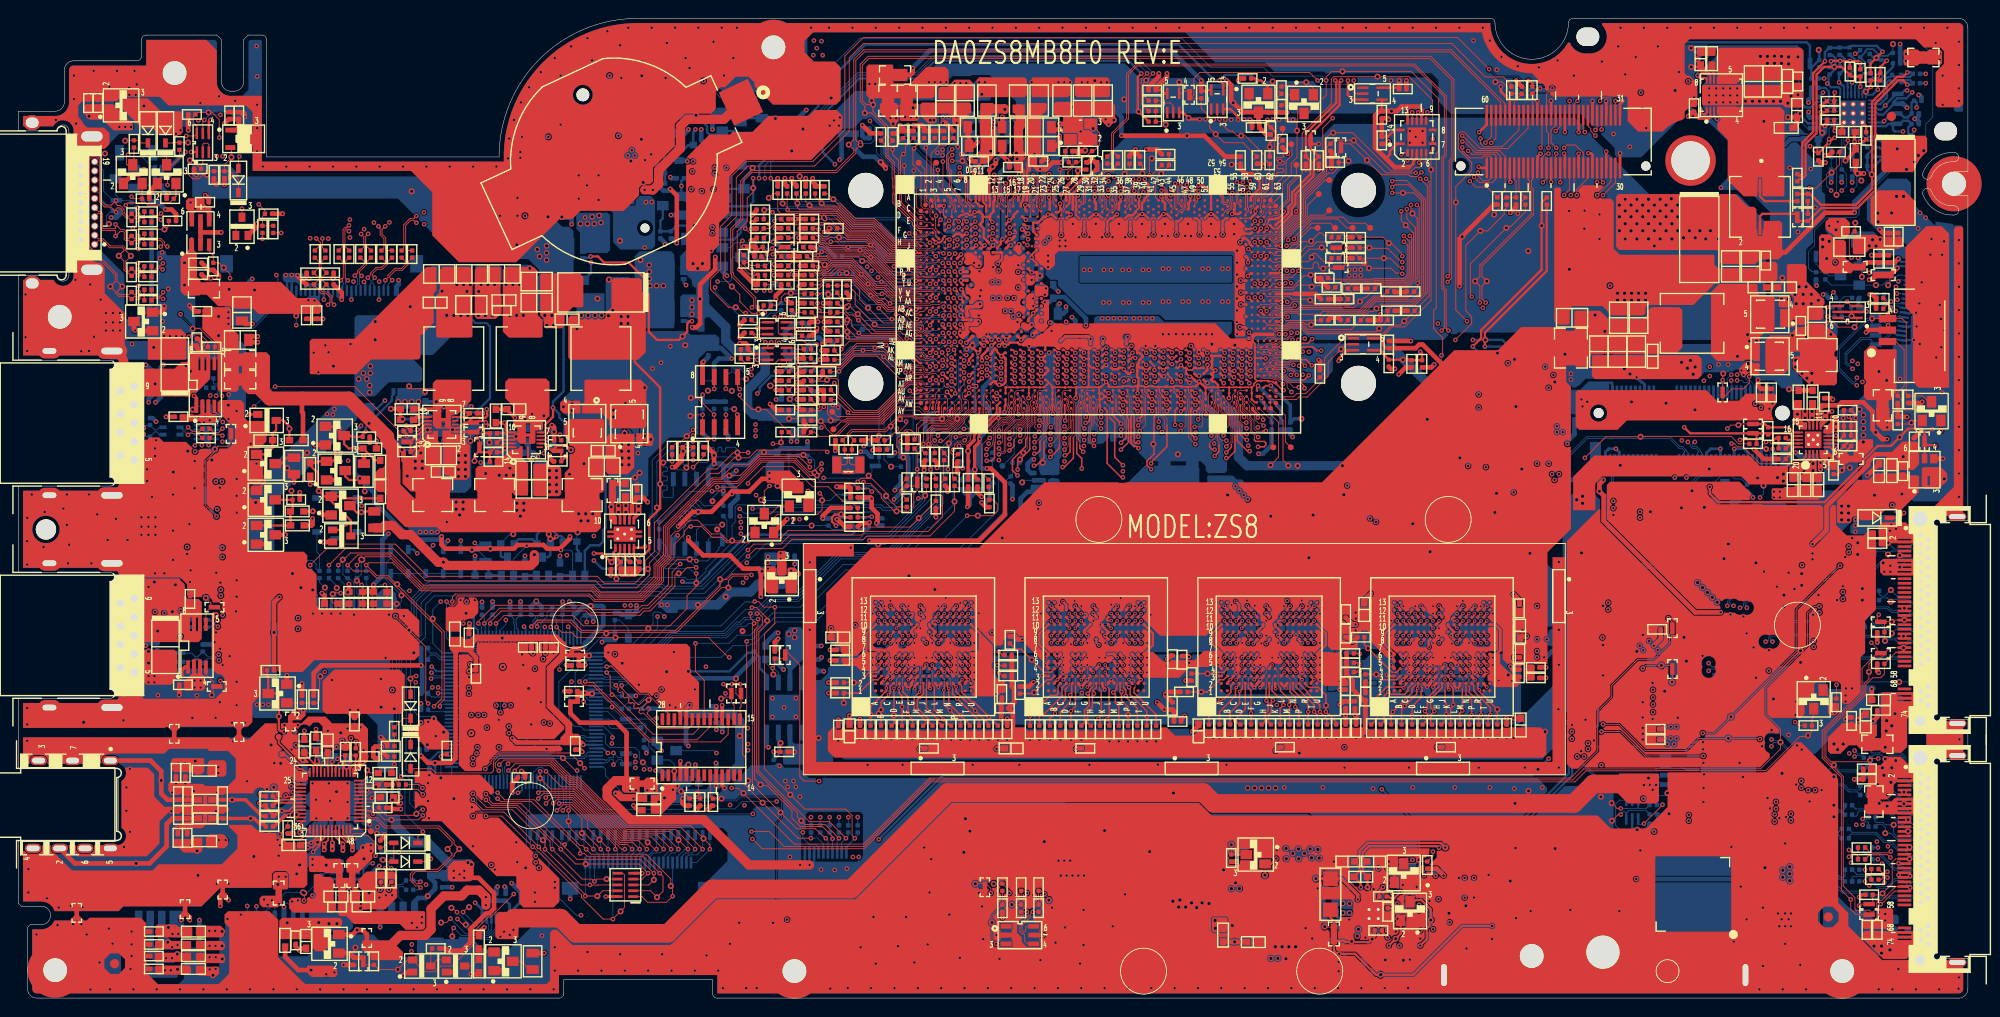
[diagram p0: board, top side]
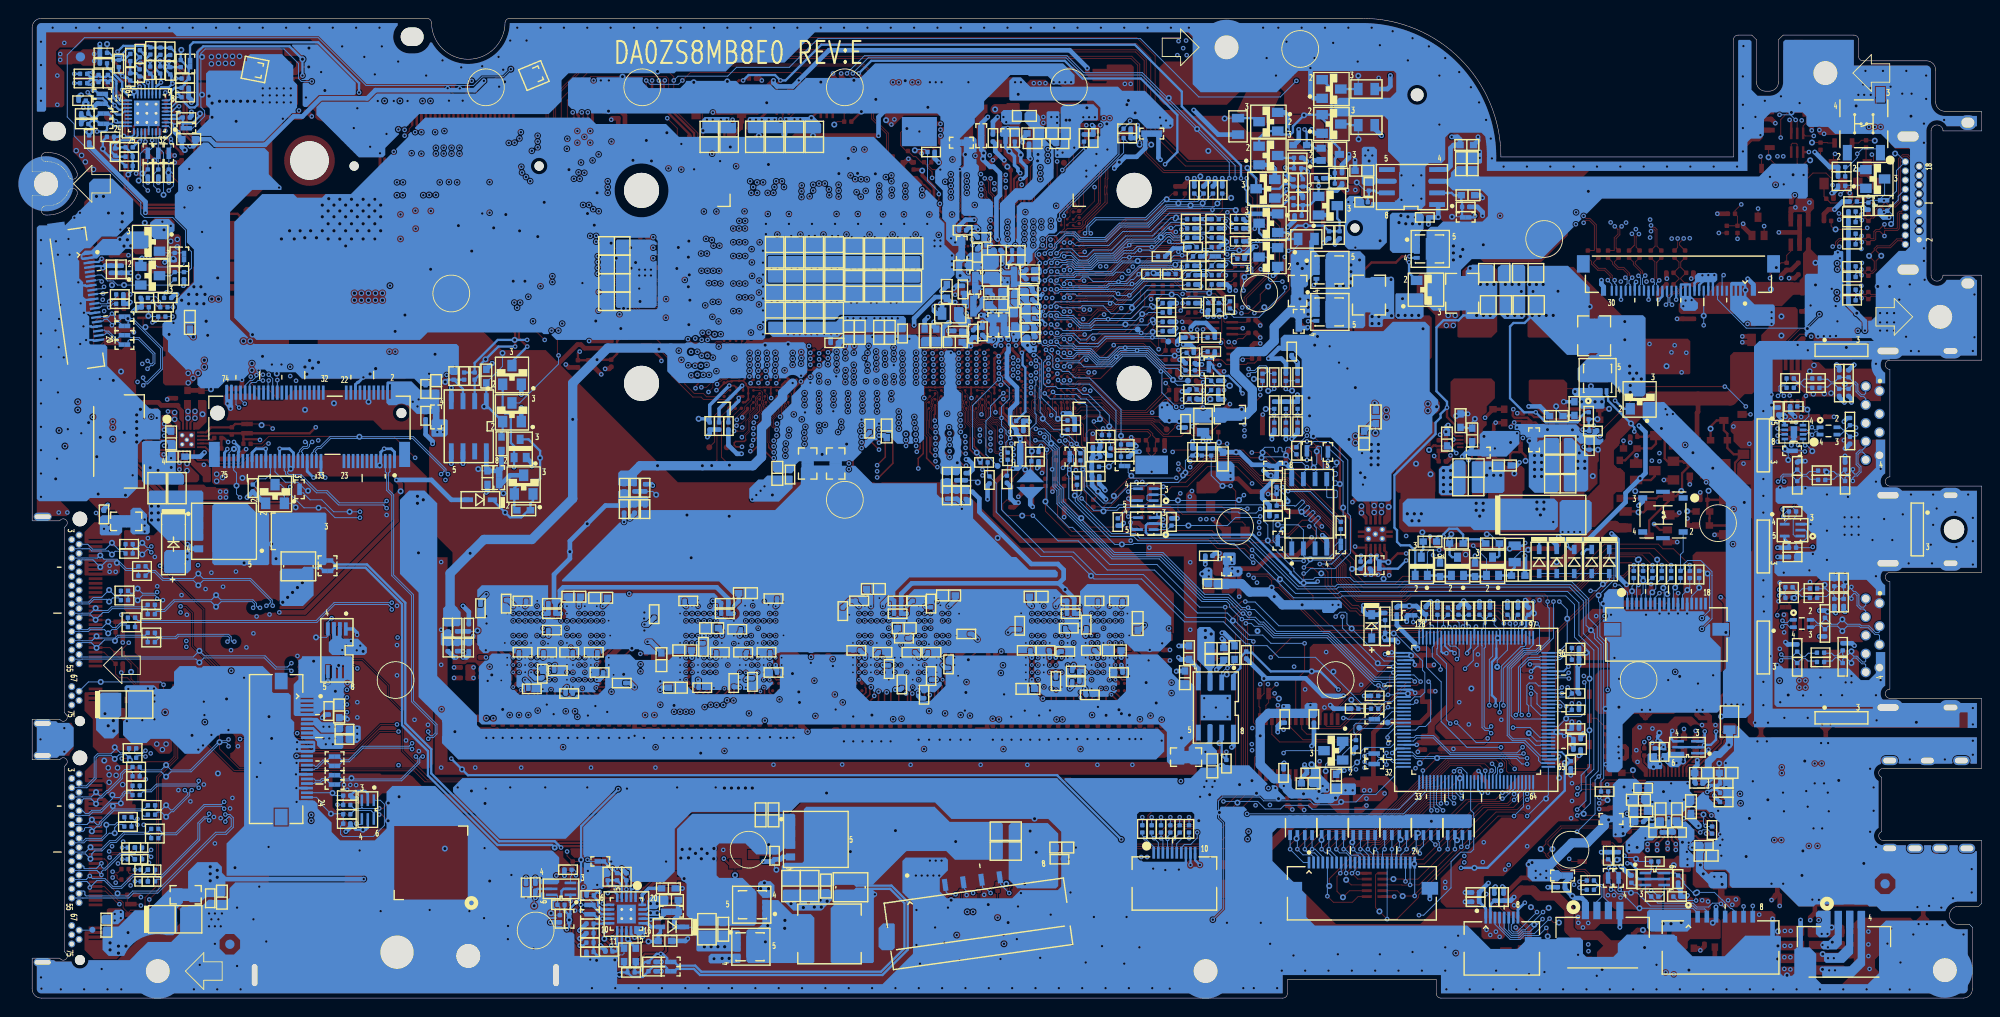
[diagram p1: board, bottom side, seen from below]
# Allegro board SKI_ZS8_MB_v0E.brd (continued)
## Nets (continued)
MA_ODT: R207.2 U6.AP32 U13.J8 U14.J8
MAIND: PC80.2 PQ21.3 PQ25.4 PQ28.4 PQ31.2 PR113.2
MAINON: PQ20.2 PR36.1 PR106.1 PR126.1 R531.1 U23.80
MAINON_ON_G: PQ17.2 PQ18.2 PQ19.2 PQ20.3 PQ21.2 PR114.1 PR119.2
MB_AMA0: R286.2 U6.AP45 U12.R2
MB_AMA1: R285.2 U6.AU46 U12.P2
MB_AMA2: R283.2 U6.AW46 U12.N2
MB_AMA3: R284.2 U6.AY47 U12.N3
MB_AMA4: R282.2 U6.AY46 U12.M3
MB_AMA5: R277.2 U6.AU49 U12.F3
MB_AMA6: R275.2 U6.AU47 U12.E3
MB_AMA7: R276.2 U6.AV47 U12.E2
MB_AMA8: R274.2 U6.AP46 U12.D2
MB_AMA9: R273.2 U6.AR46 U12.C2
MB_AZQ0: R221.2 U12.B3
MB_AZQ1: R206.2 U12.B4
MB_BMA0: R272.2 U6.AK33 U11.R2
MB_BMA1: R271.2 U6.AM33 U11.P2
MB_BMA2: R269.2 U6.AK35 U11.N2
MB_BMA3: R270.2 U6.AM35 U11.N3
MB_BMA4: R268.2 U6.AL35 U11.M3
MB_BMA5: R263.2 U6.AP42 U11.F3
MB_BMA6: R261.2 U6.AM36 U11.E3
MB_BMA7: R262.2 U6.AK36 U11.E2
MB_BMA8: R260.2 U6.AR40 U11.D2
MB_BMA9: R259.2 U6.AP40 U11.C2
MB_BZQ0: R223.2 U11.B3
MB_BZQ1: R219.2 U11.B4
MB_CKE0: R281.2 U6.AY49 U12.K3
MB_CKE1: R280.2 U6.AU50 U12.K4
MB_CKE2: R266.2 U6.AW49 U11.K3
MB_CKE3: R267.2 U6.AV50 U11.K4
MB_CLKN0: R279.2 U6.AM38 U12.J2
MB_CLKN1: R265.2 U6.AK38 U11.J2
MB_CLKP0: R278.2 U6.AN38 U12.J3
MB_CLKP1: R264.2 U6.AL38 U11.J3
MB_CS#0: R216.2 U6.AM32 U11.L3 U12.L3
MB_CS#1: R212.2 U6.AK32 U11.L4 U12.L4
MB_DQ0: U6.AY31 U12.R9
MB_DQ1: U6.AW31 U12.T8
MB_DQ2: U6.AY29 U12.T10
MB_DQ3: U6.AW29 U12.T11
MB_DQ4: U6.AV31 U12.R8
MB_DQ5: U6.AU31 U12.T9
MB_DQ6: U6.AV29 U12.R10
MB_DQ7: U6.AU29 U12.R11
MB_DQ8: U6.AY27 U12.C11
MB_DQ9: U6.AW27 U12.B11
MB_DQ10: U6.AY25 U12.C9
MB_DQ11: U6.AW25 U12.B8
MB_DQ12: U6.AV27 U12.B10
MB_DQ13: U6.AU27 U12.C10
MB_DQ14: U6.AV25 U12.B9
MB_DQ15: U6.AU25 U12.C8
MB_DQ16: U6.AM29 U12.D9
MB_DQ17: U6.AK29 U12.F8
MB_DQ18: U6.AL28 U12.E10
MB_DQ19: U6.AK28 U12.F10
MB_DQ20: U6.AR29 U12.E9
MB_DQ21: U6.AN29 U12.F9
MB_DQ22: U6.AR28 U12.F11
MB_DQ23: U6.AP28 U12.E11
MB_DQ24: U6.AN26 U12.N9
MB_DQ25: U6.AR26 U12.P9
MB_DQ26: U6.AR25 U12.N10
MB_DQ27: U6.AP25 U12.M10
MB_DQ28: U6.AK26 U12.M8
MB_DQ29: U6.AM26 U12.M9
MB_DQ30: U6.AK25 U12.M11
MB_DQ31: U6.AL25 U12.N11
MB_DQ32: U6.AY23 U11.R8
MB_DQ33: U6.AW23 U11.T8
MB_DQ34: U6.AY21 U11.T10
MB_DQ35: U6.AW21 U11.T11
MB_DQ36: U6.AV23 U11.R9
MB_DQ37: U6.AU23 U11.T9
MB_DQ38: U6.AV21 U11.R10
MB_DQ39: U6.AU21 U11.R11
MB_DQ40: U6.AY19 U11.M8
MB_DQ41: U6.AW19 U11.M9
MB_DQ42: U6.AY17 U11.M10
MB_DQ43: U6.AW17 U11.N10
MB_DQ44: U6.AV19 U11.N9
MB_DQ45: U6.AU19 U11.P9
MB_DQ46: U6.AV17 U11.M11
MB_DQ47: U6.AU17 U11.N11
MB_DQ48: U6.AR21 U11.F11
MB_DQ49: U6.AR22 U11.E9
MB_DQ50: U6.AL21 U11.F10
MB_DQ51: U6.AM22 U11.D9
MB_DQ52: U6.AN22 U11.F9
MB_DQ53: U6.AP21 U11.E11
MB_DQ54: U6.AK21 U11.E10
MB_DQ55: U6.AK22 U11.F8
MB_DQ56: U6.AN20 U11.B10
MB_DQ57: U6.AR20 U11.C10
MB_DQ58: U6.AK18 U11.C8
MB_DQ59: U6.AL18 U11.B8
MB_DQ60: U6.AK20 U11.C11
MB_DQ61: U6.AM20 U11.B11
MB_DQ62: U6.AR18 U11.B9
MB_DQ63: U6.AP18 U11.C9
MB_DQSN0: U6.AW30 U12.P11
MB_DQSN1: U6.AV26 U12.D11
MB_DQSN2: U6.AN28 U12.G11
MB_DQSN3: U6.AN25 U12.L11
MB_DQSN4: U6.AW22 U11.P11
MB_DQSN5: U6.AV18 U11.L11
MB_DQSN6: U6.AN21 U11.G11
MB_DQSN7: U6.AN18 U11.D11
MB_DQSP0: U6.AV30 U12.P10
MB_DQSP1: U6.AW26 U12.D10
MB_DQSP2: U6.AM28 U12.G10
MB_DQSP3: U6.AM25 U12.L10
MB_DQSP4: U6.AV22 U11.P10
MB_DQSP5: U6.AW18 U11.L10
MB_DQSP6: U6.AM21 U11.G10
MB_DQSP7: U6.AM18 U11.D10
MB_ODT: R209.2 U6.AL32 U11.J8 U12.J8
MBCLK: PR70.2 PR164.1 PU6.4 R509.1 U23.110
MBDATA: PR71.2 PR162.1 PU6.6 R510.1 U23.111
ME_WR#: R456.2 U23.106
MIC2-VREFO: R537.1 R538.1 R553.2 U16.29
MODPHY_D: PC85.2 PQ22.3 PQ26.4 PR118.2
MODPHY_EN: PR122.1 U6.Y2
MX0: CN16.5 CP2.8 RP1.1 U23.58
MX1: CN16.8 CP2.6 RP1.2 U23.59
MX2: CN16.9 CP2.4 RP1.3 U23.60
MX3: CN16.11 CP2.2 RP1.4 U23.61
MX4: CN16.18 CP1.2 RP1.6 U23.62
MX5: CN16.22 CP1.8 RP1.7 U23.63
MX6: CN16.23 CP1.6 RP1.8 U23.64
MX7: CN16.24 CP1.4 RP1.9 U23.65
MY0: CN16.21 CP3.2 U23.36
MY1: CN16.20 CP3.4 U23.37
MY2: CN16.19 CP3.6 U23.38
MY3: CN16.17 CP3.8 U23.39
MY4: CN16.16 CP4.2 U23.40
MY5: CN16.15 CP4.4 U23.41
MY6: CN16.14 CP4.6 U23.42
MY7: CN16.13 CP4.8 U23.43
MY8: CN16.12 CP5.2 U23.44
MY9: CN16.10 CP5.4 U23.45
MY10: CN16.7 CP5.6 U23.46
MY11: CN16.6 CP5.8 U23.51
MY12: CN16.4 CP6.2 U23.52
MY13: CN16.3 CP6.4 U23.53
MY14: CN16.2 CP6.6 U23.54
MY15: CN16.1 CP6.8 U23.55
NBSWON#: CN1.51 CN12.14 R495.1 SW2.2 U23.125
NGFF0_DET_C: R86.2 R87.2 U6.V1
NGFF0_PEDET: CN13.69 TP24.1
NGFF1_DET_C: R80.2 R85.2 U6.U1
NGFF1_RST#: CN10.50 CN13.50 R205.1 R315.1
NGFF2_DET_C: R376.2 R377.2 U6.V6
NGFF3_DET: Q16.3 R85.1 R86.1 R229.1 R376.1
NGFF3_DET_C: R97.2 R229.2 U6.AC1
NGFF3_PEDET: CN10.69 Q16.2 R227.2
NOA_STBN_0: CN1.28 U6.AA62
NOA_STBN_1: CN1.19 U6.U63
NOA_STBP_0: CN1.29 U6.AA61
NOA_STBP_1: CN1.20 U6.U62
OPI_COMP1: R187.2 U6.AY15
OPI_COMP2: R186.2 U6.AW15
PC_BEEP: D8.1 D9.1 R287.1
PCBEEP: C136.1 U16.12
PCBEEP_EC: D9.2 U23.34
PCBEEP_R: C134.1 C136.2 R287.2 R291.2
PCH_ACPRESENT: R416.2 R417.2 R418.2 U6.AJ8
PCH_AZ_CODEC_BITCLK: C70.1 C143.1 R180.2 U16.6
PCH_AZ_CODEC_RST#: C140.1 D14.1 R295.2 R457.2 U16.11
PCH_AZ_CODEC_SDIN0: R549.1 U6.AY10
PCH_AZ_CODEC_SDIN0_C: R549.2 U16.8
PCH_AZ_CODEC_SDOUT: R470.2 U16.5
PCH_AZ_CODEC_SYNC: R185.2 U16.10
PCH_BATLOW#: R428.2 R429.2 U6.AN4
PCH_I2C1_CLK: Q8.1 Q25.1 R24.2 R400.2 R571.2 U6.F1
PCH_I2C1_DAT: Q8.4 Q25.4 R25.2 R397.2 R581.2 U6.G4
PCH_INTVRMEN: R179.1 U6.AV7
PCH_PWRBTN#: R445.2 R455.2 R464.2 U6.AL7
PCH_PWROK: R13.1 R184.2 R191.2 U23.78
PCH_RSMRST#: R172.2 R182.2 U6.AW6
PCH_SLP_A#: R497.1 U6.AL5
PCH_SLP_S0#: R493.1 U6.AF3
PCH_SLP_S5#: R499.1 U6.AP5
PCH_SLP_SUS#: Q14.2 U6.AP4 U23.71
PCH_SLP_WLAN#: TP22.1 U6.AM5
PCH_SPI_CLK: C68.1 R176.2 U6.AA3
PCH_SPI_CLK_EC: R448.1 U23.105
PCH_SPI_CLK_R: R176.1 R448.2 U19.6
PCH_SPI_CS0#: R487.2 U6.Y7 U19.1
PCH_SPI_IO2: R475.2 U6.Y6
PCH_SPI_IO3: R449.2 U6.AF1
PCH_SPI_SI: R175.2 U6.AA2
PCH_SPI_SI_EC: R447.1 R507.2 U23.102
PCH_SPI_SI_R: R175.1 R447.2 U19.5
PCH_SPI_SO: R486.2 U6.AA4
PCH_SPI_SO_EC: R489.1 R508.2 U23.103
PCH_SPI_SO_R: R486.1 R489.2 U19.2
PCH_STAT: TP21.1 U6.AG4
PCH_SUSACK#: R119.2 U23.2
PCH_SUSCLK: TP20.1 U6.AE6
PCH_SUSPWARN#: R166.2 R515.1 U23.128
PCH_SUSPWRACK: R120.2 R166.1 R167.2 U6.AV4
PCI_PIRQA#: R375.1 U6.U6
PCI_PIRQB#: R74.1 U6.P4
PCI_PIRQC#: R369.1 U6.N4
PCI_PIRQD#: R64.1 U6.N2
PCI_PLTRST#: U6.AG7 U18.1 U18.2
PCIE_CLKREQ_NGFF0#: CN13.52 R367.1 R370.1
PCIE_CLKREQ_NGFF0#_C: R367.2 U6.U5
PCIE_CLKREQ_NGFF1#: CN10.52 R75.1 R210.1
PCIE_CLKREQ_NGFF1#_C: R75.2 U6.T2
PCIE_CLKREQ_WLAN#: R65.1 R473.1 U6.N1
PCIE_IREF: R44.2 U6.B27
PCIE_RCOMP: R43.1 U6.A27
PCIE_WAKE_WLAN#: Q22.3 R409.2 R410.2 U6.AJ5
PD#: D14.2 D15.2 R310.2 U16.47
PECI: R513.2 U23.117
PEG_RXN4: CN9.43 U6.F13
PEG_RXN5_L0: R567.2 U6.F10
PEG_RXN5_L1: R556.2 U6.F8
PEG_RXN5_L1_N: CN13.29 R556.1
PEG_RXN5_L2: R548.2 U6.H10
PEG_RXN5_L2_N: CN13.17 R548.1
PEG_RXN5_L3: R536.2 U6.E6
PEG_RXN5_L3_N: CN13.5 R536.1
PEG_RXN6_L1: R503.2 U6.J6
PEG_RXN6_L1_N: CN10.29 R503.1
PEG_RXN6_L2_N: CN10.17 R312.1
PEG_RXN6_L3: R488.2 U6.J5
PEG_RXN6_L3_N: CN10.5 R488.1
PEG_RXP4: CN9.41 U6.G13
PEG_RXP5_L0: R570.2 U6.E10
PEG_RXP5_L1: R560.2 U6.E8
PEG_RXP5_L1_N: CN13.31 R560.1
PEG_RXP5_L2: R551.2 U6.G10
PEG_RXP5_L2_N: CN13.19 R551.1
PEG_RXP5_L3: R541.2 U6.F6
PEG_RXP5_L3_N: CN13.7 R541.1
PEG_RXP6_L1: R505.2 U6.H6
PEG_RXP6_L1_N: CN10.31 R505.1
PEG_RXP6_L2_N: CN10.19 R311.1
PEG_RXP6_L3: R491.2 U6.H5
PEG_RXP6_L3_N: CN10.7 R491.1
PEG_TXN4: C19.1 CN9.37
PEG_TXN5_L0: C400.1 U6.C23
PEG_TXN5_L1: C391.1 U6.B23
PEG_TXN5_L1_N: C391.2 CN13.35
PEG_TXN5_L2: C384.1 U6.B21
PEG_TXN5_L2_N: C384.2 CN13.23
PEG_TXN5_L3: C372.1 U6.B22
PEG_TXN5_L3_N: C372.2 CN13.11
PEG_TXN6_L1: C291.1 U6.B14
PEG_TXN6_L1_N: C291.2 CN10.35
PEG_TXN6_L2_N: C148.2 CN10.23
PEG_TXN6_L3: C266.1 U6.B15
PEG_TXN6_L3_N: C266.2 CN10.11
PEG_TXP4: C18.1 CN9.35
PEG_TXP5_L0: C402.1 U6.C22
PEG_TXP5_L1: C395.1 U6.A23
PEG_TXP5_L1_N: C395.2 CN13.37
PEG_TXP5_L2: C387.1 U6.C21
PEG_TXP5_L2_N: C387.2 CN13.25
PEG_TXP5_L3: C377.1 U6.A21
PEG_TXP5_L3_N: C377.2 CN13.13
PEG_TXP6_L1: C299.1 U6.C15
PEG_TXP6_L1_N: C299.2 CN10.37
PEG_TXP6_L2_N: C149.2 CN10.25
PEG_TXP6_L3: C267.1 U6.A15
PEG_TXP6_L3_N: C267.2 CN10.13
PLTRST#: CN14.7 R57.1 R154.2 R189.2 R205.2 R224.1 R315.2 U18.4 U23.22
PROC_DETECT#: TP5.1 U6.D61
PROCHOT_EC: Q24.2 R535.2 U23.17
PTP_PWR_EN#: Q54.2 R775.1 R781.1 U23.99
PWR_DEBUG: CN1.53 R31.1
PWR_DEBUG_R: R31.2 R42.1 U6.H59
PWRLED#: CN18.4 U23.24
R_PEG_TXN4: C19.2 U6.B29
R_PEG_TXP4: C18.2 U6.A29
R_SPK+: R328.2 U16.45
R_SPK-: R327.2 U16.44
RAM_ID0: R148.2 R149.2 U6.AT3
RAM_ID1: R160.2 R161.2 U6.AM3
RAM_ID2: R151.2 R152.2 U6.AM2
RAM_ID3: R412.2 R413.2 U6.AH4
RF_EN: CN9.56 U23.66
RING2: L6.1 Q23.3 R538.2 U16.17
RING2_R: C135.1 CN6.3 D10.1 L6.2
RSMRST#: R181.2 R182.1 U23.112
RTC_RST#: C249.1 J2.1 R459.1 R496.1 U6.AU7
RTC_X1: C65.2 R173.2 U6.AW5 Y2.1
RTC_X2: C66.2 R173.1 U6.AY5 Y2.2
S5D: PC47.2 PQ6.3 PQ27.2 PQ30.4 PR38.2 PR47.2
S5ON: PQ13.2 PQ29.2 PQ33.2 PR147.1 R506.2 U23.100
SATA_IREF: R337.1 U6.A12
SATA_LED#: R82.2 U6.U3
SATA_RCOMP: R336.2 U6.C12
SATA_RXN1/PEG_RXN6_L2: C399.1 R312.2 U6.J8
SATA_RXN1/PEG_RXP5_L0_N: C399.2 CN13.43 R570.1
SATA_RXN3/PEG_RXN6_L0: R519.2 U6.F5
SATA_RXN3/PEG_RXN6_L0_N: CN10.43 R519.1
SATA_RXP1/PEG_RXN5_L0_N: C397.2 CN13.41 R567.1
SATA_RXP1/PEG_RXP6_L2: C397.1 R311.2 U6.H8
SATA_RXP3/PEG_RXP6_L0: R516.2 U6.E5
SATA_RXP3/PEG_RXP6_L0_N: CN10.41 R516.1
SATA_TXN1/PEG_TXN5_L0_N: C400.2 C401.2 CN13.47
SATA_TXN1/PEG_TXN6_L2: C148.1 C401.1 U6.A17
SATA_TXN3/PEG_TXN6_L0: C310.1 U6.C17
SATA_TXN3/PEG_TXN6_L0_N: C310.2 CN10.47
SATA_TXP1/PEG_TXP5_L0_N: C402.2 C403.2 CN13.49
SATA_TXP1/PEG_TXP6_L2: C149.1 C403.1 U6.B17
SATA_TXP3/PEG_TXP6_L0: C314.1 U6.D17
SATA_TXP3/PEG_TXP6_L0_N: C314.2 CN10.49
SB_ACDC: PR165.1 U23.21
SENSOR_EN: R79.1 R780.1 U23.126
SENSOR_INT: R390.2 U6.AG5 U23.81
SENSOR_PCH_CLK: R346.2 R539.2 U6.F3
SENSOR_PCH_CLK_E: R539.1 U23.30
SENSOR_PCH_DAT: R347.2 R542.2 U6.F2
SENSOR_PCH_DAT_E: R542.1 U23.31
SENSOR_SCL: C219.1 CN7.12 R527.1 R787.1 U23.94
SENSOR_SDA: C229.1 CN7.13 R525.1 R788.1 U23.95
SIO_EXT_SCI#: R352.2 U6.G2 U23.23
SIO_EXT_SMI#: R353.2 U6.K4 U23.15
SIO_RCIN#: R384.2 U6.V4 U23.4
SKU_ID0: R94.2 U6.Y1
SKU_ID1: R360.2 U6.N5
SLEEVE: L9.1 Q23.6 R537.2 U16.18
SLEEVE_R: C146.1 CN6.4 D13.1 L9.2
SM_INTRUDER#: R465.1 U6.AU6
SM_RCOMP_0: R439.1 U6.AU60
SM_RCOMP_1: R438.1 U6.AV60
SM_RCOMP_2: R440.1 U6.AU61
SMB0ALERT#: R127.2 U6.AL2
SMB1ALERT#: R164.2 U6.AU4
SMB_ME1_CLK: Q11.4 R134.1 R139.1 U6.AU3
SMB_ME1_DAT: Q11.1 R135.1 R140.1 U6.AH3
SMB_PCH_CLK: Q10.3 R130.2 U6.AP2
SMB_PCH_DAT: Q10.6 R126.2 U6.AH1
SMBALERT#: R141.2 U6.AN2
SMBCLK0: R145.2 U6.AN1
SMBDATA0: R116.2 U6.AK1
SPD_A0: R430.2 R441.2 U9.1
SPD_A1: R431.2 R442.2 U9.2
SPD_A2: R432.2 R443.2 U9.3
SPD_CLK: R422.1 U9.6
SPD_DAT: R423.1 U9.5
SPD_WP: R420.1 R421.1 U9.7
SPI_CS0#_UR_ME: R482.2 R487.1 U23.101
SPI_HOLD_IO3_ME: R177.1 R449.1 U19.7
SPI_WP_IO2_ME: R475.1 R478.1 U19.3
SPK_L+: C158.1 CN19.1 R322.1
SPK_L-: C161.1 CN19.2 R326.1
SPK_R+: C164.1 CN19.4 R328.1
SPK_R-: C163.1 CN19.3 R327.1
SPKR: D8.2 R88.1 U6.V2
SRTC_RST#: C67.1 R174.1 U6.AV6
SUSACK#_R: R119.1 R120.1 U6.AK2
SUSB#: R500.1 U6.AT4 U23.82
SUSC#: R498.1 U6.AJ6 U23.83
SUSLED#: CN18.5 U23.28
SUSON: PQ3.2 PR23.1 PR61.1 R514.1 U23.123
SYS_HWPG: D26.1 PR22.2 PR40.2 PR44.2
SYS_PWROK: R4.1 R108.2 R115.2 R192.2 R193.2 U20.4
SYS_PWROK_R: C47.1 R107.1 R108.1 U6.AG2
SYS_RESET#: R55.1 R485.2 R494.1 U6.AC3
SYS_SHDN#: C176.1 D16.1 PQ32.3 PR31.1 PR32.2 PR37.2 Q2.3 SW1.1
TD_IREF: R338.1 U6.B12
TEMP_MBAT: PR66.2 PR69.1 PU6.3 U23.73
TESTLOW_AK8: R436.2 U6.AK8
TESTLOW_AL8: R444.2 U6.AL8
TESTLOW_C34: R32.2 U6.C34
TESTLOW_C35: R33.2 U6.C35
THRMTRIP#: Q2.1 R12.1 U6.D60
TP_DC_TEST_A4: TP4.1 U6.A4
TP_DC_TEST_A60: TP1.1 U6.A60
TP_DC_TEST_A62: TP2.1 U6.A62
TP_DC_TEST_AV1: TP14.1 U6.AV1
TP_DC_TEST_AW1: TP13.1 U6.AW1
TP_DC_TEST_AW63: TP16.1 U6.AW63
TP_DC_TEST_AY60: TP15.1 U6.AY60
TP_DC_TEST_B2: TP3.1 U6.B2
TPCLK: R569.2 R573.1 U23.89
TPCLK_R: C408.1 CN15.2 R573.2
TPD_EN: CN15.8 R580.1 U23.87
TPD_INT#: CN15.7 Q20.3 R532.1
TPD_INT#_C: Q20.1 R368.1 U6.U7
TPD_INT#_EC: R532.2 U23.16
TPDATA: R568.2 R572.1 U23.90
TPDATA_R: C407.1 CN15.3 R572.2
TPM_BADD: R301.2 U15.9
TPM_CLKRUN#: R225.2 U15.15
TPM_LRESET#: R224.2 U15.16
TPM_PP: R299.2 R300.2 U15.7
TS_INT: CN7.6 Q21.1 R379.1
TS_INT_PCH: Q21.3 R378.2 R379.2 U6.R6
TS_RST#: CN7.7 R387.1 U23.35
USB2N0: R171.2 U6.AN8 U17.7
USB2N0_R: L11.4 R171.1 U17.2
USB2N0_USB3: CN4.2 D21.1 L11.3
USB2N1: L15.1 U6.AR7
USB2N1_USB3: CN5.2 D33.1 L15.2
USB2N3: R540.1 U6.AR10
USB2N3_C: CN12.16 R540.2
USB2N4: CN9.5 U6.AM15
USB2N5: R414.1 U6.AM13
USB2N5_C: CN7.16 R414.2
USB2N6: R419.1 U6.AP11
USB2N6_C: CN7.19 R419.2
USB2N7: R545.1 U6.AR13
USB2N7_C: CN12.19 R545.2
USB2P0: R163.2 U6.AM8 U17.6
USB2P0_R: L11.1 R163.1 U17.3
USB2P0_USB3: CN4.3 D20.1 L11.2
USB2P1: L15.4 U6.AT7
USB2P1_USB3: CN5.3 D31.1 L15.3
USB2P3: R544.1 U6.AT10
USB2P3_C: CN12.17 R544.2
USB2P4: CN9.3 U6.AL15
USB2P5: R411.1 U6.AN13
USB2P5_C: CN7.15 R411.2
USB2P6: R415.1 U6.AN11
USB2P6_C: CN7.18 R415.2
USB2P7: R547.1 U6.AP13
USB2P7_C: CN12.20 R547.2
USB3_RXN1: C259.1 R469.2 U6.G20
USB3_RXN1_USB3: CN4.5 D23.1 R469.1
USB3_RXN2: C337.1 R528.2 U6.E18
USB3_RXN2_USB3: CN5.5 D35.1 R528.1
USB3_RXP1: C251.1 R466.2 U6.H20
USB3_RXP1_USB3: CN4.6 D22.1 R466.1
USB3_RXP2: C317.1 R526.2 U6.F18
USB3_RXP2_USB3: CN5.6 D34.1 R526.1
USB3_TXN1: C237.1 U6.C33
USB3_TXN1_R: C237.2 R426.2
USB3_TXN1_USB3: C239.1 CN4.8 D19.1 R426.1
USB3_TXN2: C275.1 U6.B33
USB3_TXN2_R: C275.2 R504.2
USB3_TXN2_USB3: C286.1 CN5.8 D30.1 R504.1
USB3_TXP1: C235.1 U6.B34
USB3_TXP1_R: C235.2 R424.2
USB3_TXP1_USB3: C234.1 CN4.9 D18.1 R424.1
USB3_TXP2: C269.1 U6.A33
USB3_TXP2_R: C269.2 R502.2
USB3_TXP2_USB3: C268.1 CN5.9 D29.1 R502.1
USB_BC_EN: R168.1 R481.2 U21.4
USB_BC_ON: R481.1 U21.1 U23.96
USB_CHARGE_ON: R446.1 U23.76
USB_CR_ON: R446.2 U17.8
USB_OC0#: R132.2 R133.1 R200.2 U6.AL3
USB_OC1#: R153.2 R213.2 U6.AT1
USB_OC2#: R114.2 U6.AH2
USB_OC3#: R155.2 U6.AV3
USBCOMP: R437.2 U6.AJ10 U6.AJ11
USBON#: R202.1 R220.1 U23.79
VA: PC96.2 PC100.2 PJ1.3 PJ1.4 PL6.1 PL7.1
VA1: PC55.2 PC56.1 PD1.2 PD4.1 PL6.2 PL7.2 PQ8.1 PQ35.1 PQ35.2 PQ35.3 PR49.1
VA2: PD3.1 PD3.2 PQ35.5
VL: PC44.2 PR132.1 PR133.1 PU2.11
VR_SVID_ALERT#: PR109.1 PR116.2 R83.2 R84.2
VR_SVID_CLK: PR110.1 PR117.2 R91.1
VR_SVID_DATA: PR108.1 PR115.2 R77.1 R78.2
VRON: PR90.1 R543.1 U23.69
VRON_CPU: PR83.1 R17.1 R37.2 U6.F60
VRTC1: D7.2 R492.2
VRTC2: D7.1 R501.1
WLAN_CLKREQ#: CN9.53 R473.2
WLAN_RST#: CN9.52 R154.1
WLAN_WAKE#: CN9.55 Q22.1 R474.1
WRST#: C312.1 D32.2 R517.1 U23.14
XDP_BPM#0: CN1.41 U6.J60
XDP_BPM#1: CN1.42 U6.H60
XDP_BPM#2: TP7.1 U6.H61
XDP_BPM#3: TP8.1 U6.H62
XDP_BPM#4: TP11.1 U6.K59
XDP_BPM#5: TP6.1 U6.H63
XDP_BPM#6: TP12.1 U6.K60
XDP_BPM#7: TP9.1 U6.J61
XDP_DBRESET_N: CN1.7 R55.2 R56.2
XDP_PRDY#: CN1.33 U6.J62
XDP_PREQ#: CN1.32 U6.K62
XDP_RST_R_N: CN1.8 R57.2
XDP_TCK_CPU: CN1.59 R117.2 R125.2 U6.AE63 U6.E60
XDP_TCK_PCH: CN1.58 R118.2 U6.AE62
XDP_TDI_CPU: U4.6 U6.F63
XDP_TDI_PCH: CN1.3 R123.2 U4.5 U6.AD61
XDP_TDO_CPU: R30.2 U4.3 U6.F62
XDP_TDO_PCH: CN1.5 R54.2 R124.2 U4.2 U6.AE61
XDP_TMS_CPU: U4.8 U6.E61
XDP_TMS_PCH: CN1.2 R122.2 U4.9 U6.AD62
XDP_TRST#: R147.2 U4.11 U6.AU62 U6.E59
XDP_TRST_N: CN1.4 U4.12
XTAL24_IN: C17.1 R41.2 U6.A25 Y1.3
XTAL24_OUT: C16.1 R41.1 U6.B25 Y1.1
N03288: PC56.2 PQ8.6 PQ35.4 PR33.1 PR49.2
N05582: PQ36.4 PR63.1 PR154.2
N05646: PQ8.2 PQ8.3
N05670: PQ8.5 PQ14.2 PR34.1
N05802: PL10.1 PR159.1 PR173.2
N06510: PC70.1 PR75.2
N90670: PC69.1 PJ2.3 PR71.1
N90734: PC121.1 PC122.2 PJ2.7 PJ2.8 PL8.1 PL9.1
N91425: R109.1 R115.1 R183.2 R393.2
N125333: Q2.2 R3.1
N125337: Q1.1 R3.2
N243495: PD3.3 PR146.2 PR150.1
N420837: C361.1 U23.12
N423040: C362.1 R530.1
N16778199: PC22.1 PR16.2
N16779997: Q9.3 R350.1 R354.1 R359.1 R363.1 R373.1 R380.1 R385.1 R389.1
N16780395: PC39.1 PR18.2
N16793601: C142.1 U16.7
N16797704: C147.1 U16.39
N16798387: C392.1 U16.35
N16798543: C392.2 U16.37
N16798641: C145.1 U16.34
N16800298: R292.2 U16.15
N16824795: PC68.1 PJ2.4 PR70.1
N16828407: Q15.3 Q23.2 Q23.5 R214.1
N16828426: C103.2 Q15.2 R226.1 R295.1
N16828811: C123.1 U16.19
N16832743: TP19.1 U16.48
N16857822: PQ14.3 PR63.2
N16860490: D3.1 R29.2
N16860618: D2.1 R27.2
N16870904: PQ16.3 PR169.1
N16876480: PC62.1 PR51.1
N16876574: PC95.1 PR136.2
N16911747: C248.2 Q13.2 Q14.3 R450.2
N16928869: PQ37.2 PQ37.5 PR160.1 PU11.5
N16928948: PQ37.6 PR161.2 PR166.1
N16991480: PC129.2 PD8.1 PR163.1
N17028529: PD1.1 PR73.1 PR74.2
N17036761: PR67.1 PR74.1
N17045614: PR162.2 PU11.8
N17046311: PR164.2 PU11.9
N17109474: C304.2 R520.2
N17109500: C260.2 R471.2
N17132574: C256.2 R467.2
N17177387: PR171.2 PU11.13
N17177693: PR172.2 PU11.12
N17295384: TP25.1 U23.19
N17295398: TP26.1 U23.20
N17388651: R15.1 U1.4 U4.1 U4.4 U4.10 U4.13
N19105029: R213.1 U22.5
N19105147: R202.2 U22.4
N19105233: R133.2 U8.5
N19105388: R168.2 U8.4
N19105409: R220.2 U10.4
N19105455: R200.1 U10.5
N19177528: CN3.4 Q12.3 R158.2
N19177538: Q12.2 R165.2
N19179160: R433.1 U17.4
N19426582: JP8.1 PC20.2 PC21.2 PC24.2 PC26.2 PC28.2 PC88.2 PC90.2 PD7.2 PL4.2 PU3.7
N19432785: PQ19.3 PR101.2
N19432788: PQ17.3 PR93.2
N19432899: PQ18.3 PR102.2
N19432905: PC115.2 PR60.1 PR61.2 PU10.2
N19432917: PR62.2 PR153.1 PU10.7
N19433355: C714.1 Q19.2 R780.2
N19439774: JP7.1 PC18.2 PC19.2 PC25.2 PC27.2 PC43.2 PC87.2 PC89.2 PL3.2 PR137.1 PU2.7
N19442536: PC86.2 PR124.1 PR126.2 PU8.2
N19442558: PR120.2 PR123.1 PU8.7
N19866545: C177.1 CN2.13
N19866548: C27.1 CN2.14
N19944352: PC84.2 PQ23.2 PR121.1 PR122.2 PR125.2
N20615974: PQ3.3 PQ7.2 PQ10.2 PR29.1 PR30.2
N20616004: PC64.2 PQ10.3 PQ12.2 PR53.2 PR55.2
N20616028: PQ7.3 PR46.2
N21454878: C713.1 Q53.2 R781.2
N21605343: Q53.1 R325.2
N21733433: Q54.3 Q55.2 R783.2
N21733447: Q55.3 Q56.2 R785.2 R786.1
N21733477: Q56.3 R784.2
N47973729: PC104.2 PR141.1 PR143.2 PU9.8
N47973733: PD2.1 PQ34.1 PR144.1
N47973739: PQ34.3 PR143.1
N47973743: PQ33.3 PQ34.2 PR144.2
N47973784: PC92.2 PQ32.2 PR141.2 PU9.1
N47973813: PQ29.3 PR17.1
N105883866: PJ2.6 PR65.2
N106376146: PJ2.5 PR66.1
N106389743: PQ22.2 PQ23.3 PQ24.2 PR128.1 PR129.2
N106389874: PQ24.3 PR130.2
N106400087: PR99.1 PR103.2 PU7.3
N106400399: PC4.2 PR5.1
N106400425: PL1.4 PR14.1
N106400429: PL1.3 PR12.1
N106400442: PR13.2 PR15.2
N106400512: PC10.1 PR10.2
N106400579: PC77.2 PR112.2
N106400606: PR79.2 PR80.1 PR88.1
N108094032: PC45.2 PU3.11
N108094152: PC110.1 PD7.3
N108094154: PC112.2 PD6.2 PD7.1
N108094162: PC109.1 PD6.3
N108094178: PC94.1 PR138.2
N108094262: PC108.1 PD5.3
N108094270: PC111.2 PD5.2 PD6.1
N108094286: PC113.2 PD5.1 PR145.2
N108094465: PC93.1 PR135.2
N108099073: PQ6.2 PQ9.2 PQ11.2 PQ13.3 PR48.1 PR52.2
N108099274: PQ11.3 PR54.2
N108099282: PQ9.3 PR50.2
N108100988: PR26.1 PU2.3

Pads without a net: CN1 9 52; CN7 5; CN8 5 33 34; CN9 6 8 9 10 11 12 13 14 15 16 17 19 20 21 22 23 32 34 36 38 40 42 44 46 48 50 58 59 60 61 62 65 67 76 77; CN10 6 8 10 20 22 24 26 28 30 32 34 36 40 42 44 46 48 54 56 58 67 68; CN11 16 17 18 19 20; CN12 25 26; CN13 6 8 10 20 22 24 26 28 30 32 34 36 40 42 44 46 48 54 56 58 67 68; HOLE5 1; NOREF#3 1; NOREF#4 1; NOREF#6 1; NOREF#8 1; NOREF#9 1; NOREF#10 1; PU2 5 6; PU3 3; PU6 1; PU7 21 22; PU8 5; PU9 7; PU10 5; SW1 2 3; SW2 1 4 5 6; U1 1; U2 1; U3 1; U6 A5 A6 A8 A31 A41 A51 A53 AA23 AA59 AB21 AB23 AC2 AC4 AC20 AC58 AC59 AD2 AD4 AD23 AD59 AD60 AE59 AE60 AF2 AF4 AF20 AG58 AJ7 AL1 AL11 AM10 AM11 AN10 AP7 AP8 AP36 AR8 AR42 AR45 AT2 AU10 AU12 AU15 AU39 AU44 AU63 AV2 AV10 AV44 AV62 AV63 AW10 AW14 AY8 AY14 B5 B6 B30 B31 B41 B42 B43 B50 B51 B53 B54 C5 C29 C30 C31 C41 C42 C43 C49 C50 C51 C53 C62 C63 D1 D9 D11 D15 D58 E1 E13 E15 F11 F15 F17 F22 G11 G15 G17 H18 H22 J20 J21 J58 K10 K18 K21 L11 L59 L60 M20 M21 N23 N58 N59 N60 N61 P20 P60 P61 R20 R23 T23 T59 U10 U59 V21 V59 W23 Y4 Y20 Y22; U7 1; U11 A1 A2 A12 A13 B1 B13 C4 K9 R3 T1 T13 U1 U2 U12 U13; U12 A1 A2 A12 A13 B1 B13 C4 K9 R3 T1 T13 U1 U2 U12 U13; U13 A1 A2 A12 A13 B1 B13 C4 K9 R3 T1 T13 U1 U2 U12 U13; U14 A1 A2 A12 A13 B1 B13 C4 K9 R3 T1 T13 U1 U2 U12 U13; U15 1 2 3 6 8 12 13 14 28; U16 14 16 20; U23 18 48 56 57 70 77 88 98 109

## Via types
v1: diameter 0.508, hole 0.254, TOP to BOTTOM, 3409 vias
v2: diameter 0.66, hole 0.33, TOP to BOTTOM, 680 vias
v3: diameter 0.66, hole 0.254, TOP to BOTTOM, 10 vias
v4: diameter 0.61, hole 0.356, TOP to BOTTOM, 346 vias
v5: diameter 0.305, hole 0.152, TOP to BOTTOM, 4 vias
v6: diameter 0.406, hole 0.203, TOP to BOTTOM, 516 vias

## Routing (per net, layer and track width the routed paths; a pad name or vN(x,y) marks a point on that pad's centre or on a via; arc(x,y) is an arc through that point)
2.469V: length 4.9
  BOTTOM w0.254: PR134.1 165.23,66.29 PU9.3 ; PR134.1 166.89,67.3 167.15,67.05 v2(167.16,67.05) ; PR134.1 PR133.2
3VPCU_AGND: length 9.5
  TOP w0.203: v1(52.96,59.82) 53.1,59.96 PU3.14
  TOP w0.254: v1(50.55,61.47) PC45.1 PR35.1 ; PC50.1 52.55,59.41 v1(52.96,59.82)
  IN2 w0.254: v1(52.96,59.82) 56.64,59.82 v1(57.15,59.31)
  BOTTOM w0.254: PC97.1 57.94,60.1 v1(57.15,59.31)
  vias: v2(51.25,60.47) v2(54.14,61.13)
3VPCU_VIN:
  vias: v2(50.84,57.09) v2(53.48,57.67) v4(52.32,56.9) v4(53.09,56.9) v4(53.85,56.9)
5VPCU_AGND: length 2.6
  TOP w0.203: v1(43.94,61.09) 43.94,61.21 44.36,61.63 PU2.14
  TOP w0.254: PC44.1 42.29,61.33 v1(42.29,61.16) ; v1(50.55,62.1) 50.29,62.1 49.89,61.71 PR26.2
  vias: v2(44.52,61.84) v2(47.23,61.86)
5VPCU_VIN: length 1.4
  TOP w0.508: 42.29,58.17 41.9,58.56 PR41.1
  vias: v2(42.31,56.81) v2(43.78,59.32) v4(43.18,58.42) v4(43.18,57.66) v4(43.94,58.42) v4(43.94,57.66)
51211V_DRVH: length 11.9
  IN1 w1.016: 64.97,53.72 60.82,57.87 60.82,63.41 60.5,63.73
  vias: v2(59.3,64.35) v4(60.25,64.67) v4(60.25,63.93) v4(65.29,53.59) v4(65.29,52.86)
51211V_DRVL: length 6
  IN1 w1.016: 68.3,59.97 68.3,55.09 67.49,54.28
  vias: v2(68.82,60.8) v4(67.47,53.53) v4(67.47,52.8) v4(68.12,61.16) v4(68.12,60.43)
51211V_EN: length 3.8
  TOP w0.254: PR58.2 66.44,47.46 65.79,48.11 v1(65.79,48.13) 65.96,48.31 PU5.3
  BOTTOM w0.254: v1(65.79,48.13) 65.79,47.76 PR147.2 64.63,47.51 v2(64.56,47.44)
51211V_FB: length 3.8
  TOP w0.254: v1(66.46,48.13) PU5.4
  BOTTOM w0.254: v1(66.46,48.13) 66.46,47.59 PR148.1 66.78,47.51 PR149.2 67.59,46.7 v2(68.49,46.7)
51211V_SW: length 10.5
  IN1 w1.016: 66.29,53.97 66.29,55.58 64.52,57.35 64.52,62.76 64.64,62.89
  BOTTOM w0.508: v1(66.04,64.77) 65.91,64.64 PR136.1
  vias: v2(68.14,66.44) v4(64.77,63.98) v4(64.77,63.25) v4(66.09,53.59) v4(66.09,52.86)
51211V_TRIP: length 3.8
  TOP w0.254: PU5.2 65.46,48.52 65.28,48.34 65.28,47.71 PR57.2 65,46.92 65,45.7 v2(65.06,45.63)
51211V_TST: length 3.1
  TOP w0.254: v1(68.16,49.14) 68.04,49.02 PU5.5 66.96,47.97 67.48,47.46 PR59.2
51211V_VBST:
  vias: v2(64.51,53.46)
+1.2VSUS_SRC: length 58.1
  TOP w0.203: PU4.9 197.69,61.16 v1(197.74,61.21)
  IN1 w0.254: v1(173.23,70.36) 173.42,70.17 175.83,70.17 178.69,67.31 182.63,67.31 183.01,67.69 v1(184.02,67.69)
  IN1 w0.508: v1(183.39,67.18) 183.01,66.8 178.19,66.8 175.45,69.54 173.16,69.54 172.59,70.1 v1(172.59,70.36)
  IN3 w0.254: v1(184.02,67.69) 184.07,67.69 189.03,62.73 190.78,62.73 193.81,59.69 196.22,59.69 v1(197.74,61.21)
  IN3 w0.508: v1(183.39,67.18) 183.78,66.79 184.28,66.79 188.88,62.19 190.63,62.19 192.68,60.14 192.68,58.78 v1(193.42,58.04)
  vias: v2(171.54,74.34) v2(172.61,72.56)
+1V2_SUS: length 34.5
  TOP w0.076: 154.56,36.28 154.56,35.37 U14.H3 ; 135.75,36.29 135.75,35.37 U13.H3 ; 98.14,36.26 98.14,35.38 U11.H3 ; U12.H3 116.3,35.37 v6(116.3,36.25)
  TOP w0.254: U11.J9 v6(98.14,40.25) U11.H9 ; U13.L2 137.88,33.75 v6(137.92,33.75) 137.92,34.11 U13.M2 ; v6(97.49,34.65) 97.16,34.32 U11.G2 97.16,34.07 v6(96.84,33.67) 96.51,34.07 U11.F2 ; U7.5 148.16,71.81 148.46,71.5 148.46,71.12 148.85,70.73 C58.1 ; U14.M2 156.84,33.99 v6(156.54,33.62) 156.19,34.05 U14.L2 ; U11.L2 v6(100.08,33.85) U11.M2 ; U12.H3 116.62,34.97 v6(116.3,34.65) 116.3,34.57 U12.G2 115.97,34.17 v6(115.65,33.85) 115.32,34.17 U12.F2 ; U13.G2 134.78,34.12 v6(134.46,33.8) 134.13,34.12 U13.F2 ; U12.M2 119.22,34.32 v6(118.9,34.65) 118.57,34.33 U12.L2 ; v6(104.5,41.88) 104.14,41.45 U11.U11
  TOP w0.305: v6(153.92,41.85) 154.24,41.53 U14.H11 ; v6(97.49,34.65) 97.81,34.97 U11.H3 ; U13.G2 135.11,34.57 v6(135.11,34.65) 135.43,34.97 U13.H3 ; U14.F2 152.94,34.17 v6(153.26,33.85) 153.27,33.85 153.59,34.17 U14.G2 153.59,34.33 v6(153.91,34.65) 154.24,34.98 U14.H3
  TOP w0.508: v1(90.5,37.89) C88.1 ; v1(162.74,37.85) C89.1 ; C58.1 152.01,70.73 152.4,71.12 152.78,71.12 154.85,69.05 154.85,68.87
  BOTTOM w0.508: C358.1 153.28,33.83 v6(153.26,33.85) ; R524.2 166.2,37.08 v1(165.99,37.08)
  vias: v1(89.15,38.61) v1(110.95,53.25) v1(145.49,41.96) v1(145.52,41.3) v1(145.49,40) v1(162.7,41.57) v1(162.66,40.77) v2(107.05,50.08) v2(136.26,52.44) v2(140.4,47.92) v2(140.86,52.57) v2(162.93,64.38) v6(92.74,39.47) v6(92.94,41.85) v6(94.24,42.65) v6(94.88,43.23) v6(94.89,37.05) v6(94.89,36.25) v6(94.89,35.45) v6(95.53,38.65) v6(96.84,42.65) v6(96.84,36.25) v6(97.48,38.65) v6(97.49,37.05) v6(97.49,36.25) v6(98.14,41.05) v6(98.78,37.05) v6(99.44,38.65) v6(99.43,37.05) v6(100.08,42.65) v6(100.9,43.56) v6(101.39,38.65) v6(102.03,37.05) v6(102.03,36.25) v6(102.03,35.45) v6(102.46,43) v6(103.99,38.65) v6(111.25,41.83) v6(111.54,39.45) v6(113.28,42.75) v6(113.7,37.05) v6(113.7,36.25) v6(113.7,35.45) v6(114.53,38.51) v6(114.91,43.23) v6(115.65,42.65) v6(115.65,36.25) v6(116.3,38.65) v6(116.3,37.05) v6(116.95,41.05) v6(117.6,37.05) v6(118.25,38.65) v6(118.25,37.05) v6(118.9,42.82) v6(119.92,43.53) v6(120.2,38.65) v6(120.85,37.05) v6(120.85,36.25) v6(120.85,35.45) v6(121.49,42.65) v6(122.8,38.65) v6(123.19,41.71) v6(130.35,43.13) v6(130.35,39.48) v6(131.98,42.8) v6(132.51,37.05) v6(132.51,36.25) v6(132.51,35.45) v6(133.16,38.65) v6(133.66,43.28) v6(134.53,42.7) v6(134.46,36.25) v6(135.11,37.05) v6(135.11,36.25) v6(135.23,38.6) v6(135.76,41.05) v6(135.75,39.45) v6(136.41,37.05) v6(137.06,38.65) v6(137.06,37.05) v6(137.7,42.65) v6(139.01,39.45) v6(139.62,43.28) v6(139.66,37.05) v6(139.66,36.25) v6(139.66,35.45) v6(140.3,42.65) v6(141.61,41.85) v6(141.61,38.65) v6(149.21,39.45) v6(149.38,41.07) v6(150.67,42.65) v6(151.31,37.05) v6(151.31,36.25) v6(151.31,35.45) v6(151.97,42.65) v6(153.26,36.25) v6(153.92,42.65) v6(153.92,38.65) v6(153.91,37.05) v6(153.91,36.25) v6(154.56,40.25) v6(154.56,39.45) v6(155.21,37.05) v6(155.86,37.05) v6(155.97,38.57) v6(156.51,42.65) v6(156.51,36.25) v6(157.15,43.23) v6(157.82,38.65) v6(158.46,37.05) v6(158.46,36.25) v6(158.45,35.47) v6(159.11,42.65) v6(160.42,41.85) v6(160.67,38.65)
+1V2_SUS_VDDQ: length 11.8
  TOP w0.203: v1(119.96,62.52) 119.04,63.45 U6.AY35 ; v1(121.87,62.96) 122.22,63.31 122.22,64.15 U6.AY40 ; v1(127.43,66.97) 127.37,66.97 U6.AR48 ; v1(128.01,63.74) 128.46,64.19 U6.AY50
  TOP w0.254: U6.AJ37 120.56,71.82 v1(120.69,71.95) ; U6.AJ33 118.01,71.25 v1(118.01,71.75) ; v1(124.62,67.67) 124.36,67.67 U6.AP43 ; U6.AN33 118.2,68.88 v1(118.35,68.88) ; U6.AY44 125.01,63.87 v1(124.94,63.87) ; v1(116.66,71.75) U6.AJ31
  TOP w0.305: v1(116.66,71.75) 116.39,72.01 113.89,72.01 U6.AH26
  vias: v2(123.48,60.29) v2(126.15,59.17)
+1V5: length 180
  IN2 w0.508: v1(67.06,91.69) 68.09,92.73 75.45,92.73 76.55,93.82 80.18,93.82 86.88,100.52 94.04,100.52 96.01,98.55 107.19,98.55 108.13,97.61 v1(108.13,95.89)
  IN2 w1.524: 27.37,9.08 27.88,8.58 31.01,8.58 35.45,13.02 41.08,13.02 42.61,14.54 42.61,16.3 41.46,17.45 41.46,18.95 40.47,19.93 40.47,21.63 39.44,22.67 39.44,23.84 40.78,25.19 40.78,29.96 33.99,36.76 30.15,36.76 25.59,41.32 25.59,55.69 28.77,58.87 34.99,58.87
  IN3 w1.524: 65.66,91.69 61.34,91.69 58.93,89.28 58.93,86.74 54.74,82.55 49.48,82.55 35.53,68.61 35.53,63.09 35.37,62.93 35.37,61.53 34.74,60.9 34.74,59.76 34.61,59.63
  BOTTOM w0.508: R333.1 108.84,95.17 v1(108.13,95.89)
  vias: v1(26.74,10.73) v1(27.13,10.16) v1(27.58,10.64) v1(35.05,59.31) v1(35.05,58.42) v1(35.88,58.49) v1(66.29,91.69) v1(66.74,92.27) v2(66.64,91.1)
+1V05: length 142.9
  TOP w0.279: C1.2 150.09,99.07 U1.5
  TOP w0.508: v1(150.23,99.86) C1.2 ; PR8.1 196.97,91.69 v1(196.6,91.69) ; v1(120.02,93.85) v2(127.14,93.85) 129.03,93.85 131.31,91.58 R36.2 ; PC11.1 196.08,90.93 v1(196.6,90.93)
  IN2 w0.254: 198.88,90.68 203.45,90.68 207.42,94.64 207.42,95.13 208.69,96.39 208.69,101.7 205.93,104.46 173.73,104.46 171.68,102.42 169.98,102.42 166.69,99.13 163.26,99.13 162.31,98.17 159.51,98.17 156.46,101.22 149.73,101.22 149.35,100.84 v1(149.35,99.86)
  IN2 w1.016: 109.41,75.5 109.41,76.49 110.07,77.16 110.48,77.16 111.14,77.82 111.14,81.17 111.57,81.6
  BOTTOM w0.508: v1(120.02,93.85) 120.02,95.89 117.48,98.42 115.03,98.42 ; v1(197.23,88.77) PR115.1 ; v1(199.52,88.77) PR117.1 ; PR102.1 83.05,93.97 v1(85.72,96.65) ; v1(198.37,88.77) PR116.1
  BOTTOM w1.016: R434.2 80.01,63.5 79.35,64.16 79.35,66.19 81.25,68.1 81.25,69.88 80.77,70.36 78.11,70.36 76.96,71.5 76.96,73.02 74.68,75.31
  vias: v1(92.58,99.49) v1(93.22,99.49) v1(99.06,99.67) v1(99.69,99.67) v1(100.33,99.67) v1(100.97,99.67) v1(108.24,74.16) v1(108.85,74.36) v1(110.24,99.67) v1(111.67,82.23) v1(112.12,82.68) v1(113.16,99.67) v1(113.79,99.67) v1(114.43,99.67) v2(114.65,96.94) v2(120.31,97.81) v4(73.28,75.95) v4(73.28,75.18) v4(73.28,74.42)
+1V5_ADO_AVDD2: length 8.5
  TOP w0.203: v1(31.5,16.38) 31.99,16.38 32.32,16.72 32.32,16.9 32.91,17.49 U16.40
  BOTTOM w0.762: v1(31.5,16.38) 31.24,16.64 C396.1 30.62,16 30.71,15.91 C398.1 30.71,13.94 v2(30.28,13.52) 29.34,12.57
  vias: v1(28.32,13.21) v1(29.08,13.21) v2(28.23,12.37)
+1V05_AIDLE: length 27.4
  TOP w0.254: v1(102.53,79.06) 102.77,79.3 U6.N8
  TOP w0.305: v1(102.53,79.06) 102.53,79.05 U6.P9
  IN2 w1.016: 94.72,80.52 93.79,81.45 88.03,81.45 86.73,82.74 86.68,82.74 86.05,83.38 86.05,84.9 88.65,87.5 88.65,89.23 91.31,91.9 92.71,91.9 94.74,93.93 94.74,95.25
  vias: v1(94.87,95.76) v1(95.25,79.63) v1(95.5,95.76) v1(95.89,79.63) v2(95.18,95.14)
+1V05_APLLOPI: length 9.6
  TOP w0.305: U6.AA21 110.41,75.32 v1(110.42,75.32) ; v1(110.43,76.14) U6.W21
  IN2 w1.016: 118.49,94.36 118.49,91.69 116.97,90.17 115.67,90.17 114.17,88.67 114.17,88.39
  vias: v1(118.29,95.63) v1(118.62,95.07) v2(119.19,95.54)
+1V05_ASATA3PLL: length 7.9
  TOP w0.254: U6.B11 104.61,86.17 104.15,86.63 104.15,87.88 103.91,88.13 103.91,90.07 104.27,90.42 104.28,90.42 C22.1
  TOP w1.016: v2(107.33,96.71) 107.26,96.78 L1.2
  vias: v1(105.96,94.69)
+1V05_AUSB3PLL: length 18
  TOP w0.254: 109.16,90.29 109.37,90.07 109.37,87.17 109.32,87.12 109.32,86.8 109.06,86.53 U6.B18
  TOP w0.508: R43.2 116.38,90.95 v1(116.76,91.34) 117.15,90.95 R44.1
  TOP w1.016: C14.1 C9.1 108.99,94.96 108.99,96.35 108.83,96.52 L2.2
  IN2 w0.508: v1(109.47,91.67) 109.96,92.15 113.61,92.15 114.63,91.14 116.56,91.14 v1(116.76,91.34)
  vias: v2(108.65,91.33)
+1V05_AXCK_DCB: length 4
  IN2 w1.016: 108.71,85.98 108.71,84.33 108.87,84.17 108.87,82.04 v1(108.88,82.03)
  vias: v1(102.08,95.89) v1(102.08,95.26) v2(99.23,95.54)
+1V05_AXCK_LCPLL: length 10
  TOP w0.254: U6.A20 109.73,86.84 109.73,89.98 109.92,90.17
  TOP w0.508: 109.92,90.17 109.92,90.74 110.25,91.07 C21.1 110.57,90.6 110.96,90.21 v1(111.17,90.21) 111.8,90.21 112.52,90.93 v1(113.46,90.93)
  BOTTOM w0.508: v1(113.46,90.93) 113.91,91.38 R342.1
+1V05_CORE_PCH: length 20.2
  TOP w0.254: v1(105.96,82.58) 106.17,82.58 U6.H15 ; U6.H11 104.91,81.93 v1(105.13,81.93) 104.79,81.59 U6.J11 ; U6.AE8 102.77,73.06 v1(102.52,73.31)
  TOP w0.381: U6.AF22 110.66,72.48 v1(110.34,72.16)
  IN1 w0.508: v1(110.34,72.16) 110.34,72.31 109.75,72.9 108.58,72.9 107.99,72.3 103.53,72.3 v1(102.52,73.31)
  IN3 w0.508: v1(108.77,79.03) 109.6,78.21 109.6,77.85 111.06,76.39 111.06,72.89 v1(110.34,72.16)
  vias: v1(96.47,95.86) v1(97.1,95.86) v1(97.74,95.86) v1(99.99,92.01) v1(100.55,92.34) v1(100.55,91.72) v2(97.35,96.89) v2(99.61,95.54)
+1V05_DCPSUS1: length 1.5
  TOP w0.305: v1(102.54,74.3) 102.77,74.06 U6.AD8 U6.AD10
  vias: v1(107.37,74.77) v1(107.99,74.77) v5(102.07,74.76)
+1V05_DCPSUS2: length 0.5
  TOP w0.305: U6.AH13 105.15,71.65 v1(105.05,71.65)
  vias: v1(105.32,72.23)
+1V05_DCPSUS3: length 0.6
  TOP w0.254: v1(106.05,81.92) 105.72,81.59 U6.J13
  vias: v2(102.66,91.81)
+1V05_DCPSUS4: length 8.4
  TOP w0.254: v1(102.52,75.24) 102.52,75.02 U6.AB8
  IN1 w0.508: v1(102.52,75.24) 103.84,75.24 104.17,74.91 104.88,74.91 105.53,75.55 106.97,75.55 v1(107.61,76.19)
  BOTTOM w0.508: v1(107.61,76.19) 107.61,76.49 R386.2 ; v1(102.52,75.24) 102.52,75.36 102.78,75.63 102.9,75.63 C211.1
+1V05_S5: length 114.6
  TOP w0.508: R123.1 143.62,74.05 v1(143.15,74.05) 142.76,74.05 R122.1 ; R124.1 R125.1 v1(148.2,74.41) ; R54.1 160.52,86.35 157.09,82.92 ; v1(156.79,77.47) 156.79,82.63 157.09,82.92 ; v2(157.09,82.87) 157.09,82.92
  IN1 w0.508: v1(143.15,74.05) 143.52,74.41 v1(148.2,74.41) 149.78,76 151.64,76 152.18,76.54 155.87,76.54 v1(156.79,77.47)
  IN2 w1.016: 92.52,80.08 92.29,80.3 87.56,80.3 87.29,80.57 86.18,80.57 84.9,81.85 84.27,81.85 83.55,82.57 83.55,85.07 87.32,88.84 87.32,90.64 89.99,93.32 91.69,93.32 92.96,94.59 92.96,96.27 93.73,97.03 105.03,97.03 105.66,96.39
  IN3 w0.508: v1(106.7,76.19) 106.7,77.1 107.36,77.76 107.36,79.31 108.41,80.37 109.52,80.37 109.93,79.96 110.32,79.96 111.47,78.81 112.23,78.81 116.42,74.62 130.56,74.62 130.96,74.22 133.96,74.22 135.31,72.87 137.89,72.87 138.07,73.04 142.15,73.04 v1(143.15,74.05)
  vias: v1(92.35,79.6) v1(92.81,79.15) v1(106.12,95.33) v1(106.06,76.19) v1(106.43,95.89) v2(67.68,80.33) v4(68.63,79.78) v4(68.63,79.04) v4(68.63,78.28) v4(68.71,77.52) v4(69.44,77.52) v4(70.18,77.52)
+1V05_SRC: length 25.4
  TOP w0.254: v1(67.51,48.13) 67.94,48.13 68.65,48.83 68.65,52.13 69.82,53.3 v2(69.82,55.95) 69.82,66.45 67.06,69.22 67.06,70.48
  BOTTOM w0.254: PR149.1 67.56,48.08 v1(67.51,48.13)
  vias: v2(64.25,78.2) v4(64.2,74.26) v4(64.67,74.83) v4(65.58,74.17) v4(65.58,73.41) v4(66.32,74.17) v4(66.32,73.41)
+1V05_VCCASW: length 2.3
  TOP w0.254: 103.53,73.33 104.17,73.33 v1(104.46,73.62) ; 103.53,73.33 103.53,73.33 ; 103.53,73.33 U6.AE9 U6.AF9 103.21,72.39
  vias: v1(88.6,64.54) v1(89.18,64.29) v1(102.49,72.39) v2(88.38,62.85)
+1V05_VCCASW_1: length 0.6
  TOP w0.254: v1(106.68,71.64) 106.66,71.64 U6.AG14
  vias: v1(107.32,70.99)
+1V05_VCCASW_2: length 0.6
  TOP w0.305: U6.AG13 105.5,72.02 v1(105.87,71.66)
+1V5_VCCATS: length 13
  TOP w0.254: U6.J15 106.5,81.69 106.9,82.08 106.9,82.4 v1(107.06,82.57)
  BOTTOM w0.508: R333.2 108.84,92.33 108.58,92.08 v2(108.58,91.96) 108.58,91.19 107.89,90.49 107.51,90.49 106.81,89.79 106.81,87.38 107.19,87 107.19,82.69 v1(107.06,82.57)
+1V05_VCCCLK1: length 0.6
  TOP w0.305: U6.J17 107.78,81.92 v1(107.95,81.92)
  vias: v2(110.56,91.81)
+1V05_VCCCLK2:
  vias: v1(110.25,78.17) v2(111.14,78.63)
+1V05_VCCST: length 114.9
  TOP w0.254: R8.1 129.29,98.7 129.42,98.83 U2.5
  TOP w0.508: v1(97.31,101.19) 97.31,100.74 97.03,100.46 R1.2 ; R69.2 v1(144.53,82.8) ; R30.1 142.87,92.08 R42.2 v1(142.87,90.3) ; Q1.3 134.92,95.34 135.01,95.25 C11.1 135.78,93.97 R17.2 ; Q1.3 133.21,96.4 v2(132.18,97.44) 131.95,97.66 131.95,99.36 v1(131.44,99.86) ; Q1.3 136,96.4 136.02,96.38 R12.2 v1(138.04,96.38) ; R78.1 v1(144.53,81.66) ; R84.1 v1(144.53,80.52) ; v1(128.69,99.86) R8.1
  IN1 w0.508: v1(142.87,90.3) 142.37,90.8 142.37,92.84 138.82,96.38 v1(138.04,96.38)
  IN2 w0.508: v1(142.87,90.3) 141.86,89.29 141.86,86.39 144.53,83.72 v1(144.53,82.8) v1(144.53,81.66) v1(144.53,80.52) 143.76,79.76 141.48,79.76 138.43,76.71 137.03,76.71 135.76,75.44 134.49,75.44 133.25,74.19 128.08,74.19 126.98,73.09 116.27,73.09 v1(116.14,73.22)
  BOTTOM w0.508: v1(97.31,101.19) 97.31,101.24 99.21,103.15 125.41,103.15 v1(128.69,99.86) 129.35,99.21 131.06,99.21 131.44,99.59 v1(131.44,99.86) ; v1(111.67,75.73) 112.16,75.73 C207.1 112.72,76.29 113.83,76.29 116.14,73.98 v1(116.14,73.22)
+1V05_VCCUSBCORE: length 66.5
  TOP w0.254: U6.AG17 107.53,71.66 v1(107.49,71.66) 107.13,72.02 U6.AG16
  TOP w0.508: v1(73.3,73) 73.76,73 74.17,73.41 v2(74.17,76.09) 74.17,77.66 75.82,79.31 v1(75.82,80.64)
  IN1 w0.508: 105.51,81.38 105.7,81.19 109.99,81.19 110.41,81.61 112.53,81.61 115.03,79.11 115.03,77.56 115.79,76.8 115.79,73.88 114.42,72.51 113.27,72.51 112.11,71.34 110.27,71.34 109.73,71.88 109.73,72.01 109.46,72.28 108.85,72.28 108.23,71.66 v1(107.49,71.66) ; 99.86,84.18 98.14,82.45 96.37,82.45 94.98,81.06 88.54,81.06 87.45,82.15 86.46,82.15 86.12,81.8 84.32,81.8 83.04,83.08 78.26,83.08 v1(75.82,80.64)
  BOTTOM w0.508: C222.1 108.05,71.52 107.64,71.52 v1(107.49,71.66) ; v1(73.3,73) 73.38,72.92 R402.2
+1V05_VIN:
  vias: v2(59.96,57.01) v2(61.53,58.16)
+1V05DX_MODPHY: length 1.6
  BOTTOM w0.508: 72.89,81.16 72.89,82.3 PR130.1
  vias: v1(88.27,94.95) v1(88.73,95.5) v1(89.28,94.95) v1(89.38,95.83) v1(97.41,90.04) v1(97.41,89.41) v1(103.96,80.01) v1(104.52,99.67) v1(104.52,79.73) v1(105.16,99.67) v2(84.14,92.19) v2(85.36,94.58) v2(92.83,97.68) v2(104.82,98.36) v4(73.41,79.93) v4(73.91,79.4) v4(74.42,79.93)
+1V8_SUS: length 47
  TOP w0.254: v6(130.56,37.05) 130.88,36.72 U13.A5 130.88,36.57 v6(130.56,36.25) 130.88,35.92 U13.A4 ; U11.U6 103.66,37.38 v6(103.98,37.05) 104.65,37.72 104.65,39.65 U11.U10 ; U14.A3 148.97,35.05 v6(148.84,35.18) ; U13.A3 v6(130.38,35.05) ; U11.A4 93.26,35.92 v6(92.94,36.25) 93.26,36.57 U11.A5 ; U11.A10 92.25,39.64 92.25,37.73 v6(92.94,37.05) 93.26,37.37 U11.A6 ; v6(141.61,34.65) 141.28,34.97 U13.U3 ; U11.U4 103.66,35.77 v6(103.98,35.45) ; U11.U3 103.66,34.97 v6(103.98,34.65) ; U11.U5 103.66,36.57 v6(103.98,36.25) ; U12.A6 111.08,38.44 111.08,39.66 U12.A10 ; v6(141.61,35.45) 141.28,35.77 U13.U4 ; U13.U6 142.24,38.41 142.24,39.69 U13.U10 ; U14.A10 148.71,39.67 148.71,38.43 U14.A6 ; U13.A6 130.88,37.57 129.92,38.53 129.92,39.69 U13.A10 ; U13.U5 141.28,36.57 v6(141.61,36.25) ; U12.U10 123.43,39.69 123.43,38.41 U12.U6 ; v6(111.35,35.08) 111.38,35.05 U12.A3 ; U11.A3 v6(92.72,35.05)
  TOP w0.305: U12.A5 112.07,36.57 v6(111.75,36.25) 112.07,35.92 U12.A4 ; U14.A6 149.69,37.38 v6(149.36,37.05) 149.69,36.72 U14.A5 ; U12.A6 112.07,37.37 v6(111.75,37.05) ; v6(149.36,36.25) 149.69,35.92 U14.A4 ; U14.U10 160.65,40.65 161.24,40.06 161.24,37.87 v6(160.42,37.05)
  TOP w0.508: v1(90.63,36.75) C92.1
  vias: v1(106.35,33.05) v1(124.98,36.14) v1(127.38,36.49) v1(143.76,34.46) v1(162.53,34.52) v2(87.06,28.31) v2(93.59,30.95) v2(128.62,32.17) v2(162.09,35.17) v6(122.8,37.05) v6(122.8,36.25) v6(122.8,35.45) v6(141.61,37.05) v6(160.42,36.25) v6(161.06,34.57)
+1V8_SUS_C: length 0.8
  TOP w0.508: PR62.1 v1(84.45,26.8)
+3V3: length 540.2
  TOP w0.254: Q8.5 Q8.2 201.02,74.68 201.08,74.74 v1(201.08,74.73) ; Q10.2 v1(80.39,72.9) ; Q10.5 84.58,72.9 v1(84.71,72.77)
  TOP w0.279: U4.14 149.72,94.48 148.98,93.73 C12.1
  TOP w0.457: v1(86.79,81.45) 86.51,81.73 R76.2 ; v1(84.38,78.67) 84.38,78.68 R95.1 ; R62.2 v1(84.52,84.78) R61.1 ; v1(79.77,84.39) 79.94,84.39 R60.1 ; R88.2 85.04,79.7 v1(85.04,79.69) ; R87.1 82.36,79.7 v1(82.21,79.85) ; R82.1 84.62,80.71 v1(84.38,80.95) 84.14,80.71 R81.1 ; R65.2 v1(85.03,83.76) ; R64.2 v1(82.36,83.76) ; v1(84.93,77.46) 85.13,77.66 R99.2 ; R72.1 v1(84.9,82.74)
  TOP w0.508: v1(179.14,28.26) 179.01,28.13 C120.1 ; v1(149.1,95.6) 149.1,95.63 148.98,95.75 R15.2 C12.1 ; R228.1 60.06,31 61.09,29.97 65.08,29.97 66.17,28.89 66.17,23.75 ; v1(86.43,89.22) 86.43,88.84 86.68,88.59 R50.1 R51.1 ; v1(91.82,95) 92.7,94.12 R24.1 ; R226.2 32.13,35.37 32.96,36.2 v1(43.81,36.2) ; v1(18.48,94.44) R14.2 ; v1(48.51,13.08) 50.07,13.08 51.76,11.39 51.76,9.76 51.23,9.24 50.9,9.24 49.19,7.53 49.19,6.08 48.28,5.17 46.73,5.17 46.5,5.4 R783.1 ; R18.1 96.27,94.61 v1(95.89,95) ; R18.1 97.4,94.37 R19.1 ; R18.1 95.89,94.37 95.62,94.1 R25.1 ; R22.1 R21.1 R20.2 98.55,94.74 98.3,95 v1(97.41,95) ; R56.1 162.94,86.08 v1(162.33,85.47) ; C71.1 92.71,54.48 v1(92.84,54.36) 92.84,53.34 93.47,52.7 93.47,51.82 v1(93.34,51.69) ; R46.1 v1(82.62,89.22) ; v1(202.4,35.42) 202.24,35.58 R210.2 ; v1(16.31,87.6) 16.12,87.42 R53.2 ; R129.1 34.3,78.36 v1(34.24,78.3) ; v1(188.82,59.74) 189.89,58.67 PR42.2 ; R63.1 80.27,83.71 v1(79.72,83.71) ; v1(78.93,81.79) 80.13,81.79 R74.2 80.19,81.22 80.07,81.09 R80.1 ; v1(84.14,89.22) 84.14,88.97 84.65,88.46 R48.1 ; v1(64.46,46.01) 64.47,46.02 PR56.2 ; U5.6 18.86,85.54 v1(19.24,85.92) 19.93,86.61 C25.1 ; v1(20.26,86.05) 20.76,85.54 U5.4 ; v1(83.4,89.22) 83.4,88.58 R47.1 ; v1(78.44,79.32) 80.1,77.66 R97.1 R93.2 ; v1(132.71,99.86) 132.93,100.08 R2.1 ; v1(13.67,90.2) 13.11,89.64 12.42,89.64 Q6.2 ; v1(155.07,13.34) 154.31,14.09 PR64.2 ; Q7.2 14.48,88.01 14.48,87.73 v1(14.35,87.6) 14.23,87.49 R52.2 ; R157.2 R165.1 205.48,63.25 v1(205.49,63.25) ; U9.8 74.44,69.16 v1(74.53,69.25) ; R70.1 80.03,82.45 v1(79.71,82.45) ; v1(86.87,72.91) 86.87,72.67 86.27,72.08 R131.2 ; v1(78.49,73.2) 78.49,73.29 R121.2 ; R49.1 v1(85.66,89.22) ; Q9.2 v1(13.48,72.62) ; R128.1 31.36,78.54 v1(31.6,78.3)
  TOP w1.016: 65.85,23.66 64.94,23.66 64.06,22.78 64.06,21.93 66.56,19.42 74.56,19.42 79.49,14.49 v1(85.05,14.49) v1(86.07,14.49)
  IN1 w0.508: v1(84.71,72.77) 84.71,73.15 85.06,73.5 86.18,73.5 86.77,72.91 v1(86.87,72.91) ; v4(196.31,82.57) 195.71,83.16 195.71,93.09 194.77,94.03 v1(194.77,96.44)
  IN1 w2.54: 190.82,14.16 188.15,16.83 188.15,22.16 191.3,25.31 195.09,25.31 196.1,26.33
  IN2 w0.508: v1(202.4,35.42) 198.74,35.42 ; v1(188.82,59.74) 187.23,61.33 179.52,61.33 178.15,59.96 ; v1(108.78,77.33) 109.62,78.18 109.62,80.9 110.48,81.75 110.48,83.96 111.38,84.86 111.38,90.68 111.01,91.05 108.85,91.05 108.18,91.72 v1(107.91,91.72) ; 45.47,39.12 43.81,37.46 v1(43.81,36.2) ; v1(92.84,54.36) 88.65,54.36 85.09,57.91 79.63,57.91 77.85,59.69 72.26,59.69 ; 180.28,23.82 178.31,21.85 176.94,21.85 v1(176.8,21.71) 176.8,20.59 177.97,19.42 v1(177.97,18.13) ; v1(205.49,63.25) 205.55,63.31 205.55,70.27 201.1,74.73 v1(201.08,74.73) ; v1(84.71,72.77) 80.52,72.77 v1(80.39,72.9) 78.79,72.9 v1(78.49,73.2) ; 64.1,44.38 64.46,44.73 v1(64.46,46.01)
  IN2 w1.016: 64.1,44.38 64.02,44.3 64.02,42.41 68.58,37.85 68.58,33.73 v1(69.42,32.89) 69.42,31.83 66.13,28.54 66.13,24.29 66.93,23.49
  IN2 w2.54: 47.81,14.66 47.81,17.38 47.62,17.56 47.62,32.26 47.37,32.51 47.37,37.21 44.2,40.39 44.2,43.74 45.74,45.28 60.26,45.28 61.16,44.38 67.87,44.38 69.34,45.85 69.34,46.61 70.08,47.35 70.08,52.17 71.68,53.77 71.68,56.08
  IN2 w3.048: 164.86,79.8 195.03,79.8 195.83,78.99
  IN3 w0.508: v1(38.55,14.67) 38.55,14.16 39.31,13.4 42.61,13.4 43.05,13.84 v1(47.37,13.84) ; v1(194.77,97.46) v1(194.77,96.44) ; v1(176.02,12.95) 160.65,12.95 159.51,11.81 156.59,11.81 v1(155.07,13.34)
  BOTTOM w0.254: R552.1 176.97,22.55 175.86,22.55 175.58,22.27 Q17.2 ; Q25.5 Q25.2 37.34,12.95 37.53,13.15 37.53,14.04 38.17,14.67 v1(38.55,14.67) ; CN14.9 v1(86.07,14.49) ; CN14.10 85.57,15.01 v1(85.05,14.49) ; Q17.5 175.58,18.53 175.78,18.33 v2(176.11,18.33) 176.93,18.33 177.48,18.88
  BOTTOM w0.305: v1(92.84,54.36) 92.62,54.14 U18.5
  BOTTOM w0.457: R388.2 200.19,76.1 R398.2 ; v1(84.38,80.95) 84.62,80.71 R82.1 ; R87.1 82.36,79.7 v1(82.21,79.85) ; R61.1 v1(84.52,84.78) R62.2 ; R72.1 v1(84.9,82.74) ; R64.2 v1(82.36,83.76) ; v1(16.31,87.6) 16.16,87.6 15.62,88.14 R343.2 ; v1(79.72,83.71) 79.77,83.76 R63.1 ; R65.2 v1(85.03,83.76) ; v1(79.77,84.39) 79.94,84.39 R60.1 ; R369.2 87.94,81.6 86.94,81.6 v1(86.79,81.45) 86.51,81.73 R76.2 ; v1(84.38,78.67) 84.38,78.68 R95.1 ; R375.2 89.38,78.81 v1(89.35,78.84) 89.31,78.81 R374.1 ; R88.2 85.04,79.7 v1(85.04,79.69)
  BOTTOM w0.508: R330.1 R334.1 92.08,93.6 91.82,93.85 v1(91.82,95) ; Q21.2 200.28,80.42 v1(200.15,80.54) ; v1(61.66,84.96) PR127.2 ; R525.2 R527.2 v1(43.81,36.2) 43.94,36.07 43.94,33.28 R529.2 ; v1(108.78,77.33) 109.21,77.33 R382.2 109.49,76.24 R396.1 ; PR125.1 74.75,84.64 v1(75.5,83.89) ; R332.1 89.56,91.44 v1(89.35,91.23) ; PR92.2 PR95.2 194.77,97.75 v1(194.77,97.46) ; Q20.2 76.58,79.12 v1(77.09,78.61) ; R420.2 74.42,69.14 v1(74.53,69.25) 75.06,69.78 C233.1 ; R99.2 85.13,77.66 v1(84.93,77.46) ; R485.1 93.61,51.43 v1(93.34,51.69) ; R362.1 79.79,82.36 v1(79.71,82.45) ; v1(83.4,89.22) 83.4,88.58 R47.1 ; R378.1 195.58,77.6 v1(195.65,77.54) ; R552.1 177.15,21.71 v1(176.8,21.71) ; v1(13.67,90.2) 13.63,90.16 Q18.2 ; R387.2 196.59,76.58 v1(196.34,76.58) ; v1(65.28,93.85) 66.03,94.61 PR101.1 ; v1(78.93,81.79) 79.19,81.79 80.19,80.78 R370.2 ; v1(176.02,12.95) 191.77,12.95 v4(191.96,13.15) ; v1(194.77,96.44) 194.77,96 PR99.2 ; v1(177.97,18.13) 177.48,18.62 R559.1 ; R398.2 200.62,75.18 v1(201.08,74.73) ; PR152.2 77.86,34.8 73.53,34.8 71.63,32.89 v1(69.42,32.89) ; v1(74.45,65.66) 74.42,65.63 R430.1 R431.1 R432.1 ; v1(84.14,89.22) 84.14,88.85 R48.1 ; R49.1 v1(85.66,89.22) ; R46.1 v1(82.62,89.22)
  BOTTOM w1.016: 47.12,14.35 44.58,16.89 42.93,16.89 41.06,18.76 R557.2
  vias: v1(18.74,86.58) v1(47.37,13.08) v1(48.01,13.46) v1(48.51,13.84) v1(66.55,22.61) v1(67.18,22.61) v1(86.49,102.62) v1(86.55,104.21) v1(86.87,103.38) v1(87.38,104.14) v1(87.5,102.62) v1(167.39,62.23) v1(167.39,61.59) v1(168.02,61.59) v1(179.39,27.63) v1(179.77,28.26) v1(180.15,27.63) v1(180.41,28.26) v2(48.91,14.75) v2(49.29,14.54) v2(196.74,80.48) v4(61.15,84.27) v4(61.92,84.27) v4(62.42,85.03) v4(62.65,84.27) v4(63.19,85.16) v4(63.39,84.39) v4(191.96,13.91) v4(192.73,14.29) v4(192.73,13.53) v4(192.73,12.77) v4(196.31,81.75) v4(197.02,82.36) v4(197.53,27.65) v4(197.93,27.04) v4(198.54,27.65)
+3V3_ADO: length 12.5
  TOP w0.203: U16.1 37.89,19.26 v1(38.23,18.92) ; v1(30.81,18.75) U16.36 ; v1(37.94,22.61) 37.8,22.46 U16.9
  TOP w0.508: R310.1 39.83,17.61 v1(39.83,17.81)
  IN1 w1.016: v1(38.23,18.92) 37.72,18.92 37.15,18.35 31.98,18.35 31.84,18.21 31.56,18.48
  BOTTOM w0.762: C385.1 31.62,19.56 v1(30.81,18.75)
  vias: v1(39.06,18.61) v2(38.9,22.98) v2(39,17.9)
+3V3_CCD: length 7
  TOP w0.102: R90.1 200.57,79.56 v2(200.57,78.5)
  TOP w0.508: R90.1 201.07,80.07 C43.1 C44.1 204.15,80.07 v1(204.54,80.46)
  BOTTOM w0.241: v1(204.54,80.46) 204.88,80.11 205.38,80.11 CN7.3
+3V3_DMIC: length 5.4
  BOTTOM w0.508: CN17.1 43.11,10.49 43.5,10.89 44.31,10.89 v2(44.53,11.1) 45.33,11.9 C404.1 45.33,12.56 44.86,13.04 R574.1
+3V3_EC: length 4.2
  TOP w0.508: v2(62.42,33.14) 61.71,33.14 v1(61.62,33.22) 61.02,33.22 C100.1 R228.2
  BOTTOM w0.203: v1(61.62,33.22) 61.97,33.57 U23.11
+3V3_PCU: length 269.4
  TOP w0.305: RP1.5 v1(67.87,13.59) ; v1(63.91,11.05) RP1.10
  TOP w0.508: v1(19.37,89.58) 19.11,89.84 R40.2 ; PU6.5 v1(111.51,6.86) ; R194.1 v1(35.97,45.06) ; R196.1 33.3,43.79 v1(33.02,44.07) ; v1(57.78,59.05) 57.78,58.8 58.17,58.42 PR44.1 ; v1(21.53,88.56) 21.28,88.81 R45.2 ; v1(28.39,43.63) 27.82,43.06 v2(27.82,39.79) R214.2 ; PR69.2 v1(107.06,8.76) ; R136.1 v1(87.4,70.48) ; v1(22.44,95.21) 22.89,95.66 D6.1 C24.1 23.99,94.76 23.7,94.46 HE1.1 ; v1(29.06,50.42) PQ12.3
  IN1 w0.508: v1(93.52,78.44) 94.06,78.97 94.06,79.73 94.71,80.38 95.19,80.38 96.64,81.83 98.53,81.83 98.98,81.38 99.63,81.38 ; v1(114.62,74.11) 114.9,74.39 114.9,76.52 112.52,78.89 111.48,78.89 110.4,79.98 109.99,79.98 109.4,80.57 104.81,80.57 104.74,80.63 103.24,80.63
  IN2 w0.508: v1(23.03,89.37) 23.03,94.63 v1(22.44,95.21) ; v1(67.87,13.59) 65.33,11.05 v1(63.91,11.05) 63.02,10.16 58.76,10.16 56.4,12.51 v1(53.66,12.51)
  IN2 w1.016: 80.18,27.07 81.07,26.18 81.07,14.77 83.23,12.61 100.42,12.61 104.27,8.76 v1(107.06,8.76) 108.97,6.86 v1(111.51,6.86) 117.2,12.55 130.84,12.55 131.37,13.08 147.83,13.08
  IN2 w1.524: 67.76,41.47 68.9,40.33 71.31,40.33 76.27,45.28 76.27,49.34 77.79,50.87
  IN3 w0.508: v1(57.78,59.05) 57.78,58.75 56.64,57.61 56.64,50.93 54.36,48.64 54.36,43.43 v1(54.64,43.15) ; v1(53.66,12.51) 53.66,13.27 45.31,21.62 45.31,24.51 44.57,25.26 44.57,29.18 47.42,32.04 47.42,41.99 48.11,42.67 v1(48.11,43.31) ; v1(91.64,59.46) 92.21,59.46 92.74,58.93 94.95,58.93 v1(95.38,59.36) ; v1(93.52,78.44) 93.52,77.84 90.66,74.98 88.16,74.98 87.39,74.21 86.4,74.21 86.03,73.84 v1(86.03,72.75)
  BOTTOM w0.305: CN18.1 53.95,9.76 C153.1 ; U21.5 21.42,49.95 20.96,49.49 R490.1
  BOTTOM w0.508: R409.1 83.43,72.51 84.39,73.47 85.54,73.47 86.03,72.98 v1(86.03,72.75) ; R455.1 92.74,58.93 92.21,59.46 v1(91.64,59.46) ; R509.2 v1(53.49,43.15) ; R417.1 85.46,68.96 v1(84.84,68.96) ; v1(67.25,42.74) 67.25,42.1 66.87,41.72 D32.1 65.6,41.72 65.4,41.92 R517.2 ; C153.1 C150.1 54.67,11.5 v1(53.66,12.51) ; v1(82.42,65.15) R428.1 R427.1 ; R510.2 v1(54.64,43.15) ; PR167.2 152.53,7.37 v1(152.53,7.37) ; v1(114.62,74.11) 115,73.73 R408.2 ; R506.1 49.53,42.73 49.53,43.18 v1(49.66,43.31) ; R452.1 95.06,59.05 v1(95.38,59.36) ; v1(158.37,13.08) PC126.1 ; v1(157.35,13.08) PR160.2 ; PR156.2 147.46,13.6 v1(147.95,14.1) ; PR170.2 149.73,5.09 149.73,5.18 v1(150.26,5.71) ; v1(154.19,13.32) PR155.2 ; v1(155.72,8.25) PR166.2 ; v1(22.2,49.02) R490.1 ; C265.1 v1(22.2,48.01)
  vias: v1(65.98,42.74) v1(66.61,42.74) v1(78.6,51.81) v1(78.6,51.17) v1(78.6,50.54) v1(79.4,27.64) v1(79.38,26.97) v1(80.2,62.42) v1(80.2,61.79) v1(80.2,61.15) v1(81.54,48.01) v1(81.54,47.37) v2(20.51,89.6) v2(42.79,87.8) v2(48.71,41.87) v2(54.22,81.98) v4(56.45,81.47) v4(56.71,80.71) v4(57.47,81.85) v4(57.47,81.09) v4(57.47,80.33) v4(83.82,39.62) v4(84.45,40) v4(84.45,39.24)
+3V3_PCU_EC: length 74.5
  TOP w0.508: 59.25,37.28 59.31,37.34 R208.1 60.19,37.84 60.39,38.04 61.27,38.04 v1(61.34,37.97) ; 59.44,27.82 54.19,27.82 v1(53.75,28.27) ; 48.96,37.91 49.78,37.09 C96.1 49.16,35.7 v1(49.02,35.56) ; v1(43.81,26.37) 44.58,25.59 v2(45.33,25.59) 47.06,25.59 47.56,26.1 47.56,38.17 ; v1(55.98,37.53) 55.83,37.68 C86.1 55.83,39.17 55.82,39.18 ; 57.34,39.18 57.33,39.17 C87.1 57.33,37.54 v1(57.34,37.53) ; v1(61.46,27.57) 61.21,27.82 C124.1 ; C138.1 55.13,24.32 v1(54.74,24.71)
  TOP w0.762: 59.88,28.51 59.88,29.78 57.85,31.82 57.85,35.88 59.25,37.28 59.25,38.42 58.49,39.18 v2(52.64,39.18) 49.72,39.18 48.83,38.29
  IN1 w0.508: v1(53.75,28.27) 53.75,26.75 54.74,25.76 v1(54.74,24.71)
  BOTTOM w0.178: U23.92 48.03,35.97 48.16,36.09 48.49,36.09 v1(49.02,35.56) ; v1(55.98,37.53) 55.98,37.72 55.59,38.11 U23.114 ; U23.121 58.39,38.33 57.85,37.79 57.6,37.79 v1(57.34,37.53)
  BOTTOM w0.203: U23.26 v1(61.46,27.57) ; v1(54.74,24.71) 54.39,24.37 U23.50
  BOTTOM w0.508: L19.1 43.63,26.54 v1(43.81,26.37) ; L14.2 63.63,40.59 61.65,38.61 61.65,38.32 61.44,38.11 61.34,38.11 v1(61.34,37.97)
+3V3_PCU_ECAVCC: length 4.1
  BOTTOM w0.203: C370.1 44.73,28.51 v1(45.41,28.51) 45.67,28.77 U23.74
  BOTTOM w0.508: C370.1 L19.2
+3V3_PCU_ECPLL: length 6.3
  BOTTOM w0.203: U23.127 60.79,40.68 60.45,41.02 C293.2
  BOTTOM w0.508: C293.2 60.61,41.77 61.5,42.67 v2(62.27,42.67) 63.49,42.67 L14.1
+3V3_PCU_ECVBAT: length 4.6
  TOP w0.508: v1(61.67,36.27) 61.59,36.2 C93.1 R208.2 61.03,37.28 v2(62.07,37.28)
  BOTTOM w0.203: U23.3 61.86,36.77 61.77,36.68 61.77,36.37 v1(61.67,36.27)
+3V3_RTC: length 50.8
  TOP w0.305: U6.AG10 103.83,72.02 v1(103.13,71.32)
  TOP w0.508: v1(92.95,59.62) 93.01,59.69 R174.2 ; v1(99.95,57.71) 99.95,58.28 R179.2 ; v1(98.54,57.46) 98.54,58.4 R178.2
  IN2 w0.508: v1(102.74,57.68) 102.51,57.91 100.15,57.91 v1(99.95,57.71) 99.7,57.46 v1(98.54,57.46) 97.48,57.46 97.41,57.53 95.04,57.53 v1(92.95,59.62)
  IN2 w1.016: 83.82,48.64 85.22,50.04 89.15,50.04 92.46,53.34 94.34,53.34 v1(95.28,54.28) 95.81,54.28 98.54,57.01 v1(98.54,57.46) 98.54,64.76 99.95,66.17
  BOTTOM w0.508: v1(102.74,57.68) 102.61,57.82 R459.2 ; v1(95.28,54.28) v2(96.14,55.14) 96.78,55.79 C255.1 96.81,56.79 R465.2 96.81,58.8 C250.1 C247.1 ; v1(82.93,48.41) 83.4,48.41 C264.1
  vias: v1(82.93,47.78)
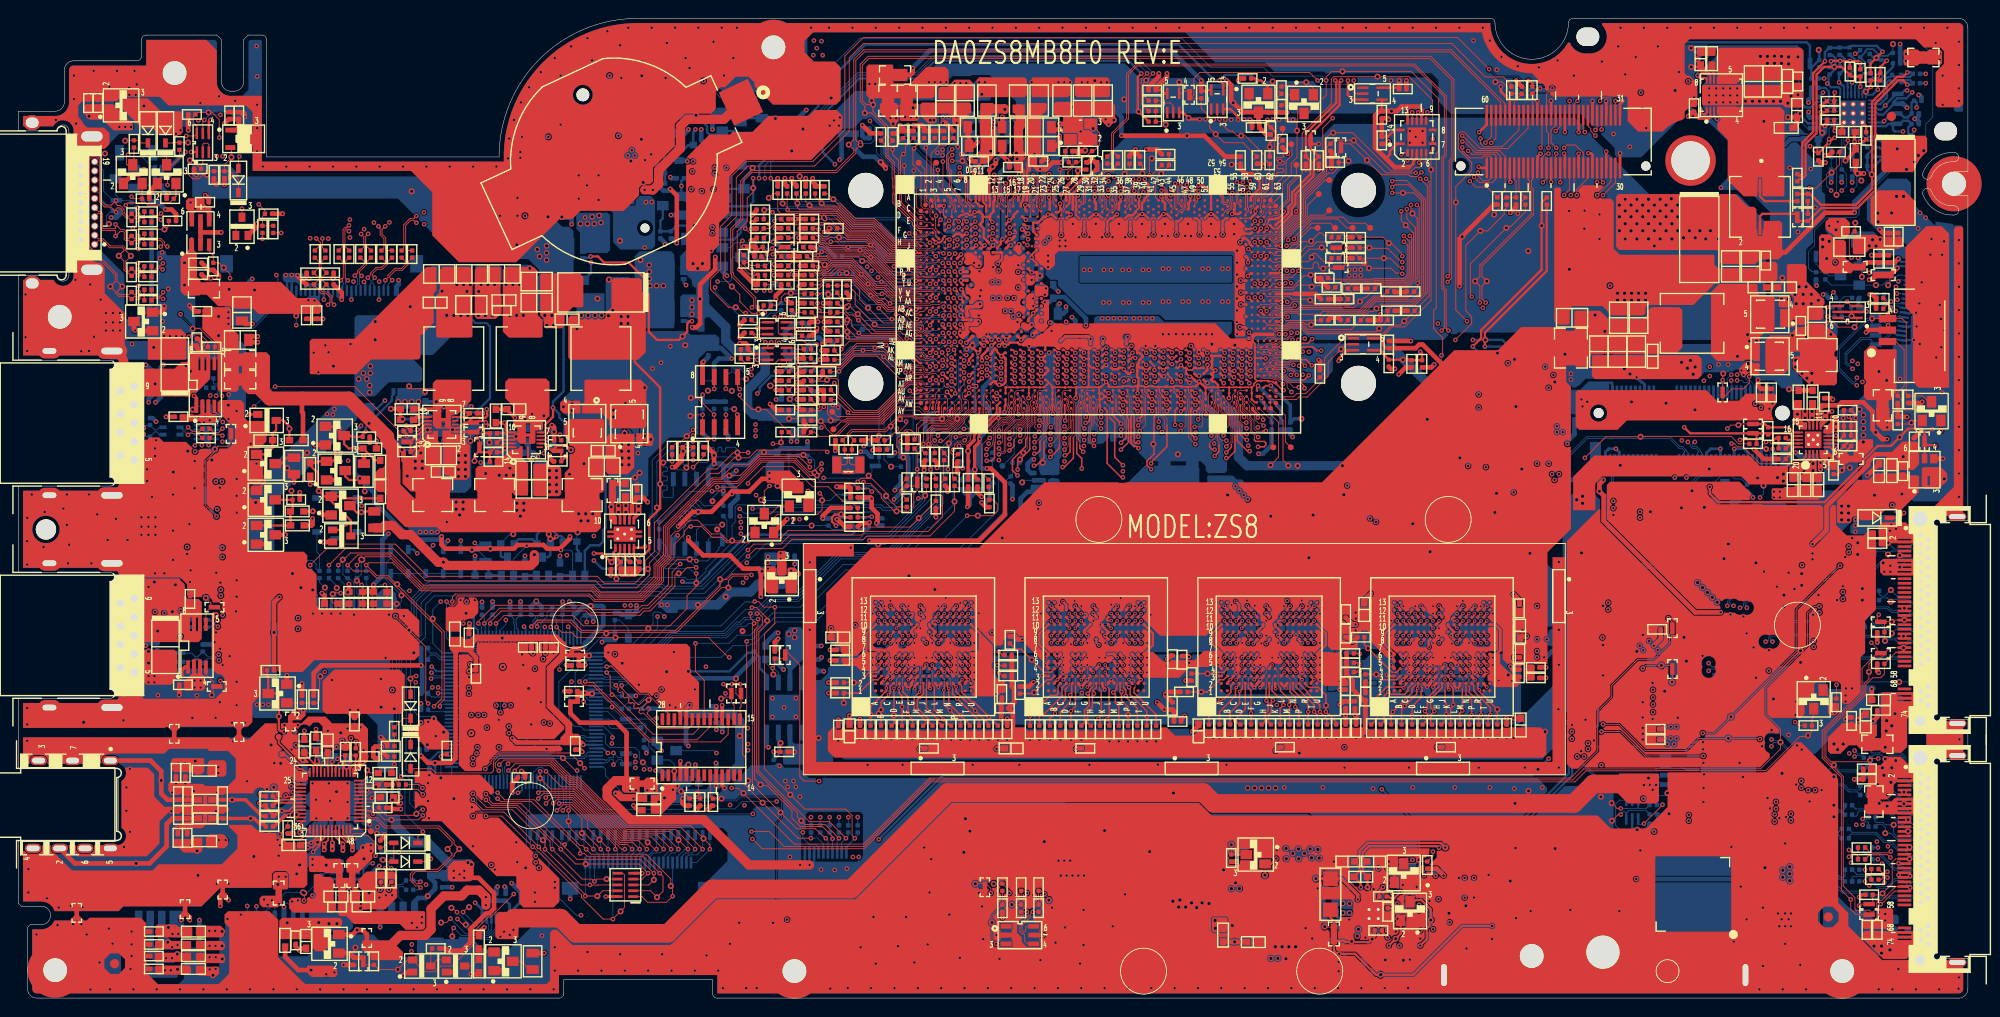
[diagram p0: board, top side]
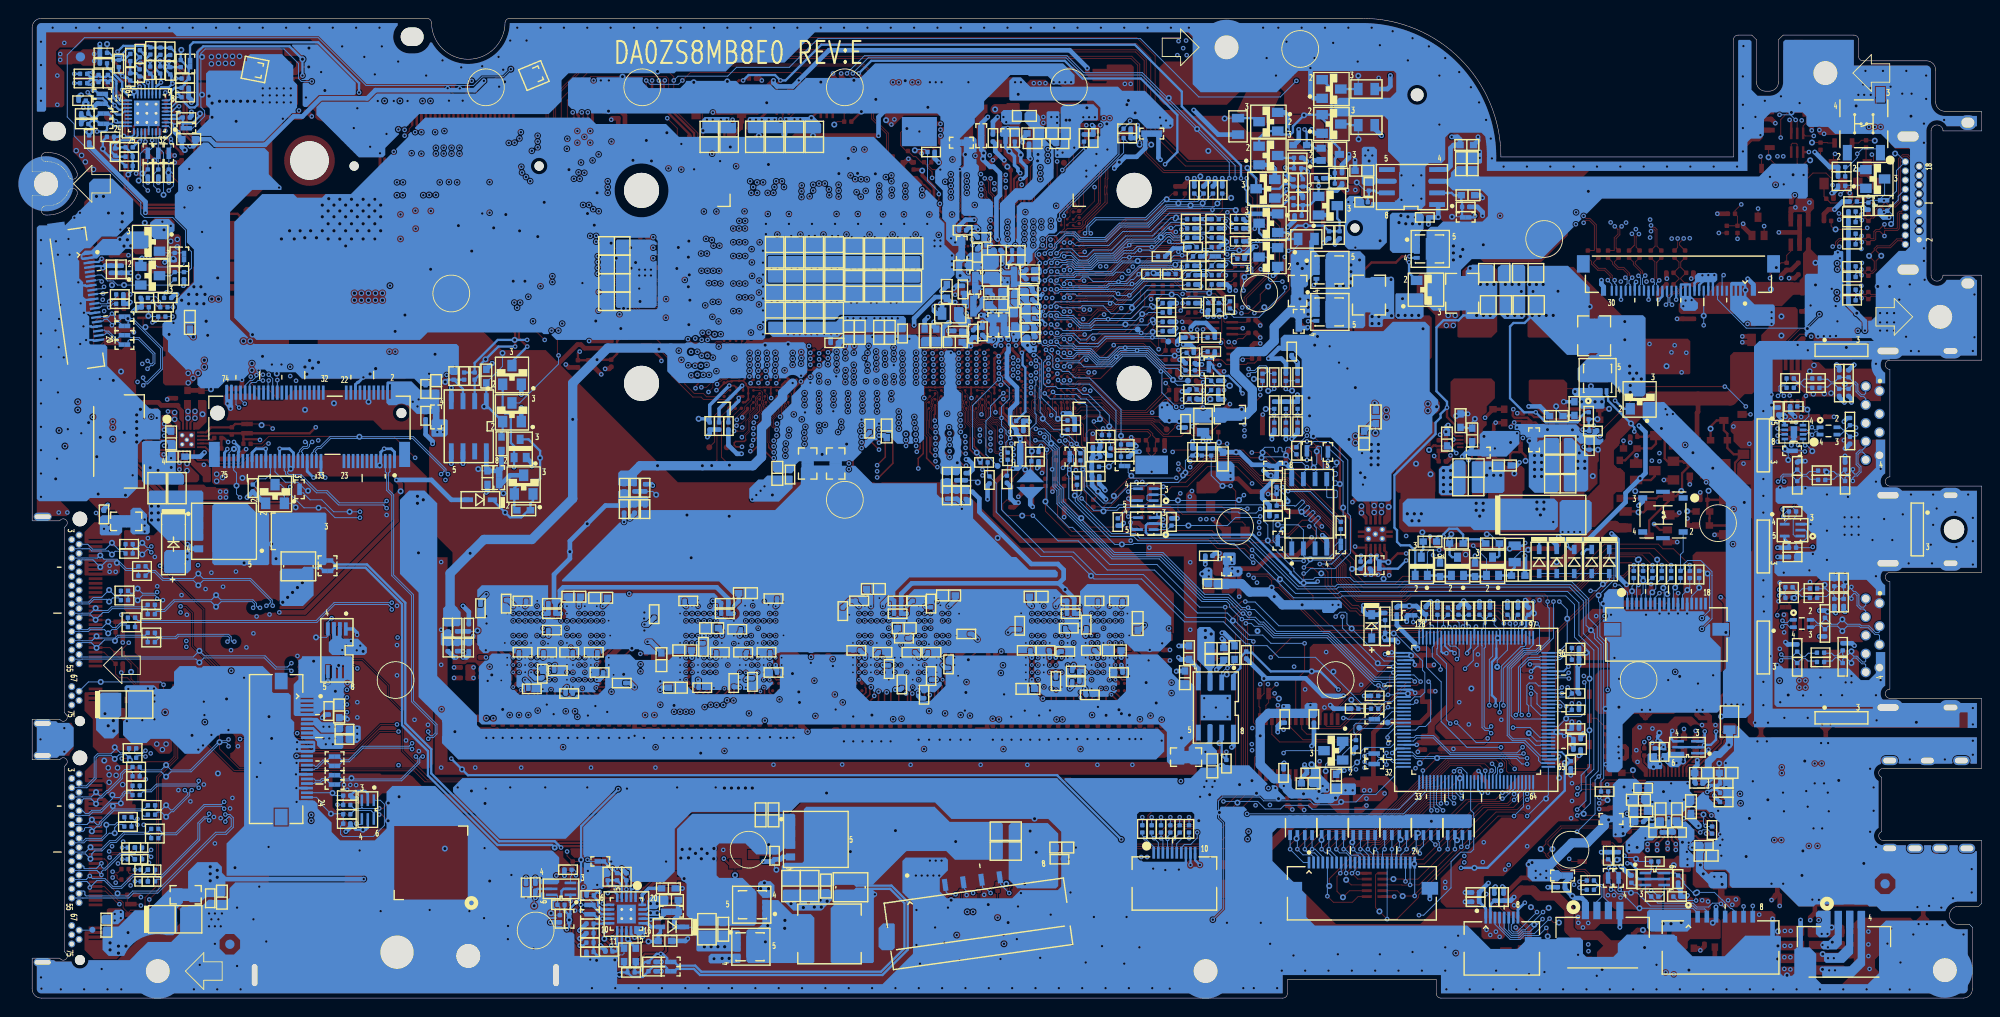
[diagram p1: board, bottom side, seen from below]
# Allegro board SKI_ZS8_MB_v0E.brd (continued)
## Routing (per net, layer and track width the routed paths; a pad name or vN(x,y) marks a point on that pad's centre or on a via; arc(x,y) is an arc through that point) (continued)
+3V3_S5: length 396.7
  TOP w0.254: R134.2 79.89,70.1 Q11.2 ; R140.2 85.46,69.86 85.22,70.1 Q11.5
  TOP w0.279: U3.5 124.68,98.46 124.32,98.82 C2.1
  TOP w0.508: R167.1 85.46,61.84 v1(85.85,62.23) 85.46,62.62 R164.1 ; R778.1 87.95,71.57 v1(87.5,71.12) ; v1(105.38,57.63) 105.82,57.63 107.34,56.11 107.34,52.6 104.52,49.78 v1(92.58,49.78) ; R132.1 87.95,72.58 87.95,72.61 v1(87.65,72.91) ; R113.1 84.85,75.63 v1(84.84,75.62) ; R148.1 v1(82.42,67.18) ; v1(84.84,69.6) R140.2 ; R151.1 v1(82.42,66.17) ; R134.2 79.38,70.98 79.12,71.25 v1(78.49,71.25) ; R114.1 v1(87.57,75.63) ; R126.1 86.18,73.6 v1(86.98,73.6) ; v1(162.95,99.82) R5.1 ; v1(78.49,71.88) 78.99,72.38 R130.1 ; v1(87,66.01) 87.15,66.17 R153.1 R156.1 ; R144.1 v1(82.42,68.2) ; R160.1 82.42,64.01 v1(81.79,64.64) ; R145.1 85.41,68.15 85.03,68.15 84.8,67.92 v1(84.8,67.91) ; R127.1 v1(87.65,73.6) ; R116.1 83.93,75.64 v1(83.56,76.01) ; C2.1 123.75,99.06 124.97,100.28 v1(124.97,100.63) ; R141.1 v1(87.25,69.47) ; R146.1 87.52,67.91 v1(87.15,67.54) ; v1(82.41,76.01) 82.41,76.45 82.99,77.03 R98.1 ; C73.1 91.69,51.68 92.52,51.68 v1(92.6,51.76) ; R155.1 v1(84.71,65.15)
  TOP w1.016: v1(50.87,10.1) v1(50.87,10.99) 50.1,11.75 48.83,11.75 48.2,11.12 46.29,11.12 44.9,9.72 44.9,7.46 44.26,6.82 41.57,6.82 40.55,5.81 ; v4(56.13,48.26) 56.13,47.47 55.74,47.08 46.6,47.08 v2(46.24,47.44) 45.66,47.44 42.66,50.43 41.72,50.43 40.72,51.44 39.88,51.44 39.62,51.17 PR54.1
  IN1 w0.508: v1(106.64,79.19) 106.67,79.16 107.77,79.16 108.52,78.41 109.11,78.41 109.98,77.54 110.51,77.54 111.24,78.27 111.98,78.27 112.51,77.74 112.51,75.33 114,73.84 v1(114,73.59) ; v1(124.97,100.63) 126.96,102.62 157.61,102.62 159.83,100.39 161.61,100.39 162.18,99.82 v1(162.95,99.82)
  IN1 w1.016: 67.81,21.72 69.37,21.72 70.3,20.79 72.76,20.79 73.65,21.68 75.35,21.68 77.03,20.01 78.02,20.01 v1(78.99,20.98)
  IN2 w0.508: v1(197.93,84.5) 197.93,86.17 194.07,90.03 194.07,90.95 194.94,91.82 v1(194.94,92.71) ; v1(114,73.59) 114.14,73.45 114.84,73.45 115.31,73.91 115.31,79.62 117.22,81.53 117.22,83.19 116.4,84.01 116.4,88.63 117.06,89.29 117.33,89.29 119.37,91.33 119.37,98.79 119.82,99.24 123.93,99.24 124.97,100.28 v1(124.97,100.63)
  IN2 w1.016: 84.71,51.44 84.2,50.93 80.3,50.93 77.85,48.48 77.85,38.86 80.01,36.7 80.01,32.13 78.23,30.35 78.23,24 78.99,23.24 v1(78.99,20.98) 78.99,19.25 78.23,18.49 78.23,14.1 70.87,6.73 60.05,6.73 57.57,9.21 53.15,9.21 52.64,9.72 51.25,9.72 v1(50.87,10.1) ; v4(56.35,43.21) 56.35,43.15 57.47,42.04 59.52,42.04 60.9,40.66 60.9,39.94 62.88,37.96 62.88,23.79 64.4,22.27 v1(64.96,22.27)
  IN3 w0.508: v1(194.94,92.71) 196.72,92.71 197.36,92.08 201.98,92.08 202.82,92.91 202.82,94.23 v1(205.49,96.9) ; v1(95.58,61.99) 95.58,61.44 95.01,60.87 93.28,60.87 92.48,60.07 v1(91.97,60.07)
  IN3 w1.016: v4(56.35,43.21) 56.35,48.04 v4(56.13,48.26)
  BOTTOM w0.102: v1(95.58,61.99) 95.71,61.86 R777.1
  BOTTOM w0.305: v1(92.6,51.76) 92.6,51.2 92.39,50.99 U20.5 ; C162.1 53.45,10.17 CN18.2
  BOTTOM w0.508: R418.1 86.99,69.47 v1(87.25,69.47) ; v1(84.84,75.62) 84.85,75.63 R113.1 ; R463.2 77.61,58.04 79.38,58.04 80.75,59.41 v2(81.12,59.41) R458.2 82.97,59.83 R450.1 C248.1 R451.1 v1(85.85,60.58) ; v1(162.95,99.82) 163.97,98.81 174.75,98.81 175.64,97.92 180.73,97.92 182.69,95.95 183.66,95.95 186.75,92.86 192.18,92.86 192.79,93.47 PR105.2 194.34,92.94 194.56,92.71 v1(194.94,92.71) ; v1(87.5,71.12) 87.5,71.5 87.12,71.88 R410.1 ; R511.2 55.78,42.58 56.35,43.15 ; v4(56.35,43.21) 56.35,43.15 ; 56.35,43.15 56.92,42.58 R512.2 ; v1(84.71,65.15) 85.34,65.15 R429.1 ; R453.2 104.6,57.89 104.86,57.63 v1(105.38,57.63) ; R381.1 105.55,78.93 106.39,78.93 v1(106.64,79.19) ; v1(84.84,69.6) 84.71,69.72 83.68,69.72 83.43,69.98 R412.1 ; R407.2 114,73.08 v1(114,73.59) ; R776.1 86.4,66.01 v1(87,66.01) ; v1(50.87,10.99) 51.26,10.6 C159.1 C162.1 ; v1(91.97,60.07) 92.15,60.25 R445.1 ; R98.1 82.11,77.66 81.8,77.36 v1(81.8,77) ; v1(205.49,96.9) 205.05,97.33 PR97.2 ; R132.1 87.94,72.58 87.94,72.61 v1(87.65,72.91) ; R399.1 R114.1 v1(87.57,75.63) ; R127.1 v1(87.65,73.6) ; R148.1 v1(82.42,67.18)
  vias: v1(66.93,21.72) v1(84.35,52.12) v1(84.99,52.12) v1(85.92,55.18) v1(86.15,54.57) v1(197.02,84.04) v2(63.01,76.11) v2(197.75,83.61) v4(61.25,74.3) v4(61.99,74.3) v4(62.73,74.3) v4(63.46,74.3)
+3V3_S5_DEEP: length 85.4
  TOP w0.305: v1(105.05,71.02) 104.93,71.02 104.65,71.29 U6.AH11
  TOP w0.508: v1(71.78,51.33) 73.37,52.92 v2(73.98,52.92) 75.4,52.92 77.6,55.12 79.5,55.12 80.9,56.52 v1(81.72,56.52) ; R195.1 v1(38.63,44.98)
  IN1 w0.508: v1(40.26,50.55) 43.41,47.4 61.85,47.4 62.37,46.88 68.72,46.88 69.47,47.62 69.47,49.02 v1(71.78,51.33)
  IN3 w1.016: 81.03,57.02 80.62,57.43 80.62,60.17 81.22,60.77 81.22,63.31 80.92,63.61 80.92,65 81.53,65.61 81.53,68.88 84.03,71.37 85.85,71.37 86.5,72.02 87.97,72.02 90.07,74.12 91.02,74.12 94.12,77.22 95.5,77.22
  BOTTOM w0.508: v1(40.26,50.55) 39.6,49.89 39.6,45.95 v1(38.63,44.98)
  vias: v1(81.72,57.15) v1(104.61,75.53) v1(110.25,73.29)
+3V3_S5_HDA: length 12.9
  TOP w0.254: v1(105.87,71.02) 105.96,71.02 U6.AH14
  BOTTOM w0.508: R453.1 v1(104.6,60.85) 104.6,61.03 105.04,61.47 C245.1 105.04,61.86 105.69,62.51 105.69,64.03 104.95,64.77 104.95,66.45 106.05,67.54 106.05,70.15 105.87,70.33 v1(105.87,71.02)
+3V3_S5_PSPI: length 4.2
  TOP w0.254: v1(102.47,76.19) 102.77,75.89 U6.Y8
  BOTTOM w0.508: R381.2 104.54,77.74 104.45,77.65 103.69,77.65 103.28,77.25 C206.1 103.28,76.95 102.85,76.52 102.8,76.52 v1(102.47,76.19)
  vias: v5(102.15,76.67)
+3V3_S5_SPI: length 12
  TOP w0.508: v1(75.69,58.17) v2(75.69,59.07) 75.69,59.24 74.98,59.95 R177.2
  BOTTOM w0.508: U19.8 75.06,57.53 v1(75.69,58.17) 76.45,58.17 R463.1 C254.1 76.7,56.68 78.27,55.11 78.27,54.39 78.06,54.18 78.03,54.18 77.48,53.63 77.48,53.6 R478.2 R482.1
+3V3_SATA_N0:
  vias: v2(201.67,7.13) v2(204.26,25.85) v4(201.89,5.65) v4(202.25,23.23) v4(202.71,5.65) v4(202.71,4.89) v4(202.81,25.06) v4(202.96,24.25) v4(203.62,6.01) v4(203.62,5.25) v4(203.72,24.3) v4(203.72,23.48) v4(203.82,25.06)
+3V3_SATA_N0_N:
  vias: v2(203.32,20.89)
+3V3_SATA_N1:
  vias: v1(203.62,50.87) v1(203.77,51.53) v1(204.28,51.07) v2(204.18,30.95) v4(197.63,31.1) v4(203.22,29.07) v4(203.27,30.19) v4(203.82,29.63)
+3V3_SATA_N1_N:
  vias: v1(199.86,52.09) v1(199.86,51.42) v1(199.86,50.76) v1(203.01,46.4) v1(203.67,47.06) v1(203.67,46.4) v2(202.89,47.36)
+3V3_SER: length 7.7
  TOP w0.508: v1(201.42,76.58) 201.7,76.58 R787.2 R788.2
  IN1 w0.508: v4(202.11,81.84) 202.28,81.67 202.28,77.43 v1(201.42,76.58)
  vias: v2(202.55,82.57) v4(201.37,81.86) v4(201.74,82.52)
+3V3_SUS: length 324.2
  TOP w0.508: v2(31.84,3.05) 30.46,3.05 29.02,4.49 R323.1 ; v1(66.93,20.95) 67.44,20.45 R303.2 ; v1(154.04,68.95) 153.73,68.64 R779.1 ; v1(27.05,49.4) PQ12.1 ; v1(29.97,56.13) PR46.1
  IN2 w1.016: 154.93,69.03 155.87,68.09 158.13,68.09 168.57,57.65 172.99,57.65 179.39,51.25 179.39,46.09 184.88,40.6 190.49,40.6 191.79,39.31 191.79,35.37 190.26,33.85 184.06,33.85 182.64,35.27 177.48,35.27 175.58,33.37 175.58,26.94 167.35,18.71 93.26,18.71 92.65,18.1 92.65,16.27 91.79,15.41 ; v1(29.97,56.13) 27.96,54.12 27.96,52.19 27.05,51.28 v1(27.05,49.4) 27.05,42.19 30.69,38.55 34.35,38.55 42.28,30.62 42.28,27.6 42.84,27.04 42.84,18.03 44,16.87 44,14.28 45.24,13.03 45.24,11.2 44.9,10.86 42.94,10.86 41.29,9.21 33.6,9.21 32.87,8.48 32.87,4.12 33.67,3.32
  IN3 w1.016: 91.23,14.62 91.23,13.86 90.39,13.02 84.32,13.02 83.25,14.09 79.34,14.09 76.27,17.16 69.18,17.16 67.6,18.74 67.6,20.28 ; v1(34.38,2.79) 34.56,2.62 37.89,2.62 39.12,3.85 51.76,3.85 60.26,12.36 60.26,16.1 60.5,16.34 60.5,18.17 63,20.67 64.84,20.67
  vias: v1(33.49,2.59) v1(90.79,15.36) v1(91.43,15.36)
+3V3_TPM: length 25.8
  TOP w0.406: U15.19 v1(75.92,31.75) ; U15.10 v1(75.92,23.09) ; U15.24 72.67,31.52 v1(73.02,31.88)
  TOP w0.508: v1(72.26,21.72) 72.26,21.21 72.53,20.95 R299.1
  BOTTOM w1.016: 70.23,22.33 70.85,21.72 v1(72.26,21.72) 72.77,22.23 v2(73.78,22.23) 75.06,22.23 75.56,22.73 75.56,23.62 ; 73.02,30.99 77.6,30.99 78.49,30.1 v2(78.49,28.54) 78.49,25.4 76.96,23.88 76.33,23.88
  vias: v1(68.43,22.61) v1(69.22,22.61)
+3V3_TPM_VSB: length 1.2
  TOP w0.406: v4(72.9,25.4) 72.67,25.17 U15.5
  vias: v1(71.21,22.67) v1(71.69,23.08) v2(70.3,21.78)
+3V3_VCCPCORE: length 1.2
  TOP w0.254: U6.W9 103.2,76.19 102.77,76.62 U6.V8 102.77,76.97 v1(102.6,77.14)
  vias: v1(105.98,77.9) v1(106.62,77.9) v5(106.29,78.35)
+3V3_VCCPTS: length 23.4
  TOP w0.254: U6.K14 106.05,81.14 106.95,81.14 U6.K16 106.98,80.37 v1(106.55,79.95)
  TOP w0.508: v1(94.36,90.3) 94.36,90.43 v2(93.82,90.97)
  IN2 w0.508: v1(106.55,79.95) 106.31,80.19 105.36,80.19 104.42,81.13 103.96,81.13 103.66,81.43 ; 100.4,86.81 98.24,88.97 98.24,90.62 97.6,91.25 95.32,91.25 v1(94.36,90.3)
  BOTTOM w0.508: R332.2 91.03,93.42 91,93.38 91,92.5 91.94,91.56 93.16,91.56 94.36,90.36 v1(94.36,90.3) ; C179.1 106.55,81.23 v1(106.55,79.95)
+3V3_VCCSDIO: length 11.9
  TOP w0.254: U6.U8 102.56,77.83 102.56,78.09 v1(102.55,78.1) U6.T9
  IN1 w0.508: v1(108.32,76.19) 108.32,76.49 107.89,76.93 107.89,77.74 107.1,78.53 105.32,78.53 105.27,78.48 103.01,78.48 102.63,78.1 v1(102.55,78.1)
  BOTTOM w0.508: v1(108.32,76.19) 108.57,76.19 108.78,75.99 108.78,75.33 109.54,74.56 R396.2 ; C196.1 102.71,78.26 v1(102.55,78.1)
+3V3_WLAN: length 13.2
  IN2 w0.508: v1(188.72,54.48) 188.72,58.42 189.48,59.18 189.48,61.59 190.47,62.59 190.47,64.11 v1(190.52,64.15)
  BOTTOM w0.508: Q22.2 186.83,53.85 R474.2 188.1,55.11 v1(188.72,54.48)
  vias: v1(170.05,65.15) v1(170.18,64.39) v1(170.69,64.9) v1(190.85,64.71) v2(175.5,64.89) v2(179.26,64.73) v2(182.41,64.02)
+3V_LDO: length 4.6
  TOP w0.203: v1(58.04,62.36) 57.68,62 57.68,61.65 57.19,61.16 PU3.6
  TOP w0.508: v1(58.04,62.36) 58.28,62.11 v2(58.28,61.64) PR31.2
  BOTTOM w0.508: v1(58.04,62.36) 58.17,62.23 PC97.2
+5V: length 314.6
  TOP w0.508: v1(207.14,64.9) 207,64.76 R158.1 ; v1(179.14,29.53) 178.88,29.28 C114.1 ; R101.2 201.64,78.17 v1(201.36,78.17)
  TOP w2.032: 175.45,23.31 171.36,23.31 169.24,21.18 v2(162.83,21.18) 130.09,21.18 128.91,22.37 101.11,22.37 90.62,11.88 75.5,11.88 70.68,7.05 60.65,7.05 58.99,8.7 53.91,8.7 53.71,8.5
  IN1 w1.016: 194.69,37.46 184.28,27.05 184.28,20.19 183.64,19.56 182.63,19.56
  IN1 w2.032: 43.12,9.97 42.13,10.96 42.13,13.88 43.12,14.87 43.12,17.01 39.97,20.16 39.97,21 39.33,21.63 39.33,23.82 41.6,26.08 41.6,29.28 38.04,32.83 28.13,32.83
  IN2 w1.524: v2(177.36,23.94) 177.87,24.45 177.87,28.77 178.76,29.66 179.01,29.66
  IN2 w2.032: 43.75,6.92 45.41,5.27 52.64,5.27
  IN3 w0.508: v1(17.65,94.46) 17.65,94.74 17.97,95.06 18.81,95.06 21.3,92.57 22.43,92.57 23.37,91.63 23.37,90.19 25.42,88.14 54.23,88.14 64.33,98.24 v1(64.33,100.4)
  IN3 w1.016: 207.74,76.7 207.74,65.5 v1(207.14,64.9) 204.24,64.9 203.2,63.85 203.2,63.12 ; 202.56,62.23 202.18,61.85 202.18,56.67 201.04,55.52 201.04,48.77 199.96,47.69 199.96,41.72 196.98,38.73 196.21,38.73
  BOTTOM w0.508: PR93.1 64.64,98.93 64.33,99.25 v1(64.33,100.4)
  vias: v1(17.14,94.06) v1(25.95,31.94) v1(26.58,31.94) v1(27.22,31.94) v1(27.85,31.94) v1(33.59,63.57) v1(34.21,63.5) v1(34.38,64.1) v1(42.8,8.17) v1(43.37,7.69) v1(43.91,8.83) v1(43.88,8.19) v1(52.44,6.67) v1(52.85,7.23) v1(53.46,6.87) v1(53.86,7.43) v1(176.85,23.18) v1(177.49,23.21) v1(177.82,22.67) v1(178.17,23.21) v1(179.77,29.53) v1(180.41,29.53) v1(181.74,19.94) v1(181.74,19.3) v1(195.33,38.86) v1(195.33,38.23) v1(203.33,62.74) v1(203.33,62.1) v2(13.66,97.09) v2(25.82,53.94) v2(29.25,57.67) v2(34.84,61.99)
+5V_ADO_AVDD: length 7.2
  TOP w0.203: v1(29.72,23.7) 29.8,23.7 30.24,23.26 U16.26
  BOTTOM w0.762: L17.2 27.43,27.71 27.5,27.65 v2(27.5,27.55) 28.53,26.52 28.93,26.52 29.74,25.71 C374.1
+5V_ADO_PVDD1: length 3
  TOP w0.203: v1(32.07,15.92) 32.78,16.63 32.78,16.93 33.2,17.35 33.2,17.38 33.31,17.48 U16.41
  vias: v1(32,15.11) v1(32,14.48) v2(32.55,16.96) v2(33.49,14.47)
+5V_ADO_PVDD2: length 2
  TOP w0.203: v1(36.58,17.4) 35.72,17.4 35.31,17.81 U16.46
  vias: v1(38.35,16.64) v1(38.35,16) v2(37.48,16.4) v2(37.61,15.15)
+5V_FAN:
  vias: v2(202.43,68.19)
+5V_HDMI:
  vias: v1(10.99,94.81) v1(11.62,94.81) v1(12.26,94.81) v2(7.69,95.98)
+5V_PCU: length 297.3
  TOP w0.508: v1(68.45,53.97) 67.95,54.47 PC63.2 ; v1(46.04,50.23) 46.04,49.34 46.47,48.91 v2(51.35,48.91) 53.91,48.91 54.32,49.32 57.11,49.32 57.52,48.91 58.92,48.91 60.01,50 v1(60.01,50.23) ; PC40.2 198.06,64.51 198.39,64.84 200.73,64.84 201.74,63.82 201.74,61.89 v2(202.07,61.56) 202.8,60.83 v1(203.32,60.83) ; v1(80.77,43.69) 80.77,46.48 80.52,46.74 78.87,46.74 77.42,48.18 74.5,48.18 72.9,49.79 v1(72.9,50.14)
  IN1 w0.508: v1(60.01,50.23) 61.03,50.23 61.98,49.28 62.74,49.28 63.37,48.64 63.37,48.39 64.26,47.5 67.76,47.5 68.45,48.19 v1(68.45,53.97) 70.02,53.97 72.4,51.59 72.4,50.41 72.67,50.14 v1(72.9,50.14) ; v1(203.32,60.83) 203.32,56.76 200.89,54.33 200.89,48.13 197.02,44.26 197.02,41.6 191.05,35.63 v1(190.44,35.63)
  IN2 w0.508: v1(190.44,35.63) 187.77,38.29 180.18,38.29 178.6,36.72 176.06,36.72 174.49,35.14 174.49,28.49 170.02,24.02 162.58,24.02 159.2,20.64 116.58,20.64 115.38,21.83 93.89,21.83 87,28.73 87,36.7 v1(87.38,37.08) 85.22,39.24 85.22,41.02 82.55,43.69 v1(80.77,43.69) ; 36.2,69.09 36.2,69.87 56.01,89.68 56.01,92.08 v1(57.66,93.73)
  BOTTOM w0.279: U17.5 21.41,62.56 22.1,63.25 C240.1
  BOTTOM w0.508: v1(57.66,93.73) 57.02,93.73 56.74,93.45 PC78.2 57.45,92.84 57.78,92.51 57.78,90.55 58.17,90.17 PU8.4 ; v1(87.38,37.08) 87.15,36.86 PC116.2 85.22,35.84 PU10.4 ; v1(21.34,63.27) 21.56,63.49 C240.1 ; R433.2 20.84,63.8 v1(20.31,63.27) ; v1(37.28,62.3) 36.58,61.59 36.58,57.13 v2(37.15,56.56) 38.73,54.97 38.73,53.97 42.81,49.9 45.71,49.9 v1(46.04,50.23)
  vias: v1(19.63,63.25) v1(20.19,62.65) v1(20.82,62.89) v2(38.83,73.62) v2(38.83,71.64) v4(37.02,67.38) v4(37.53,68.01) v4(37.91,67.38) v4(38.23,66.67) v4(38.23,65.91) v4(38.29,68.77) v4(38.29,68.01)
+5V_PCU_USB3_P0:
  vias: v2(14.87,66.84) v4(16.38,65.84) v4(17.12,65.79) v4(18.24,68.86) v4(18.31,65.76) v4(18.69,68.22)
+5V_S5: length 96.1
  TOP w0.191: 184.08,95.94 PU1.2
  TOP w0.406: 184.08,95.94 183.91,95.77 182.85,95.77 182.31,96.31 PC12.1
  TOP w0.508: v1(200.79,89.74) v2(200.09,89.74) 199.9,89.93 PR9.2 ; v1(177.93,38.35) 178.7,39.12 C80.1 ; PR50.1 37.59,59.01 v1(37.53,59.07) ; v1(181.68,95.95) 182.18,96.45 PC12.1 ; v1(149.76,68.48) 149.32,68.48 R142.1
  IN1 w0.508: v1(167,67.82) 165.04,67.82 157.93,74.93 152.78,74.93 149.76,71.91 v1(149.76,68.48) ; v1(173.17,77.54) 172.79,77.16 172.79,74.36 177,70.14 182.84,70.14 184.02,68.97 v1(184.02,68.71)
  IN3 w0.508: v1(200.79,89.74) 200.42,90.11 196.15,90.11 195.2,91.07 188.59,91.07 183.71,95.95 v1(181.68,95.95) 180.03,95.95 173.17,89.09 v1(173.17,77.54)
  BOTTOM w0.508: 41.25,64.9 v4(41.33,64.9)
  vias: v1(19.17,34.56) v1(19.17,33.8) v1(19.83,34.56) v1(19.83,33.8) v1(176.4,38.35) v1(176.78,37.85) v1(177.42,38.86) v1(178.36,37.87) v2(44.24,66) v2(176.09,37.73) v4(42.06,64.9) v4(42.8,64.9) v4(43.54,64.9)
+5V_S5_USB2:
  vias: v2(179.11,33.39) v2(181.47,36.67)
+5V_S5_USB3_P1:
  vias: v2(14.8,45.28) v2(16.75,42.05) v2(17.08,44.97)
+5V_TS: length 6
  TOP w0.102: v2(203.41,77.58) 203.62,77.79 R101.1
  TOP w0.508: R101.1 203.65,78.68 v1(204.41,79.44)
  BOTTOM w0.241: v1(204.41,79.44) 204.64,79.67 204.99,79.67 CN7.4
  BOTTOM w0.508: v1(204.41,79.44) 204.15,79.7 C50.1 C49.1
+15V: length 94.6
  TOP w0.254: PR53.1 32,52.96 v3(32.03,52.98) ; PR38.1 v1(38.96,60.66)
  IN1 w0.254: v1(38.96,60.66) 38.96,59.77 32.18,52.98 v3(32.03,52.98) 31.5,52.45 31.5,52 31.94,51.56 34.51,51.56 35.41,52.46 40.31,52.46 41.52,51.25 41.84,51.25 44.43,48.66 48.02,48.66 48.89,49.53 v1(49.66,49.53)
  IN3 w0.254: v1(38.96,60.66) 40.36,62.05 40.36,65.22 39.82,65.77 39.82,70.09 45.16,75.44 61.34,75.44 65.18,79.27 65.18,87.27 68.12,90.21 73.07,90.21 v1(73.32,89.96)
  BOTTOM w0.254: PR145.1 49.96,49.23 v1(49.66,49.53) ; PR118.1 73.85,89.29 74.03,89.47 PR113.1 73.66,90.3 v1(73.32,89.96)
+VCC_RTC: length 76.2
  TOP w1.016: v1(68.14,87.95) v1(69.03,87.95) 69.66,88.59 69.66,90.11 72.03,92.48 72.03,94.9 72.77,95.63 76.75,95.63 BT1.1
  IN3 w1.016: v1(69.03,87.95) v1(68.14,87.95) 66.67,86.49 66.67,76.83 67.82,75.69 67.82,68.46 69.39,66.88 69.39,59.89 69,59.5 69,55.4 69.67,54.73 69.67,53.47 69,52.8 69,44.54 69.67,43.87
  BOTTOM w1.016: 82.42,45.08 80.52,45.08 79.63,44.2 77.47,44.2 v2(76.96,43.69) 76.07,42.8 v2(73.93,42.8) 71.63,42.8
  vias: v1(69.98,42.8) v1(70.61,42.8)
+VCCIN: length 27.9
  TOP w0.254: U6.F56 v1(132.27,84.25) ; U6.P57 v1(132.59,78.74) ; v1(132.59,74.83) U6.AB57 ; 133.35,83.19 134.06,83.19 U6.F59 ; U6.M57 v1(132.59,80.04) ; U6.U57 v1(132.59,77.44) ; U6.K57 v1(132.59,81.34) ; U6.AG57 v1(132.59,72.23) ; U6.W57 v1(132.59,76.13) ; U6.E55 U6.G55
  TOP w0.508: 191.36,81.15 192.25,81.15 196.57,85.47 v1(199.77,85.47) ; R38.2 v1(140.08,90.2)
  BOTTOM w0.508: v1(199.77,85.47) 199.77,86.65 205.89,92.77 PR104.2
  vias: v1(112.03,80.81) v1(112.03,80.18) v1(112.03,79.54) v1(113.28,82.45) v1(113.28,81.83) v1(113.92,82.45) v1(113.92,81.83) v1(114.72,84.25) v1(115.41,82.8) v1(116.53,82.8) v1(117.22,84.25) v1(117.91,82.8) v1(118.05,75.69) v1(118.68,75.69) v1(119.04,82.8) v1(119.73,84.25) v1(120.21,75.69) v1(120.42,82.8) v1(120.84,75.69) v1(121.55,82.8) v1(122.24,84.25) v1(122.36,75.69) v1(122.93,82.8) v1(123,75.69) v1(124.41,82.93) v1(124.52,75.79) v1(124.75,84.25) v1(125.07,82.93) v1(125.16,75.79) v1(126.68,75.79) v1(126.95,82.95) v1(127.25,84.25) v1(127.32,75.79) v1(127.58,82.93) v1(128.84,75.79) v1(129.51,82.93) v1(129.48,75.79) v1(129.76,84.25) v1(130.25,82.83) v1(131,75.79) v1(131.64,75.79) v1(132.27,83.14) v1(132.56,73.56) v2(164.28,81.3) v2(174.82,86.93) v2(174.82,82.62) v2(177.99,81.85) v4(174.18,86.3) v4(174.18,85.03) v4(174.18,83.51) v4(174.82,85.66) v4(174.82,84.27) v4(175.45,86.3) v4(175.45,85.03) v4(175.45,83.51) v4(176.09,86.93) v4(176.09,85.66) v4(176.09,84.27) v4(176.09,82.62) v4(176.72,86.3) v4(176.72,85.03) v4(176.72,83.51) v4(177.36,86.93) v4(177.36,85.66) v4(177.36,84.27) v4(177.36,82.62) v4(177.99,86.3) v4(177.99,85.03) v4(177.99,83.51) v4(178.63,86.93) v4(178.63,85.66) v4(178.63,84.27) v4(178.63,82.62) v4(179.26,86.3) v4(179.26,85.03) v4(179.26,83.51) v4(179.83,87) v4(179.9,85.66) v4(179.9,84.27) v4(179.9,82.62) v4(180.53,86.3) v4(180.53,85.03) v4(180.53,83.51) v4(181.17,82.74) v4(181.8,83.51) v4(182.44,82.74) v4(182.95,83.51) v4(183.58,82.62) v4(184.09,83.51) v4(184.98,82.62)
+VCCIO_OUT: length 6.6
  TOP w0.076: v2(131.99,90.72) 132.07,90.8 R36.1
  TOP w0.254: U6.A59 134.09,87.16 135.04,88.11 135.04,88.86 134.24,89.66
  TOP w0.508: 134.24,89.66 133.6,89.66 132.97,90.3 R36.1
+VCCIOA_OUT: length 2.1
  TOP w0.254: v1(109.77,83.88) 109.45,84.2 U6.E20
  BOTTOM w0.508: R358.1 110.17,83.88 v1(109.77,83.88) 109.38,83.88 109.19,83.69 v1(109.19,83.66)
+VCCPDSW: length 14.2
  TOP w0.254: U6.AH10 103.84,71.28 v1(103.17,70.61)
  IN2 w0.508: v1(112.26,73.52) 111.01,73.52 110.63,73.91 109.93,73.91 108.96,72.94 105.37,72.94 103.89,71.45 103.89,71.04 103.45,70.61 v1(103.17,70.61)
  BOTTOM w0.508: 113.02,71.62 113.02,72.91 112.41,73.52 v1(112.26,73.52)
  vias: v2(103.8,71.03)
+VCCRTCEXT: length 2.1
  TOP w0.254: v1(101.88,73.32) 101.88,73.1 U6.AE7
  BOTTOM w0.254: v1(101.88,73.32) 101.88,73.46 102.23,73.81 102.94,73.81 C218.1
AGND_ADO: length 24.3
  TOP w0.203: U16.38 32.11,17.78 31.97,17.64 31.1,17.64 30.73,17.27 28.22,17.27 v1(28.19,17.25)
  TOP w0.508: v1(30.42,29.71) R230.2 v1(28.96,29.71) ; v1(21.61,22.36) R296.2 ; D10.2 v1(17.14,23.37) ; v1(16.74,22.36) D11.2 ; v1(17.35,18.47) D13.2 ; v1(18.29,18.47) 18.36,18.39 C146.2 ; v1(24.39,27.94) 24.39,28.18 R288.2 23.38,27.94 v1(23.37,27.94) ; v1(21.5,20.33) R304.2 ; C135.2 v1(18.16,23.37) ; C123.2 v1(33.66,29.08) ; v1(16.63,20.33) D12.2 ; v1(28.45,16.64) C147.2
  BOTTOM w0.254: v1(33.66,29.08) 33.78,28.96 33.78,28.22 33.52,27.95 Q23.4 ; v1(29.72,27.05) 30.11,26.66 Q23.1
  BOTTOM w0.508: v1(30.94,25.88) 30.94,25.34 31.22,25.06 C374.2 31.22,23.46 C379.2 ; R553.1 C382.2 ; C398.2 v1(28.32,15.49) ; C396.2 v1(28.45,16.64)
  vias: v1(0.96,28.01) v1(0.96,26.48) v1(1.08,14.04) v1(1.08,11.5) v1(3.11,10.86) v1(4,25.97) v1(4.38,9.85) v1(5.71,10.03) v1(6.98,9.91) v1(7.81,25.97) v1(11.5,16.45) v1(11.75,22.93) v1(11.75,20.39) v1(12.13,24.96) v1(12.13,18.1) v1(16.7,27.75) v1(17.47,27.75) v1(17.7,10.69) v1(18.41,10.72) v1(18.92,20.83) v1(19.08,22.53) v1(21.59,12.45) v1(22.86,12.45) v1(24.89,23.6) v1(27.05,22.73) v1(27.84,25.58) v1(35.81,29.34) v1(35.83,27.78) v1(37.21,29.46) v1(37.44,25.7) v1(37.57,26.97) v2(19.55,13.35) v2(25.62,15.41) v2(30.6,14.49)
AGND_CPU: length 23.4
  TOP w0.254: PU7.40 201.04,94.87 PC9.2 ; v1(197.61,98.55) 197.56,98.5 PR6.2 PR7.1 ; PC7.2 197.56,94.44 v1(197.61,94.39) ; PC2.2 v1(199.26,101.98) ; v1(199.26,101.98) 198.23,101.98 v1(198.21,102) 197.25,102 v1(197.21,101.95) ; v1(199.26,101.98) 200.13,101.98 v1(200.33,101.78) 200.41,101.7 PR2.1 ; PU7.34 198.4,95.07 PC8.2 ; PC11.2 v1(196.97,93.1) 197.5,93.62 v1(197.61,93.62) ; PR4.2 202.56,101.31 203.27,102.02 v1(203.27,102.02)
  BOTTOM w0.178: PU7.41 199.42,95.09 PU7.29
  BOTTOM w0.254: v1(197.21,101.95) 197.21,101.43 PR85.2 195.94,101.3 PR84.1 ; v1(199.26,101.98) PR87.2 ; PR94.2 205.24,98.78 v1(205.49,98.78) ; PR86.2 198.17,101.96 v1(198.21,102) ; PC72.2 v1(207.52,100.58) ; PR81.2 202.08,102.09 PC71.2 203.2,102.09 v1(203.27,102.02) ; PC74.2 v1(207.52,99.57) ; v1(199.85,102.77) 199.99,102.77 PR80.2
  vias: v1(205.36,102.74) v1(205.36,101.98)
AGND_DDR: length 13.3
  TOP w0.203: v1(197.74,60.12) 197.5,60.36 PU4.7
  TOP w0.254: PC48.2 198.64,59.31 ; v1(190.78,60.52) 191.22,60.96 PR28.1 PR39.1 ; PC46.2 PR24.2 199.4,63.01 v1(199.14,63.27) ; PC54.2 197.98,57.01 v2(198.4,57.43) 198.65,57.68 PR43.2
  IN2 w0.254: v1(190.78,60.52) 190.99,60.52 192.71,58.8 194.55,58.8
  vias: v1(197.79,59.16)
GND: length 1162
  TOP w0.076: v1(96.51,88.25) 96.51,86.74 97.97,85.28 98.36,85.28 98.54,85.1 98.54,85.04 U6.D2 ; U6.AP26 113.65,67.95
  TOP w0.102: 110.25,78.98 v1(110.25,78.98)
  TOP w0.127: U6.D5 100.63,85.2 100.63,85.85 100.68,85.9 v1(100.68,86.22) ; v1(135.82,83.75) 135.84,83.77 135.84,84.25 135.99,84.41 135.99,84.61 ; 122.52,66.53 122.57,66.48 122.57,66 122.75,65.82 122.77,65.82 122.93,65.65 U6.AV41 ; U6.AV49 127.66,65.63 127.29,65.99 127.29,66.37 127.13,66.53 ; U6.AY51 129.17,63.87 129.23,63.81 v1(129.23,63.53) ; v1(130.73,63.27) 130.55,63.45 130.55,64.48 U6.AY53 ; v1(137.66,68.23) 137.46,68.42 136.5,68.42 U6.AN63 ; 136.16,84.78 U6.D62 ; U6.AV43 124.42,65.57 124.42,65.69 124.14,65.97 124.14,66.28 123.9,66.53 ; 125.73,66.59 125.73,66.28 125.72,66.27 125.72,65.97 126.08,65.6 U6.AV46 ; U6.D59 U6.D57
  TOP w0.152: v1(116.11,62.61) 116.33,62.61 116.55,62.83 116.55,63.61 116.29,63.88 U6.AY30 ; v1(111.09,63.52) 111.15,63.58 U6.AY22 ; v1(137.4,70.91) 137.35,70.86 U6.AJ63 ; U6.AY18 108.72,63.62 v1(108.81,63.53) ; U6.AY57 132.95,63.9 133.35,63.5 v1(133.35,63.25) ; U6.AU53 130.93,66.46 130.94,66.48 131.23,66.48 131.25,66.46 U6.AU55
  TOP w0.178: U6.AU30 116.8,66.46 116.82,66.48 U6.AU33 ; U6.AU30 115.88,66.46 115.86,66.48 115.57,66.48 115.56,66.46 U6.AU28 ; U6.AU30 116.45,66.62 U6.AR31 U6.AP31 U6.AN31 ; U6.AW33 U6.AY33 117.69,64.46 117.69,63.97 v1(117.81,63.85) ; U6.AW33 117.88,65.16 U6.AV34 ; U6.AW33 117.64,65.76 U6.AV33 ; U6.AL60 134.54,70.13 134.52,70.15 134.52,70.43 134.54,70.45 U6.AJ60 134.54,71.23 134.32,71.44 134.32,71.99 ; U6.AL60 U6.AL61 135.66,69.65 v1(135.7,69.61) ; U6.AL60 134.54,69.16 134.52,69.14 134.52,68.86 134.54,68.84 U6.AN60 134.54,67.91 134.52,67.9 134.52,67.61 134.54,67.59 134.54,67.39 134.75,67.18 ; v1(133.9,72.43) 133.9,72.42 134.32,71.99 ; v1(131.7,65.3) 131.73,65.34 U6.AV55 U6.AU55 132.22,66.46 132.24,66.48 132.52,66.48 132.54,66.46 U6.AU57 133.46,66.46 133.48,66.48 133.77,66.48 133.78,66.46 U6.AU59 ; U6.AU59 U6.AV59 U6.AW59 ; U6.AU59 134.4,66.68 134.4,66.83 134.75,67.18 ; v1(126.48,68.87) 126.81,68.59 127.03,68.59 U6.AN48 127.3,68.34 127.68,68.34 U6.AN49 ; U6.AU33 117.8,66.48 v1(118.35,67.04) ; U6.AU33 117.59,66.46 U6.AV33 ; U6.AU28 114.58,66.46 114.57,66.48 114.28,66.48 114.26,66.46 U6.AU26 113.34,66.46 113.32,66.48 113.04,66.48 113.02,66.46 U6.AU24 ; U6.AU28 U6.AV28 115.07,65.34 v1(115.04,65.3) ; 134.75,67.18 U6.AT61 135.94,67.18 U6.AT62 136.01,67.11 136.44,67.11 136.58,66.97 U6.AT63 136.81,66.89 137.55,66.16 v1(137.65,66.16) ; v1(118.35,67.04) 118.62,66.77 U6.AT35 118.71,66.51 120.11,66.51 U6.AT37 120.96,66.59 121.03,66.53 121.4,66.53 121.46,66.59 U6.AT40 122.46,66.59 122.52,66.53 122.89,66.53 122.96,66.59 U6.AT42 123.42,66.59 123.49,66.53 124.85,66.53 U6.AT43 124.99,66.52 125.66,66.52 125.73,66.59 U6.AT46 126.56,66.53 127.62,66.53 127.66,66.57 U6.AT49 ; v1(118.35,67.04) 118.09,67.3 U6.AR33 ; 134.32,71.99 U6.AG60 U6.AG61 U6.AG62 U6.AG63 ; U6.AR23 111.8,67.3 112.13,66.97 ; 112.13,66.97 112.5,66.58 U6.AU24 ; 112.13,66.97 111.89,66.74 111.62,66.48 111.6,66.46 U6.AU22 110.74,66.46 110.73,66.48 110.44,66.48 110.42,66.46 U6.AU20 ; U6.AV33 117.88,65.81 U6.AV34 ; U6.AV34 118.32,65.49 v1(118.64,65.17) 118.97,64.84 U6.AW35 ; U6.AU16 107.89,66.46 107.9,66.48 108.19,66.48 108.21,66.46 U6.AU18 109.13,66.46 109.15,66.48 109.43,66.48 109.45,66.46 U6.AU20 ; U6.AU24 U6.AV24 U6.AW24 U6.AY24 112.5,63.65 v1(112.55,63.6) ; U6.AU20 U6.AV20 109.94,65.34 v1(109.9,65.3) ; U6.AU51 129.68,66.46 129.7,66.48 129.98,66.48 130,66.46 U6.AU53 ; v1(104.04,85.54) 103.72,85.22 103.44,85.22 103.26,85.39 102.99,85.39 102.82,85.22 102.53,85.22 U6.D8 ; U6.AY26 113.85,63.59 113.94,63.5 113.94,62.9 v1(113.89,62.85) ; U6.AN31 116.77,68.6 U6.AN32 117.08,68.6 v1(117.4,68.27) ; U6.AN31 U6.AM31 ; v1(115.94,69.57) U6.AM31 ; U6.AM31 U6.AL31 116.45,70.75 116.01,71.19 U6.AH30 ; U6.AP48 127.11,67.95 v1(127.43,67.62) ; U6.AV49 127.98,65.17 v1(128.07,65.17) 128.15,65.17 U6.AW50
  TOP w0.191: v1(184.83,95.7) 184.48,96.04 PU1.3
  TOP w0.203: PU3.2 55.45,58.85 55.75,58.55 v1(55.83,58.55) ; U6.F61 135.82,83.65 v1(135.82,83.75) ; U6.AY11 104.56,63.69 v1(103.61,62.74) ; v1(99.95,63.63) 100.11,63.79 U6.AY4 100.11,64.8 U6.AW4 ; U6.AN51 128.68,68.6 128.61,68.53 128.16,68.53 128.09,68.6 U6.AN49 ; U6.AP57 133.02,67.63 v1(133.11,67.63) ; U6.AP3 99.19,67.34 v1(99.19,67.23) ; U6.AV14 106.13,65.49 v1(106.43,65.19) ; U6.AG1 97.7,72.1 v1(97.59,72.21) ; U6.AU51 U6.AV51 U6.AW51 ; U6.AV8 103.09,65.49 v1(103.43,65.83) ; v1(38.58,20.07) 38.25,20.4 37.72,20.4 37.65,20.46 U16.4 ; v1(131.19,69.57) 130.86,69.9 U6.AL54 ; v1(133.14,69.6) 132.99,69.6 U6.AL57 ; U6.U61 135.51,77.46 v1(135.81,77.76) ; U6.AV39 121.45,65.49 v1(121.76,65.17) 121.85,65.17 U6.AW40 ; U6.K1 97.7,81.09 v1(97.59,81.21) ; U6.AV43 124.83,65.17 v1(124.91,65.17) 125,65.17 U6.AW44 ; U6.AK3 99.49,70.53 v1(99.19,70.23) ; U6.AL46 125.72,69.63 v1(125.53,69.63) 125.33,69.63 U6.AL45 ; U6.AW16 107.41,64.55 U6.AY16 107.37,64.42 107.3,64.35 107.3,63.77 v1(107.29,63.75) ; v1(126.48,68.87) 126.21,68.6 U6.AN46 ; v1(99.82,82.23) 100.26,82.23 100.58,82.55 100.58,82.69 U6.G5 ; U6.AM1 98.06,69.1 97.7,69.46 v1(97.41,69.46) ; U6.F58 133.99,83.69 134.05,83.75 v1(134.54,83.75) ; U6.AW59 134.51,64.84 U6.AW60 ; v1(97.6,66.25) 97.69,66.16 U6.AU1 ; U6.AW47 126.83,64.84 v1(126.49,65.17) 126.18,65.49 U6.AV46 ; U6.C39 121.55,85.64 121.92,86.01 121.92,86.29 121.87,86.34 121.87,86.62 121.94,86.7 v1(121.94,87.2) ; U6.AN45 124.86,68.6 v1(124.58,68.31) 124.29,68.6 U6.AN43 ; U6.AN7 101.85,68.74 v1(101.52,69.07) ; v1(115.26,87.36) 115.04,87.13 115.04,86.69 115.11,86.61 115.11,86.37 115.04,86.29 115.04,86.03 115.11,85.95 115.11,85.73 115.04,85.65 115.04,85.23 U6.D29 ; U6.AV41 123.25,65.17 v1(123.34,65.17) 123.42,65.17 U6.AW42 ; U6.AV16 U6.AU16 ; U6.J63 v1(137.32,81.88) ; U6.AP48 U6.AN48
  TOP w0.229: U6.J22 110.78,81.42 110.25,80.89 v1(110.25,80.6) 110.25,80.51 110.79,79.96 U6.M22
  TOP w0.254: Q5.1 18.8,92.07 v1(18.8,92.08) ; U13.N5 138.68,36.57 v6(139.01,36.25) ; v1(101.22,63.42) 101.36,63.56 101.36,63.98 U6.AY6 ; U13.T4 140.63,35.77 v6(140.96,35.45) ; v1(20.89,95.57) 20.72,95.39 Q5.4 ; U6.W22 110.89,76.54 U6.V23 ; U14.H10 154.24,40.65 154.56,40.97 v6(154.56,41.05) ; v6(134.46,37.05) 134.78,37.37 U13.G6 ; v6(153.92,39.45) 153.59,39.78 U14.G9 ; U6.AV36 120.11,65.16 v1(120.18,65.16) 120.28,65.16 U6.AW37 ; U6.D41 122.46,85.33 v1(122.27,85.33) 122.02,85.33 U6.D39 ; U6.AL54 U6.AL52 129.9,69.77 129.9,69.37 U6.AM52 129.87,69.15 129.87,68.7 U6.AN52 130.05,68.31 v1(130.23,68.31) 129.87,67.95 U6.AP52 129.96,67.76 129.96,67.49 U6.AR52 129.97,67.09 130.15,67.09 130.52,66.73 U6.AU53 ; v1(128.46,67.11) 128.13,67.11 U6.AR49 127.62,67.62 v1(127.43,67.62) ; v1(128.46,67.11) 128.46,66.93 U6.AT49 ; v1(128.46,67.11) 129.11,66.46 U6.AU51 ; U6.D47 126.24,84.54 U6.D46 U6.F46 126,83.11 v1(126.01,83.11) ; U14.R5 158.79,36.57 v6(159.11,36.25) ; U13.D12 132.83,42.79 v6(132.44,43.18) ; U14.T12 159.44,42.33 v6(159.76,42.65) ; U13.E4 133.48,35.77 v6(133.16,35.45) ; U13.T12 140.63,42.33 v6(140.96,42.65) ; U13.F4 134.13,35.77 v6(134.46,35.45) 134.78,35.77 U13.G4 ; U6.AL29 115.56,69.9 115.89,69.57 v1(115.94,69.57) ; v6(140.31,37.05) 139.98,37.37 U13.R6 ; v6(157.16,42.65) 156.84,42.33 U14.M12 ; U6.N3 99.19,79.33 v1(99.19,79.22) ; U13.T3 140.63,34.97 v6(140.96,34.65) 140.63,34.32 U13.T2 ; v1(104.83,67.45) 104.49,67.11 U6.AR11 ; v1(115.98,83.11) 115.97,83.11 U6.F30 U6.D30 ; U12.K2 117.92,34 118.2,33.72 v6(118.2,33.55) ; U6.AL10 103.84,69.93 103.43,69.52 v1(103.43,69.06) ; U6.AY59 134.27,64.02 134.85,63.45 v1(134.85,63.2) ; U13.J12 136.08,42.33 v6(135.76,42.65) ; v1(121.22,68.26) 120.9,67.95 U6.AP38 120.74,67.95 v1(120.26,68.42) 120.09,68.6 U6.AN36 119.61,68.44 119.07,68.44 U6.AN35 ; U11.H2 97.51,33.95 v6(97.51,33.67) ; v1(162.33,88.8) 162.25,88.87 CN1.6 ; U6.B36 119.73,85.98 119.75,86.06 119.75,86.33 119.73,86.38 U6.A36 119.93,86.68 v1(119.93,87.16) ; U6.D62 136.76,84.78 U6.D63 137.06,84.84 137.66,85.43 v1(137.66,85.6) ; U14.K10 155.54,40.5 U14.L9 155.91,39.57 v6(155.91,39.45) 155.91,39.33 U14.L8 ; U13.F12 133.7,42.68 v6(133.7,42.7) ; U13.C5 132.18,36.57 v6(131.86,36.25) ; U6.AE5 100.57,73.11 v1(100.57,73.31) ; U6.AE58 133.44,73.01 v1(132.89,73.01) ; U12.H10 115.97,40 U12.G9 ; U6.D59 134.59,85.37 v1(134.59,85.62) 134.59,85.88 134.81,86.1 134.81,86.12 U6.B60 ; U12.D3 114.02,34.97 v6(113.7,34.65) ; U6.R22 U6.P22 110.25,78.98 ; v1(113.46,83.06) 113.46,83.06 U6.F26 U6.D26 ; v1(109.38,69.57) 109.33,69.57 109.01,69.9 U6.AL20 ; U6.J10 103.88,81.59 v1(104.2,81.91) ; v1(137.41,75.77) 137.3,75.89 U6.Y63 ; U6.V58 v1(133.02,76.78) ; v6(115.65,34.65) 115.97,34.97 U12.G3 ; v1(113.33,86.44) 113.33,85.97 U6.B26 113.14,85.51 U6.C25 ; v1(123.5,83.11) 123.49,83.11 U6.F42 U6.D42 ; U13.T5 140.63,36.57 v6(140.96,36.25) ; v6(158.47,38.65) 158.14,38.98 U14.P8 ; U6.AB7 101.89,74.99 v1(101.89,75.24) ; v6(134.37,38.58) 134.78,39 U13.G8 ; v6(159.11,35.45) 158.79,35.77 U14.R4 ; U12.H2 116.62,34.17 v6(116.3,33.85) ; U6.N21 109.87,79.35 v1(110.25,78.98) ; U6.B40 U6.A40 122.53,86.78 122.53,86.97 122.94,87.38 122.94,88.52 122.55,88.9 v1(122.55,89.12) ; v1(137.36,79.14) 137.1,78.88 U6.P63 U6.P62 ; v1(99.18,76.22) 99.18,76.33 U6.V3 ; U14.D8 151.64,38.97 v6(151.32,38.65) ; U6.C39 121.22,85.19 U6.C38 120.75,85.19 U6.D37 ; U13.H10 135.43,40.5 U13.G9 134.78,39.78 v6(135.11,39.45) ; v1(111.3,69.57) 111.41,69.47 111.49,69.47 U6.AM23 ; v1(111.3,69.57) 111.22,69.57 U6.AL22 ; v1(111.3,69.57) 111.45,69.72 111.54,69.72 U6.AL23 ; v6(131.21,36.25) 131.53,36.57 U13.B5 ; U6.B48 127.33,85.91 127.33,86.41 U6.A48 127.51,86.74 v1(127.51,87.25) ; v1(115.94,67.62) 115.91,67.62 115.7,67.83 115.66,67.83 U6.AP29 ; v1(121.76,65.82) 121.77,65.83 U6.AT40 121.87,66.69 121.87,67.48 U6.AR39 U6.AP39 U6.AN39 ; U6.T58 v1(132.99,78.09) ; U13.R5 139.98,36.57 v6(140.31,36.25) ; v1(143.64,69.34) 143.64,69.6 144.1,70.06 144.13,70.06 144.46,70.39 144.46,70.42 144.55,70.51 U7.3 ; v1(104.43,88.52) 104.55,88.4 U6.A11 ; U6.AL36 120.09,69.9 v1(120.26,69.73) ; U11.H10 97.16,40 U11.G9 ; U6.AR5 101.07,67.44 v1(100.56,67.95) ; v6(139.66,38.65) 139.33,38.98 U13.P8 ; U6.Y59 v1(133.84,76.23) ; 135.99,84.61 136.16,84.78 ; U6.AD3 99.19,73.34 v1(99.19,73.22) ; v1(120.99,83.11) 120.99,83.11 U6.F38 U6.D38 ; U13.N6 138.68,37.37 v6(139.01,37.05) ; v1(97.65,78.07) 97.68,78.09 U6.T1 ; U6.AH24 111.71,71.13 U6.AK23 ; U12.F4 v6(115.65,35.45) U12.G4 ; v1(133.79,80.06) 133.79,80.46 U6.L58 ; U13.R4 139.98,35.77 v6(140.31,35.45) ; U13.B6 131.53,37.37 v6(131.21,37.05) ; U6.D43 124.52,85.33 v1(124.59,85.33) 124.97,85.33 U6.D45 ; U13.T6 140.63,37.37 v6(140.96,37.05) ; U6.B28 U6.A28 114.72,87.54 115.18,88 v1(115.26,88) ; U6.J59 133.99,82.07 133.99,82.25 133.52,82.71 U6.H57 133.24,82.54 v1(132.94,82.25) ; U6.AN39 122.05,68.6 U6.AN40 122.64,68.27 v1(122.71,68.27) 122.8,68.27 U6.AN42 ; U6.AN39 121.92,69.11 121.92,69.39 122.32,69.79 U6.AL40 121.99,70.22 U6.AL39 121.73,71.07 U6.AJ39 ; v1(108.85,87.37) 108.79,87.32 U6.A18 ; v1(118.35,70.15) 118.17,70.15 U6.AL33 ; U11.L9 99.11,40.5 U11.K10 ; v1(101.89,77.14) 102.12,76.91 U6.V7 ; U6.AP54 131.11,67.63 v1(131.2,67.63) ; v1(137.41,73.64) U6.AD63 ; U13.C6 132.18,37.37 v6(131.86,37.05) ; U6.AC61 135.17,74.7 v1(135.17,74.76) ; v1(128.52,95.63) 127.47,95.63 v2(127.32,95.78) 126.73,96.37 U3.3 ; U6.AP20 109.31,67.62 v1(109.38,67.62) ; U6.F20 109.71,83.2 v1(109.86,83.2) ; v6(115,42.65) U12.F12 ; U6.AL17 107.32,70.23 v1(106.95,69.86) ; U6.AD21 109.87,73.91 110.42,74.45 v1(110.42,74.52) 110.79,74.89 U6.AB22 ; v1(111.8,77.23) 111.58,77.23 U6.V23 ; v1(112.14,87.12) 112.21,87.05 U6.A24 U6.B24 ; v6(139.65,42.65) 139.33,42.33 U13.P12 ; v1(123.62,67.03) 123.82,67.03 U6.AR43 ; U6.D53 129.98,85.33 v1(129.76,85.33) 129.54,85.33 U6.D51 ; v1(118.48,83.11) 118.48,83.11 U6.F34 U6.D34 118.8,84.86 U6.D35 119.47,85.29 v1(119.53,85.29) ; v6(133.81,36.25) U13.F5 ; v1(103.17,83.21) 103.02,83.06 102.86,83.06 U6.G8 102.4,83.19 102.03,83.19 U6.G6 ; v6(136.78,33.67) 136.73,33.72 U13.K2 ; U13.K10 136.73,40.5 U13.L9 137.38,39.78 v6(137.05,39.45) 137.38,39.12 U13.L8 ; U6.V23 111.3,76.92 v1(111.67,76.55) ; U6.V23 111.2,76.95 U6.U22 ; v6(138.35,42.65) 138.03,42.33 U13.M12 ; U12.B2 112.72,34.32 v6(113.05,34.65) 113.37,34.97 U12.C3 ; v6(119.54,42.65) U12.M12 ; U6.G22 110.42,83.42 U6.D21 110.93,84.39 U6.D23 111.77,85.03 v1(112.02,85.27) 112.49,85.27 U6.D25 ; U6.D55 131.34,84.86 U6.D54 U6.F54 131.02,83.11 v1(131.02,83.11) ; U13.B2 131.53,34.32 v6(131.86,34.65) 132.18,34.97 U13.C3 ; U6.AG21 109.88,71.69 U6.AH20 109.34,71.15 108.91,71.15 U6.AH19 U6.AH17 107.68,71.12 107.31,71.12 U6.AH16 106.76,71.01 v1(106.68,71.01) ; v6(132.51,34.65) 132.83,34.97 U13.D3 ; v1(128.37,88.44) 128.85,88.44 129.76,87.54 U6.A52 U6.B52 ; v1(106.95,69.86) 107.06,69.75 107.24,69.75 U6.AM17 U6.AN17 U6.AP17 U6.AR17 107.41,67.02 107.12,66.74 v1(106.72,66.74) 106.52,66.74 106.33,66.93 U6.AR15 106.09,67.11 U6.AT13 ; v1(106.95,69.86) 106.45,70.36 106.45,70.52 U6.AJ14 105.93,70.35 105.93,70.21 U6.AL13 ; v1(128.51,83.11) 128.51,83.11 U6.F50 U6.D50 128.18,84.86 U6.D49 ; U6.AP22 111.22,67.62 v1(111.28,67.62) 111.39,67.62 U6.AP23 112.04,68.27 112.04,68.39 111.84,68.6 U6.AN23 ; v6(112.4,42.65) U12.B12 ; U13.N4 138.68,35.77 v6(139.01,35.45) ; 113.65,67.95 113.98,67.62 v1(114.03,67.62) ; U6.C27 114.26,85.51 v1(114.49,85.28) 114.07,84.86 U6.D27 ; U12.L9 117.92,40.5 U12.K10 ; U6.AA1 97.83,75.1 v1(97.66,74.93) ; U6.C20 109.55,85.76 v1(109.55,86.31) 109.9,86.31 U6.B20 ; U14.P12 158.14,42.33 v6(158.46,42.65) ; v6(137.71,37.05) 137.38,37.37 U13.L6 ; U14.B12 150.34,42.33 v6(150.02,42.65) ; v6(113.64,43.15) 114.02,42.77 U12.D12 ; v1(124.36,87.22) 124.46,87.12 124.46,86.78 U6.A44 U6.B44 ; U6.D12 104.92,84.52 U6.E11 105.03,83.76 105.03,82.77 U6.H13 ; U6.D12 U6.D14 ; U6.D12 104.92,85.24 U6.C11 104.46,85.54 v1(104.04,85.54) ; v6(133.16,36.25) U13.E5 ; v1(103.44,67.78) 103.53,67.78 U6.AP10 ; U6.D14 105.71,84.75 v1(105.97,84.49) ; U6.D14 105.71,85.21 U6.C14 106.09,85.64 106.09,86.69 U6.A14 106.22,87.22 106.17,87.27 v1(106.17,88.21) ; U6.D33 117.49,85.29 v1(117.25,85.29) 116.98,85.29 116.55,84.86 U6.D31 ; v6(133.16,37.05) 133.48,37.37 U13.E6 ; U13.J4 136.08,35.92 v6(136.41,36.25) ; v6(116.95,42.65) U12.J12 ; v6(133.81,37.05) 134.13,37.37 U13.F6 ; U11.D12 v6(94.89,42.65) ; v6(151.32,41.85) 151.64,42.18 U14.D12 ; U6.G3 99.82,82.29 v1(99.82,82.23) ; U14.K2 155.54,33.68 v6(155.65,33.57) ; v1(117.09,87.17) 117.09,86.62 U6.A32 U6.B32 ; v6(132.51,38.65) 132.83,38.97 U13.D8 ; U12.L6 U12.M6 ; v6(131.21,42.65) 131.53,42.33 U13.B12 ; U14.J12 154.89,42.33 v6(154.57,42.65) ; v6(153.49,38.2) 153.44,38.25 153.44,38.87 U14.G8 ; U14.G3 153.26,34.72 v6(153.26,34.65) ; v6(98.78,36.25) U11.J4 ; U6.A56 132.35,86.41 132.35,85.91 U6.B56 132.27,85.54 v1(132.06,85.33) 132.78,85.33 U6.C57 ; U13.G3 134.78,34.97 v6(134.46,34.65) ; U6.R10 U6.R8 ; v6(138.36,37.05) 138.03,37.37 U13.M6 ; U13.P3 139.33,34.97 v6(139.66,34.65) ; v6(138.36,35.45) 138.03,35.77 U13.M4 ; U6.E17 107.46,84.27 v1(107.82,84.63) 107.89,84.63 U6.D18 108.29,85.21 U6.C18 ; v1(133.77,78.59) 134.02,78.85 U6.P59 ; v1(135.81,80.76) 135.81,80.64 U6.L61 ; v6(99.19,33.7) 99.11,33.8 U11.K2 ; v6(115.65,38.65) U12.G8 ; U6.AA58 v1(133.02,75.48) ; U13.M5 138.03,36.57 v6(138.36,36.25)
  TOP w0.279: CN1.31 174.25,97.28 174.5,97.53 v1(174.5,97.63) ; CN1.46 166.76,97.66 v1(166.75,97.66) ; v1(165.61,91.9) 165.25,91.54 CN1.12 ; v1(172.76,97.63) CN1.34 ; v1(172.76,92.11) CN1.27 ; CN1.15 v1(166.76,88.8) ; U1.3 145.17,97.78 144.65,98.29 v1(144.65,99.86) ; CN1.24 171.25,91.76 171.07,91.95 v1(170.81,91.95) ; v1(168.25,94.23) CN1.43 ; CN1.49 v1(165.25,97.66) ; v1(169.76,91.89) CN1.21 ; v1(158.93,94.23) 159.76,95.06 CN1.60 ; v1(169.76,94.23) CN1.40 ; CN1.55 162.25,97.74 161.9,98.09 161.85,98.09 161.29,98.66 v1(161.29,99.19) ; v1(168.17,91.9) 168.25,91.82 CN1.18 ; v1(132.71,95.6) 132.71,95.89 131.85,96.75 U2.3 ; v1(174.25,91.94) CN1.30 ; v1(153.87,93.52) U4.7 ; v1(158.88,90.47) 159,90.35 CN1.1 ; v1(171.25,97.63) CN1.37
  TOP w0.305: U12.E6 114.67,37.38 v6(115,37.05) 115.32,37.37 U12.F6 ; v6(103.33,37.05) 103.01,37.37 U11.T6 ; v6(157.81,35.45) 157.49,35.77 U14.N4 ; U11.F6 96.51,37.37 v6(96.19,37.05) ; U11.C5 94.56,36.57 v6(94.24,36.25) ; U11.N6 101.06,37.37 v6(101.38,37.05) ; U11.B2 93.91,34.32 v6(94.24,34.65) 94.56,34.97 U11.C3 ; U11.G4 97.16,35.77 v6(96.84,35.45) ; U14.L6 156.19,37.37 v6(156.51,37.05) ; U12.E4 114.67,35.78 v6(115,35.45) ; v6(122.15,36.25) 121.82,36.57 U12.T5 ; v6(96.84,34.65) 97.16,34.97 U11.G3 ; v6(95.54,36.25) 95.86,36.57 U11.E5 ; U12.G6 115.97,37.37 v6(115.65,37.05) ; U14.T4 159.44,35.77 v6(159.76,35.45) 159.44,35.13 U14.T3 ; v6(102.04,38.65) 101.71,38.98 U11.P8 ; U11.B5 93.91,36.57 v6(93.59,36.25) ; v6(96.19,36.25) 96.51,36.57 U11.F5 ; U12.T2 121.82,34.33 v6(122.15,34.65) 121.82,34.97 U12.T3 ; U14.N5 157.49,36.57 v6(157.81,36.25) ; v6(96.19,42.65) 96.51,42.33 U11.F12 ; v6(95.54,37.05) 95.86,37.37 U11.E6 ; U6.AJ13 105.46,70.54 104.83,69.9 v1(104.83,69.4) ; U12.N6 119.87,37.37 v6(120.2,37.05) ; v6(117.6,36.25) 117.6,36.17 U12.J4 ; v6(100.73,37.05) 100.41,37.37 U11.M6 ; U14.G4 153.59,35.78 v6(153.26,35.45) 152.94,35.77 U14.F4 ; v6(159.11,37.05) 158.79,37.37 U14.R6 ; U12.T6 121.82,37.37 v6(122.15,37.05) ; U11.J12 98.46,42.33 v6(98.14,42.65) ; U12.N5 119.87,36.57 v6(120.2,36.25) ; U12.T12 121.82,42.33 v6(122.15,42.65) ; U11.N5 101.38,36.33 v6(101.38,36.25) ; v6(96.83,38.65) 97.16,38.97 U11.G8 ; v6(121.5,35.45) 121.17,35.77 U12.R4 ; U12.G9 115.97,39.78 v6(116.3,39.45) ; U14.T5 159.44,36.57 v6(159.76,36.25) ; U11.B6 93.91,37.37 v6(93.59,37.05) ; U14.E5 152.29,36.58 v6(151.96,36.25) ; U12.E5 114.67,36.57 v6(115,36.25) 115.32,36.57 U12.F5 ; U14.M4 156.84,35.77 v6(157.16,35.45) ; U6.G18 108.08,82.57 v1(107.86,82.57) 107.78,82.57 U6.H17 ; U11.M12 100.41,42.33 v6(100.73,42.65) ; v6(97.49,39.45) 97.16,39.78 U11.G9 ; v6(153.91,33.85) 153.91,33.92 U14.H2 ; U11.T5 103.01,36.57 v6(103.33,36.25) ; U14.F6 152.94,37.38 v6(152.61,37.05) ; U11.E4 95.86,35.77 v6(95.54,35.45) ; v6(119.55,37.05) 119.22,37.37 U12.M6 ; U12.P3 120.52,35.12 v6(120.2,35.45) 119.87,35.77 U12.N4 ; v6(102.03,42.65) 101.71,42.33 U11.P12 ; v6(94.24,37.05) 94.56,37.37 U11.C6 ; U12.B6 112.72,37.38 v6(113.05,37.05) 113.37,37.37 U12.C6 ; U11.T12 103.01,42.33 v6(103.34,42.66) ; v6(94.89,34.65) 95.21,34.97 U11.D3 ; U11.M5 100.41,36.57 v6(100.73,36.25) ; U12.M4 119.22,35.77 v6(119.55,35.45) ; v6(157.16,36.25) 156.84,36.57 U14.M5 ; U14.B2 150.34,34.33 v6(150.66,34.65) 150.99,34.98 U14.C3 ; v6(122.15,35.45) 121.82,35.77 U12.T4 ; v6(103.33,35.45) 103.01,35.77 U11.T4 ; v6(96.19,35.45) 96.51,35.77 U11.F4 ; U14.E4 152.29,35.78 v6(151.96,35.45) ; v6(152.61,36.25) 152.94,36.58 U14.F5 ; U11.R4 102.36,35.77 v6(102.68,35.45) ; v6(100.08,37.05) 99.76,37.37 U11.L6 ; v6(120.85,38.65) 120.52,38.98 U12.P8 ; U11.N4 101.06,35.77 v6(101.38,35.45) 101.71,35.12 U11.P3 ; v6(113.7,38.65) 114.02,38.97 U12.D8 ; U11.T3 103.01,34.97 v6(103.33,34.65) 103.01,34.32 U11.T2 ; U14.F12 152.94,42.33 v6(152.62,42.65) ; v6(151.31,34.65) 151.64,34.98 U14.D3 ; U14.C5 150.99,36.58 v6(150.66,36.25) 150.34,36.57 U14.B5 ; U12.P12 120.52,42.33 v6(120.84,42.65) ; U14.C6 150.99,37.38 v6(150.66,37.05) 150.34,37.37 U14.B6 ; U12.B5 112.72,36.57 v6(113.05,36.25) 113.37,36.57 U12.C5 ; U14.T6 159.44,37.38 v6(159.76,37.05) ; U6.L7 102.56,80.91 v1(102.56,80.94) ; U13.H2 135.43,34.12 v6(135.11,33.8) ; U12.L9 118.57,39.78 v6(118.24,39.45) 118.24,39.38 U12.L8 ; v6(121.5,37.05) 121.17,37.37 U12.R6 ; v6(100.73,35.45) 100.41,35.77 U11.M4 ; v6(159.76,33.85) 159.44,34.17 U14.T2 ; U12.R5 121.17,36.57 v6(121.5,36.25) ; v6(157.81,37.05) 157.49,37.37 U14.N6 ; U12.M5 119.22,36.57 v6(119.55,36.25) ; U14.G6 153.59,37.38 v6(153.26,37.05) ; U11.G6 97.16,37.37 v6(96.84,37.05) ; v6(158.48,34.63) 158.14,34.97 U14.P3 ; U11.D8 95.21,38.97 v6(94.89,38.65) ; v1(100.68,86.22) 100.66,86.25 100.19,86.25 U6.B4 ; U11.B12 93.91,42.33 v6(93.59,42.65) ; U14.J4 154.89,35.93 v6(155.21,36.25) ; v1(114.09,69.54) 114,69.54 U6.AL26 ; U11.R5 102.36,36.57 v6(102.68,36.25) ; U14.M6 156.84,37.37 v6(157.16,37.05) ; v6(151.96,37.05) 152.29,37.38 U14.E6 ; v6(102.68,37.05) 102.36,37.37 U11.R6 ; U11.L9 99.76,39.78 v6(99.43,39.45) 99.43,39.38 U11.L8
  TOP w0.381: R318.1 200.52,11.24 v1(200.27,10.99) ; U10.1 18.12,36.03 17.78,35.69 17.78,35.13 v1(17.55,34.9) ; U8.1 19.37,65.29 v1(19.12,65.54)
  TOP w0.406: U15.25 72.02,31.1 v1(71.5,31.62) ; U15.18 v1(76.57,31.88) ; U15.11 76.57,23.12 v1(76.83,22.86) ; v1(72.02,25.78) U15.4
  TOP w0.457: R103.1 v1(146.05,77.22) R104.1 ; R66.1 87.94,83.38 v1(87.67,83.38) ; R94.1 82.24,78.68 v1(82.23,78.67) ; v1(82.11,82.29) 82.56,82.74 R71.1 ; v1(20.02,71.08) 20.02,71.28 20.01,71.28 20.01,71.3 19.55,71.76 C61.2
  TOP w0.508: v1(104.8,53.92) 105.29,53.43 C72.2 ; v1(7.62,98.42) D1.2 ; C125.2 137.19,27.3 v1(136.78,26.9) ; R301.1 75.42,20.95 v1(75,20.52) ; C712.2 30.83,5.43 v1(30.6,5.2) 30.17,5.63 C160.2 ; v1(84.7,66.13) 84.73,66.17 R152.1 ; v1(198.8,30.34) 199.01,30.55 C137.2 ; v1(21.81,78.35) 21.81,78.64 R89.1 20.72,79.24 C33.2 ; v1(106.43,27.1) 106.5,27.18 C129.2 ; v1(26.03,72.01) 25.41,72.01 C59.2 25.28,71.37 v1(26.03,71.37) ; v1(127.36,37.13) 127.34,37.13 127.25,37.22 C91.2 ; D5.1 v1(22.42,88.51) ; v1(164.11,39.4) 164.05,39.34 163.55,39.34 C81.2 ; v1(107.06,95.89) 107.06,95.25 107.02,95.21 C9.2 ; v1(79.81,85.2) 80.32,85.71 R58.1 ; R28.2 138.12,92 v1(138.12,91.89) ; v1(22.86,10.67) 22.48,11.05 22.48,11.17 R316.1 21.97,11.17 v1(21.97,10.03) ; v1(5.94,8.05) 5.94,8.47 R321.1 6.86,8.37 v1(6.86,8.05) ; v1(133.99,95.6) 134.23,95.35 C11.2 ; PQ8.4 v1(209.39,58.71) ; C106.2 124.77,32.97 v1(124.77,33.04) 125.05,33.32 R222.1 ; v1(84.71,64.26) 84.84,64.26 85.09,64.01 R161.1 ; v1(31.75,55.91) PR48.2 ; v1(113.27,94.5) 113.25,94.53 112.59,94.53 112.39,94.73 C10.2 ; C132.2 C131.2 v1(199.74,23.82) ; v1(35.37,3.62) 35.38,3.61 C713.2 ; v1(67.31,55.88) PC63.1 ; C143.2 40.52,20.7 40.65,20.57 v1(41.61,20.57) ; v1(125,36.89) 125.38,37.27 C90.2 ; v1(88.42,40.23) C84.2 ; R204.1 145.64,39.27 v1(145.15,38.79) 144.66,39.28 C82.2 ; v1(82.65,39.12) 82.3,38.76 PR60.2 ; C99.2 17.51,33 v1(17.49,32.98) ; v1(206.76,61.47) 206.26,60.97 PR33.2 ; v1(102.23,57.15) 102.13,57.25 102.13,58.31 C69.1 ; C119.2 128.4,29.67 v1(127.74,29.01) ; v1(151.01,99.86) C1.1 ; C161.2 v1(12.32,5.84) ; U5.5 19.81,83.33 ; 19.81,83.33 v1(22.06,83.33) ; 19.81,83.33 U5.2 ; v1(98.04,27.1) 98.12,27.18 C127.2 ; v1(147.14,44.01) 146.43,43.31 C78.2 ; R331.1 v1(28.75,85.36) ; C52.2 24.67,73.37 v1(25.47,73.37) ; v1(89.21,30.3) C117.2 ; R33.1 121.54,92.08 v1(121.54,92.35) 120.9,91.71 120.9,91.6 R32.1 ; v1(145.48,40.66) 145.15,40.66 C79.2 ; v1(124.08,100.63) 124.08,100.29 122.97,99.18 C2.2 ; v1(61.34,26.8) 61.1,27.04 C124.2 ; C21.2 111.54,91.26 v1(111.96,91.26) ; v1(90.36,76.06) 90.36,76.51 C47.2 ; C112.2 145.54,30.68 v1(145.41,30.81) C105.2 ; v1(20.32,87.38) 20.71,86.99 C25.2 ; C65.1 v1(88.89,59.56) ; v1(39.44,28.39) 40.12,27.7 R291.1 ; v1(110.44,34.39) 109.96,33.91 108.97,33.91 R221.1 ; CN3.3 201.27,72.7 v1(201.03,72.46) ; v1(32.89,52.83) 33.15,52.58 PQ11.1 ; v1(41.87,2.43) 42.28,2.83 Q54.1 ; v1(18.61,75.38) 19.24,74.74 C57.2 ; C58.2 v1(151.5,71.51) ; C14.2 107.02,91.74 v1(107.57,91.19) 107.81,90.94 C23.2 ; R191.1 v1(99.82,52.35) ; PC12.2 v1(182.31,98.01) ; v1(49.03,34.92) C96.2 ; R201.1 v1(202.24,38.7) ; v1(162.72,37.07) C89.2 ; v1(35.18,76.01) 35.18,76.78 R138.1 ; C95.2 162.66,35.74 v1(162.33,36.07) ; v1(201.79,30.14) 202.24,30.59 C365.2 ; v1(84.7,67.02) 85.3,67.02 R149.1 ; C134.2 39.68,26.74 v1(39.51,26.74) ; v1(113.28,93.85) 113.28,93.09 112.94,92.75 C15.2 ; C55.2 C56.2 v1(33.14,73.92) ; R106.1 151.01,76.83 v1(150.46,76.83) 149.75,76.83 R105.1 ; v1(15.88,75.31) 15.88,75.06 15.47,74.65 Q9.1 ; PC40.1 197.22,65.29 197.36,65.15 v1(197.41,65.15) ; v1(36.07,31.37) 36.07,31 C108.1 36.97,30.88 v1(36.97,31.37) ; v1(71.12,57.78) 71.45,57.78 72.15,58.49 72.15,59.06 C68.2 ; v1(127,34.54) 127.01,34.54 R217.1 ; R786.2 49.95,2.61 v1(49.24,2.61) ; C104.2 v1(144.4,30.81) 144.4,30.8 C111.2 ; v1(88.14,34.34) R219.1 ; v1(78.21,63.5) 78.25,63.46 U9.4 ; v1(23.24,29.97) 23.38,29.97 R288.1 24.63,29.97 v1(24.64,29.97) ; v1(143.77,33.57) C98.2 ; v1(126.88,30.7) 126.5,30.32 C109.2 ; v1(73.71,20.47) 74.17,20.93 R300.1 ; v1(40.74,23.24) C140.2 ; v1(104.32,93.13) 103.93,92.75 C13.2 103.43,93.67 103.28,93.82 C8.2 ; PC55.1 201.51,57.21 201.49,57.21 v1(201.17,56.9) ; C70.2 101.09,55.49 v1(101.09,55.12) ; C164.2 v1(12.19,3.17) ; R206.1 108.4,39.38 108.74,39.04 v1(109.23,39.04) ; R112.1 v1(143.13,76.07) R111.2 ; v1(83.64,52.12) 83.62,52.12 Q14.1 ; R34.1 123.9,92.35 v1(122.71,92.35) ; C139.2 200.78,30.9 v1(200.12,30.24) ; PC43.1 v1(50.52,63.65) ; v1(115.06,27.1) 115.14,27.18 C128.2 ; C20.2 135.24,90.8 v1(135.51,90.53) ; v1(53.72,22.35) 53.72,23.38 C138.2 ; v1(150.18,67.88) 150.93,68.64 R782.2 ; v1(201.62,80.85) C43.2 C44.2 ; C145.2 29.96,17.9 v1(29.97,17.91) ; v1(30.99,31.37) 30.99,30.86 30.62,30.49 R230.1 29.59,30.61 v1(30.35,31.37) ; v1(141.47,69.46) 141.61,69.32 R147.1 ; R117.1 v1(150.49,74.8) R118.1 ; C17.2 115.58,92.19 v1(115.32,91.92) 115.05,92.19 C16.2 ; v1(100.58,95.25) 100.85,95.25 R23.1 ; Q55.1 v1(47.56,2.83) ; v1(30.86,34.23) C103.1 ; v1(154.33,27.3) C126.2 ; v1(39.44,26.1) 38.8,26.1 C133.1 38.62,27.17 38.82,27.37 v1(39.51,27.37) ; v1(25.91,58.17) PQ7.1 ; v4(137.49,5.59) v4(136.75,5.59) ; C73.2 89.93,51.31 89.21,52.02 89.16,52.02 89.09,52.09 v1(89.05,52.09) ; Q4.1 25.95,83.96 v1(25.95,84.27) ; v1(166.2,34.84) C97.2 ; v1(202.5,83.63) 202.88,83.26 C31.2 C32.2 ; v1(30.38,78.65) 30.38,78.59 31.31,77.66 R137.1 ; R172.1 R169.1 96.71,61.4 v1(96.7,61.42) ; R218.1 146.55,33.84 v1(146.56,33.83) 146.55,33.83 C102.2 ; v1(196.08,58.27) v1(196.08,57.53) ; Q15.1 v1(29.21,35.13) ; v1(104.8,54.56) 104.34,55.02 R187.1 ; C12.2 148.81,92.96 v1(149.07,93.22) ; v1(89.03,55.65) 90.39,55.65 R189.1 C71.2 ; C45.2 20.34,78.35 v1(20.94,78.35) ; C118.2 v1(90.42,30.73) ; C158.2 v1(12.32,7.24) ; C77.2 163.32,43.31 v1(162.69,43.94) ; v1(91.57,30.35) C115.2 ; v1(143.13,14.86) PC65.2 ; v1(87.51,52.21) 87.51,52.46 88.39,53.34 R192.1 ; v1(166.2,35.99) C94.2 ; v1(59.59,36.27) 59.66,36.2 C93.2 ; PU6.2 v1(106.43,6.86) ; C76.2 v1(18.67,45.29) ; v1(141.1,78.16) 141.3,78.36 R96.1 141.72,78.11 R100.1 ; C368.2 v1(201.64,33.64) ; C116.2 107.58,30.39 v1(107.59,30.4) ; v1(41.61,21.21) 41.33,21.21 40.84,21.7 C142.2 ; v1(33.12,49.63) PQ13.1 ; C64.2 v1(16.07,63.26) ; v1(17.73,8.48) 17.73,8.88 R320.1 18.64,8.78 v1(18.64,8.48) ; v1(59.44,33.4) C100.2 ; v1(162.69,30.45) C110.2 ; v1(30.62,55.03) PC64.1 ; Y1.4 113.28,95.15 v1(113.27,95.14) ; v1(26.97,53.21) PQ10.1 ; C66.1 92.2,60.71 v1(92.52,61.03) 92.84,60.71 C67.2 ; v1(8.64,98.42) C7.2 ; v1(34.57,56.39) PQ9.1 ; v1(189.27,67.27) 189.27,66.64 C62.2 C63.2 ; v1(88.14,33.19) R223.1 ; v1(16,85.83) 16.66,85.83 17.15,85.34 C27.2 ; PC47.1 v1(38.24,60.45) ; v1(88.31,37.89) C88.2 ; Q56.1 v1(52.82,2.99) ; v1(49.07,40.77) 49.07,40.18 49.02,40.13 C83.2 ; PQ6.1 v1(32.26,60.2) ; R186.1 103.33,53.54 v1(103.25,53.47) ; v1(103.49,91.35) 103.79,91.06 C22.2 ; v1(16.45,29.78) 16.45,29.67 R289.1 17.34,29.54 v1(17.34,29.78) ; R39.1 v1(141.48,90.17) ; C101.2 107,32.27 106.93,32.2 106.93,31.55 C107.2 106.93,30.35 v1(106.91,30.33) ; v1(149.1,14.86) PC66.1 ; v1(161.92,30.45) C113.2 ; v1(88.31,36.75) C92.2 ; C163.2 v1(12.32,4.57) ; PQ3.1 v1(27,62.2)
  IN1 w0.203: CN10.57 207.3,36.08 208.16,36.08 208.39,36.31 208.39,37.29 CN10.51 208.39,38.49 208.39,40.29 CN10.39 208.39,41.49 208.39,43.29 CN10.27 208.39,44.49 208.39,46.29 CN10.15 208.39,47.49 208.39,49.29 CN10.3 ; CN13.57 207.3,10.08 208.16,10.08 208.39,10.31 208.39,11.29 CN13.51 208.39,12.49 208.39,14.29 CN13.39 208.39,15.49 208.39,17.29 CN13.27 208.39,18.49 208.39,20.29 CN13.15 208.39,21.49 208.39,23.29 CN13.3
  IN2 w0.203: CN10.57 207.3,36.08 208.16,36.08 208.39,36.31 208.39,37.29 CN10.51 208.39,38.49 208.39,40.29 CN10.39 208.39,41.49 208.39,43.29 CN10.27 208.39,44.49 208.39,46.29 CN10.15 208.39,47.49 208.39,49.29 CN10.3 207.49,49.89 CN10.1 ; CN13.3 208.39,23.29 208.39,21.49 CN13.15 208.39,20.29 208.39,18.49 CN13.27 208.39,17.29 208.39,15.49 CN13.39 208.39,14.29 208.39,12.49 CN13.51 208.39,11.29 208.39,10.31 208.16,10.08 207.3,10.08 CN13.57
  IN3 w0.203: CN10.57 207.3,36.08 208.16,36.08 208.39,36.31 208.39,37.29 CN10.51 208.39,38.49 208.39,40.29 CN10.39 208.39,41.49 208.39,43.29 CN10.27 208.39,44.49 208.39,46.29 CN10.15 208.39,47.49 208.39,49.29 CN10.3 ; CN13.57 207.3,10.08 208.16,10.08 208.39,10.31 208.39,11.29 CN13.51 208.39,12.49 208.39,14.29 CN13.39 208.39,15.49 208.39,17.29 CN13.27 208.39,18.49 208.39,20.29 CN13.15 208.39,21.49 208.39,23.29 CN13.3
  BOTTOM w0.152: v1(89.03,55.65) 89.24,55.44 U18.3
  BOTTOM w0.203: v1(64.19,37.62) 64.14,37.57 U23.1 ; U23.49 54.79,22.66 54.48,22.35 v1(54.36,22.35) ; U23.27 63.64,27.17 v1(64.14,26.67) ; U23.113 55.19,40.26 v1(55.01,40.43) ; v1(58.23,37.53) 58.61,37.53 58.79,37.71 U23.122 ; U23.91 45.46,35.57 v1(44.96,36.07)
  BOTTOM w0.241: CN7.11 205.46,76.07 206.01,75.99 206.44,75.99 v1(206.82,75.61) ; v1(207.08,77.89) 206.74,77.55 206.32,77.55 206.3,77.54 206.22,77.48 205.67,77.55 CN7.8 ; CN7.20 204.84,71.61 205.06,71.58 205.38,71.54 205.46,71.6 205.48,71.61 v1(206.23,71.61) ; CN7.17 205.05,73.1 205.11,73.09 205.59,73.02 205.67,73.08 205.69,73.1 v1(206.52,73.1) ; CN7.14 205.26,74.58 205.8,74.51 205.88,74.57 205.9,74.58 v1(206.47,74.58)
  BOTTOM w0.254: v1(153.52,10.57) 153.54,10.59 PQ37.1 ; CN14.8 86.57,14.75 v1(87.34,13.99) ; CN8.16 v1(33.23,76.01) ; v1(37.59,77.94) 37.74,77.8 CN8.25 ; v1(39.23,76.01) CN8.28 ; v1(29.08,78.68) 29.23,78.53 CN8.8 ; CN8.9 v1(29.74,78.68) ; v1(35.18,76.01) 35.09,76.01 34.74,76.37 CN8.19 ; CN8.12 31.23,77.8 v1(30.38,78.65) 30.38,77.94 30.74,77.59 CN8.11 ; CN8.22 v1(36.23,76.01)
  BOTTOM w0.279: PU11.14 146.95,6.97 v1(146.56,6.58) ; v1(18.61,51.58) U21.3
  BOTTOM w0.305: CN11.14 v1(32.04,41.85) ; U20.3 89.25,52.29 v1(89.05,52.09) ; CN9.69 189.68,59.43 189.6,59.5 189.6,59.97 v1(190.14,60.52) ; v1(49.7,10.38) 50.45,9.63 CN18.8 ; CN9.39 182.17,57.33 v1(181.48,56.64) ; CN9.51 v1(185.17,59.78) 184.11,59.78 183.68,59.34 CN9.45 ; CN9.33 180.68,57.1 v1(180.21,56.64) ; CN11.12 v1(33.04,41.85) ; CN11.8 v1(35.04,41.85) ; CN12.21 v1(183.35,22.85) ; v1(176.06,67.55) 176.59,67.02 176.68,67.02 176.92,66.78 CN9.18 ; CN9.63 188.17,58.45 188.17,59.35 187.75,59.78 v1(186.69,59.78) 186.68,59.77 CN9.57 ; v1(183.33,25.59) 183.07,25.85 CN12.15 ; CN9.75 191.17,59.32 v1(190.87,59.75) ; CN12.24 v1(183.33,21.35) ; CN11.10 v1(34.04,41.85) ; CN12.18 v1(183.4,24.35) ; CN9.7 174.17,59.41 v1(173.8,59.78) 173.02,59.78 172.68,59.44 CN9.1
  BOTTOM w0.381: v6(115,42.65) 114.88,42.54 C289.2 ; C180.2 C192.2 105.96,79.88 105.96,79.66 v1(106.06,79.56) ; v1(102.34,60.1) 102.61,59.83 C249.2 ; U22.1 177.17,40.17 176.75,39.75 v1(176.75,39.53)
  BOTTOM w0.457: C296.2 C283.2 118.59,43.48 119,43.48 119.54,42.94 v6(119.54,42.65) ; R364.1 82.73,81.98 82.42,81.98 v1(82.11,82.29) 82.56,82.74 R71.1 ; C282.2 116.37,43.23 v6(116.95,42.65) ; C361.2 v1(67.18,32.89) ; v6(135.76,42.65) 135.23,43.18 C271.2 ; v1(138.05,43.23) 137.39,43.23 C287.2 C297.2 ; v1(14.99,62.74) 14.6,63.13 D20.2
  BOTTOM w0.508: v1(83.25,35.75) 83.25,35.75 82.45,36.55 PC117.1 ; C307.2 137.05,39.87 v6(137.05,39.45) ; C305.2 99.7,40.04 99.43,39.77 v6(99.43,39.45) ; R421.2 75.69,69.09 76.2,69.6 v1(77.6,69.6) 76.45,70.75 C233.2 ; v6(103.34,42.66) 103.61,42.92 C273.2 ; PC104.1 162.56,55.17 v1(162.69,55.04) ; v6(113.05,36.25) 112.73,35.93 C336.2 ; C240.2 22.81,64.27 ; v1(206.74,98.28) 206.84,98.28 207.04,98.08 PR96.1 ; C244.2 121.46,61.11 v1(121.86,61.11) ; C277.2 131.05,42.8 v6(131.21,42.65) ; v1(14.93,64.84) 15.49,65.41 C239.2 ; C332.2 153.28,37.06 v6(153.26,37.05) ; PC115.1 81.28,38.61 82.42,39.75 v1(82.65,39.75) ; v6(140.96,42.65) 141.1,42.8 C284.2 ; v1(203.88,53.66) 204.33,53.2 204.33,53.08 C263.2 ; C359.2 115.43,32.63 115.7,32.89 v1(115.7,33.22) ; v1(147.7,51.82) C262.2 ; v1(50.29,58.29) 50.62,57.96 PC102.1 ; v1(19.18,55.49) C259.2 ; C207.2 112.59,77.46 v1(113.15,76.9) ; PC132.2 141.02,6.22 v1(140.77,6.48) ; v1(10.07,84.95) 10.68,84.95 11.06,85.33 C177.2 ; C376.2 75.95,25.53 v1(75.89,25.59) ; v6(157.81,35.45) 157.81,35.23 157.38,34.8 156.71,34.8 C344.2 ; C353.2 117.63,33.6 118.15,33.6 v6(118.2,33.55) ; v6(93.59,36.25) 93.59,35.97 93.46,35.84 C341.2 ; v6(150.66,34.65) 150.39,34.65 149.98,35.06 C343.2 ; v1(59.94,43.15) 60.45,42.65 C293.1 ; v1(162.05,69.09) 162.05,69.06 PC92.1 ; PC94.2 55.42,60.07 55.5,59.99 PR142.2 56.08,59.36 v1(56.52,58.93) ; PC122.1 v1(99.31,15.11) ; v1(107.06,95.89) 107.57,95.38 R338.2 ; v1(70.36,82.03) 70.36,82.17 69.86,82.67 PR128.2 ; C346.2 87.59,35.6 v1(87.63,35.56) ; v1(105.92,39.79) 105.59,40.12 C303.2 ; v6(153.91,33.85) 154.06,33.7 C358.2 ; v1(63.5,38.73) 63.75,38.98 C312.2 ; v1(78.11,57.4) 77.6,56.9 C254.2 ; v1(75.06,60.87) 74.42,61.51 R441.1 ; v1(197.74,61.85) 197.46,61.85 197.31,61.7 PC96.1 ; v1(70.99,85.22) PQ23.1 ; v1(70.93,89.35) 71.06,89.22 PC84.1 ; C153.2 v1(56.2,10.48) ; v1(134.92,59.23) 135.41,59.23 136.35,60.17 R438.2 ; v6(101.38,37.05) 101.38,37.77 C320.2 ; PC114.2 82.45,38.91 v1(82.65,39.12) ; R484.2 v1(87.51,52.21) ; CN19.5 v1(19.7,8.5) ; PQ32.1 v1(158.88,64.26) ; v6(103.33,37.05) 103.33,37.3 103.5,37.46 C321.2 ; C378.2 69.82,24.77 v1(69.34,24.77) ; v1(72.77,91.05) 72.66,91.16 PQ20.1 ; PC75.2 206.76,96.02 206.44,95.69 ; C322.2 121.5,37.3 v6(121.5,37.05) ; PC100.1 193.81,58.93 v1(193.36,59.38) ; v1(165.23,42.67) 164.59,42.03 R520.1 ; v6(100.73,37.05) 100.73,37.31 100.33,37.72 C324.2 ; v6(103.33,34.65) 103.33,34.29 103.02,33.98 C356.2 ; R439.2 R440.2 138.38,61.38 138.63,61.13 v1(138.63,61.06) ; D18.2 13.9,68.91 v1(13.87,68.91) ; PC93.2 48.06,64.39 v1(49.28,64.39) ; PC128.1 151.77,11.55 151,12.32 v1(150.62,12.32) ; C355.2 143.55,33.78 v1(143.77,33.57) ; C325.2 115.65,37.24 v6(115.65,37.05) ; PC78.1 54.79,93.32 v1(54.79,93.73) ; C354.2 139.58,34.58 v6(139.66,34.65) ; C714.2 197.43,80.32 v1(197.68,80.08) ; v1(95.98,60.62) 95.9,60.54 C247.2 96.01,59.83 96.01,59.04 C250.2 ; v6(116.3,39.45) 116.58,39.17 C313.2 ; C228.2 109.46,72.95 C222.2 v1(108.7,73.57) ; v1(111.02,53.9) 111.45,54.32 C261.2 R477.1 ; R443.1 76.96,61.47 77.22,61.21 v1(77.22,60.83) ; v1(52.14,12.13) 52.01,12 C159.2 ; C219.2 C229.2 201.6,75.56 v1(201.42,75.74) ; v1(41.37,78.13) 41.37,77.67 41.14,77.43 CN8.32 ; v1(87.35,38.33) PC116.1 ; v1(15.77,68.94) 15.49,68.66 C234.2 ; C290.2 160.28,43.32 159.76,42.8 v6(159.76,42.65) ; D21.2 14.82,59.82 v1(14.86,59.82) ; v6(156.51,37.05) 156.47,37.09 C333.2 ; v1(177.8,30.35) 177.95,30.51 C363.2 ; C302.2 97.41,39.88 97.49,39.8 v6(97.49,39.45) ; v1(109.23,39.04) 109.82,39.62 C311.2 ; R480.1 146.56,52.7 v1(147.07,52.2) ; R508.1 v1(51.59,43.15) ; R515.2 62.54,41.53 v1(62.54,40.97) ; v1(119.98,61.23) 119.37,61.23 C246.2 ; PC86.1 54.58,87.38 v1(54.3,87.09) ; PQ33.1 157.73,58.22 v1(157.73,57.91) ; C326.2 114.65,37.4 v6(115,37.05) ; v6(131.21,36.25) 131.21,35.88 131.06,35.73 C342.2 ; v1(73.41,91.05) 73.79,91.44 PC80.1 ; R535.1 68.33,27.04 v1(68.33,26.67) ; v1(79.81,85.2) 79.66,85.34 PQ24.1 ; PQ21.1 77.34,90.68 v1(77.03,90.36) 76.9,90.24 PQ22.1 ; v1(103.49,91.35) 103.64,91.5 C175.2 ; v6(158.46,42.65) 158.36,42.76 C285.2 ; C79.2 145.15,40.66 v1(145.48,40.66) ; C345.2 113.71,34.66 v6(113.7,34.65) ; v1(16,85.83) 15.14,86.69 R349.1 ; R471.1 144.72,55.92 v1(144.58,55.78) ; PC121.2 v1(98.55,16.38) ; v6(135.11,33.8) 135.16,33.85 135.71,33.85 C351.2 ; D29.2 15.01,46.08 v1(14.86,46.23) ; v6(112.4,42.65) 111.66,43.39 C272.2 ; v1(86.87,71.12) 86.11,71.12 85.72,70.73 R413.1 ; v6(140.31,37.05) 140.36,37.11 C323.2 ; D30.2 15.01,42.19 v1(14.86,42.04) ; C309.2 155.94,39.47 v6(155.91,39.45) ; C339.2 155.3,36.16 v6(155.21,36.25) ; C357.2 158.12,34.28 v6(158.48,34.63) ; C350.2 134.3,34.81 v6(134.46,34.65) ; 17.38,70.5 v1(18.91,70.5) ; C390.2 36.44,19.56 v1(35.81,19.56) ; v1(19.18,58.44) 19.93,58.44 C251.2 ; C319.2 96.19,37.52 v6(96.19,37.05) ; v1(14.16,64.84) 14.16,65.21 D19.2 ; 206.44,95.69 206.76,95.37 PC76.2 ; 206.44,95.69 v1(206.31,95.69) ; C150.2 v1(56.2,11.5) ; D34.2 14.11,38.62 v1(13.84,38.35) ; v1(17.65,42.17) D33.2 ; v6(139.66,38.65) 139.63,38.62 C315.2 ; C364.2 180.2,30.85 v1(180.54,30.51) ; v1(111.8,77.23) 111.51,77.52 C205.2 ; Q24.1 69.47,27.43 v1(69.98,26.92) ; C280.2 96.14,42.7 v6(96.19,42.65) ; v1(109.86,83.2) 109.84,83.19 109.6,83.19 109.23,82.81 C178.2 ; C301.2 91.62,40.03 v1(91.06,40.59) ; PR168.1 152.38,6.48 v1(152.53,6.48) ; v1(162.69,43.94) 163.32,43.31 C77.2 ; v1(201.36,78.92) C49.2 C50.2 ; v6(120.84,42.65) 120.84,43.68 121.31,44.15 C270.2 ; v1(84.2,74.17) 84.2,74.8 R395.2 ; C294.2 123.17,43.23 C278.2 122.51,43.02 v6(122.15,42.65) ; C279.2 93.47,42.77 v6(93.59,42.65) ; v1(113.27,75.58) 113.1,75.41 C213.2 113.68,74.49 113.99,74.79 v1(113.99,75.25) ; PR148.2 66.42,46.6 v1(66.42,46.08) ; v1(25.45,78.27) 24.83,77.65 CN8.31 ; C257.2 105.66,55.69 105.66,54.41 105.18,53.92 v1(104.8,53.92) ; PR124.2 54.86,86.11 54.3,85.54 v1(54.3,85.14) ; v1(68.17,91.19) PC83.2 ; v1(112.41,72.61) C221.2 ; v1(84.07,60.58) 84.07,60.95 C242.2 v1(84.71,60.58) ; C335.2 143.64,37.65 144.77,38.79 v1(145.15,38.79) ; C166.2 103.86,94.01 104.32,93.55 v1(104.32,93.13) ; v6(118.24,39.45) 118.24,39.82 117.96,40.11 C306.2 ; v1(17.65,39.36) D31.2 ; PC135.1 v1(143.64,2.92) ; v6(99.19,33.7) 98.95,33.95 C349.2 ; PU9.4 v1(166.5,66.42) ; C330.2 137.67,37.08 v6(137.71,37.05) ; C327.2 120.2,37.42 v6(120.2,37.05) ; v1(166.5,58.17) PU9.5 ; v6(150.02,42.65) 149.5,43.16 C276.2 ; v1(68.27,86.61) PR123.2 ; C366.2 72.64,27.69 v1(72.9,27.43) ; v1(72.9,94.54) 72.9,94.49 72.52,94.11 PQ19.1 ; U19.4 71.25,49.89 v1(71.73,50.37) ; C360.2 97.49,33.07 97.49,33.48 97.51,33.5 v6(97.51,33.67) ; v1(52.9,12.13) 53.03,12 C162.2 ; R507.1 v1(50.44,43.13) ; PC127.1 v1(141.35,11.94) ; PC133.1 151.8,4.61 v1(151.38,4.19) ; v1(99.95,63.63) 99.19,63.63 98.67,63.11 R436.1 R444.1 ; v6(135.11,39.45) 135.11,39.76 134.99,39.88 C308.2 ; v1(68.83,91.82) 68.83,91.44 69.59,90.69 PR114.2 ; v1(15.88,46.23) 16.03,46.08 C268.2 ; C264.2 v1(84.46,47.22) ; C286.2 16.03,42.06 v1(15.88,41.91) ; v1(95.35,55.27) 95.45,55.37 95.45,55.43 96,55.98 C255.2 ; C362.2 70.48,31.5 v1(70.87,31.88) ; v6(100.73,42.65) 100.73,42.83 100.34,43.23 C281.2 C295.2 ; C348.2 100.71,35.43 v6(100.73,35.45) ; v6(134.46,37.05) 134.46,37.54 C329.2 ; C196.2 104.56,78.87 v1(104.56,79.1) 104.12,79.1 C194.2 ; v1(74.36,87.82) 73.85,87.32 PR121.2 ; v6(159.11,37.05) 159.14,37.07 C334.2 ; CN15.4 v1(28.9,9.93) ; CN15.10 v1(22.75,8.62) ; C380.2 74.02,23.91 C375.2 73.41,24.9 73.66,25.15 v1(73.66,25.4) ; J2.2 103.5,53.72 v1(103.25,53.47) ; C241.2 169.29,61.34 168.53,60.58 v1(168.53,60.33) ; PU9.6 v1(165.23,58.17) ; v1(158.88,65.7) PQ29.1 ; C331.2 150.61,37.1 v6(150.66,37.05) ; v1(34.04,19.56) 34.04,18.67 33.54,18.17 C393.2 C394.2 ; C352.2 147.02,34.29 v1(146.56,33.83) ; v1(165.23,37.08) 164.85,37.08 164.59,37.34 C316.2 ; C258.2 108.15,55.79 v1(108.15,54.29) ; PR106.2 74.8,92.84 74.3,93.34 v1(74.3,94.54) ; CN17.4 v1(39.36,7.71) ; v6(93.59,37.05) 93.62,37.09 C318.2 ; v1(75.76,89.73) 75.13,89.1 PC85.1 ; v1(73.02,101.22) 73.02,98.3 72.64,97.92 PQ17.1 ; v1(20.7,60.17) 20.7,60.48 20.42,60.76 U17.9 ; v1(21.34,38.73) 21.09,38.49 C317.2 ; v1(158.37,10.95) PC126.2 ; C328.2 131.81,37.09 v6(131.86,37.05) ; v1(13,86) 12.79,86 12.58,85.79 D17.2 ; R543.2 v1(44.7,24.26) ; D22.2 v1(14.86,58.99) ; PU10.8 81.41,27.43 81.53,27.3 v1(81.61,27.3) ; v6(152.62,42.65) 152.62,43.12 152.43,43.31 C274.2 ; CN19.6 v1(10.25,5.93) ; C367.2 76.21,29.96 76.58,29.59 v1(76.58,28.96) ; C340.2 98.95,35.85 98.78,36.01 v6(98.78,36.25) ; D16.2 C176.2 16.52,90.44 v1(18.16,92.08) ; L18.2 v1(43.81,29.99) ; PC111.1 v1(55.12,48.13) ; v1(37.34,53.59) 36.87,54.06 SW2.3 ; R467.1 110.16,57.13 109.8,57.49 109.8,58.14 110.29,58.62 v1(110.49,58.62) ; PQ18.1 75.82,96.39 75.51,96.09 v1(75.51,94.54) ; C232.2 125.22,72.18 v1(125.16,72.24) ; C243.2 v1(87.37,62.09) ; R514.2 v1(59.21,43.15) ; PC112.1 v1(58.93,48.13) ; PC113.1 v1(49.68,48.13) ; C288.2 C298.2 156.49,41.83 v6(156.51,41.85) ; PC134.1 v1(143.64,3.94) ; v1(103.61,62.74) 103.68,62.81 R437.1 C245.2 ; v1(165.23,37.76) R523.1 ; CN16.26 v1(60.03,10.79) ; C404.2 v1(47.2,12.06) ; R335.1 C173.2 96.65,94.87 v1(96.77,95) ; v6(119.55,36.25) 119.5,36.2 C338.2 ; R442.1 v1(75.69,60.83) ; R531.2 v1(43.81,32.06)
  vias: v1(0.78,76.57) v1(0.78,71.92) v1(0.96,70.42) v1(0.96,52.26) v1(0.96,49.72) v1(0.96,47.18) v1(0.96,31.56) v1(0.96,29.78) v1(1.46,54.8) v1(1.97,6.92) v1(2.73,49.09) v1(2.86,52.9) v1(4.08,95.57) v1(4.26,7.94) v1(4.89,53.28) v1(5.27,54.8) v1(5.27,51.5) v1(5.4,47.31) v1(5.53,49.34) v1(6.04,100.4) v1(6.04,97.86) v1(6.2,78.17) v1(6.28,95.16) v1(6.28,93.08) v1(6.28,81.6) v1(6.28,80.23) v1(6.84,70.4) v1(7.43,6.92) v1(7.69,70.42) v1(7.69,54.8) v1(7.81,77.66) v1(7.84,0.93) v1(7.94,47.31) v1(8.19,100.9) v1(8.22,71.97) v1(8.58,52.64) v1(8.83,3.88) v1(8.96,76.01) v1(9.52,74.55) v1(9.52,73.53) v1(9.52,72.64) v1(9.72,49.85) v1(9.85,7.56) v1(9.91,99.19) v1(9.97,0.96) v1(10.29,74.55) v1(10.29,73.53) v1(10.29,72.64) v1(10.61,52.14) v1(10.73,100.9) v1(11.05,74.55) v1(11.05,73.53) v1(11.05,72.64) v1(10.99,57.6) v1(10.99,34.61) v1(11.43,30.23) v1(11.5,69.03) v1(11.5,56.2) v1(11.5,45.91) v1(11.5,32.96) v1(11.88,49.85) v1(12.06,99.06) v1(12.06,98.3) v1(12.39,71.19) v1(12.51,0.96) v1(12.64,100.9) v1(12.78,98.3) v1(12.88,99.43) v1(13.03,80.01) v1(13.08,81.53) v1(13.08,77.52) v1(13.41,98.3) v1(13.39,52.32) v1(13.39,51.31) v1(13.39,50.42) v1(14.15,52.32) v1(14.15,51.31) v1(14.15,50.42) v1(14.16,35.05) v1(14.16,34.36) v1(14.54,54.55) v1(14.8,35.05) v1(14.8,34.36) v1(14.91,52.32) v1(14.91,51.31) v1(14.91,50.42) v1(14.99,60.71) v1(15.05,0.96) v1(15.18,32.96) v1(15.42,80.52) v1(15.65,81.15) v1(15.69,73.65) v1(15.85,72.06) v1(16.31,77.19) v1(16.48,72.03) v1(16.83,54.8) v1(16.83,50.87) v1(16.83,47.69) v1(17.17,72.03) v1(17.59,0.96) v1(17.81,72.01) v1(18.36,48.34) v1(18.74,46.55) v1(18.92,30.5) v1(19.42,32.93) v1(19.8,97.4) v1(19.96,60.17) v1(20.13,0.96) v1(20.88,65.58) v1(21.53,46.29) v1(21.5,41.72) v1(21.49,39.8) v1(21.46,30.5) v1(21.83,98.14) v1(21.92,55.55) v1(21.91,32.2) v1(21.97,45.21) v1(21.96,38.01) v1(22.1,43.18) v1(22.2,60.55) v1(22.23,36.25) v1(22.67,0.96) v1(22.87,65.68) v1(22.86,63.02) v1(22.99,37.21) v1(23.59,97.65) v1(23.75,63.88) v1(23.75,56.49) v1(23.75,54.66) v1(23.75,52.83) v1(23.75,45.47) v1(23.75,43.69) v1(23.69,42.08) v1(23.75,34.42) v1(23.75,31.88) v1(24.07,93.92) v1(24.2,9.08) v1(24.61,95.9) v1(25.21,0.96) v1(25.27,60.33) v1(25.92,103.61) v1(25.98,100.3) v1(25.97,97.22) v1(25.97,94.68) v1(25.97,92.14) v1(26.61,90.49) v1(27.75,0.96) v1(29.15,90.49) v1(29.77,10.52) v1(30.29,0.96) v1(30.4,10.64) v1(31.69,90.49) v1(31.75,82.69) v1(32,23.37) v1(32.13,70.23) v1(32.38,21.59) v1(32.41,19.56) v1(32.64,68.1) v1(32.83,0.96) v1(33.4,71.04) v1(33.72,82.65) v1(33.75,70.27) v1(33.78,23.37) v1(33.91,21.46) v1(34.1,34.61) v1(34.23,90.49) v1(35.37,0.96) v1(35.81,23.37) v1(35.81,21.34) v1(36.07,84.72) v1(36.07,82.77) v1(36.13,71.19) v1(36.46,77.98) v1(36.52,41.72) v1(36.77,90.49) v1(37.62,83.68) v1(37.91,0.96) v1(38.69,84.39) v1(39.31,90.49) v1(39.25,77.98) v1(39.28,10.94) v1(39.44,34.74) v1(39.94,37.02) v1(39.99,11.19) v1(40.33,41.72) v1(40.36,84.42) v1(40.45,0.96) v1(40.66,11.19) v1(41.85,90.49) v1(41.94,41.57) v1(42.99,0.96) v1(43.69,50.72) v1(43.91,4.71) v1(44.12,85.51) v1(44.15,84.22) v1(44.32,50.72) v1(44.35,12.34) v1(44.39,90.49) v1(44.57,23.38) v1(44.57,21.45) v1(44.67,19.57) v1(44.96,50.72) v1(45.53,0.96) v1(45.59,50.72) v1(46.93,90.49) v1(48.07,0.96) v1(49.34,20.77) v1(49.44,16.53) v1(49.47,90.49) v1(50.61,0.96) v1(51.83,13.99) v1(52.01,90.49) v1(52.26,30.29) v1(52.39,85.14) v1(53.15,0.96) v1(53.28,91.38) v1(53.41,93.54) v1(53.91,95.57) v1(54.17,16.96) v1(54.27,14.8) v1(54.61,92.08) v1(54.61,91.44) v1(54.68,97.48) v1(54.8,37.4) v1(54.93,36.26) v1(55.57,99.13) v1(55.69,0.96) v1(55.79,29.78) v1(56.84,100.78) v1(56.84,32.2) v1(56.96,6.79) v1(57.47,27.12) v1(58.23,0.96) v1(58.36,102.3) v1(58.36,12.64) v1(58.36,12) v1(58.36,5.53) v1(58.36,2.99) v1(58.99,100.4) v1(58.99,95.06) v1(60.14,103.57) v1(60.9,2.99) v1(60.96,89.53) v1(60.96,87) v1(61.85,88.44) v1(61.92,104.46) v1(61.92,5.02) v1(62.42,102.05) v1(63.12,89.53) v1(63.12,86.87) v1(63.44,2.99) v1(64.07,105.22) v1(65.47,103.7) v1(65.47,4.77) v1(65.6,100.14) v1(65.66,46.08) v1(65.98,2.99) v1(66.36,105.6) v1(67.06,46.08) v1(67.13,25.07) v1(67.41,59.31) v1(67.5,34.1) v1(67.88,101.92) v1(68.14,81.68) v1(68.52,2.99) v1(68.9,105.6) v1(68.9,86.64) v1(69,68.52) v1(69.92,69.15) v1(70.04,4.77) v1(70.42,100.14) v1(70.55,103.95) v1(70.93,70.93) v1(71.06,2.99) v1(71.31,37.66) v1(71.44,105.6) v1(72.58,102.3) v1(73.6,33.59) v1(73.6,2.99) v1(73.98,105.6) v1(74.87,4.64) v1(75.63,104.08) v1(76.14,2.99) v1(76.52,105.6) v1(76.65,1.08) v1(76.77,100.4) v1(77.41,5.91) v1(77.79,102.3) v1(78.17,105.6) v1(78.43,8.19) v1(79.19,1.08) v1(80.33,1.08) v1(82.04,32.64) v1(82.04,30.61) v1(82.11,8.19) v1(82.8,25.27) v1(83.31,31.62) v1(83.44,23.62) v1(83.69,22.99) v1(83.94,15.36) v1(84.33,23.62) v1(84.58,32.64) v1(84.58,30.61) v1(84.58,22.99) v1(85.03,21.91) v1(86.1,47.42) v1(86.1,40.09) v1(86.25,105.6) v1(88.2,105.6) v1(88.33,1.03) v1(88.81,13.93) v1(90.13,14.09) v1(90.24,1.08) v1(90.3,57.28) v1(90.55,49.02) v1(90.74,105.6) v1(91.63,5.53) v1(92.4,25.39) v1(92.78,1.08) v1(93.03,8.83) v1(93.28,105.6) v1(93.28,3.75) v1(95.32,1.08) v1(95.7,5.65) v1(95.82,105.6) v1(96.21,25.39) v1(96.59,8.83) v1(97.48,3.88) v1(97.86,1.08) v1(98.36,105.6) v1(98.93,5.84) v1(99.13,11.5) v1(100.4,1.08) v1(100.58,95.89) v1(100.9,105.6) v1(101.22,95.89) v1(101.29,9.08) v1(101.85,99.57) v1(102.41,90.4) v1(102.43,4.38) v1(102.49,99.57) v1(102.94,1.08) v1(103.12,99.57) v1(103.44,105.6) v1(103.83,25.39) v1(104.49,74.28) v1(104.52,11.43) v1(104.61,76.39) v1(104.71,77.03) v1(104.84,9.97) v1(104.97,6.42) v1(105.31,59.11) v1(105.48,1.08) v1(105.56,60.34) v1(105.98,105.6) v1(106.69,61.11) v1(106.68,58.55) v1(106.75,4.26) v1(107.83,60.25) v1(108.02,1.08) v1(108.52,105.6) v1(108.52,11.24) v1(108.79,79.76) v1(108.88,89.68) v1(108.91,25.39) v1(108.99,61.24) v1(110.43,11.22) v1(110.59,61.14) v1(110.55,59.88) v1(110.56,1.08) v1(111.06,105.6) v1(111.19,4.13) v1(112.29,61.47) v1(112.28,59.51) v1(112.46,9.85) v1(112.77,88.84) v1(112.84,6.04) v1(113.1,1.08) v1(113.16,14.96) v1(113.41,13.34) v1(113.6,105.6) v1(113.82,60.96) v1(113.82,58.42) v1(113.79,14.96) v1(113.86,7.69) v1(114.05,13.34) v1(114.43,14.96) v1(114.68,13.34) v1(115.32,13.34) v1(115.51,3.75) v1(115.57,94.31) v1(115.64,1.08) v1(115.7,99.66) v1(115.93,60.09) v1(115.89,9.59) v1(115.89,5.78) v1(115.95,79.25) v1(115.98,61.34) v1(115.95,13.34) v1(116.14,105.6) v1(116.33,99.66) v1(116.53,25.39) v1(116.59,79.25) v1(117.04,61.37) v1(117.81,99.66) v1(117.92,73.98) v1(118.11,79.25) v1(118.18,1.08) v1(118.44,99.66) v1(118.56,73.98) v1(118.68,105.6) v1(118.87,79.25) v1(119.07,7.81) v1(119.22,89.35) v1(119.19,73.98) v1(119.83,73.98) v1(120.14,79.25) v1(120.17,57.33) v1(120.46,73.98) v1(120.72,1.08) v1(120.84,79.25) v1(121.22,105.6) v1(121.35,73.98) v1(121.99,73.98) v1(122.36,79.25) v1(122.65,70.97) v1(122.75,73.98) v1(123,79.25) v1(123.26,1.08) v1(123.38,73.98) v1(123.69,70.96) v1(123.76,105.6) v1(123.97,25.42) v1(124.05,62.1) v1(124.52,79.38) v1(124.53,72.24) v1(125.16,79.38) v1(125.8,1.08) v1(125.93,72.27) v1(126.3,105.6) v1(126.49,62.36) v1(126.68,79.38) v1(126.68,72.24) v1(127.32,79.38) v1(127.32,72.24) v1(127.95,72.24) v1(128.1,61.54) v1(128.34,1.08) v1(128.42,70.31) v1(128.59,72.24) v1(128.84,105.6) v1(128.84,79.38) v1(129.16,95.63) v1(129.22,72.24) v1(129.48,79.38) v1(129.86,72.24) v1(130.05,95.63) v1(130.1,60.35) v1(130.3,88.27) v1(130.88,1.08) v1(131,79.38) v1(131.12,61.23) v1(131.32,95.6) v1(131.34,88.27) v1(131.38,105.6) v1(131.44,25.4) v1(131.64,79.38) v1(131.95,95.6) v1(132.42,55.69) v1(132.85,55.21) v1(133.35,95.6) v1(133.31,54.75) v1(133.42,1.08) v1(133.65,88.27) v1(133.81,60.13) v1(133.76,54.28) v1(133.92,105.6) v1(133.99,88.9) v1(134.85,62.1) v1(135.96,1.08) v1(136.46,105.6) v1(136.52,95.6) v1(136.91,31.9) v1(136.91,16.13) v1(137.16,95.6) v1(137.73,22.93) v1(137.85,72.24) v1(138.05,95.6) v1(138.5,1.08) v1(138.63,69.93) v1(138.68,95.6) v1(139,105.6) v1(139.34,68.81) v1(139.73,67.84) v1(139.95,71.78) v1(140.41,70.33) v1(141.04,1.08) v1(141.54,105.6) v1(141.93,22.93) v1(143.58,1.08) v1(144.08,105.6) v1(144.29,25.09) v1(144.78,79.27) v1(144.78,78.64) v1(145.42,79.27) v1(145.42,78.64) v1(146.05,79.27) v1(146.05,78.64) v1(146.12,1.08) v1(146.62,105.6) v1(147.39,22.8) v1(148.66,1.08) v1(149.16,105.6) v1(149.86,7.24) v1(151.2,1.08) v1(151.3,25.09) v1(151.38,94.36) v1(151.38,93.09) v1(151.64,13.84) v1(151.7,105.6) v1(151.7,22.93) v1(152.02,93.73) v1(152.78,94.36) v1(152.78,93.09) v1(152.78,30.61) v1(153.04,9.52) v1(154.24,105.6) v1(154.43,73.41) v1(156.28,22.93) v1(156.72,13.08) v1(156.78,105.6) v1(157.55,5.4) v1(158.31,104.21) v1(158.89,25.09) v1(159.32,105.6) v1(159.33,75.13) v1(159.96,13.4) v1(160.09,104.21) v1(160.09,22.93) v1(160.34,6.42) v1(160.85,101.03) v1(161.36,102.43) v1(162.75,22.8) v1(162.88,16.32) v1(162.93,8.7) v1(163.13,101.41) v1(163.9,25.09) v1(164.53,9.46) v1(165.42,101.29) v1(165.8,22.93) v1(166.12,68.71) v1(167.13,56.39) v1(167.45,102.05) v1(167.6,47.46) v1(167.6,40.08) v1(167.6,36.27) v1(167.56,31.44) v1(167.6,25.09) v1(168.72,85.66) v1(168.85,9.59) v1(168.91,67.94) v1(168.91,67.31) v1(169.04,29.74) v1(169.23,100.4) v1(170.03,26.87) v1(170.4,85.69) v1(170.37,83.73) v1(170.5,30.29) v1(171.42,28.04) v1(172.02,85.28) v1(172.02,82.62) v1(172.28,101.92) v1(172.4,42.69) v1(172.41,38.42) v1(172.41,35.12) v1(173.55,94.05) v1(173.53,52.58) v1(174.06,103.57) v1(174.18,9.46) v1(174.31,105.6) v1(174.82,100.52) v1(175.33,92.65) v1(175.96,102.43) v1(176.47,16.07) v1(176.72,96.84) v1(176.72,32.2) v1(176.72,30.55) v1(176.73,29.4) v1(176.73,28.77) v1(176.73,28.13) v1(176.85,105.6) v1(177.1,94.68) v1(177.8,34.29) v1(178.37,103.57) v1(179.39,105.6) v1(180.66,100.78) v1(180.98,60.7) v1(181.93,105.6) v1(183.24,37.24) v1(183.27,27.85) v1(183.28,27.08) v1(183.96,99) v1(183.96,98.24) v1(183.96,97.48) v1(184.47,105.6) v1(184.72,99) v1(184.72,98.24) v1(184.72,97.48) v1(184.98,68.95) v1(185.23,88.2) v1(185.49,99) v1(185.49,98.24) v1(185.49,97.48) v1(186.02,68.95) v1(186.25,99) v1(186.25,98.24) v1(186.25,97.48) v1(186.27,41.75) v1(186.38,16.45) v1(186.63,6.16) v1(187.01,105.6) v1(187.01,99) v1(187.01,98.24) v1(187.01,97.48) v1(187.26,25.59) v1(187.39,12.13) v1(187.65,24.07) v1(187.68,41.53) v1(188.03,39.69) v1(188.03,8.58) v1(188.79,38.17) v1(189.04,34.86) v1(189.42,0.96) v1(189.55,105.6) v1(189.71,27.4) v1(189.8,9.85) v1(189.8,3.5) v1(189.93,46.42) v1(190.31,21.78) v1(190.46,37.86) v1(190.57,20.64) v1(190.74,29.17) v1(191.01,55.12) v1(191.01,54.48) v1(191.33,44.77) v1(191.46,9.21) v1(191.64,55.12) v1(191.64,54.48) v1(191.59,19.58) v1(191.58,7.81) v1(191.84,8.58) v1(191.96,0.96) v1(192.09,105.6) v1(192.22,16.83) v1(192.22,9.21) v1(192.22,7.81) v1(192.22,5.91) v1(192.33,19.71) v1(192.6,46.29) v1(192.6,28.64) v1(192.6,8.58) v1(192.73,90.36) v1(192.85,9.21) v1(192.85,7.81) v1(193.23,44.52) v1(193.42,32.26) v1(193.36,30.8) v1(193.42,23.24) v1(193.51,27.5) v1(193.61,83.38) v1(193.87,88.2) v1(193.87,3.62) v1(194.02,27.04) v1(194.5,0.96) v1(194.63,105.6) v1(194.88,21.4) v1(195.01,90.24) v1(195.2,48.39) v1(195.2,47.75) v1(195.27,41.72) v1(195.85,43.86) v1(196.19,22.63) v1(196.72,73.48) v1(197.17,105.6) v1(197.36,62.99) v1(197.74,62.48) v1(197.87,43.31) v1(198.49,44.82) v1(198.75,48.01) v1(198.85,33.7) v1(198.8,32.93) v1(198.8,32.27) v1(199.2,26.63) v1(199.39,14.73) v1(199.51,50.05) v1(199.51,33.7) v1(199.71,105.6) v1(199.96,18.86) v1(200.11,69.02) v1(200.63,67.06) v1(201.39,12.26) v1(202.25,105.6) v1(202.2,17.03) v1(202.4,0.96) v1(202.45,9.36) v1(202.45,8.7) v1(202.76,14.65) v1(203.01,12.56) v1(203.11,9.16) v1(203.11,8.45) v1(203.41,16.53) v1(203.9,0.96) v1(204.27,74.76) v1(204.42,76.01) v1(204.54,3.16) v1(204.74,67.38) v1(204.79,105.6) v1(206.44,0.96) v1(206.7,83.76) v1(206.9,85.46) v1(206.87,71.19) v1(207.33,105.6) v1(207.51,84.93) v1(208.03,80.9) v1(208.14,82.62) v1(208.22,61.92) v1(208.27,52.85) v1(208.6,103.95) v1(208.6,29.38) v1(208.6,26.81) v1(208.66,69.72) v1(209.04,102.74) v1(209.04,102.11) v1(209.04,75.44) v1(208.98,0.96) v1(209.17,73.91) v1(209.21,70.83) v1(209.21,52.85) v1(209.3,80.9) v1(209.3,65.91) v1(209.36,100.4) v1(209.36,97.22) v1(209.51,82.36) v1(209.57,72.66) v1(209.87,105.6) v1(211.14,104.08) v1(211.14,101.54) v1(211.14,99) v1(211.14,97.65) v1(211.14,82.49) v1(211.14,79.95) v1(211.14,77.41) v1(211.14,74.87) v1(211.14,72.33) v1(211.14,69.79) v1(211.14,67.25) v1(211.14,64.71) v1(211.14,62.17) v1(211.14,59.63) v1(211.14,57.09) v1(211.14,54.55) v1(211.14,2.25) v1(211.09,1.03) v1(211.19,28.16) v2(7.1,30.01) v2(14.72,70.81) v2(16.86,57.24) v2(22.85,64.53) v2(34.28,68.77) v2(34.61,22.47) v2(39.46,31.66) v2(40.91,31.49) v2(42.64,75.25) v2(43.02,37.58) v2(47.39,21.71) v2(50.08,76.9) v2(55.51,33.7) v2(60.77,72.84) v2(65.45,82.41) v2(67.58,57.17) v2(70.53,35.52) v2(72.56,71.06) v2(79.39,23.66) v2(88.43,97.96) v2(103.04,19.52) v2(116.93,94.63) v2(117.11,99.84) v2(123.08,15.94) v2(125.67,22.32) v2(131.56,54.75) v2(146.45,80.05) v2(162.32,12.74) v2(164.3,22.55) v2(167.2,16.27) v2(168.26,70.07) v2(168.75,79.31) v2(172.18,21.91) v2(180.25,98.77) v2(186.04,49.42) v2(190.03,14.19) v2(190.95,32.55) v2(191.89,24.45) v2(193.61,98.31) v2(203.27,67.22) v2(203.8,85.44) v4(47.88,59.05) v4(47.88,58.29) v4(47.88,57.53) v4(47.88,56.77) v4(48.64,59.05) v4(48.64,58.29) v4(48.64,57.53) v4(48.64,56.77) v4(50.04,74.3) v4(50.34,77.67) v4(50.8,74.3) v4(51.08,77.67) v4(51.56,74.3) v4(51.82,77.67) v4(57.28,74.3) v4(57.48,73.2) v4(57.78,57.4) v4(57.78,56.64) v4(57.78,55.88) v4(57.78,55.12) v4(58.04,74.3) v4(58.24,73.2) v4(58.55,57.4) v4(58.55,56.64) v4(58.55,55.88) v4(58.55,55.12) v4(65.63,60.25) v4(65.63,59.51) v4(65.66,58.78) v4(65.66,58.04) v4(66.4,60.25) v4(66.4,59.51) v4(66.42,58.78) v4(66.42,58.04) v4(125.6,10.54) v4(126.24,9.91) v4(126.36,10.67) v4(127,9.91) v4(127.64,10.36) v4(128.19,9.86) v4(128.78,10.36) v4(129.54,10.29) v4(133.75,22.86) v4(134.49,22.86) v4(135.25,22.86) v4(136.02,22.86) v4(136.78,22.86) v4(138.23,5.59) v4(138.96,5.59) v4(173.99,76.71) v4(173.99,75.95) v4(174.73,68.5) v4(174.75,76.71) v4(174.75,75.95) v4(175.34,67.92) v4(175.51,76.71) v4(175.51,75.95) v4(176.28,76.71) v4(176.28,75.95) v4(177.04,76.71) v4(177.04,75.95) v4(180.95,69.19) v4(181.58,68.55) v4(181.91,69.39) v4(182.22,67.89) v4(182.42,68.68) v4(187.9,97.6) v4(188.66,97.6) v4(189.42,97.6) v4(190.19,97.6) v4(190.95,97.6) v4(191.71,97.6) v4(192.52,97.4) v4(192.85,98.16) v4(193.17,73.66) v4(193.29,76.58) v4(193.42,75.56) v4(193.74,77.41) v4(194.18,76.58) v4(194.18,75.56) v4(194.5,77.41) v4(195.07,76.58) v4(195.07,75.56) v4(195.83,75.95) v4(200.32,64.07) v4(200.73,63.46) v4(200.73,62.73) v4(200.73,61.99) v4(200.73,61.25) v4(200.73,60.52) v4(202.29,85.42) v4(202.31,84.48) v4(204.34,87.25) v4(205.11,87.25)
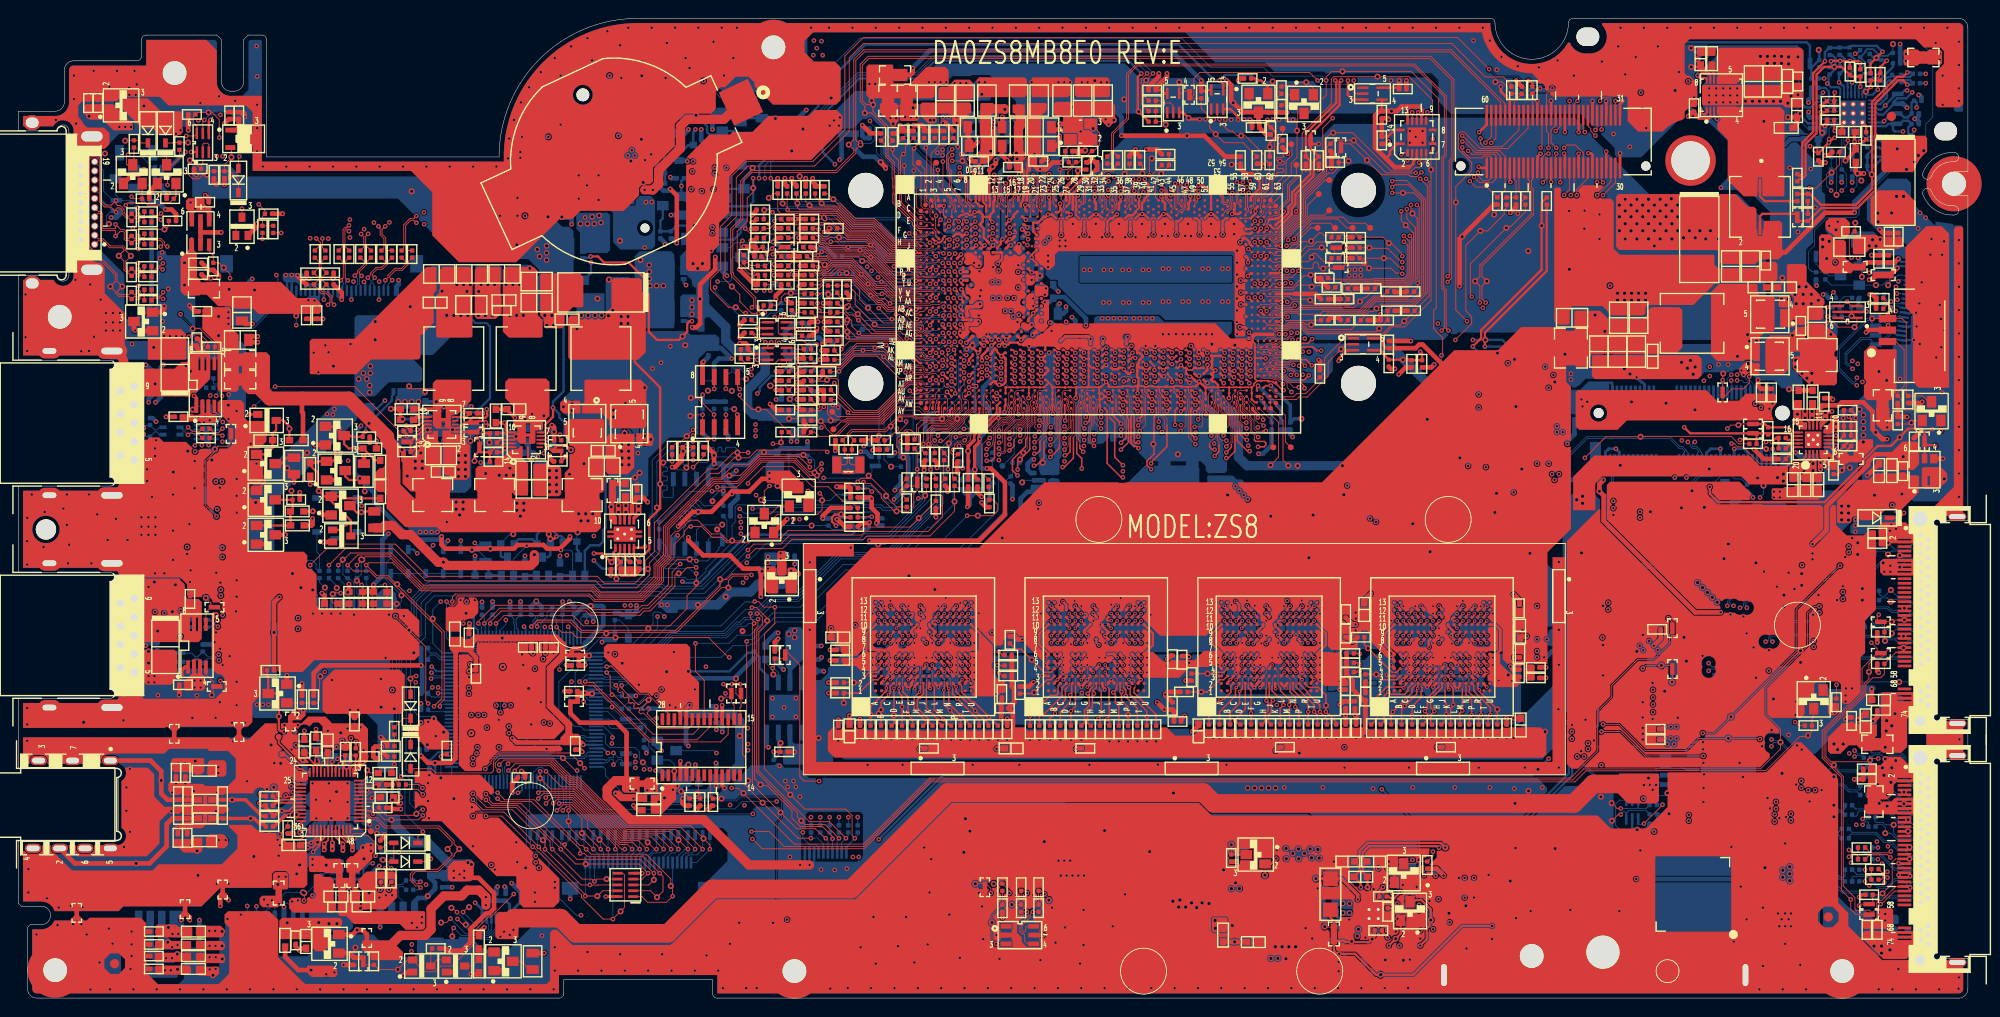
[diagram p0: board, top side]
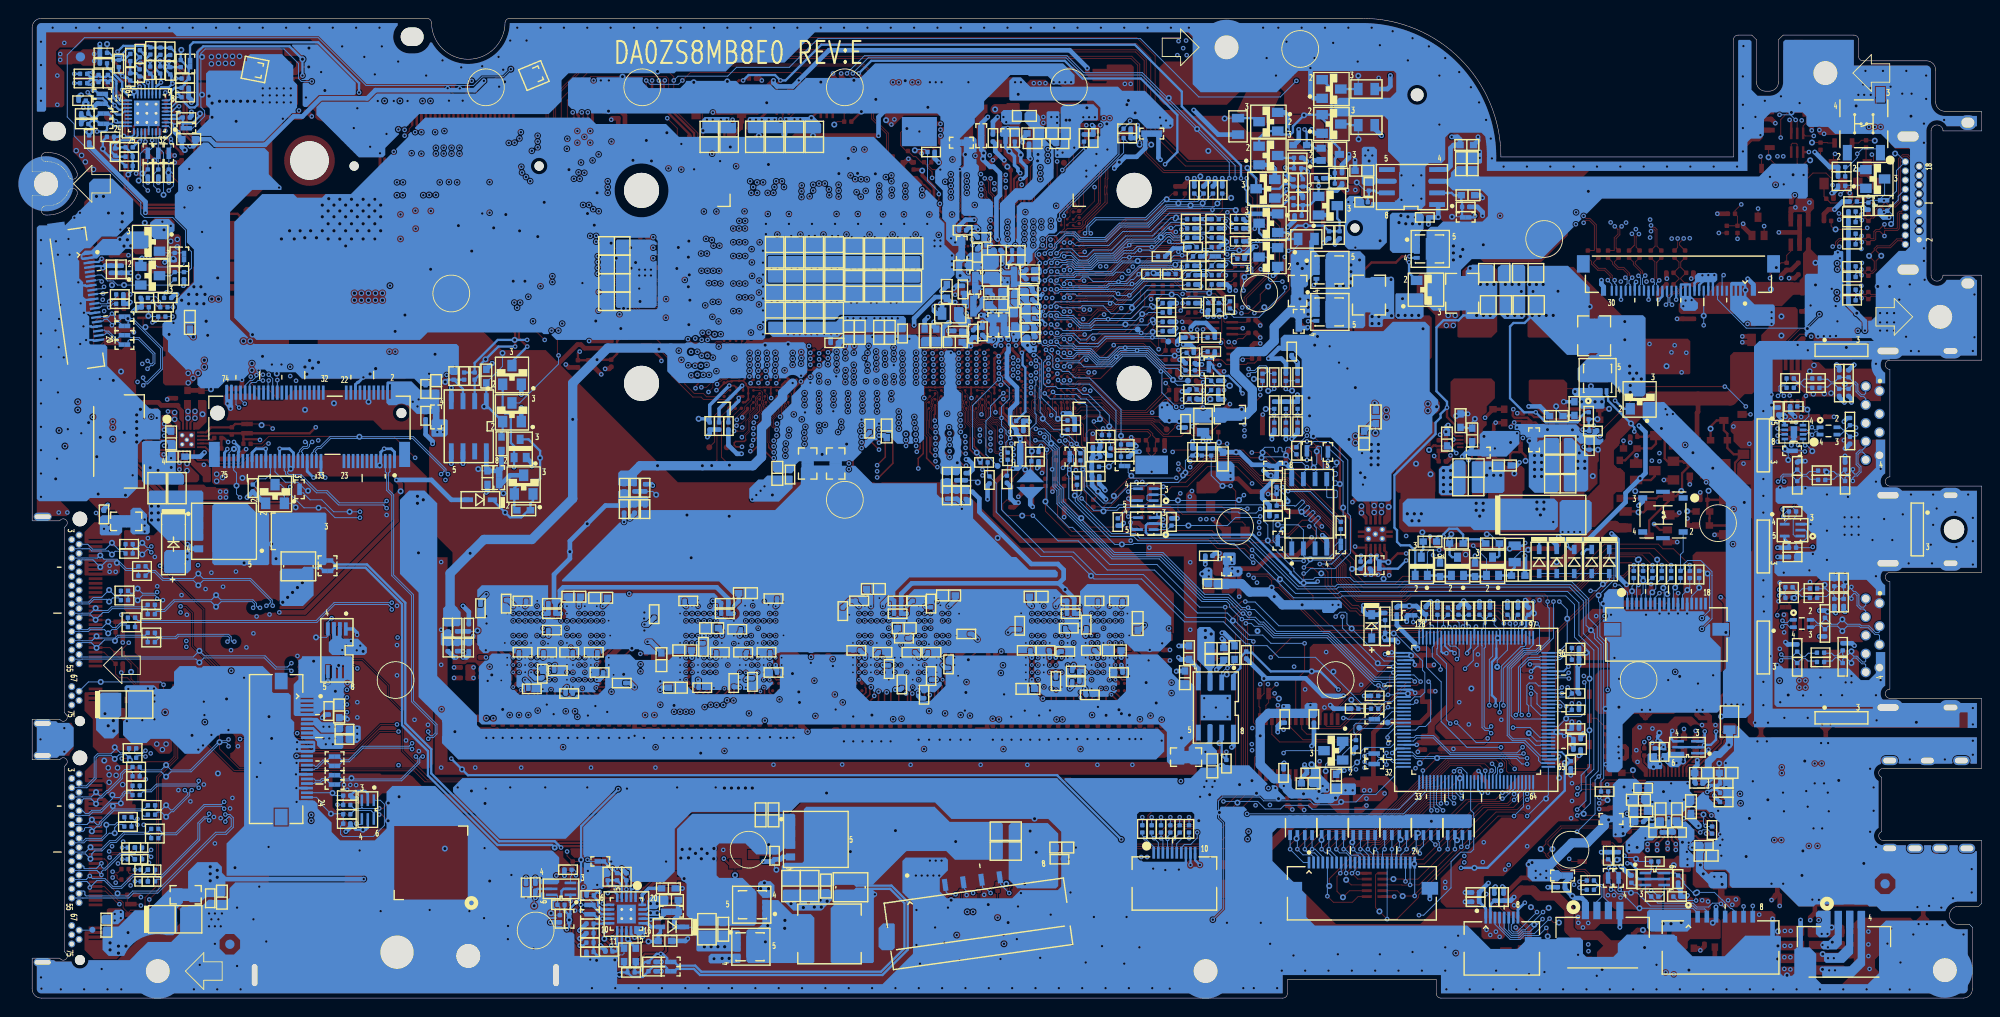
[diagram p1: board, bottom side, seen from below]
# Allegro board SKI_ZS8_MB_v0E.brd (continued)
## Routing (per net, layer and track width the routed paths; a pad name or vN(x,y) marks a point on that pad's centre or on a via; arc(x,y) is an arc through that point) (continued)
VCC_SENSE: length 96.9
  TOP w0.254: v1(143.27,99.86) 143.28,99.86 143.38,99.76 143.38,97.44 140.08,94.13 R38.1 140.56,91.09 140.56,89.66 138.58,87.68 138.58,86.5 138.18,86.1 138.18,85.43 137.22,84.48 137.13,84.48 U6.E63
  IN1 w0.254: v1(143.27,99.86) 143.27,99.94 144.16,100.84 157.51,100.84 160.05,98.3 163.45,98.3 164.93,99.77 177.88,99.77 182.57,104.46 199.59,104.46 204.58,99.47 204.58,98.95 205.26,98.27 206.02,98.27 207.02,97.27 207.02,95.25 v1(206.26,94.49)
  BOTTOM w0.254: PR100.2 205.06,95.48 205.63,95.48 PC76.1 205.61,94.75 205.61,94.17 PR104.1 206.26,94.25 v1(206.26,94.49)
VCCST_PWRGD: length 41.1
  TOP w0.076: U6.B59 134.42,86.49 134.42,87.09
  TOP w0.102: v1(145.29,99.86) 145.29,98.55 145.42,98.42 U1.2 ; 127.53,97.92 127.89,98.27 127.89,100.08 128.55,100.74 140.48,100.74 v1(141.35,99.86) ; 127.53,97.92 R8.2 128.69,96.81 129.62,95.89 129.62,94.67 v2(130.26,94.02) 131.19,93.09 133.23,93.09 C20.1 134.24,91.07 134.24,90.37 134.44,90.17 134.62,90.17 135.38,89.41 135.38,88.06 134.42,87.09 ; 127.53,97.92 R7.1
  BOTTOM w0.102: v1(145.29,99.86) 144.87,99.44 141.77,99.44 v1(141.35,99.86)
VCCST_PWRGD_EN: length 6.4
  TOP w0.102: U3.2 125.65,97.11 125.35,97.41 124.46,97.41 124.2,97.67 R9.2 R13.2 R16.2 124.51,95.39 v2(124.83,95.06)
VCCST_PWRGD_R: length 2.4
  TOP w0.102: R7.2 126.87,98.7 126.64,98.46 U3.4 v2(126.3,99.68)
VCCST_PWRGD_XDP: length 3.4
  TOP w0.102: CN1.50 164.76,97.37 164.72,97.41 R6.2 165.1,98.8 165.37,98.8 v1(165.57,99)
VIN: length 207.2
  TOP w0.508: 30.85,65.25 30.85,65.25 30.85,63.8 30.96,63.69 PR30.1 ; PR55.1 31.9,51.44 32,51.54 v1(32,52.2) ; v1(70.93,88.05) 71.63,87.36 v1(71.63,82.17) ; v1(172.47,56.39) 172.01,55.93 v2(172.01,55.16) 172.47,54.7 172.47,51.95 182.44,41.98 v1(185.21,41.98) ; R785.1 50.1,7.1 v1(50.69,7.69)
  TOP w1.524: 40.77,57.1 40.77,59.94 40.13,60.58 40.13,61.09 35.97,65.25 27.34,65.25 26.23,66.36
  IN1 w0.508: v1(32,52.2) 32.13,52.07 34.32,52.07 35.2,52.96 40.51,52.96 41.66,51.82 v1(46.61,51.82)
  IN2 w0.508: v1(46.61,51.82) 43.54,51.82 42.33,50.61 42.33,44.99 41.92,44.58 41.92,43.83 42.56,43.2 42.56,32.12 43.83,30.85 44.87,30.85 45.23,30.5 45.23,25.53 45.95,24.81 45.95,17.02 46.12,16.86 46.12,11.39 47.03,10.48 48.45,10.48 50.69,8.24 v1(50.69,7.69) ; v1(62.61,50.29) 62.61,49.66 61.98,49.02 61.98,47.24 62.23,46.99 67.25,46.99 68.33,48.07 68.33,52.96 69.09,53.72 69.09,67.25 67.33,69.01 67.33,80.41 67.76,80.84 69.13,80.84 69.73,81.43 69.73,85.6 70.93,86.81 v1(70.93,88.05)
  IN3 w0.508: v4(192.6,102.43) 192.6,102.68 193.93,104.01 204.54,104.01 v1(204.73,103.83)
  BOTTOM w0.254: PR150.2 182.49,46.81 180.68,46.81 PR151.2
  BOTTOM w0.508: PR129.1 71.13,82.67 v1(71.63,82.17) ; v1(204.73,103.83) PR79.1 PR82.1 ; PR119.1 69.59,88.46 70.16,87.88 70.76,87.88 v1(70.93,88.05) ; PD2.2 166.5,54.23 168.66,56.39 v1(172.47,56.39)
  vias: v2(193.61,102.43) v4(47.62,53.97) v4(47.62,53.21) v4(48.01,52.58) v4(48.39,53.97) v4(48.39,53.21) v4(54.23,53.85) v4(54.23,53.09) v4(54.61,52.45) v4(54.99,53.85) v4(54.99,53.09) v4(60.96,52.7) v4(61.21,51.94) v4(61.72,52.7) v4(61.98,51.94) v4(62.48,52.7) v4(137.92,16.28) v4(137.95,15.16) v4(138.66,15.75) v4(139.27,16.23) v4(139.29,15.16) v4(139.93,15.75) v4(140.54,16.23) v4(140.69,15.27) v4(141.38,16.18) v4(141.53,15.24) v4(182.7,45.21) v4(183.24,44.68) v4(183.77,44.15) v4(184.3,43.61) v4(184.84,43.08) v4(189.53,102.49) v4(190.3,102.49) v4(190.3,101.73) v4(191.06,102.51) v4(191.06,101.73) v4(191.82,102.49) v4(191.82,101.73) v4(192.6,101.67) v4(193.37,69.42) v4(193.37,68.68) v4(194.06,68) v4(194.59,67.46) v4(195.12,68) v4(195.12,66.95) v4(205.43,90.19) v4(206.31,91) v4(206.72,91.71) v4(207.3,92.22)
VSS_SENSE: length 84.8
  TOP w0.254: v1(143.92,99.86) 143.74,99.69 143.74,97.18 140.59,94.03 R26.2
  IN1 w0.254: v1(143.92,99.86) 144.51,100.46 152.01,100.46 152.26,100.2 152.26,99.58 152.52,99.33 153.03,99.33 153.28,99.58 153.28,100.2 153.53,100.46 154.04,100.46 154.3,100.2 154.3,99.58 154.55,99.33 155.06,99.33 155.31,99.58 155.31,100.2 155.57,100.46 157.35,100.46 159.89,97.92 163.59,97.92 165.08,99.4 178.03,99.4 182.72,104.09 199.44,104.09 204.22,99.31 204.22,98.79 205.1,97.9 205.87,97.9 206.53,97.24 v1(206.53,96.93)
  BOTTOM w0.254: PR98.2 205.16,95.83 205.55,95.83 PC75.1 205.99,97.46 206.19,97.67 PR96.2 206.32,97.67 206.53,97.46 v1(206.53,96.93)
VSS_SENSE_R: length 13.3
  TOP w0.229: U6.E62 136.53,83.76 137.01,83.76
  TOP w0.254: 137.01,83.76 138.53,85.28 138.53,85.95 138.94,86.36 138.94,87.48 140.92,89.46 140.92,91.02 R39.2 140.59,92.46 R26.1 v1(141.47,92.96)
2ND_MBCLK: length 194.5
  TOP w0.102: Q11.3 80.41,69.45 v1(80.39,69.47) 80.26,69.6 R139.2 ; v1(79.76,46.05) 79.65,46.15 77.65,46.15 77.07,45.57 v2(76.34,45.57) 76.34,44.85 71.53,40.03 61.26,40.03 60.15,41.14 56.51,41.14 v1(55.8,40.43) ; v1(174.34,20.64) 173.93,20.64 v2(173.34,21.22)
  IN3 w0.102: v1(174.34,20.64) 174.08,20.39 173.87,20.39 173.6,20.66 173.6,29.68 172.83,30.44 172.16,30.44 168.93,27.21 168.93,24.96 165.37,21.4 133.75,21.4 132.63,22.52 86.52,22.52 83.17,25.87 83.17,27.8 81.57,29.4 81.57,36.82 80.48,37.91 80.48,39.74 79.21,41.01 79.21,43.7 79.76,44.25 v1(79.76,46.05) 79.58,46.23 79.58,46.74 80.01,47.17 80.01,49.23 80.62,49.84 80.62,53.56 78.84,55.34 78.84,64.96 79.19,65.31 79.19,68.65 79.5,68.96 79.5,69.65 79.72,69.88 80.14,69.88 80.39,69.62 v1(80.39,69.47)
  BOTTOM w0.102: R511.1 56.05,41.72 56.24,41.53 56.24,41.32 56.01,41.09 56.01,40.64 v1(55.8,40.43) 55.99,40.25 U23.115 ; v1(174.34,20.64) 176.11,20.64 176.23,20.76 ; 176.23,20.76 176.23,20.74 176.33,20.64 177.1,20.64 R554.2 ; 176.23,20.76 Q17.3
2ND_MBDATA: length 199.8
  TOP w0.102: Q11.6 84.44,70.75 84.58,70.61 R135.2 85.46,70.75 85.09,71.12 82.96,71.12 v1(82.75,71.32) ; v1(174.34,19.98) 174.06,19.98 v2(173.37,19.29) ; v1(56.44,40.43) 56.44,40.75 56.61,40.91 60.06,40.91 61.17,39.8 71.62,39.8 76.49,44.68 v2(77.24,44.68) 77.24,45.42 77.74,45.92 79.02,45.92 v1(79.2,45.74)
  IN3 w0.102: v1(82.75,71.32) 82.41,71.32 81.96,70.87 81.79,70.87 81.03,70.1 79.63,70.1 79.27,69.75 79.27,69.06 78.96,68.74 78.96,65.41 78.61,65.06 78.61,55.25 80.39,53.47 80.39,49.94 79.78,49.33 79.78,47.27 79.35,46.84 79.35,45.88 v1(79.2,45.74) 79.2,45.66 79.53,45.34 79.53,44.34 78.98,43.8 78.98,40.92 80.25,39.65 80.25,37.82 81.35,36.73 81.35,29.3 82.95,27.7 82.95,25.77 86.43,22.29 132.53,22.29 133.65,21.17 165.46,21.17 169.15,24.86 169.15,27.12 172.25,30.22 172.74,30.22 173.37,29.58 173.37,20.56 173.78,20.16 173.99,20.16 174.16,20.16 v1(174.34,19.98)
  BOTTOM w0.102: 174.93,20.12 Q17.6 ; 174.93,20.12 175.22,20.41 177.07,20.41 R555.2 ; 174.93,20.12 174.93,20.15 174.79,20.28 174.59,20.28 174.34,20.03 v1(174.34,19.98) ; U23.116 56.39,40.39 v1(56.44,40.43) 56.24,40.64 56.24,41 56.46,41.22 56.46,41.51 56.67,41.72 R512.1
670_BST: length 2.7
  TOP w0.203: 53.09,61.85 53.38,61.56 PU3.10
  TOP w0.381: 53.09,61.85 53.08,61.86 53.08,62.42 v1(52.87,62.63) 52.86,62.61 PR20.1
670_BST1: length 2.5
  TOP w0.381: PR20.2 PC42.1 53.16,64.03 v1(54.03,63.16)
670_CLK: length 21.3
  TOP w0.203: v1(57.48,60.78) 57.45,60.76 PU3.5
  TOP w0.254: v2(57.88,49.98) 58.28,49.98 v1(58.54,50.23)
  IN3 w0.254: v1(58.54,50.23) 58.74,50.43 58.74,53.53 59.56,54.36 59.56,58.04 58.87,58.74 58.87,59.4 v1(57.48,60.78)
  BOTTOM w0.254: 58.54,50.28 58.54,50.49 57.94,51.08 57.05,51.08 56.41,50.44 PC109.2 55.97,49.93 54.4,49.93 PC108.2 ; 58.54,50.28 59.07,50.28 59.28,50.07 PC110.2 ; 58.54,50.28 v1(58.54,50.23)
670_EN: length 6.4
  TOP w0.203: PU3.13 52.74,60.36 52.32,59.94 51.87,59.94 51.33,59.41 PC50.2
  TOP w0.254: v2(49.62,58.46) 49.62,59.01 PR37.1 50.31,59.41 PC50.2 PR45.2
670_ENLDO: length 1.9
  TOP w0.203: PR35.2 52.38,60.76 PU3.12
670_SW: length 0.8
  BOTTOM w0.508: PR138.1 v1(55.88,63.58)
  vias: v2(57.17,63.36)
670PG: length 4.3
  TOP w0.203: PU3.4 57.22,60.36 57.33,60.25 57.35,60.25
  TOP w0.254: v2(60.11,59.65) 59.63,60.14 59.39,60.14 59.33,60.07 58.59,60.07 58.28,59.76 PR40.1 58.04,59.56 57.35,60.25
671_BST: length 1.7
  TOP w0.203: 44.04,63.23 PU2.10
  TOP w0.381: PR21.1 43.32,63.23 44.04,63.23
671_BST1: length 2.2
  TOP w0.381: PR21.2 PC41.1 40.54,64.11 v2(40.53,64.12)
671_EN: length 6.2
  TOP w0.203: PU2.13 44.23,62.03 43.59,61.4 43.52,61.4 43.31,61.18
  TOP w0.254: 43.31,61.18 PR32.1 PR41.2 42.85,59.44 43.28,59.87 v1(43.28,59.99)
  BOTTOM w0.254: v2(41.75,59.68) 41.75,59.68 PC99.2 42.97,59.68 v1(43.28,59.99)
671_FB: length 4.5
  TOP w0.203: PU2.12 44.2,62.43 43.62,61.86 v1(43.4,61.86)
  BOTTOM w0.254: v2(41.8,63.01) 42.72,63.01 PR137.2 42.75,62.41 42.68,62.34 PR139.1 43.26,61.72 v1(43.4,61.86)
671_SW: length 8.5
  TOP w0.102: v2(42.51,66.59) 42.78,66.32 PL3.1
  TOP w0.381: PC41.2 45.34,64.11
  BOTTOM w0.381: PR135.1 v4(45.47,64.9)
671PG: length 4.9
  TOP w0.203: 48.13,62.23 47.94,62.03 PU2.4
  TOP w0.254: v1(50.95,64.08) 50.94,64.07 50.99,64.02 50.99,63.86 51,63.85 51,63.45 50.99,63.44 50.99,63.34 50.82,63.16 49.42,63.16 49.11,62.86 PR22.1 48.54,62.64 48.13,62.23
24707_LX: length 14.4
  IN3 w1.016: 144.27,10.92 142.16,10.92 139.24,8 131.06,8
  vias: v2(132.07,7.89) v4(130.2,8.46) v4(130.23,7.59) v4(144.09,10.29) v4(144.83,10.29)
24737_ACDET: length 7.3
  TOP w0.254: PR73.2 148.34,7.23 v1(148.97,6.6) ; PR72.2 149.51,9.79 v1(150.02,10.29)
  IN1 w0.254: v1(150.02,10.29) 148.97,9.24 v1(148.97,6.6)
  BOTTOM w0.254: PU11.6 149.88,10.14 v1(150.02,10.29)
24737_ACN: length 62.6
  TOP w0.254: v3(155.24,16.38) 154.74,16.89 146.79,16.89 145.92,16.02 145.92,15.39 PC65.1 145.92,14.33 145.92,13.82 PC67.2 146.05,12.47 v1(146.05,12.06)
  BOTTOM w0.254: PR151.1 179.21,46.84 175.82,46.84 171.86,42.88 171.86,29.69 169.04,26.87 169.04,24.23 161.47,16.66 155.52,16.66 v3(155.24,16.38) ; v1(146.05,12.06) 146.05,11.94 146.45,11.54 PU11.1
24737_ACP: length 61.4
  TOP w0.254: v3(146.79,12.06) PC67.1 146.28,13.72 146.28,14.43 PC66.2 146.28,15.29 146.28,15.88 146.94,16.54 154.41,16.54 v1(154.56,16.38)
  BOTTOM w0.254: PU11.2 146.95,11.9 v3(146.79,12.06) ; PR146.1 179.14,47.19 175.67,47.19 171.5,43.02 171.5,29.91 168.68,27.09 168.68,24.45 161.3,17.07 155.24,17.07 v1(154.56,16.38)
24737_BM#: length 6.8
  TOP w0.254: v1(149.1,5.71) v2(149.84,6.46) 150.39,7.01 PQ16.2
  BOTTOM w0.254: PU11.11 148.45,5.21 148.57,5.08 PR170.1 149.1,5.22 v1(149.1,5.71)
24737_BST: length 3
  BOTTOM w0.279: PU11.17 144.91,8.64
  BOTTOM w0.381: 144.91,8.64 144.89,8.64 v1(144.8,8.55) 144.7,8.64 143.76,8.64 143.28,9.12 PR163.2
24737_CMPIN: length 6
  TOP w0.254: v1(148.46,12.06) 148.07,11.68 PR68.2
  BOTTOM w0.254: PU11.4 147.95,12.3 PR157.1 PR158.2 149.48,12.32 149.35,12.19 148.59,12.19 v1(148.46,12.06)
24737_CMPOUT: length 7
  TOP w0.254: v1(148.97,14.1) 149.71,13.36 PQ15.2
  BOTTOM w0.254: PR176.2 149.11,14.1 v1(148.97,14.1) 148.47,13.6 PR157.2 148.23,13.6 PR156.1 v1(147.45,11.85) PU11.3
24737_DH: length 11.7
  IN1 w1.016: 132.71,11.48 139.95,11.48 142.39,9.04 143.38,9.04 143.41,9.07
  vias: v2(132.43,12.54) v4(131.98,11.91) v4(132.84,11.91) v4(144.09,9.27) v4(144.83,9.27)
24737_DL: length 8.9
  IN1 w1.016: 145.16,6.86 142.39,6.86 139.84,4.31 137.3,4.31 137.29,4.32
  vias: v2(137.91,4.28) v4(136.27,4.32) v4(137.03,4.32) v4(145.67,6.76) v4(145.8,7.49)
24737_ILIM: length 6
  BOTTOM w0.254: PU11.10 149.95,8.14 149.99,8.1 PR167.1 PR168.2 PR169.2 PC133.2 150.69,4.7 v2(150.69,4.1)
24737_REGN: length 4.9
  BOTTOM w0.279: 145.18,8.14 PU11.16
  BOTTOM w0.381: 145.18,8.14 144.78,7.75 PD8.2 143.74,7.14 143.99,6.88 PC132.1 144.05,6.16 v2(145.05,6.16)
24737_SRN: length 7.8
  BOTTOM w0.254: PC136.1 146.84,2.3 145.66,2.3 PC135.2 144.53,3.43 143.21,3.43 143.01,3.23 PR174.1 ; PC136.1 148.09,2.79 v1(148.3,2.58) ; PC136.1 147.33,3.18 147.7,3.56 PR172.1
24737_SRP: length 6.5
  BOTTOM w0.254: PR171.1 146.43,3.3 146.55,3.18 PC136.2 146.05,2.79 145.67,3.17 145.67,3.68 145.42,3.94 PC134.2 144.16,4.82 v1(143.7,4.82) 143.47,4.82 143.01,4.35 PR173.1
24737_VCC: length 9.3
  TOP w0.381: v1(145.72,10.72) 145.72,11.25 143.97,13 PR67.2 v2(141.16,13)
  BOTTOM w0.279: PU11.20 v1(145.72,10.72)
  BOTTOM w0.381: PC127.2 145.03,11.94 145.72,11.25 v1(145.72,10.72)
51216_DRVH: length 7.1
  IN1 w1.016: 194.06,63.5 194.06,64.62 190.4,68.28 189.55,68.28
  vias: v1(187.47,68.29) v4(188.19,69.06) v4(188.19,68.33) v4(194.39,63.86) v4(194.39,63.12)
51216_DRVL: length 13.8
  IN1 w1.016: 196.52,63.8 196.52,65.33 196.44,65.41 196.44,68.55 192.05,72.95 192.05,75.79
  vias: v1(197.32,63.85) v4(191.82,76.07) v4(192.56,76.07) v4(196.6,63.73) v4(196.6,62.99)
51216_MODE: length 1.7
  TOP w0.203: 192.83,60.36 PU4.19
  TOP w0.254: PR39.2 192.83,60.36
51216_REF: length 7
  TOP w0.203: PC48.1 198.19,59.64 197.41,59.64 197.09,59.96 PU4.6
  TOP w0.254: PC48.1 199.13,60.58 199.52,60.58 199.9,60.96 v1(199.9,63.11) 199.9,63.48 PR19.1
51216_REFIN: length 4.9
  TOP w0.203: PC46.1 198.11,60.71 197.41,60.71 197.36,60.76 PU4.8
  TOP w0.254: PC46.1 PR24.1 198.62,62.7 198.54,62.78 v1(198.54,63.13) 198.54,63.47 198.62,63.54 PR19.2
51216_S3: length 7.9
  TOP w0.203: 192.97,61.16 PU4.17
  TOP w0.254: v1(187.31,60.75) 187.39,60.82 189.11,60.82 ; 189.11,60.82 PR27.2 190.24,61.47 PR25.2 190.51,61.47 192.66,61.47 192.97,61.16 ; 189.11,60.82 PR36.2
51216_S5: length 5
  TOP w0.203: PU4.16 193.18,61.56
  TOP w0.254: PR23.2 190,62.48 PR25.1 192.62,62.11 193.18,61.56
51216_SW: length 9.7
  IN3 w1.016: 195.35,63.98 195.35,64.63 188.99,70.99 188.98,70.99
  vias: v2(187.04,69.84) v2(188.13,72.2) v4(188.37,71.5) v4(189.1,71.5) v4(195.15,63.86) v4(195.15,63.12)
51216_TRIP: length 1.6
  TOP w0.203: 192.98,60.76 PU4.18
  TOP w0.254: PR28.2 192.49,60.76 192.98,60.76
51216_VBST:
  vias: v2(193.56,63.54)
51624_ALERT#: length 7.3
  BOTTOM w0.102: PU7.32 198.22,93.85 198.37,93.7 PR109.2 198.13,92.34 197.81,92.01 v2(197.81,87.42)
51624_B-RAMP: length 4.9
  BOTTOM w0.178: 199.02,99.06 PU7.11
  BOTTOM w0.254: 199.02,99.06 199.02,100.36 PR87.1 199.76,101.1 199.76,102.16 199.75,102.18 199.75,102.18 199.46,102.46 199.46,102.46 PR78.2
51624_CLK: length 6.5
  BOTTOM w0.089: PR110.2 199.89,92.34 199.9,92.33
  BOTTOM w0.102: PR110.2 199.25,92.34 198.62,92.97 PU7.31 ; 199.9,92.33 200.35,91.89 200.35,89.13 v2(200.51,88.97)
51624_COMP: length 8.3
  BOTTOM w0.178: 201.13,93.34 200.62,93.85 PU7.26
  BOTTOM w0.254: 201.13,93.34 202.56,93.34 203.07,92.84 PC79.2 202.56,92.46 202.44,92.58 PR107.2 201.16,91.8 PR111.2 PR112.1 201.16,90.13 201.49,89.8 201.49,89.78 v2(201.64,89.63)
51624_CSN1: length 31.7
  TOP w0.254: v1(205.51,99.42) 205.03,99.9 204.55,99.9 202.03,97.38 202.03,87.93 200.08,85.98 196.16,85.98 194.76,84.57 PR15.1 PR14.2
  BOTTOM w0.178: 202.3,97.29 PU7.18
  BOTTOM w0.254: v1(205.51,99.42) 205.96,99.42 PC74.1 205.78,99.9 205.09,99.9 PR91.2 204.66,99.9 204.07,99.9 PC73.2 203.67,99.87 203.51,99.87 203.29,99.66 203.29,98.01 202.57,97.29 202.3,97.29
51624_CSN2: length 3.4
  BOTTOM w0.178: PU7.19 202.17,96.89 202.36,96.7
  BOTTOM w0.254: 202.36,96.7 202.38,96.67 202.64,96.67 v1(203.11,97.14) 203.11,97.2 204.08,98.16 PR94.1
51624_CSP1: length 31.6
  TOP w0.254: PR12.2 PR13.1 194.94,87.51 196.12,86.33 199.92,86.33 201.68,88.09 201.68,97.53 204.4,100.25 205.03,100.25 v1(205.51,100.74)
  BOTTOM w0.178: 202.31,97.66 202.28,97.69 PU7.17
  BOTTOM w0.254: 202.31,97.66 202.44,97.66 202.59,97.81 202.59,97.82 202.94,98.16 202.94,99.51 202.94,99.81 203.36,100.23 203.62,100.23 PC73.1 204.07,100.25 204.66,100.25 PR91.1 205.09,100.25 205.78,100.25 PC72.1 205.96,100.74 v1(205.51,100.74)
51624_CSP2: length 5.7
  BOTTOM w0.178: 202.41,96.14 202.06,96.49 PU7.20
  BOTTOM w0.254: v1(206.06,98.57) 205.4,97.91 204.41,97.91 204.08,97.58 PR97.1 202.89,96.14 202.41,96.14
51624_DATA: length 3.1
  BOTTOM w0.102: PR108.2 197,92.57 v1(197,93.49) 197,94.64 197.25,94.89 PU7.1
51624_DROOP: length 6.2
  BOTTOM w0.178: PU7.25 201.02,94 201.3,93.73
  BOTTOM w0.254: 201.3,93.73 202.02,93.73 v1(202.12,93.83) 202.65,93.83 202.75,93.73 PC77.1 203.19,93.22 203.55,92.86 203.55,92.16 PC79.1 202.95,91.57 PR111.1
51624_F-IMAX: length 5.2
  BOTTOM w0.178: PU7.10 198.62,99.2
  BOTTOM w0.254: 198.62,99.2 198.45,99.36 198.38,99.36 198.1,99.65 198.09,99.65 198.08,99.64 v1(198.08,99.65) 198.08,100.53 PR86.1 198.69,101.14 198.69,102.2 198.23,102.66 PR77.2
51624_GFB: length 2.7
  BOTTOM w0.178: PU7.23 202.18,95.29
  BOTTOM w0.254: PR98.1 203.83,96.27 v1(202.99,95.43) 202.85,95.29 202.18,95.29
51624_IMON: length 5
  BOTTOM w0.178: PU7.13 199.82,99.31 200.2,99.69 201.25,99.69 PR89.1
  BOTTOM w0.254: PR89.1 201.73,100.18 202.11,100.18 v1(202.28,100.35) 202.67,100.74 PC71.1
51624_MODE: length 4.8
  TOP w0.254: v2(196.26,94.17) 196.03,94.4 196.03,96.33 v1(196.11,96.42) 196.61,96.42 PR7.2
  BOTTOM w0.178: PU7.4 196.98,96.09
  BOTTOM w0.254: 196.98,96.09 196.44,96.09 v1(196.11,96.42)
51624_O-USR: length 6.2
  BOTTOM w0.178: PU7.9 198.22,98.96
  BOTTOM w0.254: PR76.2 197.34,102.63 197.69,102.28 197.69,101.14 PR85.1 196.94,100.39 196.94,100.29 196.95,100.28 196.95,99.67 v1(196.81,99.53) 197.22,99.13 198.05,99.13 198.22,98.96
51624_OCP-I: length 5.1
  BOTTOM w0.178: 199.51,99.65 199.42,99.56 PU7.12 ; 199.51,99.65 200.15,100.3 PR88.2 ; 199.51,99.65 v1(199.51,99.65)
  BOTTOM w0.254: PR81.1 PR89.2 200.75,100.64 PR88.2
51624_PWM1: length 25.2
  TOP w0.191: 183.48,100.14 183.68,99.94 PU1.8
  TOP w0.254: v1(182.69,100.4) 182.95,100.14 183.48,100.14
  BOTTOM w0.178: PU7.6 196.99,96.89 196.34,97.54 195.6,97.54
  BOTTOM w0.254: v1(182.69,100.4) v2(182.69,102.17) 184.09,103.57 193.49,103.57 194.12,102.94 194.12,97.22 194.42,96.93 194.97,96.93 194.98,96.92 195.6,97.54
51624_PWM2: length 2.6
  TOP w0.254: PR6.1 196.66,97.6 v1(196.11,97.05)
  BOTTOM w0.178: v1(196.11,97.05) 196.32,97.05 196.88,96.49 PU7.5
51624_SKIP#: length 20.8
  TOP w0.191: 183.58,96.21 183.68,96.31 PU1.1
  TOP w0.254: 183.58,96.21 183.21,96.21 183.07,96.34 v1(183.07,96.59)
  IN1 w0.254: v1(183.07,96.59) 183.07,96.34 184.52,94.89 184.57,94.86 184.69,94.74 193.42,94.74 194.06,95.38 194.06,96.65 194.36,96.95 195.12,96.95 195.45,97.28 195.45,97.66 v1(196.34,98.55)
  BOTTOM w0.178: PR95.1 196.34,98.04 197.09,97.29 PU7.7
  BOTTOM w0.254: PR95.1 196.34,98.54 v1(196.34,98.55)
51624_SLEWA: length 4
  TOP w0.254: PR4.1 PR3.2 v1(201.52,99.16) v2(201.01,98.64)
  BOTTOM w0.178: v1(201.52,99.16) 201.04,99.16 200.62,98.74 PU7.15
51624_THERM: length 20.3
  TOP w0.254: v1(200.41,99.19) PR2.2 199.42,100.3 PC2.1 198.37,101.35 v2(197.58,101.35) 196.47,101.35 195.63,100.51 195.63,94.13 194.44,92.94 194.44,89.53 194.05,89.15 193.8,89.15 PR11.1
  BOTTOM w0.178: PU7.14 200.22,99 v1(200.41,99.19)
51624_V5A: length 4.8
  TOP w0.381: PC8.1 199.77,94.16 v1(199.77,93.22) 199.77,92.56 PR9.1 199.9,92.25 v2(198.8,91.15)
  BOTTOM w0.178: v1(199.77,93.22) 199.82,93.27 PU7.28
51624_VBAT: length 5.1
  BOTTOM w0.178: PU7.16 201.72,98.29
  BOTTOM w0.254: PR82.2 203.95,101.34 202.76,100.15 202.76,100.15 202.3,99.69 v1(202.3,98.87) 201.72,98.29
51624_VDD: length 5
  TOP w0.508: PC7.1 196.78,95.17 v1(196.55,94.94)
  BOTTOM w0.178: PU7.2 196.9,95.29 v1(196.55,94.94)
  BOTTOM w0.508: v1(196.55,94.94) 196.55,94.21 PR105.1 195.81,92.61 v2(195.49,92.29)
51624_VFB: length 4.3
  BOTTOM w0.178: PU7.24 202.18,94.89
  BOTTOM w0.254: 202.18,94.89 203.2,94.89 203.45,95.15 PR100.1 203.95,94.5 204.14,94.31 v1(205.04,94.31)
51624_VREF: length 46.2
  TOP w0.254: v1(202.82,103) v2(202.15,102.33) 201.52,101.7 PR3.1 ; v1(196.55,101.95) 196.55,101.93 195.28,100.66 195.28,94.28 194.08,93.09 194.08,89.68 193.9,89.5 193.72,89.5 PR11.2 ; v1(200.41,93.22) 200.8,93.22 PC9.1
  IN1 w0.254: v1(202.82,103) 203.07,103 203.77,102.3 203.77,101.85 204.28,101.35 205.61,101.35 206.12,100.84 206.12,100.03 207.39,98.76 207.39,94.87 206.5,93.98 201.17,93.98 v1(200.41,93.22)
  BOTTOM w0.178: PU7.27 200.22,93.41
  BOTTOM w0.254: 200.22,93.41 v1(200.41,93.22) 200.52,93.22 PR107.1 ; v1(196.55,101.95) 196.55,102.95 197.01,103.41 PR76.1 198.12,103.41 PR77.1 199.21,103.44 PR78.1 199.41,103.63 202.18,103.63 v1(202.82,103)
51624_VRON: length 7.9
  BOTTOM w0.178: PU7.8 197.2,97.69 196.98,97.92
  BOTTOM w0.254: v2(195.87,103.19) 195.94,103.13 PR84.2 195.16,101.31 PR83.2 195.06,101.17 PR90.2 195.51,99.63 195.51,99.39 PR92.1 196.6,99.06 196.98,98.68 196.98,97.92
51716_VIN: length 1
  BOTTOM w0.508: v4(194.56,71.96) 194.94,72.34 PC91.1
  vias: v2(193,72.13) v2(197.2,72.23)
+DDR_VTT_RUN: length 21.8
  TOP w0.203: 192.15,57.66 193.04,58.55 194.06,58.55 194.48,58.97 PU4.1
  TOP w0.508: R207.1 R211.1 R215.1 144.51,35.18 145.16,34.54 145.16,33.6 146.34,32.42 C102.1 146.55,31.7 146.56,31.7 v1(146.56,28.55) ; 108.2,29.21 108.2,31.05 C107.1 108.33,32.16 108.33,33.66 108.09,33.91 R216.1 R212.1 R209.1
  vias: v1(89.21,28.02) v1(91.44,28.19) v1(92.08,28.19) v1(92.71,28.19) v1(93.86,28.19) v1(95,28.19) v1(96.15,28.19) v1(97.28,28.19) v1(98.43,28.19) v1(99.44,28.19) v1(100.46,28.19) v1(101.48,28.12) v1(102.5,28.12) v1(103.51,28.12) v1(104.53,28.12) v1(105.54,28.12) v1(106.56,28.12) v1(107.58,28.12) v1(110.07,28.12) v1(111.08,28.12) v1(112.23,28.12) v1(113.37,28.12) v1(114.51,28.12) v1(115.65,28.12) v1(118.7,27.94) v1(119.72,27.94) v1(120.73,27.94) v1(121.75,27.94) v1(122.77,27.94) v1(123.78,27.94) v1(129.26,28.35) v1(129.97,28.32) v1(130.68,28.32) v1(131.82,28.4) v1(132.97,28.32) v1(134.26,28.32) v1(135.25,28.32) v1(136.27,28.32) v1(137.28,28.32) v1(138.3,28.32) v1(139.32,28.32) v1(140.33,28.32) v1(141.35,28.32) v1(142.36,28.32) v1(143.38,28.32) v1(145.54,28.32) v1(147.19,28.32) v1(148.21,28.32) v1(149.35,28.32) v1(150.49,28.32) v1(151.63,28.32) v1(152.78,28.32) v1(153.79,28.32) v1(154.81,28.32) v1(155.83,28.32) v1(156.84,28.32) v1(157.86,28.32) v1(158.87,28.32) v1(159.89,28.32) v1(160.91,28.32) v1(161.92,28.32) v1(162.69,28.32) v2(139.36,26.66) v2(166.11,29) v2(170.07,48.45) v2(174.28,57.98) v2(183.96,57.6) v2(189.22,56.61) v4(169.55,54.23) v4(170.18,54.61) v4(170.18,53.85) v4(191.39,56.64) v4(192.02,57.02) v4(192.02,56.26) v4(195.25,58.17) v4(195.25,57.4)
+M_VREF_CA: length 46.9
  TOP w0.254: U6.AP49 128.16,67.73 v1(128.44,67.73)
  BOTTOM w1.016: 142.62,70.74 149.48,70.74 153.29,66.93 v2(153.29,62.98) 153.29,54.36 157.73,49.91 162.94,49.91 v2(164.45,48.4) 166.62,46.23 166.62,41.4
  vias: v2(129.84,71.16) v2(132.35,71.06)
+M_VREF_DQ0: length 25.5
  TOP w0.254: U6.AR51 129.31,66.93 v1(129.36,66.93)
  BOTTOM w1.016: v1(129.36,66.93) 130.45,65.84 130.45,65.3 132.21,63.55 132.21,62.61 132.74,62.08 132.74,58.88 133.68,57.94 v2(139.18,57.94) v2(144.06,57.94) 145.95,57.94 147.17,56.72 147.17,56.59
+M_VREF_DQ1: length 23.5
  TOP w0.254: U6.AP51 129.36,68.36 v1(129.36,68.91)
  IN1 w0.508: v1(129.36,68.91) 129.74,68.91 130.15,69.32 130.15,71.07 129.62,71.6 124,71.6 123.01,72.59 115.77,72.59 114.3,71.12 113.24,71.12 112.34,70.23 v1(112.14,70.23)
  vias: v2(111.45,58.26)
+PCH_VCCDSW: length 4
  TOP w0.305: U6.AG20 109.49,72.02 v1(109.12,71.65) 109.09,71.65 U6.AG19
  BOTTOM w0.508: v1(109.12,71.65) 109.17,71.65 109.43,71.91 C228.1 109.73,71.9 109.73,71.9 110,71.63 109.97,71.61 v1(109.97,70.96) 110.51,70.96 C231.1
+SM_VREF_CA: length 132.2
  TOP w0.305: v6(135.11,35.45) 135.43,35.77 U13.H4 ; v6(97.49,35.45) 97.81,35.77 U11.H4 ; U12.H4 116.62,35.77 v6(116.95,35.45) ; v6(153.91,35.45) 154.24,35.78 U14.H4
  TOP w0.508: v1(143.76,31.92) 144.15,32.31 C104.1 C105.1 ; C109.1 125.72,31.25 C106.1 v1(124.68,31.41) v1(123.91,32.18)
  IN1 w0.381: 116.95,35.05 v6(116.95,35.45)
  IN1 w0.508: 117.6,31.88 117.64,31.92 117.64,33.41 116.95,34.11 116.95,35.05 ; v6(97.49,35.45) 97.6,35.45 98.6,34.44 98.6,33.48 100.61,31.47
  IN1 w1.016: 116.07,29.21 103.5,29.21 101.24,31.47 100.61,31.47 ; 116.07,29.21 116.07,31.1 116.84,31.88 123.61,31.88 v1(123.91,32.18) ; 116.07,29.21 118.62,29.21 119,28.83 124.93,28.83 126.33,27.43 132.93,27.43 134.58,25.78 142.75,25.78 v1(144.27,27.3) 147.07,27.3 148.21,26.16 161.77,26.16 164.84,29.23 164.84,34.09
  IN2 w0.381: v6(153.91,35.45) 154.03,35.45 154.53,34.95 154.53,34.54
  IN2 w0.508: 154.53,34.54 154.53,34.14 154.71,33.96 154.71,33.58 153.62,32.49 149.58,32.49 148.84,31.75 143.93,31.75 v1(143.76,31.92) 142.58,33.1 139.27,33.1 138.89,33.48 138.89,34.09 138.61,34.37 136.52,34.37 135.43,35.45 v6(135.11,35.45)
  IN2 w1.016: v1(144.27,27.3) 144.27,29.21 143.26,30.23 143.26,31.42 v1(143.76,31.92)
  BOTTOM w0.508: v6(97.49,35.45) 97.64,35.61 C340.1 C349.1
  vias: v1(164.08,35.99) v1(164.08,34.84) v1(165.23,39.04) v1(166.29,39.04)
+SM_VREF_DQA: length 40.6
  TOP w0.254: v6(154.57,41.85) 154.89,41.53 U14.J11
  TOP w0.305: U13.J11 136.08,41.53 v6(135.76,41.85)
  BOTTOM w0.508: v6(154.57,41.85) 154.59,41.83 C298.1 C288.1 ; C288.1 154.69,43.44 154.69,44.32 154.31,44.7 137.62,44.7 136.36,43.45 C287.1 C297.1 135.78,41.83 v6(135.76,41.85) ; C288.1 155.32,43.14 155.32,46.1 153.59,47.83 v2(153.59,48.58) 153.59,49.73 v2(151.71,51.62) 149.72,53.6 C262.1
+SM_VREF_DQB: length 42.8
  TOP w0.254: v6(98.14,41.85) 98.46,41.53 U11.J11
  TOP w0.305: U12.J11 117.27,41.53 v6(116.95,41.85)
  BOTTOM w0.508: 100.39,45.14 v2(99.71,44.47) 98.73,43.48 C281.1 C295.1 98.16,41.83 v6(98.14,41.85) ; 100.39,45.14 99.87,45.65 99.87,46.61 100.51,47.24 103.38,47.24 109.04,52.91 109.04,54.36 109.79,55.1 R476.1 ; 100.39,45.14 116.4,45.14 117.55,43.99 C283.1 C296.1 116.97,41.83 v6(116.95,41.85)
+TPVDD: length 53.1
  TOP w0.508: R784.1 v1(57.21,4.9)
  IN1 w0.508: 34.42,11.56 34.04,11.18 v1(32,11.18) ; 39.62,16.76 40,16.38 40,15.49 39.27,14.76 v1(39.27,14.38)
  IN1 w1.016: 34.42,9.02 34.42,11.56 35.56,12.7 35.56,13.97 37.34,15.75 37.34,16.87 38.01,17.54 38.82,17.54 39.6,16.76 40.95,16.76 41.39,16.32 v1(41.39,15.88)
  IN2 w0.508: v1(57.21,4.9) 56.71,4.9 55.67,3.85 36.54,3.85 34.66,5.73 v4(34.66,8.09)
  BOTTOM w0.508: R575.2 33.02,12.06 32.76,11.8 R580.2 32.13,11.05 v1(32,11.18) ; v1(39.27,14.38) 38.24,13.34 R576.2 ; v1(41.39,15.88) R569.1 R568.1
  vias: v2(29.25,8.19) v2(32.68,8.22) v4(33.8,8.09)
AC_PROTECT: length 136.2
  IN2 w0.114: v1(51.45,14.49) 51.45,14.9 56.53,19.98 67.1,19.98 68.14,21.02 v1(77.43,21.02)
  IN3 w0.102: v1(151.68,15.05) 149.49,15.05 149.21,15.33 145.99,15.33 144.18,13.51 131,13.51 130.43,12.94 121.15,12.94 115.27,18.82 93.23,18.82 92.41,18.01 85.93,18.01 85.54,17.62 81.12,17.62 77.72,21.02 v1(77.43,21.02) ; v1(51.45,14.49) 50.82,14.49 43.22,22.09 43.22,26.76 44.03,27.57 44.03,29.02 43.13,29.93 43.13,32.04 44.27,33.18 v1(45.67,33.18)
  BOTTOM w0.102: U23.85 45.68,33.17 v1(45.67,33.18) ; PR176.1 151.45,14.87 v1(151.68,15.05)
ACIN: length 121.7
  IN3 w0.102: v1(152.93,13.36) 152.4,12.83 131.57,12.83 131.08,12.33 120.81,12.33 115.04,18.1 95.23,18.1 93.32,16.2 78.93,16.2 76.22,18.91 75.72,18.91 74.49,20.14 74.49,21.51 72.45,23.55 49.94,23.55 48.36,25.12 48.36,27.91 v3(49.28,28.83)
  BOTTOM w0.102: v1(152.93,13.36) 152.93,13.77 153.14,13.97 PR155.1 153.41,13.34 153.54,13.21 PQ37.3 ; v3(49.28,28.83) 48.42,27.97 U23.72
ACPRESENT: length 132.1
  IN3 w0.254: v1(148.34,22.73) 147.52,21.92 133.86,21.92 132.91,22.88 132.88,22.88 132.81,22.95 88.55,22.95 86.29,25.21 84.95,25.21 83.97,26.19 83.97,27.86 82.72,29.12 82.72,36.21 82.45,36.48 82.45,37.01 81.23,38.23 81.23,41.2 80.9,41.53 80.9,43.05 81.41,43.56 81.41,45.21 80.64,45.97 80.64,48.87 81.25,49.48 81.25,54.64 79.88,56.01 79.88,59.69 79.27,60.3 79.27,64.67 v1(80.41,65.8)
  BOTTOM w0.254: R416.1 83.87,69.1 83.6,68.82 83.6,68.59 82.72,67.72 81.92,67.72 80.64,66.44 80.64,66.05 80.44,65.85 80.44,65.84 v1(80.41,65.8) ; PR161.1 154.17,9.52 PR165.2 153.66,9.03 153.54,9.14 153.54,9.78 152.63,10.69 152.63,12.52 152.37,12.78 v2(152.37,15.05) 152.37,18.69 v1(148.34,22.73)
AMP_MUTE#: length 32.1
  TOP w0.102: v1(44.87,15.15) 44.58,14.86 D15.1
  IN1 w0.114: v1(44.87,15.15) 45.49,15.77 45.49,23.09 47.47,25.07 47.47,29.96 49.8,32.28 53.14,32.28 v1(53.56,31.87)
  BOTTOM w0.102: v1(53.56,31.87) 53.56,36.84 53.19,37.21 U23.108
APS1: length 6.1
  TOP w0.102: v2(41.16,42.92) 40.12,42.92 R198.2 R195.2 40.11,44.73 v1(39.88,44.96)
  BOTTOM w0.102: v1(39.88,44.96) 39.37,44.96 38.54,44.13 CN11.1
APS2: length 2.9
  BOTTOM w0.102: R500.2 37.85,45.03 38.04,44.83 v2(38.04,44.29) CN11.2
APS3: length 6.1
  TOP w0.102: v2(36.82,45.43) 36.87,45.43 v1(37.34,44.96) 37.44,44.86 R194.2 R197.2 R198.1
  BOTTOM w0.102: CN11.3 37.54,44.76 v1(37.34,44.96)
APS4: length 5.1
  BOTTOM w0.102: v2(37.3,47.74) 37.3,46.12 36.9,45.71 R499.2 36.83,44.07 37.04,43.86 CN11.4
APS5: length 5.4
  BOTTOM w0.102: CN11.5 36.54,45.12 35.95,45.71 R498.2 35.7,45.71 35.3,46.12 v2(35.3,47.72)
APS6: length 3.3
  BOTTOM w0.102: R497.2 35.45,45.06 35.45,44.54 v2(35.83,44.16) 36.04,43.95 CN11.6
APS7: length 5.1
  TOP w0.102: R197.1 R196.2 34.35,42.93 34.13,43.14 34.13,43.91 v2(34.2,43.98) 34.33,44.11 35.01,44.11 v1(35.05,44.07)
  BOTTOM w0.102: v1(35.05,44.07) 35.54,43.58 CN11.7
APS9: length 3.2
  BOTTOM w0.102: CN11.9 34.54,44.55 v2(34.64,44.64) 34.64,44.86 R496.2
APS11: length 3.1
  BOTTOM w0.102: R495.2 32.77,45.25 v2(33.34,44.67) 33.54,44.48 CN11.11
APS13: length 3.1
  BOTTOM w0.102: R494.2 31.75,44.68 v2(32.02,44.41) 32.54,43.89 CN11.13
APS15: length 3.1
  BOTTOM w0.102: R493.2 v2(30.73,44.67) 30.73,44.57 31.54,43.76 CN11.15
APWORK: length 163.3
  TOP w0.102: v1(123.44,100.63) v2(122.7,99.88) 122.43,99.61 122.43,98.21 R9.1
  IN1 w0.114: v1(48.41,40.77) 48.97,41.33 52.12,41.33 52.76,40.69 54.13,40.69 54.58,41.15 61.32,41.15 61.58,41.41 64.1,41.41 64.94,40.56 71.5,40.56 77.85,46.91 79.38,46.91 79.81,47.35 79.81,52.54 81.39,54.12 81.39,54.74 82.14,55.49 82.14,57.56 81.39,58.31 81.39,63.9 79.97,65.32 79.97,66.74 80.18,66.95 80.18,68.62 80.85,69.3 80.85,71.65 81.58,72.38 82.41,72.38 83.57,73.53 v1(83.57,74.17)
  IN3 w0.102: v1(75.79,77.34) 76.07,77.34 76.66,77.93 76.66,78.81 77.29,79.44 77.29,81.1 78.49,82.3 78.49,85.85 81.22,88.59 v1(81.22,89.22)
  BOTTOM w0.102: U23.68 48.01,26.37 49.66,28.02 51.05,28.02 51.61,28.58 51.61,36.03 49.8,37.85 48.51,37.85 48.11,38.24 48.11,40.46 v1(48.41,40.77) ; v1(83.57,74.17) 83,74.74 R394.2 82.8,74.86 82.49,74.55 81.81,74.55 81.36,74.09 78.61,74.09 75.82,76.89 75.82,77.32 v1(75.79,77.34) ; v1(123.44,100.63) 123.44,100.66 121.54,102.57 99.51,102.57 97.66,100.71 91.31,100.71 81.22,90.62 v1(81.22,89.22)
APWROK_R: length 21.8
  TOP w0.102: v1(100.64,75.24) 100.64,74.94 U6.AB5
  BOTTOM w0.102: R393.1 82.11,75.5 82.61,75.5 82.74,75.64 R394.1 83.13,75.5 84,75.5 R395.1 84.14,75.94 84.58,76.38 86.3,76.38 86.56,76.11 87.04,76.11 87.49,76.57 v2(88.13,76.57) 90.56,76.57 92.64,74.49 94.71,74.49 95.57,75.35 97.83,75.35 98.04,75.13 100.09,75.13 100.2,75.24 v1(100.64,75.24)
BAT-V: length 39.3
  BOTTOM w0.254: PR159.2 122.42,12.24 118.6,12.24 116.84,10.48 116.84,5.26 119.59,2.51 139.44,2.51 140.1,3.17 141.98,3.17 PR174.2
  vias: v2(111.62,17.03) v2(118.18,18.23)
BATLED0#: length 38.6
  TOP w0.102: v2(47.11,9.82) 47.26,9.82 v1(47.72,9.36)
  IN1 w0.114: v1(49.45,25.48) 49.45,24.31 46.48,21.34 46.48,10.6 v1(47.72,9.36)
  BOTTOM w0.102: v1(49.45,25.48) 50.01,25.48 50.62,26.09 61.55,26.09 61.84,26.37 U23.29 ; CN18.6 51.45,7.41 51.04,7 50.44,7 50.02,7.42 49.66,7.42 v1(47.72,9.36)
BATLED1#: length 39.4
  TOP w0.102: v1(48.38,9.36) 48.91,9.9 v2(49.04,9.9)
  IN1 w0.114: v1(49.83,26.62) 50.04,26.42 50.04,24.13 46.74,20.83 46.74,11 v1(48.38,9.36)
  BOTTOM w0.102: v1(48.38,9.36) 50.54,7.2 50.94,7.2 51.17,7.43 51.17,7.97 50.95,8.19 CN18.7 ; v1(49.83,26.62) 49.96,26.49 57.83,26.49 59.66,28.32 61.47,28.32 61.82,27.97 U23.25
BC_CEN: length 19
  IN1 w0.114: v1(18.36,49.1) 18.14,49.33 18.14,56.74 19.68,58.29 19.68,59.66 v1(19.2,60.15)
  BOTTOM w0.102: v2(18.43,59.52) 18.43,59.57 19,60.15 v1(19.2,60.15) 19.43,60.38 U17.1 ; U21.2 19.18,50.93 19.02,50.77 19.02,50.08 19.26,49.83 19.74,49.83 20.18,49.39 R490.2 18.44,49.02 v1(18.36,49.1)
BKLEN: length 19.9
  TOP w0.102: R341.1 R340.1 26.56,85.09 R331.2 26.83,85.7 v1(26.15,86.38) ; Q5.5 20.07,95.4 v1(20.23,95.57)
  IN2 w0.114: v1(21.99,96.13) 23.66,96.13 24.68,95.11 24.68,89.63 26.15,88.15 v1(26.15,86.38)
  BOTTOM w0.102: v1(20.23,95.57) 20.79,96.13 v1(21.99,96.13)
BL#: length 6
  TOP w0.102: v2(18.66,91.18) 18.95,91.18 R40.1 19.89,90.64 20.07,90.82 Q5.2 20.07,92.91 20.18,93.03 20.59,93.03 20.72,92.9 Q5.3
BOARD_ID0: length 19.5
  TOP w0.076: 97.23,78.97 98.06,78.97 U6.P1
  TOP w0.102: 97.23,78.97 97.09,79.11 96.58,79.11 96.44,78.97 95.6,78.97 95.48,79.09 95.17,79.09 92.35,81.91 88.23,81.91 87.72,82.41 87.43,82.41 86.93,82.92 86.91,82.92 86.68,83.15 84.61,83.15 84.2,82.74 R71.2 83.37,83.15 81.5,83.15 R70.2
BOARD_ID1: length 22.4
  TOP w0.102: v1(100.57,79.07) 100.82,78.82 U6.R5
  BOTTOM w0.102: v1(100.57,79.07) 100.32,78.81 98.95,78.81 98.67,79.09 94.68,79.09 93.56,80.21 88.47,80.21 87.85,80.84 v1(86.98,80.84) 86.43,80.84 85.95,81.32 84.97,81.32 84.72,81.56 83.94,81.56 R364.2 83.77,81.58 83.51,81.32 82.57,81.32 82.34,81.55 81.4,81.55 81.1,81.85 R362.2
BOARD_ID2: length 23.6
  TOP w0.076: 97.82,79.89 98.8,79.89 98.91,79.99 99.82,79.99 U6.L4
  TOP w0.102: 97.82,79.89 97.76,79.94 97.05,79.94 96.32,80.66 94.74,80.66 92.46,82.95 90.36,82.95 89.55,83.76 R66.2 88.7,84.17 82.19,84.17 81.79,83.76 R63.2 81.07,83.76 80.48,83.17 79.64,83.17 v1(79.09,83.73)
BOARD_ID3: length 12.1
  TOP w0.102: R23.2 100.89,92.75 100.15,92.75 99.3,91.9 99.3,87.67 99.73,87.24 99.73,86.48 99.8,86.41 99.8,86.02 99.97,85.85 99.99,85.85 U6.C4 ; R23.2 R22.2 ; R23.2 102.2,93.12 v1(102.2,92.62)
BOARD_ID4: length 21.7
  TOP w0.076: U6.L3 99.16,80.63 97.91,80.63 97.82,80.55
  TOP w0.102: R60.2 R58.2 81.78,85.79 v1(82.06,85.51) 82.39,85.18 88.99,85.18 90.6,83.57 92.7,83.57 95,81.27 96.57,81.27 97.3,80.55 97.82,80.55
BT_EN: length 184.1
  IN1 w0.114: v3(52.7,36.04) 54.05,34.7 59.18,34.7 59.83,35.35 62.19,35.35 63.03,34.51 64.48,34.51 65.18,35.2 78.05,35.2 80.44,32.81 80.44,30.05 81.91,28.57 83.71,28.57 88.46,23.82 131.79,23.82 133.61,22 169.81,22 173.12,25.31 173.12,40.65 178.58,46.11 178.58,52.54 184.48,58.44 184.48,65.23 185.93,66.67 185.93,67.41 v1(186.36,67.84)
  BOTTOM w0.102: v1(186.36,67.84) 185.93,67.41 CN9.54 ; U23.104 51.59,37.87 52.7,36.76 v3(52.7,36.04)
CATERR#: length 10.9
  TOP w0.102: v1(137.97,81.88) 138.17,81.88 138.51,82.22 138.95,82.22 139.19,82.46 139.19,82.8 140.72,84.33 142.75,84.33 TP10.1 ; v1(135.17,80.76) 135.51,81.11 U6.K61
  IN3 w0.102: v1(135.17,80.76) 135.57,81.16 135.87,81.16 137,82.29 137.57,82.29 v1(137.97,81.88)
CFG0: length 55.1
  TOP w0.076: U6.AC60 135.17,74.04 136.27,74.04 136.47,74.24 136.47,74.5 136.66,74.68 136.94,74.68 137.07,74.55
  TOP w0.102: v1(152.16,86.32) 152.4,86.07 152.4,77.98 v1(152.23,77.82) 152.23,77.28 R106.2 151.15,76.2 147.52,76.2 146.07,74.75 145.9,74.75 141.94,74.75 141.61,74.42 139.33,74.42 139.2,74.55 137.9,74.55 137.8,74.45 137.18,74.45 137.07,74.55 ; CN1.35 v1(172.25,94.53)
  IN1 w0.114: v1(152.16,86.32) 152.36,86.12 158.47,86.12 160.59,88.24 160.59,89.54 166.29,95.24 171.54,95.24 v1(172.25,94.53)
CFG1: length 52.9
  TOP w0.076: U6.AC62 136.16,74.46 136.55,74.85 137.12,74.85 137.29,74.68
  TOP w0.102: CN1.36 171.76,94.67 v1(171.58,94.49) ; 137.29,74.68 137.33,74.64 137.72,74.64 137.82,74.74 139.2,74.74 139.42,74.96 145.98,74.96 147.43,76.4 148.42,76.4 R105.2 149.32,77.31 151.15,77.31 152.2,78.36 152.2,84.87 v2(151.68,85.38) 151.51,85.55 v1(151.51,86.32)
  IN1 w0.114: v1(171.58,94.49) 171.58,94.57 171.14,95.02 166.39,95.02 160.82,89.45 160.82,88.14 158.57,85.89 151.94,85.89 v1(151.51,86.32)
CFG2: length 56.8
  TOP w0.102: v1(138.09,74.14) 137.98,74.26 136.95,74.26 U6.AC63 ; v1(171.58,93.85) 171.07,94.36 171.07,94.61 170.76,94.93 CN1.38
  IN1 w0.114: v1(138.09,74.14) 137.89,74.34 134.96,74.34 133.35,75.95 133.35,76.34 133.86,76.85 133.86,78.06 136.4,80.6 139.5,80.6 141.24,82.34 146.88,82.34 149.74,85.2 158.85,85.2 161.51,87.86 161.51,89.16 165.81,93.47 171.2,93.47 v1(171.58,93.85)
CFG3: length 50.7
  TOP w0.102: U6.AA63 136.93,75.02 137.24,75.02 137.34,74.93 139.12,74.93 139.35,75.16 145.31,75.16 v2(145.96,75.81) 146.42,76.26 146.63,76.26 R104.2 147.88,77.51 151.06,77.51 151.99,78.44 151.99,83.88 151.06,84.81 v1(151.06,85.86) ; CN1.39 170.25,94.41 v1(170.43,94.23)
  IN1 w0.114: v1(170.43,94.23) 169.88,94.79 166.48,94.79 161.05,89.35 161.05,88.05 158.66,85.66 151.26,85.66 v1(151.06,85.86)
CFG4: length 51.4
  TOP w0.076: 138.29,75.39 138.27,75.37 137.23,75.37 137.01,75.59 136.3,75.59 136.19,75.49 135.18,75.49 U6.AA60
  TOP w0.102: v1(167.25,94.36) 167.76,94.87 CN1.44 ; 138.29,75.39 138.7,75.79 139.22,75.79 139.65,75.36 144.78,75.36 145.16,75.74 145.16,76.7 R103.2 145.05,77.62 147.7,77.62 147.77,77.69 147.79,77.71 150.98,77.71 151.79,78.53 151.79,83.27 v2(150.94,84.11) 150.46,84.6 v1(150.46,85.63)
  IN1 w0.114: v1(167.25,94.36) 166.38,94.36 161.28,89.26 161.28,87.95 158.76,85.43 150.65,85.43 v1(150.46,85.63)
CFG5: length 49.3
  TOP w0.076: v1(138.05,75.77) 137.64,76.18 136.46,76.18 U6.Y62
  TOP w0.102: v1(167.32,92.54) 166.75,93.12 166.75,94.49 167.25,94.99 CN1.45
  IN1 w0.114: v1(167.32,92.54) 167.75,92.12 167.75,91.72 166.29,90.26 166.29,88.56 166.07,88.34 164.54,88.34 159.8,83.6 150.41,83.6 147.22,80.41 147.22,78.17 146.77,77.72 140.46,77.72 139.96,78.23 137.07,78.23 136.77,77.94 136.77,77.12 138.05,75.84 v1(138.05,75.77)
CFG6: length 47.3
  TOP w0.102: v1(135.19,76.26) 135.51,75.94 U6.Y61 ; v1(166.89,99.02) 166.25,98.39 CN1.47 166.25,94.32 166.47,94.11 v1(166.47,92.54)
  IN1 w0.114: v1(166.47,92.54) 166.9,92.12 166.9,91.71 159.48,84.29 150.13,84.29 145.82,79.98 140.17,79.98 139.87,79.69 137.24,79.69 136.24,78.68 136.24,77.31 v1(135.19,76.26)
CFG7: length 44.4
  TOP w0.102: CN1.48 165.76,92.69 v1(165.61,92.54) ; v1(134.53,76.26) 134.86,75.93 U6.Y60
  IN1 w0.114: v1(165.61,92.54) 165.21,92.54 162.76,90.09 162.76,88.62 159.11,84.98 149.84,84.98 146.97,82.11 141.33,82.11 139.59,80.37 136.52,80.37 134.09,77.94 134.09,76.7 v1(134.53,76.26)
CFG8: length 47.4
  TOP w0.076: 137.61,76.93 136.53,76.93 136.24,76.64 U6.V62
  TOP w0.102: 137.61,76.93 137.77,77.09 138.66,77.09 139.17,77.6 140.52,77.6 v2(140.71,77.41) 140.86,77.56 141.59,77.56 142.32,76.83 142.76,76.83 R100.2 143.95,78.03 147.53,78.03 147.6,78.09 147.6,78.09 147.62,78.12 150.81,78.12 151.38,78.7 151.38,82.3 v1(150.74,82.95) ; CN1.26 172.25,88.93 v1(172.41,88.77)
  IN1 w0.114: v1(150.74,82.95) 151.16,82.52 153.57,82.52 153.58,82.53 160.63,82.53 160.83,82.72 160.83,82.72 165.73,87.62 166.82,87.62 167.32,88.12 171.75,88.12 v1(172.41,88.77)
CFG9: length 48.1
  TOP w0.076: 138.29,76.34 135.84,76.34 U6.V61
  TOP w0.102: v1(171.75,88.77) 171.76,88.77 CN1.25 ; 138.29,76.34 138.57,76.06 140.43,76.06 v2(140.54,75.95) 140.92,75.56 144.15,75.56 R112.2 144.14,76.59 144.14,77.47 144.5,77.83 147.62,77.83 147.68,77.89 147.68,77.89 147.71,77.92 150.89,77.92 151.59,78.61 151.59,82.75 v1(151.38,82.95)
  IN1 w0.114: v1(151.38,82.95) 160.74,82.95 165.63,87.85 166.73,87.85 167.23,88.35 171.33,88.35 v1(171.75,88.77)
CFG10: length 46.2
  TOP w0.076: 137.49,77.16 137.42,77.09 136.02,77.09 135.92,76.99 135.18,76.99 U6.V60
  TOP w0.102: 137.49,77.16 137.67,77.34 138.61,77.34 139.87,78.6 140.5,78.6 v2(140.6,78.7) 140.74,78.84 142.02,78.84 R96.2 142.63,78.23 147.41,78.23 147.5,78.32 150.72,78.32 151.18,78.78 151.18,81.9 v1(150.74,82.32) ; v1(169.55,87.38) 169.55,88.01 170.76,89.22 CN1.23
  IN1 w0.114: v1(169.55,87.38) 169.04,87.88 167.41,87.88 166.92,87.39 165.83,87.39 160.73,82.3 153.67,82.3 153.67,82.3 150.76,82.3 v1(150.74,82.32)
CFG11: length 45.9
  TOP w0.102: v1(168.17,92.53) 168.48,92.84 169.42,92.84 170.25,92 CN1.22 ; v1(134.51,77.76) 134.51,77.7 U6.U60
  IN1 w0.114: v1(134.51,77.76) 135.78,79.03 135.78,79.27 136.66,80.14 139.69,80.14 140.78,81.24 146.42,81.24 149.93,84.75 159.21,84.75 166.05,91.59 166.05,92.74 166.53,93.22 167.49,93.22 v1(168.17,92.53)
CFG12: length 39.6
  TOP w0.102: v1(167.76,88.77) CN1.17 ; v1(138.48,77.81) 138.05,78.23 137.57,78.23 137.54,78.21 136.89,78.21 U6.T63
  IN1 w0.114: v1(167.76,88.77) 167.33,88.77 166.63,88.08 165.54,88.08 160.84,83.38 150.51,83.38 147.45,80.32 147.45,77.85 146.3,76.71 145.96,76.71 145.17,77.5 138.79,77.5 v1(138.48,77.81)
CFG13: length 38.5
  TOP w0.076: 137.46,78.43 136.46,78.43 U6.T62
  TOP w0.102: 137.46,78.43 137.49,78.45 138.58,78.45 v1(139.28,79.15) ; v1(167.32,91.9) 167.25,91.83 CN1.16
  IN1 w0.114: v1(167.32,91.9) 167.32,91.81 159.57,84.06 150.22,84.06 145.92,79.76 140.28,79.76 139.67,79.15 v1(139.28,79.15)
CFG14: length 38.4
  TOP w0.076: 137.36,78.67 137.29,78.59 135.93,78.59 U6.T61
  TOP w0.102: v1(138.63,79.15) 138.2,78.72 137.41,78.72 137.36,78.67 ; v1(165.86,88.77) 166.25,89.17 CN1.14
  IN1 w0.114: v1(165.86,88.77) 164.61,88.77 159.67,83.83 150.32,83.83 146.99,80.51 146.99,78.51 146.69,78.21 143.96,78.21 143.45,78.73 139.06,78.73 v1(138.63,79.15)
CFG15: length 39.9
  TOP w0.102: v1(135.16,77.76) 134.86,78.06 U6.T60 ; v1(166.47,91.9) 166.19,91.9 165.76,91.46 CN1.13
  IN1 w0.114: v1(135.16,77.76) 136.01,78.61 136.01,78.8 137.13,79.91 139.78,79.91 140.87,81.01 146.51,81.01 150.03,84.52 159.3,84.52 166.47,91.69 v1(166.47,91.9)
CFG_RCOMP: length 5.1
  TOP w0.305: 138.87,76.64 U6.V63
  TOP w0.508: 138.87,76.64 141.16,76.64 R111.1
CLK_PCH_PCI3: length 16.1
  TOP w0.076: 104.83,60.2 105.6,60.96 v1(105.69,60.96)
  TOP w0.102: 104.83,60.2 104.83,57.15 R188.2 ; U6.AN15 106.49,68.41 v1(106.92,67.98)
  BOTTOM w0.102: R454.2 106.15,59.55 106.15,60.5 v1(105.69,60.96) 106.15,61.42 106.15,61.8 106.63,62.28 v1(106.63,63.13) 106.63,64.36 105.79,65.2 105.79,66.42 106.5,67.13 106.5,67.56 v1(106.92,67.98)
CLK_PCH_PCI4: length 11.4
  TOP w0.102: U6.AP15 106.51,67.76 v1(106.92,67.35)
  BOTTOM w0.102: R460.2 108.92,58.96 v2(109.33,59.37) 109.78,59.82 109.78,64.49 v1(106.92,67.35)
CLK_PCI_EC: length 59.5
  BOTTOM w0.102: U23.13 63.62,32.77 64.14,32.26 64.89,32.26 R530.2 66.26,32.11 67.49,32.11 72.47,37.08 76.48,37.08 77.75,38.36 79.49,38.36 79.68,38.54 80.06,38.54 82.47,40.94 86.72,40.94 91.4,45.62 96.56,45.62 v2(96.9,45.95) 99,48.06 102.36,48.06 107.21,52.91 107.21,56.04 C258.1 108.14,56.97 R460.1
CLK_PCI_LPC: length 67.9
  TOP w0.102: v1(79.23,38.81) 79.23,29.98 78.79,29.54 78.79,26.52 79.1,26.21 79.1,23.14 v2(80.97,21.27) 84.84,17.4 v1(86.22,17.4)
  BOTTOM w0.102: R454.1 105.97,56.93 C257.1 106.29,56.85 106.63,56.52 106.63,53.15 102.02,48.54 98.8,48.54 96.36,46.1 91.2,46.1 86.52,41.43 82.27,41.43 79.86,39.02 79.44,39.02 v1(79.23,38.81) ; R561.2 86.23,17.41 v1(86.22,17.4) 86.97,17.4 87.57,16.8 CN14.6
CLK_PCI_LPC_C: length 136.7
  IN1 w0.114: v1(189.48,54.48) 188.8,55.17 188.55,55.17 182.23,48.84 182.23,44.6 180.39,42.76 180.39,41.05 179.41,40.07 179.41,36.79 177.17,34.54 177.17,24.18 171.31,18.33 132.11,18.33 130.26,20.17 117.32,20.17 116.6,19.45 95.07,19.45 94.88,19.26 86.66,19.26 v1(86.23,19.68)
  BOTTOM w0.102: v1(189.48,54.48) 189.87,54.86 v2(189.87,55.77) 189.87,57.15 190.18,57.46 CN9.71 ; v1(86.23,19.68) R561.1
CLK_PCI_TPM: length 50.8
  TOP w0.102: U15.21 74.62,34.6 73.66,35.56 v1(73.66,38.61) ; R188.1 105.64,55.57 C72.1 106.06,54.21 106.5,53.77 106.5,52.96 106.05,52.5 v2(104.38,52.5) v1(103.23,52.5)
  BOTTOM w0.102: v1(73.66,38.61) 77.32,38.61 78.22,39.51 79.66,39.51 82.07,41.91 85.31,41.91 89.98,46.58 95.12,46.58 98.3,49.76 100.48,49.76 v1(103.23,52.5)
CLK_PCIE_NGFF0_N: length 135.2
  TOP w0.076: U6.A39 121.41,86.95 121.41,87.27 121.82,87.68 121.82,87.91 121.99,88.08 122.23,88.08 122.4,87.91 v1(122.4,87.71)
  IN3 w0.102: v1(122.4,87.71) 121.97,87.71 121.87,87.81 121.87,88.24 122.03,88.39 123.04,88.39 123.7,89.05 126.05,89.05 126.34,89.34 134.45,89.34 135.66,88.14 138.32,88.14 143.42,83.04 143.42,81.82 144.27,80.98 145.49,80.98 146.46,80.01 146.46,77.72 150.67,73.5 151.96,73.5 172.75,52.71 172.75,48.53 175.92,45.35 175.92,42.09 182.69,35.31 182.69,34.99 185.57,32.11 185.57,24.64 190.63,19.58 190.97,19.58 191.08,19.48 v1(191.08,19.21)
  BOTTOM w0.102: v1(191.08,19.21) 191.08,19.36 190.72,19.73 190.63,19.73 190.44,19.54 190.44,18.68 191.07,18.05 192.14,18.05 198.54,11.65 201.16,11.65 201.69,11.12 206.24,11.12 206.36,11.24 206.36,11.55 206.46,11.65 206.74,11.65 CN13.53
CLK_PCIE_NGFF0_P: length 135.2
  TOP w0.076: v1(121.41,87.85) 121.41,87.51 121.25,87.34 121.25,86.47 U6.B39
  IN3 w0.102: v1(121.41,87.85) 121.62,88.05 121.62,88.34 121.92,88.65 122.94,88.65 123.6,89.31 125.95,89.31 126.24,89.6 134.56,89.6 135.76,88.39 138.43,88.39 143.67,83.15 143.67,81.93 144.37,81.23 145.59,81.23 146.71,80.11 146.71,77.83 150.78,73.76 152.06,73.76 173,52.82 173,48.63 176.17,45.46 176.17,42.19 182.95,35.42 182.95,35.09 185.83,32.21 185.83,24.74 190.73,19.84 190.93,19.84 v1(191.08,19.99)
  BOTTOM w0.076: CN13.55 206.67,10.89
  BOTTOM w0.102: 206.67,10.89 201.6,10.89 201.07,11.42 198.45,11.42 192.05,17.82 190.98,17.82 190.21,18.59 190.21,19.63 190.56,19.99 v1(191.08,19.99)
CLK_PCIE_NGFF1_N: length 122.8
  TOP w0.076: U6.B37 120.42,86.36 120.74,86.68 120.74,86.97 120.65,87.06 120.65,88.16 120.47,88.34 120.03,88.34 v1(119.94,88.43)
  IN3 w0.102: v1(119.94,88.43) 120.21,88.43 120.51,88.72 120.51,89.88 121.83,91.2 135.95,91.2 137.09,90.07 139.32,90.07 148.72,80.67 148.72,79.55 150.29,77.98 151.29,77.98 157.42,71.85 157.42,70.48 172.91,54.99 173.74,54.99 174.27,54.46 174.27,48.41 176.91,45.76 176.91,42.59 183.2,36.3 183.74,36.3 v1(183.9,36.45)
  BOTTOM w0.102: v1(183.9,36.45) 184.31,36.03 185.53,36.03 186.75,37.25 193.36,37.25 v2(193.9,37.8) 194.58,37.12 206.72,37.12 CN10.53
CLK_PCIE_NGFF1_P: length 122.8
  TOP w0.076: U6.A37 120.48,86.88 120.48,88.09 120.4,88.18 120.26,88.18 119.94,87.86 v1(119.94,87.8)
  IN3 w0.102: v1(183.9,35.61) 183.9,35.89 183.74,36.04 183.1,36.04 176.66,42.48 176.66,45.66 174.02,48.3 174.02,54.35 173.63,54.74 172.81,54.74 157.17,70.38 157.17,71.74 151.18,77.72 150.19,77.72 148.46,79.45 148.46,80.57 139.22,89.81 136.98,89.81 135.85,90.95 121.94,90.95 120.76,89.77 120.76,88.62 v1(119.94,87.8)
  BOTTOM w0.076: CN10.55 206.67,36.89
  BOTTOM w0.102: v1(183.9,35.61) 184.09,35.8 185.62,35.8 186.84,37.02 193.41,37.02 v2(193.9,36.53) 194.27,36.89 206.67,36.89
CLK_PCIE_REQ0#: length 15.6
  TOP w0.076: U6.U2 98.54,77.64 98.06,77.64 97.94,77.51 97.25,77.51
  TOP w0.102: R76.1 85.81,81.32 86.17,81.32 86.52,80.97 87.14,80.97 v1(87.39,81.22) 87.76,81.22 87.9,81.08 92.03,81.08 95.65,77.46 96.07,77.46 96.14,77.54 97.22,77.54 97.25,77.51
CLK_PCIE_REQ1#: length 22.5
  TOP w0.076: 96.72,75.21 96.9,75.39 99.23,75.39 99.31,75.47 100.24,75.47 100.48,75.71 U6.Y5
  TOP w0.102: 96.72,75.21 95.14,75.21 95.11,75.17 94.66,75.17 93.93,75.9 93.61,75.9 90.86,78.65 90.37,78.65 v2(90.11,78.92) 89.78,79.25 89.18,79.25 88.57,78.64 87.66,78.64 87.29,78.27 82.58,78.27 82.3,77.98 81.66,77.98 81.23,78.42 R93.1
CLK_PCIE_REQ2#: length 14.2
  TOP w0.102: R99.1 87.26,77.66 87.83,78.23 90.39,78.23 90.4,78.23 90.41,78.23 90.41,78.23 90.71,78.23 93.44,75.5 93.76,75.5 94.51,74.74 95.25,74.74 95.31,74.8 96.06,74.8 97.37,73.49 98.08,73.49 U6.AD1
CLK_PCIE_WLAN_N: length 86.8
  TOP w0.076: U6.B38 120.9,85.92 120.9,86.23 121.08,86.41 121.08,87.18 121.01,87.25 121.01,88.01 121.45,88.46 121.45,88.68 121.88,89.12 v1(121.92,89.12)
  IN3 w0.102: v1(173.53,53.32) 173.53,53.47 173.36,53.64 172.86,53.64 151.06,75.44 150.85,75.44 147.19,79.09 147.19,80.79 139.09,88.9 136.04,88.9 134.86,90.08 122.21,90.08 121.67,89.53 121.67,89.37 v1(121.92,89.12)
  BOTTOM w0.102: v1(173.53,53.32) 173.88,53.67 178.77,53.67 180.09,54.99 181.17,54.99 182.92,56.74 184.25,56.74 184.54,57.03 184.54,57.28 184.68,57.41 CN9.49
CLK_PCIE_WLAN_P: length 86.8
  TOP w0.076: v1(121.29,89.1) 121.29,88.52 120.84,88.08 120.84,87.19 120.92,87.11 120.92,86.48 120.74,86.3 120.74,86.02 120.42,85.7 U6.C37
  IN3 w0.102: v1(121.29,89.1) 121.41,89.22 121.41,89.64 122.1,90.33 134.97,90.33 136.14,89.15 139.19,89.15 147.45,80.9 147.45,79.2 150.95,75.69 151.17,75.69 172.96,53.9 173.33,53.9 v1(173.53,54.1)
  BOTTOM w0.102: CN9.47 184.18,57.41 184.17,57.4 184.31,57.27 184.31,57.13 184.16,56.97 182.83,56.97 181.08,55.22 179.99,55.22 178.67,53.9 173.73,53.9 v1(173.53,54.1)
CLK_PCIE_XDPN: length 70.8
  TOP w0.076: U6.B35 118.75,86.46 118.75,87.18 v1(118.6,87.33)
  TOP w0.102: CN1.10 164.25,89.1 164.39,88.97 164.39,88.14 164.59,87.94 164.59,85.34 159,79.76 159,78.54 v2(158.49,78.02) 159,77.5 v1(159,75.69)
  IN3 w0.102: v1(118.6,87.33) 118.76,87.49 119.12,87.49 119.38,87.76 119.38,88.52 119.95,89.09 119.95,90.34 121.3,91.68 136.68,91.68 137.38,90.98 146.92,90.98 148.77,89.13 148.77,86.38 159,76.15 v1(159,75.69)
CLK_PCIE_XDPP: length 71.6
  TOP w0.076: U6.A35 118.99,86.86 118.99,87.54 v1(118.56,87.98)
  TOP w0.102: CN1.11 164.76,89.1 164.62,88.97 164.62,88.23 164.82,88.03 164.82,85.25 159.23,79.66 159.23,78.54 v2(159.76,78.02) 159.23,77.5 159.23,76.1 v1(159.64,75.69)
  IN3 w0.102: v1(159.64,75.69) 159.26,76.07 159.26,76.25 149.03,86.48 149.03,89.24 147.03,91.24 137.48,91.24 136.78,91.94 121.2,91.94 119.7,90.44 119.7,89.2 119.13,88.62 119.13,87.86 119.01,87.75 118.79,87.75 v1(118.56,87.98)
CLK_SCLK: length 134.3
  TOP w0.102: CN1.57 161.25,97.5 155.79,102.97 92.05,102.97 91.11,102.03 91.11,93.39 v2(91.62,92.88) 91.11,92.37 91.11,91.92 89.03,89.84 79.81,89.84 78.82,88.85 78.82,84.72 77.72,83.63 77.72,78.99 77.83,78.89 77.83,78.64 80.24,76.23 80.24,75.36 v1(80.44,75.16) ; R131.1 85.1,72.25 Q10.4 82.82,72.25 82.68,72.39 82.68,73.91 v1(82.93,74.17)
  IN1 w0.114: v1(79.76,68.46) 79.61,68.31 79.48,68.31 79.25,68.54 79.25,68.92 79.97,69.64 79.97,70.31 80.28,70.62 80.28,71.77 81.53,73.02 82.04,73.02 82.76,73.74 82.76,74 v1(82.93,74.17)
  IN3 w0.102: v1(82.93,74.17) 82.42,74.68 81.87,74.68 81.31,74.11 80.24,74.11 80.12,74.23 80.12,74.84 v1(80.44,75.16)
  BOTTOM w0.102: R422.2 77.38,67.95 77.62,68.2 77.62,68.57 77.86,68.81 78.58,68.81 79.09,68.3 79.6,68.3 v1(79.76,68.46)
CLK_SDATA: length 133.5
  TOP w0.102: CN1.56 161.76,97.32 155.88,103.2 91.95,103.2 90.88,102.13 90.88,93.41 v2(90.35,92.88) 90.88,92.34 90.88,92.02 88.93,90.07 79.71,90.07 78.59,88.94 78.59,84.82 77.5,83.72 77.5,78.9 77.6,78.8 77.6,78.54 80.01,76.13 80.01,75.36 v1(79.81,75.16) ; R121.1 80,73.55 Q10.1 82.34,73.55 82.44,73.65 82.44,73.98 v1(82.28,74.13)
  IN1 w0.114: v1(82.28,74.13) 82.52,73.89 82.52,73.84 81.94,73.27 81.43,73.27 80.04,71.87 80.04,70.72 79.72,70.41 79.72,69.74 79.01,69.02 79.01,68.44 79.38,68.07 79.5,68.07 v1(79.76,67.82)
  IN3 w0.102: v1(79.81,75.16) 79.89,75.07 79.89,74.13 80.14,73.88 81.4,73.88 81.97,74.45 82.09,74.45 82.28,74.26 v1(82.28,74.13)
  BOTTOM w0.102: v1(79.76,67.82) 79.5,68.07 78.99,68.07 78.49,68.58 77.95,68.58 77.85,68.48 77.85,68.07 77.97,67.95 R423.2
CLKRUN#: length 108.1
  TOP w0.102: v1(100.62,77.14) 100.82,76.94 U6.V5 ; R225.1 78.61,34.04 v1(78.49,34.16)
  IN1 w0.114: v1(78.49,34.16) 78.36,34.16 77.6,34.92 65.23,34.92 64.58,34.28 62.84,34.28 62,35.12 59.93,35.12 59.27,34.47 51,34.47 v1(49.15,36.32)
  IN3 w0.102: v1(80.29,77) 80.11,76.81 79.97,76.81 78.51,75.36 78.51,74.11 78.89,73.73 78.89,71.02 78.23,70.36 77.56,70.36 76.87,69.67 76.87,68.28 76.47,67.89 76.47,62.49 77.62,61.34 77.62,60.6 77.09,60.07 77.09,56.44 77.62,55.9 77.62,53.39 77.18,52.95 77.18,50.5 76.48,49.8 76.48,38.48 76.73,38.22 76.73,36.19 78.49,34.44 v1(78.49,34.16)
  BOTTOM w0.102: U23.93 49.1,36.37 v1(49.15,36.32) ; v1(80.29,77) 80.29,78.39 v2(80.22,78.46) 79.9,78.78 79.47,78.78 79.29,78.96 79.29,79.48 79.55,79.75 81.4,79.75 81.9,80.25 82.54,80.25 82.55,80.26 83.2,80.26 R371.2 84.18,79.28 86.35,79.28 87.41,78.22 91.27,78.22 92.34,77.16 95,77.16 95.04,77.11 100.59,77.11 v1(100.62,77.14)
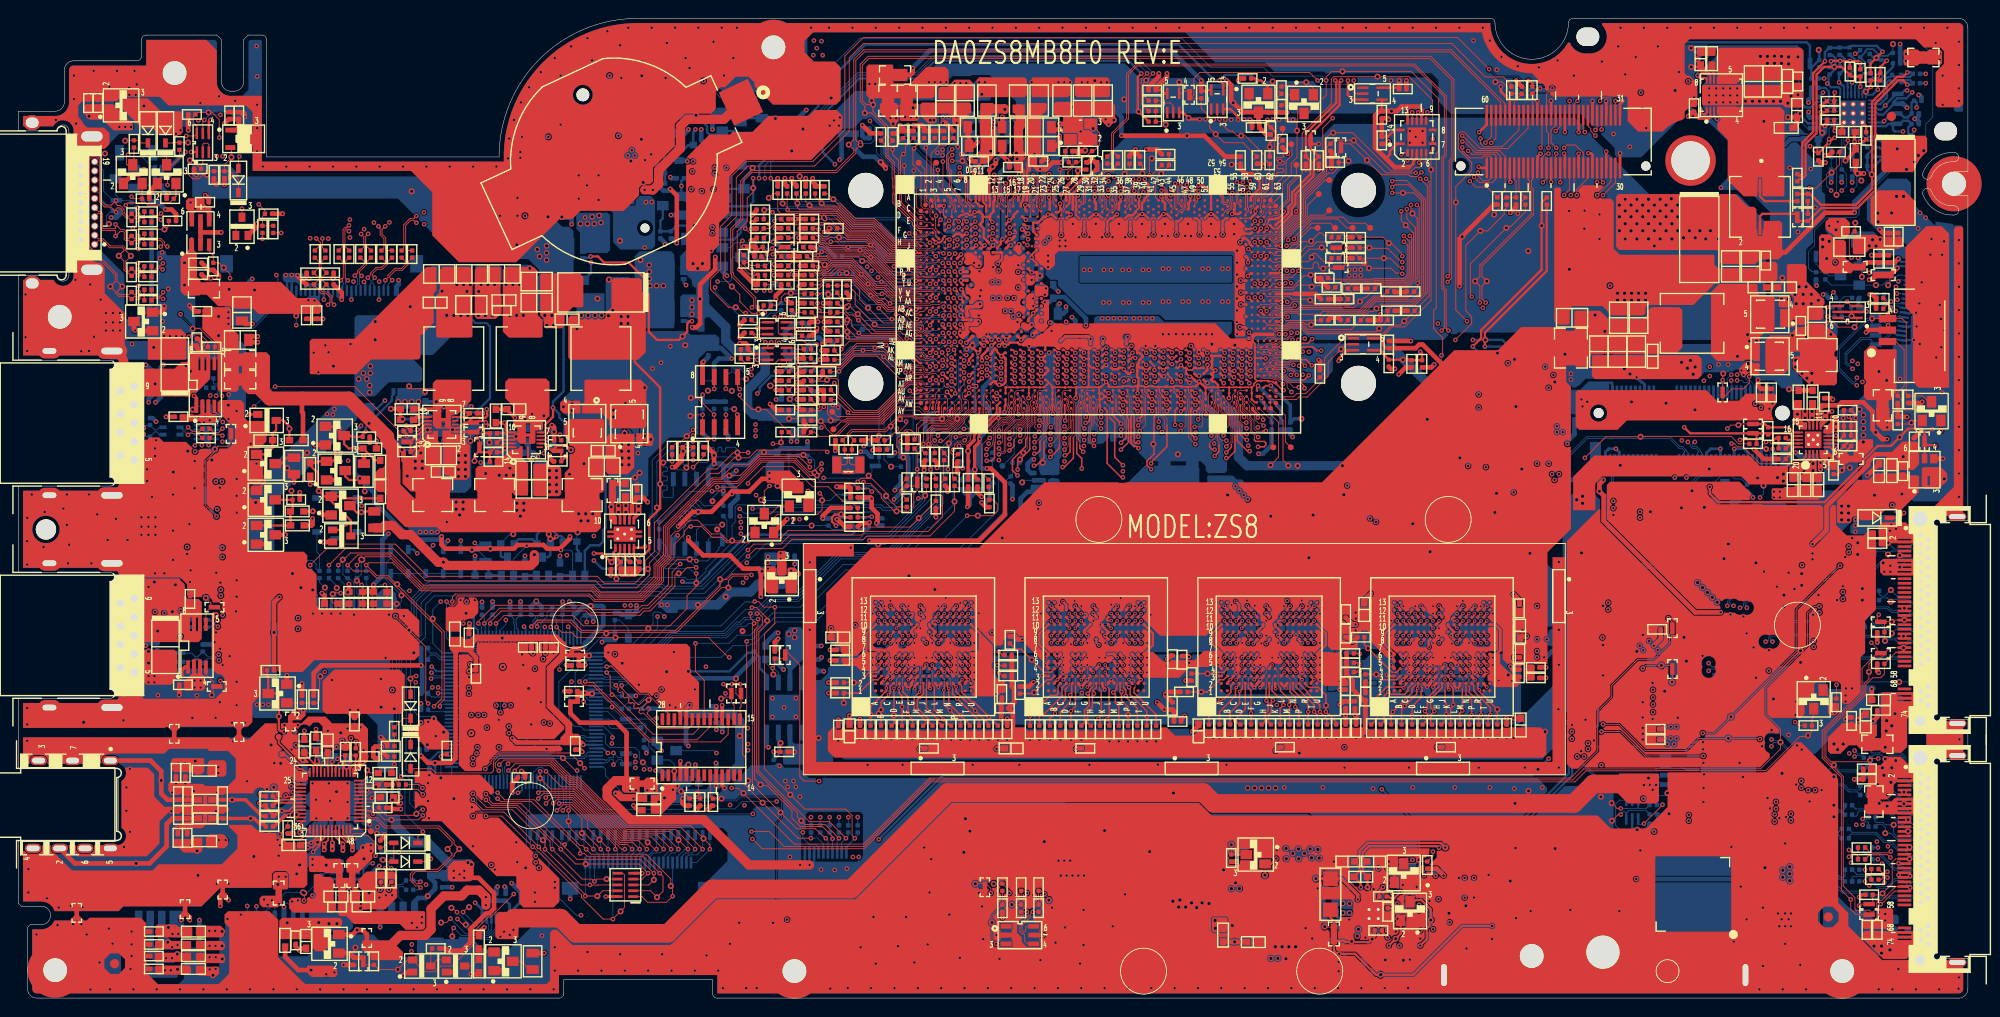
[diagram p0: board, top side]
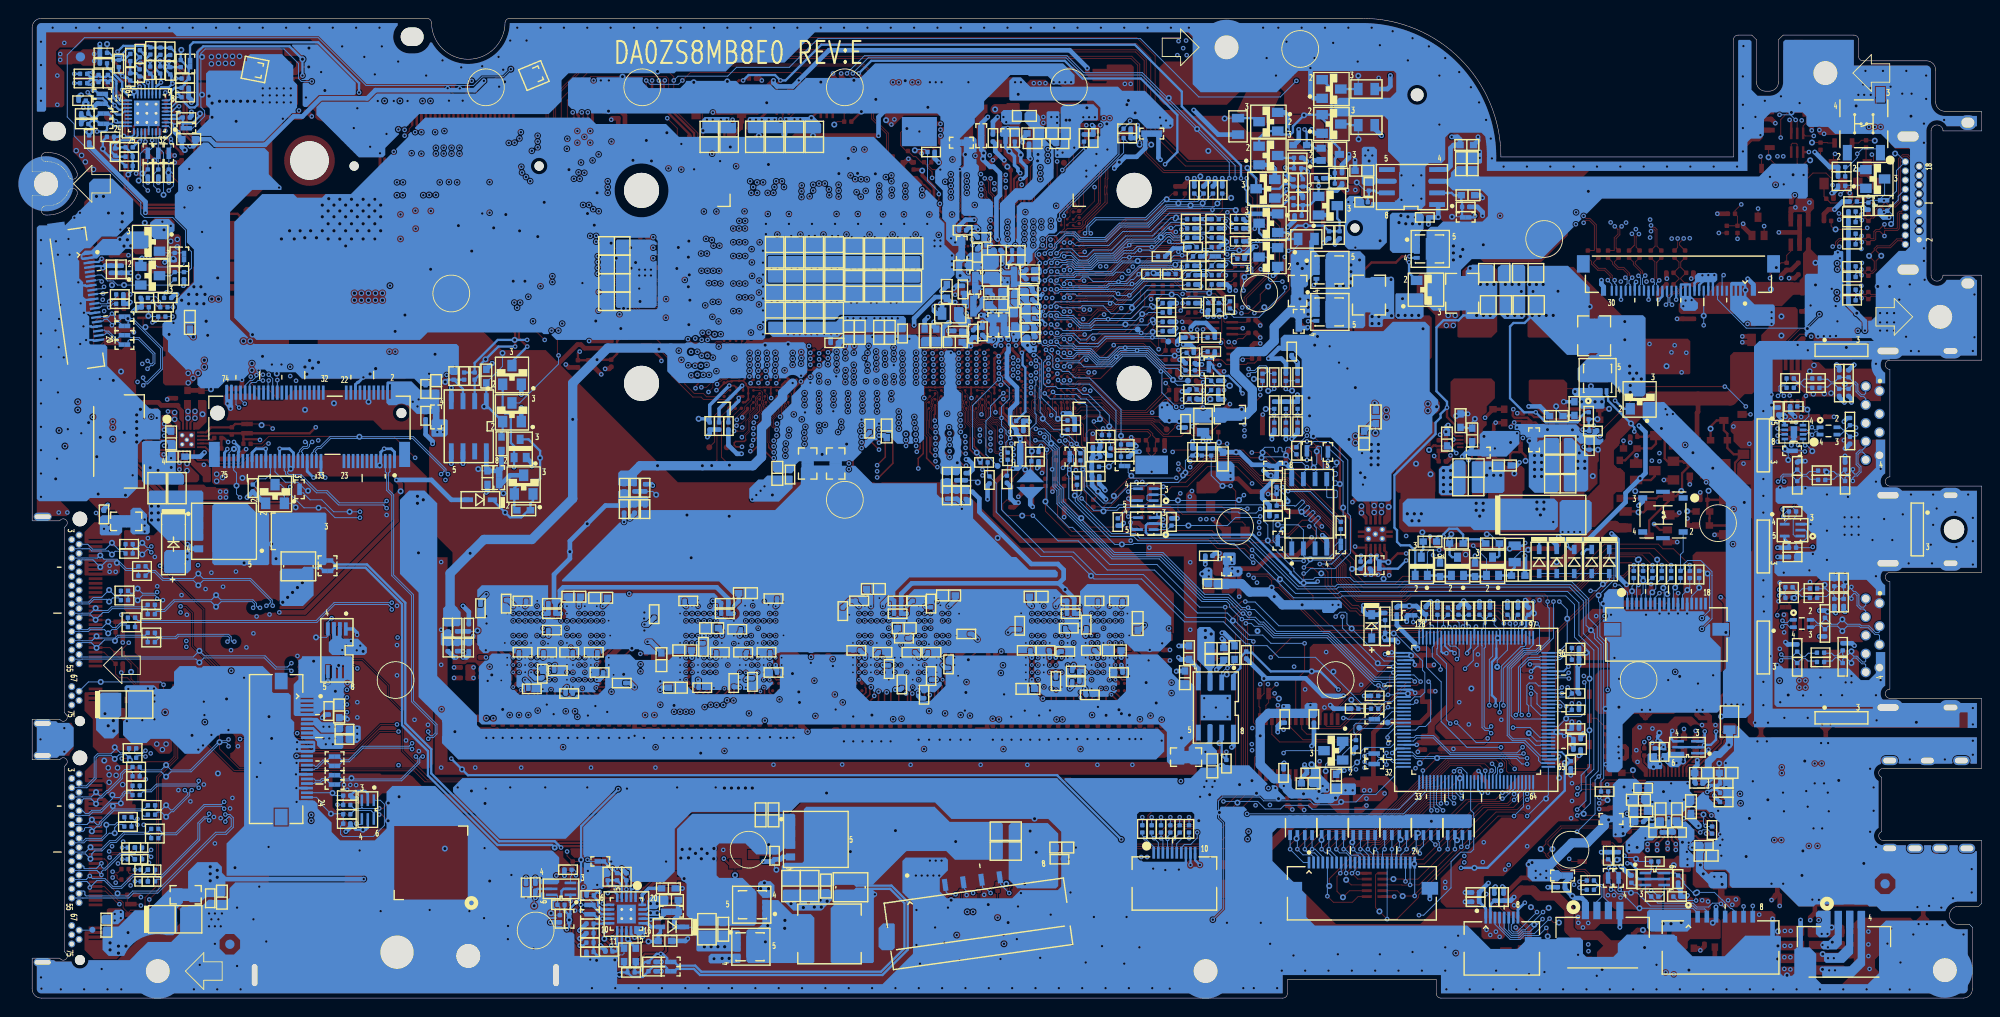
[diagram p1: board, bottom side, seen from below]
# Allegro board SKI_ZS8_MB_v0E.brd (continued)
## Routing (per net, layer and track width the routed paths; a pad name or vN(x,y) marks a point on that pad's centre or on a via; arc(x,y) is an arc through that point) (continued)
CN_HDMI_CLKN: length 19.8
  TOP w0.102: C26.2 13.71,85.21 13.6,85.1 13.25,85.1 v1(13.06,85.29) 12.86,85.1 12.57,85.1 R59.1 12.06,85.09 11.84,85.09 11.5,85.44 11.5,85.84 11.09,86.25 10.81,86.25 10.62,86.44 v1(10.62,86.8) 10.12,86.3 9.45,86.3 9.05,86.7 9.05,91.33 8.61,91.77 7.98,91.77 7.53,91.32 7.53,87.16 7.45,87.08 7.24,87.08 CN2.12
  BOTTOM w0.102: C26.2 13.71,85.21 13.59,85.09 13.26,85.09 v1(13.06,85.29)
CN_HDMI_CLKP: length 19.7
  TOP w0.102: CN2.10 7.16,86.88 7.54,86.88 7.73,87.07 7.73,91.24 8.06,91.57 8.53,91.57 8.85,91.25 8.85,86.62 9.37,86.1 10.05,86.1 v1(10.62,85.53) 10.62,85.86 10.76,85.99 11.06,85.99 11.29,85.76 11.29,85.35 11.76,84.89 12.01,84.89 R59.2 12.64,84.9 12.78,84.9 13.01,84.66 v1(13.03,84.66) 13.27,84.9 13.58,84.9 13.71,84.77 C28.2
  BOTTOM w0.102: C28.2 13.71,84.79 13.61,84.89 13.26,84.89 v1(13.03,84.66)
CN_HDMI_TXN0: length 11
  TOP w0.102: CN2.9 8.7,85.62 8.95,85.62 9.17,85.4 9.17,83.82 9.25,83.73 10.51,83.73 10.57,83.8 v1(10.57,84.21) 11.14,83.63 11.5,83.63 11.72,83.41 11.72,82.67 11.76,82.64 12.02,82.64 R73.1 12.57,82.69 12.97,82.69 13.06,82.78 v1(13.06,82.94) 13.28,82.72 13.61,82.72 13.71,82.82 C29.2
  BOTTOM w0.102: v1(13.06,82.94) 13.06,82.78 13.12,82.72 13.66,82.72 13.71,82.77 C29.2
CN_HDMI_TXN1: length 14.8
  TOP w0.102: C48.2 13.71,76.67 13.64,76.61 13.32,76.61 v1(13.08,76.84) 12.82,76.58 12.58,76.58 R110.1 12.06,76.58 11.01,76.58 10.79,76.79 10.79,76.94 v2(11.3,77.44) 10.74,78 10.74,78.78 7.73,81.8 7.73,83.74 7.4,84.07 7.25,84.07 CN2.6
  BOTTOM w0.102: C48.2 13.71,76.83 13.53,76.66 13.27,76.66 v1(13.08,76.84)
CN_HDMI_TXN2: length 10.7
  TOP w0.102: CN2.3 8.7,82.62 9.24,82.62 10,81.86 11.39,81.86 11.68,81.57 11.68,81.36 12.27,80.77 ; v2(12.24,80.77) 12.27,80.77 ; 12.27,80.77 11.68,80.19 11.68,79.33 11.92,79.1 12.03,79.1 R92.1 12.58,79.12 12.9,79.12 v1(13.08,79.3) 13.26,79.12 13.48,79.12 13.71,79.35 C34.2
  BOTTOM w0.102: v1(13.08,79.3) 13.26,79.12 13.59,79.12 13.71,79.24 C34.2
CN_HDMI_TXP0: length 11.1
  TOP w0.102: C30.2 13.71,82.39 13.58,82.51 13.3,82.51 13.06,82.27 v1(13.03,82.27) 13.03,82.43 12.97,82.49 12.65,82.49 R73.2 12.04,82.44 11.67,82.44 11.52,82.59 11.52,83.33 11.42,83.43 11.06,83.43 v1(10.57,82.94) 10.57,83.47 10.51,83.53 9.17,83.53 8.96,83.73 8.96,85.32 8.86,85.42 8.7,85.42 CN2.7
  BOTTOM w0.102: C30.2 13.71,82.36 13.55,82.51 13.15,82.51 13.03,82.4 v1(13.03,82.27)
CN_HDMI_TXP1: length 14.9
  TOP w0.102: C51.2 13.71,76.32 13.62,76.4 13.28,76.4 v1(13.06,76.17) 12.85,76.38 12.63,76.38 R110.2 12.01,76.38 10.92,76.38 10.59,76.71 10.59,76.86 v2(10.01,77.44) 10.54,77.98 10.54,78.7 7.53,81.71 7.53,83.66 7.31,83.87 7.15,83.87 CN2.4
  BOTTOM w0.102: C51.2 13.71,76.33 13.58,76.45 13.34,76.45 v1(13.06,76.17)
CN_HDMI_TXP2: length 10.7
  TOP w0.102: CN2.1 8.7,82.42 9.15,82.42 9.91,81.66 11.3,81.66 11.48,81.48 11.48,81.34 v2(10.92,80.78) 11.48,80.23 11.48,79.25 11.84,78.89 12.03,78.89 R92.2 12.63,78.92 12.8,78.92 v1(13.06,78.66) 13.31,78.92 13.54,78.92 13.71,78.75 C46.2
  BOTTOM w0.102: v1(13.06,78.66) 13.31,78.92 13.59,78.92 13.71,78.8 C46.2
CODEC_SENSEA: length 4.4
  TOP w0.102: v1(36.18,28.29) 36.24,28.23 36.24,27.57 36.18,27.52 36.18,26.61 36.39,26.41 R293.2
  TOP w0.203: U16.13 36.11,25.06 36.7,25.65 R293.2
CODEC_VREF: length 2.6
  TOP w0.203: v1(29.84,22.43) 29.88,22.46 U16.28
  BOTTOM w0.254: C382.1 28.77,22.66 29.36,22.66 29.46,22.56 29.72,22.56 v1(29.84,22.43)
CPU_DRAMRST#: length 9.8
  TOP w0.102: v1(106.43,65.84) 106.49,65.84 U6.AV15
  BOTTOM w0.102: v1(106.43,65.84) 107.82,64.45 107.82,63.32 108.33,62.81 108.33,59.18 TP23.1
CS_BST1: length 1.1
  TOP w0.254: v2(182.01,101.34) 182.84,101.34 PC4.1
CS_SW1:
  vias: v2(189.91,95.42)
D/C#: length 198.9
  TOP w0.254: 204.69,61.05 205.61,61.98 207.01,61.98 207.39,61.59 PR34.2 ; 204.69,61.05 v2(204.69,61.03) ; 204.69,61.05 203.73,60.09 202.29,60.09 200.76,58.57 200.76,58.22 196.51,53.97 184.94,53.97 184.02,54.89 v1(184.02,55.63)
  IN1 w0.254: v1(184.02,55.63) 179.57,51.17 179.57,45.7 174.12,40.25 174.12,24.89 170.21,20.99 133.21,20.99 131.37,22.83 86.26,22.83 84.86,24.24 71.77,24.24 66.78,29.24 59.94,29.24 59.74,29.03 55.69,29.03 v1(52.87,31.85)
  BOTTOM w0.178: U23.107 52.79,38.06
  BOTTOM w0.254: v1(52.87,31.85) 52.87,32.55 53.28,32.96 53.28,36.58 52.79,37.07 52.79,38.06
DC_TEST_A3_B3: length 0.7
  TOP w0.102: U6.A3 99.44,86.69 U6.B3
DC_TEST_A61_B61: length 0.7
  TOP w0.102: U6.B61 135.5,86.74 U6.A61
DC_TEST_AY2_AW2: length 0.7
  TOP w0.102: U6.AY2 98.73,64.73 U6.AW2
DC_TEST_AY3_AW3: length 0.7
  TOP w0.102: U6.AY3 99.51,64.24 U6.AW3
DC_TEST_AY61_AW61: length 7.9
  TOP w0.076: 136.71,63.05 136.7,63.06 136.7,63.08 135.92,63.86 U6.AY61
  TOP w0.102: U6.AY61 135.59,64.76 U6.AW61 ; 136.71,63.05 137.1,62.66 137.1,58.87 v2(136.24,58)
DC_TEST_AY62_AW62: length 7.7
  TOP w0.076: U6.AY62 137.02,63.41 137.04,63.41 137.06,63.4
  TOP w0.102: 137.06,63.4 137.59,62.86 137.59,58.53 v2(138.17,57.95) ; U6.AW62 136.25,64.75 U6.AY62
DC_TEST_B62_B63: length 0.7
  TOP w0.102: U6.B62 136.68,86.09 U6.B63
DC_TEST_C1_C2: length 6.4
  TOP w0.076: 96.98,88.85 97.73,88.1 97.73,86.1 98.15,85.68 U6.C1
  TOP w0.102: U6.C2 98.31,85.56 U6.C1 ; v1(96.38,90.59) 96.38,89.45 96.98,88.85
DDR_PG_CTRL: length 13.4
  TOP w0.076: 137.07,65.15 136.32,65.15 136.3,65.17 136.03,65.17 135.83,65.36 135.83,65.44 135.51,65.76 U6.AV61
  TOP w0.102: U7.2 144.43,71.16 v2(143.9,70.62) 142.49,69.22 142.49,67.69 140.21,65.41 139.32,65.41 139.06,65.14 137.08,65.14 137.07,65.15
DDR_VTTREF:
  vias: v1(196.99,58.77)
DDR_VTTT_PG_CTRL: length 50.8
  TOP w0.254: PR27.1 181.89,61.47 v1(181.24,62.12) ; U7.4 148.19,70.51 148.46,70.23 148.46,70.11 R142.2 v2(150.64,69.48) 151.52,69.48 R782.1 R779.2 152.72,70.16 v1(152.53,70.36)
  IN1 w0.254: v1(181.24,62.12) 170.04,62.12 157.86,74.3 154.62,74.3 152.53,72.2 v1(152.53,70.36)
DEVSLP0: length 237
  TOP w0.076: U6.P2 98.54,79.14 97.65,79.14 97.46,79.33
  TOP w0.102: v1(79.76,18.12) 81.7,18.12 83.31,16.51 91.97,16.51 99.2,23.74 169.1,23.74 170.31,24.94 178.16,24.94 178.17,24.96 189.55,24.96 191.71,27.12 v2(191.71,27.85) 191.71,29.28 190.12,30.87 190.12,33.78 194.67,38.33 194.67,41.92 195.38,42.64 v1(195.95,42.64) ; v1(88.39,82.33) 88.39,82.33 89.08,82.33 89.1,82.31 89.5,82.31 89.51,82.33 92.22,82.33 94.49,80.05 96.07,80.05 96.79,79.33 97.46,79.33 ; v1(202.4,41.72) 202.24,41.56 R199.2
  IN2 w0.114: v1(202.4,41.72) 197.88,41.72 196.97,42.64 v1(195.95,42.64)
  IN3 w0.102: v1(88.39,82.33) 87.87,82.84 87.08,82.84 86.78,83.15 84.59,83.15 82.91,81.47 81.22,81.47 80.59,80.85 80.59,78.78 80.28,78.47 79.75,78.47 77.11,75.83 77.11,71.79 75.55,70.22 75.55,68.83 73.66,66.94 73.66,63.03 74.42,62.27 74.42,52.37 74.78,52.01 74.78,37.84 75.21,37.41 75.21,35.59 74.6,34.98 74.6,22.86 79.34,18.12 v1(79.76,18.12)
  BOTTOM w0.102: R365.2 85.8,82.13 88.19,82.13 v1(88.39,82.33)
DEVSLP1: length 219.9
  TOP w0.076: 97.89,80.14 97.98,80.05 98.54,80.05 U6.L2
  TOP w0.102: v1(200.27,10.07) 200.42,10.23 R319.2 ; 97.89,80.14 97.13,80.14 96.4,80.87 94.83,80.87 92.54,83.15 90.44,83.15 89.23,84.37 83.39,84.37 R61.2 82.46,84.78 v1(82.26,84.57)
  IN3 w0.102: v1(200.27,10.07) 200.12,9.92 198.9,9.92 198.05,10.77 190.37,10.77 187.15,14 152.78,14 152.4,14.38 151.04,14.38 149.69,13.03 131.39,13.03 130.9,12.54 120.89,12.54 115.12,18.3 93.61,18.3 92.06,16.75 80.99,16.75 80.03,17.72 79.46,17.72 74.37,22.8 74.37,51.84 74.02,52.2 74.02,62.1 73.25,62.86 73.25,67.11 75.14,69 75.14,70.39 76.71,71.95 76.71,76 79.59,78.88 80,78.88 80.19,79.06 80.19,81.97 80.61,82.38 80.61,82.71 81.36,83.45 81.47,83.45 82.11,84.09 82.11,84.42 v1(82.26,84.57)
DEVSLP_N0: length 7.5
  TOP w0.102: R319.1 R318.2 202.66,11.24 v2(202.81,11.39) 203.88,12.46 203.88,14.8 204.22,15.14 CN13.38
DEVSLP_N1: length 4.4
  TOP w0.102: v2(203.09,38.88) 203.02,38.94 R201.2 R199.1 203.84,40.96 204.02,41.14 CN10.38
DMIC_CLK: length 21.7
  TOP w0.102: U16.3 37.66,20.06 37.77,19.95 38.1,19.95 38.42,19.63 39.04,19.63 39.94,18.73 45.79,18.73 47.41,17.11 47.41,16.78 v2(47.97,16.22) 47.41,15.66 47.41,15.49 45.7,13.78 43.25,13.78 42.87,13.4 42.87,12.89 43.32,12.44 43.53,12.44 v1(43.75,12.66)
  BOTTOM w0.102: R578.2 43.62,12.8 v1(43.75,12.66)
DMIC_CLK_C: length 4.2
  BOTTOM w0.102: R578.1 41.74,12.36 41.32,12.36 41.09,12.12 41.09,10.95 40.61,10.47 CN17.3
DMIC_DATA: length 21.6
  TOP w0.102: v1(43.75,12.03) 43.58,12.21 43.23,12.21 42.64,12.8 42.64,13.5 43.15,14.01 45.61,14.01 47.18,15.59 47.18,15.74 v2(46.7,16.22) 47.18,16.7 47.18,17.01 45.69,18.51 39.85,18.51 38.95,19.41 38.38,19.41 38.02,19.76 37.79,19.76 37.7,19.66 U16.2
  BOTTOM w0.102: v1(43.75,12.03) 43.51,11.79 R577.2
DMIC_DATA_C: length 3.8
  BOTTOM w0.102: CN17.2 41.86,10.5 41.32,11.04 41.32,12.03 41.42,12.13 41.84,12.13 R577.1
DNBSWON#: length 54.4
  IN1 w0.114: v1(57.09,36.9) 57.2,37.01 58.85,37.01 59.04,37.19 62.83,37.19 63.04,36.99 64.52,36.99 64.82,36.69 73.04,36.69 75.59,39.24 80.13,39.24 81.66,40.76 81.66,42.67 83.19,44.2 83.19,46.74 83.97,47.52 83.97,48.36 86.23,50.63 86.23,52.07 87.61,53.44 v1(87.61,56.62)
  BOTTOM w0.102: U23.120 57.99,38.48 57.81,38.3 57.23,38.3 56.84,37.91 56.84,37.15 v1(57.09,36.9) ; R464.1 92.85,57.19 v2(92.51,56.85) 92.25,56.59 87.63,56.59 v1(87.61,56.62)
DP_UTIL: length 5.8
  TOP w0.102: U6.A43 123.7,87.17 123.7,89.09 v2(124.33,89.73) 125.19,90.58 R35.2 R34.2
DPWROK: length 56.3
  TOP w0.102: v1(91.31,56.18) 91.69,56.57 92.83,56.57 94.41,54.99 v2(94.41,54.65) 94.41,54.57 95.52,53.46 R190.1
  IN1 w0.114: v1(58.87,35.75) 58.87,36.23 59.34,36.7 62.48,36.7 62.69,36.49 64.29,36.49 64.59,36.2 73.25,36.2 74.6,37.55 79.15,37.55 84.99,43.4 84.99,48.69 88.02,51.72 88.02,52.9 v1(91.31,56.18)
  BOTTOM w0.102: v1(58.87,35.75) 58.87,36.23 59.77,37.13 59.77,38.18 59.59,38.35 U23.124
DPWROK_R: length 18.1
  TOP w0.076: 97.8,62.47 98.18,62.85 100.41,62.85 100.83,63.27 100.83,63.59 101.1,63.87 101.1,65.23 U6.AV5
  TOP w0.102: 97.8,62.47 97.71,62.38 97.71,61.03 R169.2 97.49,61.44 97.09,61.84 96.54,61.84 95.57,60.87 95.57,59.97 95.78,59.76 95.78,59.34 v2(96.28,58.84) 96.65,58.48 R181.1 96.24,56.12 96.24,54.64 R190.2
DSWVREN: length 8.5
  TOP w0.076: U6.AW7 102.02,64.54 102.02,64 101.78,63.76 101.78,63.19 101.45,62.86 101.19,62.86 100.85,62.52 99.06,62.52 98.47,61.93
  TOP w0.102: R178.1 98.36,59.51 98.36,60.22 v1(98.46,60.31) 98.47,60.32 98.47,61.93
EC_FPBACK#: length 95.6
  TOP w0.102: Q4.2 v1(23.66,84.01)
  IN2 w0.114: v1(23.66,84.01) 21.1,86.58 21.1,94 v1(19.57,95.52)
  IN3 w0.102: v1(19.57,95.52) 19.47,95.62 17.96,95.62 16.74,94.4 16.74,93.89 16.92,93.71 16.92,74.18 17.18,73.91 19.05,73.91 28.55,64.41 28.55,60.71 43.54,45.72 49.68,45.72 54.38,41.02 56.64,41.02 v1(57.28,40.39)
  BOTTOM w0.102: U23.118 57.19,40.3 v1(57.28,40.39)
EC_PWROK: length 106.7
  TOP w0.102: R107.2 87.38,76.77 87.25,76.63 v1(86.93,76.63) 86.92,76.65 R109.2
  IN1 w0.114: v1(86.93,76.63) 86.86,76.56 86.41,76.56 85.89,76.04 84.59,76.04 84.13,75.59 81.83,75.59 81.34,76.08 79.35,76.08 77.07,73.8 77.07,71.07 76.18,70.18 76.18,66.57 76.2,66.55 76.2,65.66 77.6,64.26 77.6,62 77.64,61.96 77.64,53.27 v1(78.49,52.43)
  IN3 w0.102: v1(78.49,52.43) 78.16,52.09 78.16,50.11 77.44,49.4 77.44,38.88 77.7,38.63 77.7,38.32 80.09,35.93 80.09,32.51 78.46,30.89 78.46,28.7 78.63,28.54 78.63,25.77 80.69,23.71 80.69,23.3 82.49,21.5 v1(82.49,21.4)
  BOTTOM w0.102: v1(78.49,52.43) 78.61,52.3 81.18,52.3 82.05,51.43 v2(86.3,51.43) R484.1 88.58,50.99 U20.1 ; v1(82.49,21.4) 78.76,21.4 77.94,20.59 76.27,20.59 75.87,20.98 73.28,20.98 72.89,20.59 72.86,20.59 72.82,20.55 63.4,20.55 61.19,22.76 U23.33
EC_PWROK_R: length 11.5
  TOP w0.076: 100.18,62.34 100.91,62.34 101.27,62.7 101.52,62.7 101.94,63.12 101.94,63.69 102.22,63.96 102.22,64.09 U6.AY7
  TOP w0.102: R183.1 R184.1 99.82,56.77 99.25,57.34 v1(99.25,57.52) 99.25,58.87 99.21,58.91 99.21,59.49 98.87,59.83 98.87,61.78 99.43,62.34 100.18,62.34
ECAGND: length 4.1
  BOTTOM w0.203: U23.75 44.75,29.17 L18.1
  BOTTOM w0.508: v1(43.33,28.8) 43.63,28.51 C370.2 ; v1(44.59,30.06) L18.1
  vias: v2(44.49,27.57) v2(46.27,28.95)
EDP_AUXN: length 105.8
  TOP w0.102: U6.A45 125.25,86.81 124.97,87.09 124.97,87.91 v1(124.36,88.52) ; v1(32.41,82.67) 32.87,82.21 32.87,81.96 C53.1
  IN1 w0.114: v1(32.41,82.67) 32.64,82.9 32.64,83.06 32.98,83.4 34.41,83.4 36.9,80.91 45.03,80.91 46.3,82.18 56.75,82.18 60.29,85.72 62.58,85.72 67.14,90.29 67.93,90.29 70.07,92.42 76.9,92.42 77.13,92.65 87.44,92.65 88.38,93.59 98.68,93.59 99.07,93.97 104.71,93.97 105.47,93.22 111.94,93.22 113.43,91.72 114.65,91.72 115.46,90.91 117.2,90.91 117.54,91.25 120.53,91.25 120.87,90.91 122.7,90.91 124.15,89.47 124.15,88.73 v1(124.36,88.52)
EDP_AUXN_C: length 8.9
  TOP w0.102: v1(33.68,75.45) 33.91,75.68 33.91,76.3 33.56,76.65 32.98,76.65 32.73,76.9 32.73,77.07 R137.2 32.73,78.25 32.73,78.34 R128.2 32.73,79.52 32.73,80.1 C53.2
  BOTTOM w0.102: v1(33.68,75.45) 33.68,75.46 33.92,75.7 33.92,76.22 33.74,76.4 CN8.17
EDP_AUXP: length 105.7
  TOP w0.102: U6.B45 125.44,86.34 124.76,87.01 124.76,87.84 124.62,87.98 124.47,87.98 v1(124.36,87.87) ; v1(33.07,82.67) 33.07,81.69 C54.1
  IN1 w0.114: v1(124.36,87.87) 123.93,88.3 123.93,89.38 122.61,90.7 120.78,90.7 120.44,91.04 117.63,91.04 117.29,90.7 115.37,90.7 114.56,91.51 113.34,91.51 111.85,93 105.38,93 104.62,93.76 99.16,93.76 98.77,93.37 88.47,93.37 87.53,92.43 77.22,92.43 76.99,92.2 70.15,92.2 68.02,90.07 67.23,90.07 62.67,85.51 60.38,85.51 56.84,81.97 46.38,81.97 45.11,80.7 36.81,80.7 34.32,83.19 33.07,83.19 32.86,82.97 32.86,82.88 v1(33.07,82.67)
EDP_AUXP_C: length 8.9
  TOP w0.102: v1(34.34,75.45) 34.11,75.68 34.11,76.38 33.64,76.85 33.07,76.85 32.93,76.98 32.93,77.08 R138.2 32.93,78.25 32.93,78.35 R129.2 32.93,79.52 32.93,80.11 C54.2
  BOTTOM w0.102: CN8.18 34.23,76.37 34.12,76.26 34.12,75.67 v1(34.34,75.45)
EDP_BKLEN: length 139.8
  TOP w0.102: v1(101.6,91.11) v2(102.71,91.11) 102.85,91.11 103.5,90.45 103.5,86.95 U6.A9 ; R340.2 v1(26.56,82.63)
  IN1 w0.114: v1(101.6,91.11) 101.08,90.59 99.48,90.59 98.18,91.9 89.04,91.9 88.16,91.01 78.19,91.01 77.98,90.8 74.52,90.8 73.75,90.03 73.75,89.78 73.5,89.53 73.12,89.53 72.48,90.17 70.19,90.17 70,90.17 68.86,89.03 68.59,88.76 67.77,88.76 64.57,85.56 64.57,83.84 63.41,82.69 63.41,82.09 63.41,82.09 63.41,79.55 62.42,78.55 55.7,78.55 55.13,79.12 44.69,79.12 42.11,76.54 18.58,76.54 16.64,74.61 15.65,74.61 13.54,76.72 13.54,88.82 15.92,91.2 21.17,91.2 v1(21.58,91.61)
  IN2 w0.114: v1(21.58,91.61) 21.96,91.23 21.96,87.04 26.36,82.63 v1(26.56,82.63)
EDP_BKLEN_EC: length 91.8
  TOP w0.102: R341.2 v1(28.59,83.27)
  IN2 w0.114: v1(28.59,83.27) 26.29,83.27 23.37,86.18 23.37,88.29 22.21,89.45 v1(22.21,91.61)
  IN3 w0.102: v1(57.91,40.39) 57.02,41.27 54.43,41.27 49.76,45.95 43.6,45.95 28.75,60.79 28.75,64.5 18.66,74.59 18.16,74.59 17.63,75.13 17.63,90.65 18.16,91.19 21.79,91.19 v1(22.21,91.61)
  BOTTOM w0.102: v1(57.91,40.39) 57.59,40.06 U23.119
EDP_BKLTCL: length 120
  TOP w0.076: U6.B8 102.95,86.17 102.43,86.69 102.43,87.23
  TOP w0.102: R35.1 123.29,89.53 v1(123.06,89.53) 123.06,91.14 v2(123.31,91.38) ; v1(101.6,91.74) 101.19,91.34 101.19,90.36 101.5,90.05 101.5,88.16 102.43,87.23
  IN1 w0.114: v1(28.07,78.68) 29.75,77 41.92,77 44.5,79.58 55.31,79.58 55.89,79.01 62.23,79.01 62.96,79.74 62.96,81.9 62.96,82.88 64.11,84.03 64.11,85.75 67.58,89.22 68.4,89.22 69.81,90.63 70.37,90.63 73.58,90.63 74.27,91.31 77.52,91.31 77.76,91.55 88.05,91.55 88.85,92.35 98.96,92.35 99.46,92.86 100.72,92.86 101.11,92.47 101.11,92.24 v1(101.6,91.74) 102.11,92.26 111.57,92.26 112.39,91.44 112.39,91.38 113.69,90.07 117.63,90.07 117.97,90.41 120.18,90.41 120.52,90.07 122.14,90.07 122.68,89.53 v1(123.06,89.53)
  BOTTOM w0.102: v1(28.07,78.68) 28.23,78.51 CN8.6
EDP_HPD: length 95.6
  TOP w0.102: v1(100.03,90.12) 100.05,90.09 100.05,88.29 101.35,86.99 101.35,86.6 101.76,86.19 101.76,85.94 101.56,85.74 U6.D6
  IN1 w0.114: v1(30.23,73.22) 35.1,73.22 35.77,73.89 39.79,73.89 44.78,78.89 55.03,78.89 55.6,78.32 62.51,78.32 63.64,79.45 63.64,82.59 64.8,83.75 64.8,85.47 67.13,87.8 67.32,87.8 68.06,88.53 68.87,88.53 69.27,88.94 70.28,89.94 72.29,89.94 72.93,89.3 76.96,89.3 78.38,90.73 88.22,90.73 89.16,91.67 98.07,91.67 99.62,90.12 v1(100.03,90.12)
  BOTTOM w0.102: R335.2 97.66,92.48 v1(100.03,90.12) ; v1(30.23,73.22) v2(30.23,74.26) CN8.10
EDP_RCOMP: length 2.9
  TOP w0.254: v1(109.6,84.71) 109.28,85.03 U6.D20
  BOTTOM w0.508: R358.2 111.26,83.99 110.55,84.71 v1(109.6,84.71)
EDP_TXN0: length 105.8
  TOP w0.076: v1(125.37,87.38) 125.71,87.38 125.77,87.32 125.77,86.05 125.44,85.71 U6.C45
  TOP w0.102: C41.1 35.52,81.82 35.52,83.57 35.63,83.68 35.75,83.68 v1(35.97,83.46)
  IN1 w0.114: v1(35.97,83.46) 36.18,83.67 36.37,83.67 36.58,83.47 36.58,82.35 37.39,81.54 44.77,81.54 46.04,82.81 56.49,82.81 60.03,86.35 61.99,86.35 66.55,90.91 67.29,90.91 69.42,93.04 76.53,93.04 76.76,93.27 87.05,93.27 88.01,94.23 98.1,94.23 98.46,94.6 105,94.6 105.74,93.85 112.19,93.85 113.69,92.35 120.47,92.35 121.15,91.68 122.82,91.68 124.99,89.52 124.99,87.76 v1(125.37,87.38)
EDP_TXN0_C: length 4.1
  TOP w0.102: v1(35.82,78.1) 35.55,78.38 35.55,80.13 C41.2
  BOTTOM w0.102: CN8.21 35.74,77.54 35.59,77.68 35.59,77.87 v1(35.82,78.1)
EDP_TXN1: length 105.3
  TOP w0.076: U6.A47 126.56,86.56 126.49,86.49 126.36,86.49 126.27,86.58 126.27,88.42 v1(126.49,88.65)
  TOP w0.102: v1(38.05,83.17) 37.79,82.91 37.79,81.93 C39.1
  IN1 w0.114: v1(126.49,88.65) 126.33,88.81 126.33,89.67 122.57,93.43 119.35,93.43 117.86,94.92 117.86,95.76 117.08,96.53 88.77,96.53 86.58,94.35 76.31,94.35 76.06,94.09 66.12,94.09 63.79,91.76 62.28,91.76 60.24,89.72 60.24,88.06 56.04,83.86 45.6,83.86 44.33,82.59 37.92,82.59 37.81,82.7 37.81,82.93 v1(38.05,83.17)
EDP_TXN1_C: length 4.4
  TOP w0.102: C39.2 37.89,80.11 37.89,79.82 37.08,79.02 37.08,78.99 37.08,78.88 v1(37.34,78.6)
  BOTTOM w0.102: CN8.24 37.23,77.54 37.1,77.67 37.1,78.36 v1(37.34,78.6)
EDP_TXN2: length 107.4
  TOP w0.076: v1(127.13,87.88) 126.87,87.88 126.8,87.81 126.8,87.46 127.04,87.21 127.04,86.77 126.96,86.54 126.96,86.43 127.01,86.31 127.02,86.28 127.02,86.09 126.98,85.94 126.88,85.79 U6.C47
  TOP w0.102: C37.1 40.01,81.35 39.97,81.4 39.97,82.74 39.56,83.15 39.56,83.64 v1(39.91,83.99)
  IN1 w0.114: v1(39.91,83.99) 39.65,83.73 39.65,83.57 39.79,83.43 43.98,83.43 45.27,84.71 55.7,84.71 59.4,88.41 59.4,90.07 62.5,93.17 63.2,93.17 65.23,95.2 86.25,95.2 88.42,97.37 117.82,97.37 120.61,94.58 122.77,94.58 127.79,89.56 127.79,88.37 127.56,88.14 127.32,88.14 127.13,87.95 v1(127.13,87.88)
EDP_TXN2_C: length 5.1
  TOP w0.102: C37.2 40.15,80.08 40.15,79.87 39.59,79.31 39.01,79.31 38.5,78.8 38.5,78.67 v1(38.76,78.4)
  BOTTOM w0.102: v1(38.76,78.4) 38.76,78.4 38.57,78.21 38.57,77.74 38.73,77.58 CN8.27
EDP_TXN3: length 104.4
  TOP w0.102: v1(43.3,84.38) 43.03,84.65 42.7,84.65 42.13,84.08 42.13,81.42 42.2,81.35 C35.1 ; U6.A49 127.99,86.86 127.99,87.86 128.16,88.03 128.31,88.03 128.4,87.94 v1(128.4,87.81)
  IN1 w0.114: v1(128.4,87.81) 128.73,87.81 128.8,87.88 128.8,89.64 123.24,95.2 120.87,95.2 118.08,97.99 88.16,97.99 85.99,95.82 64.89,95.82 62.87,93.79 62.19,93.79 58.78,90.38 58.78,88.67 55.68,85.57 45.18,85.57 44.3,84.69 43.61,84.69 v1(43.3,84.38)
EDP_TXN3_C: length 5.3
  TOP w0.102: v1(40.67,78.13) 40.4,78.4 40.4,78.57 41.04,79.21 41.76,79.21 42.43,79.89 42.43,80.17 C35.2
  BOTTOM w0.102: v1(40.67,78.13) 40.23,77.69 CN8.30
EDP_TXP0: length 105.8
  TOP w0.076: v1(125.41,88.01) 125.41,87.91 125.94,87.38 125.94,85.9 U6.B46
  TOP w0.102: v1(35.97,84.09) 35.76,83.89 35.55,83.89 35.32,83.66 35.32,81.82 C42.1
  IN1 w0.114: v1(125.41,88.01) 125.2,88.22 125.2,89.61 122.91,91.9 121.24,91.9 120.56,92.57 113.78,92.57 112.28,94.07 105.83,94.07 105.09,94.81 98.37,94.81 98.01,94.45 87.92,94.45 86.96,93.48 76.67,93.48 76.44,93.26 69.33,93.26 67.2,91.13 66.46,91.13 61.9,86.56 59.94,86.56 56.4,83.02 45.95,83.02 44.68,81.75 37.48,81.75 36.79,82.44 36.79,83.56 36.46,83.89 36.17,83.89 v1(35.97,84.09)
EDP_TXP0_C: length 4.1
  TOP w0.102: C42.2 35.35,80.08 35.35,80.04 35.35,80.04 35.35,78.38 v1(35.08,78.1)
  BOTTOM w0.102: v1(35.08,78.1) 35.38,77.8 35.38,77.68 35.23,77.54 CN8.20
EDP_TXP1: length 105.3
  TOP w0.076: v1(125.86,88.65) 126.1,88.4 126.1,86.51 126.29,86.32 126.49,86.32 126.56,86.25 U6.B47
  TOP w0.102: v1(37.29,83.15) 37.58,82.85 37.58,81.72 C40.1
  IN1 w0.114: v1(125.86,88.65) 126.11,88.9 126.11,89.59 122.48,93.21 119.26,93.21 117.64,94.83 117.64,95.67 116.99,96.32 88.86,96.32 86.67,94.13 76.4,94.13 76.15,93.88 66.21,93.88 63.88,91.54 62.37,91.54 60.46,89.64 60.46,87.97 56.13,83.64 45.69,83.64 44.42,82.37 37.81,82.37 37.58,82.6 37.58,82.85 v1(37.29,83.15)
EDP_TXP1_C: length 4.4
  TOP w0.102: C40.2 37.68,80.11 37.68,79.91 36.88,79.11 36.88,78.99 36.88,78.89 v1(36.6,78.63)
  BOTTOM w0.102: CN8.23 36.74,77.54 36.9,77.7 36.9,78.33 v1(36.6,78.63)
EDP_TXP2: length 107.4
  TOP w0.076: v1(127.13,88.52) 126.72,88.11 126.72,87.97 126.63,87.88 126.63,87.39 126.88,87.14 126.88,86.8 126.8,86.57 126.8,86.4 126.82,86.32 126.83,86.31 126.86,86.25 126.86,86.12 126.83,86.01 126.62,85.81 126.44,85.81 126.27,85.63 U6.C46
  TOP w0.102: C38.1 39.77,81.62 39.77,82.66 39.36,83.07 39.36,83.79 v1(39.17,83.99)
  IN1 w0.114: v1(127.13,88.52) 127.29,88.35 127.47,88.35 127.58,88.46 127.58,89.47 122.68,94.36 120.52,94.36 117.73,97.16 88.51,97.16 86.34,94.98 65.32,94.98 63.29,92.95 62.59,92.95 59.62,89.98 59.62,88.32 55.79,84.5 45.36,84.5 44.07,83.21 39.7,83.21 39.44,83.48 39.44,83.72 v1(39.17,83.99)
EDP_TXP2_C: length 5.1
  TOP w0.102: C38.2 39.94,80.13 39.94,79.96 39.5,79.52 38.93,79.52 38.29,78.88 38.29,78.68 v1(38.02,78.4)
  BOTTOM w0.102: v1(38.02,78.4) 38.37,78.05 38.37,77.76 38.23,77.63 CN8.26
EDP_TXP3: length 104.5
  TOP w0.102: U6.B49 127.94,86.36 128.27,86.69 128.27,87.05 v1(128.4,87.17) ; v1(43.3,85.12) 43.03,84.85 42.61,84.85 41.93,84.17 41.93,81.58 C36.1
  IN1 w0.114: v1(128.4,87.17) 129.02,87.8 129.02,89.73 123.33,95.42 120.96,95.42 118.17,98.21 88.07,98.21 85.9,96.04 64.81,96.04 62.78,94.01 62.1,94.01 58.57,90.47 58.57,88.76 55.59,85.78 45.09,85.78 44.21,84.9 43.52,84.9 v1(43.3,85.12)
EDP_TXP3_C: length 5.3
  TOP w0.102: C36.2 42.23,80.04 42.23,79.97 41.67,79.42 40.96,79.42 40.2,78.66 40.2,78.4 v1(39.93,78.13)
  BOTTOM w0.102: CN8.29 39.73,77.61 39.93,77.8 v1(39.93,78.13)
EDP_VDDEN: length 99.3
  TOP w0.102: v1(100.58,91.05) 100.58,88.04 101.56,87.07 101.56,86.7 101.96,86.3 U6.C6 ; v1(23.03,78.35) 23.03,78.81 v2(22.34,79.5) 21.81,80.02 R89.2 21.21,80.83 20.76,81.28 U5.3
  IN1 w0.114: v1(23.03,78.35) 24.61,76.77 42.01,76.77 44.59,79.35 55.22,79.35 55.79,78.78 62.32,78.78 63.19,79.64 63.19,81.99 63.18,82.78 64.34,83.94 64.34,85.66 67.68,88.99 68.49,88.99 68.63,89.13 69.9,90.4 70.28,90.4 73.68,90.4 74.34,91.06 77.77,91.06 78,91.29 88.11,91.29 88.95,92.13 98.3,92.13 99.38,91.05 v1(100.58,91.05)
EL_SCL_C: length 9.8
  TOP w0.102: v1(176.85,18.99) 178.88,21.02 v1(178.88,21.05)
  BOTTOM w0.102: v1(176.85,18.99) 176.75,18.89 176.38,18.89 176.23,19.04 Q17.4 ; CN12.22 179.45,22.35 v2(179.42,22.32) 179.14,22.04 R552.2 R554.1 178.86,21.02 v1(178.88,21.05)
EL_SDA_C: length 16.1
  BOTTOM w0.102: CN12.23 181.17,21.85 180.66,21.34 180.66,21.13 v2(179.59,20.07) 178.32,20.07 R555.1 R559.2 178.55,18.69 178.55,17.85 178.3,17.59 174.97,17.59 173.78,18.79 173.78,21.1 174.21,21.53 Q17.1
FAN_PWM: length 203.3
  TOP w0.102: Q12.1 v1(209.17,61.77)
  IN1 w0.114: v1(209.17,61.77) 205.18,57.78 205.18,55.76 204.72,55.3 204.72,49.66 200.32,45.26 200.32,38.37 198.21,36.26 196.3,36.26 186.21,26.17 186.21,18.87 178.24,10.9 161.91,10.9 156.75,5.74 155.03,5.74 151.38,2.09 91.36,2.09 84.92,8.53 v1(83.64,8.53)
  BOTTOM w0.102: U23.32 63.63,25.17 63.88,24.92 63.88,24.19 65.9,22.17 67.23,22.17 68.06,21.35 v2(69.69,21.35) 69.99,21.05 72.63,21.05 73.05,21.46 78.11,21.46 78.53,21.89 82.59,21.89 83.02,21.45 83.02,19.62 82.46,19.07 82.46,9.71 v1(83.64,8.53)
FANSIG: length 218.7
  TOP w0.102: v1(207.14,64.01) 205.11,64.01 204.98,64.14 204.98,65.02 204.47,65.53 R157.1 204.47,65.91 205.17,66.61 205.17,70.55 204.27,71.45 CN3.2
  IN1 w0.114: v1(61.22,9.02) 84.75,9.02 91.46,2.32 151.29,2.32 154.94,5.97 156.66,5.97 161.81,11.13 178.15,11.13 185.99,18.97 185.99,26.27 196.24,36.53 198.15,36.53 200,38.38 200,45.26 202.94,48.2 202.94,53.84 204.83,55.73 204.83,61.7 v1(207.14,64.01)
  BOTTOM w0.102: U23.47 55.59,20.46 55.26,20.13 55.26,16.2 55.58,15.88 56.7,15.88 57.72,14.85 57.72,12 60.71,9.02 v1(61.22,9.02)
GPIO2: length 18.3
  TOP w0.076: U6.J3 99.4,81.8 99.15,81.55 98.06,81.55 97.83,81.79 97.67,81.79 97.57,81.88
  TOP w0.102: 97.57,81.88 95.25,81.88 92.95,84.18 90.85,84.18 89.24,85.79 85,85.79 84.75,86.05 v2(84.75,86.5) 84.65,86.6 R48.2
GPIO3: length 20.3
  TOP w0.076: 95.76,81.68 97.28,81.68 97.34,81.62 97.76,81.62 98,81.38 99.33,81.38 99.37,81.42 99.76,81.42 U6.J4
  TOP w0.102: 95.76,81.68 95.17,81.68 92.87,83.98 90.77,83.98 89.16,85.59 83.86,85.59 83.68,85.77 ; 83.68,85.77 83.63,85.82 R47.2 ; 83.68,85.77 v1(83.68,85.79)
GPIO8: length 12.7
  TOP w0.076: U6.AU2 98.68,66.17 98.36,66.49 97.94,66.49
  TOP w0.102: 97.94,66.49 97.68,66.75 96.83,66.75 93.6,63.52 90.43,63.52 90.25,63.71 v1(90.25,63.72) 90.25,63.8 88.89,65.15 R156.2
GPIO12: length 15.8
  TOP w0.102: v1(101.52,69.7) 101.84,69.39 U6.AM7
  BOTTOM w0.102: R452.2 94.77,60.38 94.93,60.53 R777.2 94.93,62.2 v2(94.91,62.22) 94.91,63.41 97.18,65.69 97.79,65.69 98.45,66.34 100.5,66.34 100.71,66.55 101.75,66.55 102.06,66.86 102.06,69.17 v1(101.52,69.7)
GPIO15: length 13.7
  TOP w0.102: U6.AD6 101.47,74.08 v1(101.27,74.29)
  BOTTOM w0.102: R403.1 89.68,73.6 89.88,73.8 v2(90.19,73.8) 90.73,73.25 96.58,73.25 96.9,72.93 98.11,72.93 99,73.82 100.81,73.82 v1(101.27,74.29)
GPIO17: length 13
  TOP w0.102: v1(99.19,77.72) 99.49,78.02 U6.T3
  BOTTOM w0.102: v1(99.19,77.72) 98.98,77.52 95.21,77.52 94.95,77.77 92.96,77.77 92.52,78.21 92.28,78.21 v1(91.71,78.78) 91.24,79.25 88.21,79.25 87.77,78.81 R374.2
GPIO24: length 13.2
  TOP w0.102: U6.AD5 100.64,73.99 v1(100.64,74.29)
  BOTTOM w0.102: R399.2 90.64,74.62 90.82,74.44 v2(91.33,74.44) 92.03,73.73 96.43,73.73 97,73.16 98.01,73.16 98.9,74.05 100.41,74.05 v1(100.64,74.29)
GPIO25: length 14.2
  TOP w0.076: 95.76,69.87 97.76,69.87 98.1,69.53 98.5,69.53 98.63,69.4 99.13,69.4 99.24,69.5 99.78,69.5 U6.AM4
  TOP w0.102: 95.76,69.87 95.62,69.87 v1(94.43,71.06) 94.25,71.24 91.18,71.24 89.96,70.02 89.25,70.02 R136.2 88.78,71.25 R778.2
GPIO26: length 17.8
  TOP w0.076: 97.54,68.68 97.57,68.65 98.31,68.65 98.53,68.42 98.53,68.24 98.71,68.06 99.23,68.06 U6.AN3
  TOP w0.089: 96.18,68.7 96.2,68.68 97.54,68.68
  TOP w0.102: R144.2 84.18,68.55 85.17,68.55 85.47,68.85 89.37,68.85 91,70.47 91.89,70.47 ; 91.89,70.47 92.91,70.47 93.01,70.37 94.15,70.37 95.82,68.7 96.18,68.7 ; 91.89,70.47 v1(91.89,70.48)
GPIO27: length 20.9
  TOP w0.102: v1(100.55,69.45) 100.55,69.44 101.09,68.9 U6.AN5
  BOTTOM w0.102: v1(100.55,69.45) 100.55,69.44 100.44,69.34 98.2,69.34 97.66,69.87 97.24,69.87 96.28,68.91 94.68,68.91 93.52,70.08 90.88,70.08 87.51,66.7 85.87,66.7 R776.2 84.79,65.62 84.37,65.62 R427.2
GPIO28: length 15
  TOP w0.102: U6.AD7 102.12,74.06 v1(101.89,74.29)
  BOTTOM w0.102: v1(101.89,74.29) 101.47,74.71 100.44,74.71 100.01,74.28 98.81,74.28 97.92,73.39 97.09,73.39 96.52,73.96 92.49,73.96 91.22,75.22 v2(90.13,75.22) 89.51,75.22 R391.2
GPIO44: length 15.9
  TOP w0.076: U6.AK4 99.84,70.93 99.37,70.93 99.33,70.89 98.65,70.89 98.48,71.06 97.35,71.06 97.03,71.38 96.48,71.38
  TOP w0.102: R113.2 86.71,75.22 87.4,75.22 87.44,75.18 89.57,75.18 90.4,74.35 90.82,74.35 v1(91.4,73.77) 92.85,72.31 95.54,72.31 96.48,71.38
GPIO46: length 19.5
  TOP w0.076: 96.22,73.48 96.3,73.48 96.6,73.18 96.62,73.18 96.98,72.82 96.98,72.81 97.82,72.81 98.06,72.56 98.48,72.56 98.65,72.39 99.1,72.39 99.35,72.14 U6.AG3
  TOP w0.102: R98.2 84.38,77.05 85.74,77.05 85.95,77.26 87.09,77.26 87.09,77.26 87.14,77.26 87.35,77.46 87.35,77.46 87.47,77.58 87.47,77.58 87.91,78.03 90.31,78.03 90.31,78.03 90.5,78.03 90.5,78.03 90.62,78.03 91.53,77.12 91.53,76.04 v2(92.45,75.12) 94.09,73.48 96.22,73.48
GPIO47: length 20
  TOP w0.102: v1(101.27,75.24) 101.47,75.03 U6.AB6
  BOTTOM w0.102: v1(101.27,75.24) 100.73,75.78 98.08,75.78 98.03,75.83 94.58,75.83 94.24,75.49 92.35,75.49 92.34,75.5 92.33,75.5 90.78,77.05 86.67,77.05 86.48,76.86 84.18,76.86 v2(84.04,76.72) 83.77,76.99 R383.2
GPIO48: length 19.1
  TOP w0.076: U6.U4 99.78,76.95 99.36,76.95 99.3,76.89 97.88,76.89 97.82,76.82
  TOP w0.102: R81.2 83.4,80.3 88.08,80.3 88.24,80.47 90.77,80.47 93.28,77.96 v1(93.91,77.96) 93.93,77.98 94.13,77.98 95.29,76.82 97.82,76.82
GPIO49: length 15.2
  TOP w0.076: 96.61,75.55 99.1,75.55 99.35,75.81 U6.Y3
  TOP w0.102: R95.2 87.41,78.68 87.58,78.84 88.33,78.84 88.94,79.45 90.35,79.45 93.69,76.11 94.3,76.11 v1(94.82,75.59) 94.86,75.55 96.61,75.55
GPIO50: length 14.9
  TOP w0.076: 97.84,78.67 97.96,78.55 99.23,78.55 U6.P3
  TOP w0.102: R72.2 86.64,82.54 87.02,82.54 87.35,82.21 87.64,82.21 88.15,81.7 92.27,81.7 95.3,78.67 95.33,78.67 95.33,78.67 96.39,78.67 96.43,78.7 97.81,78.7 97.84,78.67
GPIO52: length 13.6
  TOP w0.076: U6.L1 97.35,80.34
  TOP w0.102: 97.35,80.34 97.21,80.34 96.49,81.07 94.91,81.07 92.63,83.36 90.53,83.36 89.11,84.78 v1(87.75,84.78) R62.1
GPIO56: length 13.7
  TOP w0.102: v1(101.23,72.39) 101.23,72.15 U6.AG6
  BOTTOM w0.076: 99.57,72.35 100.01,72.35 100.37,71.99 100.83,71.99 v1(101.23,72.39)
  BOTTOM w0.102: R406.2 90.11,72.58 v2(90.19,72.51) 90.4,72.29 96.75,72.29 97.41,71.63 98.04,71.63 98.76,72.35 99.57,72.35
GPIO57: length 11.7
  TOP w0.102: R146.2 v1(89.29,68.2) 90.97,69.87 93.43,69.87 94.09,69.22 94.09,69.21 94.51,68.8 94.51,68.79 95.76,67.54 95.86,67.44 98.02,67.44 U6.AP1
GPIO58: length 21.4
  TOP w0.102: U6.AL4 100.14,69.93 v1(99.84,70.23)
  BOTTOM w0.102: v1(99.84,70.23) 99.43,69.82 98.92,69.82 98.46,70.28 97.07,70.28 96.11,69.32 94.85,69.32 93.68,70.48 90.72,70.48 88.74,68.51 87.45,68.51 86.76,67.82 85.28,67.82 84.9,67.44 84.08,67.44 R425.2 83.29,66.65 v2(81.85,66.65)
GPIO59: length 30.8
  TOP w0.089: v1(101.93,65.81) 101.93,66.27 101.73,66.47 101.47,66.47 101.16,66.79 U6.AT5
  BOTTOM w0.102: v1(101.93,65.81) 101.32,65.2 98.68,65.2 98.19,64.72 97.58,64.72 97.35,64.49 97.35,55.67 95.55,53.87 94.67,53.87 92.79,55.75 90.91,55.75 90.55,56.11 87.43,56.11 86.63,56.91 v2(86.63,57.19) 86.63,58.47 86.05,59.05 R451.2
GPIO64: length 12.1
  TOP w0.076: 98,84.62 98.38,84.62 98.58,84.43 99.18,84.43 U6.E3
  TOP w0.102: R19.2 97.39,93.6 96.51,92.73 96.51,92.06 v1(96.31,91.86) 95.98,91.53 95.98,89.56 96.09,89.45 96.09,87.67 96.07,87.66 96.07,86.87 96.09,86.86 96.09,86.54 98,84.62
GPIO65: length 15.2
  TOP w0.102: U6.F4 100.05,83.39 100.05,83.49 99.8,83.74 99.8,85.09 v1(99.85,85.14)
  BOTTOM w0.102: v1(91.61,93.13) 91.73,93 92.75,93 93.34,93.6 R334.2 93.35,91.99 99.85,85.5 v1(99.85,85.14)
GPIO66: length 10.5
  TOP w0.076: 98.21,86.22 98.53,85.9 98.99,85.9 99.18,85.71 99.18,85.08 U6.D3
  TOP w0.102: R20.1 97.45,92.49 v1(97.45,92.47) 97.32,92.34 97.32,90.72 98.21,89.83 98.21,86.22
GPIO67: length 14.6
  TOP w0.102: U6.E4 100.14,84.52 v1(100.33,84.71)
  BOTTOM w0.102: v1(100.33,84.71) 100.33,85.34 93.85,91.82 93.85,94.12 R330.2 92.65,95.32 v1(92.65,95.47)
GPIO68: length 8.8
  TOP w0.076: 98.82,86.76 99.11,86.47 99.11,86.03 99.49,85.65 U6.C3
  TOP w0.102: R21.2 98.72,92.61 v1(98.72,92.55) 98.82,92.45 98.82,86.76
GPIO69: length 12.2
  TOP w0.102: U6.E2 98.69,83.95 98.05,83.95 97.79,84.2 97.79,84.56 96.24,86.11 96.24,86.12 95.9,86.46 95.9,86.78 95.88,86.79 95.88,89.36 95.77,89.47 95.77,91.16 95.11,91.82 v1(95.11,92.34) 95.11,92.44 R18.2
GPIO84: length 23.7
  TOP w0.102: v1(101.93,81.02) 101.47,80.57 U6.L6
  BOTTOM w0.102: R344.2 82.62,87.01 v2(83.15,86.48) 83.51,86.12 88.66,86.12 90.66,84.12 93.73,84.12 95.27,82.58 98.1,82.58 98.7,83.17 99.73,83.17 100.83,82.08 100.83,81.78 101.12,81.49 101.47,81.49 v1(101.93,81.02)
GPIO85: length 20.4
  TOP w0.102: v1(101.21,80.02) 101.47,79.75 U6.N6
  BOTTOM w0.102: v1(101.21,80.02) 100.81,80.41 100.25,80.41 100.11,80.27 99.68,80.27 99.59,80.36 98.87,80.36 98.41,79.9 97.08,79.9 96.33,80.64 94.33,80.64 93.27,81.71 92.98,81.71 v1(92.73,81.96) 92.53,82.16 89.89,82.16 88.73,83.32 88.2,83.32 87.82,82.95 87.17,82.95 86.76,83.35 84.17,83.35 R356.2
GPIO86: length 25
  TOP w0.102: v1(102.48,79.99) 102.77,80.29 U6.L8
  BOTTOM w0.102: R345.1 84.66,86.53 v1(84.78,86.53) 84.98,86.32 88.75,86.32 90.73,84.34 93.82,84.34 95.38,82.78 98.02,82.78 98.62,83.38 100.27,83.38 100.68,82.97 101.49,82.97 101.73,82.73 101.73,81.71 101.93,81.51 102.56,81.51 102.97,81.1 102.97,80.75 102.48,80.25 v1(102.48,79.99)
GPIO87: length 18.3
  TOP w0.102: U6.R7 102.12,78.83 v1(101.88,79.08)
  BOTTOM w0.102: R361.2 86.69,82.49 87.97,82.49 88.35,82.87 88.51,82.87 90.06,81.32 90.46,81.32 90.53,81.4 v1(91.58,81.4) 91.81,81.4 92.14,81.07 93.3,81.07 94.13,80.24 96.16,80.24 96.91,79.49 98.59,79.49 98.99,79.89 99.42,79.89 99.49,79.82 99.99,79.82 100.27,79.54 101.42,79.54 v1(101.88,79.08)
GPIO88: length 24.6
  TOP w0.102: U6.L5 100.82,80.54 v1(101.29,81.01)
  BOTTOM w0.102: v1(101.29,81.01) 100.63,81.67 100.63,81.99 99.65,82.97 98.79,82.97 98.19,82.37 95.18,82.37 93.64,83.91 90.58,83.91 88.81,85.69 88.81,85.69 88.58,85.92 81.32,85.92 v2(81.15,85.75) 81.1,85.7 R351.2
GPIO89: length 24.3
  TOP w0.102: U6.N7 102.12,79.72 v1(101.84,80)
  BOTTOM w0.102: R355.2 81.79,83.76 82.19,84.17 86.54,84.17 86.81,84.43 88.2,84.43 90.04,82.59 92.98,82.59 94.52,81.05 96.5,81.05 97.25,80.3 98.24,80.3 99.12,81.19 99.96,81.19 100.23,80.92 100.23,80.77 100.39,80.61 100.91,80.61 101.1,80.42 101.42,80.42 v1(101.84,80)
GPIO90: length 21.4
  TOP w0.076: 97.61,80.8 98.54,80.8 U6.K2
  TOP w0.102: v2(81.65,87.09) 82.12,87.56 R46.2 82.62,85.71 82.95,85.38 89.07,85.38 90.68,83.77 92.78,83.77 95.08,81.48 96.66,81.48 97.38,80.75 97.56,80.75 97.61,80.8
GPIO91: length 15.4
  TOP w0.102: R49.2 85.66,86.68 v2(86.07,86.27) 86.35,85.99 89.33,85.99 90.94,84.38 93.04,84.38 95.33,82.09 97.67,82.09 97.69,82.07 97.96,82.07 U6.J1
GPIO92: length 16
  TOP w0.102: U6.K3 99.49,81.06 v1(99.82,80.73)
  BOTTOM w0.102: R357.2 86.74,84.06 87.7,84.06 87.95,83.81 v1(88.2,83.81) 88.53,83.81 89.96,82.38 92.88,82.38 94.41,80.85 96.42,80.85 97.16,80.1 98.32,80.1 99.03,80.81 99.74,80.81 v1(99.82,80.73)
GPIO93: length 14.7
  TOP w0.102: U6.J2 98.41,82.27 97.77,82.27 97.76,82.29 95.42,82.29 93.12,84.59 91.02,84.59 89.41,86.2 87.7,86.2 v2(87.39,86.5) 86.68,87.21 R50.2
GPIO94: length 12.6
  TOP w0.102: R51.2 88.04,87.56 v2(88.66,86.93) 89.14,86.45 89.44,86.45 91.06,84.84 93.16,84.84 95.49,82.51 97.66,82.51 97.74,82.59 U6.G1
H_CPU_SVIDART#: length 8.1
  TOP w0.102: R83.1 142.87,80.26 142.77,80.16 142.01,80.16 141.12,81.05 140.87,81.05 140.71,80.89 v2(140.71,80.63) 140.71,80.53 140.31,80.14 137.11,80.14 137.03,80.07 136.48,80.07 U6.L62
H_CPU_SVIDCLK: length 7.9
  TOP w0.102: R91.2 143.15,79.4 142.8,79.4 142.62,79.58 142.14,79.58 v2(141.96,79.4) 141.58,79.4 141.47,79.51 141.47,79.87 141.25,80.09 141.07,80.09 140.87,79.88 140.87,79.48 140.79,79.4 139.8,79.4 139.62,79.58 137.92,79.58 137.71,79.79 136.97,79.79 U6.N63
H_CPU_SVIDDAT: length 7.8
  TOP w0.102: R77.2 143.18,81.47 143.18,81.15 143.03,81 142.71,81 142.03,81.69 v2(141.8,81.69) 141.62,81.69 141.44,81.51 140.49,81.51 139.5,80.52 136.95,80.52 U6.L63
H_PECI: length 216
  TOP w0.102: U6.N62 136.54,79.26 136.89,79.26 137.18,79.56 137.59,79.56 v1(138,79.15) ; v1(58.55,40.38) 59.12,39.8 60.17,39.8 60.73,39.24 v2(64.96,39.24) 75.08,39.24 77.24,37.08 v1(77.34,37.08)
  IN3 w0.102: v1(138,79.15) 138.02,79.15 142.24,74.93 143.18,74.93 143.94,74.17 143.94,73.23 148.79,68.38 148.79,64.38 178.54,34.64 178.54,30.35 177.35,29.17 177.35,26.99 174.87,24.51 174.87,19.8 174.21,19.14 169.95,19.14 169.53,19.56 132.92,19.56 131.79,20.69 92.39,20.69 92.37,20.67 85.26,20.67 84.99,20.4 82.05,20.4 79.65,22.79 79.65,23.25 77.59,25.31 77.59,28.11 77.42,28.27 77.42,31.83 79.04,33.45 79.04,34.67 77.34,36.37 v1(77.34,37.08)
  BOTTOM w0.102: R513.1 58.55,41.24 v1(58.55,40.38)
H_PROCHOT#: length 266.9
  TOP w0.102: v1(150.57,80.73) 150.57,80.95 149.37,82.16 v2(149.11,82.16) 148.46,82.8 R69.1 145.42,83.31 144.15,83.31 R68.2 143.13,82.29 141.24,82.29 140.78,81.83 140.12,81.83 v1(139.32,81.03) ; v1(199.04,93.34) 199.04,92.99 PR8.2 198.13,90.69 v2(197.27,89.83) 195.6,88.16 v1(194.91,88.16) ; PQ15.3 152.02,14.63 152.26,14.87 PR64.1 153.9,15.48 v1(153.9,15.95)
  IN1 w0.114: v1(194.91,88.16) 194.91,83.15 193.55,81.79 165.89,81.79 165.01,80.91 154.24,80.91 154.06,80.73 v1(150.57,80.73)
  IN3 w0.102: v1(75.95,26.67) 76.29,26.32 76.29,25.34 81.8,19.83 85.28,19.83 85.56,20.11 130.24,20.11 132.04,18.3 151.55,18.3 v1(153.9,15.95) 154.1,15.75 171.6,15.75 175.43,19.57 175.43,24.28 178.54,27.39 178.54,29.56 179.1,30.12 179.1,34.87 149.35,64.61 149.35,68.61 144.5,73.46 144.5,74.42 143.36,75.56 142.4,75.56 140.46,77.5 140.46,79.22 139.32,80.37 v1(139.32,81.03)
  BOTTOM w0.102: v1(75.95,26.67) 75.69,26.92 Q24.3 ; PU7.30 199.02,93.37 v1(199.04,93.34)
H_PROCHOT#_R: length 7.8
  TOP w0.102: U6.K63 136.95,81.27 138.29,81.27 138.54,81.52 138.87,81.52 139.66,82.31 140.58,82.31 v2(140.65,82.38) 141.56,83.29 141.76,83.29 142.11,82.93 142.24,82.93 142.6,83.29 142.88,83.29 143,83.16 143,82.94 R68.1
H_PWRGOOD: length 13
  TOP w0.076: U6.C61 135.26,85.65 135.26,85.85 135.14,85.97 135.14,86.49 135.24,86.59 135.24,87
  TOP w0.102: R28.1 136.91,92.72 136.91,92 137.01,91.9 137.55,91.9 137.67,91.78 137.67,91.61 137.55,91.49 137.01,91.49 136.91,91.39 136.91,91.19 137.01,91.08 v1(137.25,91.08) 137.6,91.08 137.72,90.97 137.72,90.8 137.6,90.68 137.01,90.68 136.91,90.58 136.91,90.4 137.03,90.27 137.55,90.27 137.67,90.15 137.67,89.98 137.55,89.87 137.03,89.87 136.91,89.74 136.91,89.41 136.4,88.9 136.4,87.76 135.85,87.21 135.46,87.21 135.24,87
H_SYS_PWROK_XDP: length 6.3
  TOP w0.102: CN1.54 162.76,97.6 R5.2 R4.2 162.29,98.42 161.95,98.76 161.95,99.17 161.41,99.71 v2(160.7,99.71)
HDA_BCLK_R: length 10.9
  TOP w0.076: U6.AW8 102.77,64.54 102.77,63.96 102.27,63.47 102.27,62.99 101.66,62.37 101.47,62.37 101.1,62 99.59,62 99.24,61.65 99.24,60.56 99.6,60.2 99.95,60.2 100.21,59.94
  TOP w0.102: 100.21,59.94 100.71,59.44 R180.1 100.71,59.27 101.14,58.84 101.14,57.56 v1(101.13,57.55)
HDA_RST#_R: length 10.9
  TOP w0.076: v1(99.69,60.69) 99.69,60.71 99.4,61 99.4,61.4 99.83,61.84 101.21,61.84 101.57,62.2 101.73,62.2 102.44,62.92 102.44,63.15 103.35,64.06 103.35,64.96 103.16,65.15 102.87,65.15 102.73,65.29 102.73,65.84 U6.AU8
  BOTTOM w0.102: R457.1 v1(99.03,60.28) 99.45,60.69 v1(99.69,60.69)
HDA_SDO_R: length 12.8
  TOP w0.076: U6.AU11 104.18,65.79 104.18,65.39 104.1,65.31 104.1,64.06 103.93,63.89 103.65,63.89 102.77,63.01 102.77,62.78 101.22,61.23
  TOP w0.102: v1(100.33,60.63) 100.62,60.63 101.22,61.23
  BOTTOM w0.102: v1(100.33,60.63) 100.23,60.63 99.67,60.07 99.57,60.07 99.21,59.72 R456.1 99.07,59.32 98.81,59.05 98.81,58.04 99.06,57.78 99.06,57.29 R470.1
HDA_SYNC_R: length 11.7
  TOP w0.076: U6.AV11 104.52,65.4 104.27,65.15 104.27,63.98 104.02,63.73 103.72,63.73 102.93,62.94 102.93,62.64 101.47,61.18 101.47,60.6 v2(101.23,60.37) 101.17,60.3 101.17,60.2
  TOP w0.102: 101.17,60.2 101.17,59.62 101.6,59.19 C69.2 101.63,58.58 101.63,56.75 R185.1
HDMI_CLKN: length 138.9
  TOP w0.076: U6.A57 133.04,86.73 133.04,86.62 132.95,86.52 132.83,86.52 132.72,86.63 132.68,86.71 132.67,86.74 132.67,87.67 132.95,87.96 132.95,88.5 v1(133.22,88.77)
  TOP w0.102: v1(15.52,85.39) 15.3,85.18 14.72,85.18 14.49,85.41 C26.1
  IN1 w0.114: v1(133.22,88.77) 133.22,90.3 124.26,99.26 122.43,99.26 119.68,102.01 86.45,102.01 83.83,99.39 62.68,99.39 62.42,99.65 59.39,99.65 55.21,95.47 55.21,90.15 54.47,89.41 40.13,89.41 39.48,88.75 24.34,88.75 20.73,85.15 15.77,85.15 v1(15.52,85.39)
HDMI_CLKP: length 138.9
  TOP w0.076: v1(132.58,88.77) 132.79,88.56 132.79,88.03 132.5,87.74 132.5,86.71 132.53,86.65 132.59,86.53 132.59,86.53 132.76,86.36 132.9,86.36 132.96,86.3 U6.B57
  TOP w0.102: v1(15.49,84.71) 15.23,84.97 14.67,84.97 14.49,84.79 C28.1
  IN1 w0.114: v1(132.58,88.77) 133.01,89.2 133.01,90.21 124.17,99.05 122.34,99.05 119.77,101.61 119.59,101.79 86.54,101.79 83.92,99.17 62.59,99.17 62.4,99.36 62.33,99.43 59.48,99.43 55.43,95.38 55.43,90.06 54.56,89.19 40.22,89.19 39.57,88.54 24.43,88.54 20.82,84.93 15.72,84.93 v1(15.49,84.71)
HDMI_DDCCLK: length 126.4
  TOP w0.102: Q7.1 17.14,87.24 R53.1 16.44,86.53 15.59,86.53 15.37,86.31 14.07,86.31 13.84,86.54 11.94,86.54 v1(11.68,86.28) ; v1(102.41,89.76) 102.59,89.59 102.87,89.59 103.28,89.18 103.28,86.73 103.84,86.17 U6.B9
  IN1 w0.114: v1(102.41,89.76) 102.21,89.56 98.83,89.56 97.22,91.17 90.41,91.17 89.47,90.23 78.59,90.23 77.08,88.73 72.33,88.73 72.14,88.92 70.07,88.92 69.44,88.29 69.44,88.14 69.45,88.13 69.45,87.77 68.98,87.3 67.33,87.3 65.29,85.26 65.29,83.54 64.14,82.39 64.14,79.25 62.72,77.83 55.4,77.83 54.82,78.4 44.99,78.4 39.99,73.4 35.97,73.4 35.3,72.73 15.9,72.73 11.18,77.45 11.18,86.04 11.42,86.28 v1(11.68,86.28)
HDMI_DDCCLK_CN: length 15.3
  TOP w0.102: v1(15.95,91.87) 16.13,91.69 Q7.3 16.76,90.68 17.53,91.44 R29.1
  IN1 w0.114: v1(15.95,91.87) 14.12,91.87 13.39,91.14 9.78,91.14 9.19,91.72 8.11,91.72 7.73,91.34 7.73,89.59 CN2.15
HDMI_DDCDAT: length 123.7
  TOP w0.102: v1(102.41,89.13) 102.57,89.28 102.64,89.36 102.78,89.36 103.05,89.08 103.05,86.64 103.54,86.15 U6.C9 ; v1(12.31,87.21) 12.53,87 R52.1 13.46,87 Q6.1
  IN1 w0.114: v1(102.41,89.13) 102.22,89.32 98.73,89.32 97.12,90.93 90.51,90.93 89.57,89.99 78.69,89.99 77.18,88.49 72.23,88.49 72.04,88.67 70.17,88.67 69.69,88.2 69.69,87.87 69.69,87.67 69.08,87.06 69.08,87.06 67.43,87.06 65.53,85.16 65.53,83.44 64.38,82.29 64.38,79.15 62.82,77.58 55.3,77.58 54.72,78.16 45.09,78.16 40.09,73.16 36.07,73.16 35.4,72.49 15.8,72.49 10.93,77.35 10.93,86.17 11.5,86.73 11.83,86.73 v1(12.31,87.21)
HDMI_DDCDAT_CN: length 11.3
  TOP w0.102: R27.1 12.57,90.8 Q6.3 11.81,90.68 11.76,90.73 11.76,91.62 v1(11.94,91.8)
  IN1 w0.114: CN2.16 7.15,89.52 7.49,89.86 7.49,91.44 8.01,91.96 9.29,91.96 9.88,91.38 11.52,91.38 v1(11.94,91.8)
HDMI_HPD: length 124.5
  TOP w0.076: 102.11,87.25 102.27,87.09 102.27,86.62 102.72,86.17 U6.C8
  TOP w0.102: v1(101.6,92.38) 100.99,91.77 100.99,90.27 101.3,89.97 101.3,88.06 102.11,87.25
  IN1 w0.114: v1(15.36,87.47) 13.77,85.88 13.77,76.82 15.75,74.83 16.02,74.83 20.55,79.36 31.43,79.36 33.57,77.22 41.82,77.22 44.4,79.81 55.41,79.81 55.98,79.24 62.13,79.24 62.73,79.83 62.73,81.8 62.73,82.97 63.88,84.13 63.88,85.84 67.49,89.45 68.3,89.45 70.42,91.57 77.39,91.57 77.62,91.79 87.97,91.79 88.92,92.75 99.03,92.75 99.41,93.14 101.35,93.14 101.6,92.89 v1(101.6,92.38)
  BOTTOM w0.102: Q18.1 12.91,88.46 14.79,88.46 R343.1 14.84,87.98 v1(15.36,87.47)
HDMI_HPD_CN: length 6.5
  BOTTOM w0.102: R348.2 9.26,87.83 9.26,90.06 CN2.19 9.19,91.91 v2(9.41,91.91)
HDMI_HPD_CN_R: length 5.2
  BOTTOM w0.102: Q18.3 10.56,87.44 11.06,86.94 R348.1 12.07,86.82 D17.1 13.46,86.57 R349.2
HDMI_TXN0: length 143.4
  TOP w0.102: U6.B55 131.58,86.22 131.44,86.35 131.16,86.35 130.94,86.58 130.94,87.12 130.73,87.33 130.73,88.69 v1(130.52,88.9) ; C29.1 14.49,82.85 14.67,82.67 15.5,82.67 15.9,82.27 15.9,81.94 16.05,81.79 v1(16.21,81.79)
  IN1 w0.114: v1(16.21,81.79) 15.97,82.02 15.97,82.24 16.35,82.62 18.48,82.62 18.6,82.5 18.6,81.63 18.94,81.28 19.3,81.28 19.65,81.63 19.65,82.5 19.76,82.62 20.16,82.62 20.27,82.5 20.27,81.68 20.65,81.31 21.05,81.31 21.43,81.68 21.43,82.49 21.56,82.62 22.09,82.62 22.2,82.5 22.2,81.79 22.51,81.49 22.95,81.49 23.26,81.79 23.26,82.5 23.37,82.62 23.69,82.62 27.92,86.84 40.58,86.84 41.25,87.52 55.26,87.52 57.11,89.36 57.11,94.53 58.19,95.62 62.32,95.62 64.2,97.5 84.61,97.5 87.11,100 95.92,100 96.25,99.67 98.06,99.67 98.49,100.1 118.9,100.1 121.63,97.37 123.47,97.37 130.68,90.16 130.68,89.07 v1(130.52,88.9)
HDMI_TXN1: length 139.2
  TOP w0.102: C48.1 14.49,76.48 14.58,76.38 15.45,76.38 15.75,76.67 v1(15.75,76.81) ; U6.B58 133.52,87.39 133.29,87.63 v1(133.22,87.63)
  IN1 w0.114: v1(15.75,76.81) 15.75,76.71 16.14,76.31 16.32,76.31 20.22,80.21 22.58,80.21 28.59,86.22 40.84,86.22 41.24,86.62 55.24,86.62 57.73,89.11 57.73,90.84 61.78,94.9 62.48,94.9 64.46,96.88 84.87,96.88 87.04,99.05 118.51,99.05 120.91,96.65 123.31,96.65 129.87,90.09 129.87,88.06 130.85,87.08 133.29,87.08 133.45,87.25 133.45,87.46 133.28,87.63 v1(133.22,87.63)
HDMI_TXN2: length 143.7
  TOP w0.076: U6.C54 131.29,85.63 131.48,85.83 131.66,85.83 131.84,86 131.88,86.15 131.88,86.21 131.81,86.4 131.81,86.57 131.9,86.82 131.9,87.25 131.52,87.63 v1(131.44,87.63)
  TOP w0.102: C34.1 14.49,79.24 14.6,79.12 14.73,79.12 15.29,79.68 15.44,79.68 v1(15.72,79.96)
  IN1 w0.114: v1(131.44,87.63) 131.77,87.95 131.77,90.26 123.82,98.21 121.98,98.21 119.25,100.94 98.15,100.94 97.73,100.52 96.58,100.52 96.27,100.84 86.77,100.84 84.26,98.34 63.85,98.34 61.97,96.45 57.85,96.45 56.27,94.88 56.27,89.71 54.91,88.35 40.91,88.35 40.23,87.68 25.15,87.68 21.32,83.86 16.33,83.86 14.81,82.34 14.81,80.14 15.26,79.68 15.44,79.68 v1(15.72,79.96)
HDMI_TXP0: length 143.4
  TOP w0.102: v1(131.15,88.9) 130.93,88.68 130.93,87.42 131.14,87.21 131.14,86.66 131.25,86.56 131.51,86.56 131.58,86.62 U6.A55 ; v1(15.48,81.78) 15.7,82 15.7,82.19 15.42,82.46 14.67,82.46 14.49,82.28 C30.1
  IN1 w0.114: v1(131.15,88.9) 130.9,89.15 130.9,90.25 123.56,97.59 121.72,97.59 118.99,100.32 98.4,100.32 97.97,99.89 96.34,99.89 96.01,100.22 87.02,100.22 84.52,97.71 64.11,97.71 62.23,95.83 58.1,95.83 56.89,94.62 56.89,89.45 55.17,87.73 41.17,87.73 40.49,87.06 27.83,87.06 23.6,82.83 23.28,82.83 23.04,82.59 23.04,81.88 22.86,81.7 22.6,81.7 22.42,81.88 22.42,82.59 22.18,82.83 21.47,82.83 21.21,82.58 21.21,81.77 20.96,81.52 20.74,81.52 20.49,81.77 20.49,82.59 20.25,82.83 19.67,82.83 19.43,82.59 19.43,81.72 19.21,81.5 19.03,81.5 18.81,81.72 18.81,82.59 18.57,82.83 16.26,82.83 15.75,82.33 15.75,82.06 v1(15.48,81.78)
HDMI_TXP1: length 139.2
  TOP w0.102: v1(15.75,76.1) 15.67,76.17 14.72,76.17 C51.1 ; U6.C58 133.52,85.39 133.84,85.71 133.84,85.95 133.73,86.07 133.73,87.5 v1(133.86,87.63)
  IN1 w0.114: v1(133.86,87.63) 133.67,87.44 133.67,87.16 133.38,86.87 130.76,86.87 129.65,87.97 129.65,90 123.22,96.43 120.82,96.43 118.42,98.83 87.13,98.83 84.96,96.66 64.55,96.66 62.57,94.68 61.87,94.68 57.94,90.75 57.94,89.02 55.33,86.4 41.33,86.4 40.93,86 28.68,86 22.67,80 20.31,80 16.41,76.1 v1(15.75,76.1)
HDMI_TXP2: length 143.7
  TOP w0.076: v1(132.08,87.63) 132.06,87.61 132.06,86.79 131.97,86.54 131.97,86.43 132.05,86.24 132.05,86.12 131.99,85.92 131.87,85.8 131.58,85.51 U6.C55
  TOP w0.102: C46.1 14.49,78.84 14.56,78.92 14.82,78.92 15.37,79.47 15.52,79.47 v1(15.7,79.3)
  IN1 w0.114: v1(15.7,79.3) 15.53,79.46 15.35,79.46 15.18,79.46 14.59,80.05 14.59,82.43 16.24,84.07 21.23,84.07 25.06,87.9 40.14,87.9 40.82,88.57 54.82,88.57 56.05,89.8 56.05,94.97 57.76,96.67 61.88,96.67 63.76,98.55 84.17,98.55 86.68,101.05 96.36,101.05 96.67,100.74 97.64,100.74 98.06,101.16 119.34,101.16 122.07,98.42 123.91,98.42 131.98,90.35 131.98,87.73 v1(132.08,87.63)
HP_IC_L: length 18.5
  TOP w0.203: U16.32 29.91,20.86 29.43,20.39 v1(28.67,20.39)
  TOP w0.381: v1(26.23,21.2) 26.23,21.21 26.48,20.95 R302.1 26.92,20.77 27.69,19.99 R305.2 27.84,19.81 28.41,20.39 v1(28.67,20.39) ; C121.2 v1(31.12,29.08)
  IN1 w0.381: v1(31.12,29.08) 30.48,28.45 28.32,28.45 25.47,25.59 25.47,21.96 v1(26.23,21.2)
HP_IC_R: length 20.9
  TOP w0.203: U16.33 29.99,20.46 29.46,19.94
  TOP w0.381: R309.2 27.81,18.67 29.02,19.88 v1(29.4,19.88) 29.46,19.94 ; R297.1 26.54,21.97 v1(26.29,22.23) ; C122.2 v1(32.38,29.29)
  IN1 w0.381: v1(26.29,22.23) 26.29,25.34 28.56,27.61 31.47,27.61 32.38,28.52 v1(32.38,29.29)
  IN3 w0.381: v1(26.29,22.23) 26.68,22.23 29.02,19.88 v1(29.4,19.88)
HP_L: length 6.6
  TOP w0.381: L7.1 22.22,21.59 R296.1 v2(23.26,21.58) 24.72,21.58 26.49,19.81 R305.1
HP_R: length 6.2
  TOP w0.381: L8.1 22.22,19.56 R304.1 v2(25.26,19.55) 25.67,19.55 26.29,18.93 26.65,18.93 R309.1
HPL_SYS: length 12.8
  TOP w0.508: CN6.1 14.38,25.85 15.54,24.69 v2(15.54,23.69) 15.54,22.25 16.21,21.58 D11.1 C141.1 18.42,21.59 L7.2
HPOUT_JD: length 41
  TOP w0.254: v1(36.7,27.86) R293.1
  IN1 w0.254: v1(36.7,27.86) 36.7,28.2 36.13,28.77 34.61,28.77 32.31,26.47 29.79,26.47 28.59,25.26 28.59,18.34 25.23,14.99 8.56,14.99 CN6.6
HPR_SYS: length 19.2
  TOP w0.508: CN6.2 6.14,14.66 v2(12.82,14.66) 14.27,14.66 16.13,16.51 16.13,18.92 16.76,19.55 D12.1 C144.1 18.42,19.56 L8.2
HWPG: length 26.3
  IN3 w0.102: v1(42.55,44.32) 43.63,43.24 43.63,40.57 45.49,38.71 45.49,34.27 v1(45.03,33.81)
  BOTTOM w0.102: U23.84 44.96,32.77 R529.1 44.59,33.37 v1(45.03,33.81) ; v1(42.55,44.32) 41.92,44.32 v2(41.21,45.04) 41.02,45.04 40.48,45.58 40.48,46.17 D24.2 D25.2 D26.2 D27.2 D28.2
HWPG_1.2V: length 208.1
  TOP w0.102: PR42.1 191.77,58.15 189.5,58.15 187.67,59.98 187.06,59.98 186.7,60.35 v1(186.39,60.35)
  TOP w0.203: PU4.20 193.26,59.96 192.76,59.46 192.76,59.15 PR42.1
  IN1 w0.114: v1(40.69,33.53) 41.72,32.5 44.83,32.5 45.15,32.18 46.02,32.18 46.04,32.16 49.05,32.16 49.69,32.8 53.45,32.8 56.91,29.34 58.09,29.34 58.6,29.84 68.33,29.84 70.48,27.69 70.48,25.95 71.9,24.54 85.06,24.54 86.47,23.13 131.49,23.13 133.34,21.29 170.07,21.29 173.81,25.02 173.81,40.36 179.27,45.82 179.27,52.26 185.93,58.92 185.93,59.89 v1(186.39,60.35)
  BOTTOM w0.102: v1(40.69,33.53) 40.69,38.56 41.53,39.4 41.53,43.02 41.67,43.16 v2(41.67,43.83) 40,45.5 40,47.37 40.51,47.88 D24.1
HWPG_1.5V: length 59.5
  IN3 w0.508: v1(46.74,49.78) 46.48,49.53 45.88,49.53 45.51,49.9 42.94,49.9 36.9,55.94 36.9,61.41 36.64,61.66 36.64,62.55 38.8,64.71 38.8,65.49 38.95,65.65 38.95,70.41 49.82,81.28 55.12,81.28 58.05,84.21 v1(60.19,84.21)
  BOTTOM w0.508: v1(60.19,84.21) PR127.1 59.16,84.96 v2(59.12,85) 59.12,86.24 PU8.1 ; v1(46.74,49.78) 46.23,49.28 D27.1
HWPG_1.05V_S5: length 189.2
  TOP w0.254: v1(164.28,99.82) 164.46,99.82 164.72,99.57 R6.1 ; PU5.1 64.96,48.71 64.77,48.51 64.77,47.76 PR56.1 63.53,48.39 v1(62.61,48.39) ; R16.1 v2(121.88,96.47) 121.79,96.56 121.79,100.24 v1(122.17,100.63)
  IN1 w0.254: v1(164.28,99.82) 164.28,99.82 163.27,98.81 162.43,98.81 161.42,99.82 159.38,99.82 157.48,101.73 127.64,101.73 125.88,99.97 122.71,99.97 122.17,100.51 v1(122.17,100.63) ; v1(48.13,49.78) 48.51,50.16 50.22,50.16 50.61,49.77 56.81,49.77 57.14,49.44 61.08,49.44 62.13,48.39 v1(62.61,48.39)
  IN3 w0.254: v1(62.61,48.39) 64,47 67.06,47 68.27,48.2 68.27,53.1 68.94,53.77 68.94,54.42 68.27,55.09 68.27,59.81 68.66,60.21 68.66,61.36 68.59,61.43 68.59,66.55 67.06,68.08 67.06,75.18 65.53,76.71 65.53,87.12 68.27,89.86 71.95,89.86 72.46,89.35 73.6,89.35 75.94,91.68 87.9,91.68 v1(88.84,90.74)
  BOTTOM w0.254: D28.1 v1(48.13,49.78) ; v1(122.17,100.63) 120.79,102.01 99.75,102.01 97.82,100.08 91.47,100.08 87.5,96.11 87.5,92.08 v1(88.84,90.74)
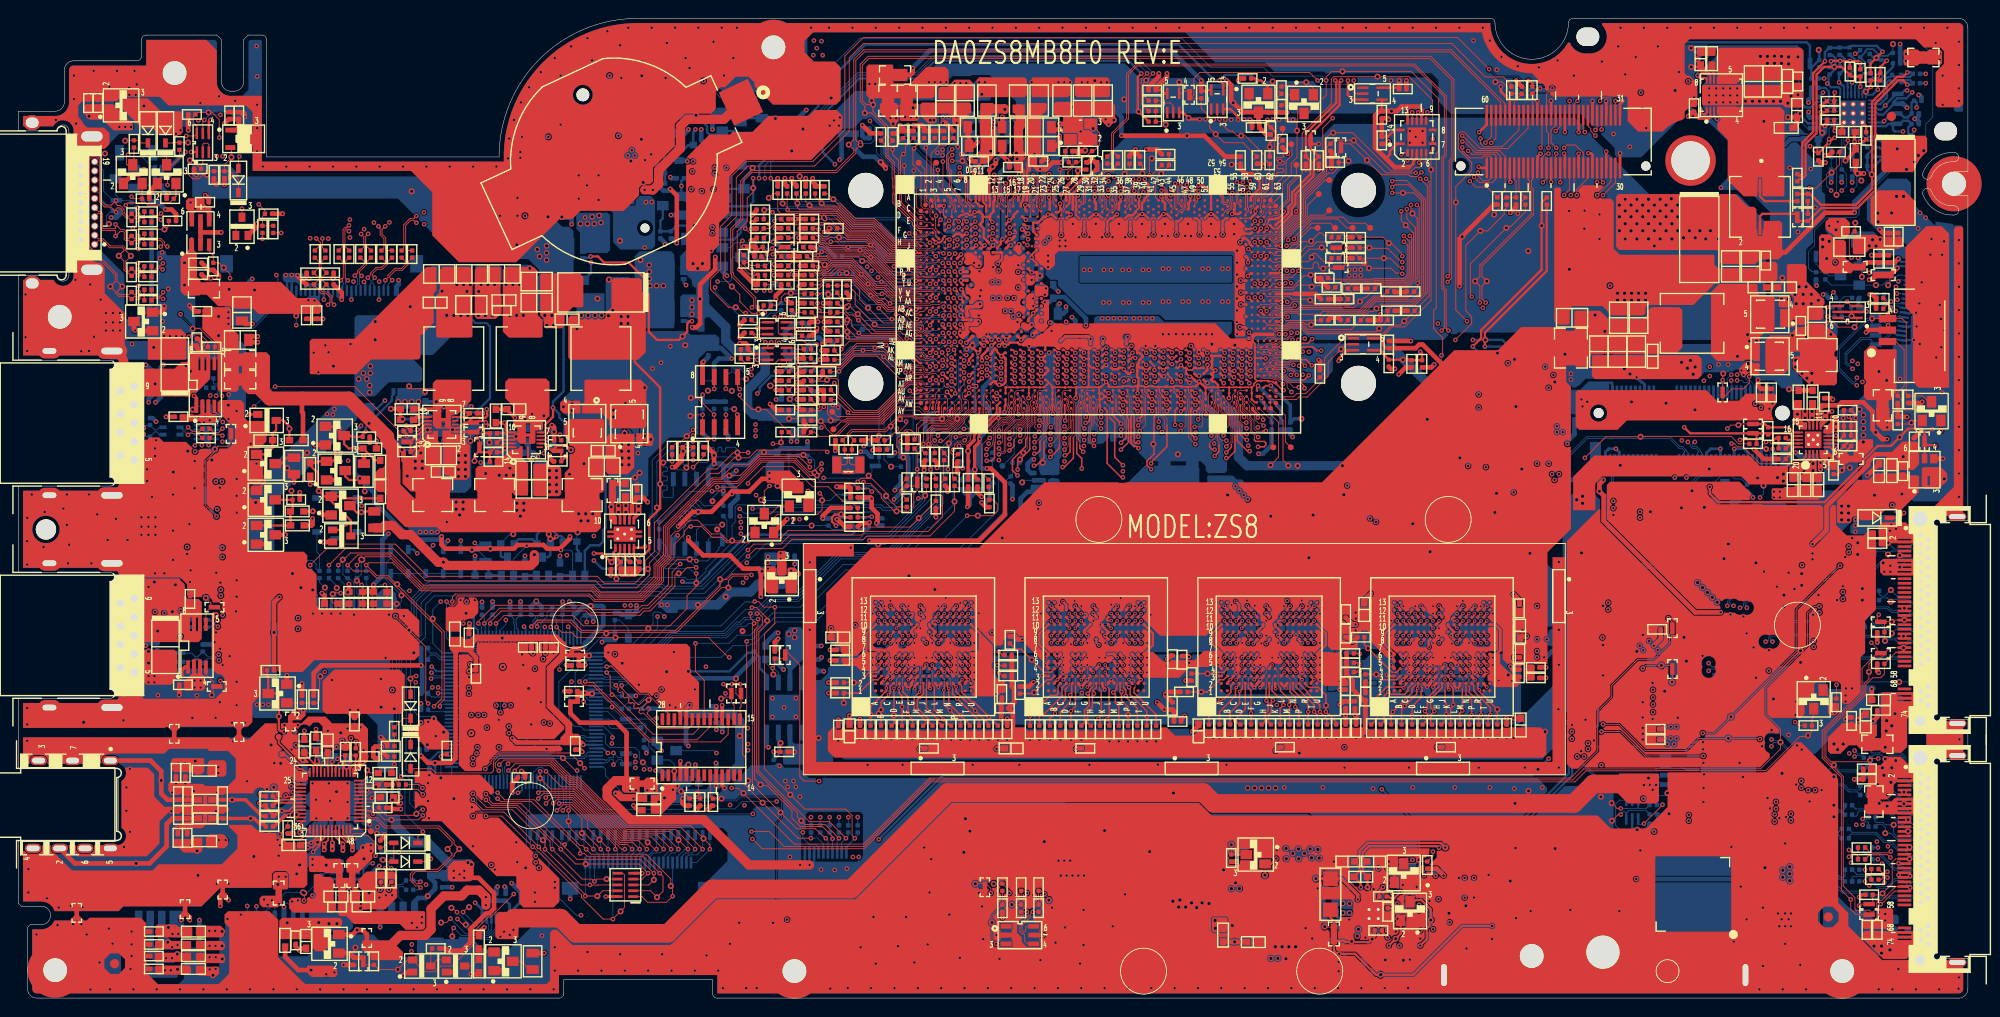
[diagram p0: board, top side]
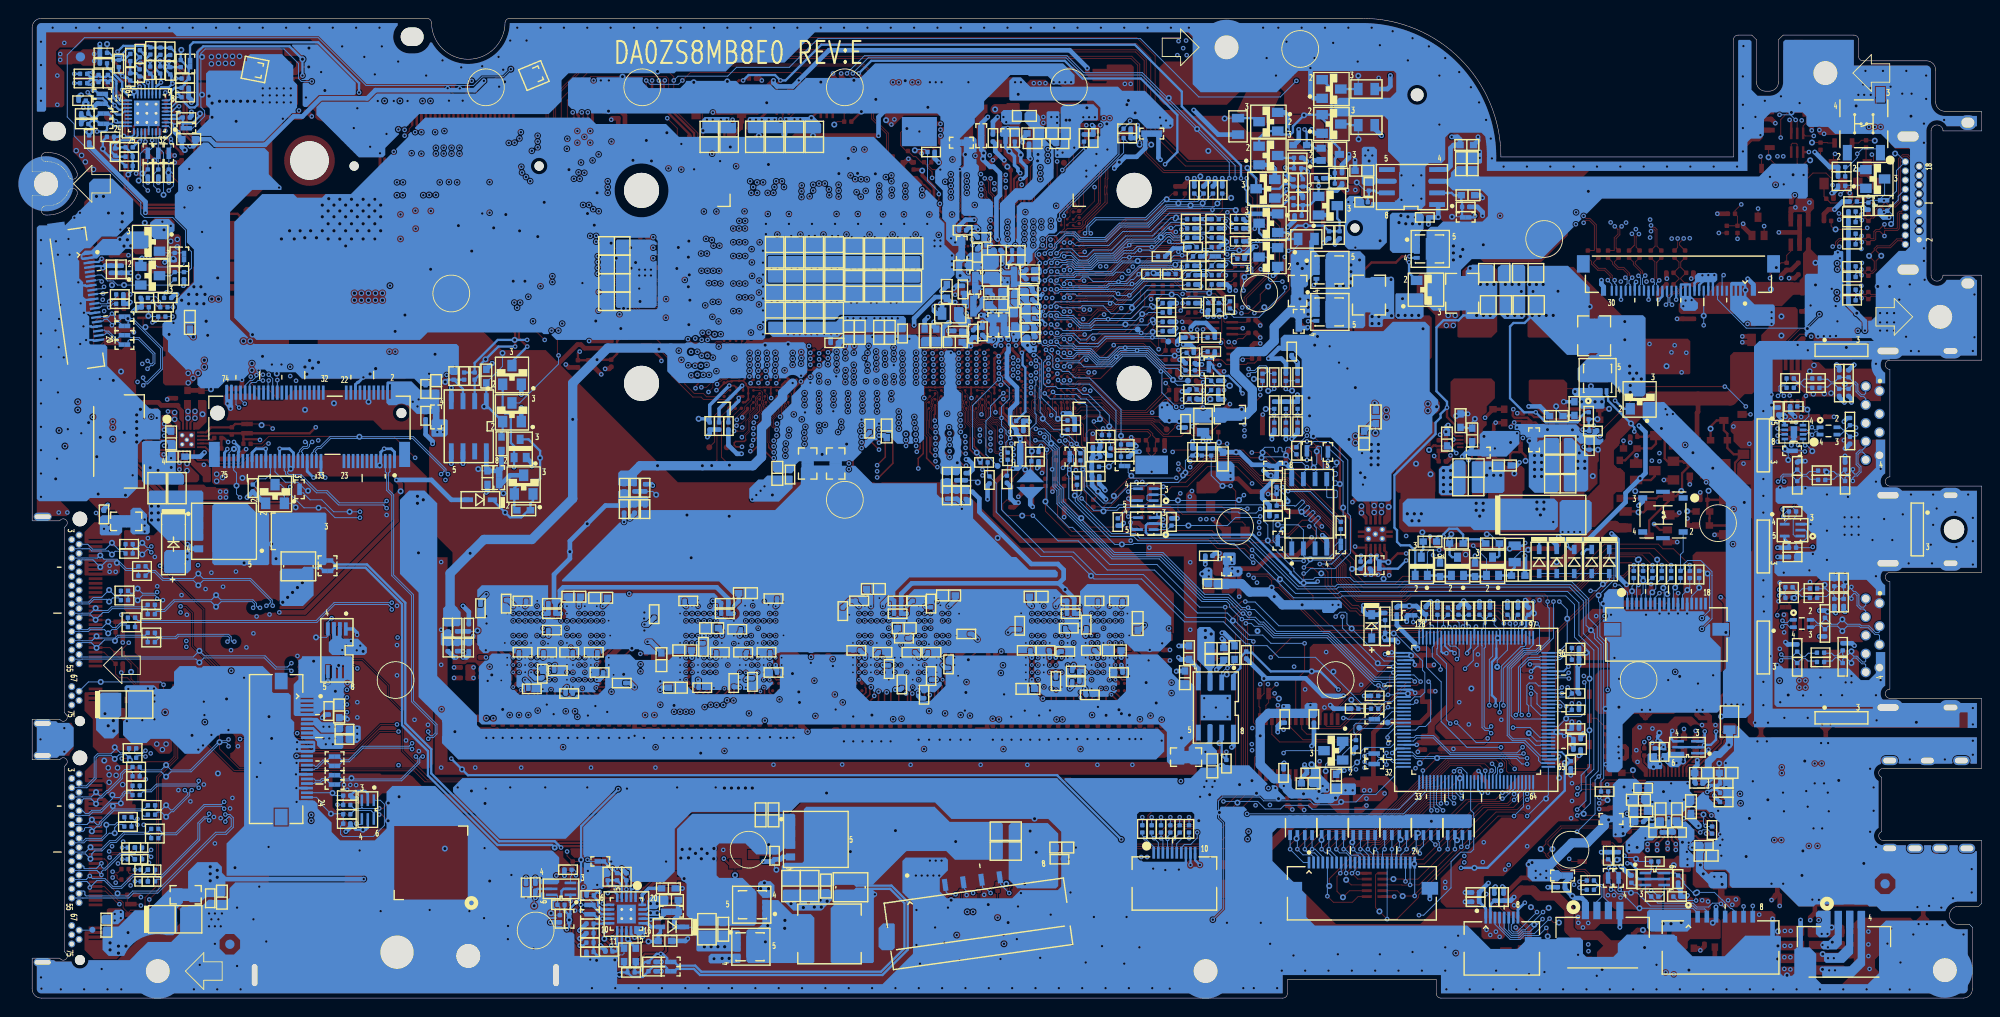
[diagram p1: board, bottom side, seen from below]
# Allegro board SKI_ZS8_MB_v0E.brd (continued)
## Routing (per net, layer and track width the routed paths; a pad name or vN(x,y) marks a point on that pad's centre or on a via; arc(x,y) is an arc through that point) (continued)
HWPG_1.8V: length 53
  IN1 w0.254: v1(59.68,48.2) 59.17,48.71 56.84,48.71 56.51,49.03 55.25,49.03 54.85,48.64 49.15,48.64 48.43,47.92 43.88,47.92 v1(43.4,48.4)
  IN3 w0.254: v1(69.98,33.58) 66.29,37.26 66.29,39.38 61.34,44.33 61.34,46.54 v1(59.68,48.2)
  BOTTOM w0.254: D25.1 42.98,48.82 v1(43.4,48.4) ; PU10.1 81.41,35.15 80.64,35.92 80.64,37.09 PR152.1 79.87,37.59 79.38,37.59 77.34,35.56 v2(72.89,35.56) 71.96,35.56 v1(69.98,33.58)
I2C_TP_SCL: length 12.2
  BOTTOM w0.102: R571.1 35.17,14.46 35.38,14.25 35.38,13.77 35.22,13.6 Q25.6 33.28,13.6 R575.1 32.38,12.71 32.38,12.45 31.45,11.51 v2(30.95,11.51) 29.06,11.51 28.22,10.67 28.19,10.67 27.95,10.43 27.95,10.4 27.3,9.75 27.18,9.75 26.9,9.48 CN15.6
I2C_TP_SDA: length 13
  BOTTOM w0.102: R576.1 37.84,12.3 Q25.3 36.58,11.68 R581.1 35.23,10.33 31.4,10.33 30.97,9.91 29.71,9.91 29.29,10.33 28.43,10.33 v1(28.36,10.26) 27.9,9.8 CN15.5
I2C_TS_SCL: length 13.6
  TOP w0.102: Q8.6 198.52,74.03 v1(199.01,73.53)
  IN3 w0.102: v1(199.01,73.53) 199.01,75.21 200.93,77.13 203.93,77.13 v1(204.38,76.67)
  BOTTOM w0.102: CN7.10 204.79,76.67 v1(204.38,76.67) ; R398.1 199.41,74.79 199.46,74.74 v2(199.46,74.23) 199.39,74.17 R400.1 198.38,73.78 198.63,73.53 v1(199.01,73.53)
I2C_TS_SDA: length 12
  TOP w0.102: v1(198.96,75.79) 199.43,75.33 Q8.3
  IN3 w0.102: v1(198.96,75.79) 200.57,77.41 v1(204.28,77.41)
  BOTTOM w0.102: v1(204.28,77.41) 204.51,77.18 204.95,77.18 CN7.9 ; v1(198.96,75.79) 198.35,75.18 R397.1 198.15,75.85 198.63,76.33 199.38,76.33 R388.1
ICLK_BIAS: length 9.2
  TOP w0.102: U6.C26 113.46,85.4 113.79,85.72 113.79,85.95 113.7,86.04 113.7,86.26 113.75,86.31 113.75,86.61 113.45,86.92 v1(113.45,87.49)
  BOTTOM w0.102: v1(113.45,87.49) 113.45,87.76 114.69,89 R342.2 114.96,92.34 115.99,92.34 v2(116.07,92.27)
ICMNT: length 122.3
  TOP w0.254: v1(150.37,11.56) 149.68,10.87 149.28,10.87 149.1,11.05 PR68.1 ; C130.1 46.22,26.53 v1(45.97,26.29)
  IN3 w0.254: v1(45.97,26.29) 49.02,23.24 69.77,23.24 74.81,18.2 76.37,18.2 78.65,15.92 93.44,15.92 95.34,17.82 114.92,17.82 120.69,12.05 131.23,12.05 131.72,12.55 149.25,12.55 150.24,11.56 v1(150.37,11.56)
  BOTTOM w0.102: v2(45.96,23.97) 45.97,23.98 v1(45.97,26.29)
  BOTTOM w0.203: v1(45.97,26.29) 46.29,25.97 U23.67
  BOTTOM w0.254: PC128.2 150.61,11.56 v1(150.37,11.56)
  BOTTOM w0.279: PU11.7 150.11,9.64 150.52,10.06 150.52,10.59 150.99,11.07 PC128.2
IMVP_PWRGD: length 92.3
  TOP w0.076: U6.C59 134.09,85.73 134.4,86.05 134.4,86.25 134.58,86.43 134.58,86.98 134.74,87.13
  TOP w0.102: U2.2 130.43,95.89 v1(130.68,95.63) 130.68,95.38 131.7,94.36 132.08,94.36 132.59,93.85 v2(133.04,93.85) 133.48,93.85 135.61,91.72 135.61,91.33 R37.1 136.14,89.66 135.76,89.28 135.76,88.16 134.74,87.13
  IN1 w0.114: v1(130.68,95.63) 130.68,95.76 132.25,97.33 150.12,97.33 150.54,97.75 158.45,97.75 159,97.2 163.58,97.2 165.46,99.08 181,99.08 v1(181.68,99.76)
  BOTTOM w0.102: PR103.1 194.64,94.67 193.34,95.97 193.34,96.57 193.74,96.97 193.74,102.81 193.26,103.29 184.7,103.29 183.12,101.72 183.12,100.07 182.82,99.76 v1(181.68,99.76)
IMVP_PWRGD_3V: length 144.1
  TOP w0.254: 89.5,52.67 89.54,52.63 89.59,52.63 89.89,52.32 R193.1 ; 89.5,52.67 v2(89.5,52.65) ; 89.5,52.67 89.46,52.63 88.82,52.63 88.52,52.32 88.52,51.85 v1(88.96,51.41) ; R2.2 134.53,100.08 v1(134.75,99.86) 135.21,99.86 135.93,99.14 Q1.2 ; U2.4 131.08,99.47 v1(130.68,99.86)
  IN3 w0.254: v1(80.58,89.22) 80.58,88.46 78.16,86.03 78.16,82.47 77.01,81.33 77.01,79.68 75.03,77.7 75.03,72.75 71.6,69.32 71.6,61.92 72.03,61.48 72.03,57.16 72.36,56.83 72.36,50.83 72.21,50.67 72.21,48.46 71.53,47.78 71.53,46.05 v1(72.24,45.34)
  BOTTOM w0.254: v1(72.24,45.34) 72.39,45.19 74.14,45.19 75.18,46.23 75.18,46.36 79.26,50.43 90.69,50.43 90.93,50.67 90.93,51.44 90.73,51.64 U20.2 89.41,51.64 89.33,51.56 89.11,51.56 v1(88.96,51.41) ; v1(80.58,89.22) 80.58,90.62 87.02,97.05 87.02,98.65 92.13,103.76 126.24,103.76 130.13,99.86 v1(130.68,99.86) 131.28,100.46 134.15,100.46 v1(134.75,99.86)
INT_AMIC-VREFO: length 4.8
  TOP w0.203: v1(29.69,23.04) 30.05,23.04 30.23,22.86 U16.27
  BOTTOM w0.102: C373.1 28.55,25.53 v2(28.54,25.54)
  BOTTOM w0.381: C373.1 28.55,24 28.46,23.91 R546.2 28.69,23.14 29.54,23.14 29.64,23.04 v1(29.69,23.04)
IRQ_SERIRQ: length 111
  TOP w0.102: U6.T4 100.14,78.03 v1(99.82,77.72) ; U15.27 70.72,31.01 70.57,31.16 70.42,31.16 68.5,33.07 67.58,33.07 64.58,36.07 v1(64.01,36.07)
  IN1 w0.114: v1(99.82,77.72) 99.32,77.22 97.49,77.22 97.26,77.45 93.53,77.45 90.67,80.31 88.35,80.31 87.65,81.01 85.94,81.01 85.57,81.38 83.22,81.38 82.73,81.86 80.85,81.86 80.35,81.36 77.53,81.36 73.08,76.91 68.91,76.91 68.58,76.58 68.58,71.88 71.26,69.2 71.26,59.83 70.61,59.18 70.61,57.69 71.26,57.04 71.26,56.36 74.76,52.86 74.76,46.34 70.59,42.16 70.19,42.16 v1(69.55,41.52)
  BOTTOM w0.102: v1(99.82,77.72) 99.82,77.95 99.57,78.2 98.09,78.2 97.82,78.48 97.17,78.48 96.67,77.98 93.12,77.98 91.55,79.54 88.15,79.54 87.82,79.21 87.34,79.21 87.26,79.14 86.86,79.14 86.43,79.56 R372.2 ; v1(69.55,41.52) 69.55,40.28 v2(65.7,36.44) 65.46,36.2 64.14,36.2 v1(64.01,36.07) 63.91,35.97 U23.5
L_SPK+: length 18.4
  TOP w0.203: v1(33.27,16.76) 33.71,17.2 U16.42
  IN3 w1.016: 32.94,15.57 32.94,10.79 29.52,7.37 22.48,7.37
  vias: v1(20.78,7.32) v1(21.41,7.32) v1(33.27,16.13) v2(22.16,7.25)
L_SPK-: length 19.1
  TOP w0.203: U16.43 34.11,16.95 v1(34.16,16.89)
  IN3 w1.016: 22.48,5.97 30.1,5.97 34.34,10.21 34.34,14.22
  vias: v1(20.8,5.69) v1(21.44,5.69) v1(34.16,16.26) v2(22.16,5.68)
LCD_BL_ON: length 54.1
  TOP w0.102: v1(24.05,91.59) 23.94,91.48 D4.2 ; Q4.3 v1(24.32,85.92) ; v1(18.26,93.83) 19.18,93.83 19.42,94.07 Q5.6 19.42,94.91 19.07,95.26 19.07,95.97 R14.1 19.48,96.38 v2(20.69,96.38) 21.08,96.38 21.86,95.61 v1(21.86,93.64)
  IN2 w0.114: v1(24.32,85.92) 24.32,91.32 v1(24.05,91.59)
  IN3 w0.102: v1(18.26,93.83) 17.42,92.99 17.42,74.65 v1(17.65,74.42) ; v1(21.86,93.64) 22.93,93.64 24.05,92.51 v1(24.05,91.59)
  BOTTOM w0.102: CN8.7 28.74,76.04 25.6,72.91 19.04,72.91 17.65,74.3 v1(17.65,74.42)
LCD_VCC:
  vias: v1(31.55,75.96) v1(32.21,75.91) v1(32.46,75.3) v2(22.93,77.13) v2(25.69,77.05)
LCD_VCC_S:
  vias: v2(18.07,80.03) v2(18.07,77.61)
LCD_VIN:
  vias: v1(22.85,74.64) v1(22.85,74.01) v1(22.85,73.37) v2(21.78,74.18) v2(21.78,72.1)
LID1#: length 84.4
  TOP w0.102: D4.1 23.94,89.12 23.07,89.99 D5.2 ; D5.2 22.42,90.69 23.18,91.46 v2(23.18,91.51) 23.18,92.44 HE1.2 ; D5.2 R45.1 20.47,89.99 19.65,89.17 18.96,89.17 18.34,89.79 16.93,89.79 16.22,89.08 v1(16.22,88.48)
  IN3 w0.102: v1(16.22,88.48) 16.22,88.48 16.71,87.99 16.71,74.09 17.09,73.71 18.96,73.71 28.35,64.33 28.35,60.62 34.06,54.91 34.06,52.59 37.45,49.2 38.68,49.2 43.83,44.05 43.83,40.88 45.9,38.81 45.9,34.04 v1(45.67,33.81)
  BOTTOM w0.102: v1(45.67,33.81) 45.91,33.57 U23.86
LID2#: length 46.5
  TOP w0.102: v2(47.21,6.72) 47.21,7.48 v1(47.36,7.64)
  IN1 w0.114: v1(52.02,31.85) 49.69,31.85 47.75,29.91 47.75,24.93 45.72,22.9 45.72,9.28 v1(47.36,7.64)
  BOTTOM w0.102: v1(47.36,7.64) 48.19,6.81 49.76,6.81 50.19,6.39 51.3,6.39 52.95,8.04 CN18.3 ; U23.97 48.79,38.46 49.2,38.05 49.89,38.05 52.04,35.89 52.04,31.88 v1(52.02,31.85)
LINE1L-VREFO: length 3.2
  TOP w0.203: U16.31 28,21.26
  TOP w0.381: 28,21.26 R302.2
LINE1L_R: length 4.3
  TOP w0.102: C121.1 31.12,27.21 30.8,27.53 v1(30.19,27.53)
  TOP w0.203: C121.1 31.12,26.57 32.51,25.18 U16.22
LINE1R-VREFO: length 4.3
  TOP w0.102: R297.2 27.69,22.84 v2(27.78,22.93)
  TOP w0.203: U16.30 30.22,21.66 30.15,21.59 28.35,21.59 28.27,21.66 28,21.66 R297.2
LINE1R_R: length 2.8
  TOP w0.203: 32.45,25.8 32.45,26.09 32.38,26.15 C122.1 ; 32.45,25.8 32.45,25.67 32.91,25.21 U16.21 ; 32.45,25.8 v1(32.45,26.03)
LINE2-L: length 3.8
  TOP w0.203: TP18.1 28.96,26.54 30.58,24.92 30.89,24.92 31.24,24.56 U16.24
LINE2-R: length 6.1
  TOP w0.203: U16.23 32.11,25.15 31.88,25.37 30.71,25.37 28.32,27.76 TP17.1
LM393_PIN2: length 27.1
  TOP w0.254: PR17.2 166.28,79.14 159.55,72.41 v1(159.55,70.91)
  BOTTOM w0.254: PU9.2 PR132.2 163.33,67.93 163.33,68.95 v2(162.77,69.51) 161.38,70.91 v1(159.55,70.91)
LPC_LAD0: length 104.6
  TOP w0.076: v1(102.44,61.49) 103.18,61.49 105.02,63.33 105.02,65.59 105.27,65.84 105.73,65.84 U6.AU14
  TOP w0.102: v1(65.63,34.04) 65.63,33.71 67.41,31.94 67.56,31.94 68.08,32.46 68.25,32.46 68.37,32.34 68.37,32.17 67.84,31.65 67.84,31.5 67.99,31.36 68.13,31.36 68.47,31.7 68.63,31.7 68.75,31.58 68.75,31.41 68.42,31.07 68.42,30.93 69.79,29.55 71.21,29.55 71.37,29.71 U15.26 ; v1(79.64,41.86) 79.64,41.37 80.05,40.96 v1(80.05,40.78) 80.05,40.71 79.86,40.51 79.86,23.27 v2(82.93,20.2) 84.68,18.44 86.7,18.44 87.75,17.39 v1(87.85,17.39)
  BOTTOM w0.102: v1(79.64,41.86) 79.76,41.86 80.15,42.26 80.6,42.26 81.95,43.61 84.55,43.61 89.2,48.26 94.43,48.26 100.15,53.99 100.15,55.41 100.58,55.84 100.58,59.78 101.55,60.75 101.55,61.21 101.83,61.49 v1(102.44,61.49) ; v1(80.05,40.78) 79.47,40.78 79.15,40.46 78.31,40.46 77.07,39.22 71.23,39.22 66.05,34.04 v1(65.63,34.04) 65.23,33.63 64.8,33.63 64.46,33.97 U23.10 ; R562.1 87.25,17.99 v1(87.85,17.39) 88.07,17.16 CN14.5
LPC_LAD0_C: length 142.5
  IN1 w0.114: v1(87.25,19.68) 88.98,21.42 115.78,21.42 116.5,22.14 131.08,22.14 132.93,20.29 170.5,20.29 174.83,24.62 174.83,39.98 180.26,45.41 180.26,49.66 185.17,54.57 185.17,57.27 187.37,59.48 187.37,66.83 v1(186.99,67.21)
  BOTTOM w0.102: CN9.64 188.43,66.8 188.23,67 187.75,67 187.53,67.21 v1(186.99,67.21) ; v1(87.25,19.68) R562.2
LPC_LAD1: length 104.4
  TOP w0.076: U6.AW12 105.6,64.54 105.6,64.06 105.35,63.81 105.35,63.19 103.26,61.11 103.26,61.02 v1(102.95,60.71)
  TOP w0.102: v1(65,34.04) 65,34.03 65.28,33.74 65.28,33.6 65.22,33.54 65.22,33.4 65.37,33.25 65.51,33.25 65.57,33.31 65.71,33.31 65.86,33.17 65.86,33.02 65.8,32.97 65.8,32.82 65.94,32.68 66.08,32.68 66.14,32.74 66.29,32.74 66.43,32.59 66.43,32.45 66.37,32.39 66.37,32.25 66.52,32.1 66.66,32.1 66.72,32.16 66.86,32.16 67.01,32.02 67.01,31.87 66.95,31.82 66.95,31.67 67.09,31.53 67.24,31.53 67.29,31.59 67.44,31.59 67.58,31.44 67.58,31.3 67.52,31.24 67.52,31.1 67.67,30.95 67.81,30.95 67.87,31.01 68.01,31.01 69.7,29.33 72.89,29.33 73.32,29.76 U15.23 ; v1(88.57,17.34) 88.57,17.58 87.48,18.67 85.07,18.67 84.17,19.57 84.17,20.43 81.44,23.15 80.81,23.15 v2(80.74,23.23) 80.09,23.87 80.09,40.07 80.46,40.44 80.46,41.21 v1(80.48,41.24)
  BOTTOM w0.102: CN14.4 v1(88.57,17.34) 88.57,17.58 88.27,17.89 R563.1 ; v1(102.95,60.71) 102.87,60.63 102.08,60.63 101.04,59.59 101.04,55.65 100.61,55.22 100.61,53.8 94.61,47.8 89.48,47.8 84.83,43.15 82.14,43.15 81.81,42.82 81.81,42.57 v1(80.48,41.24) 80.43,41.19 79.15,41.19 78.65,40.69 78.22,40.69 76.97,39.45 71.13,39.45 66.15,34.47 65.43,34.47 v1(65,34.04) 64.67,34.37 U23.9
LPC_LAD1_C: length 143.3
  IN1 w0.114: v1(186.99,67.84) 187.61,67.23 187.61,59.38 185.41,57.17 185.41,54.47 180.5,49.56 180.5,45.31 175.08,39.9 175.08,24.54 170.6,20.05 132.83,20.05 130.98,21.9 116.6,21.9 115.88,21.18 89.76,21.18 v1(88.27,19.68)
  BOTTOM w0.102: v1(186.99,67.84) 187.66,67.84 v1(187.7,67.81) 187.7,67.66 188.13,67.22 188.38,67.22 188.93,66.68 CN9.66 ; v1(88.27,19.68) R563.2
LPC_LAD2: length 109.8
  TOP w0.076: v1(101.98,61.06) 102.61,61.06 102.76,61.2 103.12,61.2 105.18,63.26 105.18,64.06 U6.AY12
  TOP w0.102: U15.20 75.27,29.55 73.83,28.11 68.79,28.11 62.55,34.34 61.78,34.34 v1(61.67,34.45) ; v1(80.36,41.85) 80.58,41.85 80.94,41.49 80.94,40.6 80.32,39.98 80.32,24.6 84.75,20.17 84.75,19.73 v2(85.17,19.31) 85.58,18.9 87.77,18.9 v1(89.28,17.39)
  BOTTOM w0.102: v1(61.67,34.45) 61.99,34.77 U23.8 63.63,34.77 63.7,34.7 66.06,34.7 71.04,39.67 76.88,39.67 78.12,40.92 78.49,40.92 79.01,41.44 79.82,41.44 80.23,41.85 v1(80.36,41.85) 80.57,41.85 81.54,42.82 81.54,42.88 82.05,43.38 84.68,43.38 89.32,48.03 94.52,48.03 100.38,53.89 100.38,55.31 100.81,55.75 100.81,59.69 101.98,60.85 v1(101.98,61.06) ; R564.1 v1(89.28,17.39) 89.07,17.18 CN14.3
LPC_LAD2_C: length 137.7
  IN1 w0.114: v1(89.28,19.68) 90.53,20.94 115.98,20.94 116.7,21.66 130.88,21.66 132.73,19.81 170.7,19.81 175.39,24.5 175.39,39.86 180.74,45.21 180.74,49.46 185.65,54.37 185.65,57.07 187.85,59.28 187.85,63.57 v1(188.97,64.68)
  BOTTOM w0.102: v1(89.28,19.68) R564.2 ; CN9.68 189.43,65.14 v1(188.97,64.68)
LPC_LAD3: length 116
  TOP w0.076: U6.AW11 104.85,64.54 104.85,63.4 103.4,61.95 v1(102.9,61.95)
  TOP w0.102: v1(61.04,34.44) 61.44,34.04 62.53,34.04 68.69,27.88 76.39,27.88 77.22,28.71 U15.17 ; v1(90.03,17.4) 88.23,19.2 86.04,19.2 80.55,24.69 80.55,39.89 81.46,40.79 v2(81.46,41.07) 81.46,41.34 80.31,42.49 v1(79.81,42.49)
  BOTTOM w0.102: v1(102.9,61.95) 101.96,61.95 101.32,61.32 101.32,60.84 100.36,59.88 100.36,55.94 99.92,55.5 99.92,54.08 94.33,48.49 89.07,48.49 84.52,43.94 81.91,43.94 80.47,42.49 v1(79.81,42.49) 79.6,42.29 79.09,42.29 76.71,39.9 70.94,39.9 65.96,34.92 63.8,34.92 63.56,35.17 U23.7 61.76,35.17 v1(61.04,34.44) ; CN14.2 89.57,16.94 v1(90.03,17.4) 90.3,17.66 R565.1
LPC_LAD3_C: length 137.1
  IN1 w0.114: v1(90.3,19.68) 91.31,20.69 116.08,20.69 116.8,21.42 130.78,21.42 132.63,19.57 170.8,19.57 175.64,24.41 175.64,39.77 180.98,45.11 180.98,49.36 185.89,54.27 185.89,56.97 188.09,59.18 188.09,62.77 v1(189.59,64.26)
  BOTTOM w0.102: CN9.70 189.93,64.6 v1(189.59,64.26) ; v1(90.3,19.68) R565.2
LPC_LFRAME#: length 111.6
  TOP w0.076: U6.AV12 105.35,65.22 105.77,64.81 105.77,63.98 105.52,63.74 105.52,63.14 103.62,61.23 103.62,60.79 103.1,60.27 102.74,60.27 102.51,60.5
  TOP w0.102: 102.51,60.5 102.17,60.5 101.88,60.21 101.88,59.86 v1(101.7,59.68) ; v1(64.01,35.43) 64.39,35.05 64.39,33.37 69.04,28.72 73.4,28.72 73.97,29.29 U15.22 ; v1(80.11,43.15) 80.52,43.15 81.13,42.55 v1(82.3,42.55) 82.3,40.77 81.16,39.63 81.16,24.94 83.99,22.12 v2(83.99,22.14) 85.56,20.56 90.01,20.56 90.7,19.87 90.7,17.68 v1(91,17.39)
  BOTTOM w0.102: CN14.1 90.07,16.46 v1(91,17.39) 91.31,17.7 R566.2 ; v1(80.11,43.15) 80.06,43.1 79.04,43.1 76.45,40.51 70.66,40.51 65.71,35.56 64.14,35.56 v1(64.01,35.43) 63.87,35.57 U23.6 ; v1(101.7,59.68) 101.7,53.65 99.28,51.23 98.91,51.23 94.87,47.19 89.73,47.19 85.08,42.55 v1(82.3,42.55)
LPC_LFRAME#_C: length 132.2
  IN1 w0.114: v1(91.31,19.68) 91.7,20.07 116.34,20.07 117.06,20.8 130.52,20.8 132.37,18.95 171.06,18.95 176.26,24.15 176.26,34.53 178.78,37.05 178.78,42.04 181.6,44.86 181.6,49.1 186.51,54.01 186.51,55.19 190.14,58.83 v3(190.14,59.77)
  BOTTOM w0.102: v3(190.14,59.77) 190.25,59.77 190.68,59.34 CN9.73 ; v1(91.31,19.68) R566.1
MA_AMA0: length 72.3
  TOP w0.076: v1(121.39,67.13) 121.39,67.27 121.03,67.62 120.09,67.62 U6.AR36
  TOP w0.165: R258.2 v2(160.91,31.42) 158.95,33.37 v6(158.95,33.53) 158.79,33.69 U14.R2
  IN1 w0.191: v1(121.39,67.13) 122.01,66.51 123.76,66.51 124.44,67.19 124.95,67.19 126.09,68.33 128.07,68.33 128.17,68.22 128.68,68.22 129.06,67.84 129.36,67.84 130.07,67.13 130.23,67.13 130.9,66.45 133.59,66.45 133.86,66.18 136.08,66.18 136.57,65.69 137.19,65.69 143.74,59.14 144.93,59.14 146.23,57.83 147.09,57.83 163.16,41.76 163.16,40.91 163.2,40.87 163.2,36.01 160.64,33.44 159.05,33.44 v6(158.95,33.53)
MA_AMA1: length 68.4
  TOP w0.076: U6.AU40 122.23,65.93 122.64,65.52 122.64,62.37 v1(122,61.72)
  TOP w0.165: R257.2 159.89,30.55 v1(160.14,30.81) 160.14,31.62 158.37,33.4 158.37,34.02 U14.P2
  IN1 w0.191: v1(122,61.72) 122.1,61.72 123.88,59.94 124.72,59.94 127.21,57.45 128.05,57.45 133.26,52.25 138.06,52.25 145.39,44.92 145.39,42.8 146.25,41.94 146.25,39.1 147.14,38.21 147.14,32.43 149.83,29.74 159.08,29.74 v1(160.14,30.81)
MA_AMA2: length 67.9
  TOP w0.076: U6.AV40 122.28,65.49 122.48,65.29 122.48,62.97 v1(121.83,62.32)
  TOP w0.165: U14.N2 157.49,33.01 158.11,32.39 v1(158.11,30.81) 157.86,30.55 R255.2
  IN1 w0.191: v1(121.83,62.32) 122.05,62.32 124.04,60.34 124.75,60.34 127.15,57.94 128.13,57.94 131.01,55.06 131.25,55.06 131.67,55.48 131.92,55.48 132.1,55.3 132.1,55.06 131.67,54.64 131.67,54.39 131.85,54.21 132.1,54.21 132.52,54.64 132.77,54.64 132.94,54.46 132.94,54.21 132.52,53.79 132.52,53.54 133.21,52.86 138.06,52.86 145.81,45.11 145.81,43.04 146.66,42.19 146.66,39.34 147.55,38.46 147.55,32.72 148.83,31.43 149.8,31.43 150.13,31.76 150.5,31.76 150.83,31.43 151.7,31.43 152.03,31.76 155.41,31.76 156.84,30.33 157.63,30.33 v1(158.11,30.81)
MA_AMA3: length 66.1
  TOP w0.076: U14.N3 157.82,34.72 157.82,33.99 157.86,33.96
  TOP w0.165: 157.86,33.96 157.86,33.28 159.13,32.01 v1(159.13,30.81) 158.87,30.55 R256.2 ; U6.AY39 121.44,64.19 v1(121.76,63.86)
  IN1 w0.191: v1(159.13,30.81) 159.13,31.37 158.69,31.81 158.38,31.81 157.35,30.78 156.95,30.78 155.57,32.16 148.69,32.16 147.94,32.91 147.94,38.87 147.14,39.67 147.14,42.34 146.23,43.26 146.23,46.15 138.09,54.29 134.79,54.29 132.36,56.72 129.93,56.72 128.41,58.24 127.27,58.24 124.78,60.73 124.04,60.73 122.72,62.05 122.72,62.76 122.16,63.32 122.16,63.46 v1(121.76,63.86)
MA_AMA4: length 68.8
  TOP w0.076: 157.1,33.68 157.17,33.76 157.17,34.72 U14.M3
  TOP w0.165: 157.1,33.68 v1(157.1,31.29) 156.84,31.03 R254.2 ; v1(121.76,64.53) 121.76,64.53 121.76,64.54 121.46,64.84 U6.AW39
  IN1 w0.191: v1(157.1,31.29) 155.82,32.56 154.86,32.56 154.56,32.86 148.7,32.86 148.34,33.22 148.34,39.32 147.62,40.03 147.62,42.7 146.68,43.65 146.68,46.87 138.22,55.32 137.98,55.32 137.63,54.97 137.38,54.97 137.2,55.15 137.2,55.39 137.56,55.75 137.56,55.99 137.38,56.17 137.13,56.17 136.17,55.2 135.92,55.2 135.74,55.38 135.74,55.62 136.17,56.05 136.17,56.78 135.83,57.12 134.81,57.12 134.63,56.94 134.63,55.89 134.46,55.71 134.21,55.71 134.04,55.89 134.04,56.94 133.86,57.12 129.96,57.12 128.53,58.55 127.38,58.55 124.8,61.13 124.04,61.13 123.11,62.05 123.11,62.76 122.44,63.43 122.44,63.85 v1(121.76,64.53)
MA_AMA5: length 69.8
  TOP w0.076: v6(152.61,34.65) 152.61,33.9
  TOP w0.165: 152.61,33.9 152.73,33.78 152.73,33.44 152.61,33.32 152.61,32.72 151.63,31.75 v1(151.63,30.75) R249.2 ; v6(152.61,34.65) 152.94,34.98 U14.F3 ; v1(123.36,63.88) 123.05,64.19 U6.AY41
  IN1 w0.076: 131.56,63.31 131.21,63.66 130.29,63.66 129.06,62.43 128.27,62.43 127.53,63.17 124.74,63.17 124.03,63.88 v1(123.36,63.88)
  IN1 w0.191: 131.56,63.31 132.11,62.76 132.11,60.49 133.9,58.69 139.16,58.69 143.94,53.91 146.52,53.91 151.26,49.17 151.26,44.55 151.42,44.39 154.9,44.39 155.07,44.22 155.07,43.98 154.9,43.81 151.42,43.81 151.26,43.65 151.26,43.41 151.42,43.24 154.83,43.24 155.04,43.04 155.04,40.03 154.99,39.98 154.99,38.49 154.33,37.83 154.33,35.28 154.1,35.05 153.01,35.05 v6(152.61,34.65)
MA_AMA6: length 73.3
  TOP w0.076: 151.96,34 v6(151.96,34.65)
  TOP w0.165: v6(151.96,34.65) 152.29,34.98 U14.E3 ; U6.AU41 123.03,66.14 v1(123.33,65.84) ; 151.96,34 151.64,33.68 151.64,33.25 v1(149.53,31.14) 149.35,30.96 R247.2
  IN1 w0.191: v6(151.96,34.65) 152.36,34.25 154.42,34.25 154.49,34.19 159.51,34.19 159.61,34.29 160.18,34.29 161.78,35.89 161.78,40.11 162,40.34 162,42.09 146.65,57.44 144.68,57.44 138.14,63.98 137.67,63.98 135.86,65.79 133.69,65.79 133.42,66.06 129.57,66.06 129,66.63 127.73,66.63 127.62,66.52 126.97,66.52 126.86,66.63 125.74,66.63 125.68,66.57 124.56,66.57 123.83,65.84 v1(123.33,65.84)
MA_AMA7: length 70.5
  TOP w0.165: R248.2 150.49,31.45 v1(150.82,31.78) 152.15,33.11 152.15,33.6 v6(152.25,33.71) 152.25,34.21 U14.E2 ; U6.AW41 123.05,64.84 v1(123.36,64.53)
  IN1 w0.191: v1(123.36,64.53) 122.89,64.06 122.89,63.63 123.12,63.39 124.09,63.39 124.61,62.86 124.61,62.64 127.76,59.49 128.93,59.49 130.12,58.3 138.87,58.3 143.65,53.52 144.72,53.52 149.12,49.11 149.12,48.43 149.33,48.22 150.51,48.22 150.69,48.04 150.69,47.79 150.51,47.62 148.9,47.62 148.73,47.44 148.73,47.2 148.9,47.02 150.51,47.02 150.69,46.85 150.69,46.6 150.51,46.43 149.53,46.43 149.35,46.25 149.35,46 149.53,45.83 150.51,45.83 150.69,45.65 150.69,45.41 150.51,45.23 149.72,45.23 149.54,45.06 149.54,44.81 149.72,44.64 150.51,44.64 150.69,44.46 150.69,44.21 150.51,44.04 149.72,44.04 149.54,43.86 149.54,43.24 148.96,42.67 148.96,40.9 149.43,40.44 151.74,40.44 152.12,40.05 152.12,38.13 151.65,37.66 150.43,37.66 150.22,37.44 150.22,34.49 150.51,34.19 151.76,34.19 v6(152.25,33.71)
MA_AMA8: length 70.6
  TOP w0.076: v1(124.41,61.59) 124.7,61.88 124.7,63 124.22,63.49 124.22,64.06 124.22,64.06 124.22,64.31 124.22,64.31 124.22,64.71 124.22,64.72 124.22,64.96 124.22,64.96 124.22,65.36 124.22,65.37 124.22,65.46 123.81,65.87 U6.AU42
  TOP w0.165: R246.2 148.59,30.16 148.59,32.87 v1(149.07,33.35) 149.35,33.07 150.82,33.07 151.18,33.42 151.18,33.74 151.64,34.2 U14.D2
  IN1 w0.191: v1(124.41,61.59) 124.75,61.59 127.5,58.85 128.64,58.85 129.98,57.51 136.6,57.51 137.37,56.74 137.61,56.74 138.13,57.26 138.38,57.26 138.56,57.09 138.56,56.84 138.03,56.32 138.03,56.07 138.21,55.9 138.46,55.9 138.98,56.42 139.2,56.42 139.4,56.22 139.4,56 138.88,55.47 138.88,55.23 139.05,55.05 139.3,55.05 139.82,55.57 140.07,55.57 140.25,55.4 140.25,55.15 139.72,54.63 139.72,54.38 139.9,54.21 140.15,54.21 140.67,54.73 140.91,54.73 141.09,54.55 141.09,54.31 140.57,53.79 140.57,53.54 140.74,53.36 140.99,53.36 141.51,53.89 141.76,53.89 141.93,53.71 141.93,53.46 141.41,52.94 141.41,52.69 141.59,52.52 141.83,52.52 142.36,53.04 142.6,53.04 142.78,52.87 142.78,52.62 142.26,52.1 142.26,51.85 142.43,51.67 142.68,51.67 143.2,52.2 143.45,52.2 143.62,52.02 143.62,51.77 143.1,51.25 143.1,51.01 143.28,50.83 143.52,50.83 144.04,51.35 144.29,51.35 144.47,51.18 144.47,50.93 143.94,50.41 143.94,50.16 147.6,46.5 147.6,43.36 148.06,42.9 148.06,40.39 148.77,39.67 148.77,39.07 149.16,38.67 149.16,38.11 148.77,37.72 148.77,36.17 149.28,35.66 149.28,34.98 148.78,34.48 148.78,34.29 149.28,33.79 149.28,33.55 v1(149.07,33.35)
MA_AMA9: length 72.8
  TOP w0.076: v1(124.08,62.74) 124.05,62.77 124.05,64.96 124.01,65 124.01,65.24 U6.AV42
  TOP w0.165: U14.C2 150.99,34.12 150.72,33.86 v6(150.72,33.76) 150.63,33.85 148.87,33.85 147.87,32.85 147.87,30.45 R245.2
  IN1 w0.191: v1(124.08,62.74) 127.66,59.16 128.78,59.16 130.03,57.9 138.5,57.9 143.76,52.65 144.01,52.65 144.23,52.88 144.48,52.88 144.66,52.7 144.66,52.45 144.43,52.22 144.43,51.98 144.6,51.8 144.85,51.8 145.08,52.03 145.33,52.03 145.5,51.86 145.5,51.61 145.15,51.26 145.15,51.01 145.32,50.84 145.57,50.84 145.92,51.19 146.17,51.19 146.35,51.01 146.35,50.77 145.24,49.66 145.24,49.42 145.42,49.24 145.67,49.24 146.77,50.34 147.01,50.34 147.19,50.17 147.19,49.92 146.09,48.82 146.09,48.57 146.26,48.4 146.51,48.4 147.61,49.5 147.83,49.5 147.98,49.35 147.98,49.03 147.45,48.49 147.45,47.43 148.19,46.69 148.19,45.86 148.36,45.69 148.97,45.69 149.15,45.51 149.15,45.27 148.97,45.09 148.36,45.09 148.19,44.92 148.19,44.67 148.36,44.49 148.97,44.49 149.15,44.32 149.15,44.07 148.97,43.9 148.36,43.9 148.19,43.72 148.19,43.33 148.49,43.03 148.49,40.74 149.2,40.03 151.32,40.03 151.73,39.62 151.73,38.37 151.41,38.05 150.27,38.05 149.81,37.59 149.81,34.21 150.27,33.76 v6(150.72,33.76)
MA_AZQ0: length 4.2
  TOP w0.165: R218.2 v2(147.74,35.23) 147.87,35.23 148.46,34.64 149.93,34.64 U14.B3
MA_AZQ1: length 6.1
  TOP w0.165: R204.2 146.44,38.47 v2(146.85,38.06) 149.46,35.45 149.94,35.45 U14.B4
MA_BMA0: length 70.3
  TOP w0.165: U13.R2 140.41,33.82 141.42,33.82 142.26,32.98 v2(142.26,31.85) v1(142.26,31.16) 143.38,30.04 R244.2 ; v1(119.31,66.97) 118.98,67.3 U6.AR35
  IN1 w0.076: 120.45,55.17 120.13,55.17 118.51,56.79 118.51,58.71 118.71,58.9 118.71,61.45 118.95,61.69 118.95,64.17 118.21,64.91 118.21,66 118.44,66.23 118.56,66.23 v1(119.31,66.97)
  IN1 w0.191: v1(142.26,31.16) 142.26,28.87 141.88,28.5 141.88,28.14 141.12,27.38 134.55,27.38 133.52,28.41 133.52,29.8 132.6,30.71 132.11,30.71 131.71,30.31 127.95,30.31 125.83,32.44 125.83,35.28 126.64,36.1 126.64,37.13 127.95,38.43 127.95,47.68 120.45,55.17
MA_BMA1: length 68.3
  TOP w0.165: R243.2 142.36,30.4 v1(141.6,31.16) 141.6,31.85 140.21,33.25 140.21,33.37 U13.P2 ; U6.AU34 118.46,65.84 v1(118.61,65.84)
  IN1 w0.076: 120.92,55.26 120.76,55.42 120.11,55.42 118.78,56.76 118.78,58.54 118.97,58.73 118.97,61.48 119.11,61.62 119.11,65.33 v1(118.61,65.84)
  IN1 w0.191: v1(141.6,31.16) 141.83,30.93 141.83,30.56 141.35,30.07 141.35,29.77 141.83,29.29 141.83,29.06 141.56,28.78 140.98,28.78 140.84,28.65 140.84,28.12 140.54,27.81 136.12,27.81 135.91,28.02 135.61,28.02 135.4,27.81 135.08,27.81 134.77,28.12 134.77,28.47 134.39,28.85 134.04,28.85 133.91,28.98 133.91,29.34 134.34,29.77 134.34,30.07 134.19,30.23 133.64,30.23 132.68,31.19 131.85,31.19 131.37,30.71 128.14,30.71 126.26,32.59 126.26,35 127.08,35.82 127.46,35.82 128.07,36.42 128.07,37.99 128.34,38.26 128.34,47.84 120.92,55.26
MA_BMA2: length 68.8
  TOP w0.076: 118.74,63.15 118.74,64.3 U6.AW34
  TOP w0.165: R241.2 v1(140.33,31.16) 140.33,31.88 138.68,33.53 U13.N2 ; v1(120.17,57.99) 119.28,58.88 119.28,62.61 118.74,63.15
  IN1 w0.191: v1(120.17,57.99) 120.42,57.99 130.76,47.65 132.18,47.65 132.8,47.02 132.8,44.21 131.66,43.06 131.03,43.06 130.78,42.81 130.78,40.86 131,40.64 132.36,40.64 132.59,40.41 132.59,40.07 132.38,39.86 130.99,39.86 130.78,39.66 130.78,38.3 130.99,38.1 132.99,38.1 133.16,37.93 133.16,37.7 132.99,37.53 130.35,37.53 130.14,37.33 130.14,36.08 130.38,35.84 131.09,35.84 131.34,35.59 131.34,33.48 131.86,32.96 133.92,32.96 135.13,31.75 135.13,29.46 135.39,29.2 138.09,29.2 138.29,29.4 138.29,30.83 138.46,31 138.7,31 138.87,30.83 138.87,30.28 139.04,30.11 139.27,30.11 139.43,30.28 139.43,30.8 139.64,31 140.17,31 v1(140.33,31.16)
MA_BMA3: length 68.3
  TOP w0.076: U13.N3 139.01,34.72 139.01,34.08
  TOP w0.165: 139.01,34.08 139.01,33.86 140.97,31.91 v1(140.97,31.16) 141.35,30.78 R242.2 ; U6.AY34 118.45,63.94 118.45,58.2 119.99,56.67 v1(120.17,56.67)
  IN1 w0.191: v1(140.97,31.16) 140.96,31.15 140.96,29.3 140.79,29.13 140.56,29.13 140.4,29.3 140.4,30.44 140.23,30.61 139.99,30.61 139.83,30.44 139.83,28.94 139.66,28.77 139.42,28.77 139.26,28.94 139.26,29.55 139.09,29.72 138.85,29.72 138.68,29.55 138.68,28.95 138.54,28.8 135.01,28.8 134.73,29.08 134.73,31.59 133.76,32.57 131.7,32.57 130.95,33.31 130.95,34.4 130.75,34.61 129.92,34.61 129.72,34.81 129.72,37.87 129.94,38.09 129.94,39.65 130.32,40.03 130.32,41.72 129.52,42.52 129.52,43.33 129.73,43.54 131.58,43.54 132.41,44.37 132.41,46.86 132.01,47.26 130.42,47.26 129.57,48.1 129.57,48.28 121.19,56.67 v1(120.17,56.67)
MA_BMA4: length 69.4
  TOP w0.076: U6.AU35 119.08,65.87 119.49,65.46 119.49,65.37 119.5,65.36 119.5,64.96 119.49,64.96 119.49,64.71 119.5,64.71 119.5,64.31 119.49,64.31 119.49,63.97 120.57,62.89 120.57,61.67 120.53,61.63 120.53,61.37 ; 138.36,34.08 138.36,34.72 U13.M3
  TOP w0.165: v1(119.96,60.44) 120.53,61 120.53,61.37 ; 138.36,34.08 138.36,33.32 138.94,32.74 v1(138.94,31.67) 139.32,31.29 R240.2
  IN1 w0.191: v1(138.94,31.67) 138.66,31.39 138.13,31.39 137.73,31 137.73,29.76 137.56,29.59 137.33,29.59 137.16,29.76 137.16,31.07 136.99,31.24 136.76,31.24 136.59,31.07 136.59,29.76 136.42,29.59 136.18,29.59 136.02,29.76 136.02,31.43 135.81,31.63 135.81,31.63 135.25,32.18 135.25,32.61 136.13,33.49 136.13,33.72 136.4,33.98 136.4,34.29 136.97,34.86 138.86,34.86 139.48,34.24 141.83,34.24 142.06,34.47 142.06,39.55 142.02,39.59 142.02,42.02 141.73,42.31 141.73,42.8 136.78,47.75 136.78,48.17 136.12,48.83 132.04,48.83 124.1,56.77 123.31,56.77 121.08,59 121.08,59 120.75,59.33 120.75,59.65 v1(119.96,60.44)
MA_BMA5: length 68.4
  TOP w0.076: U13.F3 133.81,34.73 133.81,34.08
  TOP w0.165: v1(120.26,67.11) 120.64,67.11 U6.AR38 ; R235.2 v1(134.11,30.98) 134.11,33.45 133.81,33.75 133.81,34.08
  IN1 w0.076: 120.39,55.73 120.04,55.73 118.94,56.83 118.94,58.47 119.14,58.67 119.14,61.41 119.28,61.55 119.28,63.27 119.38,63.37 119.38,66.01 120.26,66.89 v1(120.26,67.11)
  IN1 w0.191: v1(134.11,30.98) 133.81,30.98 133.6,31.19 133.6,31.99 133.43,32.17 133.17,32.17 132.99,31.99 132.99,31.79 132.79,31.58 132.54,31.58 132.33,31.79 132.33,31.98 132.14,32.17 131.87,32.17 131.67,31.98 131.67,31.8 130.97,31.1 130.51,31.1 130.3,31.31 130.3,31.46 130.13,31.62 129.9,31.62 129.73,31.46 129.73,31.27 129.56,31.1 129.33,31.1 129.16,31.27 129.16,31.65 128.99,31.81 128.75,31.81 128.59,31.65 128.59,31.39 128.42,31.23 128.18,31.23 128.02,31.39 128.02,31.8 127.81,32 127.4,32 127.24,32.17 127.24,32.41 127.4,32.58 130.02,32.58 130.22,32.78 130.22,32.94 130.02,33.15 126.85,33.15 126.68,33.31 126.68,33.55 126.85,33.72 128.23,33.72 128.4,33.89 128.4,34.12 128.23,34.29 127.63,34.29 127.46,34.46 127.46,34.69 127.63,34.86 128.66,34.86 128.87,35.06 128.87,35.23 128.66,35.43 128.2,35.43 128.04,35.6 128.04,35.84 128.2,36 128.66,36 128.87,36.21 128.87,37.55 128.73,37.68 128.73,48.01 121.01,55.73 120.39,55.73
MA_BMA6: length 72
  TOP w0.076: 133.16,34.08 133.16,34.73 U13.E3 ; U6.AV35 119.33,65.19 119.33,65.03 119.33,65.03 119.33,64.65 119.33,64.64 119.33,64.38 119.33,64.38 119.33,63.9 120.4,62.83 120.4,62.08 120.19,61.87 v1(119.98,61.87)
  TOP w0.165: R233.2 131.82,31.04 132.86,32.08 v6(132.86,33.37) 133.16,33.66 133.16,34.08
  IN1 w0.076: 119.57,59 119.57,61.38 119.98,61.78 v1(119.98,61.87)
  IN1 w0.191: v6(132.86,33.37) 132.01,33.37 131.8,33.57 131.8,34.02 132.01,34.22 133.34,34.22 133.54,34.43 133.54,35.29 133.69,35.43 133.9,35.43 134.04,35.29 134.04,34.43 134.25,34.22 135.37,34.22 135.59,34.44 135.59,37.2 135.25,37.53 133.9,37.53 133.73,37.7 133.73,37.93 133.9,38.1 135.87,38.1 136.21,38.44 136.21,39.66 135.14,40.73 135.14,43.61 134.94,43.81 133.36,43.81 133.2,43.98 133.2,44.22 133.36,44.39 135.47,44.39 135.64,44.55 135.64,44.79 135.47,44.96 133.36,44.96 133.2,45.13 133.2,45.36 133.36,45.53 135.47,45.53 135.64,45.7 135.64,45.93 135.47,46.1 133.36,46.1 133.2,46.27 133.2,46.51 133.36,46.67 135.47,46.67 135.64,46.84 135.64,47.08 135.47,47.24 133.4,47.24 133.2,47.45 133.2,47.78 132.93,48.04 130.92,48.04 120.45,58.52 120.05,58.52 119.57,59
MA_BMA7: length 67.3
  TOP w0.165: U6.AP35 118.98,67.95 v1(119.31,67.62) ; U13.E2 133.48,31.42 132.38,30.32 v1(132.38,30.2) 132.81,29.77 R234.2
  IN1 w0.076: 120.17,54.9 118.34,56.72 118.34,58.77 118.54,58.97 118.54,61.52 118.68,61.66 118.68,64.2 117.86,65.03 117.86,65.98 118.82,66.95 118.82,67.14 v1(119.31,67.62)
  IN1 w0.191: 120.17,54.9 127.55,47.52 127.55,38.59 126.14,37.18 126.14,36.14 125.37,35.38 125.37,35.07 125.21,34.9 123.56,34.9 123.39,34.73 123.39,34.5 123.56,34.33 125.21,34.33 125.37,34.16 125.37,31.19 124.82,30.63 121.63,30.63 121.46,30.46 121.46,30.22 121.63,30.05 125.63,30.05 125.91,29.77 131.95,29.77 v1(132.38,30.2)
MA_BMA8: length 71
  TOP w0.165: v1(119.96,59.69) 120.78,60.51 120.78,63.02 120.64,63.17 120.64,64.16 U6.AY37 ; R232.2 130.68,31.16 132.41,32.89 132.41,33.7 v6(132.51,33.8) 132.83,34.12 U13.D2
  IN1 w0.191: v6(132.51,33.8) 133.74,33.8 134.7,32.84 134.93,32.84 135.62,33.54 135.62,33.92 135.99,34.29 135.99,37.33 136.2,37.53 140.23,37.53 140.4,37.7 140.4,37.93 140.23,38.1 139.08,38.1 138.87,38.3 138.87,38.72 138.71,38.89 138.47,38.89 138.3,38.72 138.3,38.44 138.1,38.24 136.8,38.24 136.6,38.44 136.6,39.88 136.73,40 138.9,40 139.06,40.17 139.06,40.41 138.9,40.58 136.58,40.58 136.37,40.78 136.37,40.94 136.58,41.15 136.94,41.15 137.11,41.32 137.11,41.55 136.94,41.72 136.58,41.72 136.37,41.92 136.37,42.09 136.58,42.29 136.94,42.29 137.11,42.46 137.11,42.7 136.94,42.86 136.43,42.86 136.26,43.03 136.26,43.27 136.43,43.43 137.56,43.43 137.73,43.6 137.73,43.84 137.56,44.01 136.37,44.01 136.21,44.17 136.21,44.41 136.37,44.58 137.56,44.58 137.73,44.74 137.73,44.98 137.56,45.15 136.58,45.15 136.37,45.35 136.37,48.02 135.95,48.44 131.09,48.44 120.67,58.85 120.22,58.85 119.96,59.11 v1(119.96,59.69)
MA_BMA9: length 65.7
  TOP w0.165: R231.2 129.54,31.25 v1(130.79,32.51) 131.14,32.51 131.92,33.3 131.92,33.99 U13.C2 ; U6.AU36 120.03,65.84 v1(120.18,65.84)
  IN1 w0.076: 120.09,56.06 119.21,56.93 119.21,58.51 119.3,58.6 119.3,61.34 119.55,61.59 119.55,65.63 119.75,65.84 v1(120.18,65.84)
  IN1 w0.191: v1(130.79,32.51) 130.79,32.91 130.56,33.15 130.56,34.01 130.35,34.21 129.92,34.21 129.72,34.01 129.72,33.74 129.51,33.54 129.04,33.54 128.84,33.74 128.84,34.44 129.26,34.86 129.26,37.71 129.13,37.85 129.13,39.8 129.33,40 129.74,40 129.91,40.17 129.91,40.41 129.74,40.58 129.29,40.58 129.13,40.74 129.13,40.98 129.29,41.15 129.76,41.15 129.93,41.32 129.93,41.55 129.76,41.72 129.33,41.72 129.13,41.92 129.13,43.8 129.33,44.01 131.49,44.01 131.65,44.17 131.65,44.41 131.49,44.58 129.29,44.58 129.13,44.74 129.13,44.98 129.29,45.15 131.85,45.15 132.02,45.32 132.02,45.55 131.85,45.72 129.29,45.72 129.13,45.89 129.13,46.12 129.29,46.29 131.85,46.29 132.02,46.46 132.02,46.7 131.85,46.86 129.38,46.86 129.18,47.07 129.18,48.12 121.24,56.06 120.09,56.06
MA_BZQ0: length 5
  TOP w0.165: U13.B3 131.12,34.64 130.68,34.64 129.36,33.32 v2(128.69,33.32) R222.2
MA_BZQ1: length 4.1
  TOP w0.165: U13.B4 131.13,35.45 129.92,35.45 129.78,35.31 v2(129.38,35.31) R217.2
MA_CKE0: length 64.4
  TOP w0.076: v6(155.86,34.65) 155.86,33.92
  TOP w0.165: v6(155.86,34.65) 155.54,34.97 U14.K3 ; v1(124.91,65.82) 124.77,65.82 U6.AU43 ; 155.86,33.92 156.11,33.67 v1(156.11,31.94) 156.11,31.78 155.83,31.49 R253.2
  IN1 w0.191: v6(155.86,34.65) 156.1,34.88 158.07,34.88 158.24,35.05 158.68,35.05 158.7,35.03 159.93,35.03 161.08,36.18 161.08,40.53 161,40.61 161,42 146.26,56.74 144.05,56.74 137.77,63.02 137.29,63.02 135.69,64.62 134.72,64.62 134.49,64.84 131.4,64.84 130.89,65.35 129.29,65.35 128.35,66.29 127.86,66.29 127.75,66.18 126.78,66.18 126.66,66.29 126.3,66.29 125.83,65.82 v1(124.91,65.82)
MA_CKE1: length 63.2
  TOP w0.076: 155.22,33.53 v6(155.22,34.65) 155.22,34.87 155.22,34.88 155.22,35.53 U14.K4
  TOP w0.165: R252.2 155.36,30.32 v1(155.36,30.9) 155.36,32.04 155.22,32.18 155.22,33.53 ; U6.AW43 124.6,64.84 v1(124.91,64.53)
  IN1 w0.076: 129,64.13 127.4,64.13 126.66,63.39 126.05,63.39 v1(124.91,64.53)
  IN1 w0.191: 129,64.13 133.55,64.13 133.78,63.91 135.46,63.91 138.03,61.33 138.03,61.01 143.72,55.31 146.23,55.31 152.55,49 152.55,48.75 152.23,48.42 152.23,48.18 152.4,48 152.65,48 152.98,48.33 153.22,48.33 153.4,48.15 153.4,47.9 153.07,47.58 153.07,47.33 153.25,47.16 153.5,47.16 153.82,47.48 154.07,47.48 154.24,47.31 154.24,47.06 153.92,46.74 153.92,46.49 154.09,46.31 154.34,46.31 154.66,46.64 154.91,46.64 155.09,46.46 155.09,46.22 154.76,45.89 154.76,45.64 154.94,45.47 155.18,45.47 155.51,45.79 155.76,45.79 156.06,45.49 156.06,40.26 155.5,39.7 155.5,37.92 154.8,37.22 154.8,36.01 155.22,35.59 v6(155.22,34.65)
MA_CKE2: length 60
  TOP w0.076: U13.K3 136.41,34.73 136.41,33.95
  TOP w0.165: R238.2 137.28,31.54 v1(137.64,31.9) 137.64,32.39 137.24,32.79 137.05,32.79 136.4,33.45 136.4,33.93 136.41,33.95 ; U6.AY42 123.81,64.14 123.81,63.49 123.55,63.22 123.55,59.21 122.78,58.45 122.78,58 123.23,57.56 v1(123.24,57.56)
  IN1 w0.191: v1(137.64,31.9) 137.64,31.91 137.16,32.38 137.16,32.97 137.35,33.16 137.91,33.16 138.29,33.54 138.68,33.54 138.86,33.36 138.86,32.76 139.03,32.59 139.28,32.59 139.45,32.76 139.45,33.36 139.63,33.54 139.88,33.54 140.05,33.36 140.05,32.76 140.23,32.59 140.47,32.59 140.65,32.76 140.65,33.36 140.82,33.54 141.07,33.54 141.25,33.36 141.25,32.76 141.42,32.59 141.67,32.59 141.84,32.76 141.84,33.36 142.02,33.54 142.56,33.54 142.76,33.74 142.76,39.8 142.72,39.85 142.72,43 137.78,47.93 137.78,48.15 136.4,49.53 132.33,49.53 124.3,57.56 v1(123.24,57.56)
MA_CKE3: length 60.1
  TOP w0.076: U6.AY43 124.51,63.55 124.97,63.09 124.97,62.34 ; U13.K4 137.06,35.52 137.06,34.01 137.22,33.85
  TOP w0.165: 137.22,33.85 137.32,33.75 137.32,33.45 138.27,32.49 v1(138.27,31.92) 138.3,31.9 R239.2 ; v1(123.24,58.19) 123.24,58.32 124.97,60.05 124.97,62.34
  IN1 w0.191: v1(138.27,31.92) 138.27,32.09 138.38,32.19 142.86,32.19 143.07,31.99 143.07,30.87 143.27,30.67 143.62,30.67 143.83,30.87 143.83,31.23 144.03,31.43 144.2,31.43 144.4,31.64 144.4,32.28 143.15,33.53 143.15,40.16 143.11,40.2 143.11,43.16 142.85,43.42 142.85,43.64 136.57,49.92 132.49,49.92 124.22,58.19 v1(123.24,58.19)
MA_CLKN0: length 65.7
  TOP w0.076: 121.39,63.25 121.39,63.27 121.3,63.36 121.3,63.61 121.07,63.84 121.07,65.45 120.66,65.86 U6.AU37
  TOP w0.165: v1(121.86,60.49) 121.77,60.4 121.54,60.4 121.39,60.55 121.39,63.25 ; R251.2 153.67,29.9 153.67,30.83 v1(154.05,31.21) 153.64,31.62 153.64,32.51 154.89,33.76 U14.J2
  IN3 w0.152: v1(154.05,31.21) 153.59,31.67 153.59,31.95 152.63,32.91 140.85,32.91 138.7,35.07 137.05,35.07 135.86,36.25 135.86,37.22 135.38,37.71 129.52,37.71 127.33,39.9 127.33,51.09 122.81,55.61 122.81,59.3 122.39,59.72 122.39,59.96 v1(121.86,60.49)
MA_CLKN1: length 65.2
  TOP w0.076: U6.AW36 119.86,64.84 v1(120.18,64.51)
  TOP w0.165: R237.2 135.99,30.05 135.99,30.81 136.31,31.13 136.31,32.22 v1(136.5,32.41) 136.09,32.82 136.09,34.24 U13.J2
  IN3 w0.152: v1(136.5,32.41) 136.32,32.59 136.32,32.93 135.85,33.4 135.06,33.4 134.66,32.99 134.66,30.12 134.48,29.95 133.65,29.95 133.48,30.12 133.48,30.73 133.17,31.04 130.81,31.04 130.63,31.22 130.63,31.52 130.81,31.7 132.78,31.7 133.12,32.04 133.12,32.58 132.78,32.92 132.45,32.92 132.31,33.06 132.31,33.41 131.97,33.75 130.21,33.75 128.75,32.29 128.49,32.29 128.28,32.5 128.28,32.76 129.91,34.39 129.91,34.87 129.53,35.25 129.05,35.25 128.2,34.41 127.95,34.41 127.74,34.62 127.74,34.87 128.42,35.55 128.42,36 128.17,36.25 128.17,37.88 126.49,39.55 126.49,50.74 121.97,55.26 121.97,58.93 121.36,59.54 121.36,62.86 120.62,63.6 120.62,64.07 v1(120.18,64.51)
MA_CLKP0: length 66
  TOP w0.076: U6.AV37 120.8,65.49 120.9,65.38 120.9,63.78 121.14,63.54 121.14,63.36 121.05,63.27 121.05,63.25 ; 154.55,33.9 154.56,33.91 154.56,34.72 U14.J3
  TOP w0.165: v1(121.86,59.85) 121.65,60.06 121.4,60.06 121.05,60.41 121.05,63.25 ; 154.55,33.9 153.3,32.65 153.3,31.48 v1(153.03,31.21) 153.33,30.92 153.33,30.32 R250.2
  IN3 w0.152: v1(153.03,31.21) 153.31,31.49 153.31,31.84 152.52,32.63 140.74,32.63 138.58,34.79 136.93,34.79 135.59,36.14 135.59,37.11 135.26,37.43 129.4,37.43 127.05,39.78 127.05,50.98 122.53,55.5 122.53,59.18 v1(121.86,59.85)
MA_CLKP1: length 65.3
  TOP w0.076: U6.AY36 119.99,63.98 120.04,63.98 v1(120.18,63.84) ; 135.75,33.66 135.76,33.67 135.76,34.73 U13.J3
  TOP w0.165: R236.2 135.65,30.17 135.65,30.95 135.97,31.27 135.97,32.21 v1(135.79,32.38) 135.76,32.41 135.76,32.54 135.75,32.55 135.75,33.66
  IN3 w0.152: v1(120.18,63.84) 120.35,63.67 120.35,63.49 121.08,62.75 121.08,59.43 121.69,58.82 121.69,55.14 126.21,50.62 126.21,39.44 127.89,37.76 127.89,36.13 128.14,35.88 128.14,35.67 127.46,34.99 127.46,34.51 127.84,34.13 128.32,34.13 129.16,34.97 129.42,34.97 129.63,34.76 129.63,34.5 128,32.87 128,32.39 128.38,32.01 128.86,32.01 130.33,33.48 131.85,33.48 132.03,33.3 132.03,32.94 132.33,32.64 132.66,32.64 132.84,32.46 132.84,32.16 132.66,31.98 130.69,31.98 130.35,31.64 130.35,31.1 130.69,30.76 133.06,30.76 133.2,30.62 133.2,30.01 133.54,29.67 134.59,29.67 134.94,30.01 134.94,32.88 135.18,33.12 135.74,33.12 136.04,32.82 136.04,32.64 v1(135.79,32.38)
MA_CS#0: length 71.6
  TOP w0.165: R215.2 145.61,35.48 145.69,35.56 v1(145.92,35.56) ; v6(137.71,35.45) 137.71,35.38 U13.L3 ; v6(155.86,35.45) 155.86,35.38 U14.L3 ; v1(118.35,67.68) 118.08,67.95 U6.AP33
  IN1 w0.076: v1(118.35,67.68) 118.71,68.03 119.49,68.03 120,67.52 120.41,67.52 120.65,67.28 120.65,66.29 120.8,66.14 120.8,63.64 121.11,63.34 121.11,59.49 122.01,58.59 123.6,58.59
  IN1 w0.191: v1(145.92,35.56) 145.79,35.68 145.54,35.68 143.6,37.63 143.6,40.24 143.5,40.34 143.5,43.57 136.76,50.32 132.66,50.32 124.39,58.59 123.6,58.59
  IN2 w0.191: v6(155.86,35.45) 155.02,35.45 154.62,35.85 149.82,35.85 149.71,35.74 146.1,35.74 v1(145.92,35.56) 145.41,35.05 145.3,35.05 145.11,34.86 145.11,34.21 144.91,34.01 144.62,34.01 144.42,34.21 144.42,34.86 144.22,35.05 138.11,35.05 v6(137.71,35.45)
MA_CS#1: length 72.8
  TOP w0.165: v1(117.4,66.97) 117.08,67.3 U6.AR32 ; v6(137.71,36.25) 137.71,36.18 U13.L4 ; R211.2 145.74,36.5 v1(145.9,36.33) ; v6(155.86,36.25) 155.86,36.18 U14.L4
  IN1 w0.076: 124.06,58.93 121.95,58.93 121.27,59.6 121.27,63.41 120.97,63.71 120.97,66.31 120.82,66.46 120.82,67.35 120.44,67.73 120.05,67.73 119.57,68.21 118.32,68.21 117.88,67.77 117.88,67.45 v1(117.4,66.97)
  IN1 w0.191: 124.06,58.93 124.6,58.93 132.82,50.71 137.2,50.71 143.9,44.02 143.9,40.5 143.99,40.41 143.99,38.13 145.79,36.33 v1(145.9,36.33)
  IN2 w0.191: v6(155.86,36.25) 155.46,36.65 146.22,36.65 v1(145.9,36.33) 145.38,36.33 145.19,36.14 145.19,35.88 145,35.69 144.68,35.69 144.49,35.88 144.49,36.14 144.3,36.33 143.98,36.33 143.79,36.14 143.79,35.88 143.6,35.69 143.28,35.69 143.09,35.88 143.09,36.14 142.9,36.33 142.48,36.33 142,35.85 138.11,35.85 v6(137.71,36.25)
MA_DQ0: length 61
  TOP w0.076: v1(139.15,72.4) 138.78,72.03 138.45,72.03 138.05,71.63 136.91,71.63 U6.AH63
  TOP w0.165: U14.R9 158.79,39.78 v6(159.12,39.45)
  IN2 w0.191: v1(139.15,72.4) 139.38,72.63 148.23,72.63 155.23,65.62 155.23,58.78 158.12,55.9 158.12,51.66 158.41,51.36 158.68,51.36 159,51.68 159.27,51.68 159.46,51.49 159.46,51.22 159.14,50.9 159.14,50.63 159.33,50.44 159.6,50.44 159.92,50.76 160.18,50.76 160.37,50.57 160.37,50.3 160.05,49.98 160.05,49.72 160.24,49.53 160.51,49.53 160.83,49.85 161.1,49.85 161.29,49.66 161.29,49.39 160.97,49.07 160.97,48.8 161.16,48.61 161.43,48.61 161.75,48.93 162.02,48.93 162.21,48.74 162.21,47.56 163.79,45.98 163.79,40.53 162.74,39.47 162.38,39.47 161.96,39.05 159.52,39.05 v6(159.12,39.45)
MA_DQ1: length 61.4
  TOP w0.076: U6.AH62 136.38,71.75 136.59,71.75 136.75,71.83 138,71.83 138.5,72.33 v1(138.5,72.43)
  TOP w0.165: U14.T8 159.44,38.98 v6(159.77,38.65)
  IN2 w0.191: v6(159.77,38.65) 160.17,38.25 161.8,38.25 162.56,39.01 162.97,39.01 164.21,40.26 164.21,47.33 161.08,50.46 161.08,50.73 161.53,51.18 161.53,51.45 161.34,51.64 161.07,51.64 160.62,51.19 160.35,51.19 160.16,51.38 160.16,51.65 160.61,52.1 160.61,52.37 160.42,52.56 160.15,52.56 159.7,52.11 159.43,52.11 159.14,52.4 159.14,55.49 155.65,58.98 155.65,65.8 148.35,73.1 139.17,73.1 v1(138.5,72.43)
MA_DQ2: length 58.7
  TOP w0.076: U6.AK63 136.94,70.06 137.6,70.06 137.8,70.26 138.13,70.26 138.43,70.56 138.97,70.56 139.19,70.34 139.46,70.34
  TOP w0.165: 139.46,70.34 v1(139.73,70.34) ; U14.T10 159.44,40.73 v6(159.76,41.05)
  IN2 w0.191: v1(139.73,70.34) 139.73,70.12 139.99,69.85 140.82,69.85 140.89,69.93 147.04,69.93 148.82,68.15 148.82,65.11 148.63,64.92 148.53,64.92 148.34,64.73 148.34,64.47 148.53,64.28 148.63,64.28 148.82,64.09 148.82,63.82 148.63,63.63 148.53,63.63 148.34,63.44 148.34,63.17 148.53,62.98 148.63,62.98 148.82,62.79 148.82,61.8 155.71,54.91 155.71,48.68 156.01,48.38 156.28,48.38 157,49.1 157.27,49.1 157.46,48.91 157.46,48.65 156.23,47.42 156.23,47.15 156.42,46.96 156.69,46.96 157.92,48.19 158.19,48.19 158.38,48 158.38,47.73 157.65,47.01 157.65,46.74 157.84,46.55 158.11,46.55 158.84,47.27 159.1,47.27 159.29,47.08 159.29,46.81 158.57,46.09 158.57,45.82 158.76,45.63 159.03,45.63 159.75,46.36 160.02,46.36 160.21,46.17 160.21,45.9 159.49,45.17 159.49,44.91 160.64,43.75 160.64,42.68 160.83,42.49 160.83,41.66 160.63,41.45 160.17,41.45 v6(159.76,41.05)
MA_DQ3: length 60.9
  TOP w0.076: v1(139.26,69.91) 138.83,70.33 138.43,70.33 138.2,70.1 137.87,70.1 137.67,69.89 136.68,69.89 136.38,70.18 U6.AK62
  TOP w0.165: U14.T11 159.44,41.53 v6(159.76,41.85)
  IN2 w0.191: v6(159.76,41.85) 160.22,42.31 160.22,43.08 158.86,44.44 157.82,44.44 157.63,44.63 157.63,46.17 157.44,46.36 157.17,46.36 156.98,46.17 156.98,44.63 156.79,44.44 156.52,44.44 156.33,44.63 156.33,46.17 156.14,46.36 155.87,46.36 155.68,46.17 155.68,44.63 155.49,44.44 155.07,44.44 154.44,45.08 154.44,47.51 155.3,48.37 155.3,54.73 154.61,55.42 154.34,55.42 154.07,55.15 153.8,55.15 153.61,55.34 153.61,55.61 153.88,55.88 153.88,56.15 153.69,56.34 153.42,56.34 153.15,56.07 152.88,56.07 152.69,56.26 152.69,56.53 152.96,56.8 152.96,57.06 152.77,57.25 152.5,57.25 152.23,56.98 151.97,56.98 151.78,57.17 151.78,57.44 152.05,57.71 152.05,57.98 151.86,58.17 151.59,58.17 151.32,57.9 151.05,57.9 150.86,58.09 150.86,58.36 151.13,58.63 151.13,58.9 150.94,59.09 150.67,59.09 150.4,58.82 150.13,58.82 149.94,59.01 149.94,59.27 150.21,59.55 150.21,59.81 150.02,60 149.76,60 149.48,59.73 149.22,59.73 149.03,59.92 149.03,60.19 149.3,60.46 149.3,60.73 148.13,61.9 147.86,61.9 147.59,61.63 147.32,61.63 147.13,61.82 147.13,62.09 147.4,62.36 147.4,62.62 147.21,62.81 146.95,62.81 146.67,62.54 146.41,62.54 146.22,62.73 146.22,63 146.49,63.27 146.49,63.54 146.14,63.88 144.55,63.88 142.42,66.02 142.42,67.84 140.83,69.43 139.74,69.43 v1(139.26,69.91)
MA_DQ4: length 61.8
  TOP w0.076: v1(137.18,72.25) 136.94,72.25 136.66,71.97 136.55,71.92 135.9,71.92 U6.AH61
  TOP w0.165: U14.R8 158.79,38.98 v6(159.12,38.65)
  IN2 w0.191: v1(137.18,72.25) 138.51,73.58 148.46,73.58 156.07,65.97 156.07,60.46 159.56,56.98 159.56,54.02 161.95,51.62 161.95,50.19 164.63,47.5 164.63,39.26 163.69,38.32 162.47,38.32 161.99,37.83 159.94,37.83 v6(159.12,38.65)
MA_DQ5: length 62.9
  TOP w0.076: U6.AH60 134.94,71.46 134.94,71.09 134.86,71.01 134.86,70.77 135.07,70.57 135.31,70.57 135.33,70.58 135.7,70.58 135.72,70.57 135.91,70.57 135.92,70.58 136.06,70.64 136.27,70.64 136.42,70.57 136.55,70.57 136.66,70.62 136.71,70.64 137,70.64 137.24,70.41 137.46,70.41 137.65,70.59 137.99,70.59 138.29,70.89 139.27,70.89 139.65,71.27 139.7,71.27
  TOP w0.165: v1(140.75,71.71) 140.31,71.27 139.7,71.27 ; v6(159.77,39.45) 159.44,39.78 U14.T9
  IN2 w0.191: v1(140.75,71.71) 141.1,72.06 148.2,72.06 154.14,66.12 154.14,63.32 154.33,63.13 154.62,63.13 154.81,62.94 154.81,62.67 154.62,62.48 154.33,62.48 154.14,62.29 154.14,62.03 154.33,61.84 154.62,61.84 154.81,61.65 154.81,61.38 154.62,61.19 152.88,61.19 152.69,61 152.69,60.73 152.88,60.54 154.62,60.54 154.81,60.35 154.81,60.08 154.62,59.89 154.33,59.89 154.14,59.7 154.14,59.28 157.7,55.73 157.7,51.48 163.37,45.8 163.37,40.82 162.84,40.28 162.53,40.28 161.72,39.47 159.79,39.47 v6(159.77,39.45)
MA_DQ6: length 59.7
  TOP w0.076: U6.AK61 135.86,70.29 135.99,70.43 136.1,70.48 136.23,70.48 136.25,70.47 136.33,70.43 136.39,70.4 136.59,70.4 136.75,70.48 136.94,70.48 137.19,70.22 137.53,70.22 137.74,70.43 138.06,70.43 138.36,70.73 139.64,70.73 139.7,70.79
  TOP w0.165: v1(141.74,70.46) 141.25,70.46 140.84,70.86 139.77,70.86 139.7,70.79 ; v6(159.14,41.06) 158.79,40.71 U14.R10
  IN2 w0.191: v1(141.74,70.46) 141.85,70.36 147.2,70.36 149.24,68.32 149.24,67.43 149.43,67.24 150.43,67.24 150.62,67.05 150.62,66.78 150.43,66.59 149.43,66.59 149.24,66.4 149.24,66.14 149.43,65.95 150.43,65.95 150.62,65.76 150.62,65.49 150.43,65.3 149.43,65.3 149.24,65.11 149.24,64.84 149.43,64.65 150.43,64.65 150.62,64.46 150.62,64.19 150.43,64 149.43,64 149.24,63.81 149.24,63.54 149.43,63.35 150.43,63.35 150.62,63.17 150.62,62.9 150.43,62.71 149.43,62.71 149.24,62.52 149.24,61.98 156.13,55.08 156.13,50.83 161.21,45.75 161.21,41.15 160.71,40.64 159.56,40.64 v6(159.14,41.06)
MA_DQ7: length 61.8
  TOP w0.076: U6.AK60 135.1,70.29 135.39,70 135.63,70 135.65,70.02 135.92,70.02 136.05,69.89 136.45,69.89 136.61,69.73 138.01,69.73 v1(138.04,69.7)
  TOP w0.165: v6(159.11,41.85) 158.79,41.53 U14.R11
  IN2 w0.191: v1(138.04,69.7) 138.04,68.62 138.33,68.33 140.59,68.33 141.48,67.44 141.48,66.36 144.67,63.17 145.19,63.17 153.38,54.98 153.38,54.37 153.57,54.18 154.69,54.18 154.88,53.99 154.88,53.72 154.69,53.53 153.57,53.53 153.38,53.34 153.38,53.07 153.57,52.88 154.69,52.88 154.88,52.69 154.88,52.43 154.69,52.24 153.59,52.24 153.4,52.05 153.4,51.78 153.59,51.59 154.69,51.59 154.88,51.4 154.88,51.13 154.69,50.94 154.09,50.94 153.9,50.75 153.9,50.48 154.09,50.29 154.33,50.29 154.52,50.1 154.52,49.84 154.33,49.65 153.76,49.65 153.57,49.46 153.57,49.16 153.73,49 154.69,49 154.88,48.81 154.88,48.54 154.69,48.35 153.76,48.35 153.59,48.19 153.59,44.27 153.84,44.02 155.03,44.02 155.22,43.83 155.22,40.58 155.41,40.39 155.68,40.39 155.87,40.58 155.87,43.83 156.06,44.02 157.61,44.02 157.99,43.64 157.99,42.56 158.3,42.25 158.71,42.25 v6(159.11,41.85)
MA_DQ8: length 52.9
  TOP w0.076: v1(138.72,68.92) 138.66,68.98 136.94,68.98 U6.AM63
  TOP w0.165: U14.M8 156.84,38.97 v6(156.52,38.65)
  IN3 w0.152: v6(156.52,38.65) 156.52,38.33 157.42,37.43 161.31,37.43 163.92,40.04 163.92,43.89 144.55,63.26 144.55,63.7 142.95,65.3 142.95,65.86 142.67,66.14 142.67,67.63 140.99,69.32 139.12,69.32 v1(138.72,68.92)
MA_DQ9: length 53.2
  TOP w0.076: U6.AM62 136.46,69.4 136.94,69.4 137.19,69.14 138.39,69.14 138.55,69.31 139.48,69.31 139.7,69.09
  TOP w0.165: v6(157.16,39.45) 157.49,39.78 U14.N9 ; 139.7,69.09 v1(139.97,68.82)
  IN3 w0.152: v6(157.16,39.45) 157.16,39.28 157.4,39.04 157.4,38.53 157.68,38.25 161.01,38.25 163.13,40.37 163.13,42.65 162.26,43.52 162.26,44.48 144.63,62.11 144.44,62.11 144.25,61.91 144.06,61.91 143.92,62.05 143.92,62.24 144.12,62.43 144.12,62.62 143.98,62.75 143.79,62.75 143.6,62.56 143.41,62.56 143.28,62.69 143.28,62.88 143.47,63.08 143.47,63.27 143.34,63.4 143.15,63.4 142.95,63.21 142.76,63.21 142.63,63.34 142.63,63.53 142.82,63.72 142.82,63.91 142.18,64.56 142.18,65.5 141.83,65.85 141.83,67.39 140.9,68.33 140.47,68.33 v1(139.97,68.82)
MA_DQ10: length 51.5
  TOP w0.076: v1(139.29,66.47) 138.74,66.47 137.71,67.5 137.26,67.5 137,67.75 U6.AP63
  TOP w0.165: v6(157.81,41.85) 157.49,41.53 U14.N11
  IN3 w0.152: v1(139.29,66.47) 139.29,65.33 140.02,64.61 140.02,62.69 140.77,61.95 140.77,61.41 141.96,60.22 141.96,60.03 141.81,59.88 141.81,59.69 141.95,59.56 142.13,59.56 142.28,59.71 142.47,59.71 142.6,59.57 142.6,59.38 142.46,59.24 142.46,59.05 142.59,58.91 142.78,58.91 142.93,59.06 143.12,59.06 143.25,58.93 143.25,58.74 143.1,58.59 143.1,58.4 143.24,58.27 143.43,58.27 143.58,58.41 143.76,58.41 143.9,58.28 143.9,58.09 143.75,57.94 143.75,57.75 143.89,57.62 144.07,57.62 144.22,57.77 144.41,57.77 144.55,57.63 144.55,57.44 144.4,57.3 144.4,57.11 144.53,56.97 144.72,56.97 144.99,57.24 145.18,57.24 145.31,57.1 145.31,56.92 145.04,56.65 145.04,56.46 145.18,56.33 145.37,56.33 145.63,56.59 145.82,56.59 145.96,56.46 145.96,56.27 145.69,56 145.69,55.81 145.83,55.68 146.01,55.68 146.28,55.95 146.47,55.95 146.6,55.81 146.6,55.62 146.34,55.36 146.34,55.17 146.47,55.03 146.66,55.03 146.93,55.3 147.12,55.3 147.25,55.16 147.25,54.98 146.98,54.71 146.98,54.52 147.12,54.39 147.31,54.39 147.57,54.65 147.76,54.65 147.9,54.52 147.9,54.33 147.63,54.06 147.63,53.87 147.77,53.74 147.95,53.74 148.22,54.01 148.41,54.01 148.54,53.87 148.54,53.68 148.28,53.42 148.28,53.23 148.41,53.09 148.6,53.09 148.87,53.36 149.06,53.36 149.19,53.22 149.19,53.04 148.93,52.77 148.93,52.58 149.06,52.45 149.25,52.45 149.51,52.71 149.7,52.71 149.84,52.58 149.84,52.39 149.57,52.12 149.57,51.93 149.71,51.8 149.9,51.8 150.16,52.07 150.35,52.07 150.48,51.93 150.48,51.74 150.22,51.48 150.22,51.29 150.35,51.15 150.54,51.15 150.81,51.42 151,51.42 151.13,51.28 151.13,51.1 150.87,50.83 150.87,50.64 151,50.51 151.19,50.51 151.45,50.77 151.64,50.77 151.78,50.64 151.78,50.45 151.51,50.18 151.51,49.99 151.65,49.86 151.84,49.86 152.1,50.13 152.29,50.13 152.42,49.99 152.42,49.8 152.16,49.54 152.16,49.35 152.29,49.21 152.48,49.21 152.75,49.48 152.94,49.48 153.07,49.34 153.07,49.16 152.81,48.89 152.81,48.7 158.24,43.27 158.24,42.97 157.98,42.72 157.98,42.02 v6(157.81,41.85)
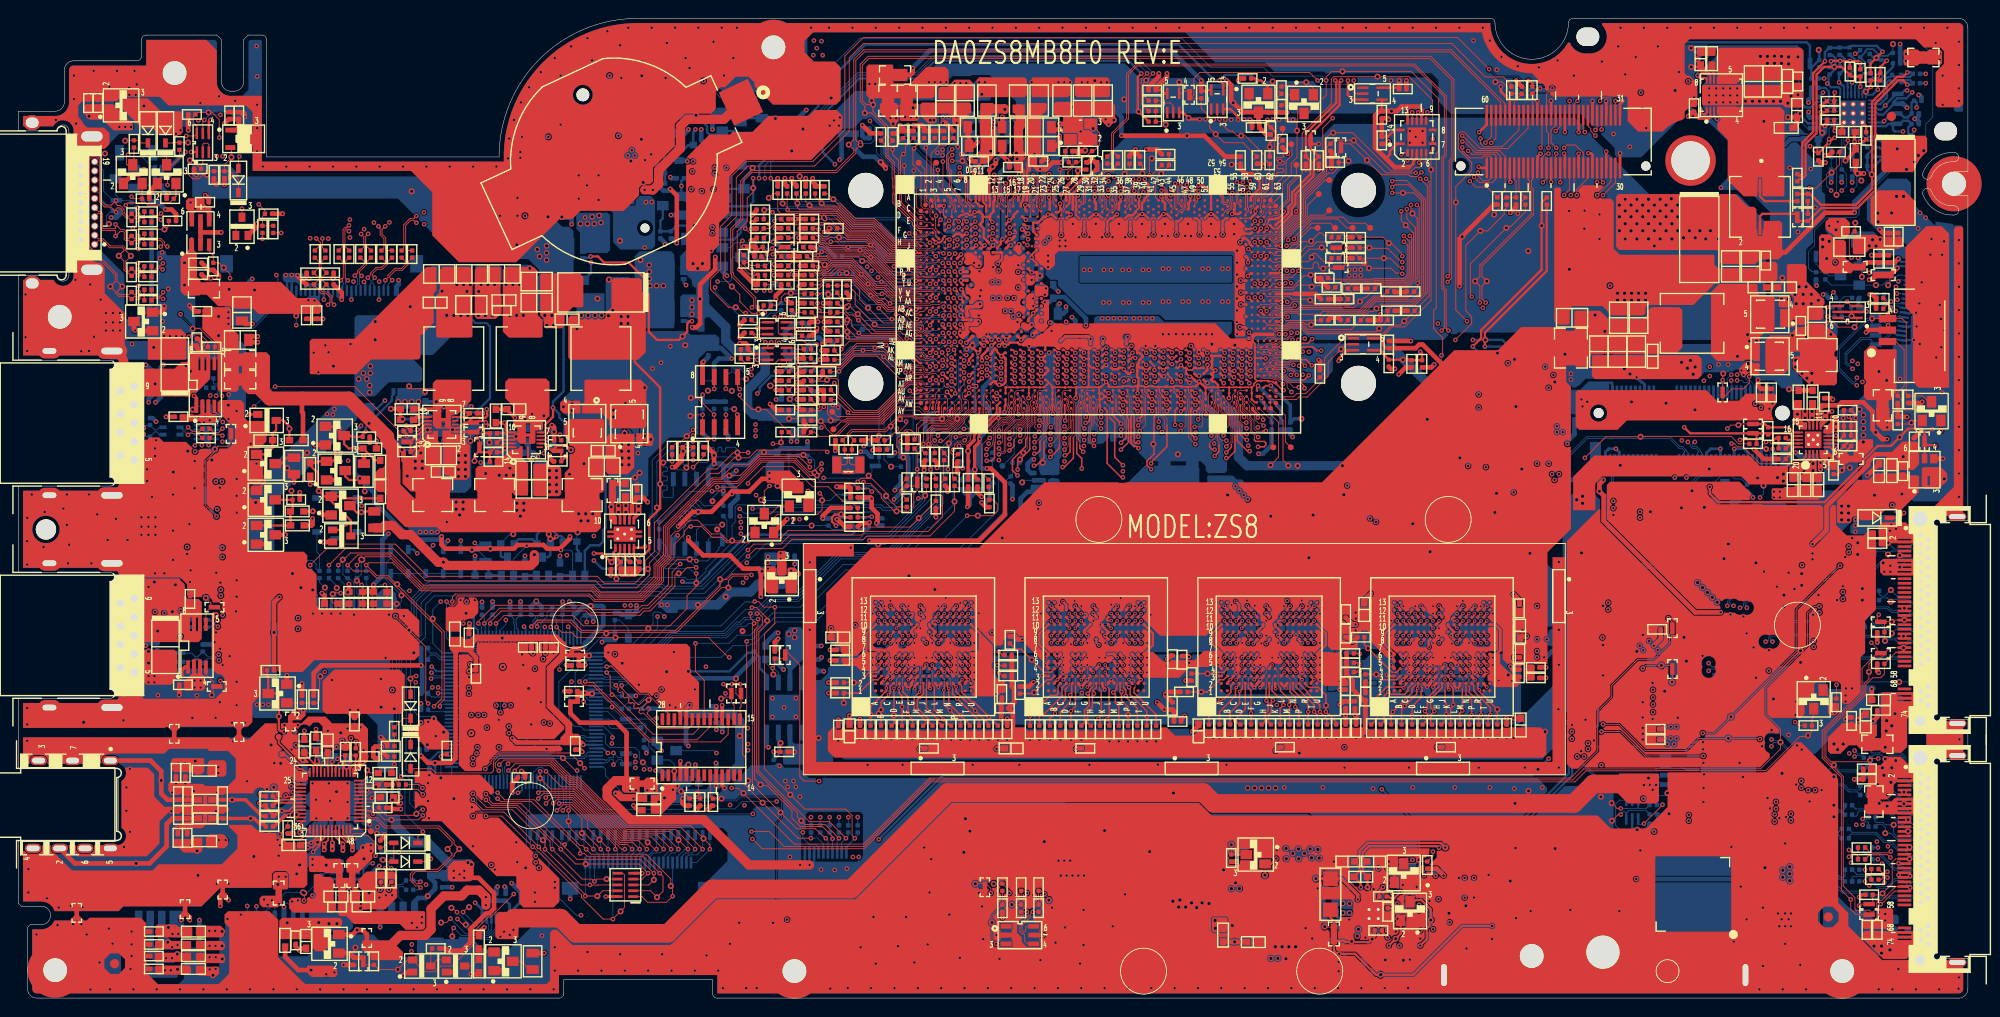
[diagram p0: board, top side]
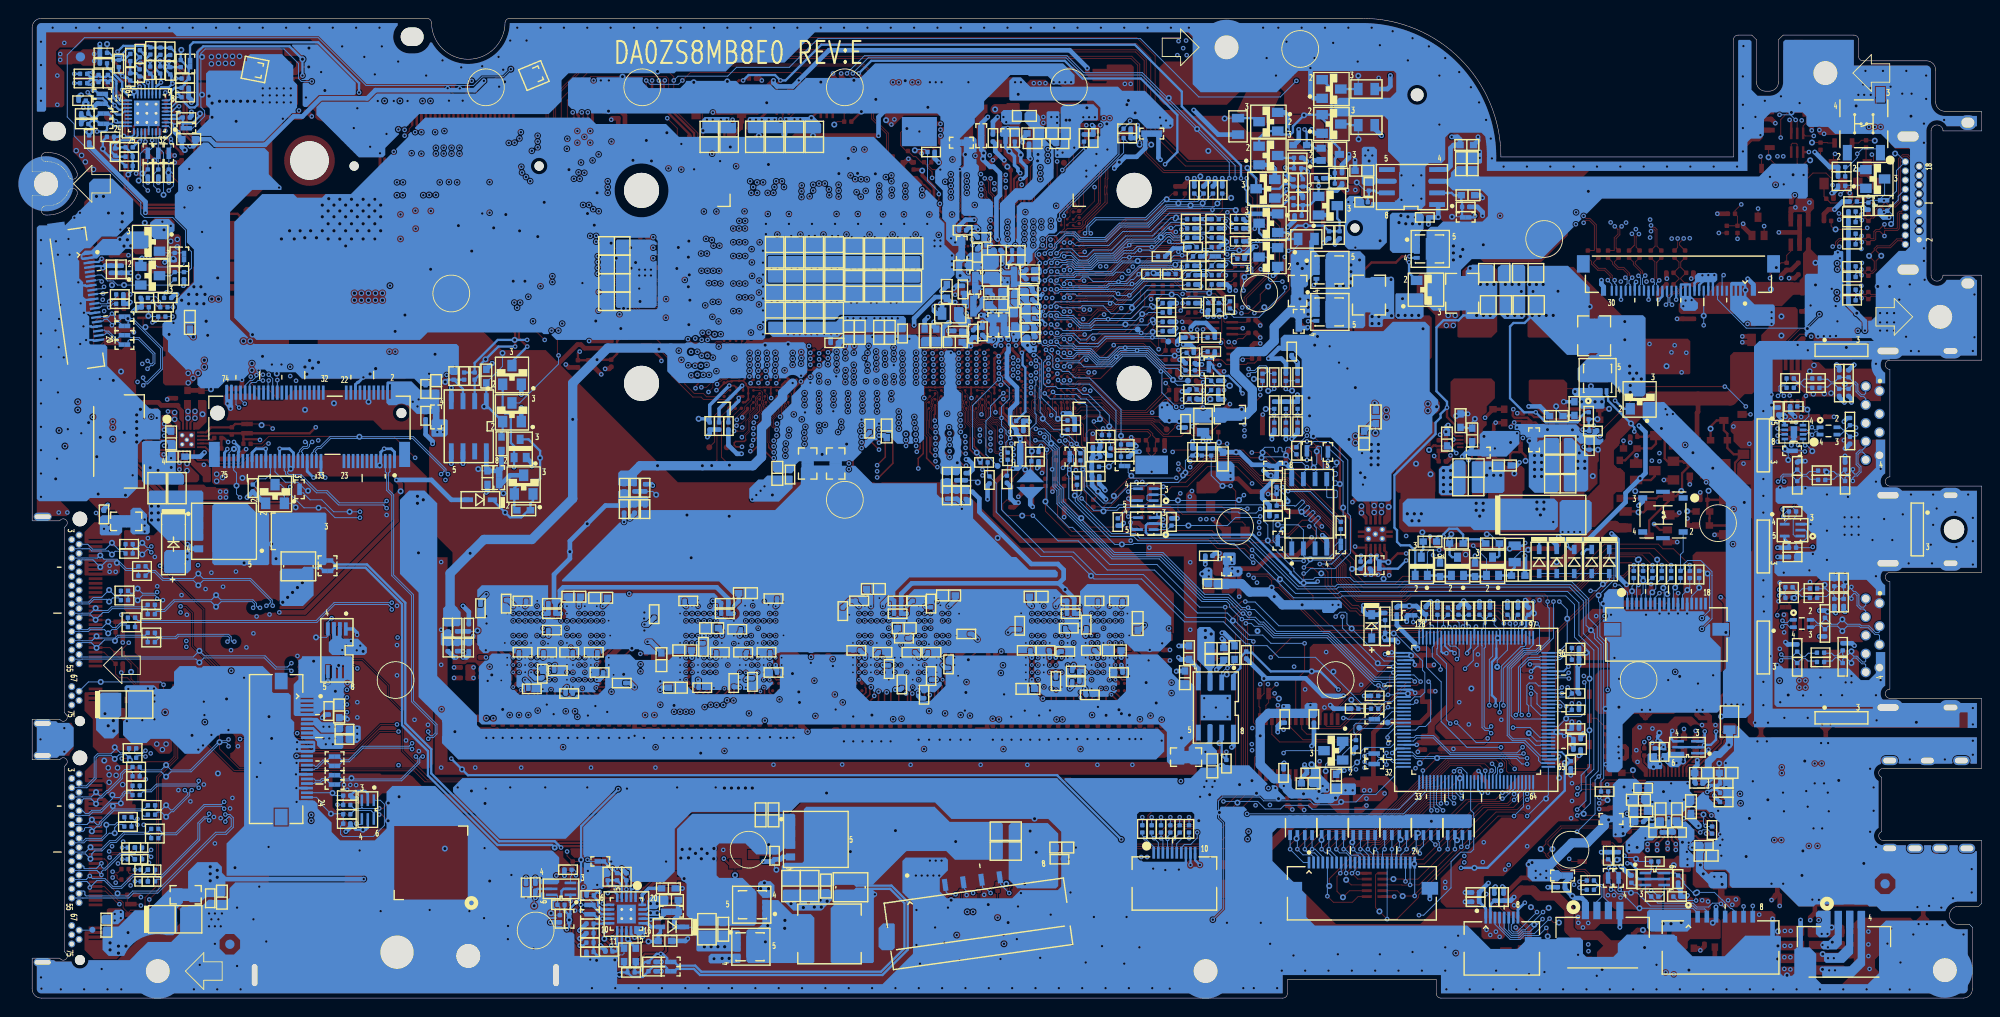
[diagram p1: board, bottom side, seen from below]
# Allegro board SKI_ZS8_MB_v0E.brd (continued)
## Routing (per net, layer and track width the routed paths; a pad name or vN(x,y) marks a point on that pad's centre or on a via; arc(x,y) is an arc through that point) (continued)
MA_DQ11: length 52.4
  TOP w0.076: v1(138.51,65.96) 138.04,66.44 138.04,66.94 137.66,67.31 137.21,67.31 137.06,67.46 136.69,67.46 136.4,67.75 U6.AP62
  TOP w0.165: v6(157.16,41.85) 156.84,41.53 U14.M11
  IN3 w0.152: v1(138.51,65.96) 138.51,65.57 139.64,64.45 139.64,62.54 140.39,61.79 140.39,60.58 140.78,60.19 140.78,60 140.58,59.79 140.58,59.6 140.71,59.47 140.9,59.47 141.1,59.67 141.29,59.67 141.43,59.54 141.43,59.35 141.22,59.14 141.22,58.95 141.36,58.82 141.55,58.82 141.75,59.03 141.94,59.03 142.07,58.89 142.07,58.7 141.87,58.5 141.87,58.31 142,58.17 142.19,58.17 142.4,58.38 142.59,58.38 142.72,58.25 142.72,58.06 142.52,57.85 142.52,57.66 142.65,57.53 142.84,57.53 143.04,57.73 143.23,57.73 143.37,57.6 143.37,57.41 143.16,57.2 143.16,57.01 143.3,56.88 143.49,56.88 143.69,57.09 143.88,57.09 144.01,56.95 144.01,56.76 143.81,56.56 143.81,56.37 143.94,56.23 144.13,56.23 144.34,56.44 144.53,56.44 145.19,55.78 145.19,55.59 144.92,55.32 144.92,55.13 145.05,55 145.24,55 145.51,55.27 145.7,55.27 145.84,55.13 145.84,54.94 145.57,54.67 145.57,54.48 145.7,54.35 145.89,54.35 146.16,54.62 146.35,54.62 146.48,54.48 146.48,54.3 146.21,54.03 146.21,53.84 146.35,53.7 146.54,53.7 146.81,53.97 146.99,53.97 149.08,51.89 149.08,51.7 148.88,51.51 148.88,51.32 149.02,51.18 149.21,51.18 149.4,51.38 149.59,51.38 149.72,51.24 149.72,51.05 149.53,50.86 149.53,50.67 149.66,50.54 149.85,50.54 150.05,50.73 150.24,50.73 150.37,50.6 150.37,50.41 150.18,50.21 150.18,50.02 150.31,49.89 150.5,49.89 150.69,50.08 150.88,50.08 151.02,49.95 151.02,49.76 150.82,49.57 150.82,49.38 150.96,49.24 151.15,49.24 151.34,49.44 151.53,49.44 151.66,49.3 151.66,49.11 151.47,48.92 151.47,48.73 151.6,48.6 151.79,48.6 151.99,48.79 152.18,48.79 152.31,48.66 152.31,48.47 152.12,48.27 152.12,48.08 152.25,47.95 152.44,47.95 152.63,48.14 152.82,48.14 152.96,48.01 152.96,47.82 152.76,47.63 152.76,47.44 152.9,47.3 153.09,47.3 153.28,47.5 153.47,47.5 153.6,47.36 153.6,47.17 153.41,46.98 153.41,46.79 153.54,46.66 153.73,46.66 153.93,46.85 154.12,46.85 154.25,46.72 154.25,46.53 154.06,46.33 154.06,46.14 154.19,46.01 154.38,46.01 154.57,46.2 154.76,46.2 154.9,46.07 154.9,45.88 154.7,45.69 154.7,45.5 154.84,45.36 155.03,45.36 155.22,45.56 155.41,45.56 155.54,45.42 155.54,45.23 155.35,45.04 155.35,44.85 155.48,44.72 155.67,44.72 155.87,44.91 156.06,44.91 157.6,43.36 157.6,42.29 v6(157.16,41.85)
MA_DQ12: length 53.6
  TOP w0.076: U6.AM61 135.64,69 136.09,69.45 136.21,69.56 137,69.56 137.26,69.31 138.32,69.31 138.5,69.49 139.7,69.49
  TOP w0.165: v1(140.72,68.87) 140.1,69.49 139.7,69.49 ; v6(156.51,39.45) 156.84,39.78 U14.M9
  IN3 w0.152: v6(156.51,39.45) 156.51,39.24 156.92,38.83 156.92,38.47 157.54,37.85 161.19,37.85 163.54,40.2 163.54,43.73 142.56,64.72 142.56,65.66 142.21,66.01 142.21,67.55 140.89,68.87 v1(140.72,68.87)
MA_DQ13: length 55.4
  TOP w0.076: 139.37,67.23 138.44,67.23 137.85,67.83 137.48,67.83 137.09,68.21 136.71,68.21 136.55,68.14 136.42,68.14 136.27,68.21 136.06,68.21 136.01,68.19 135.92,68.15 135.91,68.14 135.07,68.14 134.86,68.34 U6.AM60
  TOP w0.165: v1(140.39,67.77) 139.85,67.23 139.37,67.23 ; U14.P9 158.14,39.78 v6(158.47,39.45)
  IN3 w0.152: v6(158.47,39.45) 158.85,39.07 159.95,39.07 160.14,39.26 161.36,39.26 162.2,40.11 162.2,42.88 161.75,43.34 161.75,44.45 150.01,56.19 149.82,56.19 149.46,55.82 149.27,55.82 149.13,55.96 149.13,56.14 149.5,56.51 149.5,56.7 149.36,56.83 149.17,56.83 148.81,56.47 148.62,56.47 148.49,56.6 148.49,56.79 148.85,57.16 148.85,57.35 147.71,58.48 147.53,58.48 147.42,58.38 147.23,58.38 147.1,58.51 147.1,58.7 147.2,58.81 147.2,59 147.07,59.13 146.88,59.13 146.57,58.82 146.38,58.82 146.25,58.96 146.25,59.15 146.56,59.45 146.56,59.64 146.42,59.78 146.23,59.78 145.96,59.5 145.77,59.5 145.64,59.64 145.64,59.83 145.91,60.1 145.91,60.29 145.77,60.42 145.59,60.42 145.31,60.15 145.12,60.15 144.99,60.29 144.99,60.48 145.26,60.75 145.26,60.94 144.86,61.34 143.96,61.34 141.8,63.5 141.8,65.35 141.45,65.69 141.45,67.23 140.91,67.77 v1(140.39,67.77)
MA_DQ14: length 52.8
  TOP w0.076: U6.AP61 135.75,67.75 135.99,68 136.1,68.05 136.23,68.05 136.25,68.04 136.33,68 136.33,68 136.39,67.97 136.59,67.97 136.75,68.05 137.01,68.05 137.39,67.66 137.78,67.66 138.46,66.98 139.52,66.98 139.7,66.8
  TOP w0.165: 139.7,66.8 139.93,66.57 v1(139.93,66.37) ; v6(157.16,41.05) 156.84,40.73 U14.M10
  IN3 w0.152: v1(139.93,66.37) 139.95,66.34 139.95,65.21 140.4,64.77 140.4,62.85 141.15,62.1 141.15,61.57 144.85,57.87 145.08,57.87 153.71,49.25 153.71,49.06 153.44,48.79 153.44,48.6 153.57,48.47 153.76,48.47 154.03,48.74 154.22,48.74 154.35,48.6 154.35,48.41 154.09,48.15 154.09,47.96 154.22,47.82 154.41,47.82 154.68,48.09 154.87,48.09 155,47.96 155,47.77 154.73,47.5 154.73,47.31 154.87,47.18 155.06,47.18 155.32,47.44 155.51,47.44 155.65,47.31 155.65,47.12 155.38,46.85 155.38,46.66 155.51,46.53 155.7,46.53 155.97,46.8 156.16,46.8 156.29,46.66 156.29,46.47 156.03,46.21 156.03,46.02 156.16,45.88 156.35,45.88 156.62,46.15 156.81,46.15 156.94,46.02 156.94,45.83 156.67,45.56 156.67,45.37 156.81,45.24 157,45.24 157.26,45.5 157.45,45.5 157.59,45.37 157.59,45.18 157.32,44.91 157.32,44.72 157.45,44.59 157.64,44.59 157.91,44.86 158.1,44.86 158.23,44.72 158.23,44.53 157.97,44.27 157.97,44.08 158.1,43.94 158.29,43.94 158.56,44.21 158.75,44.21 158.88,44.08 158.88,43.89 158.61,43.62 158.61,43.43 158.75,43.3 158.94,43.3 159.2,43.56 159.39,43.56 160.8,42.15 160.8,40.89 160.58,40.67 157.65,40.67 157.27,41.05 v6(157.16,41.05)
MA_DQ15: length 53.7
  TOP w0.076: U6.AP60 135.07,67.75 135.37,67.46 136.43,67.46 136.59,67.3 136.99,67.3 137.15,67.14 137.25,67.14 v1(137.58,66.81)
  TOP w0.165: U14.N10 157.49,40.73 v6(157.81,41.05)
  IN3 w0.152: v1(137.58,66.81) 137.78,66.81 138.08,66.51 138.08,65.47 139.26,64.29 139.26,62.38 140,61.63 140,59.49 146.86,52.63 147.5,52.63 148.31,51.82 148.31,51.08 152.13,47.26 152.13,47.07 151.89,46.83 151.89,46.64 152.02,46.51 152.21,46.51 152.45,46.75 152.64,46.75 152.77,46.62 152.77,46.43 152.02,45.68 152.02,45.49 152.16,45.35 152.35,45.35 153.1,46.1 153.29,46.1 153.42,45.97 153.42,45.78 152.42,44.78 152.42,44.59 152.55,44.45 152.74,44.45 153.74,45.46 153.93,45.46 154.07,45.32 154.07,45.13 152.95,44.01 152.95,43.83 153.08,43.69 153.27,43.69 154.39,44.81 154.58,44.81 154.71,44.68 154.71,44.49 153.86,43.63 153.86,43.45 154,43.31 154.19,43.31 155.04,44.16 155.75,44.16 155.93,43.99 155.93,43.69 155.75,43.52 155.4,43.52 155.27,43.38 155.27,43.19 155.4,43.06 155.82,43.06 155.96,42.93 155.96,42.74 155.82,42.6 155.4,42.6 155.27,42.47 155.27,42.28 155.4,42.15 155.57,42.15 155.7,42.01 155.7,41.63 155.88,41.45 157.42,41.45 v6(157.81,41.05)
MA_DQ16: length 43.3
  TOP w0.165: U14.E9 152.29,39.78 v6(152.62,39.45) ; v1(134.06,67.64) 133.9,67.64 U6.AP58
  IN2 w0.076: 134.34,66.65 134.32,66.67 134.32,67.38 v1(134.06,67.64)
  IN2 w0.191: v6(152.62,39.45) 152.22,39.85 148.18,39.85 147.37,40.67 147.37,43.05 147.88,43.56 147.88,44.78 147.69,44.97 147.05,44.97 146.86,45.16 146.86,45.43 147.05,45.62 147.69,45.62 147.88,45.81 147.88,46.07 147.69,46.26 147.05,46.26 146.86,46.45 146.86,49.87 146.15,50.58 146.15,53.01 145.64,53.51 145.64,56.92 139.39,63.18 137.44,63.18 135.78,64.84 135.01,64.84 134.34,65.51 134.34,66.65
MA_DQ17: length 42.7
  TOP w0.165: U14.D9 151.64,39.77 v6(151.32,39.45) ; U6.AR58 133.7,67.3 133.93,67.07 v1(133.93,66.91)
  IN2 w0.191: v6(151.32,39.45) 150.92,39.05 149.59,39.05 149.53,38.99 148.25,38.99 146.89,40.35 146.89,43.03 146.44,43.47 146.44,49.7 145.73,50.41 145.73,52.83 145.22,53.34 145.22,55.84 144.62,56.44 144.62,56.71 144.72,56.81 144.72,57.08 144.53,57.27 144.27,57.27 144.17,57.17 143.9,57.17 143.71,57.36 143.71,57.63 143.81,57.73 143.81,58 143.62,58.19 143.35,58.19 143.25,58.08 142.98,58.08 142.79,58.27 142.79,58.54 142.89,58.64 142.89,58.91 142.7,59.1 142.43,59.1 142.33,59 142.06,59 141.88,59.19 141.88,59.46 141.98,59.56 141.98,59.83 141.79,60.02 141.52,60.02 141.42,59.92 141.15,59.92 140.96,60.11 140.96,60.38 141.06,60.48 141.06,60.74 140.87,60.93 140.6,60.93 140.5,60.83 140.23,60.83 139.93,61.13 139.93,61.75 138.93,62.76 137.32,62.76 135.65,64.42 134.65,64.42 133.93,65.15 v1(133.93,66.91)
MA_DQ18: length 44.9
  TOP w0.165: U14.F10 153.27,40.98 v6(153.27,41.05) ; U6.AM57 132.79,69.25 v1(133.14,68.9)
  IN2 w0.076: 133.55,71.15 133.44,71.15 132.74,70.45 132.74,69.3 v1(133.14,68.9)
  IN2 w0.191: 133.55,71.15 135.4,71.15 136.52,70.03 136.52,68.62 137.44,67.71 137.82,67.71 138.19,67.35 139.65,67.35 144.51,62.49 145.02,62.49 152.78,54.73 152.78,44.15 153.49,43.44 153.49,41.71 153.27,41.48 v6(153.27,41.05)
MA_DQ19: length 45.6
  TOP w0.165: v6(152.62,41.85) 152.94,41.53 U14.F11 ; v1(133.14,70.22) 132.82,70.55 U6.AK57
  IN2 w0.191: v6(152.62,41.85) 153.03,42.27 153.03,43.31 151.8,44.54 151.8,53.41 151.69,53.52 151.69,53.79 152.21,54.3 152.21,54.55 152,54.76 151.75,54.76 151.24,54.25 150.97,54.25 150.78,54.44 150.78,54.7 151.09,55.02 151.09,55.28 150.9,55.47 150.63,55.47 150.32,55.16 150.05,55.16 149.86,55.35 149.86,55.62 150.17,55.93 150.17,56.2 149.98,56.39 149.72,56.39 149.4,56.08 149.13,56.08 148.84,56.38 148.84,58.08 144.85,62.07 144.33,62.07 140.52,65.89 139.23,65.89 137.75,67.37 137.3,67.37 136.18,68.48 136.18,69.89 135.26,70.81 133.44,70.81 133.14,70.51 v1(133.14,70.22)
MA_DQ20: length 45.5
  TOP w0.165: U6.AL58 133.71,69.9 v1(134.03,69.57) ; U14.E10 152.29,40.73 v6(152.62,41.05)
  IN2 w0.191: v1(134.03,69.57) 134.32,69.57 135.45,68.45 135.45,68.17 136.72,66.9 136.72,65.92 137.87,64.77 140.11,64.77 144.44,60.45 145.29,60.45 147.21,58.53 147.21,54.72 147.5,54.43 147.77,54.43 148.46,55.11 148.72,55.11 148.91,54.92 148.91,54.65 148.23,53.97 148.23,53.7 148.42,53.51 148.69,53.51 149.37,54.2 149.64,54.2 149.83,54.01 149.83,53.74 149.15,53.05 149.15,52.78 149.9,52.03 149.9,43.37 149.5,42.98 149.5,41.81 149.86,41.45 152.22,41.45 v6(152.62,41.05)
MA_DQ21: length 45.1
  TOP w0.165: v6(151.97,41.85) 152.29,41.53 U14.E11 ; U6.AK58 133.72,70.55 v1(134.04,70.22)
  IN2 w0.191: v1(134.04,70.22) 134.16,70.22 135.79,68.59 135.79,68.31 137.07,67.03 137.07,66.08 137.82,65.33 140.48,65.33 144.28,61.53 144.79,61.53 148.42,57.91 148.42,56.01 150.93,53.5 151.07,53.5 151.26,53.31 151.26,53.04 151.07,52.85 150.51,52.85 150.32,52.66 150.32,52.4 150.51,52.21 151.19,52.21 151.38,52.02 151.38,51.75 151.19,51.56 150.51,51.56 150.32,51.37 150.32,51.1 150.51,50.91 151.19,50.91 151.38,50.72 151.38,50.45 151.19,50.26 150.51,50.26 150.32,50.07 150.32,49.81 150.51,49.62 151.19,49.62 151.38,49.43 151.38,49.16 151.19,48.97 150.51,48.97 150.32,48.78 150.32,43.58 151.51,42.39 151.51,42.31 v6(151.97,41.85)
MA_DQ22: length 44.1
  TOP w0.165: U6.AR57 132.74,67.3 133.08,66.96 v1(133.08,66.95) ; v6(153.27,39.45) 152.94,39.78 U14.F9
  IN2 w0.191: v1(133.08,66.95) 133.08,65.03 134.39,63.71 135.45,63.71 137.24,61.92 138.43,61.92 139.1,61.25 139.1,60.49 142.79,56.8 142.79,55.96 144.39,54.36 144.39,52.46 144.68,52.17 144.68,50.27 145.61,49.34 145.61,42.91 146.02,42.49 146.02,39.65 147.55,38.13 149.25,38.13 149.5,37.87 152.48,37.87 153.16,38.56 153.16,39.34 v6(153.27,39.45)
MA_DQ23: length 43.8
  TOP w0.165: v6(152.61,38.65) 152.94,38.98 U14.F8 ; U6.AN57 132.77,68.6 v1(133.09,68.27)
  IN2 w0.076: 133.5,66.37 133.5,67.86 v1(133.09,68.27)
  IN2 w0.191: 133.5,66.37 133.5,66.37 133.5,65.09 134.52,64.07 135.59,64.07 137.31,62.34 138.75,62.34 139.52,61.58 139.52,60.66 143.21,56.97 143.21,56.13 143.33,56.01 143.92,56.01 144.11,55.82 144.11,55.23 144.81,54.53 144.81,52.83 145.31,52.32 145.31,50.23 146.02,49.52 146.02,43.13 146.46,42.7 146.46,39.85 147.75,38.56 149.43,38.56 149.74,38.25 151.99,38.25 152.39,38.65 v6(152.61,38.65)
MA_DQ24: length 41.4
  TOP w0.165: U14.B10 150.34,40.73 v6(150.02,41.05) ; U6.AP55 132.12,67.58 v1(132.26,67.58)
  IN3 w0.152: v6(150.02,41.05) 149.2,41.87 149.2,47.55 148.13,48.62 148.13,48.81 148.32,49.01 148.32,49.2 148.19,49.33 148,49.33 147.8,49.13 147.61,49.13 147.48,49.27 147.48,49.46 147.68,49.66 147.68,49.84 147.54,49.98 147.35,49.98 147.16,49.78 146.97,49.78 146.83,49.91 146.83,50.1 147.03,50.3 147.03,50.49 146.9,50.63 146.71,50.63 146.51,50.43 146.32,50.43 146.19,50.56 146.19,50.75 146.38,50.95 146.38,51.14 146.25,51.27 146.06,51.27 145.86,51.07 145.67,51.07 145.54,51.21 145.54,51.4 145.74,51.6 145.74,51.78 145.6,51.92 145.41,51.92 145.22,51.72 145.03,51.72 144.89,51.85 144.89,52.04 145.09,52.24 145.09,52.43 144.96,52.57 144.77,52.57 144.57,52.37 144.38,52.37 144.25,52.5 144.25,52.69 144.44,52.89 144.44,53.08 137.94,59.59 137.94,63.74 135.49,66.19 134.7,66.19 134.44,66.45 132.8,66.45 132.63,66.62 132.63,67.21 v1(132.26,67.58)
MA_DQ25: length 41.2
  TOP w0.165: v1(132.09,66.92) 132.09,66.95 U6.AR55 ; U14.C10 150.67,40.97 v6(150.67,41.05)
  IN3 w0.152: v6(150.67,41.05) 150.28,40.67 149.2,40.67 148.54,41.33 148.54,42.19 148.74,42.4 148.74,47.35 143.58,52.51 143.58,52.7 143.7,52.82 143.7,53.01 143.57,53.15 143.38,53.15 143.25,53.02 143.06,53.02 142.93,53.16 142.93,53.35 143.19,53.61 143.19,53.8 143.05,53.93 142.86,53.93 142.61,53.67 142.42,53.67 142.28,53.8 142.28,53.99 142.54,54.25 142.54,54.44 142.41,54.58 142.22,54.58 141.96,54.32 141.77,54.32 141.64,54.45 141.64,54.64 141.89,54.9 141.89,55.09 141.76,55.22 141.57,55.22 141.31,54.96 141.12,54.96 140.99,55.1 140.99,55.29 141.25,55.55 141.25,55.74 137.56,59.43 137.56,63.59 135.33,65.81 134.52,65.81 134.32,66.01 132.75,66.01 132.09,66.67 v1(132.09,66.92)
MA_DQ26: length 44.7
  TOP w0.165: v6(150.01,38.65) 150.34,38.98 U14.B8 ; v1(131.24,68.92) 131.12,68.92 U6.AM54
  IN3 w0.152: v1(131.24,68.92) 130.9,68.92 130.68,68.71 130.68,68.1 130.43,67.85 130.43,67.64 129.84,67.05 129.84,65.37 131.53,63.68 132.28,63.68 132.89,63.07 132.89,62.41 133.17,62.13 133.17,59.62 133.7,59.09 133.87,59.09 134.19,58.76 134.38,58.76 134.45,58.83 134.64,58.83 134.77,58.7 134.77,58.51 134.7,58.44 134.7,58.25 134.84,58.12 135.03,58.12 135.32,58.41 135.51,58.41 135.65,58.28 135.65,58.09 135.35,57.79 135.35,57.6 145.92,47.03 145.92,43.05 146.35,42.62 146.35,39.6 147.94,38.02 149.5,38.02 150.01,38.54 v6(150.01,38.65)
MA_DQ27: length 45.9
  TOP w0.165: U6.AK54 130.91,70.55 v1(131.24,70.22) ; v6(150.66,38.65) 150.99,38.98 U14.C8
  IN3 w0.152: v6(150.66,38.65) 149.66,37.64 147.78,37.64 145.97,39.45 145.97,42.32 145.54,42.75 145.54,46.87 133.71,58.71 133.52,58.71 132.79,59.44 132.79,61.87 128.9,65.76 128.9,67.69 129.81,68.59 129.81,68.85 131.18,70.22 v1(131.24,70.22)
MA_DQ28: length 44
  TOP w0.165: v6(150.07,41.85) 150.34,41.58 U14.B11 ; v1(132.14,69.57) 131.81,69.9 U6.AL55
  IN3 w0.152: v1(132.14,69.57) 132.14,69.57 132.63,70.06 132.63,70.38 132.9,70.65 134.22,70.65 134.66,70.22 134.66,69.1 135.11,68.65 135.11,67.11 138.32,63.9 138.32,61.99 139.06,61.24 139.06,59 149.58,48.48 149.58,46.5 149.71,46.37 149.85,46.37 149.99,46.23 149.99,46.04 149.85,45.91 149.71,45.91 149.58,45.78 149.58,45.59 149.71,45.45 150.34,45.45 150.47,45.32 150.47,45.13 150.34,44.99 149.71,44.99 149.58,44.86 149.58,44.67 149.71,44.54 150.34,44.54 150.47,44.4 150.47,44.21 150.34,44.08 149.71,44.08 149.58,43.95 149.58,43.76 149.71,43.62 150.34,43.62 150.47,43.49 150.47,43.3 150.34,43.17 149.71,43.17 149.58,43.03 149.58,42.34 v6(150.07,41.85)
MA_DQ29: length 44.6
  TOP w0.165: U14.C11 150.99,41.53 v6(150.67,41.85) ; U6.AK55 131.85,70.55 v1(132.18,70.22)
  IN3 w0.152: v6(150.67,41.85) 151.1,42.29 151.1,43.43 150.76,43.78 150.76,43.97 150.89,44.1 151.35,44.1 151.49,44.23 151.49,44.42 151.35,44.56 150.89,44.56 150.76,44.69 150.76,44.88 150.89,45.01 151.35,45.01 151.49,45.15 151.49,45.34 151.35,45.47 150.86,45.47 150.72,45.61 150.72,45.79 150.86,45.93 151.35,45.93 151.49,46.06 151.49,46.25 151.35,46.39 151.24,46.39 151.1,46.52 151.1,47.5 150.82,47.78 150.63,47.78 150.28,47.44 150.1,47.44 149.96,47.58 149.96,47.77 150.3,48.11 150.3,48.3 139.45,59.15 139.45,61.4 138.7,62.15 138.7,64.06 136.69,66.07 136.69,67.88 135.05,69.52 135.05,70.36 134.38,71.04 132.74,71.04 132.18,70.47 v1(132.18,70.22)
MA_DQ30: length 42.8
  TOP w0.165: v1(131.14,66.92) 131.13,66.92 131.12,66.92 130.8,67.25 U6.AR54 ; v6(150.01,39.45) 150.34,39.78 U14.B9
  IN3 w0.152: v6(150.01,39.45) 149.76,39.45 149.38,39.07 148.56,39.07 147.12,40.51 147.12,43.23 146.69,43.66 146.69,47.35 142.34,51.7 142.34,51.7 139.11,54.93 139.11,55.12 139.4,55.42 139.4,55.6 139.27,55.74 139.08,55.74 138.78,55.44 138.59,55.44 138.46,55.58 138.46,55.76 138.76,56.06 138.76,56.25 138.62,56.39 138.43,56.39 138.14,56.09 137.95,56.09 137.81,56.22 137.81,56.41 138.11,56.71 138.11,56.9 137.98,57.03 137.79,57.03 137.56,56.8 137.37,56.8 137.23,56.94 137.23,57.13 137.46,57.36 137.46,57.54 136.16,58.85 136.16,62.83 135,63.98 134.35,63.98 133.76,64.57 131.77,64.57 130.81,65.53 130.81,66.59 v1(131.14,66.92)
MA_DQ31: length 44
  TOP w0.165: v1(131.29,68.27) 131.12,68.27 U6.AN54 ; v6(150.66,39.45) 150.99,39.78 U14.C9
  IN3 w0.152: v1(131.29,68.27) 131.21,68.27 130.76,67.82 130.76,67.59 130.3,67.13 130.3,65.46 131.6,64.16 133.63,64.16 134.09,63.7 134.09,61.72 134.33,61.48 135.06,61.48 135.46,61.08 135.46,59.01 136.36,58.11 136.36,57.92 136.06,57.62 136.06,57.43 136.2,57.3 136.39,57.3 136.53,57.44 136.72,57.44 136.85,57.3 136.85,57.12 136.71,56.97 136.71,56.78 146.3,47.19 146.3,43.26 146.74,42.82 146.74,40.11 148.23,38.61 149.43,38.61 149.86,39.04 150.25,39.04 v6(150.66,39.45)
MA_DQ32: length 33.9
  TOP w0.076: 135.38,61.72 135.36,61.7 134.7,61.7 134.44,61.95 134.44,62.81 134.07,63.18 134.07,63.63 133.62,64.08 U6.AY58
  TOP w0.165: U13.R9 139.98,39.78 v6(140.31,39.45) ; 135.38,61.72 v1(135.73,61.72)
  IN2 w0.191: v6(140.31,39.45) 140.71,39.05 142.86,39.05 144.14,40.34 144.14,48.51 142.95,49.71 142.95,52.96 141.35,54.56 141.35,56.09 135.82,61.63 v1(135.73,61.72)
MA_DQ33: length 34.8
  TOP w0.076: U6.AW58 133.96,64.5 133.96,64.34 133.94,64.32 133.94,64.05 133.96,64.03 133.96,63.97 134.45,63.48 134.45,63.03 134.93,62.56 135.21,62.56 v1(135.47,62.3)
  TOP w0.165: U13.T8 140.63,38.98 v6(140.96,38.65)
  IN2 w0.191: v1(135.47,62.3) 135.84,62.3 141.77,56.38 141.77,54.95 143.37,53.35 143.37,49.88 144.58,48.68 144.58,40.06 143.09,38.57 142.28,38.57 141.94,38.23 141.38,38.23 v6(140.96,38.65)
MA_DQ34: length 35.7
  TOP w0.076: v1(133.63,61.37) 133.22,61.37 133.12,61.47 133.12,62.2 132.61,62.71 132.61,63.43 132.41,63.64 132.41,64.05 U6.AY56
  TOP w0.165: v6(140.96,41.85) 140.96,41.77 U13.T11
  IN2 w0.191: v1(133.63,61.37) 133.28,61.37 133.2,61.29 133.2,60.02 133.35,59.87 133.35,58.7 133.74,58.31 133.74,57.49 134.22,57.01 134.22,56.58 134.52,56.28 134.79,56.28 135.15,56.64 135.41,56.64 135.6,56.45 135.6,56.18 135.25,55.82 135.25,55.55 135.44,55.36 135.7,55.36 136.06,55.72 136.33,55.72 136.52,55.53 136.52,55.26 136.16,54.9 136.16,54.64 136.3,54.5 136.67,54.5 136.98,54.8 137.25,54.8 137.44,54.61 137.44,54.35 137.08,53.99 137.08,53.15 137.43,52.8 137.43,50.81 139.04,49.2 139.04,48.93 138.61,48.49 138.61,48.17 138.8,47.98 139.12,47.98 139.55,48.42 139.82,48.42 140.39,47.85 140.39,45.69 139.88,45.18 139.88,44.92 140.14,44.65 140.78,44.65 140.97,44.46 140.97,44.19 140.78,44 140.04,44 139.88,43.84 139.88,43.61 140.33,43.16 141.08,43.16 141.43,42.82 141.43,42.32 v6(140.96,41.85)
MA_DQ35: length 36.2
  TOP w0.076: U6.AW56 132.27,64.6 131.98,64.31 131.98,64.06 132.12,63.93 132.12,63.7 132.45,63.36 132.45,62.64 132.87,62.22 132.87,61.82
  TOP w0.165: v1(133.65,60.74) 133.54,60.74 132.87,61.41 132.87,61.82 ; v6(140.97,41.05) 140.63,40.71 U13.T10
  IN2 w0.191: v6(140.97,41.05) 141.38,40.64 141.86,40.64 142.43,41.21 142.43,42.94 142.01,43.36 142.01,47.81 140.65,49.18 140.65,50.57 140.22,51 140.22,51.27 140.67,51.72 140.67,51.99 140.48,52.18 140.21,52.18 139.76,51.73 139.49,51.73 139.3,51.92 139.3,52.19 139.75,52.64 139.75,52.91 139.56,53.1 139.29,53.1 138.84,52.65 138.57,52.65 138.28,52.94 138.28,53.52 138.47,53.7 138.88,53.7 139.06,53.89 139.06,54.16 138.88,54.35 138.47,54.35 138.28,54.54 138.28,55.55 138.13,55.7 137.54,55.7 136.43,56.8 136.43,57.61 136.33,57.71 135.53,57.71 134.42,58.81 134.42,59.73 134.29,59.87 134.29,60.76 134.14,60.91 133.83,60.91 v1(133.65,60.74)
MA_DQ36: length 36.9
  TOP w0.076: v1(135.43,62.94) 135.43,63.22 134.6,64.05 134.6,64.32 133.85,65.08 133.85,65.26 U6.AV58
  TOP w0.165: v6(140.31,38.65) 139.98,38.98 U13.R8
  IN2 w0.191: v6(140.31,38.65) 141.09,37.87 142.16,37.87 142.39,38.1 143.21,38.1 145.01,39.89 145.01,48.84 143.79,50.06 143.79,53.7 142.19,55.3 142.19,56.55 135.8,62.94 v1(135.43,62.94)
MA_DQ37: length 36.5
  TOP w0.076: U6.AU58 132.86,66.14 132.66,65.93 132.66,65.69 132.67,65.68 132.67,65.37 132.64,65.33 132.64,65.13 132.66,65.08 132.71,64.99 132.73,64.94 132.73,64.73 132.71,64.68 132.65,64.57 132.66,64.44 132.71,64.32 132.73,64.32 132.74,64.02 132.74,63.82 132.94,63.62 132.94,62.87 133.18,62.63 v1(133.59,62.63)
  TOP w0.165: v6(140.96,39.45) 140.63,39.78 U13.T9
  IN2 w0.191: v1(133.59,62.63) 133.99,62.63 134.09,62.53 134.09,61.64 134.2,61.52 135.25,61.52 136.77,60.01 136.77,59.64 136.87,59.54 137.24,59.54 138.25,58.53 138.25,57.79 138.47,57.56 139.21,57.56 140.93,55.84 140.93,54.27 142.53,52.67 142.53,49.5 143.69,48.34 143.69,40.54 142.6,39.45 v6(140.96,39.45)
MA_DQ38: length 36.8
  TOP w0.076: U6.AV56 132.38,65.14 132.52,65.01 132.54,64.95 132.56,64.9 132.56,64.77 132.56,64.75 132.51,64.66 132.49,64.63 132.49,64.6 132.46,64.55 132.49,64.45 132.48,64.43 132.5,64.38 132.51,64.36 132.52,64.36 132.55,64.28 132.56,64.26 132.58,63.97 132.58,63.75 132.78,63.55 132.78,62.8 133.57,62.01 v1(133.63,62.01)
  TOP w0.165: v6(140.3,41.85) 140.3,41.77 U13.R11
  IN2 w0.076: 133.01,59.72 132.95,59.77 132.95,61.75 133.2,62.01 v1(133.63,62.01)
  IN2 w0.191: v6(140.3,41.85) 139.9,42.25 139.43,42.25 139.06,42.63 139.06,43.36 138.76,43.65 138.26,43.65 138.18,43.73 138.18,44.14 138.37,44.33 139.27,44.33 139.46,44.52 139.46,44.78 139.27,44.97 138.37,44.97 138.18,45.16 138.18,45.43 138.37,45.62 139.73,45.62 139.92,45.81 139.92,46.08 139.73,46.27 138.57,46.27 138.38,46.46 138.38,46.73 138.57,46.92 139.78,46.92 139.97,47.11 139.97,47.37 139.78,47.56 138.42,47.56 138.18,47.8 138.18,49.47 137.01,50.64 137.01,52.63 135.24,54.4 135.24,54.97 133.32,56.88 133.32,58.06 133.01,58.38 133.01,59.72
MA_DQ39: length 37.7
  TOP w0.076: U6.AU56 132.38,65.9 132.09,65.61 132.09,65.37 132.09,65.36 132.09,65.07 131.82,64.79 131.82,63.98 131.95,63.84 131.95,63.63 132.28,63.3 132.28,62.57 132.61,62.24 132.61,61.7
  TOP w0.165: 132.61,61.7 132.61,60.63 133.72,59.52 v1(133.96,59.52) ; v6(140.32,41.07) 140.32,40.99 139.98,40.65 U13.R10
  IN2 w0.191: v6(140.32,41.07) 140.32,41.36 140.41,41.45 141.97,41.45 142.07,41.55 142.07,42.74 141.22,43.59 141.22,43.7 141.59,44.07 141.59,44.82 141.4,45.01 140.99,45.01 140.8,45.2 140.8,45.47 140.99,45.66 141.4,45.66 141.59,45.85 141.59,46.12 141.4,46.31 141.03,46.31 140.84,46.5 140.84,46.76 141.03,46.95 141.4,46.95 141.59,47.14 141.59,47.64 139.8,49.43 139.8,49.7 140.23,50.13 140.23,50.4 140.04,50.59 139.77,50.59 139.34,50.16 139.07,50.16 138.88,50.35 138.88,50.62 139.31,51.05 139.31,51.32 139.12,51.51 138.85,51.51 138.42,51.08 138.15,51.08 137.86,51.37 137.86,51.77 138.2,52.11 138.2,52.43 137.86,52.77 137.86,54.79 133.96,58.68 v1(133.96,59.52)
MA_DQ40: length 39
  TOP w0.076: 131.58,60.2 131.93,60.54 131.93,62.15 131.79,62.29 131.79,63.09 131.45,63.42 131.45,63.57 131.23,63.8 131.23,64.15 U6.AY54
  TOP w0.165: U13.M9 138.03,39.78 v6(137.7,39.45) ; 131.58,60.2 v1(131.42,60.04)
  IN3 w0.152: v6(137.7,39.45) 139.33,37.82 142.22,37.82 144.55,40.15 144.55,46.54 132.15,58.94 132.15,59.31 v1(131.42,60.04)
MA_DQ41: length 40.6
  TOP w0.076: U6.AW54 131.19,64.6 131.48,64.31 131.49,64.31 131.49,63.77 131.62,63.64 131.62,63.49 131.95,63.16 131.95,62.44 132.13,62.26 132.13,60.5 131.97,60.34 131.97,60.2
  TOP w0.165: U13.N9 138.68,39.78 v6(138.35,39.45) ; v1(131.42,59.39) 131.97,59.93 131.97,60.2
  IN3 w0.152: v1(131.42,59.39) 131.86,58.95 131.86,58.59 133.1,57.34 133.2,57.34 141.45,49.1 141.45,48.91 141.32,48.78 141.32,48.6 141.45,48.46 141.64,48.46 141.77,48.59 141.96,48.59 142.09,48.45 142.09,48.26 141.97,48.14 141.97,47.95 142.1,47.81 142.29,47.81 142.42,47.94 142.61,47.94 142.74,47.81 142.74,47.62 142.61,47.49 142.61,47.3 142.75,47.17 142.94,47.17 143.06,47.29 143.25,47.29 143.39,47.16 143.39,46.97 143.26,46.84 143.26,46.65 143.39,46.52 143.58,46.52 143.71,46.65 143.9,46.65 144.17,46.38 144.17,40.31 142.11,38.25 139.52,38.25 139.04,38.73 139.04,38.76 v6(138.35,39.45)
MA_DQ42: length 40.2
  TOP w0.076: U6.AY52 129.99,64.04 129.99,62.39 130.3,62.08 130.3,61.11 129.59,60.4 129.59,60.2
  TOP w0.165: 129.59,60.2 129.59,59.99 129.9,59.69 v1(130.15,59.69) ; v6(138.99,41.06) 138.99,40.96 U13.N10
  IN3 w0.152: v6(138.99,41.06) 139.4,41.47 141.76,41.47 141.99,41.69 141.99,42.52 141.36,43.14 140.63,43.14 139.42,44.35 139.42,47.44 139.15,47.71 138.96,47.71 138.36,47.11 138.17,47.11 138.03,47.24 138.03,47.43 138.64,48.03 138.64,48.22 138.5,48.36 138.31,48.36 137.71,47.75 137.52,47.75 137.39,47.89 137.39,48.08 137.99,48.68 137.99,48.87 137.86,49 137.67,49 137.06,48.4 136.88,48.4 136.74,48.53 136.74,48.72 137.34,49.33 137.34,49.52 137.21,49.65 137.02,49.65 136.59,49.22 136.4,49.22 136.27,49.35 136.27,49.54 136.7,49.97 136.7,50.16 129.54,57.32 129.54,59.08 v1(130.15,59.69)
MA_DQ43: length 40.9
  TOP w0.076: v1(129.79,61.21) 130.14,61.56 130.14,62.01 129.82,62.32 129.82,63.79 129.55,64.06 129.55,64.25 129.6,64.35 129.62,64.41 129.84,64.63 U6.AW52
  TOP w0.165: U13.N11 139,41.77 v6(139,41.85)
  IN3 w0.152: v1(129.79,61.21) 129.16,60.58 129.16,57.16 134.69,51.63 134.69,50.04 135.02,49.71 135.02,49.52 134.6,49.1 134.6,48.91 134.73,48.77 134.92,48.77 135.57,49.42 135.76,49.42 135.89,49.29 135.89,49.1 134.76,47.96 134.76,47.77 134.89,47.64 135.08,47.64 135.99,48.55 136.18,48.55 136.32,48.42 136.32,48.23 135.4,47.32 135.4,47.13 135.54,46.99 135.73,46.99 136.64,47.9 136.83,47.9 136.96,47.77 136.96,47.58 136.05,46.67 136.05,46.48 136.18,46.35 136.37,46.35 137.29,47.26 137.48,47.26 137.61,47.12 137.61,46.93 137.04,46.36 137.04,46.17 137.17,46.04 137.36,46.04 137.93,46.61 138.12,46.61 139.04,45.69 139.04,43.21 139.24,43 139.24,42.09 v6(139,41.85)
MA_DQ44: length 41.4
  TOP w0.076: U6.AV54 131.26,65.31 131.26,65.18 131.65,64.79 131.65,63.84 131.79,63.71 131.79,63.56 132.12,63.23 132.12,62.51 132.36,62.26 132.36,61.19
  TOP w0.165: v1(131.42,58.76) 131.61,58.76 132.36,59.51 132.36,61.19 ; U13.P9 139.33,39.78 v6(139.66,39.45)
  IN3 w0.152: v1(131.42,58.76) 131.42,58.4 132.85,56.96 133.05,56.96 135.03,54.98 135.03,54.35 135.67,53.7 135.86,53.7 135.92,53.77 136.11,53.77 136.25,53.63 136.25,53.45 136.18,53.38 136.18,53.19 136.32,53.06 136.51,53.06 136.57,53.12 136.76,53.12 136.89,52.99 136.89,52.8 136.83,52.73 136.83,52.55 136.96,52.41 137.15,52.41 137.22,52.48 137.41,52.48 137.54,52.34 137.54,52.15 137.48,52.09 137.48,51.9 137.61,51.76 137.8,51.76 137.86,51.83 138.05,51.83 138.19,51.69 138.19,51.51 138.12,51.44 138.12,51.25 138.26,51.12 138.45,51.12 138.51,51.18 138.7,51.18 138.83,51.05 138.83,50.86 138.77,50.79 138.77,50.61 138.9,50.47 139.09,50.47 139.16,50.54 139.35,50.54 139.48,50.4 139.48,50.21 139.42,50.15 139.42,49.96 139.55,49.82 139.74,49.82 139.8,49.89 139.99,49.89 140.13,49.75 140.13,49.57 140.06,49.5 140.06,49.31 140.2,49.18 140.39,49.18 140.45,49.24 140.64,49.24 140.77,49.11 140.77,48.92 140.71,48.85 140.71,48.67 142.24,47.14 142.24,46.95 142.04,46.75 142.04,46.56 142.17,46.43 142.36,46.43 142.56,46.63 142.75,46.63 142.88,46.49 142.88,46.3 142.68,46.1 142.68,45.91 142.82,45.78 143.01,45.78 143.21,45.98 143.4,45.98 143.79,45.59 143.79,40.61 142.24,39.06 140.05,39.06 v6(139.66,39.45)
MA_DQ45: length 42.6
  TOP w0.076: v1(131.42,60.67) 130.95,60.67 130.63,60.99 130.63,62.22 130.32,62.53 130.32,64.24 130.27,64.34 130.23,64.45 130.23,64.58 130.3,64.73 130.3,64.94 130.27,64.99 130.23,65.08 130.23,65.09 130.23,65.93 130.43,66.14 U6.AU54
  TOP w0.165: v6(137.71,38.65) 138.03,38.97 U13.M8
  IN3 w0.152: v6(137.71,38.65) 138.92,37.44 142.38,37.44 144.96,40.02 144.96,46.67 132.41,59.21 132.41,59.67 v1(131.42,60.67)
MA_DQ46: length 41.4
  TOP w0.076: U6.AV52 129.95,65.14 130.08,65.01 130.13,64.9 130.13,64.77 130.09,64.67 130.06,64.61 130.06,64.41 130.15,64.21 130.15,62.46 130.47,62.15 130.47,60.67 130.62,60.52 130.62,60.2
  TOP w0.165: 130.62,60.2 130.62,59.47 v1(130.15,59) ; U13.M10 138.37,40.99 v6(138.37,41.06)
  IN3 w0.152: v6(138.37,41.06) 138.76,40.67 141.15,40.67 141.35,40.87 141.83,40.87 142.38,41.41 142.38,44.24 142.07,44.55 141.88,44.55 141.09,43.76 140.9,43.76 140.76,43.89 140.76,44.08 141.56,44.87 141.56,45.06 141.42,45.2 141.23,45.2 140.39,44.36 140.2,44.36 140.07,44.49 140.07,44.68 140.91,45.52 140.91,45.71 140.77,45.84 140.59,45.84 140.12,45.38 139.94,45.38 139.8,45.52 139.8,45.71 140.26,46.17 140.26,46.36 139.8,46.82 139.8,47.6 130,57.4 130,58.85 v1(130.15,59)
MA_DQ47: length 42.2
  TOP w0.076: v1(129.74,61.85) 129.66,61.93 129.66,63.72 129.38,64 129.38,64.29 129.41,64.34 129.46,64.45 129.5,64.75 129.5,65.8 U6.AU52
  TOP w0.165: v6(138.35,41.85) 138.35,41.77 U13.M11
  IN3 w0.152: v1(129.74,61.85) 129.16,61.85 128.78,61.47 128.78,57 134.22,51.57 134.22,47.77 135,46.99 135,46.8 134.73,46.53 134.73,46.34 134.87,46.21 135.05,46.21 135.32,46.48 135.51,46.48 135.65,46.34 135.65,46.16 135.26,45.77 135.26,45.58 135.4,45.45 135.59,45.45 135.97,45.83 136.16,45.83 136.29,45.7 136.29,45.51 135.54,44.76 135.54,44.57 135.68,44.44 135.87,44.44 137.09,45.66 137.28,45.66 137.41,45.52 137.41,45.33 136.29,44.21 136.29,44.02 136.42,43.89 136.61,43.89 138.34,45.61 138.52,45.61 138.66,45.48 138.66,45.29 137.32,43.95 137.32,43.76 137.45,43.62 137.64,43.62 137.91,43.89 138.1,43.89 138.56,43.43 138.56,43 138.76,42.8 138.76,42.49 138.35,42.09 v6(138.35,41.85)
MA_DQ48: length 40
  TOP w0.165: U6.AK40 122.38,70.55 v1(122.71,70.22) ; v6(131.85,38.65) 131.85,38.72 U13.C8
  IN3 w0.076: v1(122.71,70.22) 121.82,69.33 121.82,66.7 121.51,66.4
  IN3 w0.152: 121.51,66.4 121.29,66.17 121.29,63.73 121.58,63.43 122.16,63.43 122.47,63.12 122.47,60.52 123.75,59.23 123.75,57.33 123.37,56.95 123.37,55.85 127.89,51.33 127.89,40.13 129.75,38.27 131.47,38.27 v6(131.85,38.65)
MA_DQ49: length 39.6
  TOP w0.165: U6.AK42 123.35,70.55 v1(123.62,70.27) ; v6(131.2,38.65) 131.53,38.98 U13.B8
  IN3 w0.152: v1(123.62,70.27) 122.95,69.6 122.78,69.6 122.53,69.35 122.04,68.86 122.04,66.41 122.21,66.23 122.21,63.72 122.71,63.22 122.71,61.01 124.36,59.36 124.36,59.03 124.13,58.8 124.13,56.73 124,56.6 123.88,56.6 123.75,56.46 123.75,56.27 123.88,56.14 124,56.14 124.13,56 124.13,55.62 124.4,55.35 124.71,55.35 124.88,55.18 124.88,54.88 125.05,54.71 125.35,54.71 125.52,54.54 125.52,54.23 125.69,54.06 126,54.06 126.17,53.89 126.17,53.58 126.34,53.41 126.65,53.41 126.82,53.24 126.82,52.94 126.99,52.77 127.29,52.77 127.46,52.6 127.46,52.29 128.27,51.48 128.27,40.34 129.96,38.65 v6(131.2,38.65)
MA_DQ50: length 37.4
  TOP w0.165: v1(124.58,69.05) 124.28,69.05 U6.AM43 ; v6(131.86,41.05) 132.18,40.73 U13.C10
  IN3 w0.076: 125.09,67.05 125.09,68.39 124.58,68.91 v1(124.58,69.05)
  IN3 w0.152: 125.09,67.05 125.09,66.5 125.5,66.09 125.5,63.5 125.32,63.32 125.32,62.28 125.73,61.87 125.73,61.39 126.77,60.35 126.77,56.6 132.08,51.3 132.08,49.22 131.95,49.09 131.12,49.09 130.99,48.96 130.99,48.77 131.12,48.63 131.95,48.63 132.08,48.5 132.08,48.31 131.95,48.18 131.12,48.18 130.99,48.04 130.99,45.73 131.22,45.5 131.22,45.12 130.99,44.89 130.99,44.51 131.22,44.29 131.22,43.9 130.99,43.68 130.99,42.98 130.43,42.42 130.43,41.27 131.06,40.64 131.44,40.64 v6(131.86,41.05)
MA_DQ51: length 37.4
  TOP w0.165: U6.AM45 125.33,68.98 v1(125.53,68.98) ; v6(131.21,41.85) 131.53,41.53 U13.B11
  IN3 w0.076: v1(125.53,68.98) 125.98,69.44 125.98,70.31 126.25,70.57 126.75,70.57
  IN3 w0.152: v6(131.21,41.85) 131.6,41.45 132.05,41.45 133.22,42.62 133.22,51.77 128.22,56.77 128.22,59.65 128.53,59.96 128.53,62.22 128.16,62.59 128.06,62.59 127.48,63.17 127.48,66.41 127.86,66.79 127.86,67.8 126.97,68.69 126.97,70.34 126.75,70.57
MA_DQ52: length 36.6
  TOP w0.165: U6.AK45 125.25,70.55 v1(125.51,70.28) ; v6(131.86,41.85) 132.18,41.53 U13.C11
  IN3 w0.076: v1(125.51,70.28) 125.13,69.9 125.13,68.82 125.82,68.14 126.66,68.14 126.9,67.89 126.9,67.39
  IN3 w0.152: v6(131.86,41.85) 132.84,42.84 132.84,43.72 132.71,43.85 132.11,43.85 131.98,43.98 131.98,44.17 132.11,44.31 132.71,44.31 132.84,44.44 132.84,44.63 132.71,44.76 132.11,44.76 131.98,44.9 131.98,45.09 132.11,45.22 132.71,45.22 132.84,45.36 132.84,51.61 127.53,56.92 127.53,62.56 127,63.09 127,67.29 126.9,67.39
MA_DQ53: length 38.9
  TOP w0.165: v1(124.58,70.35) 124.28,70.35 U6.AK43 ; U13.B10 131.53,40.73 v6(131.21,41.05)
  IN3 w0.076: 125.92,67.73 125.92,67.8 124.97,68.75 124.97,69.96 v1(124.58,70.35)
  IN3 w0.152: v6(131.21,41.05) 131.21,41.26 130.81,41.66 130.81,42.06 131.01,42.27 131.37,42.27 131.6,42.49 131.6,45.7 131.73,45.83 132.33,45.83 132.46,45.97 132.46,46.16 132.33,46.29 131.5,46.29 131.37,46.42 131.37,46.61 131.5,46.75 132.33,46.75 132.46,46.88 132.46,47.07 132.33,47.2 131.5,47.2 131.37,47.34 131.37,47.53 131.5,47.66 132.33,47.66 132.46,47.79 132.46,51.45 127.15,56.76 127.15,62.38 125.93,63.6 125.93,66.8 126.03,66.9 126.03,67.37 125.92,67.48 125.92,67.73
MA_DQ54: length 38
  TOP w0.165: v1(122.71,68.92) 122.38,69.25 U6.AM40 ; v6(131.85,39.45) 132.18,39.78 U13.C9
  IN3 w0.152: v6(131.85,39.45) 131.44,39.04 130.18,39.04 128.65,40.56 128.65,48.94 128.9,49.19 128.9,49.4 128.65,49.65 128.65,49.86 128.9,50.1 128.9,50.31 128.65,50.56 128.65,50.77 128.9,51.02 128.9,51.23 128.65,51.47 128.65,52.04 124.85,55.84 124.85,56.22 124.72,56.35 124.64,56.35 124.51,56.49 124.51,56.67 124.64,56.81 124.72,56.81 124.85,56.94 124.85,57.13 124.72,57.27 124.64,57.27 124.51,57.4 124.51,57.59 124.64,57.72 124.72,57.72 124.85,57.86 124.85,58.05 124.72,58.18 124.64,58.18 124.51,58.31 124.51,58.5 124.64,58.64 124.72,58.64 124.85,58.77 124.85,59.75 123.16,61.44 123.16,63.11 122.56,63.72 122.56,66.48 122.28,66.76 122.28,68.49 v1(122.71,68.92)
MA_DQ55: length 38
  TOP w0.165: v6(131.2,39.45) 131.53,39.78 U13.B9 ; v1(123.6,68.34) 123.6,68.78 U6.AM42
  IN3 w0.152: v6(131.2,39.45) 130.93,39.45 130.48,39.9 129.9,39.9 129.03,40.77 129.03,43.96 129.17,44.1 129.33,44.1 129.46,44.23 129.46,44.42 129.33,44.56 129.17,44.56 129.03,44.69 129.03,44.88 129.17,45.01 129.33,45.01 129.46,45.15 129.46,45.34 129.33,45.47 129.17,45.47 129.03,45.6 129.03,45.79 129.17,45.93 129.33,45.93 129.46,46.06 129.46,46.25 129.33,46.38 129.17,46.38 129.03,46.52 129.03,46.71 129.17,46.84 129.33,46.84 129.46,46.98 129.46,47.17 129.33,47.3 129.17,47.3 129.03,47.43 129.03,47.62 129.17,47.76 129.33,47.76 129.46,47.89 129.46,48.08 129.33,48.21 129.17,48.21 129.03,48.35 129.03,48.54 129.17,48.67 129.33,48.67 129.46,48.8 129.46,51.93 125.23,56.15 125.23,59.91 123.6,61.54 123.6,63.02 122.9,63.71 122.9,66.38 123.16,66.65 123.16,67.91 v1(123.6,68.34)
MA_DQ56: length 43.4
  TOP w0.165: v1(126.48,69.52) 126.21,69.25 U6.AM46 ; U13.E11 133.48,41.53 v6(133.16,41.85)
  IN2 w0.076: 129.45,58.34 129.45,60.98 129.32,61.11 129.32,62.29 129.79,62.76 129.79,65.43 128.9,66.32 128.9,67.82 128.6,68.13 128.1,68.13 127.7,68.53 127.27,68.53 127.04,68.76 127.04,68.96 v1(126.48,69.52)
  IN2 w0.191: v6(133.16,41.85) 132.44,41.85 132.21,42.08 132.21,42.26 132.45,42.5 133.15,42.5 133.24,42.59 133.24,43.48 133.72,43.95 133.72,44.59 133.52,44.79 130.34,44.79 130.16,44.98 130.16,45.24 130.32,45.41 131.99,45.41 132.18,45.6 132.18,45.87 131.99,46.06 130.87,46.06 130.68,46.25 130.68,47.42 130.45,47.65 130.22,47.65 130.03,47.46 130.03,46.24 129.85,46.06 129.56,46.06 129.38,46.24 129.38,48.67 129.31,48.75 129.31,58.2 129.45,58.34
MA_DQ57: length 43.1
  TOP w0.165: v1(126.48,70.17) 126.1,70.55 U6.AK46 ; v6(133.81,41.05) 134.13,40.73 U13.F10
  IN2 w0.076: 128.87,58.54 129.28,58.95 129.28,60.91 129.15,61.04 129.15,62.35 129.63,62.83 129.63,65.34 128.05,66.92 128.05,67.82 127.68,68.18 127.09,68.18 126.8,68.48 126.32,68.48 126.09,68.71 126.09,69.78 v1(126.48,70.17)
  IN2 w0.191: 128.87,58.54 128.87,48.16 128.96,48.07 128.96,45.8 129.74,45.02 129.74,44.56 129.93,44.37 132.73,44.37 132.94,44.16 132.94,43.89 132.78,43.72 132.04,43.72 131.57,43.26 130.84,43.26 130.37,43.72 129.93,43.72 129.74,43.53 129.74,42.65 129.95,42.44 130.34,42.44 130.58,42.2 130.58,41.81 130.94,41.45 133.41,41.45 v6(133.81,41.05)
MA_DQ58: length 41.5
  TOP w0.165: U13.E9 133.86,39.47 v6(133.86,39.45) ; v1(128.45,69.04) 128.15,69.04 U6.AM49
  IN2 w0.076: 132.31,63.96 132.31,64.21 132.26,64.26 132.26,65.86 131.65,66.47 131.65,67.16 131.7,67.21 131.7,70.46 131.52,70.64 129.11,70.64 128.85,70.38 128.85,69.45 v1(128.45,69.04)
  IN2 w0.191: 132.31,63.96 132.31,56.46 134.22,54.55 134.22,53.98 135.99,52.21 135.99,50.22 137.06,49.15 137.06,43.46 136.93,43.33 136.93,40.51 136.32,39.9 134.31,39.9 v6(133.86,39.45)
MA_DQ59: length 42.3
  TOP w0.165: v6(134.46,39.45) 134.46,39.52 U13.F9 ; U6.AK49 127.92,70.63 v1(127.58,70.97)
  IN2 w0.076: 132.57,64.64 132.57,67.01 132.7,67.14 132.7,69.05 132.57,69.18 132.57,70.39 131.99,70.97 v1(127.58,70.97)
  IN2 w0.191: 132.57,64.64 132.73,64.49 132.73,56.63 134.64,54.72 134.64,54.15 136.41,52.38 136.41,50.39 137.58,49.22 137.58,46.42 137.52,46.36 137.52,43.15 137.27,42.91 137.27,40.29 136.56,39.58 136.56,39.4 136.21,39.05 134.86,39.05 v6(134.46,39.45)
MA_DQ60: length 42.7
  TOP w0.165: v1(127.43,68.92) 127.11,69.25 U6.AM48 ; U13.F11 134.13,41.53 v6(133.81,41.85)
  IN2 w0.076: 129.81,58.23 129.67,58.37 129.67,60.58 129.92,60.83 130.1,60.83 130.19,60.92 130.19,61.99 129.96,62.22 129.96,65.95 129.77,66.14 129.77,67.08 129.51,67.34 129.39,67.34 129.18,67.54 129.18,67.94 128.81,68.32 128.15,68.32 127.54,68.92 v1(127.43,68.92)
  IN2 w0.191: 129.81,58.23 129.81,48.88 131.09,47.59 131.09,46.68 131.3,46.48 131.56,46.48 131.75,46.67 131.75,48.45 131.94,48.64 132.21,48.64 132.4,48.45 132.4,47.16 132.97,46.58 132.97,46.13 132.6,45.76 132.6,45.43 132.82,45.21 133.49,45.21 133.67,45.39 133.67,47.51 133.86,47.7 134.13,47.7 134.32,47.51 134.32,43.18 134.12,42.98 134.12,42.16 v6(133.81,41.85)
MA_DQ61: length 42.1
  TOP w0.165: v6(133.1,40.25) 133.48,40.63 U13.E10 ; v1(127.43,70.22) 127.11,70.55 U6.AK48
  IN2 w0.076: 128.45,58.43 129.12,59.1 129.12,60.84 128.99,60.97 128.99,63.15 128.78,63.36 128.78,65.67 127.84,66.61 127.84,67.79 127.62,68.02 126.89,68.02 126.77,68.14 126.15,68.14 125.92,68.36 125.92,70.17 126.32,70.57 127.09,70.57 v1(127.43,70.22)
  IN2 w0.191: 128.45,58.43 128.45,47.99 128.54,47.89 128.54,45.63 129.32,44.85 129.32,41.61 129.51,41.42 130.34,41.42 130.56,41.21 130.56,40.94 130.39,40.77 129.51,40.77 129.32,40.58 129.32,39.9 129.49,39.73 129.74,39.73 130.14,40.13 130.73,40.13 130.85,40.25 v6(133.1,40.25)
MA_DQ62: length 39.6
  TOP w0.076: v1(129.35,69.58) 129.03,69.25 U6.AM51
  TOP w0.165: v6(132.51,39.45) 132.83,39.77 U13.D9
  IN2 w0.076: 130.96,60.63 130.68,60.91 130.68,62.28 130.67,62.29 130.67,62.67 130.93,62.93 131.01,62.93 131.22,63.13 131.22,63.8 130.78,64.24 130.78,66.06 130.38,66.47 130.38,67.78 130.67,68.07 130.67,68.97 130.07,69.58 v1(129.35,69.58)
  IN2 w0.191: v6(132.51,39.45) 132.87,39.45 134.04,40.61 135.97,40.61 136.19,40.84 136.19,42.85 136.02,43.03 136.02,48.88 134.82,50.07 134.82,50.32 135.15,50.65 135.15,51.86 134.4,52.62 132.25,52.62 131.47,53.39 131.47,57.96 130.96,58.47 130.96,60.63
MA_DQ63: length 40
  TOP w0.165: v1(129.35,70.22) 129.02,70.55 U6.AK51 ; U13.F8 133.8,38.72 v6(133.8,38.65)
  IN2 w0.076: v1(129.35,70.22) 129.96,70.22 130.84,69.34 130.84,67.82 130.63,67.61 130.63,66.45 131.25,65.82 131.25,64.81
  IN2 w0.191: v6(133.8,38.65) 133.38,39.08 133.38,39.53 134.13,40.28 136.22,40.28 136.59,40.65 136.59,48.9 135.57,49.91 135.57,52.03 134.52,53.09 132.66,53.09 131.89,53.86 131.89,64.17 131.25,64.81
MA_DQSN0: length 61.6
  TOP w0.076: U6.AJ61 135.39,70.86 135.78,71.24 136.23,71.24 136.29,71.27 136.33,71.29 136.39,71.32 136.59,71.32 136.74,71.25 136.76,71.24 136.93,71.24 137.16,71.47 137.65,71.47 137.9,71.22 138.61,71.22 138.71,71.32 138.71,71.55 v1(138.62,71.64)
  TOP w0.165: U14.P11 158.19,41.45 158.41,41.68 v6(158.41,41.85)
  IN2 w0.076: v6(158.41,41.85) 158.8,41.47 158.8,40.56 158.86,40.5
  IN2 w0.191: v1(138.62,71.64) 138.62,71.52 139.33,70.82 141.24,70.82 141.47,71.04 147.85,71.04 151.22,67.68 151.22,65.85 151.75,65.32 152.98,65.32 153.17,65.13 153.17,64.75 152.98,64.55 151.63,64.55 151.22,64.15 151.22,63.46 151.63,63.06 152.98,63.06 153.17,62.87 153.17,62.48 152.98,62.29 151.63,62.29 151.22,61.89 151.22,60.84 156.73,55.33 156.73,51.08 161.81,46 161.81,40.99 161.16,40.34 159.02,40.34 158.86,40.5
MA_DQSN1: length 54.2
  TOP w0.076: U6.AN62 135.79,68.48 135.79,68.59 135.85,68.65 136.27,68.65 136.36,68.69 136.42,68.72 136.55,68.72 136.68,68.66 136.73,68.65 137.82,68.65 138.14,68.34 138.54,68.34 138.72,68.16 138.72,68.02 138.52,67.82 v1(138.44,67.82)
  TOP w0.165: v6(156.51,41.05) 156.1,41.05 155.96,41.19 155.96,41.33 156.08,41.45 U14.L11
  IN3 w0.152: v1(138.44,67.82) 138.63,67.63 138.63,67.31 139.01,66.93 140.37,66.93 140.61,66.69 140.61,65.34 140.96,65 140.96,63.16 141.94,62.18 141.94,61.97 144.42,59.48 144.61,59.48 145.45,58.64 145.45,58.45 149.22,54.68 149.67,54.68 149.87,54.89 150.12,54.89 150.34,54.67 150.34,54.42 150.13,54.21 150.13,53.77 150.55,53.35 151,53.35 151.2,53.56 151.45,53.56 151.67,53.34 151.67,53.09 151.46,52.88 151.46,52.44 151.89,52.02 152.32,52.02 152.53,52.23 152.78,52.23 153,52.01 153,51.76 152.79,51.55 152.79,51.11 153.21,50.69 153.66,50.69 153.86,50.9 154.11,50.9 154.33,50.68 154.33,50.43 154.12,50.22 154.12,49.78 154.54,49.36 154.99,49.36 155.19,49.57 155.45,49.57 155.66,49.35 155.66,49.1 155.45,48.89 155.45,48.45 155.87,48.03 156.32,48.03 156.44,48.16 156.69,48.16 156.91,47.94 156.91,47.69 156.78,47.56 156.78,47.12 161.36,42.54 161.36,40.52 160.95,40.11 157.45,40.11 156.93,40.63 156.4,40.63 156.29,40.74 156.29,40.83 v6(156.51,41.05)
MA_DQSN2: length 45.1
  TOP w0.165: U6.AM58 133.72,69.25 v1(134.04,68.92) ; U14.G11 153.92,41.12 v6(153.92,41.05)
  IN2 w0.191: v1(134.04,68.92) 134.19,68.78 134.55,68.78 135.05,68.28 135.05,68.11 135.69,67.47 135.69,66.23 137.77,64.14 139.89,64.14 144.27,59.77 145.12,59.77 145.92,58.97 145.92,58.4 146.61,57.71 146.61,54.08 148.79,51.9 148.79,51.13 147.83,50.16 147.83,49.77 148.09,49.51 148.95,49.51 149.3,49.16 149.3,48.37 148.95,48.02 148.72,48.02 148.45,47.74 148.45,47.21 148.92,46.74 148.92,43.1 148.69,42.88 148.69,40.82 148.89,40.61 153.48,40.61 v6(153.92,41.05)
MA_DQSN3: length 43.6
  TOP w0.165: U6.AM55 131.81,69.25 v1(132.14,68.92) ; v6(151.97,41.05) 151.64,41.38 U14.D11
  IN3 w0.076: 131.5,66.28 131.53,66.32 131.53,67.25 131.69,67.4 131.69,68.47 v1(132.14,68.92)
  IN3 w0.152: v6(151.97,41.05) 151.97,40.17 151.65,39.85 148.62,39.85 147.7,40.77 147.7,44.5 147.27,44.93 147.27,45.84 147.9,46.47 147.9,46.92 139.96,54.86 139.96,55.84 136.72,59.08 136.72,63.06 135.23,64.54 134.59,64.54 133.99,65.15 132.51,65.15 131.5,66.16 131.5,66.28
MA_DQSN4: length 37.3
  TOP w0.076: v1(134.88,61.05) 134.19,61.74 134.19,62.83 133.91,63.11 133.91,63.49 133.32,64.07 133.32,64.24 133.41,64.41 133.41,64.62 133.38,64.67 133.33,64.77 133.33,64.9 133.38,65 133.41,65.06 133.41,65.26 133.38,65.32 133.38,65.32 133.33,65.43 132.95,65.81 U6.AV57
  TOP w0.165: U13.P11 139.68,41.8 v6(139.68,41.85)
  IN2 w0.076: 139.32,40.61 139.35,40.64 139.35,41.52 v6(139.68,41.85)
  IN2 w0.191: 139.32,40.61 139.32,40.24 139.66,39.91 142.37,39.91 143.26,40.8 143.26,43.24 143.03,43.47 143.03,48.16 141.61,49.58 141.61,50.27 141.94,50.6 141.94,52.43 140.33,54.03 140.33,54.57 139.58,55.32 139.58,56.3 138.92,56.97 137.94,56.97 137.65,57.25 137.65,58.26 137.04,58.87 136.35,58.87 136.12,59.11 136.12,59.81 v1(134.88,61.05)
MA_DQSN5: length 41.3
  TOP w0.076: U6.AV53 130.52,65.6 130.9,65.21 130.9,64.78 130.91,64.74 130.95,64.66 130.97,64.62 130.97,64.41 130.92,64.29 130.9,64.25 130.9,63.89 131.29,63.5 131.29,63.35 131.62,63.02 131.62,62.2 131.48,62.07 131.31,62.07 v1(131.1,61.86)
  TOP w0.165: U13.L11 137.7,41.77 v6(137.7,41.85)
  IN3 w0.152: v1(131.1,61.86) 130.61,61.86 130.51,61.76 130.51,61.15 130.89,60.77 130.89,58.06 132.55,56.4 132.81,56.4 134.47,54.75 134.47,54.12 140.64,47.95 140.64,47.17 143.23,44.57 143.23,41.06 142,39.83 137.54,39.83 136.81,40.56 136.81,41.48 137.18,41.85 v6(137.7,41.85)
MA_DQSN6: length 39
  TOP w0.165: U13.D11 132.83,41.38 v6(132.51,41.05) ; v1(124.58,69.7) 124.28,69.7 U6.AL43
  IN3 w0.076: 124.25,66.68 124.25,66.7 124.19,66.75 124.19,68.03 124.17,68.06 124.17,69.31 124.02,69.46 124.02,69.84 124.16,69.98 124.3,69.98 v1(124.58,69.7)
  IN3 w0.152: 124.25,66.68 124.25,63.73 124.85,63.13 124.85,62.17 125.19,61.82 125.19,61.22 126.19,60.22 126.19,56.39 130.3,52.27 130.3,51.24 130.45,51.09 131.18,51.09 131.52,50.75 131.52,50.21 131.18,49.87 130.45,49.87 130.3,49.72 130.3,43.62 129.87,43.19 129.87,41.16 130.25,40.79 130.54,40.79 131.11,40.21 132.11,40.21 132.71,40.81 132.71,40.94 132.6,41.05 v6(132.51,41.05)
MA_DQSN7: length 43.2
  TOP w0.165: U6.AL48 127.11,69.9 v1(127.43,69.57) ; U13.G11 134.78,41.53 v6(134.46,41.85)
  IN2 w0.076: 130.4,58.04 130.4,58.07 130.51,58.17 130.51,58.78 130.57,58.84 130.57,60.44 130.35,60.66 130.35,62.13 130.12,62.36 130.12,66.17 129.96,66.34 129.96,67.52 129,68.48 128.21,68.48 127.83,68.87 127.83,69.31 127.97,69.45 127.97,69.55 127.69,69.82 127.53,69.82 127.43,69.73 v1(127.43,69.57)
  IN2 w0.191: 130.4,58.04 130.4,52.33 131.09,51.65 134,51.65 134.19,51.46 134.19,51.05 134.02,50.89 130.84,50.89 130.4,50.46 130.4,49.4 130.81,49 131.45,49 131.81,49.35 132.34,49.35 133.03,48.67 134.86,48.67 134.96,48.56 134.96,41.73 134.82,41.59 134.71,41.59 v6(134.46,41.85)
MA_DQSP0: length 61.5
  TOP w0.076: v1(139.26,71.64) 138.68,71.06 137.83,71.06 137.58,71.3 137.23,71.3 137,71.08 136.73,71.08 136.68,71.1 136.55,71.15 136.42,71.15 136.36,71.12 136.27,71.08 135.85,71.08 135.8,71.04 135.8,70.9 U6.AJ62
  TOP w0.165: U14.P10 158.45,40.95 v6(158.45,41.05)
  IN2 w0.191: v6(158.45,41.05) 158.49,41.01 158.49,40.35 158.87,39.97 161.31,39.97 162.18,40.83 162.18,46.15 157.1,51.23 157.1,55.48 151.59,60.99 151.59,61.74 151.78,61.93 153.14,61.93 153.54,62.33 153.54,63.02 153.14,63.42 151.78,63.42 151.59,63.61 151.59,64 151.78,64.19 153.14,64.19 153.54,64.59 153.54,65.28 153.14,65.68 151.9,65.68 151.59,66 151.59,67.83 148.01,71.41 141.31,71.41 141.08,71.18 139.48,71.18 139.26,71.41 v1(139.26,71.64)
MA_DQSP1: length 54.3
  TOP w0.076: U6.AN61 135.39,68.43 135.78,68.81 136.23,68.81 136.29,68.84 136.33,68.86 136.39,68.89 136.59,68.89 136.74,68.82 136.76,68.81 137.89,68.81 138.21,68.5 138.61,68.5 138.89,68.22 138.89,68.02 v1(139.08,67.82)
  TOP w0.165: v6(156.51,40.25) 156.19,40.58 U14.L10
  IN3 w0.152: v6(156.51,40.25) 156.62,40.35 156.81,40.35 157.34,39.83 161.06,39.83 161.64,40.41 161.64,42.65 157.06,47.23 157.06,47.45 157.19,47.57 157.19,48.06 156.81,48.44 156.33,48.44 156.2,48.31 155.99,48.31 155.73,48.56 155.73,48.78 155.94,48.98 155.94,49.47 155.56,49.85 155.08,49.85 154.87,49.64 154.66,49.64 154.4,49.89 154.4,50.11 154.61,50.31 154.61,50.8 154.23,51.18 153.75,51.18 153.54,50.97 153.33,50.97 153.07,51.22 153.07,51.44 153.28,51.64 153.28,52.13 152.9,52.51 152.53,52.51 152.42,52.51 152.2,52.29 152,52.29 151.74,52.55 151.74,52.77 151.95,52.98 151.95,53.46 151.57,53.84 151.09,53.84 150.88,53.63 150.67,53.63 150.41,53.88 150.41,54.1 150.62,54.31 150.62,54.79 150.24,55.17 149.76,55.17 149.55,54.96 149.34,54.96 145.73,58.57 145.73,58.76 144.72,59.76 144.54,59.76 142.21,62.08 142.21,62.3 141.24,63.27 141.24,65.11 140.89,65.46 140.89,66.8 140.49,67.21 139.13,67.21 138.91,67.43 138.91,67.66 v1(139.08,67.82)
MA_DQSP2: length 45
  TOP w0.165: v1(134.04,68.27) 133.68,68.27 133.59,68.36 U6.AN58 ; v6(153.92,40.25) 153.92,40.32 U14.G10
  IN2 w0.191: v1(134.04,68.27) 134.18,68.41 134.4,68.41 134.68,68.12 134.68,67.96 135.32,67.32 135.32,66.07 137.62,63.77 139.74,63.77 144.12,59.4 144.97,59.4 145.55,58.81 145.55,58.25 146.24,57.56 146.24,53.93 148.42,51.75 148.42,51.28 147.46,50.32 147.46,49.62 147.94,49.15 148.79,49.15 148.93,49.01 148.93,48.52 148.79,48.38 148.57,48.38 148.08,47.89 148.08,47.05 148.55,46.58 148.55,43.26 148.32,43.03 148.32,40.67 148.74,40.25 153.63,40.25 153.64,40.25 v6(153.92,40.25)
MA_DQSP3: length 43.6
  TOP w0.165: U6.AN55 131.7,68.55 131.7,68.43 131.84,68.28 131.92,68.28 132.03,68.17 132.21,68.17 v1(132.29,68.26) ; v6(151.32,41.05) 151.28,41.02 151.28,40.89 151.36,40.82 151.36,40.72 151.42,40.65 U14.D10
  IN3 w0.076: 131.78,66.31 131.78,66.28 ; 131.76,66.33 131.7,66.39 131.7,67.18 131.85,67.34 131.85,68.4 131.98,68.53 132.24,68.53 132.29,68.48 v1(132.29,68.26)
  IN3 w0.152: 131.76,66.33 131.78,66.31 ; 131.78,66.28 131.78,66.28 132.62,65.43 134.1,65.43 134.71,64.82 135.35,64.82 137,63.17 137,59.2 140.24,55.95 140.24,54.98 148.18,47.04 148.18,46.36 147.55,45.72 147.55,45.05 147.98,44.62 147.98,40.88 148.73,40.13 151.54,40.13 151.69,40.28 151.69,40.74 151.59,40.84 151.59,40.97 151.51,41.05 v6(151.32,41.05)
MA_DQSP4: length 37.6
  TOP w0.076: U6.AW57 132.85,65.26 132.85,65.47 132.89,65.51 133.01,65.51 133.19,65.33 133.23,65.24 133.24,65.23 133.24,65.1 133.17,64.94 133.17,64.73 133.19,64.68 133.24,64.58 133.24,64.45 133.16,64.27 133.16,64 133.74,63.42 133.74,63.04 134.02,62.76 134.02,61.67 134.47,61.23 134.47,60.81
  TOP w0.165: 134.47,60.81 134.47,60.73 134.62,60.58 135.56,60.58 135.71,60.43 135.71,60.17 135.53,59.99 v1(134.87,59.99) ; U13.P10 139.56,40.65 139.62,40.72 139.62,40.98 v6(139.69,41.05)
  IN2 w0.191: v1(134.87,59.99) 134.87,60.15 134.98,60.25 135.16,60.25 135.75,59.66 135.75,58.95 136.2,58.5 136.89,58.5 137.28,58.1 137.28,57.1 137.79,56.6 138.77,56.6 139.21,56.15 139.21,55.17 139.97,54.42 139.97,53.87 141.57,52.27 141.57,50.75 141.24,50.43 141.24,49.42 142.66,48.01 142.66,43.32 142.89,43.09 142.89,40.95 142.22,40.28 139.81,40.28 139.69,40.39 v6(139.69,41.05)
MA_DQSP5: length 41.3
  TOP w0.076: U6.AW53 130.56,65.2 130.68,65.2 130.73,65.15 130.73,64.73 130.76,64.68 130.81,64.58 130.81,64.45 130.79,64.4 130.74,64.29 130.74,63.82 131.12,63.43 131.12,63.29 131.46,62.95 131.46,62.27 131.42,62.23 131.24,62.23 131.06,62.41 v1(131.06,62.51)
  TOP w0.165: v6(137.7,41.05) 137.67,41.08 137.1,41.08 137.03,41.02 137.03,40.86 137.25,40.65 U13.L10
  IN3 w0.152: v6(137.7,41.05) 137.93,41.28 137.93,41.39 137.85,41.47 137.52,41.47 137.41,41.57 137.3,41.57 137.09,41.37 137.09,40.67 137.66,40.11 141.89,40.11 142.95,41.17 142.95,44.46 140.36,47.05 140.36,47.83 134.19,54 134.19,54.64 132.7,56.13 132.43,56.13 130.61,57.95 130.61,60.66 130.23,61.04 130.23,61.87 130.49,62.14 130.76,62.14 131.06,62.44 v1(131.06,62.51)
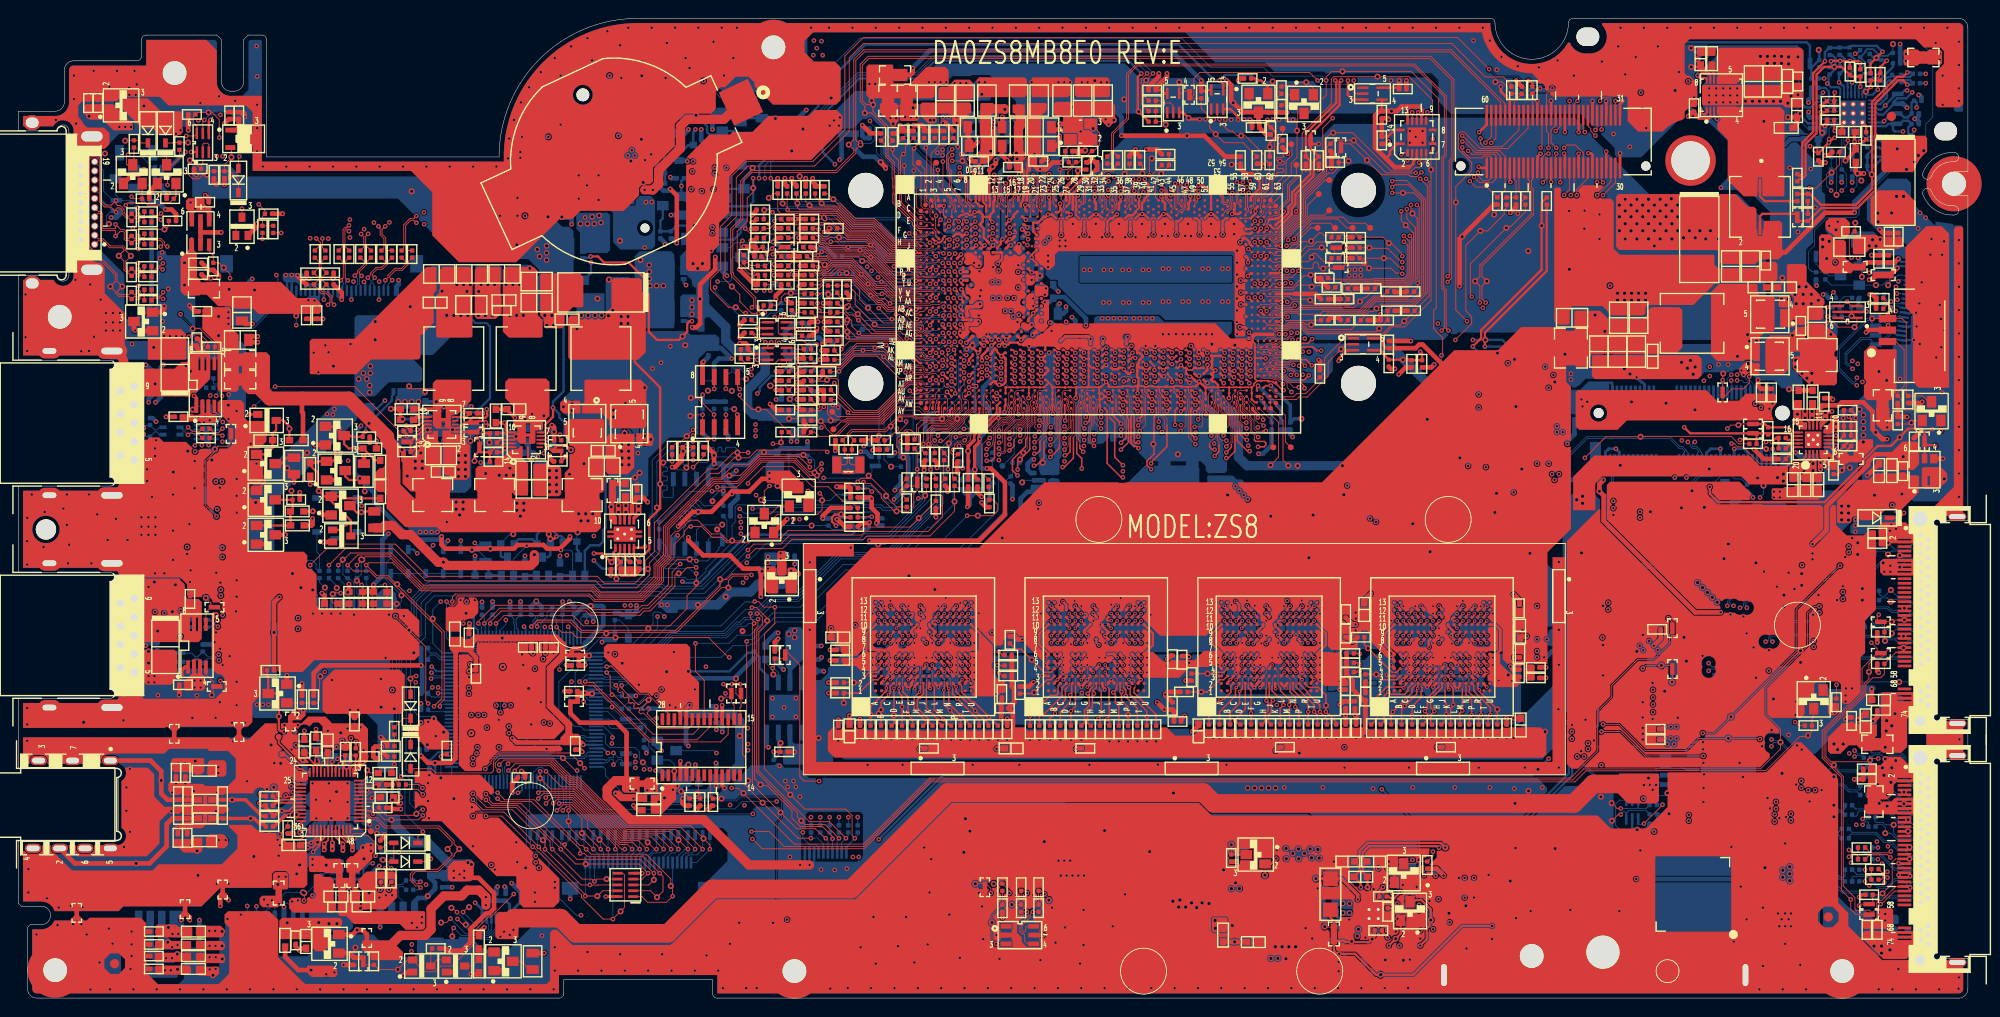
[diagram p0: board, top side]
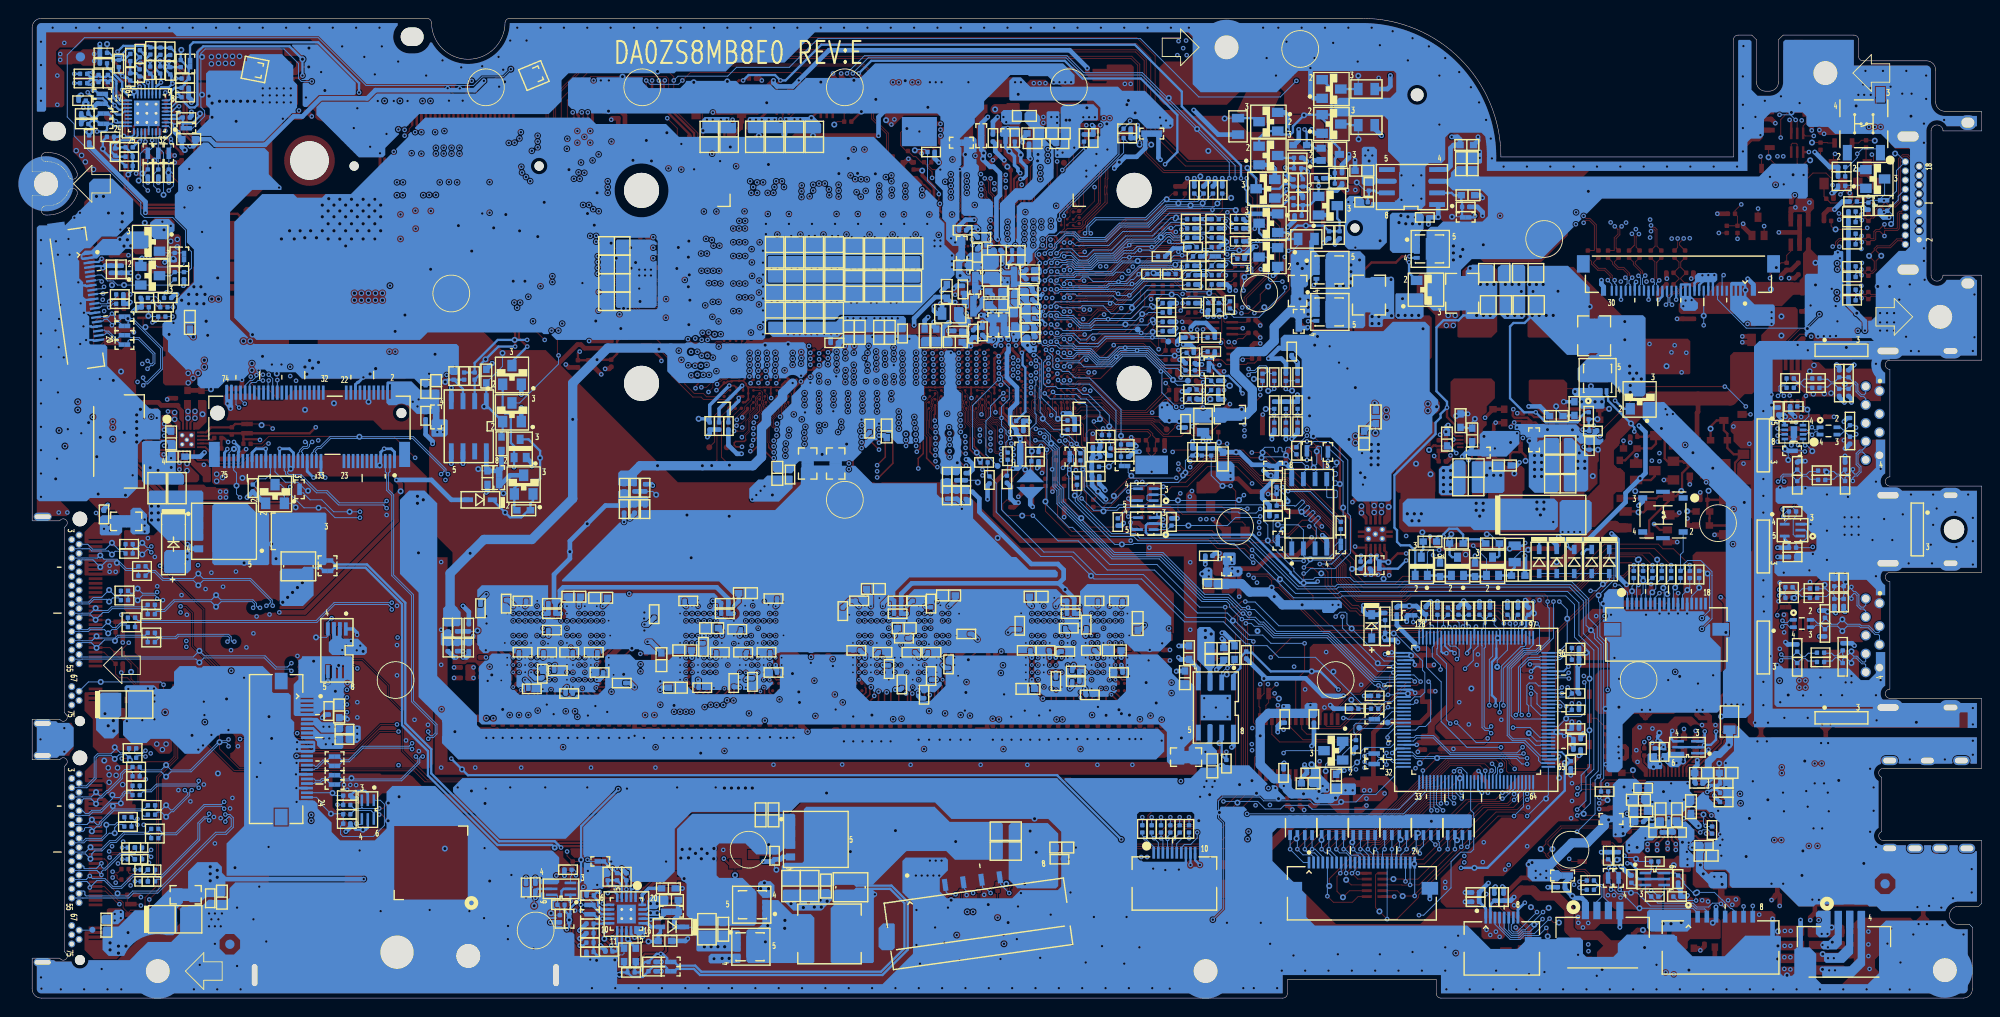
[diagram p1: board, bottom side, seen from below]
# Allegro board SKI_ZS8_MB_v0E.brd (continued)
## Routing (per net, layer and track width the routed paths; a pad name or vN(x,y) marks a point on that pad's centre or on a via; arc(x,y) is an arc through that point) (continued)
MA_DQSP6: length 39.1
  TOP w0.165: v6(133.16,41.05) 132.83,40.73 U13.D10 ; U6.AL42 123.35,69.9 v1(123.62,69.62)
  IN3 w0.076: 123.97,66.68 123.97,66.7 124.03,66.75 124.03,67.96 124,67.99 124,69.24 123.74,69.51 v1(123.62,69.62)
  IN3 w0.152: 123.97,66.68 123.97,63.61 124.57,63.01 124.57,62.05 124.91,61.71 124.91,61.1 125.91,60.11 125.91,56.27 130.02,52.16 130.02,51.13 130.34,50.81 131.06,50.81 131.24,50.63 131.24,50.33 131.06,50.15 130.34,50.15 130.02,49.83 130.02,43.73 129.59,43.3 129.59,41.05 130.13,40.51 130.42,40.51 131,39.93 132.22,39.93 132.99,40.7 132.99,40.89 v6(133.16,41.05)
MA_DQSP7: length 43.2
  TOP w0.165: v1(128.41,69.66) 128.18,69.9 U6.AL49 ; v6(134.46,41.05) 134.78,40.73 U13.G10
  IN2 w0.076: 130.77,58.04 130.77,58.07 130.67,58.17 130.67,58.71 130.73,58.78 130.73,60.51 130.52,60.72 130.52,62.19 130.29,62.43 130.29,66.24 130.12,66.41 130.12,67.59 129.07,68.65 128.28,68.65 127.99,68.94 127.99,69.24 v1(128.41,69.66)
  IN2 w0.191: 130.77,58.04 130.77,52.49 131.24,52.02 134.15,52.02 134.56,51.61 134.56,50.9 134.18,50.52 130.99,50.52 130.77,50.3 130.77,49.56 130.96,49.36 131.3,49.36 131.65,49.72 132.49,49.72 133.18,49.03 135.01,49.03 135.33,48.72 135.33,41.58 134.98,41.22 134.63,41.22 134.51,41.11 v6(134.46,41.05)
MA_ODT: length 73.3
  TOP w0.165: U14.J8 154.89,38.97 v6(154.57,38.65) ; v1(145.92,37.46) 145.88,37.51 R207.2 ; v6(135.76,38.57) 136.08,38.9 U13.J8 ; v1(117.4,67.62) 117.08,67.95 U6.AP32
  IN1 w0.076: 123,59.26 121.89,59.26 121.44,59.71 121.44,63.47 121.33,63.58 121.33,66.18 120.98,66.53 120.98,67.42 120.5,67.9 120.13,67.9 119.65,68.39 118.17,68.39 v1(117.4,67.62)
  IN1 w0.191: 123,59.26 124.89,59.26 127.64,56.51 128.01,56.51 133.11,51.41 137.49,51.41 144.69,44.21 144.69,38.44 144.91,38.23 145.16,38.23 v1(145.92,37.46)
  IN2 w0.191: v6(135.76,38.57) 136.6,37.73 140.32,37.73 140.59,37.46 141.91,37.46 142.14,37.24 145.69,37.24 v1(145.92,37.46) 146.02,37.36 148.93,37.36 149.01,37.45 154.65,37.45 155.24,38.05 155.24,38.53 155.13,38.65 v6(154.57,38.65)
MAIND: length 81.1
  TOP w0.254: v1(73.28,73.66) 73.02,73.66 72.77,73.41 72.77,72.52 v2(72.26,72) 71.88,71.63 69.47,71.63 68.58,72.52 68.58,76.58 68.07,77.09 68.07,78.36 66.39,80.05 63.72,80.05 63.06,80.71 v1(62.26,80.71)
  IN2 w0.254: v1(62.26,80.71) 62.8,80.71 63.06,80.46 63.06,79.35 62,78.3 55.94,78.3 55.63,78.61 47.24,78.61 39.62,70.99 39.62,65.28 v1(39.88,65.02)
  IN3 w0.254: v1(73.28,73.66) 73.81,74.19 73.81,78.51 75.06,79.76 75.06,81.53 76.77,83.25 76.77,89.73 76.12,90.38 v1(75.76,90.38)
  BOTTOM w0.254: v1(73.28,73.66) 73.24,73.7 PQ28.4 ; v1(75.76,90.38) 75.68,90.3 PR113.2 PC80.2 76.33,91.44 PQ21.3 ; PQ25.4 62.1,80.56 v1(62.26,80.71) ; v1(39.88,65.02) 38.99,64.14 PQ31.2
MAINON: length 240.9
  TOP w0.102: v1(41.02,41.58) 41.02,41.53 44.32,38.23 44.32,32.33 v1(44.59,32.07) ; PR36.1 187.15,60.33 186.35,61.13 176.54,61.13 v2(176.49,61.09) 172.72,61.09 v1(170.43,58.8)
  IN2 w0.114: v1(41.02,41.58) 41.02,43.56 40.77,43.81 40.77,60.62 38.94,62.44 38.94,71.71 48.01,80.77 52.28,80.77 55.12,83.61 v1(55.12,85.14) 55.12,86.74 59.44,91.06 63.69,91.06 66.61,93.98 73.15,93.98 73.66,94.49 v1(73.66,94.54) 74.56,95.44 80.36,95.44 86.25,101.34 95.51,101.34 96.45,100.4 98.07,100.4 98.81,101.13 121.25,101.13 121.55,101.44 125.49,101.44 128.29,98.64 137.45,98.64 142.48,93.61 147.44,93.61 153.3,87.75 153.3,79.41 158.75,73.96 158.75,68.58 168.53,58.8 v1(170.43,58.8)
  BOTTOM w0.102: v1(44.59,32.07) R531.1 44.79,31.17 U23.80
  BOTTOM w0.254: v1(55.12,85.14) 55.29,84.96 PR126.1 ; v1(73.66,94.54) 73.66,94.49 73.43,94.26 PR106.1 72.9,92.84 72.54,92.48 PQ20.2
MAINON_ON_G: length 23.1
  BOTTOM w0.254: PR119.2 PR114.1 70.37,91.33 PQ20.3 69.88,92.48 70.87,93.47 70.87,94.87 71.75,95.76 PQ19.2 ; PQ21.2 78.61,93.6 77.85,94.36 PQ18.2 76.2,93.98 75.18,93.98 74.93,94.23 74.93,94.87 v2(73.72,96.08) 73.66,96.14 PQ19.2 ; PQ19.2 70.87,96.14 70.74,96.27 70.74,98.93 PQ17.2
MB_AMA0: length 71.1
  TOP w0.076: 121.49,33.81 121.49,34.54 121.36,34.67 v6(120.83,34.67)
  TOP w0.165: 121.49,33.81 121.39,33.71 121.39,33.25 123.78,30.85 R286.2 ; U6.AP45 125.06,67.83 125.53,67.36 v1(125.53,67.03) ; v6(120.83,34.67) 120.83,34.59 U12.R2
  IN2 w0.191: v6(120.83,34.67) 120.83,34.83 120.62,35.04 120.29,35.04 120.09,34.83 120.09,34.49 120.4,34.19 120.4,34.01 120.24,33.86 119.41,33.86 119.28,33.99 119.28,34.37 119.48,34.57 119.48,34.93 119.27,35.14 118.88,35.14 118.67,35.36 118.67,35.59 119.13,36.04 119.13,36.75 118.26,37.62 117.58,37.62 117.07,37.11 116.82,37.11 116.36,37.57 116.36,37.85 116.71,38.2 116.71,39.66 116.51,39.86 115.69,39.86 115.48,40.07 115.48,40.44 115.69,40.64 116.33,40.64 116.53,40.84 116.53,41.43 116.31,41.66 116.31,42.82 115.24,43.89 114.96,43.89 114.5,43.43 114.22,43.43 114,43.66 114,44.35 113.82,44.53 113.56,44.53 113.39,44.35 113.39,43.87 113.21,43.69 112.95,43.69 112.78,43.87 112.78,44.81 112.66,44.92 112.66,45.52 112.46,45.72 111.82,45.72 111.34,46.2 111.34,47 111.66,47.31 111.66,48.08 112.51,48.93 112.51,49.7 119.02,56.2 120.36,56.2 120.63,56.48 120.63,57.97 122.52,59.86 122.52,63.31 122.68,63.47 122.68,65.84 123.13,66.29 123.84,66.29 124.1,66.55 124.1,70.7 124.35,70.94 124.9,70.94 125.04,70.8 125.04,68.81 125.53,68.33 v1(125.53,67.03)
MB_AMA1: length 74.5
  TOP w0.165: R285.2 v1(122.77,30.65) 122.77,31.23 120.95,33.05 120.95,33.71 v1(120.85,33.82) 120.52,34.15 U12.P2 ; U6.AU46 126.18,66.14 v1(126.48,65.84)
  IN2 w0.191: v1(126.48,65.84) 126.48,66.15 126.26,66.37 124.66,66.37 123.95,65.66 123.95,63.82 122.91,62.78 122.91,59.69 121.02,57.8 121.02,56.31 120.08,55.37 119.48,55.37 119.25,55.6 118.97,55.6 118.64,55.27 118.64,54.71 118.37,54.44 117.81,54.44 115.68,52.31 115.68,51.83 115.38,51.53 114.9,51.53 114.62,51.25 114.62,50.96 114.15,50.5 113.86,50.5 113.46,50.09 113.46,49.6 113.29,49.42 113.08,49.42 112.9,49.25 112.9,49 113.08,48.83 113.29,48.83 113.46,48.65 113.46,48.4 113.29,48.23 112.37,48.23 112.19,48.05 112.19,47.81 112.37,47.63 114.68,47.63 114.86,47.46 114.86,46.91 114.66,46.71 114.33,46.71 114.13,46.9 112.71,46.9 112.57,47.03 111.94,47.03 111.73,46.83 111.73,46.41 111.94,46.2 113.02,46.2 113.14,46.08 113.39,46.08 113.67,46.36 113.9,46.36 114.17,46.08 114.5,46.08 114.67,45.91 114.67,45.62 114.55,45.49 113.22,45.49 113.06,45.32 113.06,45.09 113.22,44.92 114.49,44.92 114.73,44.68 114.73,44.42 114.87,44.28 115.72,44.28 116.07,43.94 116.07,43.7 116.33,43.43 116.71,43.43 117.14,43.87 117.3,43.87 117.54,43.62 117.54,40.76 117,40.22 117,40.02 117.3,39.73 117.6,39.73 117.83,39.5 117.83,39.04 117.68,38.89 117.42,38.89 117.11,38.57 117.11,38.16 117.25,38.02 118.01,38.02 118.23,38.24 118.71,38.24 118.85,38.1 118.85,37.59 118.97,37.46 119.96,37.46 120.15,37.65 120.37,37.65 120.56,37.46 121.24,37.46 121.48,37.71 121.83,37.71 122.07,37.46 122.3,37.46 122.43,37.59 122.9,37.59 123.21,37.28 123.21,34.58 123.09,34.47 122.66,34.47 122.55,34.37 122.55,33.93 122.45,33.82 122,33.82 121.79,34.04 121.79,34.43 121.63,34.6 121.4,34.6 121.23,34.43 121.23,34.03 121.03,33.82 v1(120.85,33.82)
MB_AMA2: length 72.9
  TOP w0.165: v1(126.49,64.53) 126.48,64.53 126.48,64.54 126.18,64.84 U6.AW46 ; R283.2 v2(120.73,30.8) 120.73,31.67 120.02,32.38 v1(120.02,33.35) 119.87,33.49 U12.N2
  IN2 w0.191: v1(126.49,64.53) 125.66,64.53 125.43,64.29 125.43,63.5 125.28,63.36 124.65,63.36 124.49,63.2 123.89,63.2 123.3,62.62 123.3,59.52 121.42,57.64 121.42,56.15 120.25,54.98 119.25,54.98 119.05,54.78 119.05,53.97 118.87,53.8 118.63,53.8 118.38,54.05 117.98,54.05 116.68,52.75 116.68,52.5 116.51,52.33 116.25,52.33 116.08,52.15 116.08,51.9 116.25,51.73 116.51,51.73 116.68,51.55 116.68,51.31 116.51,51.13 115.19,51.13 115.01,50.96 115.01,50.71 115.19,50.54 116.51,50.54 116.68,50.36 116.68,50.11 116.51,49.94 114.03,49.94 113.86,49.76 113.86,49.52 114.03,49.34 116.51,49.34 116.68,49.17 116.68,48.86 116.56,48.74 114.08,48.74 113.86,48.51 113.86,48.32 114.03,48.14 115.88,48.14 116.05,47.97 116.05,47.72 115.88,47.55 115.57,47.55 115.27,47.24 115.27,46.56 115.7,46.13 115.7,45.7 115.33,45.33 115.33,45.06 115.5,44.88 115.75,44.88 116.2,45.33 116.44,45.33 116.62,45.16 116.62,44.94 116.25,44.56 116.25,44.32 116.42,44.14 116.69,44.14 117.04,44.49 117.28,44.49 117.94,43.84 117.94,40.18 118.11,40 118.39,40 118.55,39.84 119.09,39.84 119.48,40.24 120.5,40.24 120.68,40.06 120.68,39.86 120.42,39.61 120.42,39.27 120.22,39.07 119.71,39.07 119.38,38.73 119.38,38.48 119.26,38.36 119.26,38.09 119.49,37.86 119.8,37.86 120.04,38.1 120.48,38.1 120.72,37.86 121.08,37.86 121.42,38.2 122.25,38.2 122.45,38 123.07,38 123.6,37.46 123.6,34.42 122.53,33.35 121.92,33.35 121.69,33.58 121.34,33.58 121.12,33.35 120.02,33.35 v1(120.02,33.35)
MB_AMA3: length 70.6
  TOP w0.076: U12.N3 120.2,34.72 120.2,33.9 120.26,33.85
  TOP w0.165: 120.26,33.85 120.26,33.74 120.48,33.52 v1(120.48,32.89) 120.48,32.78 121.75,31.51 R284.2 ; v1(126.49,63.86) 126.61,63.86 126.91,64.16 U6.AY47
  IN2 w0.191: v1(126.49,63.86) 125.17,62.54 125.17,61.54 123.7,60.07 123.7,59.36 121.81,57.48 121.81,55.99 119.93,54.1 119.93,53.58 119.75,53.4 117.89,53.4 117.71,53.23 117.71,52.98 117.89,52.81 119.75,52.81 119.93,52.63 119.93,52.38 119.75,52.21 117.36,52.21 117.18,52.03 117.18,51.79 117.36,51.61 119.75,51.61 119.93,51.44 119.93,51.09 119.48,50.65 119.48,49.96 119.31,49.78 119.08,49.78 118.88,49.98 118.88,50.7 118.71,50.88 118.44,50.88 118.27,50.7 118.27,49.83 118.12,49.68 117.85,49.68 117.67,49.86 117.67,50.63 117.5,50.8 117.25,50.8 117.07,50.63 117.07,49.84 117.35,49.57 117.35,48.35 117.25,48.25 117.25,47.62 117.07,47.45 116.33,47.45 115.89,47 115.89,46.49 116.22,46.16 116.65,46.16 116.97,46.48 117.22,46.48 117.39,46.31 117.39,46.06 117.07,45.74 117.07,45.49 117.24,45.32 117.49,45.32 117.82,45.64 118.06,45.64 118.24,45.47 118.24,45.22 117.91,44.89 117.91,44.65 118.23,44.33 118.45,44.33 118.77,44.65 119.14,44.65 119.63,44.16 119.63,43.83 119.24,43.43 119.05,43.43 118.75,43.74 118.51,43.74 118.33,43.56 118.33,40.8 118.47,40.66 119.21,40.66 119.25,40.63 120.76,40.63 121.29,40.11 122.83,40.11 122.94,40 122.94,39.25 123.6,38.58 123.6,38.02 124,37.63 124,34.26 122.63,32.89 v1(120.48,32.89)
MB_AMA4: length 72.8
  TOP w0.076: U12.M3 119.54,34.73 119.54,34.03
  TOP w0.165: U6.AY46 125.84,63.94 v1(125.84,62.38) ; R282.2 119.72,31.79 119.35,32.16 119.35,33.04 v1(119.13,33.27) 119.48,33.62 119.48,33.97 119.54,34.03
  IN2 w0.191: v1(119.13,33.27) 119.42,32.98 119.67,32.98 119.87,32.78 119.87,32.52 120.02,32.38 122.8,32.38 124.7,34.28 124.7,34.56 124.39,34.87 124.39,35.16 124.7,35.47 124.7,35.76 124.42,36.05 124.42,37.77 124.08,38.1 124.08,38.55 124.39,38.86 124.39,39.08 124.22,39.26 123.75,39.26 123.57,39.43 123.57,39.68 123.75,39.85 124.22,39.85 124.39,40.03 124.39,40.3 124.22,40.47 123.01,40.47 122.83,40.65 122.83,40.87 123.03,41.07 124.04,41.07 124.26,41.3 124.26,41.49 124.09,41.67 123.77,41.67 123.6,41.84 123.6,42.06 123.8,42.27 124.22,42.27 124.39,42.44 124.39,42.57 123.87,43.09 123.75,43.09 123.19,42.54 122.94,42.54 122.77,42.71 122.77,42.96 123.22,43.4 123.22,43.75 122.71,44.25 122.31,44.25 122.14,44.07 122.14,43.53 121.91,43.31 121.74,43.31 121.34,43.71 121.34,44.17 121.59,44.42 121.59,44.75 121.31,45.03 120.91,45.03 120.74,44.86 120.74,43.91 120.56,43.74 120.32,43.74 120.14,43.91 120.14,44.86 119.97,45.03 119.46,45.03 119.45,45.05 118.91,45.05 118.72,45.24 118.72,45.77 117.63,46.87 117.63,47.17 117.92,47.46 117.92,48.91 118.38,49.36 119.67,49.36 119.88,49.57 119.88,50.48 120.32,50.93 120.32,53.85 120.45,53.97 120.78,53.97 120.92,53.84 120.92,50.67 120.6,50.36 120.6,49.79 120.77,49.62 121.12,49.62 121.34,49.83 121.34,50.16 121.51,50.34 121.51,55.13 122.21,55.82 122.21,56.67 122.43,56.9 123.28,56.9 123.83,57.44 123.83,58.93 124.1,59.21 124.1,59.92 125.84,61.66 v1(125.84,62.38)
MB_AMA5: length 71.6
  TOP w0.076: 114.99,33.96 114.99,34.72 U12.F3
  TOP w0.165: R277.2 114.51,31.24 v1(114.51,31.24) 115.02,31.75 115.02,33.93 114.99,33.96 ; v1(128.06,65.84) 127.76,66.14 U6.AU49
  IN2 w0.191: v1(114.51,31.24) 114.51,31.25 114.55,31.29 118.79,31.29 119.28,30.8 124.73,30.8 127.25,33.32 127.25,33.63 126.49,34.4 126.49,34.82 127.1,35.43 127.1,35.84 126.85,36.09 126.85,37.37 126.24,37.98 126.24,43.61 124.79,45.06 124.79,45.9 124.49,46.2 123.65,46.2 122.66,47.19 120,47.19 119.84,47.35 119.84,47.63 120,47.79 122.09,47.79 123.09,48.79 123.09,54.43 123.28,54.62 123.51,54.62 123.69,54.44 123.69,50.71 123.9,50.49 124.1,50.49 124.28,50.67 124.28,55.67 125.48,56.86 125.48,58.34 125.68,58.55 125.68,59.21 127.51,61.04 127.51,64.01 127.61,64.11 127.61,65.39 v1(128.06,65.84)
MB_AMA6: length 67.4
  TOP w0.076: U12.E3 114.35,34.73 114.35,34.05 114.06,33.76 ; U6.AU47 126.96,65.89 127.37,65.48 127.37,63.94 127.28,63.86 127.28,61.06 v1(128.06,60.28)
  TOP w0.165: R275.2 112.23,30.44 v1(112.78,30.99) 112.78,31.33 113.92,32.47 113.92,33.62 114.06,33.76
  IN2 w0.191: v1(112.78,30.99) 113.03,30.73 113.28,30.73 113.49,30.94 113.49,30.95 113.69,31.16 113.94,31.16 114.15,30.95 114.15,30.94 114.35,30.73 116.85,30.73 117.01,30.89 118.64,30.89 119.12,30.41 124.9,30.41 127.71,33.22 127.71,35.84 127.84,35.97 127.84,37.3 126.66,38.48 126.66,43.86 125.36,45.16 125.36,46.22 124.98,46.6 123.92,46.6 123.19,47.33 123.19,48.34 123.48,48.63 123.48,49.72 123.63,49.87 123.9,49.87 124.08,49.69 124.08,47.36 124.24,47.19 124.52,47.19 124.68,47.35 124.68,55.51 125.87,56.7 125.87,58.18 126.09,58.39 126.09,59.03 127.34,60.28 v1(128.06,60.28)
MB_AMA7: length 73.4
  TOP w0.076: U6.AV47 127.2,65.2 127.2,64.96 127.2,64.96 127.2,64.71 127.2,64.71 127.2,64.31 127.2,64.31 127.2,64.06 127.03,63.88 127.03,62.31 v1(126.44,61.73)
  TOP w0.165: R276.2 113.37,31.16 114.43,32.23 v1(114.43,32.99) 114.44,32.99 114.59,33.15 114.59,34.17 U12.E2
  IN2 w0.191: v1(114.43,32.99) 114.22,32.99 114.02,33.19 114.02,33.75 114.55,34.29 114.55,34.8 114.79,35.04 115.05,35.04 115.23,34.86 115.23,32.85 115.46,32.63 117.34,32.63 117.48,32.77 117.48,33.33 117.16,33.66 116.84,33.66 116.71,33.79 116.71,34.93 116.34,35.3 116.34,35.71 116.82,36.2 117.07,36.2 117.36,35.9 117.36,35.44 117.53,35.27 117.81,35.27 117.98,35.09 117.98,34.84 117.81,34.67 117.53,34.67 117.36,34.49 117.36,34.33 117.73,33.96 118.04,33.96 118.35,34.27 118.73,34.27 118.87,34.13 118.87,33.67 118.66,33.46 118.66,33.34 118.29,32.96 118.29,32.82 118.48,32.63 119.13,32.63 119.77,31.98 122.97,31.98 123.7,32.72 124.12,32.72 124.28,32.88 124.28,33.3 124.54,33.55 124.94,33.55 125.09,33.71 125.09,35.38 125.46,35.75 125.46,37.08 124.81,37.74 124.81,42.88 122.26,45.43 119.62,45.43 118.31,46.74 118.31,48.49 118.8,48.97 121.36,48.97 121.91,49.52 121.91,54.97 124.29,57.35 124.29,58.83 124.5,59.04 124.5,59.73 126.24,61.47 126.24,61.53 v1(126.44,61.73)
MB_AMA8: length 72.3
  TOP w0.165: R274.2 v1(111.08,30.81) 111.11,30.78 111.46,30.78 113.54,32.86 113.54,33.77 U12.D2 ; v1(126.49,67.74) 126.49,67.74 126.19,67.74 U6.AP46
  IN2 w0.191: v1(111.08,30.81) 111.48,31.21 111.48,32.87 111.66,33.05 111.9,33.05 112.08,32.87 112.08,31.54 112.25,31.36 112.5,31.36 112.68,31.54 112.68,32.62 112.85,32.79 113.1,32.79 113.27,32.62 113.27,31.9 113.45,31.72 118.92,31.72 119.45,31.2 124.36,31.2 126.03,32.87 126.03,35.21 126.34,35.51 126.34,37.32 125.81,37.85 125.81,43.49 123.08,46.22 120.15,46.22 119.45,46.92 119.45,47.8 119.84,48.18 121.84,48.18 122.69,49.03 122.69,54.64 125.08,57.03 125.08,58.51 125.29,58.71 125.29,59.37 127.23,61.32 127.23,64.26 127.29,64.33 127.29,66.47 126.95,66.82 126.95,67.28 v1(126.49,67.74)
MB_AMA9: length 72.8
  TOP w0.165: R273.2 v1(110.07,30.73) v1(110.62,31.29) 112.28,32.94 112.93,32.94 113.11,33.12 113.11,33.99 U12.C2 ; U6.AR46 126.27,67.3 v1(126.47,67.1)
  IN2 w0.191: v1(126.47,67.1) 126.47,66.75 126.97,66.24 126.97,64.39 126.95,64.36 126.95,61.59 124.89,59.54 124.89,58.87 124.69,58.67 124.69,57.19 122.3,54.8 122.3,49.2 121.68,48.58 119.29,48.58 118.85,48.13 118.85,46.76 119.79,45.82 122.43,45.82 125.41,42.84 125.41,37.69 125.81,37.3 125.81,37.28 125.93,37.15 125.93,35.66 125.6,35.33 125.6,33.12 124.07,31.59 119.61,31.59 118.97,32.23 114.19,32.23 113.62,32.8 113.62,33.48 113.48,33.62 112.16,33.62 111.96,33.82 111.66,33.82 110.32,32.48 110.32,32.23 110.84,31.71 110.84,31.46 110.66,31.29 110.42,31.29 109.9,31.81 109.65,31.81 109.35,31.5 109.35,31 109.61,30.73 v1(110.07,30.73)
MB_AZQ0: length 4.5
  TOP w0.165: U12.B3 112.31,34.64 111.89,34.64 v2(110.51,33.26) 110.39,33.14 R221.2
MB_AZQ1: length 6.3
  TOP w0.165: U12.B4 112.32,35.45 111.61,35.45 v2(110.24,36.82) 109.09,37.97 108.5,37.97 R206.2
MB_BMA0: length 80.9
  TOP w0.165: v6(102.67,34.65) 102.36,34.34 U11.R2 102.62,33.99 102.62,33.3 103.37,32.55 103.4,32.55 103.71,32.24 103.96,32.24 v1(105.58,30.62) 105.93,30.27 105.94,30.27 R272.2 ; U6.AK33 118.16,70.79 v1(118.38,70.79)
  IN2 w0.191: v1(118.38,70.79) 117.67,70.79 117.32,71.15 117.32,71.85 117.03,72.14 117.03,72.14 116.96,72.21 116.45,72.21 116.37,72.14 111.46,72.14 109.86,70.53 109.86,66.52 109.25,65.91 108.53,65.91 106.22,63.6 106.22,63.27 104.17,61.22 104.17,57.1 104,56.93 103.06,56.93 102.67,56.54 100.79,56.54 96.82,52.57 96.82,51.04 95.31,49.54 95.31,48.78 95.15,48.62 93.94,48.62 93.78,48.45 93.78,48.21 93.94,48.05 94.73,48.05 94.89,47.88 94.89,47.64 94.73,47.47 93.92,47.47 93.75,47.31 93.75,47.07 93.92,46.9 94.6,46.9 94.77,46.74 94.77,46.5 94.6,46.33 93.72,46.33 93.55,46.16 93.55,45.93 93.72,45.76 95.15,45.76 95.31,45.59 95.31,45.36 95.15,45.19 93.54,45.19 93.37,45.02 93.37,44.78 93.54,44.62 95.15,44.62 95.31,44.45 95.31,43.7 95.95,43.06 97.01,43.06 97.49,42.59 97.49,40.04 98.25,39.28 98.25,39.09 97.92,38.76 97.92,38.4 98.12,38.2 99.63,38.2 99.81,38.02 99.81,37.77 99.63,37.59 98.12,37.59 97.92,37.39 97.92,36.53 98.61,35.84 99.03,35.84 100.23,34.65 v6(102.67,34.65)
MB_BMA1: length 79
  TOP w0.165: R271.2 105.54,29.84 v1(104.1,31.28) 102.02,33.36 v6(102.02,33.87) 101.71,34.18 U11.P2 ; v1(118.35,69.52) 118.18,69.52 U6.AM33
  IN2 w0.076: v1(118.35,69.52) 117.79,68.96 117.79,66.79 117.48,66.47 117.17,66.47
  IN2 w0.191: v6(102.02,33.87) 102.37,34.21 104.19,34.21 104.8,34.82 106.83,34.82 107.94,35.93 107.94,38.08 106.63,39.39 106.63,39.75 105.16,41.22 105.16,41.81 104.67,42.29 104.67,43.64 103.87,44.44 102.43,44.44 102.23,44.63 102.23,45.02 102.07,45.19 100.14,45.19 99.97,45.36 99.97,45.59 100.14,45.76 102.07,45.76 102.23,45.93 102.23,46.16 102.07,46.33 100.12,46.33 99.95,46.5 99.95,46.74 100.12,46.9 102.07,46.9 102.23,47.07 102.23,47.31 102.07,47.47 100.17,47.47 100,47.64 100,47.88 100.17,48.05 102.07,48.05 102.23,48.21 102.23,48.45 102.07,48.62 100.14,48.62 99.97,48.79 99.97,49.02 100.14,49.19 102.07,49.19 102.23,49.36 102.23,49.59 102.07,49.76 101.06,49.76 100.89,49.93 100.89,50.16 101.06,50.33 102.07,50.33 102.23,50.5 102.23,51.05 102.51,51.33 103.4,51.33 104.45,52.39 105.8,52.39 107.47,54.05 107.47,54.56 107.8,54.89 109.78,54.89 112.73,57.84 112.73,57.96 113.12,58.36 113.12,63.41 114.55,64.84 115.54,64.84 117.17,66.47
MB_BMA2: length 77.8
  TOP w0.165: v1(119.33,70.22) 119,70.55 U6.AK35 ; U11.N2 101.06,33.93 101.23,33.76 v6(101.23,33.7) 101.23,32.07 v1(102.54,30.76) 103.51,29.79 R269.2
  IN2 w0.076: 117.29,66.02 117.96,66.69 117.96,68 118.26,68.3 118.34,68.3 118.75,68.71 118.75,69.64 v1(119.33,70.22)
  IN2 w0.191: v6(101.23,33.7) 101.55,33.7 101.8,33.45 102.2,33.45 102.55,33.81 104.34,33.81 104.95,34.42 106.98,34.42 108.33,35.76 108.33,38.6 108.07,38.86 107.71,38.86 107.14,39.44 107.14,39.8 106.73,40.2 106.73,41.18 106.53,41.38 105.99,41.38 105.77,41.6 105.77,42.15 105.26,42.66 105.26,43.61 104.65,44.22 104.65,44.65 104.44,44.86 104.01,44.86 103.48,45.39 103.48,46.58 103.68,46.78 105.2,46.78 105.37,46.95 105.37,47.18 105.2,47.35 102.8,47.35 102.63,47.52 102.63,47.75 102.8,47.92 105.2,47.92 105.37,48.09 105.37,48.33 105.2,48.49 102.82,48.49 102.63,48.69 102.63,48.96 102.82,49.15 105.17,49.15 105.37,49.35 105.37,49.58 105.17,49.78 102.92,49.78 102.72,49.99 102.72,50.34 102.92,50.55 103.78,50.55 103.99,50.75 103.99,51.23 104.19,51.44 104.42,51.44 104.62,51.23 104.62,50.62 104.83,50.42 105.13,50.42 105.33,50.62 105.33,51.79 105.54,51.99 106.2,51.99 108.03,53.83 108.35,53.83 109.01,54.5 110.4,54.5 112.67,56.77 114.05,56.77 114.6,57.33 114.6,58.06 114.54,58.13 114.54,63.16 117.29,65.9 117.29,66.02
MB_BMA3: length 77.7
  TOP w0.076: U11.N3 101.39,34.72 101.39,34.1 101.64,33.84 101.64,33.66
  TOP w0.165: U6.AM35 118.98,69.25 v1(119.31,68.92) ; R270.2 104.53,30.21 v1(102.14,32.6) 101.64,33.09 101.64,33.66
  IN2 w0.076: 118.06,65.41 118.06,66.04 118.39,66.37 118.59,66.37 118.91,66.69 118.91,68.11 119.31,68.5 v1(119.31,68.92)
  IN2 w0.191: v1(102.14,32.6) 102.45,32.6 102.88,33.02 104.92,33.02 105.15,32.79 105.33,32.79 105.49,32.94 105.49,33.5 105.59,33.6 106.53,33.6 106.81,33.32 107.01,33.32 109.12,35.43 109.12,35.72 109.37,35.98 109.37,36.42 109.12,36.68 109.12,38.27 109.69,38.84 109.69,39.66 109.41,39.94 109.17,39.94 108.79,39.55 108.55,39.55 108.39,39.72 108.39,39.96 108.77,40.34 108.77,40.58 108.6,40.75 108.37,40.75 107.98,40.36 107.74,40.36 107.58,40.53 107.58,40.77 107.96,41.15 107.96,41.39 107.58,41.77 107.58,42.35 107.41,42.52 106.51,42.52 106.35,42.68 106.35,42.92 106.51,43.09 107.41,43.09 107.58,43.25 107.58,43.49 107.41,43.66 106.44,43.66 106.27,43.83 106.27,44.06 106.44,44.23 107.41,44.23 107.58,44.4 107.58,44.63 107.41,44.8 106.44,44.8 106.27,44.97 106.27,45.21 106.44,45.37 107.41,45.37 107.58,45.54 107.58,45.78 107.41,45.95 106.44,45.95 106.27,46.11 106.27,46.35 106.44,46.52 107.41,46.52 107.58,46.68 107.58,46.92 107.41,47.09 106.44,47.09 106.27,47.26 106.27,47.49 106.44,47.66 107.41,47.66 107.58,47.83 107.58,48.06 107.41,48.23 106.48,48.23 106.32,48.4 106.32,48.64 106.91,49.23 107.29,49.23 107.69,48.82 107.98,48.82 108.19,49.03 108.19,49.32 107.99,49.51 107.99,49.75 108.16,49.92 108.4,49.92 108.69,49.62 108.93,49.62 109.09,49.79 109.09,50.03 108.64,50.49 108.64,50.72 108.8,50.89 109.04,50.89 109.4,50.53 109.64,50.53 109.8,50.7 109.8,50.93 109.44,51.29 109.44,51.53 109.61,51.7 109.85,51.7 110.21,51.34 110.44,51.34 111.32,52.21 111.44,52.21 112.15,52.92 112.15,54.57 113.4,55.82 113.8,55.82 114.15,55.47 114.53,55.47 115.37,56.31 115.7,56.31 116.55,57.16 116.55,59.35 116.48,59.41 116.48,61.75 117.15,62.41 117.15,64.11 117.6,64.57 117.6,64.95 118.06,65.41
MB_BMA4: length 77.9
  TOP w0.076: 100.74,34.08 100.74,34.72 U11.M3
  TOP w0.165: R268.2 102.5,30.17 v1(101.36,31.31) 100.69,31.97 v6(100.69,33.52) 100.74,33.57 100.74,34.08 ; U6.AL35 118.98,69.9 v1(119.31,69.57)
  IN2 w0.076: 117.65,65.71 117.65,66.07 118.17,66.58 118.57,66.58 118.75,66.76 118.75,68.2 118.91,68.36 118.91,69.18 v1(119.31,69.57)
  IN2 w0.191: 117.65,65.71 115.21,63.27 115.21,58.06 115.04,57.89 115.04,57.2 114.21,56.38 113.4,56.38 111.76,54.74 111.76,53.09 111.46,52.78 110.75,52.78 110.24,53.3 110.24,53.95 110.08,54.1 109.18,54.1 108.9,53.82 108.9,53.59 109.8,52.68 109.8,52.45 109.63,52.28 109.4,52.28 108.39,53.29 108.15,53.29 107.98,53.12 107.98,52.88 108.99,51.87 108.99,51.64 108.82,51.47 108.59,51.47 107.68,52.37 107.45,52.37 107.28,52.21 107.28,51.97 108.2,51.05 108.2,50.82 108.03,50.65 107.79,50.65 106.72,51.72 106.48,51.72 106.32,51.55 106.32,51.32 107.6,50.03 107.6,49.8 107.43,49.63 107.2,49.63 106.07,50.76 105.94,50.76 105.77,50.58 105.77,46.22 105.6,46.05 104.36,46.05 104.19,45.88 104.19,45.65 104.36,45.48 105.6,45.48 105.77,45.31 105.77,45.07 105.6,44.91 105.27,44.91 105.11,44.74 105.11,44.5 105.27,44.33 105.6,44.33 105.77,44.17 105.77,42.71 106.35,42.12 106.98,42.12 107.16,41.94 107.16,40.33 108.72,38.77 108.72,35.6 107.13,34.01 105.1,34.01 104.5,33.41 102.71,33.41 102.36,33.06 101.64,33.06 101.42,33.27 100.94,33.27 v6(100.69,33.52)
MB_BMA5: length 64.6
  TOP w0.076: 96.19,33.91 96.19,34.73 U11.F3
  TOP w0.165: R263.2 97.29,30.3 v1(96.78,30.81) 96.78,32.78 96.24,33.32 96.24,33.86 96.19,33.91 ; U6.AP42 123.35,67.95 v1(123.62,67.67)
  IN2 w0.191: v1(123.62,67.67) 123.16,67.21 123.16,66.78 122.22,65.84 122.22,63.53 122.11,63.41 121.68,63.41 120.95,62.69 120.95,59.47 119.08,57.59 119.08,56.82 111.63,49.38 111.63,48.61 111.07,48.05 111.07,47.29 110.95,47.16 110.95,45.85 112.29,44.5 112.29,43.46 112.83,42.93 112.83,42.62 113.11,42.34 113.32,42.34 113.92,41.73 113.92,39.85 114.11,39.66 114.11,38.48 113.63,38 113.41,38 112.37,36.96 112.37,35.08 108.22,30.94 106.86,30.94 106.43,30.51 101.35,30.51 101.05,30.81 v1(96.78,30.81)
MB_BMA6: length 78.3
  TOP w0.076: v6(95.26,33.7) 95.54,33.98 95.54,34.73 U11.E3
  TOP w0.165: v1(120.26,69.07) 120.09,69.25 U6.AM36 ; R261.2 95.26,29.9 v2(95.26,30.77) v6(95.26,33.7)
  IN2 w0.076: v1(120.26,69.07) 120.73,68.6 120.73,67.02 120.08,66.38
  IN2 w0.191: v6(95.26,33.7) 95.26,33.65 95.9,33.01 96.13,33.01 96.42,33.3 96.66,33.3 96.83,33.13 96.83,32.89 96.54,32.6 96.54,32.37 96.82,32.09 97.11,32.09 97.41,32.38 97.75,32.38 98.04,32.09 98.41,32.09 98.58,32.26 98.58,33.18 98.75,33.35 98.98,33.35 99.15,33.18 99.15,32.26 99.32,32.09 99.56,32.09 99.72,32.26 99.72,32.78 99.89,32.94 100.13,32.94 100.29,32.78 100.29,32.26 100.46,32.09 101.44,32.09 101.81,31.71 105.97,31.71 106.45,32.19 107.02,32.19 109.91,35.08 109.91,35.33 110.48,35.9 110.48,41.51 110.19,41.8 110.02,41.8 109.86,41.96 109.86,42.2 110.02,42.37 110.28,42.37 110.45,42.54 110.45,42.77 110.28,42.94 108.75,42.94 108.58,43.11 108.58,43.34 108.75,43.51 110.25,43.51 110.42,43.68 110.42,43.91 110.25,44.08 108.75,44.08 108.58,44.25 108.58,44.49 108.75,44.65 109.69,44.65 109.86,44.82 109.86,45.06 109.69,45.23 108.75,45.23 108.58,45.39 108.58,45.63 108.75,45.8 109.28,45.8 109.45,45.96 109.45,46.2 109.28,46.37 108.75,46.37 108.58,46.54 108.58,46.77 108.75,46.94 109.28,46.94 109.45,47.11 109.45,47.34 109.28,47.51 108.75,47.51 108.58,47.68 108.58,47.92 108.75,48.08 109.28,48.08 109.45,48.25 109.45,48.36 109.98,48.89 109.98,49.48 117.78,57.28 117.78,58.39 118.84,59.46 118.84,61.54 118.81,61.57 118.81,63.77 119.72,64.68 119.72,66.01 120.08,66.38
MB_BMA7: length 77.5
  TOP w0.165: U11.E2 95.86,33.75 v6(95.82,33.7) 95.82,33.19 96.15,32.86 v1(96.15,31.69) R262.2 ; U6.AK36 119.94,70.38 v1(120.28,70.38)
  IN2 w0.191: v1(120.28,70.38) 120.03,70.38 119.79,70.13 119.79,66.7 119.23,66.14 119.23,64.82 118.38,63.98 118.38,61.79 118.39,61.79 118.39,59.64 116.94,58.19 116.94,57 115.62,55.68 115.29,55.68 115.04,55.42 115.04,55.09 114.61,54.66 114.37,54.66 113.96,55.07 113.72,55.07 113.55,54.91 113.55,54.67 113.97,54.26 113.97,54.02 113.8,53.85 113.56,53.85 112.95,54.46 112.71,54.46 112.55,54.3 112.55,54.06 113.16,53.45 113.16,53.21 109.93,49.99 109.83,49.99 109.42,49.58 109.42,48.89 109.01,48.48 108.42,48.48 108.08,48.13 108.08,41.96 108.36,41.68 108.59,41.68 109.06,42.15 109.29,42.15 109.46,41.98 109.46,41.74 109,41.28 109,41.04 109.16,40.87 109.4,40.87 109.48,40.96 109.72,40.96 109.89,40.79 109.89,40.55 109.81,40.47 109.81,40.23 110.08,39.95 110.08,38.68 109.73,38.32 109.73,38 110.08,37.64 110.08,37.43 109.92,37.26 109.68,37.26 109.51,37.1 109.51,36.86 109.68,36.69 109.92,36.69 110.08,36.53 110.08,36.13 109.51,35.56 109.51,35.27 106.83,32.59 106.15,32.59 105.69,32.13 105.09,32.13 104.92,32.3 104.92,32.46 104.75,32.63 104.52,32.63 104.35,32.46 104.35,32.3 104.18,32.13 103.95,32.13 103.78,32.3 103.78,32.46 103.61,32.63 103.37,32.63 103.21,32.46 103.21,32.3 103.04,32.13 101.95,32.13 101.6,32.48 100.82,32.48 100.69,32.61 100.69,32.94 100.29,33.34 99.85,33.34 99.64,33.54 99.64,34.01 99.85,34.22 99.85,34.46 99.68,34.64 99.43,34.64 98.93,34.14 98.73,34.14 98.54,34.33 98.54,34.58 98.78,34.82 98.78,35.12 98.36,35.53 98.12,35.53 97.94,35.36 97.94,34.34 97.74,34.14 96.6,34.14 96.39,34.34 96.39,34.87 96.22,35.04 95.58,35.04 95.3,34.76 95.3,34.37 95.82,33.85 v6(95.82,33.7)
MB_BMA8: length 63.3
  TOP w0.165: v1(122.71,66.97) 122.38,67.3 U6.AR40 ; U11.D2 94.85,33.89 94.85,33.19 v6(94.67,33.01) 93.86,32.2 v2(93.86,31.38) R260.2
  IN2 w0.191: v1(122.71,66.97) 122.28,66.97 121.16,65.85 121.16,63.45 120.56,62.85 120.56,59.63 118.64,57.71 118.64,56.95 111.05,49.35 111.05,48.62 110.68,48.25 110.68,47.46 110.44,47.22 110.44,45.69 111.66,44.47 111.66,41.42 111.96,41.12 111.96,37.85 111.33,37.22 111.33,35.64 110.94,35.25 110.94,34.21 108.14,31.41 106.78,31.41 106.27,30.9 101.51,30.9 101.11,31.3 96.38,31.3 v6(94.67,33.01)
MB_BMA9: length 63.1
  TOP w0.165: U6.AP40 122.38,67.95 v1(122.71,67.62) ; U11.C2 94.45,34.14 v6(94.45,33.74) 94.45,33.45 92.72,31.72 v2(92.72,30.8) R259.2
  IN2 w0.191: v6(94.45,33.74) 94.53,33.74 96.57,31.7 101.27,31.7 101.65,31.32 106.13,31.32 106.61,31.8 107.19,31.8 110.44,35.05 110.44,35.31 110.94,35.81 110.94,41.56 110.84,41.66 110.84,44.74 110.05,45.53 110.05,48.35 110.66,48.96 110.66,49.57 118.21,57.13 118.21,58.22 119.44,59.44 119.44,61.47 119.41,61.5 119.41,62.62 120.16,63.37 120.37,63.37 120.65,63.64 120.65,65.74 122.53,67.62 v1(122.71,67.62)
MB_BZQ0: length 5.9
  TOP w0.165: v2(89.8,32.12) R223.2 91.45,33.19 92.89,34.64 93.5,34.64 U11.B3
MB_BZQ1: length 4.7
  TOP w0.165: U11.B4 93.51,35.45 92.56,35.45 91.45,34.34 v2(90.9,34.34) R219.2
MB_CKE0: length 69.4
  TOP w0.076: 118.62,33.73 118.24,34.1 118.24,34.73 U12.K3
  TOP w0.165: 118.62,33.73 118.67,33.68 118.67,30.6 v1(118.42,30.35) 118.7,30.07 R281.2 ; U6.AY49 127.58,64.1 127.58,63.85 127.53,63.8 127.53,61.45 v1(128.07,60.91)
  IN2 w0.076: v1(128.07,60.91) 128.46,60.53 128.46,60.12 128.17,59.83
  IN2 w0.191: 128.17,59.83 127.52,59.83 126.57,58.88 126.57,56.41 126.24,56.08 126.24,55.88 126.57,55.55 126.57,47.8 126.39,47.62 126.14,47.62 125.97,47.79 125.97,55.19 125.79,55.37 125.52,55.37 125.37,55.22 125.37,47.22 126.2,46.39 126.2,45.3 127.36,44.15 127.36,38.77 128.65,37.48 128.65,36.83 128.54,36.72 128.54,34.67 128.63,34.59 128.63,33.15 127.75,32.27 127.75,31.64 127.56,31.45 126.92,31.45 125.19,29.71 118.37,29.71 118.24,29.84 118.24,30.16 v1(118.42,30.35)
MB_CKE1: length 72.9
  TOP w0.076: U12.K4 117.6,35.53 117.6,33.63 ; v1(127.97,62.17) 128.74,62.17 128.8,62.23 128.8,63.73 128.94,63.87 128.94,64.28 128.92,64.34 128.92,64.34 128.87,64.45 128.87,64.58 128.94,64.73 128.94,64.94 128.92,64.99 128.88,65.08 128.87,65.09 128.87,65.85 U6.AU50
  TOP w0.165: 117.6,33.63 117.81,33.42 117.81,30.73 117.51,30.43 v1(117.51,30.4) 117.51,30.31 117.69,30.13 R280.2
  IN2 w0.076: v1(127.97,62.17) 128.08,62.17 128.49,61.76 128.49,60.73 128.62,60.6 128.62,59.84 128.14,59.36
  IN2 w0.191: 128.14,59.36 126.96,58.18 126.96,47.37 126.64,47.05 126.64,45.42 127.75,44.31 127.75,38.94 129.04,37.65 129.04,32.77 128.35,32.07 128.35,31.48 127.11,30.24 126.51,30.24 125.46,29.2 118.22,29.2 118.03,29.39 109.82,29.39 109.64,29.57 109.64,29.89 109.79,30.04 117.14,30.04 v1(117.51,30.4)
MB_CKE2: length 73.4
  TOP w0.076: 98.79,34.08 98.79,34.73 U11.K3
  TOP w0.165: 98.79,34.08 98.79,31.59 100.01,30.37 v1(100.01,30.32) 100.01,30.1 R266.2 ; v1(128.06,64.53) 127.97,64.53 U6.AW49
  IN2 w0.076: 127.75,58.05 128.95,59.25 128.95,60.77 128.82,60.91 128.82,63.08 128.47,63.43 128.47,64.12 v1(128.06,64.53)
  IN2 w0.191: 127.75,58.05 127.75,45.43 128.54,44.64 128.54,39.26 129.92,37.88 129.92,31.94 126.39,28.41 117.9,28.41 117.7,28.6 101.51,28.6 100.01,30.11 v1(100.01,30.32)
MB_CKE3: length 73.6
  TOP w0.076: U11.K4 99.44,35.52 99.44,34.04 ; v1(128.36,62.98) 128.5,63.12 128.5,63.75 128.78,64.03 128.78,64.25 128.73,64.36 128.7,64.41 128.7,64.61 128.73,64.67 128.78,64.77 128.78,64.9 128.73,65.01 128.59,65.14 U6.AV50
  TOP w0.165: 99.44,34.04 99.65,33.83 99.65,31.36 100.64,30.37 v1(100.64,30.32) 101.32,29.65 R267.2
  IN2 w0.076: 127.36,58.09 128.79,59.52 128.79,60.71 128.66,60.84 128.66,62.69 v1(128.36,62.98)
  IN2 w0.191: 127.36,58.09 127.36,45.27 128.15,44.47 128.15,39.1 129.49,37.76 129.49,32.06 127.26,29.84 127.02,29.84 125.98,28.8 118.06,28.8 117.87,28.99 101.76,28.99 100.64,30.11 v1(100.64,30.32)
MB_CLKN0: length 69.6
  TOP w0.165: U12.J2 117.27,33.78 116.93,33.44 116.93,33.23 v1(117.01,33.14) 116.85,32.98 116.85,31.69 116.33,31.17 116.33,29.98 R279.2 ; U6.AM38 120.76,69.31 120.76,69.42 120.88,69.55 121.03,69.55 121.23,69.75 121.43,69.75 v1(121.51,69.66)
  IN3 w0.076: 120.55,58.58 120.54,58.6 120.54,58.68 120.37,58.85 120.37,62.84 120.09,63.12 119.93,63.12 119.62,63.43 119.62,66.13 120.05,66.56 120.35,66.56 120.69,66.9 120.69,67.57 120.65,67.61 120.65,68.6 120.8,68.75 120.8,69.09 121.03,69.32 121.42,69.32 121.51,69.41 v1(121.51,69.66)
  IN3 w0.152: v1(117.01,33.14) 116.62,32.75 116.62,32.56 116.77,32.41 117.53,32.41 117.85,32.09 117.85,31.27 118,31.12 118.36,31.12 118.51,31.27 118.51,32.09 118.82,32.41 119.41,32.41 119.73,32.09 119.73,30.38 119.91,30.2 120.21,30.2 120.39,30.38 120.39,32.09 120.7,32.41 121.29,32.41 121.56,32.14 121.56,29.59 121.74,29.41 122.09,29.41 122.27,29.59 122.27,32.09 122.58,32.41 123.14,32.41 124.8,34.07 125.24,34.07 125.83,33.48 126.05,33.48 126.3,33.73 126.3,33.95 125.71,34.54 125.71,34.98 126.19,35.46 126.19,38.13 125.27,39.05 125.27,50.14 120.75,54.66 120.75,58.39 120.55,58.58
MB_CLKN1: length 70.5
  TOP w0.165: U6.AK38 120.68,70.67 120.68,70.76 120.89,70.98 v1(121.09,70.98) ; U11.J2 98.46,33.12 v6(98.05,32.71) 97.8,32.46 97.8,31.59 99.08,30.31 99.08,30.01 R265.2
  IN3 w0.076: v1(121.09,70.98) 121.09,70.7 121.16,70.64 121.48,70.64 121.58,70.73 121.58,71.15 121.27,71.46 120.99,71.46 120.72,71.19 118.18,71.19 118.12,71.13 114.49,71.13 113.95,70.59 112.85,70.59 112.75,70.48 112.75,70.03 112.05,69.33 112.05,65.45 111.62,65.02 111.62,64.94 111.61,64.92
  IN3 w0.152: 111.61,64.92 110.44,63.75 110.44,62.65 109.83,62.04 109.83,57.39 109.58,57.14 109.58,48.37 107.98,46.77 107.98,35.29 107.89,35.21 107.89,34.99 108.27,34.62 108.27,34.14 107.89,33.76 107.41,33.76 107.03,34.13 106.82,34.13 105.68,33 105.68,32.78 106.49,31.97 106.49,31.49 106.11,31.11 105.62,31.11 104.82,31.92 104.6,31.92 104.1,31.42 101.41,31.42 99.91,32.92 98.26,32.92 v6(98.05,32.71)
MB_CLKP0: length 69.7
  TOP w0.076: 116.88,33.87 116.94,33.93 116.94,34.72 U12.J3
  TOP w0.165: v1(121.21,68.92) 121.15,68.92 U6.AN38 ; 116.88,33.87 116.59,33.58 116.59,33.39 v1(116.34,33.14) 116.51,32.97 116.51,31.83 115.99,31.31 115.99,29.98 R278.2
  IN3 w0.076: 120.75,58.78 120.74,58.79 120.66,58.79 120.54,58.92 120.54,62.91 120.16,63.28 120,63.28 119.79,63.5 119.79,66.07 120.12,66.4 120.42,66.4 120.85,66.83 120.85,67.64 120.82,67.68 120.82,68.53 v1(121.21,68.92)
  IN3 w0.152: v1(116.34,33.14) 116.34,32.45 116.66,32.13 117.42,32.13 117.57,31.98 117.57,31.15 117.88,30.84 118.47,30.84 118.79,31.15 118.79,31.98 118.94,32.13 119.3,32.13 119.45,31.98 119.45,30.26 119.79,29.92 120.33,29.92 120.67,30.26 120.67,31.98 120.82,32.13 121.18,32.13 121.29,32.02 121.29,29.48 121.63,29.13 122.21,29.13 122.55,29.48 122.55,31.98 122.7,32.13 123.25,32.13 124.91,33.79 125.13,33.79 125.72,33.2 126.16,33.2 126.58,33.62 126.58,34.06 125.99,34.65 125.99,34.87 126.47,35.35 126.47,38.25 125.55,39.16 125.55,50.26 121.03,54.78 121.03,58.5 120.75,58.78
MB_CLKP1: length 71.3
  TOP w0.076: 98.12,34.01 98.13,34.02 98.13,34.72 U11.J3
  TOP w0.165: U6.AL38 120.89,69.9 v1(121.21,70.22) ; 98.12,34.01 98.12,33.36 v6(98.05,33.3) 97.46,32.7 97.46,31.45 98.74,30.17 98.74,29.93 98.46,29.65 R264.2
  IN3 w0.076: v1(121.21,70.22) 121.46,70.47 121.55,70.47 121.74,70.66 121.74,71.22 121.34,71.63 120.92,71.63 120.65,71.35 118.11,71.35 118.05,71.3 114.42,71.3 113.88,70.75 112.78,70.75 112.59,70.55 112.59,70.1 111.89,69.4 111.89,65.52 111.5,65.13 111.42,65.13 111.41,65.12
  IN3 w0.152: v6(98.05,33.3) 98.15,33.2 100.03,33.2 101.52,31.7 103.99,31.7 104.49,32.2 104.93,32.2 105.74,31.39 105.99,31.39 106.21,31.61 106.21,31.86 105.4,32.67 105.4,33.11 106.7,34.41 107.15,34.41 107.52,34.04 107.77,34.04 107.99,34.25 107.99,34.5 107.61,34.88 107.61,35.33 107.7,35.41 107.7,46.89 109.3,48.49 109.3,57.25 109.55,57.51 109.55,62.15 110.16,62.76 110.16,63.87 111.41,65.12
MB_CS#0: length 89.6
  TOP w0.165: v6(100.09,35.45) 99.76,35.12 U11.L3 ; U6.AM32 117.08,69.25 v1(117.4,68.92) ; R216.2 107.04,35.05 v1(106.71,35.38) ; v6(118.24,35.45) 118.24,35.38 U12.L3
  IN1 w0.191: v6(100.09,35.45) 100.09,35.09 100.81,34.37 102.16,34.37 102.55,33.97 104.1,33.97 104.52,33.55 104.88,33.55 105.16,33.27 105.71,33.27 106.35,33.91 107.87,33.91 108.08,34.11 108.08,34.47 107.87,34.67 106.81,34.67 106.71,34.77 v1(106.71,35.38) 106.98,35.66 113.2,35.66 113.39,35.85 117.52,35.85 117.84,35.85 v6(118.24,35.45)
  IN2 w0.191: v1(117.4,68.92) 116.85,68.92 116.59,68.66 116.59,66.9 115.93,66.24 114.5,66.24 113.54,65.28 113.13,65.28 111.96,64.11 111.96,62.66 111.73,62.43 111.73,57.84 109.48,55.59 107.4,55.59 106.77,54.95 106.77,54.34 106.45,54.03 106.29,54.03 105.66,54.66 105.43,54.66 105.26,54.49 105.26,54.25 105.54,53.97 105.54,53.47 105.16,53.09 104.93,53.09 104.65,53.37 103.96,53.37 103.58,52.98 102.72,52.98 102.35,52.62 102.12,52.62 101.72,53.02 101.48,53.02 101.31,52.85 101.31,52.61 101.94,51.99 101.94,51.75 101.77,51.58 101.54,51.58 100.68,52.44 100.45,52.44 100.28,52.27 100.28,52.03 100.9,51.41 100.9,51.17 100.74,51 100.5,51 100.34,51.16 100.1,51.16 99.94,50.99 99.94,50.76 100.08,50.61 100.08,50.37 99.91,50.21 99.68,50.21 99.39,50.49 99.16,50.49 98.99,50.32 98.99,50.09 99.29,49.79 99.29,49.55 99.01,49.27 99.01,47.8 99.32,47.5 99.32,47.09 99.01,46.78 99.01,46 99.28,45.73 99.28,45.28 99.01,45.01 99.01,44.34 99.43,43.92 99.57,43.92 100.13,44.47 100.64,44.47 100.75,44.36 100.75,44 100.48,43.73 100.48,43.23 100.63,43.08 100.89,43.08 101.22,42.75 101.52,42.75 101.68,42.9 101.68,43.74 101.83,43.89 101.99,43.89 102.14,43.74 103.35,43.74 103.96,43.13 103.96,41.83 104.34,41.45 104.34,41.33 103.96,40.94 103.96,40.59 104.42,40.13 104.66,40.13 104.79,40.26 105.03,40.26 105.19,40.09 105.19,39.85 105.06,39.72 105.06,39.49 105.94,38.61 106.42,38.61 107.24,37.79 107.24,36.23 106.71,35.7 v1(106.71,35.38)
MB_CS#1: length 89.9
  TOP w0.165: R212.2 106.5,36.2 v1(106.48,36.22) ; U12.L4 118.24,36.18 v6(118.24,36.25) ; U6.AK32 117.1,70.55 v1(117.42,70.22) ; v6(99.44,36.25) 99.44,36.17 U11.L4
  IN1 w0.191: v6(118.24,36.25) 117.84,36.65 111.2,36.65 110.77,36.22 v1(106.48,36.22) 106.48,35.84 106.2,35.56 105.84,35.56 105.55,35.85 105.36,35.85 105.16,35.65 105.16,35 105.36,34.8 105.66,34.8 105.87,34.59 105.87,34.26 105.66,34.06 104.64,34.06 104.44,34.26 104.44,35.66 104.24,35.85 100.42,35.85 100.02,36.25 v6(99.44,36.25)
  IN2 w0.191: v1(117.42,70.22) 116.21,71.44 112.76,71.44 112.18,70.86 111.17,70.86 110.79,70.48 110.79,65.3 109.93,64.43 109.93,63.6 108.36,62.03 108.36,58.67 106.13,56.45 106.03,56.45 105.82,56.24 103.58,56.24 102,54.65 100.07,54.65 97.52,52.1 97.52,49.58 97.35,49.42 96.18,49.42 96.01,49.25 96.01,49.01 96.18,48.85 96.59,48.85 96.76,48.68 96.76,48.44 96.59,48.27 96.18,48.27 96.01,48.11 96.01,44.02 96.27,43.76 97.61,43.76 98.78,42.59 98.78,40.31 99.21,39.88 100.94,39.88 101.24,39.57 101.24,39.29 100.51,38.56 100.51,37.77 100.81,37.46 101.28,37.46 101.45,37.63 101.45,38.03 101.62,38.2 101.85,38.2 102.02,38.03 102.02,37.63 102.19,37.46 102.42,37.46 102.59,37.63 102.59,37.81 102.76,37.97 103,37.97 103.16,37.81 103.16,37.63 103.33,37.46 104.16,37.46 105.4,36.22 v1(106.48,36.22)
MB_DQ0: length 33.7
  TOP w0.076: v1(117.8,61.97) 117.79,61.97 117.09,62.68 117.09,63.95 116.96,64.07 U6.AY31
  TOP w0.165: v6(121.5,39.45) 121.17,39.78 U12.R9
  IN1 w0.076: 119.57,53.33 119.32,53.58 119.32,54.77 117.65,56.44 117.65,59.18 117.92,59.45 117.92,60.72 117.8,60.85 v1(117.8,61.97)
  IN1 w0.191: 119.57,53.33 124.99,47.9 124.99,47.43 125.25,47.18 125.72,47.18 126.01,46.88 126.01,40.77 124.29,39.05 121.71,39.05 121.5,39.26 v6(121.5,39.45)
MB_DQ1: length 34.8
  TOP w0.076: v1(117.82,62.6) 117.82,62.6 117.25,63.16 117.25,64.25 117.2,64.36 117.18,64.38 117.18,64.62 U6.AW31
  TOP w0.165: v6(122.15,38.65) 121.82,38.98 U12.T8
  IN1 w0.076: 119.66,53.83 119.48,54.01 119.48,54.84 117.91,56.41 117.91,58.96 118.1,59.15 118.1,60.78 117.96,60.91 117.96,61.57 118.24,61.85 118.24,62.18 v1(117.82,62.6)
  IN1 w0.191: 119.66,53.83 126.43,47.05 126.43,40.58 124.05,38.2 123.83,38.2 123.55,38.48 123.25,38.48 122.97,38.2 122.6,38.2 v6(122.15,38.65)
MB_DQ2: length 35
  TOP w0.076: U6.AY29 115.49,64.07 115.49,61.18 v1(115.95,60.72)
  TOP w0.165: U12.T10 121.82,40.73 v6(122.15,41.05)
  IN1 w0.076: v1(115.95,60.72) 116.33,60.34 116.33,59.36 116.25,59.28 116.25,57.33 116.09,57.17 116.09,56.69
  IN1 w0.191: 116.09,56.69 116.09,55.49 116.97,54.61 116.97,50.86 118.78,49.05 118.78,48.69 118.14,48.05 118.14,47.78 118.33,47.59 118.6,47.59 119.37,48.36 119.64,48.36 119.83,48.17 119.83,47.9 119.06,47.13 119.06,46.87 119.25,46.68 119.52,46.68 119.69,46.85 119.96,46.85 120.15,46.66 120.15,46.39 119.98,46.22 119.98,45.95 120.17,45.76 120.44,45.76 120.55,45.87 120.82,45.87 121.01,45.68 121.01,45.41 120.43,44.84 120.43,44.57 120.62,44.38 120.89,44.38 121.46,44.95 121.73,44.95 121.92,44.76 121.92,44.5 121.55,44.12 121.55,43.85 121.74,43.66 122,43.66 122.38,44.04 122.65,44.04 123,43.69 123,42.23 122.58,41.81 122.58,41.49 v6(122.15,41.05)
MB_DQ3: length 35.2
  TOP w0.076: 115.49,60.2 115.49,60.66 115.32,60.83 115.32,64.31 115.61,64.6 U6.AW29
  TOP w0.165: 115.49,60.2 115.49,59.82 v1(115.85,59.46) ; v6(122.15,41.85) 121.82,41.53 U12.T11
  IN1 w0.076: v1(115.85,59.46) 116.08,59.23 116.08,57.4 115.8,57.11
  IN1 w0.191: 115.8,57.11 115.8,55.14 116.42,54.52 116.42,50.3 116.63,50.1 117.14,50.1 117.3,49.93 117.3,49.7 117.14,49.53 116.63,49.53 116.42,49.33 116.42,48.91 116.72,48.61 116.99,48.61 117.67,49.3 117.94,49.3 118.13,49.11 118.13,48.84 117.45,48.16 117.45,47.89 117.58,47.76 117.58,47.49 117.19,47.1 117.19,46.83 117.38,46.64 117.65,46.64 118.03,47.03 118.3,47.03 118.49,46.84 118.49,46.57 118.11,46.18 118.11,45.92 118.3,45.73 118.56,45.73 118.95,46.11 119.22,46.11 119.93,45.4 119.93,44.77 119.73,44.57 119.73,44.34 120.04,44.03 120.29,44.03 120.49,43.83 120.49,43.3 120.69,43.1 120.97,43.1 121.17,43.3 121.48,43.3 121.68,43.1 121.99,43.1 122.17,43.28 122.46,43.28 122.58,43.15 122.58,42.47 122.15,42.03 v6(122.15,41.85)
MB_DQ4: length 36.9
  TOP w0.076: v1(117.8,63.22) 117.42,63.6 117.42,64.29 117.42,64.29 117.39,64.34 117.34,64.45 117.34,65.1 U6.AV31
  TOP w0.165: v6(121.5,38.65) 121.17,38.98 U12.R8
  IN1 w0.076: 119.95,54.13 119.95,54.63 118.08,56.5 118.08,58.9 118.26,59.08 118.26,61.47 118.52,61.73 118.52,62.5 v1(117.8,63.22)
  IN1 w0.191: v6(121.5,38.65) 122.37,37.78 124.24,37.78 126.85,40.39 126.85,47.23 119.95,54.13
MB_DQ5: length 37.2
  TOP w0.076: U6.AU31 116.2,66.14 115.99,65.93 115.99,65.69 116.03,65.65 116.03,65.32 115.99,65.28 115.99,65.1 116.07,64.94 116.07,64.71 116.04,64.68 115.99,64.58 115.99,64.45 116.04,64.34 116.07,64.29 116.07,63.3 v1(116.12,63.25)
  TOP w0.165: U12.T9 121.82,39.78 v6(122.15,39.45)
  IN1 w0.076: 117.42,59.07 117.42,59.33 117.75,59.66 117.75,60.66 117.45,60.96 117.45,61.77 116.89,62.33 116.89,62.47 v1(116.12,63.25)
  IN1 w0.191: 117.42,59.07 117.42,56.18 118.85,54.76 118.85,53.04 120.66,51.23 120.66,50.6 120.81,50.45 121,50.45 121.28,50.73 121.49,50.73 121.71,50.52 121.71,50.25 121.53,50.07 121.53,49.73 121.72,49.54 121.99,49.54 122.04,49.58 122.3,49.58 122.49,49.39 122.49,49.13 122.45,49.08 122.45,48.81 122.64,48.62 122.91,48.62 122.95,48.67 123.22,48.67 123.41,48.48 123.41,48.21 123.36,48.16 123.36,47.89 123.55,47.7 123.82,47.7 123.87,47.75 124.14,47.75 124.33,47.56 124.33,47.29 124.28,47.25 124.28,46.98 125.6,45.66 125.6,40.95 124.1,39.45 v6(122.15,39.45)
MB_DQ6: length 36
  TOP w0.076: v1(115.99,61.99) 115.67,62.31 115.67,63.83 115.9,64.06 115.9,64.25 115.85,64.36 115.83,64.38 115.83,64.4 115.83,64.41 115.83,64.61 115.83,64.62 115.83,64.65 115.85,64.67 115.9,64.76 115.9,64.77 115.9,64.9 115.85,65.01 115.72,65.14 U6.AV29
  TOP w0.165: v6(121.52,41.05) 121.17,40.7 U12.R10
  IN1 w0.076: v1(115.99,61.99) 116.5,61.99 116.63,61.85 116.63,59.43 116.41,59.21 116.41,57.18 116.38,57.15
  IN1 w0.191: 116.38,57.15 116.38,55.8 117.4,54.79 117.4,51.19 120.95,47.64 120.95,47.37 120.57,46.98 120.57,46.72 120.76,46.53 121.02,46.53 121.41,46.91 121.68,46.91 121.87,46.72 121.87,46.45 121.48,46.07 121.48,45.8 121.67,45.61 121.94,45.61 122.32,45.99 122.59,45.99 122.78,45.8 122.78,45.54 122.4,45.15 122.4,44.88 122.59,44.69 122.86,44.69 123.24,45.08 123.51,45.08 123.81,44.78 123.81,44.02 123.43,43.64 123.43,42.33 123.8,41.96 123.8,41.46 123.64,41.3 122.98,41.3 122.3,40.62 121.86,40.62 121.52,40.96 v6(121.52,41.05)
MB_DQ7: length 38
  TOP w0.076: U6.AU29 115.72,65.9 115.42,65.61 115.42,65.37 115.44,65.35 115.44,65.08 115.32,64.96 115.32,64.54 115.15,64.38 115.15,60.55
  TOP w0.165: v6(121.49,41.85) 121.17,41.53 U12.R11 ; v1(115.69,57.63) 115.69,58.73 115.15,59.27 115.15,60.55
  IN1 w0.191: v6(121.49,41.85) 121.49,42.07 121.31,42.25 120.13,42.25 120.02,42.37 120.02,42.47 120.19,42.65 120.19,42.9 119.99,43.1 119.36,43.1 119.16,43.31 119.16,43.76 118.87,44.05 118.87,44.32 119.51,44.96 119.51,45.23 119.32,45.42 119.05,45.42 118.4,44.77 118.16,44.77 117.54,45.38 117.54,45.88 117.34,46.09 116.83,46.09 116.4,46.52 115.87,46.52 115.69,46.69 115.69,47.04 115.9,47.24 116.74,47.24 116.91,47.41 116.91,47.65 116.74,47.82 114.85,47.82 114.68,47.98 114.68,48.22 114.85,48.39 115.85,48.39 116.02,48.55 116.02,48.79 115.85,48.96 114.92,48.96 114.76,49.13 114.76,49.36 114.92,49.53 115.7,49.53 115.9,49.73 115.9,54.41 115.51,54.8 115.51,57.45 v1(115.69,57.63)
MB_DQ8: length 32.4
  TOP w0.076: v1(113.82,59.69) 114.21,60.08 114.21,61.12 114.62,61.53 114.62,62.88 114.66,62.92 114.66,64.06 U6.AY27
  TOP w0.165: v6(113.1,41.85) 113.37,41.58 U12.C11
  IN3 w0.152: v1(113.82,59.69) 113.95,59.69 114.55,59.08 114.55,53.2 115.77,51.98 115.77,46.79 115.64,46.66 114.89,46.66 114.76,46.52 114.76,46.33 114.89,46.2 115.64,46.2 115.77,46.07 115.77,45.88 115.64,45.74 114.89,45.74 114.76,45.61 114.76,45.42 114.89,45.29 115.64,45.29 115.77,45.15 115.77,44.96 115.64,44.83 114.89,44.83 114.76,44.7 114.76,44.51 114.89,44.37 115.64,44.37 115.77,44.24 115.77,43.46 115.6,43.28 115.39,43.28 115.21,43.46 115.21,43.61 115.09,43.74 114.68,43.74 114.5,43.56 114.5,42.6 113.96,42.06 113.96,41.82 113.75,41.61 113.34,41.61 v6(113.1,41.85)
MB_DQ9: length 33.6
  TOP w0.076: U6.AW27 114.71,64.84 114.82,64.72 114.82,62.83 114.8,62.8 114.8,61.4 114.42,61.03 114.42,61
  TOP w0.165: v6(112.4,41.85) 112.72,41.53 U12.B11 ; v1(113.84,59.06) 114.03,59.06 114.42,59.46 114.42,61
  IN3 w0.152: v6(112.4,41.85) 112.86,42.32 113.59,42.32 114.07,42.8 114.07,43.79 114.17,43.89 114.17,47.13 114.31,47.26 115.26,47.26 115.39,47.39 115.39,47.58 115.26,47.72 114.31,47.72 114.17,47.85 114.17,48.04 114.31,48.17 115.26,48.17 115.39,48.31 115.39,48.5 115.26,48.63 114.31,48.63 114.17,48.77 114.17,48.95 114.31,49.09 115.26,49.09 115.39,49.22 115.39,49.41 115.26,49.55 114.31,49.55 114.17,49.68 114.17,49.87 114.31,50 115.26,50 115.39,50.14 115.39,51.82 114.17,53.04 114.17,56.39 114.29,56.5 114.29,58.62 v1(113.84,59.06)
MB_DQ10: length 32.3
  TOP w0.076: v1(112.28,60.19) 113.09,60.99 113.09,63.12 113.31,63.34 113.31,64.06 U6.AY25
  TOP w0.165: v6(113.04,39.45) 113.37,39.78 U12.C9
  IN3 w0.152: v6(113.04,39.45) 112.63,39.04 112.24,39.04 111.61,38.4 110.24,38.4 110.04,38.61 110.04,39.37 109.3,40.12 109.3,46.22 110.9,47.83 110.9,52.58 111.61,53.3 111.61,53.93 110.95,54.59 110.95,56.53 111.78,57.36 111.78,59.81 112.15,60.19 v1(112.28,60.19)
MB_DQ11: length 33.6
  TOP w0.076: U6.AW25 113.18,64.82 112.98,64.63 112.98,64.62 112.97,64.61 112.97,64.44 112.96,64.41 112.89,64.26 112.89,64.25 112.89,64.06 113.14,63.81 113.14,63.4 112.9,63.17 112.9,61.45 v1(112.28,60.83)
  TOP w0.165: U12.B8 112.72,38.98 v6(112.39,38.65)
  IN3 w0.152: v6(112.39,38.65) 111.74,38 109.45,38 109.25,38.21 109.25,38.38 109.66,38.79 109.66,39.21 109.4,39.47 109.07,39.47 108.92,39.62 108.92,46.38 110.52,47.98 110.52,56.64 111.44,57.56 111.44,60.48 111.78,60.83 v1(112.28,60.83)
MB_DQ12: length 34.5
  TOP w0.076: 114.78,61.04 114.99,61.24 114.99,64.79 114.64,65.14 114.64,65.27 U6.AV27
  TOP w0.165: v1(113.61,57.78) 113.8,57.78 114.78,58.77 114.78,61.04 ; U12.B10 112.72,40.73 v6(112.4,41.05)
  IN3 w0.152: v6(112.4,41.05) 112.01,41.43 112.01,42.95 112.36,43.3 112.55,43.3 112.73,43.12 112.92,43.12 113.05,43.25 113.05,43.44 112.88,43.62 112.88,43.81 113.01,43.95 113.2,43.95 113.38,43.76 113.57,43.76 113.71,43.9 113.71,44.09 113.52,44.27 113.52,44.46 113.79,44.73 113.79,48.52 113.66,48.66 113.44,48.66 113.31,48.79 113.31,48.98 113.44,49.11 113.66,49.11 113.79,49.25 113.79,49.44 113.66,49.57 113.44,49.57 113.31,49.7 113.31,49.89 113.44,50.03 113.66,50.03 113.79,50.16 113.79,50.38 113.93,50.52 114.88,50.52 115.01,50.65 115.01,50.84 114.88,50.98 113.52,50.98 113.39,51.11 113.39,51.3 113.52,51.43 114.78,51.43 114.91,51.57 114.91,51.76 114.78,51.89 113.93,51.89 113.79,52.02 113.79,57.61 v1(113.61,57.78)
MB_DQ13: length 35.1
  TOP w0.076: v1(113.82,60.33) 113.42,60.73 113.42,62.93 113.64,63.15 113.64,64.29 113.56,64.45 113.56,64.58 113.64,64.73 113.64,64.94 113.61,64.99 113.57,65.07 113.56,65.09 113.56,65.93 113.77,66.14 U6.AU27
  TOP w0.165: U12.C10 113.37,40.73 v6(113.05,41.05)
  IN3 w0.076: 113.39,57.15 113.39,57.34 113.2,57.53 113.2,58.01 113.37,58.19 113.37,59.88 v1(113.82,60.33)
  IN3 w0.152: v6(113.05,41.05) 112.61,40.62 112.26,40.62 111.63,41.25 111.63,43.68 111.77,43.81 112.38,43.81 112.52,43.95 112.52,44.14 112.38,44.27 111.77,44.27 111.63,44.4 111.63,44.59 111.77,44.73 113.25,44.73 113.38,44.86 113.38,45.05 113.25,45.18 111.84,45.18 111.71,45.32 111.71,45.51 111.84,45.64 113.23,45.64 113.39,45.8 113.39,48.01 112.93,48.46 112.93,51.85 113.39,52.31 113.39,57.15
MB_DQ14: length 34.8
  TOP w0.076: 113.25,60.2 113.25,63.05 113.47,63.27 113.47,64.25 113.42,64.36 113.4,64.41 113.4,64.61 113.42,64.67 113.46,64.76 113.47,64.77 113.47,64.9 113.45,64.95 113.42,65.01 113.4,65.06 113.4,65.38 113.29,65.49 U6.AV25
  TOP w0.165: v1(112.28,58.88) 113.25,59.85 113.25,60.2 ; v6(112.39,39.45) 112.72,39.78 U12.B9
  IN3 w0.152: v1(112.28,58.88) 112.28,57.04 111.99,56.74 111.99,56.16 111.85,56.02 111.46,56.02 111.33,55.89 111.33,55.7 111.46,55.56 111.85,55.56 111.99,55.43 111.99,55.24 111.85,55.11 111.46,55.11 111.33,54.97 111.33,54.78 111.46,54.65 111.85,54.65 111.99,54.52 111.99,52.96 111.28,52.25 111.28,51.69 111.46,51.51 111.46,51.23 111.28,51.05 111.28,50.77 111.46,50.59 111.46,50.31 111.28,50.14 111.28,49.86 111.46,49.68 111.46,49.4 111.28,49.22 111.28,48.01 111.56,47.73 111.56,47.4 111.37,47.21 110.82,47.21 109.68,46.07 109.68,44.55 110.03,44.2 110.03,43.89 109.68,43.54 109.68,41.96 109.88,41.75 109.88,41.47 109.68,41.27 109.68,40.28 110.49,39.47 110.49,39.01 110.69,38.81 111.45,38.81 111.71,39.07 111.76,39.07 112.14,39.45 v6(112.39,39.45)
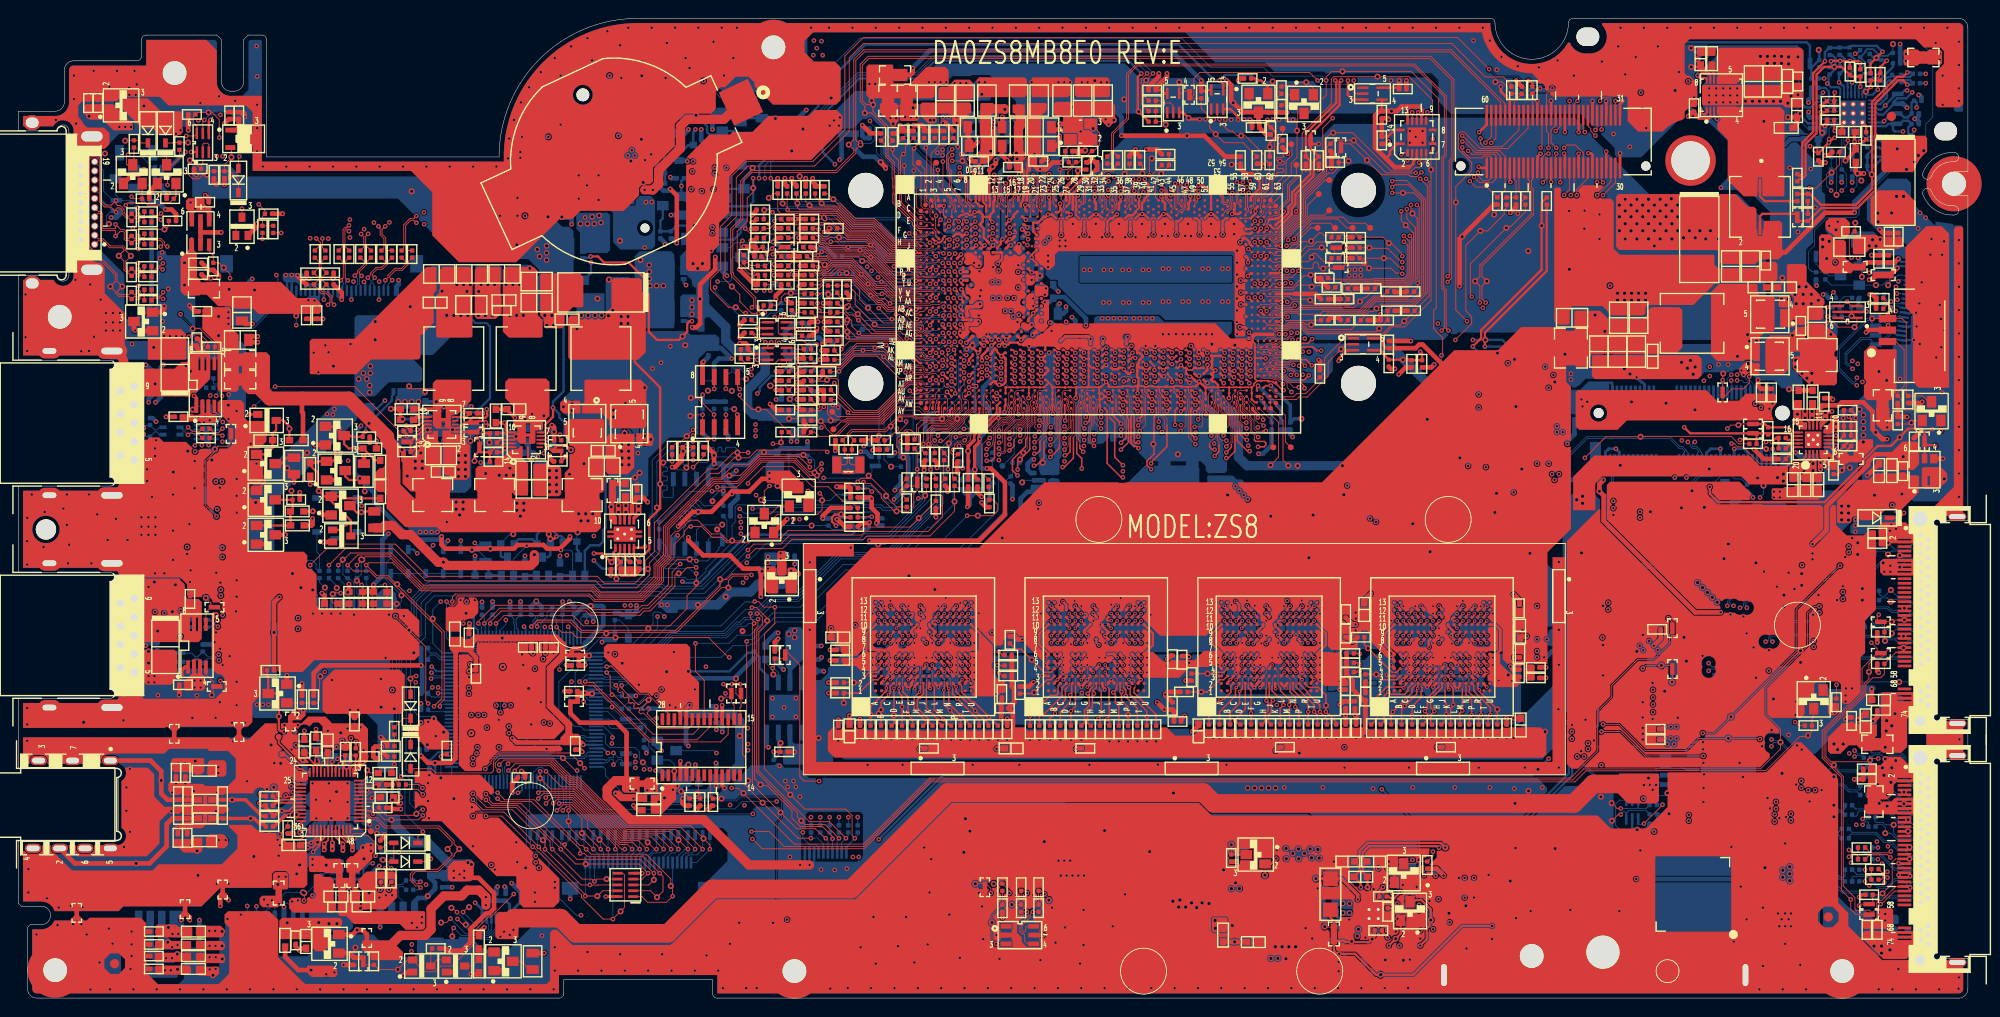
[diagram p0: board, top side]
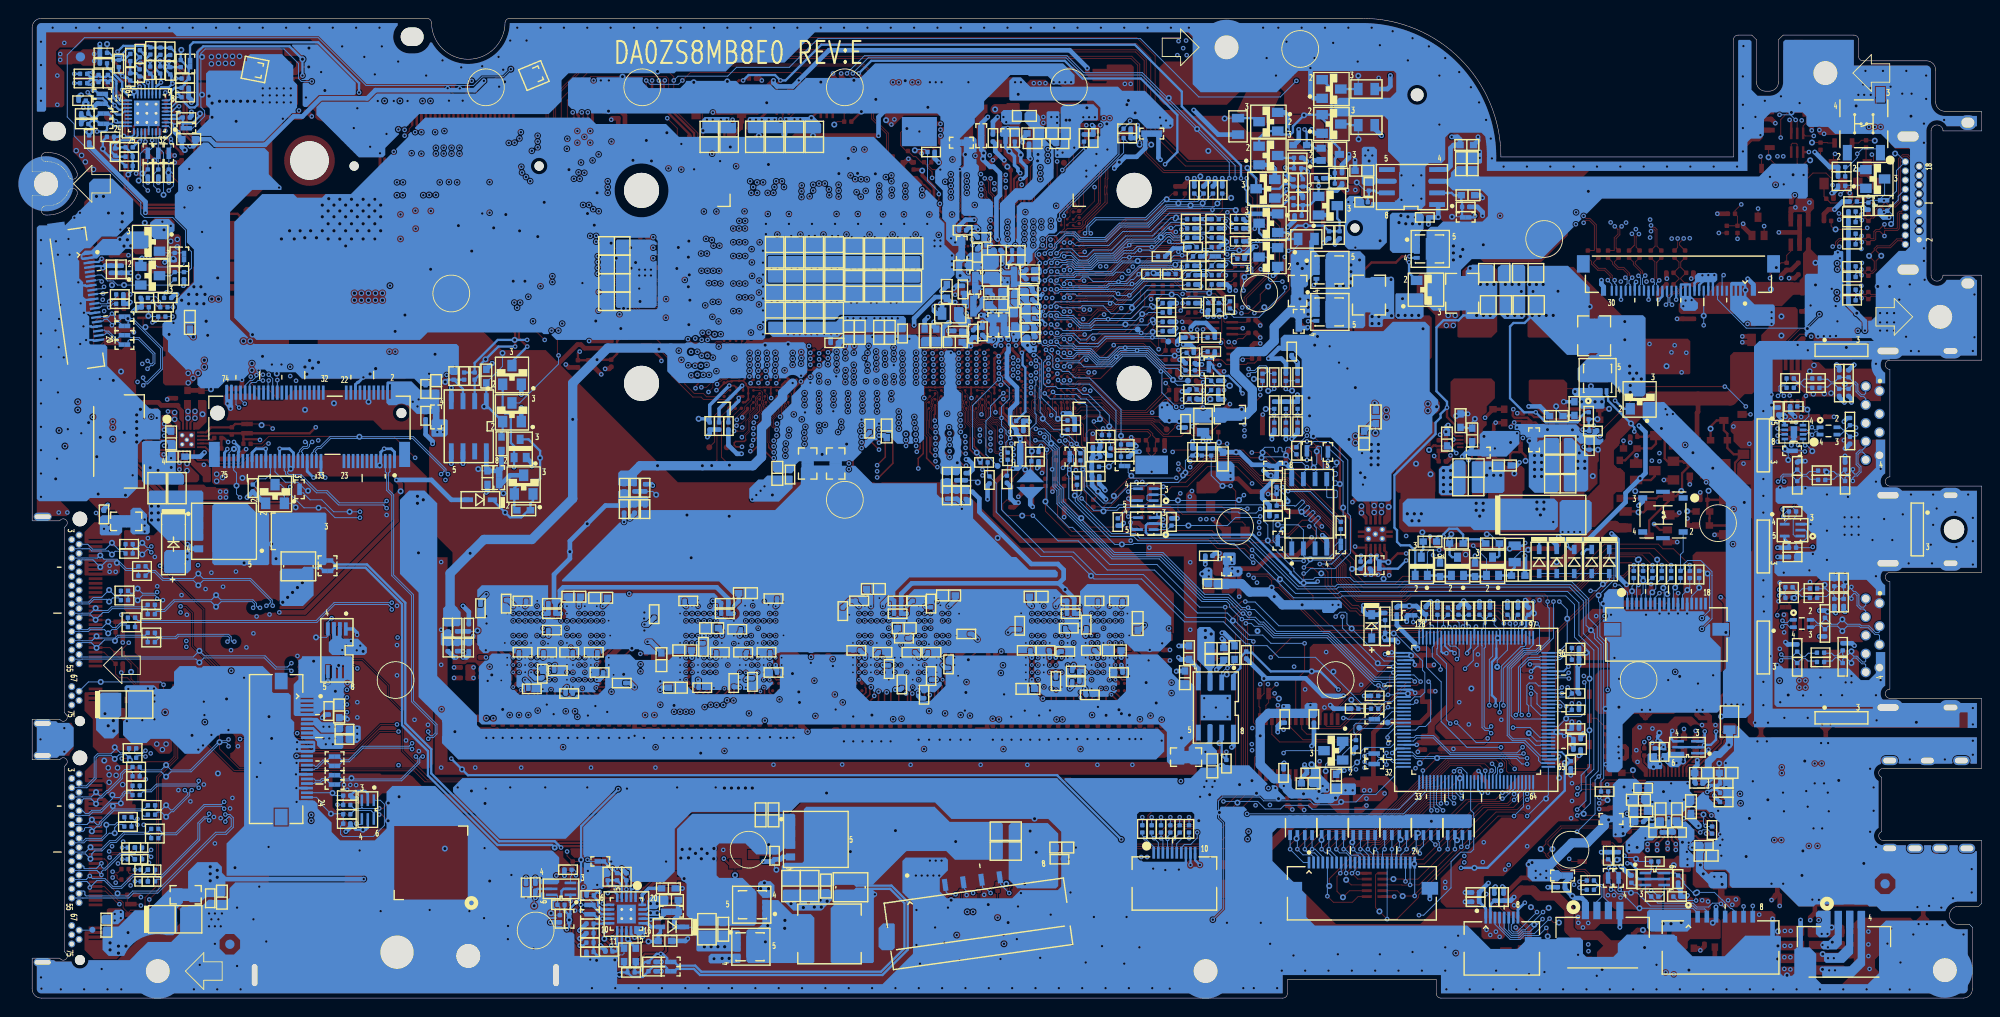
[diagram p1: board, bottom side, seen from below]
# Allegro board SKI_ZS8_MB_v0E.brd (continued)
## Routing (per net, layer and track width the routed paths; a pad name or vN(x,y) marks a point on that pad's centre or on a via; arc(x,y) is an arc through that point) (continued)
MB_DQ15: length 35.7
  TOP w0.076: v1(112.34,62.13) 112.7,62.49 112.7,63.2 112.97,63.47 112.97,63.74 112.86,63.85 112.86,63.85 112.72,63.99 112.72,64.29 112.75,64.34 112.75,64.34 112.8,64.45 112.8,64.91 112.82,64.93 112.82,65.77 U6.AU25
  TOP w0.165: U12.C8 113.37,38.98 v6(113.04,38.65)
  IN3 w0.152: v1(112.34,62.13) 111.09,60.88 111.09,57.75 110.13,56.79 110.13,48.14 108.53,46.54 108.53,38.38 109.3,37.62 112.01,37.62 v6(113.04,38.65)
MB_DQ16: length 39.2
  TOP w0.165: U12.D9 114.02,39.77 v6(113.7,39.45) ; U6.AM29 115.61,69.25 v1(115.94,68.92)
  IN1 w0.191: v6(113.7,39.45) 113.7,39.24 113.89,39.05 116.7,39.05 118.14,40.49 118.14,43.35 115.98,45.5 115.39,45.5 114.57,46.33 114.2,46.33 113.84,46.69 113.84,47.06 113.67,47.23 113.67,50.01 113.92,50.26 114.21,50.26 114.82,50.87 114.82,57.92 115.01,58.12 115.01,63.35 116.67,65 116.67,68.69 116.43,68.92 v1(115.94,68.92)
MB_DQ17: length 40.2
  TOP w0.165: U6.AK29 115.62,70.55 v1(115.93,70.24) ; v6(115.04,38.62) 115.32,38.9 U12.F8
  IN1 w0.191: v1(115.93,70.24) 116.74,70.24 116.95,70.03 116.95,64.73 115.4,63.18 115.4,57.98 115.21,57.79 115.21,54.61 115.24,54.58 115.24,50.33 115.04,50.13 114.68,50.13 114.08,49.54 114.08,47.46 114.33,47.22 114.83,47.22 115.06,46.98 115.06,46.48 115.62,45.92 116.16,45.92 118.48,43.6 118.48,40.27 116.94,38.73 116.94,38.73 116.46,38.25 115.42,38.25 v6(115.04,38.62)
MB_DQ18: length 39.9
  TOP w0.165: v1(114.99,69.57) 114.92,69.57 U6.AL28 ; v6(114.99,41.05) 114.99,40.97 U12.E10
  IN1 w0.076: 111.93,58.43 111.93,58.64 111.89,58.67 111.89,62.33 112.15,62.59 112.15,64.53 113.86,66.25 113.98,66.25 114.43,66.7 114.43,69.01 114.63,69.22 v1(114.99,69.57)
  IN1 w0.191: v6(114.99,41.05) 114.59,41.45 113.94,41.45 113.72,41.22 113.72,40.41 113.6,40.3 112.38,40.3 112.14,40.54 111.7,40.54 111.46,40.3 110.03,40.3 108.81,41.51 108.81,50.6 111,52.78 111.14,52.78 111.52,53.16 111.52,55.31 111.93,55.71 111.93,58.43
MB_DQ19: length 41.2
  TOP w0.165: U12.F10 115.32,40.57 v6(115,40.25) ; U6.AK28 114.66,70.55 v1(115,70.21)
  IN1 w0.076: 113.56,69.01 113.67,69.11 113.67,70.26 113.99,70.59 114.62,70.59 v1(115,70.21)
  IN1 w0.191: v6(115,40.25) 114.52,39.78 114.25,39.78 114.15,39.88 109.86,39.88 108.39,41.34 108.39,50.77 110.48,52.86 110.48,54.86 111.54,55.91 111.54,62.53 111.74,62.74 111.74,64.59 113.56,66.41 113.56,69.01
MB_DQ20: length 37.5
  TOP w0.165: v1(115.94,66.97) 115.61,67.3 U6.AR29 ; v6(115,39.45) 114.67,39.78 U12.E9
  IN1 w0.191: v6(115,39.45) 116.04,40.49 116.99,40.49 117.35,40.85 117.35,42.95 115.63,44.67 115.04,44.67 114.41,45.3 112.57,45.3 111.96,45.9 111.96,46.66 112.36,47.05 112.36,47.28 111.96,47.68 111.96,47.82 112.15,48.01 112.66,48.01 112.83,48.17 112.83,48.41 112.66,48.58 112.02,48.58 111.85,48.74 111.85,48.98 112.02,49.15 112.56,49.15 112.76,49.35 112.76,50.29 113.98,51.51 113.98,57.24 114.12,57.38 114.12,58.02 114.35,58.25 114.35,63.7 115.1,64.45 115.1,64.71 115.94,65.54 v1(115.94,66.97)
MB_DQ21: length 38.4
  TOP w0.165: U12.F9 115.32,39.78 v6(115.65,39.45) ; U6.AN29 115.61,68.6 v1(115.94,68.27)
  IN1 w0.191: v6(115.65,39.45) 115.65,39.69 116.16,40.2 116.52,40.2 116.79,39.93 117.16,39.93 117.75,40.51 117.75,43.15 115.81,45.08 115.22,45.08 114.39,45.91 112.55,45.91 112.38,46.08 112.38,46.31 112.55,46.48 113.1,46.48 113.26,46.65 113.26,46.89 113.1,47.05 112.94,47.05 112.78,47.22 112.78,47.46 112.94,47.62 113.04,47.62 113.25,47.83 113.25,50.18 113.75,50.68 114.01,50.68 114.4,51.07 114.4,57.9 114.73,58.23 114.73,63.65 116.39,65.31 116.39,68.07 116.19,68.27 v1(115.94,68.27)
MB_DQ22: length 37.8
  TOP w0.165: v1(114.99,66.97) 114.92,66.97 U6.AR28 ; v6(115,41.85) U12.F11
  IN1 w0.076: 112.7,58.19 112.97,58.46 112.97,62.95 113.74,63.71 113.74,64.26 114.09,64.61 114.09,65.64 114.99,66.53 v1(114.99,66.97)
  IN1 w0.191: v6(115,41.85) 115,42 114.27,42.72 114.27,43.09 113.7,43.66 113.49,43.66 112.95,43.13 112.28,43.13 111.44,42.29 110.83,42.29 110.63,42.09 110.63,41.45 110.46,41.29 110.23,41.29 110.06,41.45 110.06,42.59 109.65,43 109.65,44.32 110.11,44.77 110.11,45.16 109.65,45.62 109.65,47.71 109.84,47.9 110.1,47.9 110.29,48.09 110.29,48.36 110.1,48.55 109.84,48.55 109.65,48.73 109.65,49 109.84,49.19 110.1,49.19 110.29,49.38 110.29,50.88 111.35,51.94 111.59,51.94 112.37,52.72 112.37,55.11 112.52,55.26 112.52,58.01 112.7,58.19
MB_DQ23: length 37.5
  TOP w0.165: U6.AP28 114.92,67.62 v1(114.99,67.62) ; v6(114.35,41.85) 114.67,41.53 U12.E11
  IN1 w0.076: 112.45,58.37 112.75,58.67 112.75,63.22 113.11,63.58 113.11,64.72 113.59,65.2 113.59,65.53 114.59,66.54 114.59,67.42 114.8,67.62 v1(114.99,67.62)
  IN1 w0.191: v6(114.35,41.85) 114.35,42.05 114.14,42.25 112.04,42.25 111.85,42.06 111.85,41.73 112.01,41.57 112.01,41.3 111.76,41.05 111.52,41.05 111.24,40.77 110.15,40.77 109.23,41.69 109.23,41.83 109.59,42.2 109.59,42.46 109.23,42.82 109.23,44.49 109.54,44.8 109.54,45.1 109.23,45.4 109.23,49.18 109.54,49.48 109.54,49.8 109.23,50.1 109.23,50.42 111.18,52.36 111.42,52.36 111.94,52.88 111.94,55.17 112.22,55.45 112.22,58.14 112.45,58.37
MB_DQ24: length 44.6
  TOP w0.165: U12.N9 119.87,39.78 v6(119.54,39.45) ; U6.AN26 113.97,68.27 v1(114.03,68.27)
  IN3 w0.076: 116.86,65.94 116.54,66.25 114.67,66.25 114.43,66.49 114.43,68.04 114.2,68.27 v1(114.03,68.27)
  IN3 w0.152: v6(119.54,39.45) 119.89,39.8 120.14,39.8 120.31,39.63 120.31,39.39 119.74,38.81 119.74,38.48 119.96,38.25 122.94,38.25 123.95,39.27 123.95,49.59 123.68,49.86 123.49,49.86 123.25,49.62 123.06,49.62 122.92,49.75 122.92,49.94 123.17,50.18 123.17,50.37 123.04,50.51 122.85,50.51 122.6,50.26 122.41,50.26 122.28,50.4 122.28,50.59 122.52,50.83 122.52,51.02 119.29,54.25 118.69,54.25 118.55,54.4 118.55,64.24 116.86,65.94
MB_DQ25: length 43
  TOP w0.165: U12.P9 120.52,39.78 v6(120.85,39.45) ; v1(114.03,66.97) 113.97,66.97 U6.AR26
  IN3 w0.152: v1(114.03,66.97) 114.03,66.41 114.69,65.75 115.34,65.75 115.67,65.43 116.94,65.43 118.29,64.08 118.29,61.59 118.15,61.45 118.15,53.99 118.53,53.6 118.72,53.6 118.97,53.85 119.16,53.85 119.29,53.71 119.29,53.52 119.05,53.28 119.05,53.09 119.18,52.96 119.37,52.96 119.61,53.2 119.8,53.2 119.94,53.07 119.94,52.88 119.69,52.63 119.69,52.44 119.83,52.31 120.02,52.31 120.26,52.55 120.45,52.55 120.58,52.42 120.58,52.23 120.34,51.99 120.34,51.8 120.47,51.66 120.66,51.66 120.91,51.91 121.1,51.91 121.23,51.77 121.23,51.58 120.99,51.34 120.99,51.15 121.12,51.02 121.31,51.02 121.55,51.26 121.74,51.26 121.88,51.13 121.88,50.94 121.63,50.69 121.63,50.5 122.9,49.24 123.41,49.24 123.57,49.07 123.57,47.35 123.37,47.15 123.37,46.9 123.57,46.69 123.57,46.44 123.37,46.24 123.37,45.98 123.57,45.78 123.57,45.53 123.37,45.32 123.37,45.07 123.57,44.87 123.57,44.61 123.37,44.41 123.37,44.15 123.57,43.95 123.57,43.7 123.37,43.49 123.37,43.24 123.57,43.04 123.57,42.78 123.37,42.58 123.37,42.33 123.57,42.12 123.57,40.46 123.27,40.16 123.27,39.93 123.57,39.62 123.57,39.43 123.18,39.04 121.26,39.04 v6(120.85,39.45)
MB_DQ26: length 42.6
  TOP w0.165: v1(113.08,66.97) 113.02,66.97 U6.AR25 ; v6(120.19,41.05) 119.87,40.73 U12.N10
  IN3 w0.152: v1(113.08,66.97) 113.08,66.12 115.09,64.11 116.05,64.11 116.61,63.55 116.61,62.43 116.54,62.36 116.54,59.77 116.61,59.69 116.61,53.55 121.23,48.93 121.23,48.74 121.1,48.6 120.15,48.6 120.02,48.47 120.02,48.28 120.15,48.15 121.84,48.15 121.97,48.01 121.97,47.82 121.84,47.69 119.11,47.69 118.97,47.55 118.97,47.36 119.11,47.23 119.75,47.23 119.88,47.1 119.88,46.91 119.75,46.77 119.11,46.77 118.97,46.64 118.97,46.45 119.11,46.32 119.6,46.32 119.74,46.18 119.74,45.99 119.6,45.86 119.11,45.86 118.97,45.73 118.97,45.54 119.11,45.4 120.09,45.4 120.23,45.27 120.23,45.08 120.09,44.95 119.11,44.95 118.97,44.81 118.97,44.62 119.11,44.49 119.6,44.49 119.74,44.35 119.74,44.3 120.42,43.61 120.42,41.5 120.19,41.28 v6(120.19,41.05)
MB_DQ27: length 43.8
  TOP w0.076: U6.AP25 112.76,67.95 v1(113.08,67.62)
  TOP w0.165: U12.M10 119.22,40.73 v6(119.54,41.05)
  IN3 w0.076: 112.95,65.61 112.69,65.87 112.69,67.23 v1(113.08,67.62)
  IN3 w0.152: v6(119.54,41.05) 119.77,41.27 119.77,41.47 119.97,41.68 119.97,42.82 118.92,43.87 117.91,43.87 117.78,44.01 117.78,44.2 117.91,44.33 118.46,44.33 118.59,44.46 118.59,44.65 118.46,44.79 117.91,44.79 117.78,44.92 117.78,45.11 117.91,45.24 118.46,45.24 118.59,45.38 118.59,45.57 118.46,45.7 117.91,45.7 117.78,45.84 117.78,46.02 117.91,46.16 118.46,46.16 118.59,46.29 118.59,46.48 118.46,46.62 117.91,46.62 117.78,46.75 117.78,46.94 117.91,47.07 118.46,47.07 118.59,47.21 118.59,47.4 118.46,47.53 117.91,47.53 117.78,47.66 117.78,47.85 117.91,47.99 118.87,47.99 119.01,48.12 119.01,48.31 118.87,48.44 117.91,48.44 117.78,48.58 117.78,48.77 117.91,48.9 119.91,48.9 120.05,49.04 120.05,49.23 119.91,49.36 118.7,49.36 118.57,49.49 118.57,49.68 118.7,49.82 119.28,49.82 119.43,49.97 119.43,50.19 116.15,53.47 116.15,57.96 115.28,58.84 115.28,60.05 115.23,60.1 115.23,63.33 112.95,65.61
MB_DQ28: length 46.5
  TOP w0.165: U6.AK26 113.76,70.55 v1(114.13,70.17) ; v6(118.9,38.65) 119.22,38.97 U12.M8
  IN3 w0.076: v1(114.13,70.17) 114.37,70.17 114.86,70.66 116.06,70.66 116.51,70.21 116.51,67.26 117.19,66.58 118.24,66.58
  IN3 w0.152: v6(118.9,38.65) 118.9,38.24 119.67,37.47 123.23,37.47 124.71,38.95 124.71,49.91 120.19,54.43 120.19,56.03 119.66,56.56 119.66,59.03 119.33,59.36 119.33,64.39 119.13,64.59 119.13,65.93 118.48,66.58 118.24,66.58
MB_DQ29: length 45.9
  TOP w0.165: U12.M9 119.22,39.75 v6(118.89,39.42) ; v1(114.03,68.92) 113.97,68.92 U6.AM26
  IN3 w0.076: v1(114.03,68.92) 114.36,69.25 114.47,69.25 114.59,69.12 114.59,66.71 114.89,66.41 116.72,66.41 116.97,66.17
  IN3 w0.152: 116.97,66.17 118.95,64.19 118.95,58.07 119.08,57.94 119.14,57.94 119.28,57.8 119.28,57.61 119.14,57.48 119.08,57.48 118.95,57.34 118.95,57.15 119.08,57.02 119.14,57.02 119.28,56.89 119.28,56.7 119.14,56.56 119.08,56.56 118.95,56.43 118.95,56.24 119.08,56.11 119.58,56.11 119.71,55.97 119.71,55.78 119.58,55.65 119.08,55.65 118.95,55.52 118.95,55.13 124.33,49.75 124.33,39.11 123.07,37.85 119.83,37.85 119.35,38.32 119.35,38.96 v6(118.89,39.42)
MB_DQ30: length 45.7
  TOP w0.165: U6.AK25 112.79,70.55 v1(113.17,70.17) ; v6(118.89,41.85) 119.22,41.53 U12.M11
  IN3 w0.076: v1(113.17,70.17) 112.75,69.75 112.75,69.38 112.26,68.89 112.26,68.61
  IN3 w0.152: 112.26,68.61 112.26,65.26 114.5,63.02 114.5,59.99 114.8,59.7 114.8,57.37 115.23,56.93 115.23,53.31 116.33,52.21 116.33,43.74 116.46,43.61 116.46,42.88 116.33,42.75 116.16,42.75 116.03,42.61 116.03,42.42 116.16,42.29 116.33,42.29 116.46,42.15 116.46,41.96 116.33,41.83 116.16,41.83 116.03,41.7 116.03,41.51 116.16,41.37 116.33,41.37 116.46,41.24 116.46,40.56 116.28,40.39 115.51,40.39 115.38,40.25 115.38,40.06 115.51,39.93 116.71,39.93 116.89,39.75 116.89,39 117.02,38.86 117.21,38.86 117.35,39 117.35,41.6 117.48,41.73 117.67,41.73 117.81,41.6 117.81,40.06 117.93,39.93 118.11,39.93 118.24,40.06 118.24,40.77 118.34,40.87 118.34,41.3 v6(118.89,41.85)
MB_DQ31: length 45.5
  TOP w0.165: U12.N11 119.87,41.53 v6(119.54,41.85) ; U6.AL25 113.04,69.55 v1(113.18,69.55)
  IN3 w0.076: 112.61,65.29 112.52,65.38 112.52,68.92 113.15,69.55 v1(113.18,69.55)
  IN3 w0.152: 112.61,65.29 114.76,63.14 114.76,60.13 115.04,59.85 115.04,57.53 115.7,56.87 115.7,53.38 117.4,51.68 117.4,51.36 117.58,51.18 117.9,51.18 118.04,51.04 118.04,50.84 117.9,50.69 116.9,50.69 116.76,50.56 116.76,50.37 116.9,50.24 118.13,50.24 118.26,50.1 118.26,49.91 118.13,49.78 116.9,49.78 116.76,49.65 116.76,49.46 116.9,49.32 117.26,49.32 117.4,49.19 117.4,49 117.26,48.86 116.9,48.86 116.76,48.73 116.76,48.54 116.9,48.41 117.26,48.41 117.4,48.27 117.4,48.08 117.26,47.95 116.9,47.95 116.76,47.82 116.76,47.63 116.9,47.49 117.26,47.49 117.4,47.36 117.4,47.17 117.26,47.04 116.9,47.04 116.76,46.9 116.76,46.71 116.9,46.58 117.26,46.58 117.4,46.44 117.4,46.26 117.26,46.12 116.9,46.12 116.76,45.99 116.76,45.8 116.9,45.66 117.26,45.66 117.4,45.53 117.4,45.34 117.26,45.21 116.9,45.21 116.76,45.07 116.76,44.88 116.9,44.75 117.26,44.75 117.4,44.62 117.4,44.43 117.26,44.29 116.9,44.29 116.76,44.16 116.76,43.97 116.9,43.84 117.26,43.84 117.4,43.7 117.4,43.32 117.53,43.19 118.28,43.19 118.41,43.05 118.41,42.86 118.28,42.73 117.55,42.73 117.37,42.55 117.37,42.29 117.55,42.11 118.44,42.11 118.64,42.32 119.13,42.32 119.54,41.9 v6(119.54,41.85)
MB_DQ32: length 33.4
  TOP w0.076: U6.AY23 111.82,64.18 111.82,62.65 111.51,62.34 111.51,61.35 110.68,60.51 v1(110.56,60.51)
  TOP w0.165: v6(102.69,38.65) 102.36,38.98 U11.R8
  IN1 w0.191: v1(110.56,60.51) 111.24,59.83 111.24,56.09 109.89,54.74 109.89,53.11 107.8,51.02 107.8,39.78 106.11,38.09 104.76,38.09 104.6,37.93 103.41,37.93 v6(102.69,38.65)
MB_DQ33: length 33
  TOP w0.076: U6.AW23 112.09,64.31 112.12,64.26 112.12,64.26 112.12,64.06 111.99,63.93 111.99,62.57 111.72,62.3 111.72,61.18 111.15,60.6
  TOP w0.165: U11.T8 103.01,38.98 v6(103.34,38.65) ; 111.15,60.6 111.15,59.61 110.78,59.25 v1(110.53,59.25)
  IN1 w0.191: v6(103.34,38.65) 103.74,38.24 104.29,38.24 104.59,38.54 105.96,38.54 107.38,39.97 107.38,51.19 109.47,53.28 109.47,54.88 110.95,56.36 110.95,59.05 110.75,59.25 v1(110.53,59.25)
MB_DQ34: length 33.7
  TOP w0.076: 109.77,61 109.77,62.08 110.37,62.68 110.37,63.89 110.48,64 U6.AY21
  TOP w0.165: U11.T10 103.01,40.73 v6(103.33,41.05) ; v1(108.7,56.88) 108.15,57.43 108.15,58.6 109.6,60.05 109.6,60.83 109.77,61
  IN1 w0.191: v1(108.7,56.88) 108.7,56.56 106.88,54.74 106.27,54.74 104.9,53.36 104.9,49.76 104.71,49.57 104.32,49.57 104.13,49.38 104.13,49.11 104.32,48.92 104.71,48.92 104.9,48.73 104.9,48.47 104.71,48.28 104.32,48.28 104.13,48.09 104.13,47.82 104.32,47.63 104.71,47.63 104.9,47.44 104.9,47.17 104.71,46.98 104.32,46.98 104.13,46.79 104.13,46.52 104.32,46.33 104.71,46.33 104.9,46.14 104.9,45.88 104.71,45.69 104.32,45.69 104.13,45.5 104.13,45.23 104.32,45.04 104.71,45.04 104.9,44.85 104.9,44.58 104.71,44.39 104.32,44.39 104.13,44.2 104.13,43.93 104.32,43.74 104.71,43.74 104.9,43.55 104.9,41.55 104.16,40.81 103.57,40.81 v6(103.33,41.05)
MB_DQ35: length 34
  TOP w0.076: U6.AW21 110.48,64.6 110.18,64.31 110.18,64.09 110.2,64.07 110.2,62.75 109.54,62.09 109.54,61.13 v1(108.99,60.58)
  TOP w0.165: U11.T11 103.01,41.53 v6(103.33,41.85)
  IN1 w0.191: v1(108.99,60.58) 108.99,58.43 107.65,57.09 107.65,56.68 106.57,55.61 104.15,55.61 103.18,54.65 103.18,54.14 102.76,53.71 102.76,51.67 103.3,51.14 103.3,50.62 102.53,49.85 102.53,49.58 102.72,49.39 103.11,49.39 103.3,49.21 103.3,48.94 103.11,48.75 102.72,48.75 102.53,48.56 102.53,48.29 102.72,48.1 103.11,48.1 103.3,47.91 103.3,47.64 103.11,47.45 102.72,47.45 102.53,47.26 102.53,46.99 102.72,46.8 103.11,46.8 103.3,46.61 103.3,46.35 103.11,46.16 102.72,46.16 102.53,45.97 102.53,45.7 102.72,45.51 103.11,45.51 103.3,45.32 103.3,45.05 103.11,44.86 102.72,44.86 102.53,44.67 102.53,44.4 102.72,44.21 103.11,44.21 103.3,44.02 103.3,43.49 103.78,43 103.78,42.42 103.33,41.97 v6(103.33,41.85)
MB_DQ36: length 34.3
  TOP w0.076: U6.AV23 112.19,65.12 112.19,64.72 112.21,64.6 112.21,64.45 112.24,64.38 112.26,64.35 112.29,64.32 112.29,63.97 112.15,63.84 112.15,62.5 111.89,62.23 111.89,60.83 111.58,60.53
  TOP w0.165: v1(110.49,57.95) 110.73,57.95 111.58,58.8 111.58,60.53 ; U11.R9 102.36,39.78 v6(102.69,39.45)
  IN1 w0.191: v1(110.49,57.95) 110.66,57.78 110.66,56.5 109.05,54.9 109.05,53.45 108.77,53.18 108.4,53.18 108.2,52.97 108.2,52.61 107.69,52.1 107.21,52.1 106.96,51.85 106.96,40.16 106.84,40.04 106.52,40.04 106.4,39.92 106.4,39.6 105.82,39.01 104.3,39.01 104.26,39.05 102.88,39.05 102.69,39.24 v6(102.69,39.45)
MB_DQ37: length 34.1
  TOP w0.076: v1(111.07,61.62) 110.57,62.12 110.57,62.33 110.7,62.46 110.7,63.74 110.94,63.98 110.94,64.27 110.91,64.34 110.86,64.45 110.86,64.58 110.91,64.68 110.93,64.71 110.93,64.94 110.91,64.99 110.86,65.1 110.86,65.28 110.9,65.32 110.9,65.65 110.86,65.69 110.86,65.93 111.06,66.14 U6.AU23
  TOP w0.165: v6(103.34,39.45) 103.01,39.78 U11.T9
  IN1 w0.076: v1(111.07,61.62) 110.76,61.93 110.46,61.93 110.09,61.55 110.09,57.45 110.13,57.4
  IN1 w0.191: 110.13,57.4 110.13,56.46 108.63,54.96 108.63,53.84 108.43,53.64 108.16,53.64 107.75,53.23 107.75,52.74 107.53,52.53 107.04,52.53 106.54,52.02 106.54,40.78 106.07,40.31 105.79,40.31 104.93,39.45 v6(103.34,39.45)
MB_DQ38: length 33.9
  TOP w0.076: U6.AV21 110.58,65.14 110.72,65.01 110.77,64.9 110.77,64.77 110.76,64.75 110.72,64.67 110.7,64.65 110.7,64.62 110.7,64.61 110.7,64.41 110.7,64.4 110.7,64.38 110.72,64.36 110.77,64.25 110.77,64.06 110.53,63.82 110.53,62.6 110.05,62.11 110.05,61
  TOP w0.165: U11.R10 102.36,40.7 v6(102.71,41.05) ; 110.05,61 110.05,59.68 v2(108.98,58.62) 108.71,58.35 v1(108.71,57.52)
  IN1 w0.191: v6(102.71,41.05) 102.71,41.28 102.88,41.45 103.6,41.45 103.78,41.63 103.78,41.76 104.2,42.18 104.2,43.18 103.71,43.67 103.71,50.14 103.9,50.33 104.29,50.33 104.48,50.52 104.48,50.79 104.29,50.98 103.9,50.98 103.71,51.17 103.71,51.44 103.9,51.63 104.29,51.63 104.48,51.82 104.48,52.09 104.29,52.28 103.9,52.28 103.71,52.47 103.71,52.73 103.9,52.92 104.29,52.92 104.48,53.11 104.48,53.38 104.29,53.57 103.9,53.57 103.71,53.76 103.71,54.57 104.33,55.19 106.74,55.19 108.08,56.52 108.08,56.89 108.7,57.52 v1(108.71,57.52)
MB_DQ39: length 33.7
  TOP w0.076: U6.AU21 110.58,65.9 110.29,65.61 110.29,65.37 110.31,65.35 110.31,65.08 110.09,64.86 110.09,64.45 110.02,64.38 110.02,64.03 110.04,64.01 110.04,62.84 109.07,61.87 v1(108.99,61.87)
  TOP w0.165: v6(102.68,41.85) 102.36,41.53 U11.R11
  IN1 w0.076: 108.51,59.08 108.51,61.6 108.78,61.87 v1(108.99,61.87)
  IN1 w0.191: 108.51,59.08 108.51,58.52 107.31,57.33 107.31,57.02 106.32,56.03 103.97,56.03 102.71,54.77 102.71,54.26 102.5,54.05 101.99,54.05 101.71,53.77 101.71,53.48 102.26,52.93 102.26,52.61 101.71,52.06 101.71,51.68 101.98,51.41 102.43,51.41 102.72,51.13 102.72,50.64 102.53,50.44 101.97,50.44 101.71,50.18 101.71,49.05 101.94,48.82 101.94,48.4 101.71,48.17 101.71,47.75 101.94,47.53 101.94,47.11 101.71,46.88 101.71,46.46 101.94,46.23 101.94,45.81 101.71,45.58 101.71,45.16 101.94,44.93 101.94,43.68 102.13,43.48 102.71,43.48 102.9,43.3 102.9,42.06 v6(102.68,41.85)
MB_DQ40: length 36.4
  TOP w0.076: v1(107.83,61.55) 107.83,61.74 108.68,62.6 109.08,62.6 109.54,63.06 109.54,63.84 109.52,63.86 109.52,64.06 U6.AY19
  TOP w0.165: v6(100.09,38.65) 100.41,38.97 U11.M8
  IN3 w0.152: v1(107.83,61.55) 108.56,60.82 108.56,58.76 108.27,58.48 108.27,55.71 108.69,55.3 108.69,48.67 107.14,47.12 107.14,39.04 105.56,37.46 100.71,37.46 100.09,38.09 v6(100.09,38.65)
MB_DQ41: length 36.9
  TOP w0.076: U6.AW19 109.69,64.54 109.69,63.92 109.71,63.9 109.71,62.99 109.15,62.43 108.75,62.43 108.29,61.97 108.29,61.35 v1(107.83,60.88)
  TOP w0.165: U11.M9 100.41,39.78 v6(100.08,39.45)
  IN3 w0.152: v1(107.83,60.88) 107.91,60.88 108.26,60.53 108.26,59.13 107.89,58.76 107.89,55.13 107.72,54.97 107.72,54.11 108.31,53.53 108.31,48.83 106.76,47.28 106.76,39.27 105.33,37.85 100.99,37.85 100.53,38.3 100.53,39 v6(100.08,39.45)
MB_DQ42: length 35.7
  TOP w0.076: U6.AY17 108.06,64.17 108.06,63.36 107.5,62.8 107.12,62.8 106.3,61.97 106.3,60.5 106.21,60.41
  TOP w0.165: U11.M10 100.41,40.73 v6(100.73,41.05) ; v1(105.35,58.48) 105.88,58.48 106.21,58.8 106.21,60.41
  IN3 w0.152: v1(105.35,58.48) 104.93,58.06 104.93,56.36 105.31,55.98 105.31,51.21 104.55,50.44 104.55,45.41 104.41,45.28 103.99,45.28 103.86,45.14 103.86,44.95 103.99,44.82 104.41,44.82 104.55,44.68 104.55,44.49 104.41,44.36 103.38,44.36 103.25,44.23 103.25,44.04 103.38,43.9 104.41,43.9 104.55,43.77 104.55,43.58 104.41,43.45 103.54,43.45 103.4,43.31 103.4,43.12 103.54,42.99 104.41,42.99 104.55,42.86 104.55,42.47 104.11,42.04 104.11,41.73 104.5,41.35 104.5,41.14 104.03,40.67 101.12,40.67 v6(100.73,41.05)
MB_DQ43: length 36.5
  TOP w0.076: v1(105.35,59.75) 105.53,59.75 105.97,60.19 105.97,60.47 106.13,60.63 106.13,62.06 107.05,62.98 107.43,62.98 107.89,63.43 107.89,63.86 107.75,64.11 107.75,64.24 107.78,64.3 107.81,64.36 107.98,64.71 U6.AW17
  TOP w0.165: v6(101.38,41.05) 101.38,40.97 U11.N10
  IN3 w0.152: v1(105.35,59.75) 105.22,59.75 104.55,59.08 104.55,55.22 104.37,55.04 104.37,50.81 104.09,50.53 104.09,48.72 103.91,48.54 103.64,48.54 103.5,48.4 103.5,48.21 103.64,48.08 104.03,48.08 104.17,47.94 104.17,47.75 104.03,47.62 103,47.62 102.87,47.49 102.87,47.3 103,47.16 104.03,47.16 104.17,47.03 104.17,46.84 104.03,46.7 103,46.7 102.87,46.57 102.87,46.38 103,46.25 104.03,46.25 104.17,46.11 104.17,45.92 104.03,45.79 103,45.79 102.87,45.66 102.87,45.47 103,45.33 103.32,45.33 103.45,45.2 103.45,45.01 103.32,44.88 103,44.88 102.87,44.74 102.87,42.44 103.07,42.24 103.48,42.24 103.73,41.99 103.73,41.68 103.5,41.45 101.61,41.45 101.38,41.23 v6(101.38,41.05)
MB_DQ44: length 37.8
  TOP w0.076: U6.AV19 109.43,65.35 109.43,65.22 109.87,64.78 109.87,64.46 109.85,64.44 109.85,63.98 109.87,63.96 109.87,62.92 109.22,62.27 108.82,62.27 108.56,62 108.56,61.04 108.33,60.8 108.33,60.73
  TOP w0.165: 108.33,60.73 108.33,60.09 v1(107.83,59.59) ; U11.N9 101.06,39.78 v6(100.73,39.45)
  IN3 w0.152: v6(100.73,39.45) 100.97,39.22 100.97,38.51 101.24,38.23 105,38.23 106.38,39.6 106.38,47.44 107.34,48.4 107.34,49.09 107.47,49.22 107.69,49.22 107.82,49.36 107.82,49.55 107.69,49.68 107.47,49.68 107.34,49.82 107.34,50 107.47,50.14 107.69,50.14 107.82,50.27 107.82,50.46 107.69,50.6 107.47,50.6 107.34,50.73 107.34,50.92 107.47,51.05 107.69,51.05 107.82,51.19 107.82,51.38 107.69,51.51 107.47,51.51 107.34,51.64 107.34,51.83 107.73,52.22 107.73,53.34 107.34,53.72 107.34,55.4 107.51,55.57 107.51,59.27 v1(107.83,59.59)
MB_DQ45: length 37.6
  TOP w0.076: v1(106.71,60.44) 106.97,60.44 107.09,60.55 107.09,62.25 107.3,62.47 107.68,62.47 108.4,63.18 108.4,63.84 108.5,63.95 108.5,64.29 108.43,64.45 108.43,64.58 108.5,64.73 108.5,64.94 108.48,64.99 108.44,65.07 108.43,65.09 108.43,65.4 108.41,65.42 108.41,65.91 108.63,66.14 U6.AU19
  TOP w0.165: v6(102.04,39.45) 101.71,39.78 U11.P9
  IN3 w0.152: v6(102.04,39.45) 102.43,39.06 103.51,39.06 103.68,39.23 104.61,39.23 104.73,39.35 104.92,39.35 105.16,39.11 105.35,39.11 105.48,39.24 105.48,39.43 105.24,39.67 105.24,39.86 105.99,40.61 105.99,47.98 106.17,48.16 106.56,48.16 106.69,48.29 106.69,48.48 106.56,48.62 106.08,48.62 105.94,48.75 105.94,48.94 106.08,49.07 106.84,49.07 106.98,49.21 106.98,49.4 106.84,49.53 106.15,49.53 106.02,49.66 106.02,49.85 106.15,49.99 106.78,49.99 106.96,50.16 106.96,55.56 107.13,55.73 107.13,60.24 106.94,60.44 v1(106.71,60.44)
MB_DQ46: length 36.2
  TOP w0.076: U6.AV17 108.26,65.27 108.26,65.06 108.29,65.01 108.34,64.9 108.34,64.77 108.33,64.75 108.29,64.67 108.29,64.67 108.26,64.61 108.26,64.41 108.34,64.25 108.34,64.02 108.23,63.91 108.23,63.27 107.59,62.63 107.21,62.63 106.69,62.11 v1(106.69,61.76)
  TOP w0.165: v6(100.73,41.85) 100.41,41.53 U11.M11
  IN3 w0.152: v1(106.69,61.76) 106.36,62.09 104.96,62.09 104.5,61.63 104.5,60.12 103.78,59.41 103.78,57.07 103.61,56.9 103.61,54.43 102.79,53.62 102.79,50.31 102.65,50.17 102.65,49.98 103.16,49.47 103.16,49.29 103.02,49.15 102.83,49.15 102.33,49.65 102.14,49.65 102.01,49.52 102.01,49.33 102.68,48.66 102.68,48.47 102.55,48.33 102.36,48.33 101.68,49.01 101.49,49.01 101.36,48.87 101.36,48.68 102.12,47.92 102.12,47.74 101.99,47.6 101.13,47.6 100.99,47.46 100.99,47.27 101.13,47.14 101.49,47.14 101.63,47 101.63,46.81 101.49,46.68 100.57,46.68 100.43,46.54 100.43,43.36 100.69,43.1 100.97,43.1 101.19,42.88 101.19,42.31 v6(100.73,41.85)
MB_DQ47: length 37.6
  TOP w0.076: U6.AU17 107.75,65.84 107.75,64.65 107.66,64.43 107.63,64.37 107.62,64.34 107.59,64.27 107.59,64.05 107.65,63.9 107.7,63.86 107.7,63.78 107.72,63.76 107.72,63.51 107.37,63.15 106.95,63.15 105.73,61.94 v1(105.73,61.63)
  TOP w0.165: U11.N11 101.06,41.53 v6(101.38,41.85)
  IN3 w0.152: v1(105.73,61.63) 104.88,60.78 104.88,59.95 104.17,59.24 104.17,56.87 103.99,56.69 103.99,50.96 103.54,50.51 103.54,48.98 103.06,48.5 103.06,48.22 102.49,47.64 102.49,47.21 102.36,47.08 102.14,47.08 102.01,46.94 102.01,46.75 102.14,46.62 102.36,46.62 102.49,46.49 102.49,46.3 102.36,46.16 100.95,46.16 100.81,46.03 100.81,45.84 100.95,45.71 102.36,45.71 102.49,45.57 102.49,45.38 102.36,45.25 100.95,45.25 100.81,45.12 100.81,44.93 100.95,44.79 102.36,44.79 102.49,44.66 102.49,44.47 102.36,44.33 101.15,44.33 101.02,44.2 101.02,44.01 101.15,43.88 102.36,43.88 102.49,43.74 102.49,43.55 102.36,43.42 101.79,43.42 101.65,43.29 101.65,42.12 v6(101.38,41.85)
MB_DQ48: length 40.5
  TOP w0.165: U6.AR21 110.01,67.3 v1(110.33,66.97) ; v6(96.19,41.85) 96.51,41.53 U11.F11
  IN1 w0.076: v1(110.33,66.97) 110.33,66.77 109.88,66.32 109.42,66.32 109.12,66.01 108.92,66.01
  IN1 w0.191: 108.92,66.01 108.86,66.01 106.45,63.6 104.69,63.6 104.47,63.37 103.12,63.37 101.19,61.44 101.19,60.71 100.08,59.59 98.5,59.59 96.98,58.06 96.98,55.73 96.23,54.99 96.23,51.22 96.42,51.03 96.95,51.03 97.13,50.85 97.13,50.56 96.95,50.38 96.42,50.38 96.23,50.19 96.23,49.93 96.42,49.74 96.53,49.74 96.71,49.55 96.71,49.28 96.53,49.09 96.42,49.09 96.23,48.9 96.23,48.63 96.42,48.44 97.05,48.44 97.24,48.25 97.24,47.98 97.05,47.79 96.42,47.79 96.23,47.6 96.23,47.34 96.42,47.15 96.53,47.15 96.71,46.96 96.71,46.69 96.53,46.5 96.42,46.5 96.23,46.31 96.23,46.04 96.42,45.85 96.53,45.85 96.71,45.66 96.71,45.39 96.53,45.2 96.42,45.2 96.23,45.01 96.23,44.74 96.42,44.56 96.53,44.56 96.71,44.37 96.71,44.1 96.53,43.91 96.42,43.91 96.23,43.72 96.23,43.32 95.76,42.85 95.76,42.27 v6(96.19,41.85)
MB_DQ49: length 41.4
  TOP w0.165: U11.E9 95.86,39.78 v6(96.19,39.45) ; v1(111.28,66.97) 110.96,67.3 U6.AR22
  IN1 w0.076: 108.37,62.92 108.53,63.08 108.93,63.08 109.32,63.47 109.32,64.08 111.28,66.05 v1(111.28,66.97)
  IN1 w0.191: v6(96.19,39.45) 97.28,40.54 97.65,40.54 97.76,40.65 98.33,40.65 98.6,40.92 98.6,43.92 98.79,44.11 99.47,44.11 99.66,44.3 99.66,44.57 99.47,44.76 98.79,44.76 98.6,44.95 98.6,45.21 98.79,45.4 99.6,45.4 99.79,45.59 99.79,45.86 99.6,46.05 99.5,46.05 99.31,46.24 99.31,46.51 99.5,46.7 99.6,46.7 99.79,46.89 99.79,51.13 98.6,52.32 98.6,55.23 101.1,57.72 102.11,57.72 104.39,60.01 104.39,60.78 104.7,61.09 104.7,61.97 105.34,62.61 108.06,62.61 108.37,62.92
MB_DQ50: length 44.2
  TOP w0.165: U11.F10 96.51,40.73 v6(96.19,41.05) ; v1(110.33,69.57) 110.01,69.9 U6.AL21
  IN1 w0.076: 107.97,70.24 108.36,70.62 109.54,70.62 109.79,70.37 109.79,70.11 v1(110.33,69.57)
  IN1 w0.191: 107.97,70.24 107.97,66.06 106.34,64.43 104.38,64.43 103.97,64.01 102.51,64.01 100.98,62.47 100.05,62.47 94.81,57.23 94.81,52.37 94.43,51.99 94.43,44.09 93.17,42.83 93.17,42.49 93.41,42.25 94.4,42.25 95.2,41.45 95.79,41.45 v6(96.19,41.05)
MB_DQ51: length 43.2
  TOP w0.165: U11.D9 95.21,39.77 v6(94.89,39.45) ; U6.AM22 110.89,69.17 111.14,68.92 v1(111.28,68.92)
  IN1 w0.191: v6(94.89,39.45) 95.29,39.05 97.98,39.05 99.35,40.42 99.35,42.76 100.63,44.04 100.63,55.48 100.88,55.73 102.23,55.73 103.65,57.15 105.95,57.15 107.19,58.39 107.19,61.75 107.47,62.03 108.27,62.03 108.73,62.49 109.09,62.49 110.41,63.81 110.41,64.22 112.01,65.82 112.01,68.19 v1(111.28,68.92)
MB_DQ52: length 43
  TOP w0.165: v6(96.84,39.45) 96.51,39.78 U11.F9 ; v1(111.28,68.27) 110.96,68.6 U6.AN22
  IN1 w0.076: 108.74,62.79 108.92,62.79 110.13,64.01 110.13,64.34 111.68,65.88 111.68,67.88 v1(111.28,68.27)
  IN1 w0.191: v6(96.84,39.45) 97.32,39.93 97.82,39.93 97.9,39.85 98.3,39.85 99,40.55 99,43.05 100.21,44.26 100.21,51.31 99.25,52.27 99.25,52.81 99.44,53 99.94,53 100.13,53.19 100.13,53.46 99.94,53.65 99.44,53.65 99.25,53.84 99.25,54.11 99.44,54.3 100.02,54.3 100.21,54.49 100.21,54.76 100.02,54.95 99.67,54.95 99.47,55.15 99.47,55.5 100.19,56.22 102.13,56.22 104.83,58.92 104.83,60.33 105.21,60.71 105.21,62.06 105.47,62.32 108.17,62.32 108.64,62.79 108.74,62.79
MB_DQ53: length 42.3
  TOP w0.165: v6(95.54,41.85) 95.86,41.53 U11.E11 ; v1(110.33,67.62) 110.01,67.95 U6.AP21
  IN1 w0.089: v1(110.33,67.62) 110.02,67.62 109.86,67.46 109.86,66.82 109.59,66.56 109.23,66.56 109.07,66.39
  IN1 w0.191: 109.07,66.39 108.81,66.39 106.32,63.91 104.55,63.91 104.34,63.7 102.84,63.7 101.19,62.05 100.23,62.05 95.82,57.64 95.82,56.8 96,56.61 96.23,56.61 96.42,56.42 96.42,56.15 96.23,55.96 96,55.96 95.82,55.77 95.82,51.93 95,51.11 95,49.96 95.82,49.14 95.82,48.9 95.63,48.71 95.04,48.71 94.85,48.52 94.85,48.25 95.04,48.06 95.63,48.06 95.82,47.87 95.82,47.61 95.63,47.42 95.04,47.42 94.85,47.23 94.85,46.96 95.04,46.77 95.63,46.77 95.82,46.58 95.82,46.31 95.63,46.12 95.04,46.12 94.85,45.93 94.85,45.66 95.04,45.47 95.63,45.47 95.82,45.28 95.82,44.73 95.53,44.44 95.53,44.02 95.82,43.73 95.82,43.54 95.31,43.03 95.31,42.08 v6(95.54,41.85)
MB_DQ54: length 45
  TOP w0.165: v6(95.54,40.25) 95.86,40.58 U11.E10 ; v1(110.33,70.22) 110.01,70.55 U6.AK21
  IN1 w0.076: 107.65,70.21 107.65,70.22 108.22,70.8 109.75,70.8 v1(110.33,70.22)
  IN1 w0.191: v6(95.54,40.25) 95.28,40.51 93.53,40.51 92.52,41.51 92.52,42.77 94.01,44.26 94.01,52.25 94.39,52.64 94.39,57.63 99.76,62.99 100.08,62.99 100.97,63.89 101.97,63.89 102.39,64.3 103.67,64.3 104.27,64.9 104.77,64.9 106.17,66.29 106.58,66.29 106.61,66.26 106.91,66.26 107.65,66.99 107.65,70.21
MB_DQ55: length 43.7
  TOP w0.165: v6(96.18,38.65) 96.51,38.98 U11.F8 ; v1(111.28,70.22) 110.96,70.55 U6.AK22
  IN1 w0.076: v1(111.28,70.22) 111.28,70.17 112.06,69.39 112.06,68.75 112.33,68.48 112.33,65.57 111.35,64.59 111.35,64.44 109.18,62.27 108.82,62.27 108.22,61.67 108.22,58.82 107.7,58.29
  IN1 w0.191: v6(96.18,38.65) 96.58,38.25 97.65,38.25 99.68,40.27 99.68,42.06 99.87,42.25 101,42.25 101.35,42.6 101.35,43.87 101.12,44.09 101.12,54.02 103.73,56.63 106.03,56.63 107.7,58.29
MB_DQ56: length 47.1
  TOP w0.165: v6(93.59,41.05) 93.91,40.73 U11.B10 ; v1(109.38,68.27) 109.05,68.6 U6.AN20
  IN3 w0.076: 109.37,66.32 109.77,66.72 109.77,67.88 v1(109.38,68.27)
  IN3 w0.152: 109.37,66.32 109.37,64.79 107.55,62.97 104.81,62.97 103.03,61.19 102.79,61.19 101.71,60.11 101.43,60.11 101.27,59.95 101.27,55.96 100.66,55.35 100.66,50.8 100.39,50.53 100.39,50.34 100.58,50.15 100.58,49.96 100.45,49.83 100.26,49.83 100.07,50.02 99.88,50.02 99.74,49.89 99.74,49.7 99.93,49.51 99.93,49.32 99.8,49.18 99.61,49.18 99.42,49.37 99.23,49.37 98.91,49.05 98.91,45.06 98.76,44.91 97.79,44.91 97.66,44.78 97.66,44.74 97.53,44.6 97.34,44.6 97.2,44.74 97.2,44.78 97.07,44.91 96.88,44.91 96.75,44.78 96.75,43.64 96.61,43.51 96.42,43.51 96.29,43.64 96.29,44.78 96.15,44.91 95.97,44.91 95.83,44.78 95.83,43.87 95.7,43.74 95.51,43.74 95.37,43.87 95.37,44.78 95.24,44.91 94.77,44.91 94.51,44.65 94.51,44.24 94.31,44.04 93.9,44.04 92.53,42.67 92.53,41.64 92.72,41.45 93.19,41.45 v6(93.59,41.05)
MB_DQ57: length 46.1
  TOP w0.165: v1(109.38,66.97) 109.05,67.3 U6.AR20 ; U11.C10 94.56,40.73 v6(94.24,41.05)
  IN3 w0.152: v1(109.38,66.97) 109.38,66.71 108.99,66.32 108.99,64.77 107.52,63.3 103.4,63.3 101.55,61.44 101.55,60.88 100.89,60.22 100.89,59.5 100.75,59.37 100.34,59.37 100.2,59.23 100.2,59.04 100.34,58.91 100.75,58.91 100.89,58.78 100.89,58.59 100.75,58.45 100.51,58.45 100.38,58.32 100.38,58.13 100.51,58 100.75,58 100.89,57.86 100.89,57.67 100.75,57.54 100.51,57.54 100.38,57.4 100.38,57.21 100.51,57.08 100.75,57.08 100.89,56.95 100.89,56.57 100.63,56.31 99.98,56.31 99.85,56.18 99.85,55.99 99.98,55.85 100.15,55.85 100.28,55.72 100.28,55.53 100.15,55.39 99.98,55.39 99.85,55.26 99.85,55.07 99.98,54.94 100.15,54.94 100.28,54.8 100.28,54.61 100.15,54.48 99.98,54.48 99.85,54.35 99.85,54.16 99.98,54.02 100.15,54.02 100.28,53.89 100.28,53.7 100.15,53.57 99.98,53.57 99.85,53.43 99.85,53.24 99.98,53.11 100.15,53.11 100.28,52.97 100.28,51.13 98.53,49.38 98.53,45.42 98.4,45.29 94.44,45.29 92.02,42.88 92.02,41.48 92.53,40.97 92.99,40.97 93.32,40.64 93.83,40.64 v6(94.24,41.05)
MB_DQ58: length 48.4
  TOP w0.165: U6.AK18 108.19,70.55 v1(108.52,70.22) ; U11.C8 94.56,38.98 v6(94.23,38.65)
  IN3 w0.076: 106.3,66.29 106.87,66.29 107.7,67.13 107.7,69.41 v1(108.52,70.22)
  IN3 w0.152: 106.3,66.29 105.63,66.29 104.71,65.37 100.54,65.37 97.13,61.96 97.13,59.77 96.72,59.36 96.72,51.84 89.48,44.6 89.48,39.94 91.48,37.94 93.53,37.94 v6(94.23,38.65)
MB_DQ59: length 46.8
  TOP w0.165: U11.B8 93.91,38.98 v6(93.58,38.65) ; U6.AL18 108.1,69.9 v1(108.43,69.57)
  IN3 w0.076: 105.98,64.97 106.31,64.63 106.67,64.63 107.87,65.82 107.87,69.01 v1(108.43,69.57)
  IN3 w0.152: v6(93.58,38.65) 93.26,38.32 91.63,38.32 89.87,40.09 89.87,44.35 97.1,51.59 97.1,58.08 97.56,58.53 97.56,61.85 100.68,64.97 105.98,64.97
MB_DQ60: length 48.8
  TOP w0.165: U6.AK20 109.05,70.55 v1(109.38,70.22) ; U11.C11 94.56,41.53 v6(94.24,41.85)
  IN3 w0.152: v6(94.24,41.85) 94.71,41.85 95.1,42.24 98.96,42.24 99.77,43.05 99.77,48.08 102.23,50.54 102.23,50.92 102.1,51.06 101.71,51.06 101.57,51.19 101.57,51.38 101.71,51.51 102.1,51.51 102.23,51.65 102.23,51.84 102.1,51.97 101.71,51.97 101.57,52.1 101.57,52.29 101.71,52.43 102.1,52.43 102.23,52.56 102.23,52.75 102.1,52.88 101.71,52.88 101.57,53.02 101.57,53.21 101.71,53.34 102.1,53.34 102.23,53.48 102.23,53.66 102.1,53.8 101.71,53.8 101.57,53.93 101.57,54.12 101.71,54.26 102.64,54.26 103.05,54.67 103.05,55.96 102.91,56.09 102.39,56.09 102.26,56.23 102.26,56.42 102.39,56.55 102.91,56.55 103.05,56.69 103.05,57.19 103.21,57.35 103.21,59.63 103.93,60.35 103.93,61.41 104.86,62.33 108.56,62.33 108.8,62.57 109.21,62.57 109.68,63.04 109.68,63.91 110.78,65.01 110.78,70.47 110.58,70.67 109.83,70.67 v1(109.38,70.22)
MB_DQ61: length 47.9
  TOP w0.165: U11.B11 93.91,41.53 v6(93.59,41.85) ; U6.AM20 109.05,69.25 v1(109.38,68.92)
  IN3 w0.076: v1(109.38,68.92) 109.94,68.36 109.94,66.26 110.08,66.12
  IN3 w0.152: 110.08,66.12 110.43,65.77 110.43,65.19 109.27,64.03 109.27,63.29 108.97,62.99 108.56,62.99 108.23,62.66 104.85,62.66 103.5,61.32 103.5,60.55 101.8,58.85 101.8,55.83 101.94,55.69 102.43,55.69 102.57,55.56 102.57,54.91 102.39,54.74 101.32,54.74 101.04,54.46 101.04,49.89 99.39,48.24 99.39,43.23 99.21,43.05 98.8,43.05 98.62,43.23 98.62,44.39 98.48,44.53 98.29,44.53 98.16,44.39 98.16,43.24 98.03,43.1 97.84,43.1 97.7,43.24 97.7,44.09 97.57,44.22 97.38,44.22 97.25,44.09 97.25,43.26 97.11,43.13 95.58,43.13 95.1,43.61 94,43.61 93.2,42.81 93.2,42.38 93.37,42.21 93.37,42.07 v6(93.59,41.85)
MB_DQ62: length 43.7
  TOP w0.165: U11.B9 93.91,39.78 v6(93.58,39.45) ; v1(108.43,66.97) 108.1,67.3 U6.AR18
  IN3 w0.076: v1(108.43,66.97) 108.2,66.75 108.2,65.69 106.71,64.2 105.92,64.2
  IN3 w0.152: 105.92,64.2 102.63,64.2 101.16,62.73 99.61,62.73 98.37,61.49 98.37,58.27 98.11,58 98.11,56.78 98.37,56.52 98.37,51.66 97.13,50.42 97.13,47.78 96.67,47.32 94.03,47.32 90.63,43.92 90.63,40.41 91.95,39.09 92.92,39.09 93.28,39.45 v6(93.58,39.45)
MB_DQ63: length 44.5
  TOP w0.165: v1(108.43,67.62) 108.1,67.95 U6.AP18 ; v6(94.23,39.45) 94.56,39.78 U11.C9
  IN3 w0.076: v1(108.43,67.62) 108.03,67.23 108.03,65.75 106.74,64.46 106.13,64.46 106.01,64.58
  IN3 w0.152: v6(94.23,39.45) 93.82,39.04 93.43,39.04 93.1,38.71 91.79,38.71 90.25,40.25 90.25,44.12 97.49,51.36 97.49,57.92 97.99,58.43 97.99,61.74 99.37,63.12 100.29,63.12 101.75,64.58 106.01,64.58
MB_DQSN0: length 36.9
  TOP w0.076: U6.AW30 116.29,65.34 116.36,65.41 116.45,65.41 116.53,65.33 116.58,65.23 116.58,65.1 116.5,64.94 116.5,64.73 116.53,64.68 116.57,64.6 116.58,64.58 116.58,64.45 116.53,64.34 116.5,64.29 116.5,64 116.76,63.75 116.76,62.42 116.46,62.13 116.46,60.55 116.7,60.31 116.8,60.31 v1(117.02,60.09)
  TOP w0.165: U12.P11 120.52,41.65 120.72,41.85 v6(120.84,41.85)
  IN1 w0.076: v1(117.02,60.09) 117.25,60.31 117.36,60.31 117.42,60.24 117.42,59.9 116.87,59.35 116.87,59.06 116.76,58.96 116.76,58.93 ; 121.19,40.77 121.18,40.78 121.18,41.39 121.1,41.46 120.65,41.46 120.59,41.53 120.59,41.64 120.8,41.85 v6(120.84,41.85)
  IN1 w0.191: 121.19,40.77 121.19,40.52 121.43,40.28 123.56,40.28 124.63,41.34 124.63,42.06 124.03,42.66 124.03,43.22 124.63,43.81 124.63,44.97 119.7,49.9 119.7,50.66 119.29,51.07 118.36,51.07 118,51.44 118,54.66 116.76,55.89 116.76,58.93
MB_DQSN1: length 34.5
  TOP w0.076: v1(113.81,61.59) 114.06,61.83 114.21,61.83 114.45,62.08 114.45,63.85 114.24,64.06 114.24,64.25 114.29,64.35 114.29,64.36 114.31,64.41 114.31,64.61 114.24,64.77 114.24,64.9 114.29,65 114.29,65.2 113.85,65.63 U6.AV26
  TOP w0.165: U12.D11 114.34,41.13 v6(114.34,41.05)
  IN3 w0.152: v1(113.81,61.59) 113.63,61.77 113.32,61.77 113.13,61.58 113.13,58.38 112.83,58.08 112.83,52.54 112.29,52 112.29,48.18 112.78,47.7 112.78,46.63 112.46,46.32 111.25,46.32 110.52,45.58 110.52,44.93 111.07,44.37 111.07,43.71 110.52,43.15 110.52,42.3 110.87,41.95 110.87,41.29 110.62,41.03 110.62,40.65 111.06,40.21 113.04,40.21 113.5,40.67 114.14,40.67 114.34,40.87 v6(114.34,41.05)
MB_DQSN2: length 40.4
  TOP w0.165: U12.G11 116.12,41.45 116.26,41.58 116.26,41.73 116.14,41.85 v6(115.65,41.85) ; v1(114.99,68.27) 114.68,68.27 114.53,68.43 114.53,68.53 U6.AN28
  IN1 w0.076: 112.93,57.4 112.93,57.43 113.03,57.53 113.03,58.07 113.25,58.29 113.25,63 113.9,63.65 113.9,63.99 114.42,64.51 114.42,65.69 114.8,66.08 115.28,66.08 115.38,66.18 115.38,68.54 115.31,68.61 115.24,68.61 114.99,68.35 v1(114.99,68.27)
  IN1 w0.191: v6(115.65,41.85) 115.88,41.62 116.06,41.62 116.14,41.69 116.14,42.77 115.21,43.7 114.64,43.7 114.01,44.34 113.16,44.34 112.64,43.81 112.2,43.81 111.28,42.89 110.6,42.89 110.25,43.24 110.25,44.07 111.07,44.89 111.07,45.46 110.85,45.68 110.65,45.68 110.25,46.09 110.25,46.71 110.65,47.12 110.69,47.12 110.88,47.31 110.88,50.63 111.48,51.23 112.05,51.23 113.02,52.2 113.02,56.36 112.93,56.45 112.93,57.4
MB_DQSN3: length 45.8
  TOP w0.165: U12.L11 118.39,41.27 118.39,41.15 118.46,41.08 v6(118.89,41.08) ; v1(113.08,68.27) 112.8,68.27 112.69,68.39 U6.AN25
  IN3 w0.076: 117.51,61.21 117.51,61.23 117.56,61.29 117.56,61.4 117.06,61.91 117.06,64.07 116.64,64.48 115.07,64.48 113.47,66.07 113.47,68.46 113.38,68.55 113.22,68.55 113.08,68.41 v1(113.08,68.27)
  IN3 w0.152: v6(118.89,41.08) 119.33,40.64 122.36,40.64 122.53,40.81 122.53,43.62 122.38,43.77 122.16,43.77 121.84,43.46 121.36,43.46 120.75,44.07 120.75,44.65 121.09,44.99 122.38,44.99 122.53,45.14 122.53,45.5 122.38,45.65 120.64,45.65 120.29,45.99 120.29,46.53 120.64,46.87 122.38,46.87 122.53,47.02 122.53,48.42 117.27,53.68 117.27,58.38 117.51,58.62 117.51,61.21
MB_DQSN4: length 34.6
  TOP w0.076: v1(111.09,62.88) 111.29,62.69 111.39,62.69 111.49,62.79 111.49,63.87 111.37,64 111.37,64.29 111.39,64.34 111.44,64.45 111.44,64.58 111.44,64.6 111.4,64.68 111.37,64.73 111.37,64.94 111.44,65.1 111.44,65.23 111.4,65.33 111.24,65.49 111.15,65.49 111.1,65.44 111.1,65.21 U6.AW22
  TOP w0.165: v6(102.03,41.85) 101.71,41.53 U11.P11
  IN1 w0.076: v6(102.03,41.85) 102.37,41.52 102.37,40.79
  IN1 w0.191: v1(111.09,62.88) 111.07,62.88 110.94,62.75 110.06,62.75 109.44,62.14 109.44,56.8 107.26,54.63 107.26,54.11 106.71,53.56 105.94,53.56 105.58,53.2 105.58,41.21 104.65,40.29 102.47,40.29 102.37,40.39 102.37,40.79
MB_DQSN5: length 37.9
  TOP w0.076: U6.AV18 108.72,65.64 109.15,65.21 109.15,65 109.11,64.9 109.11,64.77 109.18,64.61 109.18,64.41 109.15,64.36 109.15,64.35 109.11,64.25 109.11,64.04 109.38,63.77 109.38,63.14 109.03,62.8 108.5,62.8 107.43,61.73 107.43,59.44 107.26,59.27 106.77,59.27 v1(106.68,59.18)
  TOP w0.165: U11.L11 99.76,41.5 v6(100.09,41.83)
  IN3 w0.152: v6(100.09,41.83) 99.98,41.72 99.4,41.72 99.14,41.46 99.14,40.3 99.6,39.83 104.37,39.83 105.38,40.84 105.38,50.01 106.17,50.8 106.17,51.36 106.4,51.59 106.4,52.5 106.17,52.73 106.17,53.24 106.4,53.47 106.4,54.38 106.17,54.61 106.17,55.12 106.4,55.35 106.4,56.26 106.17,56.49 106.17,58.91 106.44,59.18 v1(106.68,59.18)
MB_DQSN6: length 43.5
  TOP w0.165: U6.AN21 109.94,68.37 110.03,68.27 v1(110.33,68.27) ; v6(96.84,41.85) 96.87,41.89 97.27,41.89 97.36,41.8 97.36,41.65 U11.G11
  IN1 w0.076: 109.13,65.74 109.47,65.74 109.62,65.89 110.12,65.89 110.72,66.49 110.72,68.49 110.66,68.55 110.48,68.55 110.33,68.4 v1(110.33,68.27)
  IN1 w0.191: 109.13,65.74 107.74,64.36 107.74,63.52 107.49,63.27 105.01,63.27 103.43,61.69 103.43,60.52 101.77,58.85 98.72,58.85 97.64,57.77 97.64,57.01 98.16,56.49 98.16,56.15 97.64,55.63 97.64,55.28 96.98,54.62 96.98,54.09 97.31,53.75 97.31,51.61 98.05,50.87 98.62,50.87 98.83,50.67 98.83,50.32 98.62,50.11 97.72,50.11 97.31,49.71 97.31,49.02 97.72,48.61 98.62,48.61 98.83,48.41 98.83,48.05 97.31,46.54 97.31,41.8 97.18,41.67 97.02,41.67 v6(96.84,41.85)
MB_DQSN7: length 46.6
  TOP w0.165: v6(95.54,41.05) 95.21,41.38 U11.D11 ; v1(108.43,68.27) 108.1,68.6 U6.AN18
  IN3 w0.076: v1(108.43,68.27) 108.82,67.88 108.82,66.73 108.38,66.29 108.38,65.64 106.62,63.87 106.27,63.87 106.22,63.93 106.17,63.93
  IN3 w0.152: v6(95.54,41.05) 95.43,40.95 95.33,40.84 95.33,40.61 94.7,39.99 92.28,39.99 91.19,41.08 91.19,43.45 93.86,46.13 94.49,46.13 94.97,46.61 96.04,46.61 96.52,46.13 97.47,46.13 97.69,46.34 97.69,49.95 98.98,51.25 98.98,61.29 99.75,62.05 100.97,62.05 102.84,63.93 106.17,63.93
MB_DQSP0: length 36.9
  TOP w0.076: v1(117.02,60.73) 117.02,60.65 116.85,60.48 116.76,60.48 116.62,60.62 116.62,62.06 116.92,62.36 116.92,63.81 116.67,64.06 116.67,64.25 116.72,64.35 116.72,64.36 116.74,64.41 116.74,64.61 116.67,64.77 116.67,64.9 116.72,65 116.74,65.06 116.74,65.26 116.68,65.4 116.68,65.42 116.61,65.49 116.52,65.58 116.36,65.58 116.29,65.66 U6.AV30
  TOP w0.165: v6(120.82,41.05) 120.52,40.75 U12.P10
  IN1 w0.076: 117.13,58.93 117.13,58.96 117.03,59.06 117.03,59.28 117.59,59.84 117.59,60.31 117.42,60.48 117.27,60.48 v1(117.02,60.73)
  IN1 w0.191: 117.13,58.93 117.13,56.05 118.36,54.81 118.36,51.59 118.52,51.44 119.44,51.44 120.07,50.81 120.07,50.05 124.99,45.12 124.99,43.66 124.39,43.06 124.39,42.82 124.99,42.22 124.99,41.19 123.71,39.91 121.28,39.91 120.82,40.37 v6(120.82,41.05)
MB_DQSP1: length 34.4
  TOP w0.076: U6.AW26 113.92,65.23 114.03,65.23 114.12,65.13 114.12,65.04 114.07,64.94 114.07,64.73 114.1,64.68 114.14,64.6 114.15,64.58 114.15,64.45 114.07,64.29 114.07,64 114.29,63.78 114.29,62.15 114.14,62 114.04,62 v1(113.81,62.22)
  TOP w0.165: U12.D10 114.34,40.33 v6(114.34,40.25)
  IN3 w0.152: v1(113.81,62.22) 113.64,62.05 113.21,62.05 112.85,61.7 112.85,58.5 112.55,58.19 112.55,52.65 112.01,52.12 112.01,48.07 112.5,47.59 112.5,46.75 112.34,46.6 111.14,46.6 110.24,45.7 110.24,44.82 110.8,44.26 110.8,43.83 110.24,43.27 110.24,42.19 110.59,41.83 110.59,41.4 110.34,41.15 110.34,40.54 110.95,39.93 113.16,39.93 113.62,40.39 114.21,40.39 v6(114.34,40.25)
MB_DQSP2: length 40.3
  TOP w0.165: U6.AM28 114.92,68.92 v1(114.99,68.92) ; v6(115.65,41.05) 115.97,40.73 U12.G10
  IN1 w0.076: 113.3,57.4 113.3,57.43 113.2,57.53 113.2,58 113.42,58.22 113.42,62.93 114.07,63.58 114.07,63.92 114.58,64.44 114.58,65.62 114.87,65.91 115.35,65.91 115.54,66.11 115.54,68.61 115.38,68.77 115.14,68.77 v1(114.99,68.92)
  IN1 w0.191: 113.3,57.4 113.3,56.6 113.39,56.52 113.39,52.04 112.2,50.86 111.63,50.86 111.25,50.48 111.25,47.16 110.85,46.75 110.81,46.75 110.62,46.56 110.62,46.24 110.81,46.05 111,46.05 111.44,45.61 111.44,44.74 110.62,43.92 110.62,43.4 110.76,43.26 111.12,43.26 112.05,44.18 112.48,44.18 113,44.7 114.16,44.7 114.8,44.07 115.36,44.07 116.51,42.92 116.51,41.54 116.22,41.25 115.84,41.25 v6(115.65,41.05)
MB_DQSP3: length 45.8
  TOP w0.165: v6(118.89,40.25) 118.57,40.58 U12.L10 ; U6.AM25 112.76,69.25 v1(113.08,68.92)
  IN3 w0.076: v1(113.08,68.92) 113.28,68.72 113.45,68.72 113.64,68.53 113.64,66.14 115.14,64.64 116.71,64.64 117.22,64.14 117.22,61.98 117.73,61.47 117.73,61.29 117.79,61.23 117.79,61.21
  IN3 w0.152: 117.79,61.21 117.79,58.5 117.55,58.26 117.55,53.8 122.81,48.54 122.81,46.91 122.49,46.59 120.75,46.59 120.57,46.41 120.57,46.11 120.75,45.93 122.49,45.93 122.81,45.61 122.81,45.03 122.49,44.71 121.21,44.71 121.03,44.53 121.03,44.19 121.48,43.74 121.73,43.74 122.04,44.05 122.49,44.05 122.81,43.73 122.81,40.69 122.48,40.36 119,40.36 v6(118.89,40.25)
MB_DQSP4: length 34.5
  TOP w0.076: v1(111.07,62.26) 111.33,62.52 111.46,62.52 111.66,62.72 111.66,63.94 111.54,64.06 111.54,64.25 111.58,64.35 111.58,64.36 111.61,64.41 111.61,64.61 111.54,64.77 111.54,64.9 111.58,65 111.61,65.06 111.61,65.26 111.54,65.4 111.54,65.42 111.47,65.49 111.15,65.81 U6.AV22
  TOP w0.165: v6(102.02,41.05) 101.71,40.74 U11.P10
  IN1 w0.191: v1(111.07,62.26) 110.95,62.38 110.21,62.38 109.81,61.98 109.81,56.65 107.63,54.47 107.63,53.96 106.87,53.19 106.09,53.19 105.94,53.05 105.94,41.06 104.8,39.92 102.32,39.92 102,40.24 102,41.03 v6(102.02,41.05)
MB_DQSP5: length 37.9
  TOP w0.076: U6.AW18 108.8,65.24 108.89,65.24 108.99,65.14 108.99,65.04 108.94,64.94 108.94,64.73 108.96,64.68 109,64.6 109.01,64.58 109.01,64.45 108.96,64.34 108.94,64.29 108.94,63.97 109.21,63.7 109.21,63.21 108.96,62.96 108.43,62.96 107.26,61.8 107.26,59.5 107.2,59.44 106.99,59.44 106.68,59.74 v1(106.68,59.81)
  TOP w0.165: U11.L10 99.61,40.65 99.42,40.84 99.42,40.98 99.53,41.09 100.02,41.09 v6(100.08,41.03)
  IN3 w0.152: v1(106.68,59.81) 105.89,59.03 105.89,56.37 106.12,56.15 106.12,55.46 105.89,55.23 105.89,54.49 106.12,54.27 106.12,53.58 105.89,53.35 105.89,52.61 106.12,52.39 106.12,51.7 105.89,51.47 105.89,50.92 105.11,50.13 105.11,40.96 104.26,40.11 99.72,40.11 99.42,40.41 99.42,41.34 99.52,41.44 100.19,41.44 100.28,41.35 100.28,41.22 v6(100.08,41.03)
MB_DQSP6: length 43.4
  TOP w0.165: U11.G10 97.16,40.73 v6(96.84,41.05) ; v1(110.33,68.92) 110.01,69.25 U6.AM21
  IN1 w0.076: v1(110.33,68.92) 110.53,68.72 110.73,68.72 110.89,68.56 110.89,66.42 110.19,65.72 109.69,65.72 109.4,65.43 109.34,65.43
  IN1 w0.191: 109.34,65.43 108.11,64.2 108.11,63.37 107.65,62.9 105.16,62.9 103.8,61.54 103.8,60.36 101.92,58.48 98.87,58.48 98.01,57.62 98.01,57.16 98.53,56.64 98.53,56 98.01,55.48 98.01,55.13 97.35,54.47 97.35,54.24 97.68,53.91 97.68,51.76 98.2,51.24 98.77,51.24 99.19,50.82 99.19,50.16 98.77,49.74 97.87,49.74 97.68,49.55 97.68,49.17 97.87,48.98 98.77,48.98 99.19,48.56 99.19,47.9 97.68,46.39 97.68,41.65 97.33,41.3 97.09,41.3 v6(96.84,41.05)
MB_DQSP7: length 46.6
  TOP w0.165: v1(108.43,68.92) 108.13,68.92 107.98,69.06 107.98,69.2 U6.AM18 ; v6(94.89,41.05) 94.89,40.88 95.11,40.65 U11.D10
  IN3 w0.076: 106.17,63.65 106.22,63.65 106.27,63.71 106.69,63.71 108.55,65.57 108.55,66.23 108.98,66.66 108.98,67.95 108.84,68.09 108.84,68.82 108.74,68.92 v1(108.43,68.92)
  IN3 w0.152: 106.17,63.65 102.96,63.65 101.08,61.77 99.86,61.77 99.26,61.17 99.26,51.13 97.97,49.84 97.97,46.23 97.59,45.85 96.4,45.85 95.92,46.33 95.08,46.33 94.6,45.85 93.98,45.85 91.47,43.34 91.47,41.2 92.39,40.27 94.59,40.27 95.05,40.73 95.05,40.89 v6(94.89,41.05)
MB_ODT: length 89.5
  TOP w0.165: v1(106.65,37.72) 107.04,37.34 R209.2 ; v6(98.78,38.65) U11.J8 ; U12.J8 117.27,38.71 v6(117.55,38.43) ; U6.AL32 117.08,69.9 v1(117.4,69.57)
  IN1 w0.191: v6(98.78,38.65) 98.78,38.05 98.27,37.54 98.27,36.93 98.55,36.65 104.17,36.65 104.57,37.06 104.83,37.06 105.33,36.55 105.56,36.55 105.99,36.98 106.53,36.98 106.65,37.11 v1(106.65,37.72) 112.52,37.72 112.78,37.46 114.3,37.46 114.55,37.72 117.27,37.72 117.55,38 v6(117.55,38.43)
  IN2 w0.191: v1(106.65,37.72) 105,37.72 104.43,38.29 104.43,39.13 102.97,40.59 102.72,40.59 102.23,40.11 101.85,40.11 101.37,40.59 99.59,40.59 99.49,40.69 99.49,42.87 98.29,44.07 98.29,44.46 98.12,44.63 96.88,44.63 96.71,44.8 96.71,45.03 96.88,45.2 98.12,45.2 98.29,45.37 98.29,45.6 98.12,45.77 96.88,45.77 96.71,45.94 96.71,46.18 96.88,46.34 98.12,46.34 98.29,46.51 98.29,46.75 98.12,46.91 97.04,46.91 96.88,47.08 96.88,47.32 97.04,47.49 98.12,47.49 98.29,47.65 98.29,47.89 98.12,48.06 97.66,48.06 97.46,48.26 97.46,48.59 97.66,48.79 98.09,48.79 98.29,49 98.29,51.61 100.51,53.82 102.49,53.82 103.2,54.53 103.38,54.53 104.28,55.44 106.11,55.44 106.96,56.29 109.17,56.29 109.63,56.74 109.63,62.05 110.63,63.05 110.63,64.14 112.56,66.07 112.56,69.13 112.7,69.27 112.7,70.38 113.06,70.74 116.13,70.74 117.3,69.57 v1(117.4,69.57)
MBCLK: length 150.2
  TOP w0.102: PR70.2 v1(109.73,9.39) 109.86,9.25 109.86,8.9 108.97,8 108.97,7.24 109.22,6.98 109.37,6.98 109.47,6.88 109.47,6.22 109.79,5.91 PU6.4
  IN1 w0.114: v1(53.37,29.57) 53.61,29.32 54.01,29.32 55.67,27.67 55.67,24.3 55.12,23.75 55.12,14.22 55.96,13.38 63.2,13.38 63.79,12.8 78.31,12.8 78.79,12.32 84.48,12.32 88.81,7.99 109.32,7.99 109.92,8.6 109.92,9.19 v1(109.73,9.39)
  IN3 w0.102: v1(109.73,9.39) 109.88,9.24 109.88,4.54 112.14,2.29 151.58,2.29 152.12,2.83 152.12,9.25 v1(152.4,9.52)
  BOTTOM w0.102: PR164.1 151.99,9.12 v1(152.4,9.52) ; v1(53.37,29.57) 53.57,29.36 53.95,29.36 54.13,29.54 54.13,38.07 53.99,38.2 U23.110 53.99,40.64 53.9,40.73 53.9,41.31 R509.1
MBDATA: length 150.3
  TOP w0.102: PR71.2 v1(110.36,9.39) 110.33,9.39 110.09,9.15 110.09,8.8 109.19,7.91 109.19,7.33 109.31,7.21 109.47,7.21 109.6,7.35 109.6,7.75 109.66,7.81 PU6.6
  IN1 w0.114: v1(53.37,28.83) 53.62,29.08 53.91,29.08 55.43,27.57 55.43,24.4 54.88,23.85 54.88,14.12 55.86,13.14 63.1,13.14 63.69,12.55 78.21,12.55 78.69,12.08 84.38,12.08 88.71,7.75 109.42,7.75 110.17,8.5 110.17,9.19 v1(110.36,9.39)
  IN3 w0.102: v1(152.4,10.16) 151.89,9.65 151.89,2.92 151.49,2.51 112.23,2.51 110.11,4.64 110.11,9.14 v1(110.36,9.39)
  BOTTOM w0.102: PR162.1 152.37,10.13 v1(152.4,10.16) ; v1(53.37,28.83) 53.67,29.13 54.04,29.13 54.36,29.45 54.36,38.35 54.39,38.39 U23.111 54.39,40.09 54.22,40.26 54.22,40.73 54.13,40.83 54.13,41.21 R510.1
ME_WR#: length 59
  IN1 w0.114: v1(53.04,41.15) 53.26,41.38 60.93,41.38 61.19,41.64 64.19,41.64 65.03,40.79 71.41,40.79 78,47.38 v1(79.25,47.38)
  BOTTOM w0.102: U23.106 52.39,40 53.04,40.64 v1(53.04,41.15) ; v1(79.25,47.38) 81.34,49.48 92.26,49.48 92.35,49.38 v2(93.54,49.38) 94.31,49.38 99.31,54.38 99.31,56.77 99.44,56.9 99.44,58.04 99.21,58.27 R456.2
MIC2-VREFO: length 15.7
  TOP w0.203: U16.29 30.17,22.06 30.02,21.92 29.21,21.92 v1(29.08,22.05)
  IN1 w0.381: v1(35.25,28.01) 34.84,28.01 32.26,25.43 32.26,25.15 30.86,23.75 30.86,22.48 30.23,21.84 29.29,21.84 v1(29.08,22.05)
  BOTTOM w0.381: v2(35.07,28.87) 35.14,28.79 35.14,28.59 35.25,28.49 v1(35.25,28.01) 34.99,28.01 34.54,27.56 R537.1 R538.1 ; v1(29.08,22.05) 29.08,21.96 R553.2
MODPHY_D: length 20.4
  IN3 w0.254: v1(72.64,77.6) 72.87,77.83 72.87,81.68 72.71,81.84 72.71,87.44 73.22,87.95 v1(73.22,88.03)
  BOTTOM w0.254: v1(73.22,88.03) 73.51,88.32 PR118.2 PC85.2 74.99,88.32 75.25,88.59 75.89,88.59 76.39,88.08 PQ22.3 78.93,89.22 79.88,90.17 v2(79.88,90.35) ; v1(72.64,77.6) 72.38,77.86 PQ26.4
MODPHY_EN: length 41.5
  TOP w0.076: U6.Y2 98.54,76.14 97.59,76.14 97.56,76.11 97.41,76.11 97.32,76.2
  TOP w0.102: v1(79.95,89.22) v2(79.95,88.15) 79.95,87.72 79.3,87.07 79.3,84.52 78.21,83.43 78.21,80.13 79.53,78.81 79.93,78.81 80.21,79.09 83.86,79.09 84.07,79.29 84.08,79.28 86.12,79.28 86.13,79.29 86.7,79.29 86.88,79.11 87.24,79.11 87.4,79.26 88,79.26 88.59,79.86 90.52,79.86 93.24,77.13 94.11,77.13 95.04,76.2 97.32,76.2
  BOTTOM w0.254: v1(79.95,89.22) 79.95,86.68 79.44,86.17 76.14,86.17 75.24,87.07 PR122.1
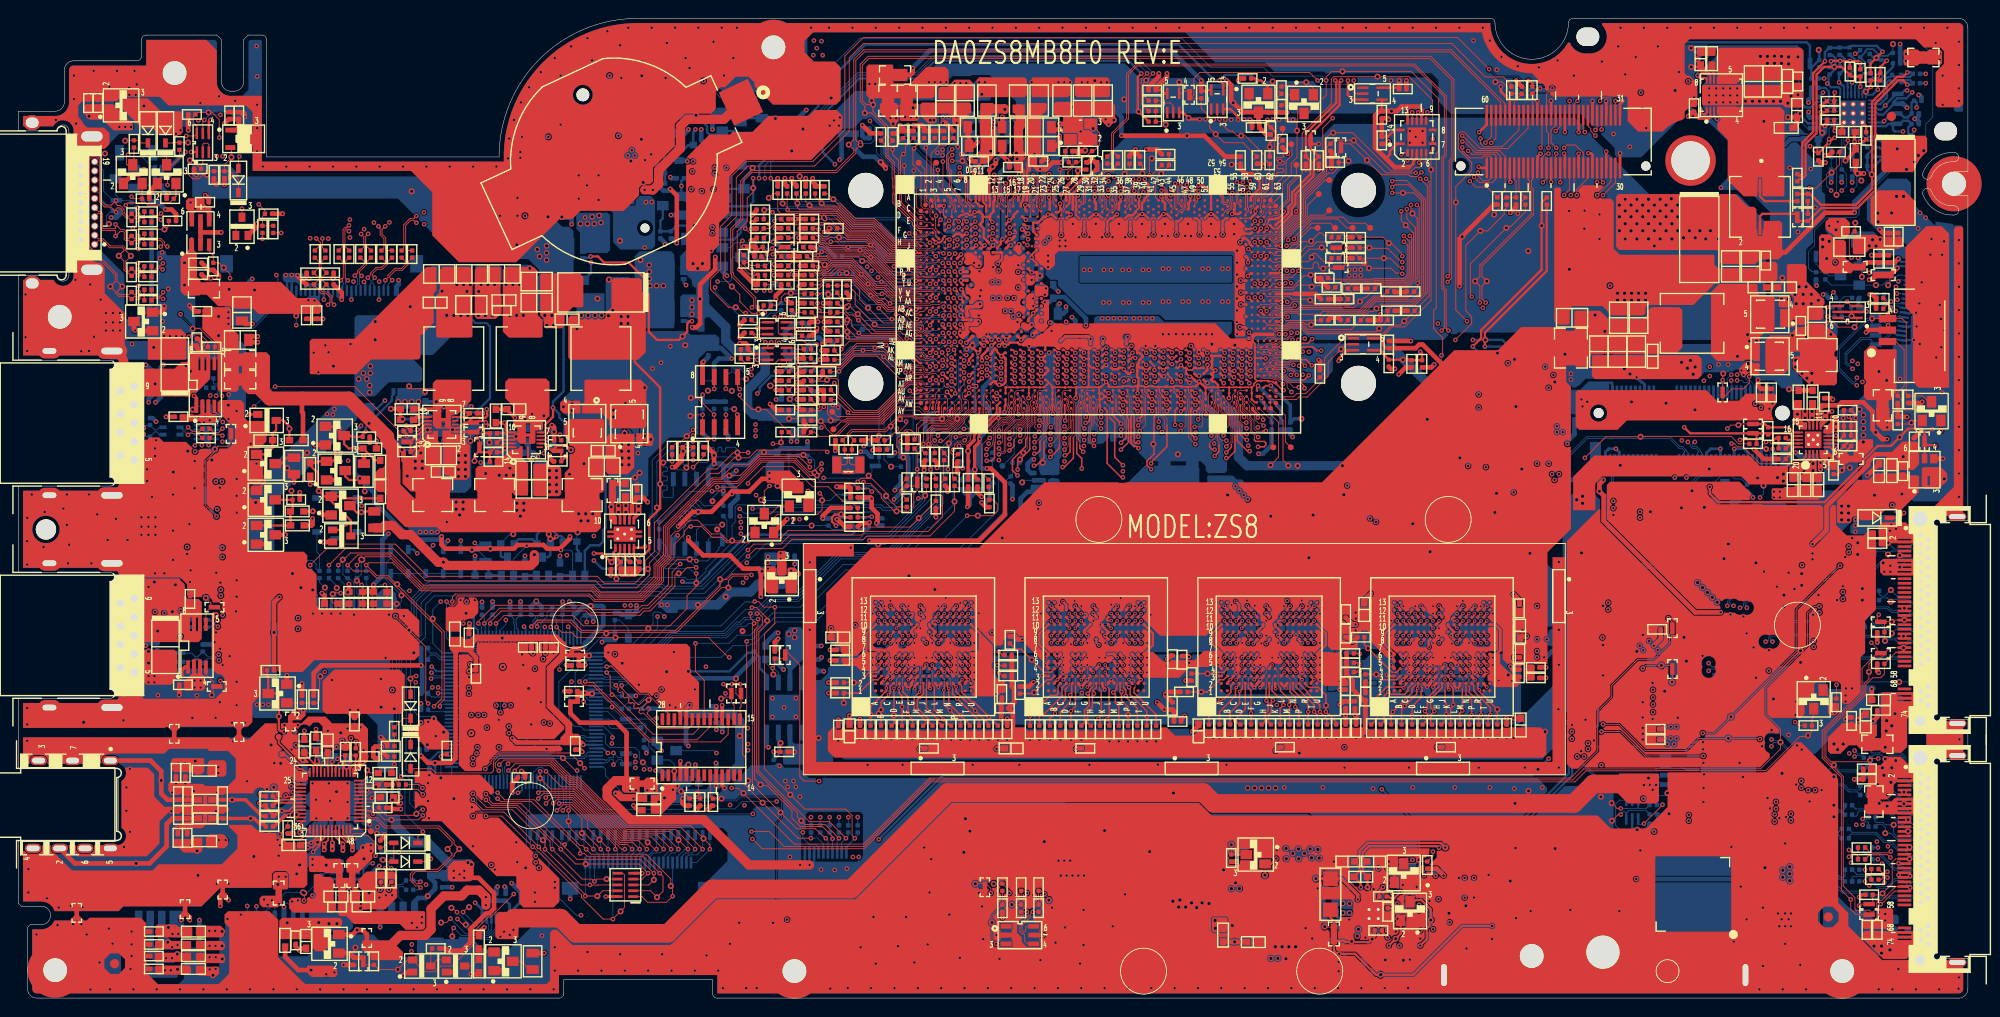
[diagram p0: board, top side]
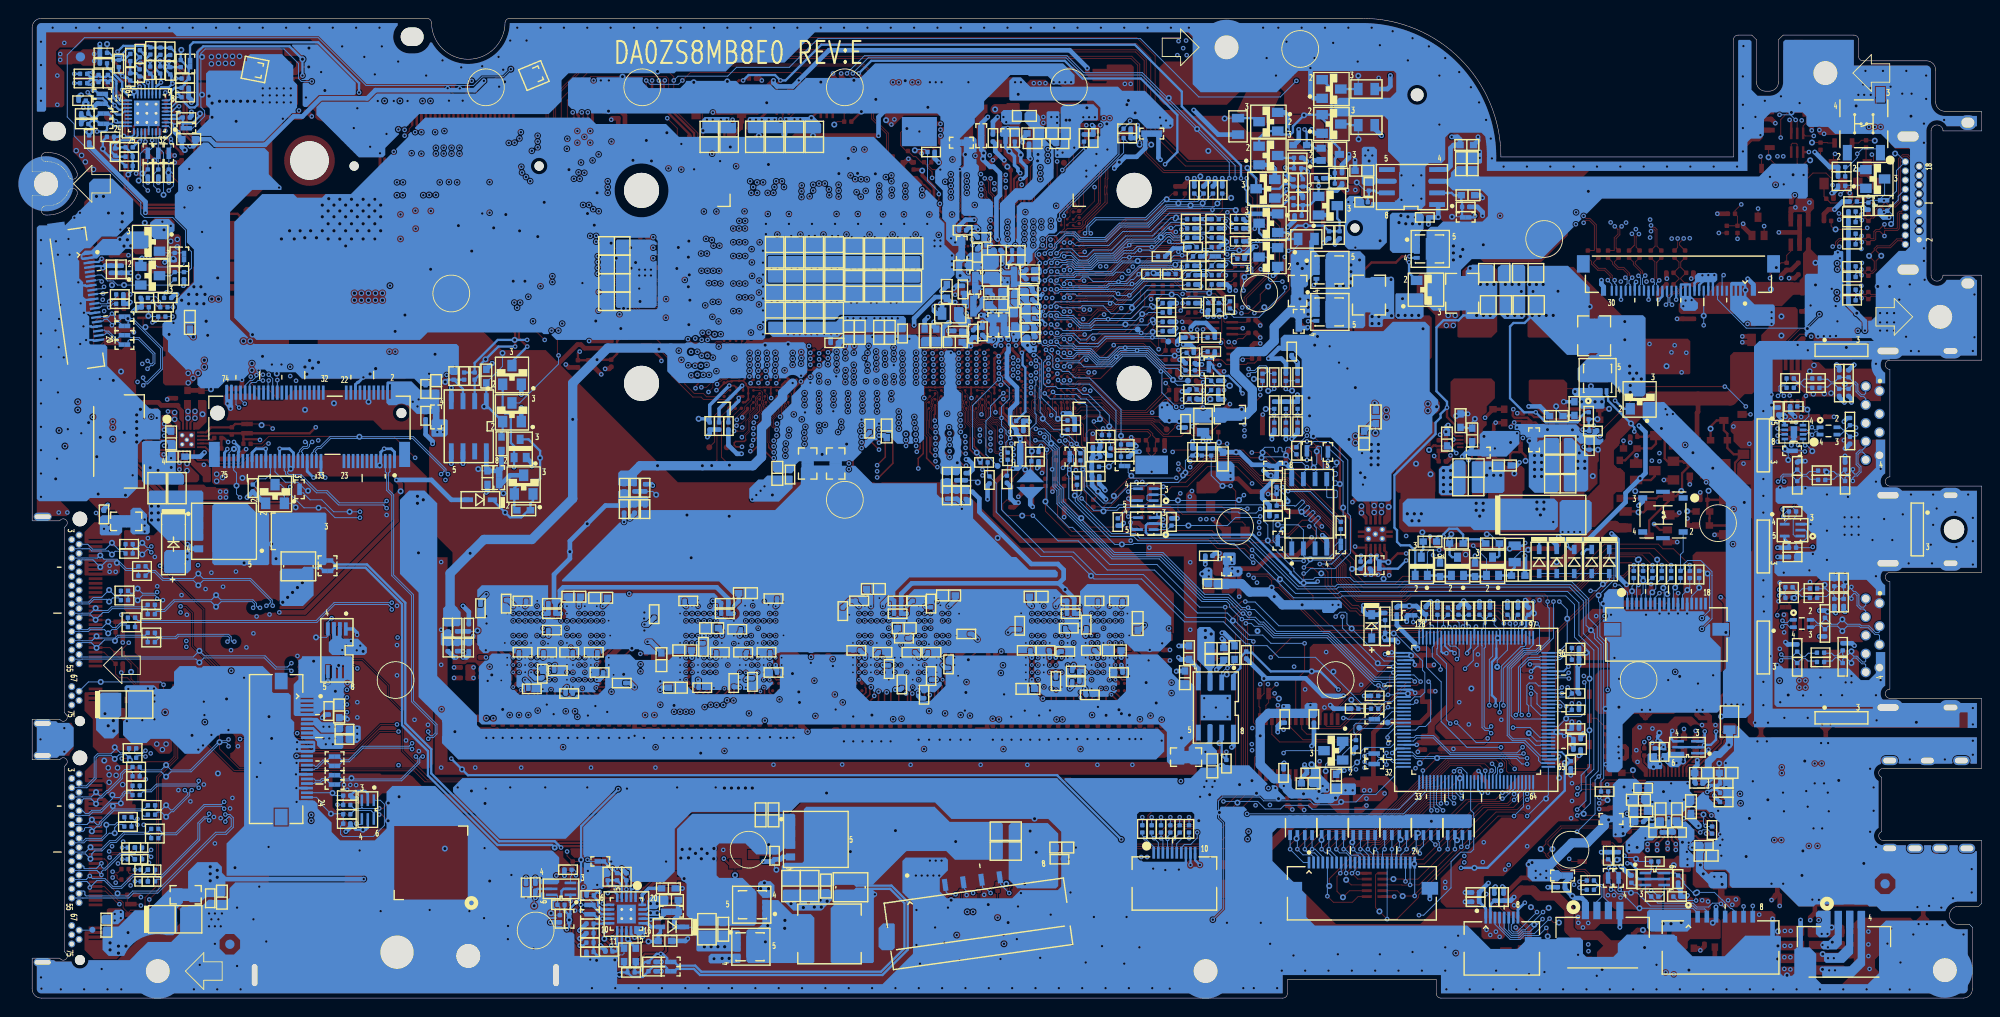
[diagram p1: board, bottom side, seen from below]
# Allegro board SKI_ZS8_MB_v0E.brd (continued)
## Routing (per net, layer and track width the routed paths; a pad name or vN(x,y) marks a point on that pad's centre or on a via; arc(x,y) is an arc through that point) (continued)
MX0: length 36.7
  TOP w0.102: v1(52.14,22.35) 52.9,21.59 56.12,21.59 61.1,16.61 61.37,16.61 v1(61.77,16.21) 62.32,15.66 68.29,15.66 70.98,12.98 v2(70.98,12.21) 71.18,12 v1(71.18,11.09) 70.52,10.43 68.47,10.43 67.84,11.05 RP1.1
  BOTTOM w0.102: U23.58 51.19,22.8 51.64,22.35 v1(52.14,22.35) ; v1(61.77,16.21) 61.52,16.46 CP2.8 ; CN16.5 v1(71.18,11.09)
MX1: length 33
  TOP w0.102: v1(52.14,21.71) 52.46,21.39 55.8,21.39 61.12,16.19 v1(61.12,15.74) 61.58,15.74 61.88,15.43 67.93,15.43 v1(69.77,13.59) 70.13,13.23 70.13,11.62 v2(69.48,10.97) 68.77,11.68 RP1.2
  BOTTOM w0.102: v1(69.77,13.59) 69.68,13.68 CN16.8 ; CP2.6 60.73,16.59 61.12,16.19 v1(61.12,15.74) ; U23.59 50.79,22.8 50.98,22.61 51.08,22.61 51.98,21.71 52.13,21.71 v1(52.14,21.71)
MX2: length 29.3
  TOP w0.102: RP1.3 68.59,12.32 v2(69.14,12.87) v1(69.14,13.59) 67.62,15.1 60.77,15.1 59.43,16.44 v1(59.43,16.7) 59.35,16.78 59.09,16.78 54.69,21.18 51.59,21.18 51.28,21.49 51.28,21.79 v1(50.87,22.2)
  BOTTOM w0.102: U23.60 50.39,22.68 v1(50.87,22.2) ; CP2.4 59.92,17.17 59.45,16.7 v1(59.43,16.7) ; CN16.9 69.18,13.63 v1(69.14,13.59)
MX3: length 28.1
  TOP w0.102: RP1.4 67.87,12.95 v1(68.5,13.59) 67.5,14.59 v2(61.74,14.59) 60.61,14.59 v1(59,16.21) 59,16.29 54.31,20.98 51.45,20.98 v1(50.87,21.56)
  BOTTOM w0.102: CP2.2 59.13,17.07 59,16.94 v1(59,16.21) ; CN16.11 68.18,13.91 v1(68.5,13.59) ; v1(50.87,21.56) 50.46,21.97 50.46,22.18 49.99,22.65 U23.61
MX4: length 36.6
  TOP w0.102: v1(50.87,19.81) 52.6,19.81 v1(55.96,16.46) 56.04,16.46 61.28,11.22 61.28,10.94 63.62,8.6 v1(64.68,8.6) v2(65.52,9.44) 65.94,9.86 65.94,13.41 65.76,13.59 RP1.6
  BOTTOM w0.102: v1(55.96,16.46) 55.7,16.71 CP1.2 ; U23.62 49.59,22.77 49.85,22.51 49.85,20.83 v1(50.87,19.81) ; CN16.18 v1(64.68,8.6)
MX5: length 25.1
  TOP w0.102: RP1.7 v2(64,12.95) 62.93,12.95 v1(62.68,12.7) 62.64,12.7 62.4,12.94 61.35,12.94 v1(58.09,16.21) 57.85,16.44 57.85,17.07 57.55,17.37 57.55,17.38 57.27,17.66 57.26,17.66 54.17,20.75 50.93,20.75 v1(49.44,22.23)
  BOTTOM w0.102: v1(58.09,16.21) CP1.8 ; CN16.22 v1(62.68,12.7) ; U23.63 49.19,22.49 v1(49.44,22.23)
MX6: length 26.2
  TOP w0.102: v1(49.44,21.59) 50.54,20.5 53.75,20.5 v2(57.07,17.18) 57.3,16.94 v1(57.3,16.21) 58.83,14.71 61.21,12.32 v1(62.18,12.32) 62.21,12.29 63.04,12.29 63.07,12.32 RP1.8
  BOTTOM w0.102: U23.64 48.79,22.24 v1(49.44,21.59) ; CN16.23 v1(62.18,12.32) ; CP1.6 v1(57.3,16.21)
MX7: length 31.4
  TOP w0.102: v1(49.44,19.81) 49.88,20.24 52.83,20.24 v1(56.62,16.46) 56.79,16.29 56.79,16.15 61.68,11.25 v1(61.68,11.11) 62.98,11.11 v2(62.99,11.1) 63.58,11.68 RP1.9
  BOTTOM w0.102: v1(61.68,11.11) 61.68,11.12 CN16.24 ; v1(49.44,19.81) 47.14,22.12 U23.65 ; CP1.4 56.49,16.59 v1(56.62,16.46)
MY0: length 11.9
  TOP w0.102: v1(62.56,16.21) 61.53,17.24 61.28,17.24 59.87,18.65 v2(59.87,19.24) v1(59.87,20.42)
  BOTTOM w0.102: U23.36 59.99,20.49 v1(59.87,20.42) ; CP3.2 v1(62.56,16.21) 63.18,15.59 CN16.21
MY1: length 13.5
  TOP w0.102: v1(59.23,20.42) 59.64,20.83 60.04,20.83 61.31,19.56 v2(61.31,17.95) 61.61,17.95 v1(63.35,16.21)
  BOTTOM w0.102: CP3.4 v1(63.35,16.21) 63.68,15.87 CN16.20 ; U23.37 59.59,20.78 v1(59.23,20.42)
MY2: length 14.8
  TOP w0.102: v1(64.16,16.21) 64.16,16.29 v2(63.21,17.24) 61.94,18.51 61.94,19.32 60.21,21.05 59.26,21.05 58.64,20.42 v1(58.6,20.42)
  BOTTOM w0.102: U23.38 59.19,22.72 59.31,22.61 59.31,21.09 58.99,20.78 58.95,20.78 v1(58.6,20.42) ; CN16.19 64.18,16.19 v1(64.16,16.21) CP3.6
MY3: length 13.9
  TOP w0.102: v1(58.83,21.18) 58.92,21.28 60.27,21.28 64.95,16.6 v1(64.95,16.21)
  BOTTOM w0.102: v1(58.83,21.18) 58.79,21.22 U23.39 ; CP3.8 v1(64.95,16.21) 65.18,15.97 CN16.17
MY4: length 15.7
  TOP w0.102: v1(58.19,21.21) 58.62,21.64 60.19,21.64 65.63,16.21 v1(65.99,16.21)
  BOTTOM w0.102: U23.40 58.39,21.41 v1(58.19,21.21) ; CP4.2 v1(65.99,16.21) 65.68,15.9 CN16.16
MY5: length 17.8
  TOP w0.102: v1(57.4,21.18) 58.06,21.84 60.28,21.84 65.39,16.73 65.73,16.73 65.9,16.73 66.25,16.73 v1(66.78,16.21)
  BOTTOM w0.102: CP4.4 v1(66.78,16.21) 66.18,15.61 CN16.15 ; v1(57.4,21.18) 57.99,21.77 U23.41
MY6: length 18
  TOP w0.102: v1(67.59,16.21) 66.86,16.93 66.32,16.93 65.98,16.93 65.98,16.93 65.81,16.93 65.65,16.93 65.48,16.93 60.36,22.05 57.61,22.05 v1(57.38,21.82)
  BOTTOM w0.102: U23.42 57.59,22.03 v1(57.38,21.82) ; CP4.6 v1(67.59,16.21) 67.35,16.21 66.68,15.53 CN16.14
MY7: length 20.3
  TOP w0.102: v1(68.38,16.21) 67.45,17.13 66.57,17.13 66.24,17.13 65.9,17.13 65.73,17.13 65.56,17.13 60.42,22.28 57.12,22.28 v1(56.57,21.72)
  BOTTOM w0.102: CN16.13 67.18,15.39 67.58,15.79 67.96,15.79 v1(68.38,16.21) CP4.8 ; v1(56.57,21.72) 57.19,22.34 U23.43
MY8: length 21
  TOP w0.102: v1(56.57,22.35) 56.72,22.5 60.48,22.5 65.65,17.34 65.81,17.34 66.15,17.34 66.49,17.34 68.09,17.34 v2(68.47,16.96) 69.22,16.21 v1(69.42,16.21)
  BOTTOM w0.102: U23.44 56.79,22.58 v1(56.57,22.35) ; CN16.12 67.68,15.38 67.85,15.55 68.58,15.55 69.23,16.21 v1(69.42,16.21) CP5.2
MY9: length 22.8
  TOP w0.102: v1(56.77,24.68) 56.77,24.32 56.76,24.31 v2(56.76,23.92) 57.92,22.76 60.51,22.76 65.73,17.54 66.07,17.54 66.4,17.54 66.4,17.54 68.87,17.54 v1(70.21,16.21)
  BOTTOM w0.102: CN16.10 68.68,15.37 69.11,15.8 69.83,15.8 70.21,16.17 v1(70.21,16.21) CP5.4 ; U23.45 56.39,24.3 v1(56.77,24.68)
MY10: length 23.3
  TOP w0.102: v1(57.4,24.68) 59.07,23.01 60.55,23.01 65.81,17.74 65.98,17.74 66.32,17.74 69.48,17.74 v1(71.02,16.21)
  BOTTOM w0.102: CP5.6 v1(71.02,16.21) 70.18,15.37 CN16.7 ; U23.46 55.99,24.5 56.58,25.09 57,25.09 v1(57.4,24.68)
MY11: length 26.7
  TOP w0.102: v1(54,24.74) 54.56,25.3 57.84,25.3 59.89,23.24 60.6,23.24 65.9,17.95 66.23,17.95 66.24,17.95 70.06,17.95 v1(71.81,16.21)
  BOTTOM w0.102: CN16.6 70.68,15.41 71.07,15.8 71.4,15.8 v1(71.81,16.21) CP5.8 ; v1(54,24.74) 53.99,24.73 U23.51
MY12: length 28.7
  TOP w0.102: v1(53.31,24.77) 54.05,25.5 57.92,25.5 59.98,23.44 60.69,23.44 65.98,18.15 66.15,18.15 70.88,18.15 v2(71.82,17.21) 72.83,16.21 v1(72.85,16.21)
  BOTTOM w0.102: CN16.4 71.68,15.37 72.52,16.21 v1(72.85,16.21) CP6.2 ; v1(53.31,24.77) 53.59,24.49 U23.52
MY13: length 30.7
  TOP w0.102: v1(53.26,25.5) 53.47,25.7 58,25.7 60.06,23.65 60.77,23.65 66.07,18.35 71.49,18.35 v1(73.63,16.21)
  BOTTOM w0.102: v1(53.26,25.5) 52.88,25.12 52.88,24.61 53.19,24.3 U23.53 ; CN16.3 72.18,15.41 72.57,15.8 73.29,15.8 73.63,16.14 v1(73.63,16.21) CP6.4
MY14: length 32.7
  TOP w0.102: v1(74.45,16.21) 72.1,18.56 66.15,18.56 60.86,23.85 60.15,23.85 58.09,25.91 52.83,25.91 v1(52.32,25.4)
  BOTTOM w0.102: CN16.2 72.68,15.35 72.91,15.59 73.83,15.59 v1(74.45,16.21) CP6.6 ; v1(52.32,25.4) 52.68,25.04 52.68,24.41 52.79,24.3 U23.54
MY15: length 34.4
  TOP w0.102: v1(52.27,24.74) 51.89,25.12 51.89,25.6 52.4,26.11 58.17,26.11 60.23,24.05 60.94,24.05 66.24,18.76 73.14,18.76 v2(74.54,17.36) 75.23,16.67 v1(75.23,16.21)
  BOTTOM w0.102: CP6.8 v1(75.23,16.21) 73.78,14.75 CN16.1 ; v1(52.27,24.74) 52.39,24.62 U23.55
NBSWON#: length 284.2
  TOP w0.102: v1(183.33,26.36) 176.97,26.36 174.32,29.01 v1(172.24,29.01) ; CN1.51 164.25,94.66 162.05,92.46 159.07,92.46 157.27,94.26 156.93,94.26 156.67,94 156.67,92.38 158.12,90.93 158.12,90.04 156.39,88.32 v2(156.39,86.6) 156.39,74.88 v1(157.61,73.66)
  IN1 w0.114: v1(78.84,45.21) 77.2,45.21 71.86,39.88 64.63,39.88 64.42,40.09 61.13,40.09 60.78,40.44 59.84,40.44 v1(59.82,40.41) 59.31,39.9 30.71,39.9 v1(30.43,40.18) ; v1(172.24,29.01) 171.78,29.47 171.78,55.53 157.61,69.7 v1(157.61,73.66)
  IN3 w0.102: v1(172.24,29.01) 172.24,26.95 166.09,20.8 133.49,20.8 132.36,21.94 85.92,21.94 85.31,22.55 83.23,22.55 80.98,24.8 80.98,36.3 79.88,37.39 79.88,39.5 78.59,40.8 78.59,44.96 v1(78.84,45.21)
  BOTTOM w0.102: v1(183.33,26.36) 183.32,26.35 CN12.14 ; U23.125 59.99,40.24 v1(59.82,40.41) ; v1(30.43,40.18) 29.34,41.27 29.34,46 29.33,46 29.33,46.4 30.56,47.62 32,47.62 32.38,47.24 32.38,46.74 32.63,46.49 R495.1 32.77,48.26 32.47,48.55 SW2.2
NGFF0_DET_C: length 19.4
  TOP w0.102: R86.2 81.23,79.53 81.47,79.29 83.36,79.29 R87.2 84.17,80.1 87.29,80.1 87.51,79.87 v1(87.75,79.87) 88,79.87 88.39,80.26 90.69,80.26 93.41,77.54 94.27,77.54 95.19,76.62 95.84,76.62 95.86,76.63 97.89,76.63 97.93,76.67 98.11,76.67 U6.V1
NGFF0_PEDET: length 1.5
  BOTTOM w0.102: CN13.69 205.59,7.39 TP24.1
NGFF1_DET_C: length 24
  TOP w0.102: v1(78.78,82.41) 78.53,82.16 78.53,81.27 78.93,80.86 R85.2 79.52,80.26 80.4,80.26 R80.2 81.1,80.46 82.36,80.46 82.49,80.58 82.49,80.86 82.74,81.11 83.91,81.11 84.15,81.36 84.66,81.36 84.9,81.11 86.06,81.11 86.46,80.71 87.87,80.71 87.88,80.71 87.91,80.71 88.07,80.87 91.95,80.87 95.56,77.26 97.19,77.26 97.2,77.24 98.08,77.24 U6.U1
NGFF1_RST#: length 42.2
  TOP w0.102: 201.75,9.2 201.39,9.57 199.96,9.57 199.81,9.72 199.81,10.94 198.54,12.21 198.54,24.11 196.46,26.19 196.46,29 199.12,31.66 199.35,31.66 200.8,33.11 200.8,34.21 201.34,34.75 v2(201.34,35.5) 201.34,36.36 202,37.02 202.63,37.02 203.02,37.41 R205.1 203.63,38.14 CN10.50 ; 201.75,9.2 R315.1 ; 201.75,9.2 201.75,9.37 202.2,9.82 202.2,10.39 202.44,10.63 202.73,10.63 204.24,12.14 CN13.50
NGFF2_DET_C: length 19.7
  TOP w0.102: v1(101.26,77.14) 101.47,76.93 U6.V6
  BOTTOM w0.102: R376.2 84.17,79.08 85.91,79.08 R377.2 86.97,78.02 91.18,78.02 v1(92.73,76.47) 93.85,76.47 94.29,76.91 100.28,76.91 100.47,76.72 100.83,76.72 v1(101.26,77.14)
NGFF3_DET: length 197.8
  TOP w0.102: v1(79.78,79.32) 79.43,79.32 78.93,79.82 R85.1 79.31,80.07 79.65,79.73 80.41,79.73 R86.1 ; Q16.3 195.33,30.6 195.15,30.42 R229.1 195.15,29.03 v2(194.71,28.59) 194.58,28.46 193.82,28.46 190.11,24.76 178.24,24.76 178.22,24.74 170.56,24.74 169.36,23.54 99.29,23.54 92.01,16.26 80.92,16.26 v1(79.86,17.31)
  IN3 w0.102: v1(79.86,17.31) 79.58,17.31 74.17,22.72 74.17,51.71 73.81,52.07 73.81,62.02 73.05,62.78 73.05,67.2 74.94,69.08 74.94,70.47 76.5,72.04 76.5,76.08 79.75,79.32 v1(79.78,79.32)
  BOTTOM w0.102: R376.1 82.56,79.11 79.99,79.11 v1(79.78,79.32)
NGFF3_DET_C: length 203
  TOP w0.102: v1(172.41,29.78) 174.18,29.78 177.03,26.94 181.5,26.94 182.82,28.26 v2(186.04,28.26) 189.42,28.26 v1(189.48,28.19) ; v1(81.15,77) 81.23,77.08 R97.2 82.26,77.66 82.67,78.07 87.38,78.07 87.74,78.43 90.79,78.43 93.52,75.7 93.84,75.7 94.6,74.95 95.16,74.95 95.23,75.01 95.84,75.01 95.86,74.99 96.14,74.99 96.16,74.97 96.23,74.97 96.87,74.33 98.16,74.33 U6.AC1 ; R229.2 193.69,29.66 v1(193.31,30.04)
  IN1 w0.114: v1(193.31,30.04) 190.92,30.04 189.48,28.6 v1(189.48,28.19)
  IN3 w0.102: v1(172.41,29.78) 172.86,29.33 172.86,26.74 166.73,20.6 133.38,20.6 132.25,21.73 85.79,21.73 85.21,22.32 82.87,22.32 80.33,24.86 80.33,27.52 78.94,28.91 78.94,29.56 80.57,31.18 80.57,36.13 78.18,38.52 78.18,38.83 77.93,39.08 77.93,49.2 79.02,50.29 79.02,53.35 77.83,54.55 77.83,55.99 77.29,56.52 77.29,59.99 77.83,60.52 77.83,61.42 77.39,61.86 77.39,68.81 78,69.43 78,69.84 79.1,70.94 79.1,73.81 78.71,74.19 78.71,75.27 80.02,76.58 80.73,76.58 v1(81.15,77)
NGFF3_PEDET: length 13.1
  TOP w0.102: Q16.2 197.28,32.59 R227.2 v1(197.81,34.1)
  BOTTOM w0.102: v1(197.81,34.1) 198.11,34.41 v2(204.64,34.41) 205.98,34.41 CN10.69
NOA_STBN_0: length 46.1
  TOP w0.076: U6.AA62 136.46,75.43 136.94,75.43 137.17,75.2 137.46,75.2 137.54,75.12
  TOP w0.102: v1(138.87,75.39) 138.6,75.12 137.54,75.12 ; CN1.28 173.25,88.85 v1(171.78,87.38)
  IN1 w0.114: v1(171.78,87.38) 171.02,86.61 168.66,86.61 163.66,81.61 153.95,81.61 153.95,81.61 151.28,81.61 151.1,81.43 149.53,81.43 148.21,80.11 148.21,77.41 146.44,75.65 139.13,75.65 v1(138.87,75.39)
NOA_STBN_1: length 41.4
  TOP w0.102: U6.U63 136.86,77.34 137.38,77.34 v1(137.85,77.81) ; v1(168.18,87.4) 168.76,87.98 CN1.19
  IN1 w0.114: v1(168.18,87.4) 162.84,82.07 153.76,82.07 153.76,82.07 151.09,82.07 150.91,81.89 149.34,81.89 147.7,80.25 147.7,77.72 146.35,76.38 145.96,76.38 145.07,77.27 138.38,77.27 v1(137.85,77.81)
NOA_STBP_0: length 47.5
  TOP w0.102: CN1.29 173.76,88.72 v1(172.42,87.38) ; U6.AA61 135.51,75.06 v1(135.81,74.76)
  IN1 w0.114: v1(135.81,74.76) 135.98,74.93 139.19,74.93 139.68,75.42 146.54,75.42 148.66,77.54 148.66,80.24 149.63,81.2 151.2,81.2 151.37,81.38 154.05,81.38 154.05,81.38 163.76,81.38 168.73,86.36 171.4,86.36 v1(172.42,87.38)
NOA_STBP_1: length 42.9
  TOP w0.102: v1(168.9,87.4) 169.25,87.76 CN1.20 ; v1(137.2,77.76) 136.54,77.76 U6.U62
  IN1 w0.114: v1(137.2,77.76) 137.92,77.04 144.98,77.04 145.87,76.15 146.62,76.15 147.95,77.48 147.95,80.18 149.44,81.66 151.01,81.66 151.19,81.84 153.86,81.84 153.86,81.84 163.34,81.84 v1(168.9,87.4)
OPI_COMP1: length 9
  TOP w0.254: 104.5,60.44 104.5,61.27 106.81,63.58 U6.AY15
  TOP w0.381: 104.5,60.44 104.05,60 v2(104.05,57.52) 104.05,56.74 R187.2
OPI_COMP2: length 9.8
  TOP w0.229: 106.43,63.69 106.43,64.46 U6.AW15
  TOP w0.254: 104,60.72 104,61.26 106.43,63.69
  TOP w0.381: R186.2 v2(103.33,59.53) 103.33,60.05 104,60.72
PC_BEEP: length 5
  TOP w0.102: R287.1 40.92,29.47 41.9,30.45 D8.1 v2(42.67,29.15) D9.1
PCBEEP: length 3.1
  TOP w0.102: U16.12 37.51,23.66 37.94,24.09 v2(37.94,24.81) 38.23,24.51 C136.1
PCBEEP_EC: length 21.7
  TOP w0.102: D9.2 44.96,24.97 45.42,24.51 51.49,24.51 51.69,24.71 51.69,25.78 52.32,26.42 58.96,26.42 v2(59.25,26.13) 60.61,24.77 v1(60.79,24.77)
  BOTTOM w0.102: U23.34 v1(60.79,24.77)
PCBEEP_R: length 4.3
  TOP w0.102: C136.2 40.61,24.82 40.9,25.1 v1(40.9,25.44) C134.1 R291.2 40.9,28.68 R287.2
PCH_ACPRESENT: length 21.3
  TOP w0.102: v1(102.51,71.42) 102.51,71.21 U6.AJ8
  BOTTOM w0.102: R416.2 R417.2 R418.2 87.2,68.9 88.85,68.9 90.63,70.69 93.78,70.69 94.95,69.52 96.03,69.52 96.99,70.48 98.69,70.48 98.93,70.72 100.34,70.72 100.63,71.02 v5(101.56,71.02) 102.1,71.02 v1(102.51,71.42)
PCH_AZ_CODEC_BITCLK: length 99.4
  TOP w0.102: R180.2 100.65,58.48 100.65,56.71 C70.1 100.3,55.99 100.3,54.84 100.53,54.61 100.53,52.35 98.96,50.77 92.12,50.77 91.74,50.39 83.93,50.39 82.94,49.4 80.01,49.4 v1(79.38,48.77) ; v1(44.01,20.51) 43.75,20.51 v2(43.29,20.05) 43.13,19.89 40.05,19.89 C143.1 39.23,21.04 38.96,21.31 37.67,21.31 37.62,21.26 U16.6
  BOTTOM w0.102: v1(44.01,20.51) 43.05,21.47 43.05,24.05 42.19,24.92 42.19,37.87 43.81,39.49 43.81,43.03 45.04,44.25 69.78,44.25 69.99,44.04 74.65,44.04 v1(79.38,48.77)
PCH_AZ_CODEC_RST#: length 98.8
  TOP w0.102: v1(44.01,18.1) 43.46,17.56 D14.1 ; v1(41.66,24.12) 41.39,23.85 R295.2 40.9,23.74 39.73,23.74 C140.1 39.03,23.44 37.72,23.44 37.54,23.26 U16.11
  BOTTOM w0.102: R457.2 97.98,58.45 97.98,54.89 98.32,54.55 98.32,54.21 94.66,50.55 92.08,50.55 91.59,50.06 79.57,50.06 74.33,44.82 70.31,44.82 70.1,45.02 44.71,45.02 43.04,43.35 43.04,40.58 v2(42.5,40.04) 42.11,39.65 42.11,39.15 41.41,38.45 41.41,24.36 v1(41.66,24.12) 42.05,23.72 42.05,20.06 v1(44.01,18.1)
PCH_AZ_CODEC_SDIN0: length 96.7
  TOP w0.076: U6.AY10 103.71,64.19 102.6,63.08 102.6,62.85 101.79,62.04 101.68,62.04 101.31,61.67 100.51,61.67 v1(100.06,61.22)
  BOTTOM w0.102: v1(100.06,61.22) 99.33,61.22 97.64,59.54 97.64,55.33 95.69,53.38 94.2,53.38 93.89,53.68 78.23,53.68 77.98,53.43 77.98,51.82 77.66,51.5 v2(77.66,49.8) 77.66,49.59 74.83,46.76 74.83,46.46 73.94,45.57 72.72,45.57 72.52,45.77 68.72,45.77 68.27,45.31 44.59,45.31 42.75,43.47 42.75,41.35 41.82,40.42 41.82,39.27 41.12,38.58 41.12,23.91 41.41,23.62 R549.1
PCH_AZ_CODEC_SDIN0_C: length 7.1
  TOP w0.102: U16.8 37.97,22.06 38.34,22.43 41.33,22.43 41.61,22.15 v1(41.61,21.84)
  BOTTOM w0.102: R549.2 40.63,21.63 v2(40.71,21.55) 41.32,21.55 v1(41.61,21.84)
PCH_AZ_CODEC_SDOUT: length 94.7
  TOP w0.102: v1(44.01,19.88) 43.54,19.41 v2(40.58,19.41) 39.83,19.41 38.37,20.86 U16.5
  BOTTOM w0.102: v1(44.01,19.88) 43.88,19.88 42.57,21.19 42.57,23.85 41.71,24.71 41.71,38.07 43.33,39.69 43.33,43.23 44.84,44.73 69.98,44.73 70.19,44.53 74.45,44.53 79.69,49.77 91.78,49.77 92.25,50.24 94.76,50.24 98.62,54.09 98.62,54.67 98.42,54.86 R470.2
PCH_AZ_CODEC_SYNC: length 94.1
  TOP w0.102: v1(79.37,48.08) 80.21,48.92 83.14,48.92 84.13,49.91 91.94,49.91 92.32,50.29 99.16,50.29 101.85,52.99 v2(101.85,54.04) R185.2 ; U16.10 37.59,22.86 37.84,23.11 38.71,23.11 39.1,22.72 43.45,22.72 v1(44.01,22.16)
  BOTTOM w0.102: v1(79.37,48.08) 74.85,43.56 69.79,43.56 69.58,43.76 45.24,43.76 44.3,42.83 44.3,39.29 42.67,37.67 42.67,25.15 43.56,24.26 43.56,22.61 v1(44.01,22.16)
PCH_BATLOW#: length 23.7
  TOP w0.102: v1(100.56,68.81) 100.56,68.74 U6.AN4
  IN3 w0.102: v1(100.56,68.81) 99.94,68.2 97.92,68.2 97.61,68.5 96.35,68.5 96.11,68.27 96.11,64.85 93.97,62.7 89.57,62.7 88.39,63.88 87.45,63.88 v1(87,64.34)
  BOTTOM w0.102: v1(87,64.34) 87,64.4 R429.2 85.78,64.69 84.29,64.69 R428.2
PCH_I2C1_CLK: length 394.9
  TOP w0.102: v1(196.82,74.17) 197.97,73.02 v2(199.77,73.02) 200.03,73.28 Q8.1 ; U6.F1 98.05,83.52 97.89,83.52 97.28,84.12 97.28,84.39 95.14,86.53 95.14,87.44 95.15,87.51 95.17,87.61 95.17,88.19 95.15,88.3 95.14,88.36 95.14,89.1 95.06,89.18 95.06,90.87 94.39,91.54 94.39,92.79 R24.2 94.39,93.86 94.39,94.77 92.83,96.33 v2(92.09,96.33) 92.09,97.07 91.59,97.57 91.59,101.63 92.46,102.49 153.67,102.49 156.18,99.97 156.18,91.35 155.91,91.07 155.91,78.33 v1(155.5,77.93)
  IN1 w0.114: v1(38.86,15.49) 38.42,15.49 37.46,14.54 37.46,10.78 41.15,7.1 41.15,6.31 41.88,5.58 42.53,5.58 v1(42.8,5.84) ; v1(155.5,77.93) 155.92,78.35 167.2,78.35 168.11,79.26 196.24,79.26 196.81,78.69 196.81,76.03 196.34,75.56 196.34,74.91 196.82,74.43 v1(196.82,74.17) 197.1,74.17 197.23,74.04 197.23,71.18 198.54,69.87 199.94,69.87 201.77,68.05 201.77,59.34 197.3,54.87 197.3,46.66 192.09,41.45 192.09,38.79 190.71,37.4 188.04,37.4 181.72,31.08 181.72,25.98 174.91,19.17 173.51,19.17 172.05,17.7 132.34,17.7 130.81,16.18 130.81,14.68 129.51,13.38 117.94,13.38 117.22,14.1 112.86,14.1 112.14,13.38 85.54,13.38 84.01,14.91 57.02,14.91 56.78,15.15 56.6,15.15 v1(56.29,15.47)
  IN3 w0.102: v1(56.29,15.47) 56.06,15.24 55.76,15.24 55.08,14.56 55.08,11.41 49.08,5.41 44.05,5.41 43.82,5.64 43,5.64 v1(42.8,5.84)
  BOTTOM w0.102: v1(38.86,15.49) 38.67,15.31 37.72,15.31 37.28,14.86 R571.2 35.95,13.81 36.15,13.6 Q25.1 ; R400.2 v1(196.82,74.17)
PCH_I2C1_DAT: length 386.7
  TOP w0.102: U6.G4 99.82,82.94 99.82,83.4 99.48,83.74 97.98,83.74 97.5,84.23 97.5,84.49 95.37,86.62 95.37,87.42 95.38,87.46 95.4,87.59 95.4,88.22 95.38,88.34 95.37,88.39 95.37,89.2 95.29,89.27 95.29,90.96 94.61,91.64 94.61,92.82 R25.2 94.61,93.83 94.61,94.87 94.3,95.19 92.99,96.5 92.99,97.22 v2(92.99,97.23) 92.26,97.23 91.82,97.67 91.82,101.53 92.55,102.26 153.58,102.26 155.96,99.88 155.96,91.44 155.68,91.16 155.68,78.74 v1(155.5,78.56) ; v1(196.77,75.18) 196.8,75.18 196.94,75.33 Q8.4
  IN1 w0.114: v1(155.5,78.56) 155.52,78.59 167.1,78.59 168.01,79.5 196.34,79.5 197.05,78.79 197.05,75.46 v1(196.77,75.18) 196.77,74.84 197.47,74.14 197.47,71.28 198.64,70.11 200.04,70.11 202.01,68.15 202.01,59.24 197.54,54.77 197.54,46.56 192.33,41.35 192.33,38.69 190.81,37.16 188.14,37.16 181.97,30.98 181.97,25.88 175.01,18.93 173.61,18.93 172.15,17.46 132.44,17.46 131.06,16.08 131.06,14.58 129.61,13.14 117.84,13.14 117.12,13.86 112.96,13.86 112.24,13.14 85.44,13.14 83.91,14.67 56.92,14.67 56.68,14.91 56.43,14.91 v1(56.29,14.77) ; v1(35.96,11.71) 36.19,11.71 40.91,7 40.91,6.21 41.78,5.33 42.55,5.33 v1(42.77,5.11)
  IN3 w0.102: v1(42.77,5.11) 43.08,5.41 43.73,5.41 43.96,5.18 49.17,5.18 55.31,11.32 55.31,14.47 55.85,15.01 56.05,15.01 v1(56.29,14.77)
  BOTTOM w0.102: Q25.4 34.54,11.41 34.9,11.05 R581.2 35.84,11.71 v1(35.96,11.71) ; v1(196.77,75.18) R397.2
PCH_INTVRMEN: length 9
  TOP w0.076: U6.AV7 102.35,65.37 102.6,65.11 102.6,64.06 102.11,63.57 102.11,63.05 101.59,62.53 101.35,62.53 100.98,62.17 99.5,62.17 99.04,61.71 99.04,60.5 99.35,60.2
  TOP w0.102: 99.35,60.2 99.35,60.03 99.69,59.69 R179.1
PCH_PWRBTN#: length 18.3
  TOP w0.102: U6.AL7 101.93,70.43 v1(101.8,70.55)
  BOTTOM w0.102: R464.2 R455.2 R445.2 v2(93.63,61.18) 93.63,64.06 97.07,67.5 98.61,67.5 99.31,68.2 100,68.2 100.2,68.4 100.79,68.4 101.05,68.67 101.05,69.86 101.3,70.1 101.35,70.1 v1(101.8,70.55)
PCH_PWROK: length 178.4
  TOP w0.102: R13.1 122.17,97.33 122.17,100.04 122.76,100.63 v1(122.81,100.63) ; v1(46.58,43.15) 46.99,42.75 47.4,42.75 47.62,42.98 47.62,43.56 47.83,43.76 62.05,43.76 62.66,43.15 67.98,43.15 70.18,45.36 70.18,46.77 71.32,47.92 71.32,49.35 72.46,50.49 72.46,50.81 72.97,51.33 v1(73.15,51.33) 74.31,51.33 75.5,50.14 76.53,50.14 77.11,49.56 79.48,49.56 79.81,49.89 82.74,49.89 83.73,50.88 91.54,50.88 91.92,51.26 96.98,51.26 v2(97.96,52.24) 99.25,53.53 99.25,53.54 R191.2 R184.2
  IN3 w0.102: v1(73.15,51.33) 72.85,51.63 72.85,57.03 72.52,57.36 72.52,61.74 72.09,62.17 72.09,68.98 75.54,72.44 75.54,76.48 77.5,78.44 77.5,81 78.69,82.19 78.69,85.55 81.85,88.71 v1(81.85,89.22)
  BOTTOM w0.102: v1(46.58,43.15) 46.58,39.19 48.34,37.44 49.63,37.44 51.18,35.89 51.18,30.73 50.82,30.37 U23.78 ; v1(122.81,100.63) 122.81,100.66 121.13,102.34 99.61,102.34 97.73,100.46 91.38,100.46 81.85,90.93 v1(81.85,89.22)
PCH_RSMRST#: length 11.8
  TOP w0.076: U6.AW6 101.85,64.54 101.85,64.06 101.61,63.82 101.61,63.26 101.38,63.03 101.12,63.03 100.77,62.69 98.84,62.69 98.83,62.67
  TOP w0.102: 98.83,62.67 98.59,62.67 97.9,61.99 97.9,60.2 R172.2 97.79,59.5 v1(97.79,57.55) R182.2
PCH_SLP_A#: length 93.2
  TOP w0.102: v1(101.16,70.54) 101.09,70.47 U6.AL5 ; v1(34.8,47.12) 36.12,48.44 40.56,48.44 44.07,44.93 62.59,44.93 63.35,44.17 67.47,44.17 69.16,45.86 69.16,47.2 70.18,48.21 70.18,51.32 75.47,56.62 76.4,56.62 77.86,58.08 79.47,58.08 80.53,59.14 85.38,59.14 v2(85.41,59.11) v1(86.11,58.42)
  IN3 w0.102: v1(101.16,70.54) 101.16,70.17 100.86,69.87 100.22,69.87 100.08,69.72 98.99,69.72 98.17,68.91 96.18,68.91 95.71,68.43 95.71,65.01 94.22,63.52 90.8,63.52 87.8,66.52 86.92,66.52 86.59,66.19 86.59,63.27 86.87,62.99 86.87,59.82 86.11,59.05 v1(86.11,58.42)
  BOTTOM w0.102: R497.1 v1(34.8,47.12)
PCH_SLP_S0#: length 110.7
  TOP w0.076: U6.AF3 99.23,72.56 98.72,72.56 98.48,72.79 98.48,73.1
  TOP w0.102: v1(95.48,74.4) 95.89,74.4 97.02,73.26 98.31,73.26 98.48,73.1
  IN1 w0.114: v1(95.48,74.4) 95.19,74.1 92.28,74.1 90.75,75.63 89.21,75.63 88.53,76.31 87.78,77.06 86.2,77.06 85.68,76.54 81.58,76.54 81.54,76.57 79.14,76.57 76.57,74.01 76.57,71.28 75.69,70.39 75.69,67.18 75.28,66.78 75.28,65.81 76.42,64.67 76.42,62.48 76.47,62.43 76.47,46.18 71.31,41.02 65.13,41.02 64.29,41.87 61.04,41.87 60.8,41.62 47.72,41.62 47.24,41.15 30.63,41.15 v1(30.43,41.35)
  BOTTOM w0.102: R493.1 30.11,46.49 v2(29.82,46.2) 29.59,45.97 29.59,42.19 v1(30.43,41.35)
PCH_SLP_S5#: length 83.4
  TOP w0.102: v1(101.52,68.41) 101.45,68.41 101.13,68.09 U6.AP5 ; v1(36.83,47.12) v2(37.41,47.7) 37.74,48.03 40.36,48.03 43.86,44.53 62.42,44.53 63.18,43.76 67.73,43.76 69.57,45.61 69.57,47.03 70.59,48.04 70.59,51.15 75.64,56.21 78.17,56.21 80.7,58.74 84.58,58.74 86.04,57.28 86.5,57.28 v1(87.39,58.17)
  IN3 w0.102: v1(101.52,68.41) 101.09,67.98 101.09,67.29 100.63,66.83 100.42,66.83 97.73,64.14 96.28,64.14 94.24,62.09 90.01,62.09 87.29,59.38 87.29,58.27 v1(87.39,58.17)
  BOTTOM w0.102: R499.1 v1(36.83,47.12)
PCH_SLP_SUS#: length 97
  TOP w0.076: v1(97.16,68.1) 97.19,68.06 98.38,68.06 98.55,67.9 99.3,67.9 99.38,67.97 99.81,67.97 U6.AP4
  TOP w0.102: v1(47.22,43.15) 47.22,43.66 47.52,43.97 62.14,43.97 62.75,43.36 67.9,43.36 69.98,45.44 69.98,46.86 70.99,47.87 70.99,50.29 71.5,50.8 71.82,50.8 73.03,52.01 73.91,52.01 75.4,50.52 76.44,50.52 77.2,49.76 78.72,49.76 79.63,50.67 Q14.2 80.14,51.53 80.43,51.82 81.74,51.82 82.57,52.64 86.93,52.64 87.44,53.15 v2(87.44,54.17) 87.44,54.68 87.19,54.93 v1(87.18,54.93)
  IN3 w0.102: v1(97.16,68.1) 96.32,67.26 96.32,64.75 94.07,62.5 89.84,62.5 86.74,59.4 86.74,57.41 87.18,56.97 v1(87.18,54.93)
  BOTTOM w0.102: v1(47.22,43.15) 47.22,42.6 47.04,42.42 47.04,39.02 48.42,37.64 49.72,37.64 51.41,35.95 51.41,28.66 50.97,28.22 49.25,28.22 48.54,27.51 48.01,27.51 47.95,27.57 U23.71
PCH_SLP_WLAN#: length 18
  TOP w0.102: U6.AM5 101.09,69.53 100.77,69.84 100.77,69.89 100.49,70.17 v1(100.49,70.27)
  BOTTOM w0.102: v1(100.49,70.27) 100.49,70.14 99.95,69.6 98.86,69.6 98.38,70.07 97.16,70.07 96.2,69.11 94.77,69.11 93.6,70.28 90.8,70.28 87.65,67.13 86.41,67.13 TP22.1
PCH_SPI_CLK: length 47.2
  TOP w0.102: v1(73.41,60.58) 72.89,60.58 C68.1 R176.2 73.41,59.92 72.91,59.43 72.91,57.95 v2(72.68,57.72) ; v1(99.19,74.72) 99.19,74.84 U6.AA3
  IN1 w0.114: v1(99.19,74.72) 98.89,74.42 96.65,74.42 96.22,74.85 95.2,74.85 94.95,74.6 92.48,74.6 90.42,76.66 88.88,76.66 87.99,77.55 86,77.55 85.48,77.03 82.48,77.03 82.08,77.43 79.3,77.43 76.08,74.21 76.08,71.48 75.19,70.59 75.19,67.56 74.01,66.39 74.01,63.27 74.42,62.86 74.42,61.53 73.47,60.58 v1(73.41,60.58)
PCH_SPI_CLK_EC: length 50
  TOP w0.102: v1(51.97,40.77) 52.83,41.62 60.36,41.62 61.47,40.51 70.87,40.51 72.75,42.39 72.75,43.79 73.76,44.81 v2(73.76,45.18) v1(73.76,46.2)
  BOTTOM w0.102: U23.105 51.99,40.74 v1(51.97,40.77) ; v1(73.76,46.2) 73.56,46.2 73.02,46.74 70.36,46.74 68.66,48.44 68.66,52.46 68.96,52.77 68.96,58.55 70.99,60.58 72.65,60.58 73.28,59.95 R448.1
PCH_SPI_CLK_R: length 9.4
  TOP w0.102: R176.1 v1(73.41,58.55)
  BOTTOM w0.102: R176.1 v1(73.41,58.55) 72.95,58.55 72.85,58.45 72.85,58.12 72.75,58.01 72.44,58.01 72.34,58.12 v2(72.34,59.5) 72.34,59.94 72.24,60.05 71.93,60.05 71.83,59.94 71.83,58.65 71.63,58.45 71.63,57.61 71.73,57.51 72.24,57.51 72.52,57.23 U19.6
PCH_SPI_CS0#: length 61.9
  TOP w0.102: U6.Y7 102.12,75.83 v1(101.77,76.19)
  IN1 w0.114: v1(101.77,76.19) 101.27,75.69 100.5,75.69 100.27,75.47 98.18,75.47 97.84,75.8 97.05,75.8 96.71,76.14 92.99,76.14 90.96,78.17 89.41,78.17 88.59,79 85.1,79 84.69,79.42 81.21,79.42 80.88,79.75 79.5,79.75 74.63,74.89 74.63,72.46 72.57,70.39 72.57,57.35 75.23,54.69 75.64,54.69 75.97,54.36 75.97,51.05 v3(76.02,51)
  BOTTOM w0.102: v3(76.02,51) 76.58,50.44 R487.2 75.32,50.17 75.06,49.91 U19.1
PCH_SPI_IO2: length 58.1
  TOP w0.102: U6.Y6 101.47,75.83 v1(101.12,76.19)
  IN1 w0.114: v3(75.51,54.08) 75.26,54.08 72.25,57.09 72.25,70.52 74.31,72.59 74.31,75.25 76.58,77.52 76.58,78.88 77.45,79.75 79.05,79.75 79.36,80.07 81.78,80.07 81.98,80.27 82.77,80.27 83.17,79.87 84.62,79.87 84.86,80.12 85.33,80.12 85.45,79.99 87.25,79.99 87.92,79.32 90.26,79.32 93.12,76.46 96.84,76.46 97.19,76.12 97.97,76.12 98.31,75.78 100.14,75.78 100.55,76.19 v1(101.12,76.19)
  BOTTOM w0.102: R475.2 75.52,54.45 75.52,54.08 v3(75.51,54.08)
PCH_SPI_IO3: length 42.6
  TOP w0.076: 95.91,73.89 96.14,73.89 96.97,73.06 97.77,73.06 97.86,72.98 98.06,72.98 U6.AF1
  TOP w0.102: v1(93.6,75.08) 94.79,73.89 v1(95.04,73.89) 95.91,73.89
  IN1 w0.114: v1(73.41,61.21) 73.91,61.72 73.91,62.61 73.52,63.01 73.52,68.84 74.7,70.02 74.7,70.8 75.58,71.69 75.58,74.42 79.09,77.92 82.29,77.92 82.55,77.67 84.52,77.67 84.91,78.05 88.19,78.05 89.08,77.16 90.63,77.16 92.68,75.11 93.57,75.11 v1(93.6,75.08)
  BOTTOM w0.102: R449.2 74.55,60.07 v1(73.41,61.21)
PCH_SPI_SI: length 43.9
  TOP w0.102: U6.AA2 98.45,74.71 98.07,74.71 97.89,74.52 97.43,74.52 v1(97.03,74.93) ; v1(73.41,61.85) v2(72.7,61.14) 72.01,60.45 71.62,60.45 R175.2
  IN1 w0.114: v1(97.03,74.93) 96.61,75.35 94.25,75.35 94.09,75.51 92.72,75.51 90.7,77.54 89.15,77.54 88.32,78.37 84.77,78.37 84.39,77.98 82.68,77.98 82.42,78.24 78.96,78.24 75.27,74.55 75.27,72.19 73.2,70.13 73.2,62.05 v1(73.41,61.85)
PCH_SPI_SI_EC: length 43.3
  TOP w0.102: v1(50.7,40.77) 52.36,42.43 61.87,42.43 62.34,41.97 67.5,41.97 67.96,42.43 68.6,42.43 71.12,44.96 71.12,46.36 v1(72.01,47.24)
  BOTTOM w0.102: R447.1 71.03,59.83 69.62,58.52 69.47,58.37 v2(69.47,53.38) 69.47,52.59 69.16,52.29 69.16,48.8 70.72,47.24 v1(72.01,47.24) ; U23.102 50.79,40.67 v1(50.7,40.77) 50.7,41.46 R507.2
PCH_SPI_SI_R: length 11.6
  TOP w0.102: v1(71.12,58.42) R175.1
  BOTTOM w0.102: U19.5 71.25,54.56 71.15,54.46 70.21,54.46 70.1,54.56 70.1,55.17 70.21,55.27 70.51,55.27 70.61,55.37 70.61,55.68 70.51,55.78 70.21,55.78 70.1,55.88 70.1,56.18 70.21,56.29 70.51,56.29 70.61,56.39 70.61,56.69 70.51,56.79 70.21,56.79 70.1,56.9 70.1,57.2 70.21,57.3 70.51,57.3 70.61,57.4 70.61,57.71 70.51,57.81 70.21,57.81 70.1,57.91 70.1,58.22 v2(70.17,58.28) 70.31,58.42 v1(71.12,58.42) R447.2
PCH_SPI_SO: length 58.9
  TOP w0.102: v1(99.82,74.72) 99.82,74.82 U6.AA4 ; v1(76.7,55.19) 75.49,55.19 v1(75.46,55.17)
  IN1 w0.114: v1(75.46,55.17) 75.18,55.45 75.18,57.76 72.88,60.06 72.88,70.26 74.95,72.32 74.95,74.68 78.83,78.56 81.52,78.56 82.06,79.1 84.56,79.1 84.97,78.68 88.45,78.68 89.28,77.85 90.83,77.85 92.86,75.83 96.58,75.83 96.92,75.48 97.71,75.48 98.05,75.15 99.4,75.15 v1(99.82,74.72)
  BOTTOM w0.102: v1(75.46,55.17) 75.41,55.12 73.02,55.12 R486.2
PCH_SPI_SO_EC: length 33.8
  TOP w0.102: v1(73.74,46.86) 72.77,46.86 72.12,46.22 v2(71.85,46.22) 71.63,46.22 71.43,46.01 71.43,44.83 68.72,42.13 68.09,42.13 67.62,41.66 62.21,41.66 61.75,42.13 52.54,42.13 51.33,40.92 51.33,40.77 v1(51.33,40.77)
  BOTTOM w0.102: v1(73.74,46.86) 72.92,47.68 70.81,47.68 69.72,48.77 R489.1 ; R508.2 51.33,41.46 v1(51.33,40.77) 51.19,40.62 U23.103
PCH_SPI_SO_R: length 12.4
  BOTTOM w0.102: R486.1 R489.2 69.82,49.77 70.48,49.1 70.48,48.44 70.94,47.98 73.63,47.98 73.79,48.13 U19.2 73.79,50.95 74.34,51.5 76.55,51.5 v2(76.57,51.53)
PCH_STAT: length 12.8
  TOP w0.102: v1(99.84,71.73) 100.14,72.03 U6.AG4
  BOTTOM w0.102: v1(99.84,71.73) 99.31,71.19 98.81,71.19 98.5,70.89 96.14,70.89 95.22,71.81 88.85,71.81 TP21.1
PCH_SUSACK#: length 58.8
  TOP w0.102: R119.2 84.97,74.62 v1(84.84,74.75)
  IN1 w0.114: v1(64.91,37.42) 65.15,37.19 72.84,37.19 75.58,39.93 78.77,39.93 v3(78.78,39.94)
  IN3 w0.102: v1(84.84,74.75) 84.84,73.93 84.36,73.46 82.19,73.46 78.41,69.68 78.41,69.26 77.79,68.64 77.79,62.03 78.23,61.59 78.23,60.35 77.7,59.82 77.7,56.72 78.23,56.19 78.23,54.71 79.43,53.52 79.43,50.12 78.33,49.03 78.33,40.39 v3(78.78,39.94)
  BOTTOM w0.102: v1(64.91,37.42) 64.65,37.16 63.63,37.16 63.62,37.17 U23.2
PCH_SUSCLK: length 10.3
  TOP w0.102: U6.AE6 101.47,73.08 v1(101.25,73.31)
  BOTTOM w0.102: v1(101.25,73.31) 100.83,72.9 100.2,72.9 99.95,72.64 96.91,72.64 96.78,72.77 TP20.1
PCH_SUSPWARN#: length 41.1
  TOP w0.102: R166.2 83.05,60.54 v2(82.97,60.47) 82.83,60.33 v1(82.09,60.33)
  IN1 w0.114: v1(82.09,60.33) 82.37,60.05 82.37,54.78 80.04,52.45 80.04,47.25 79.48,46.69 77.95,46.69 71.6,40.34 64.82,40.34 64.61,40.54 62.21,40.54 v1(61.84,40.92)
  BOTTOM w0.102: v1(61.84,40.92) 61.84,41.45 R515.1 61.47,41.66 61.19,41.38 U23.128
PCH_SUSPWRACK: length 43.1
  TOP w0.076: U6.AV4 100.16,65.27 99.89,64.99 99.89,64.99 99.87,64.97 99.87,64.74 99.78,64.66 99.78,64.05 99.36,63.63 98.32,63.63 97.97,63.98 96.29,63.98
  TOP w0.102: R120.2 87.34,74.62 v1(87.14,74.82) ; v1(78.49,65.63) 78.49,65.41 79.82,64.07 v2(80.51,64.07) 81.36,64.07 R166.1 84.23,61.19 85.84,61.19 R167.2 86.62,61.59 87.09,61.13 89.02,61.13 90.38,62.48 94,62.48 95.5,63.98 96.29,63.98
  IN3 w0.102: v1(78.49,65.63) 78,66.12 78,68.56 78.61,69.17 78.61,69.59 82.28,73.25 84.45,73.25 85.23,74.04 85.34,74.04 86.12,74.82 v1(87.14,74.82)
PCI_PIRQA#: length 12
  TOP w0.102: v1(101.28,78.1) 101.47,77.9 U6.U6
  BOTTOM w0.102: R375.1 91.13,78.43 91.36,78.43 92.06,77.72 v1(92.44,77.72) 92.59,77.57 94.87,77.57 95.13,77.31 99.99,77.31 100.37,77.69 100.87,77.69 v1(101.28,78.1)
PCI_PIRQB#: length 21.7
  TOP w0.076: 97.26,78.28 97.49,78.5 97.78,78.5 97.89,78.39 99.32,78.39 99.42,78.49 99.82,78.49 U6.P4
  TOP w0.102: R74.1 81.35,81.35 81.78,81.35 v1(82.01,81.57) 82.23,81.8 82.29,81.8 82.72,82.24 83.86,82.24 83.96,82.33 86.94,82.33 87.27,82.01 87.55,82.01 88.06,81.5 92.18,81.5 95.41,78.27 97.25,78.27 97.26,78.28
PCI_PIRQC#: length 11.7
  TOP w0.102: U6.N4 100.14,79.52 v1(99.84,79.22)
  BOTTOM w0.102: v1(99.84,79.22) 99.47,79.59 99.4,79.59 99.31,79.68 99.06,79.68 98.67,79.29 96.82,79.29 96.08,80.04 94.02,80.04 93.47,80.58 92.76,80.58 v1(92.73,80.62) 92.63,80.71 R369.1
PCI_PIRQD#: length 17.2
  TOP w0.076: 97.76,79.39 97.85,79.3 98.54,79.3 U6.N2
  TOP w0.102: R64.1 84.17,83.35 86.78,83.35 87.52,82.62 88.08,82.62 88.25,82.79 v2(89.3,82.79) 89.94,82.79 90.19,82.54 92.29,82.54 94.58,80.26 96.15,80.26 96.88,79.53 97.54,79.53 97.68,79.39 97.76,79.39
PCI_PLTRST#: length 57
  TOP w0.102: v1(101.85,72.39) 101.85,72.17 U6.AG7
  IN1 w0.114: v1(101.85,72.39) 101.34,71.88 100.33,71.88 99.95,72.26 98.68,72.26 98.3,72.64 91.67,72.64 90.15,74.17 84.8,74.17 84.38,74.59 82.01,74.59 80.74,73.32 80.21,73.32 79.38,72.49 79.38,70.87 79.12,70.61 79.12,69.85 78.41,69.14 78.41,68.25 79.5,67.15 79.5,65.12 80.14,64.49 80.92,63.71 80.92,55.39 v1(80.26,54.74)
  BOTTOM w0.102: v1(80.26,54.74) v2(80.79,54.21) 80.85,54.15 88.32,54.15 88.95,54.79 U18.2 90.68,54.79 90.8,54.66 90.8,54.23 90.71,54.14 U18.1
PCIE_CLKREQ_NGFF0#: length 204
  TOP w0.102: CN13.52 204.12,11.64 202.71,10.23 v1(202.61,10.23)
  IN3 w0.102: v1(202.61,10.23) 202.5,10.33 200.88,10.33 200.62,10.58 199.86,10.58 199.51,10.23 198.95,10.23 198.2,10.97 190.46,10.97 187.23,14.2 152.86,14.2 152.48,14.58 150.95,14.58 149.61,13.23 131.24,13.23 130.75,12.74 120.98,12.74 115.13,18.58 93.59,18.58 92.81,17.81 86.05,17.81 85.66,17.41 81.04,17.41 79.92,18.53 79.22,18.53 74.81,22.94 74.81,32.82 75.59,33.6 75.59,34.29 75.41,34.47 75.41,37.5 74.98,37.93 74.98,52.09 74.63,52.45 74.63,62.35 73.86,63.12 73.86,66.86 75.75,68.75 75.75,70.13 77.32,71.7 77.32,75.75 79.84,78.27 80.37,78.27 80.8,78.7 80.8,80.29 v1(81.45,80.94)
  BOTTOM w0.102: R367.1 82.74,80.47 81.92,80.47 v1(81.45,80.94) 80.97,80.47 R370.1
PCIE_CLKREQ_NGFF0#_C: length 18.8
  TOP w0.102: v1(100.64,78.1) 100.82,77.92 U6.U5
  BOTTOM w0.102: R367.2 84.38,80.1 87.42,80.1 v2(87.72,79.8) 87.77,79.75 91.64,79.75 92.69,78.69 93.07,78.69 93.37,78.99 94.18,78.99 94.5,78.68 98.45,78.68 98.72,78.41 100.33,78.41 v1(100.64,78.1)
PCIE_CLKREQ_NGFF1#: length 240
  TOP w0.102: R75.1 82.87,81.73 v1(82.08,80.94) ; CN10.52 204.28,37.64 203.03,36.39 R210.1 203.02,35.27 202.62,34.86 201.74,34.86 201,34.12 201,33.03 199.43,31.46 199.21,31.46 196.66,28.92 196.66,26.28 197.22,25.72 201.28,25.72 v2(201.45,25.89) 201.64,26.08 v1(202.35,26.08)
  IN3 w0.102: v1(202.35,26.08) 203.46,26.08 204.72,24.81 204.72,12.4 203.73,11.4 190.61,11.4 187.28,14.73 153.06,14.73 151.93,15.86 145.94,15.86 144.07,13.99 130.9,13.99 130.26,13.35 121.32,13.35 115.26,19.41 93.05,19.41 92.1,18.46 80.94,18.46 76.94,22.45 75.87,22.45 75.21,23.11 75.21,32.09 77.22,34.1 77.22,34.42 75.82,35.81 75.82,37.85 75.56,38.1 75.56,52.63 76.45,53.52 76.45,55.78 76.1,56.13 76.1,61.57 74.85,62.81 74.85,67.56 75.95,68.66 75.95,70.05 77.52,71.62 77.52,75.66 79.92,78.06 80.45,78.06 81,78.61 81,79.73 82.08,80.81 v1(82.08,80.94)
PCIE_CLKREQ_NGFF1#_C: length 17.3
  TOP w0.076: 97.16,77.87 97.36,77.68 97.87,77.68 98,77.8 98.54,77.8 U6.T2
  TOP w0.102: R75.2 84.17,82.13 86.85,82.13 87.18,81.8 87.47,81.8 87.98,81.3 92.1,81.3 95.53,77.87 97.16,77.87
PCIE_CLKREQ_WLAN#: length 214.7
  TOP w0.102: R65.1 86.96,83.76 v1(87.06,83.66) 87.06,83.38 87.57,82.87 88,82.87 88.38,83.25 89.07,83.25 89.1,83.28 89.5,83.28 89.52,83.25 89.77,83.25 90.27,82.75 92.38,82.75 94.66,80.46 96.23,80.46 96.96,79.73 97.62,79.73 97.76,79.59 U6.N1
  IN1 w0.114: v1(176.43,52.93) 176.91,52.45 176.91,44.76 172.89,40.74 172.89,25.4 169.72,22.23 133.71,22.23 131.89,24.05 88.56,24.05 83.8,28.8 82.01,28.8 80.67,30.15 80.67,32.91 77.89,35.69 75.18,35.69 v1(74.8,36.07)
  IN3 w0.102: v1(87.06,83.66) 86.76,83.35 84.5,83.35 84.4,83.25 81.44,83.25 80.81,82.62 80.81,82.3 80.39,81.88 80.39,78.87 80.2,78.67 79.67,78.67 76.91,75.91 76.91,71.87 75.34,70.3 75.34,68.91 73.46,67.03 73.46,62.95 74.22,62.19 74.22,52.28 74.57,51.93 74.57,36.3 v1(74.8,36.07)
  BOTTOM w0.102: R473.1 182.62,54.98 181.86,54.23 180.59,54.23 179.29,52.93 v2(177.56,52.93) v1(176.43,52.93)
PCIE_IREF: length 5.8
  TOP w0.203: U6.B27 114.3,86.43 114.3,86.54 114.39,86.63 114.39,87.21 114.37,87.23 114.37,87.83 115.01,88.47 115.09,88.47 115.41,88.79
  TOP w0.381: 115.41,88.79 115.9,89.28 116.33,89.28 117.22,90.17 R44.2
PCIE_RCOMP: length 4.8
  TOP w0.305: 113.98,88.24 113.98,86.86 U6.A27
  TOP w0.381: R43.1 115.38,90.17 v2(115.26,90.05) 115.26,90.04 115.26,89.52 113.98,88.24
PCIE_WAKE_WLAN#: length 195.7
  TOP w0.102: v1(101.27,71.43) 101.27,71.4 U6.AJ5
  IN1 w0.114: v1(172.34,39.24) 172.34,40.51 176.43,44.61 v1(176.43,52.29)
  IN3 w0.076: 100.58,70.99 100.77,70.99 101.21,71.43 v1(101.27,71.43)
  IN3 w0.102: v1(172.34,39.24) 171.32,38.23 171.32,36.38 162.86,27.91 135.51,27.91 135.12,27.52 116.6,27.52 116.41,27.71 90.91,27.71 88.77,29.84 88.77,35.56 87.88,36.45 87.38,36.45 86.94,36.88 86.94,52.65 86.77,52.82 86.77,56.51 85.5,57.78 85.5,59.18 86.46,60.15 86.46,62.82 86.18,63.1 86.18,66.36 86.75,66.93 87.97,66.93 90.97,63.93 94.05,63.93 95.3,65.18 95.3,69.23 96.15,70.08 98.11,70.08 99.03,70.99 100.58,70.99
  BOTTOM w0.076: 99.7,72.13 99.99,72.13 100.3,71.82 100.87,71.82 v1(101.27,71.43)
  BOTTOM w0.102: v1(176.43,52.29) 179.16,52.29 180.23,53.36 v2(180.94,53.36) 182.52,53.36 185.04,55.88 Q22.3 ; R409.2 R410.2 86.35,72.39 87.38,72.39 87.76,72.01 95.37,72.01 96.14,71.24 98.13,71.24 99.02,72.13 99.7,72.13
PD#: length 9.9
  TOP w0.102: U16.47 35.71,17.86 35.87,17.7 36.3,17.7 36.5,17.91 37.39,17.91 37.59,17.7 38.04,17.7 R310.2 39.62,16.37 40.13,16.89 D14.2 D15.2 39.86,14.86 v2(39.66,15.05)
PECI: length 3.8
  BOTTOM w0.102: U23.117 56.79,40.03 56.85,40.08 56.85,40.84 57.53,41.53 57.53,41.96 R513.2
PEG_RXN4: length 116.8
  TOP w0.102: U6.F13 105.77,83.55 106.02,83.79 v1(106.02,83.86)
  IN3 w0.102: v1(106.02,83.86) 106.02,83.74 105.93,83.65 105.67,83.65 105.56,83.76 105.56,89.97 105.77,90.17 105.77,91.29 110.26,95.78 110.26,96.31 112.44,98.49 125.3,98.49 126.06,99.25 153.55,99.25 158.32,94.49 158.32,93.44 160.1,91.66 160.1,84.39 165.74,78.75 165.74,75.14 175.34,65.54 175.34,64.08 179.69,59.73 181.85,59.73 182.06,59.93 182.06,60.19 v1(182.4,60.53)
  BOTTOM w0.102: v1(182.4,60.53) 182.17,60.53 182.13,60.49 182.13,60.12 182.24,60.01 182.62,60.01 183.02,59.6 183.02,59.45 183.18,59.3 CN9.43
PEG_RXN5_L0: length 170.4
  TOP w0.102: v1(104.12,83.89) 103.84,83.89 103.65,83.7 U6.F10
  IN3 w0.102: v1(202.31,16.38) 202.07,16.14 201.97,16.14 197.98,20.13 197.98,21.89 195.83,24.04 195.83,26.54 192.68,29.69 192.68,40.45 184.68,48.45 184.68,59.59 184.68,60.26 182.62,62.32 182.54,62.32 182.54,62.32 182.37,62.32 182.18,62.32 167.56,76.94 167.56,79.51 161.93,85.15 161.93,93.47 154.1,101.29 112.58,101.29 107.48,96.19 107.48,95.63 103.93,92.07 103.93,91.12 102.98,90.18 102.98,87.33 103.06,87.26 103.06,87.25 103.4,86.91 103.4,85.29 103.72,84.97 103.72,84.3 v1(104.12,83.89)
  BOTTOM w0.102: R567.2 v1(202.31,16.38)
PEG_RXN5_L1: length 170.1
  TOP w0.102: v1(103.17,83.87) 103.01,83.87 U6.F8
  IN3 w0.102: v1(200.65,19.5) 200.09,19.5 199.15,20.44 199.15,25.04 194.03,30.16 194.03,33.15 193.5,33.68 193.5,40.79 186.26,48.03 186.26,59.86 182.94,63.17 182.48,63.17 168.38,77.27 168.38,79.85 162.94,85.29 162.94,89.05 162.74,89.25 162.74,93.8 154.44,102.1 110.56,102.1 104.57,96.11 104.57,96.02 102.01,93.46 102.01,90.9 101.8,90.69 101.8,87.23 102.49,86.55 102.49,85.03 102.74,84.78 102.74,84.29 v1(103.17,83.87)
  BOTTOM w0.102: v1(200.65,19.5) 200.76,19.39 200.99,19.39 R556.2
PEG_RXN5_L1_N: length 7
  BOTTOM w0.102: R556.1 201.97,19.59 201.97,19.29 202.15,19.12 202.86,19.12 203.11,18.86 v2(204.03,18.86) 204.03,17.92 204.56,17.39 206.26,17.39 206.55,17.09 206.7,17.09 CN13.29
PEG_RXN5_L2: length 166.6
  TOP w0.102: v1(104.14,82.55) 103.95,82.55 U6.H10
  IN3 w0.102: v1(104.14,82.55) 104.75,83.16 104.75,86.14 104.47,86.42 104.47,87.29 104,87.76 104,89.75 104.95,90.71 104.95,91.63 109.37,96.05 109.37,96.62 113,100.25 119.11,100.25 119.49,99.87 125.53,99.87 125.92,100.27 153.68,100.27 160.91,93.04 160.91,84.73 166.55,79.09 166.55,75.51 180.76,61.31 182.2,61.31 183.67,59.84 183.67,56.74 183.31,56.39 183.31,48.39 191.67,40.03 191.67,28.42 194.63,25.46 194.63,23.56 194.5,23.43 194.18,23.43 v1(193.98,23.64)
  BOTTOM w0.102: R548.2 200.4,22.76 200.29,22.66 199.22,22.66 198.58,23.29 194.09,23.29 193.98,23.4 v1(193.98,23.64)
PEG_RXN5_L2_N: length 8
  BOTTOM w0.102: CN13.17 206.61,20.39 206.31,20.1 205.94,20.1 205.6,20.44 204.65,20.44 203.68,21.4 203.67,21.4 203.37,21.71 v2(203.37,22.11) 203.09,21.83 202.58,21.83 202.3,22.11 202.3,22.27 202.05,22.52 201.41,22.52 201.18,22.75 R548.1
PEG_RXN5_L3: length 167.8
  TOP w0.102: v1(102.3,84.52) 102.06,84.76 101.93,84.76 101.74,84.57 U6.E6
  IN3 w0.102: v1(199.77,26.92) 200.2,26.49 200.38,26.49 200.57,26.69 200.57,27.11 199.42,28.26 197.98,28.26 194.64,31.6 194.64,33.58 194.31,33.91 194.31,40.87 187.12,48.05 187.12,60.22 186.57,60.77 186.23,60.77 183.22,63.78 182.73,63.78 168.99,77.53 168.99,80.1 163.55,85.54 163.55,89.3 163.35,89.51 163.35,94.06 154.69,102.71 110.31,102.71 103.76,96.16 103.76,96.07 101.19,93.51 101.19,86.89 101.88,86.21 101.88,84.35 101.96,84.28 102.06,84.28 v1(102.3,84.52)
  BOTTOM w0.102: v1(199.77,26.92) 200.11,26.58 200.78,26.58 200.94,26.75 200.94,27.02 R536.2
PEG_RXN5_L3_N: length 9.5
  BOTTOM w0.102: CN13.5 206.7,23.1 206.22,23.1 205.35,23.97 205.35,26.23 204.99,26.58 203.52,26.58 203.11,26.99 v2(203.11,27.29) 202.5,26.69 201.67,26.69 201.56,26.79 R536.1
PEG_RXN6_L1: length 158.3
  TOP w0.102: U6.J6 101.82,81.59 v1(102.16,81.93)
  IN3 w0.102: v1(198.5,44.19) 196.6,44.19 195.81,44.98 195.81,51.97 192.02,55.75 191.45,55.75 188.14,59.06 188.14,60.64 183.98,64.8 183.15,64.8 170,77.95 170,80.52 164.57,85.96 164.57,89.73 164.36,89.93 164.36,94.48 155.12,103.72 109.89,103.72 103.57,97.41 101.09,97.41 99.36,95.68 99.36,85.52 99.16,85.32 99.16,84.63 100.84,82.96 101.48,82.96 101.73,82.71 101.73,82.36 v1(102.16,81.93)
  BOTTOM w0.102: v1(198.5,44.19) 198.63,44.06 200.12,44.06 v2(200.62,44.57) 201.13,44.06 201.4,44.06 R503.2
PEG_RXN6_L1_N: length 5.9
  BOTTOM w0.102: CN10.29 206.7,43.1 205.96,43.1 205.45,43.6 204.54,43.6 v2(203.72,44.41) 203.06,43.75 202.68,43.75 202.45,43.99 R503.1
PEG_RXN6_L2_N: length 37.2
  TOP w0.102: v1(203.67,15.31) 203.37,15.61 201.42,15.61 R312.1
  IN1 w0.114: CN10.17 206.71,46.11 205.57,46.11 204.32,44.86 204.32,19 202.75,17.43 202.75,15.93 203.11,15.56 203.42,15.56 v1(203.67,15.31)
PEG_RXN6_L3: length 156.9
  TOP w0.102: v1(101.3,81.91) 100.97,81.59 U6.J5
  IN3 w0.102: v1(199.14,49.15) 197.39,49.15 196.7,49.84 196.7,53.49 191.31,58.88 190.04,58.88 189.61,59.31 189.61,60.31 184.28,65.64 183.46,65.64 170.81,78.28 170.81,80.88 165.43,86.27 165.43,90.38 165.18,90.64 165.18,96.16 161.14,100.2 159.89,100.2 155.56,104.54 107.93,104.54 103.63,100.24 103.63,99.09 102.91,98.37 100.7,98.37 98.55,96.22 98.55,87.41 98.35,87.21 98.35,84.29 100.68,81.97 101.24,81.97 v1(101.3,81.91)
  BOTTOM w0.102: v1(199.14,49.15) 199.26,49.02 199.59,49.02 v2(200.12,49.55) 200.64,49.02 201.03,49.02 201.16,49.15 R488.2
PEG_RXN6_L3_N: length 6.4
  BOTTOM w0.102: R488.1 201.94,48.94 202.05,48.83 202.71,48.83 v2(203.42,49.55) 204.1,48.86 205.52,48.86 206.05,49.39 CN10.5
PEG_RXP4: length 116.9
  TOP w0.102: v1(106.02,83.22) 105.69,82.89 U6.G13
  IN3 w0.102: v1(106.02,83.22) 105.84,83.4 105.63,83.4 105.36,83.67 105.36,90.05 105.56,90.25 105.56,91.38 110.05,95.87 110.05,96.39 112.36,98.7 125.21,98.7 125.97,99.46 153.63,99.46 158.52,94.57 158.52,93.52 160.3,91.74 160.3,84.48 165.94,78.84 165.94,75.23 175.54,65.63 175.54,64.17 179.77,59.93 181.77,59.93 181.85,60.02 181.85,60.31 v1(181.64,60.53)
  BOTTOM w0.102: CN9.41 182.68,59.33 182.82,59.48 182.82,59.52 182.53,59.81 182.16,59.81 181.93,60.03 181.93,60.23 v1(181.64,60.53)
PEG_RXP5_L0: length 170.3
  TOP w0.102: v1(104.12,84.53) 103.79,84.2 U6.E10
  IN3 w0.102: v1(104.12,84.53) 103.92,84.73 103.92,85.06 103.61,85.37 103.61,87 103.27,87.34 103.27,87.34 103.19,87.42 103.19,90.09 104.13,91.03 104.13,91.99 107.69,95.54 107.69,96.1 112.67,101.08 154.02,101.08 161.72,93.38 161.72,85.07 167.36,79.43 167.36,76.85 182.09,62.12 182.45,62.12 182.54,62.12 184.48,60.18 184.48,60.09 184.48,60.09 184.48,59.67 184.48,59.67 184.48,48.37 192.48,40.37 192.48,29.61 195.63,26.46 195.63,23.96 197.78,21.81 197.78,20.05 201.89,15.94 202.5,15.94 202.68,15.76 202.68,15.48 v1(202.31,15.11)
  BOTTOM w0.102: R570.2 v1(202.31,15.11)
PEG_RXP5_L1: length 170.1
  TOP w0.102: v1(103.17,84.52) 102.94,84.75 102.81,84.75 102.74,84.68 102.74,84.25 U6.E8
  IN3 w0.102: v1(103.17,84.52) 102.95,84.74 102.95,84.86 102.69,85.12 102.69,86.63 102.01,87.32 102.01,90.61 102.21,90.81 102.21,93.37 104.77,95.94 104.77,96.03 110.64,101.9 154.36,101.9 162.53,93.72 162.53,89.17 162.74,88.97 162.74,85.2 168.17,79.77 168.17,77.19 182.39,62.97 182.86,62.97 186.06,59.77 186.06,47.95 193.29,40.71 193.29,33.6 193.83,33.06 193.83,30.08 198.95,24.96 198.95,20.35 200.01,19.29 200.22,19.29 v1(200.65,18.86)
  BOTTOM w0.102: R560.2 201.29,19.09 201.19,19.18 200.91,19.18 200.65,18.92 v1(200.65,18.86)
PEG_RXP5_L1_N: length 7
  BOTTOM w0.076: CN13.31 207.79,16.89 206.67,16.89
  BOTTOM w0.102: 206.67,16.89 206.47,16.89 206.18,17.19 204.48,17.19 203.72,17.95 v2(203.11,17.95) 203.11,18.57 202.78,18.91 202.31,18.91 R560.1
PEG_RXP5_L2: length 166.6
  TOP w0.102: v1(104.14,83.19) 103.85,82.89 U6.G10
  IN3 w0.102: v1(193.98,22.89) 194.32,23.23 194.59,23.23 194.83,23.48 194.83,25.55 191.87,28.51 191.87,40.12 183.51,48.47 183.51,56.3 183.87,56.66 183.87,59.92 182.29,61.51 180.84,61.51 166.75,75.6 166.75,79.18 161.11,84.81 161.11,93.13 153.77,100.47 125.84,100.47 125.44,100.08 119.57,100.08 119.19,100.46 112.92,100.46 109.17,96.71 109.17,96.14 104.75,91.72 104.75,90.79 103.8,89.84 103.8,87.67 104.27,87.2 104.27,86.33 104.55,86.06 104.55,83.4 104.33,83.19 v1(104.14,83.19)
  BOTTOM w0.102: v1(193.98,22.89) 194.17,23.09 198.5,23.09 199.13,22.45 200.04,22.45 R551.2
PEG_RXP5_L2_N: length 8.1
  BOTTOM w0.076: CN13.19 206.67,19.89
  BOTTOM w0.102: 206.67,19.89 205.86,19.89 205.52,20.23 204.56,20.23 203.6,21.2 v2(202.45,21.2) 202.45,21.67 202.1,22.03 202.1,22.18 201.96,22.32 201.4,22.32 R551.1
PEG_RXP5_L3: length 167.8
  TOP w0.102: U6.F6 102.07,83.87 v1(102.3,83.87)
  IN3 w0.102: v1(102.3,83.87) 102.1,84.07 101.87,84.07 101.68,84.27 101.68,86.12 100.99,86.81 100.99,93.59 103.56,96.15 103.56,96.24 110.22,102.91 154.78,102.91 163.55,94.14 163.55,89.59 163.75,89.39 163.75,85.62 169.19,80.19 169.19,77.61 182.81,63.98 183.3,63.98 186.31,60.98 186.65,60.98 187.32,60.3 187.32,48.14 194.51,40.95 194.51,33.99 194.84,33.66 194.84,31.69 198.07,28.46 199.51,28.46 200.78,27.19 200.78,26.6 200.46,26.29 v1(199.77,26.29)
  BOTTOM w0.102: v1(199.77,26.29) 199.86,26.38 200.56,26.38 R541.2
PEG_RXP5_L3_N: length 9.5
  BOTTOM w0.076: CN13.7 206.68,22.89
  BOTTOM w0.102: R541.1 201.88,26.48 202.66,26.48 v2(203.11,26.02) 203.47,26.38 204.91,26.38 205.15,26.14 205.15,23.88 206.14,22.89 206.68,22.89
PEG_RXP6_L1: length 158.3
  TOP w0.102: U6.H6 101.74,82.49 101.82,82.57 v1(102.16,82.57)
  IN3 w0.102: v1(198.5,43.44) 198.34,43.6 198.34,43.78 198.13,43.99 196.52,43.99 195.61,44.9 195.61,51.88 191.94,55.55 191.36,55.55 187.93,58.98 187.93,60.55 183.89,64.59 183.07,64.59 169.8,77.86 169.8,80.44 164.36,85.88 164.36,89.64 164.16,89.84 164.16,94.39 155.03,103.52 109.97,103.52 103.65,97.21 101.18,97.21 99.57,95.6 99.57,85.44 99.36,85.23 99.36,84.72 100.92,83.16 101.57,83.16 v1(102.16,82.57)
  BOTTOM w0.102: R505.2 201.67,43.65 201.46,43.86 201.18,43.86 v2(200.62,43.3) 200.07,43.86 198.74,43.86 198.5,43.61 v1(198.5,43.44)
PEG_RXP6_L1_N: length 5.9
  BOTTOM w0.076: CN10.31 206.67,42.89
  BOTTOM w0.102: R505.1 202.69,43.55 203.32,43.55 v2(203.72,43.14) 203.98,43.4 205.37,43.4 205.87,42.89 206.67,42.89
PEG_RXP6_L2_N: length 37.2
  TOP w0.102: R311.1 201.49,15.81 203.57,15.81 v1(203.72,15.97)
  IN1 w0.076: CN10.19 206.69,45.89
  IN1 w0.114: v1(203.72,15.97) 203.53,15.78 203.2,15.78 202.96,16.02 202.96,17.34 204.54,18.91 204.54,44.77 205.66,45.89 206.69,45.89
PEG_RXP6_L3: length 156.9
  TOP w0.102: v1(101.3,82.55) 101.22,82.63 100.97,82.63 100.86,82.52 100.86,82.32 U6.H5
  IN3 w0.102: v1(101.3,82.55) 100.91,82.17 100.76,82.17 98.55,84.38 98.55,87.12 98.76,87.33 98.76,96.14 100.79,98.17 103,98.17 103.84,99.01 103.84,100.15 108.02,104.33 155.47,104.33 159.81,100 161.05,100 164.97,96.08 164.97,90.55 165.23,90.3 165.23,86.18 170.61,80.8 170.61,78.2 183.37,65.44 184.2,65.44 189.41,60.23 189.41,59.22 189.96,58.67 191.23,58.67 196.49,53.41 196.49,49.76 197.31,48.95 198.7,48.95 v1(199.14,48.51)
  BOTTOM w0.102: R491.2 201.16,48.73 201.07,48.82 200.66,48.82 v2(200.12,48.28) 199.57,48.82 199.44,48.82 v1(199.14,48.51)
PEG_RXP6_L3_N: length 6.4
  BOTTOM w0.076: CN10.7 206.67,48.89
  BOTTOM w0.102: 206.67,48.89 205.84,48.89 205.6,48.66 203.8,48.66 v2(203.42,48.28) 203.06,48.63 202.18,48.63 R491.1
PEG_TXN4: length 110.8
  TOP w0.102: C19.1 119.15,92.06 119.15,94.06 120.78,95.68 120.78,100.51 121.72,101.45 151.79,101.45 155.14,98.1 155.14,91.78 154.86,91.5 154.86,77.24 155.14,76.96 155.14,72.94 v1(154.85,72.64)
  IN1 w0.114: v1(154.85,72.64) 155.11,72.38 155.11,70.32 167.03,58.39 167.03,57.2 v1(166.86,57.02)
  BOTTOM w0.102: v1(166.86,57.02) 167.07,57.23 167.07,57.55 170.62,61.1 179.69,61.1 180.76,60.04 181.07,60.04 181.5,59.6 181.5,59.48 181.68,59.3 CN9.37
PEG_TXN5_L0: length 146.3
  TOP w0.076: v1(112.15,89.03) 112.15,89.1 111.76,89.5 111.67,89.5 111.34,89.17 111.34,87.25 111.08,86.99 111.08,86.66 111.27,86.47 111.27,85.98 111.11,85.83 111.11,85.67 111.17,85.62 U6.C23
  IN3 w0.102: v1(112.15,89.03) 112.58,89.46 113.04,89.46 113.93,90.35 116.8,90.35 117.38,90.93 118.14,90.93 120.8,93.59 124.79,93.59 125.02,93.36 146.91,93.36 153.68,86.59 153.68,83.84 160.86,76.66 160.86,72.79 163.63,70.02 163.63,67.71 175.69,55.65 175.69,49 178.33,46.35 178.33,44.34 187.32,35.35 187.32,27.32 193.61,21.04 193.61,20.04 193.3,19.73 192.98,19.73 192.85,19.86 v1(192.85,20.06)
  BOTTOM w0.102: C400.1 198.73,13.26 198.6,13.14 198.24,13.14 194.07,17.3 194.07,19.06 193.41,19.73 192.98,19.73 192.85,19.86 v1(192.85,20.06)
PEG_TXN5_L1: length 139.2
  TOP w0.076: U6.B23 111.71,86.24 111.71,87.88 111.86,88.03 112,88.03 112.15,87.88 v1(112.15,87.76)
  IN3 w0.102: v1(191.21,21.35) 191.49,21.07 191.63,21.07 191.84,21.28 191.84,21.66 186.51,26.99 186.51,34.99 177.52,43.98 177.52,46.02 174.88,48.66 174.88,55.31 167.55,62.64 166.49,62.64 160.05,69.08 160.05,76.33 152.87,83.5 152.87,86.26 146.58,92.55 124.68,92.55 124.45,92.78 121.16,92.78 118.42,90.04 117.76,90.04 117.25,89.53 114.33,89.53 112.99,88.19 112.52,88.19 112.15,87.82 v1(112.15,87.76)
  BOTTOM w0.102: v1(191.21,21.35) 191.49,21.07 193.39,21.07 196.48,17.98 197.93,17.98 C391.1
PEG_TXN5_L1_N: length 9.9
  BOTTOM w0.076: CN13.35 206.67,15.89
  BOTTOM w0.102: C391.2 199.51,18.05 202.13,18.05 203.05,17.13 203.67,17.13 204.59,16.22 205.55,16.22 v2(205.76,16.42) 206.29,15.89 206.67,15.89
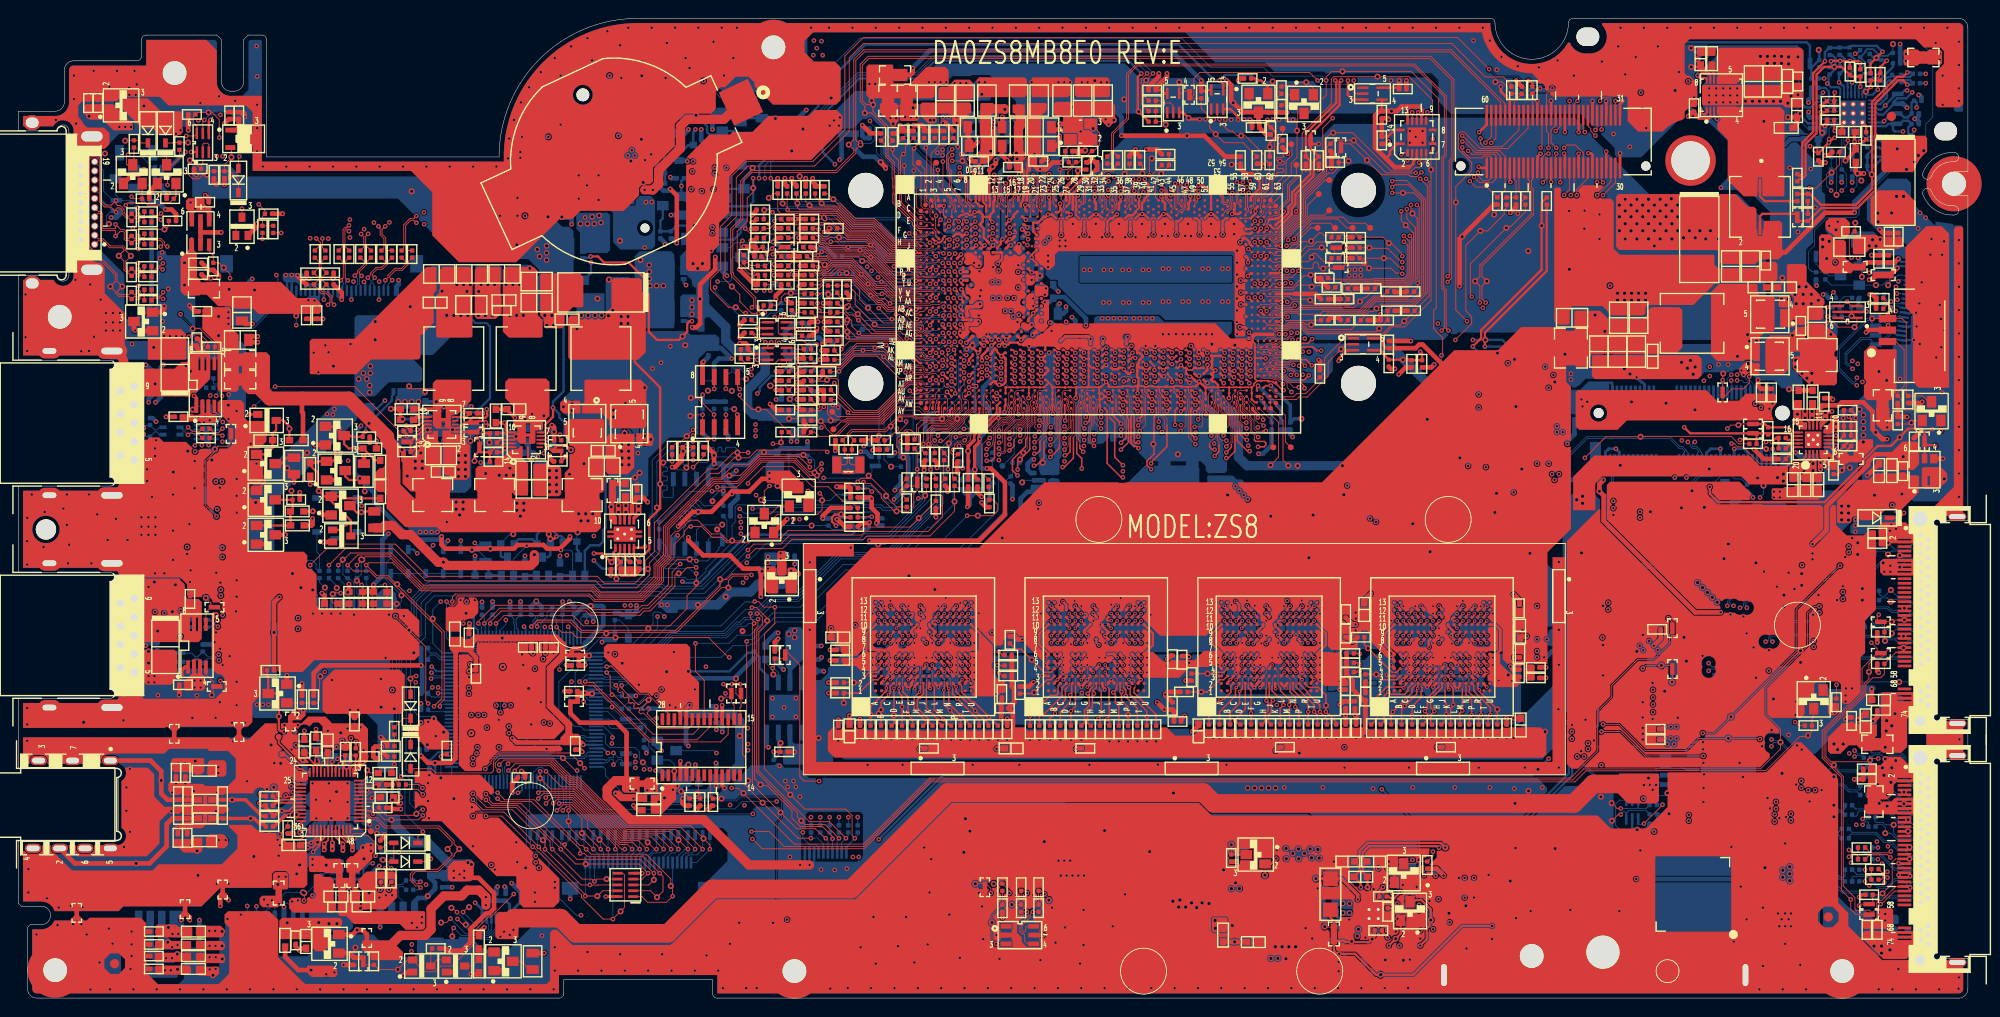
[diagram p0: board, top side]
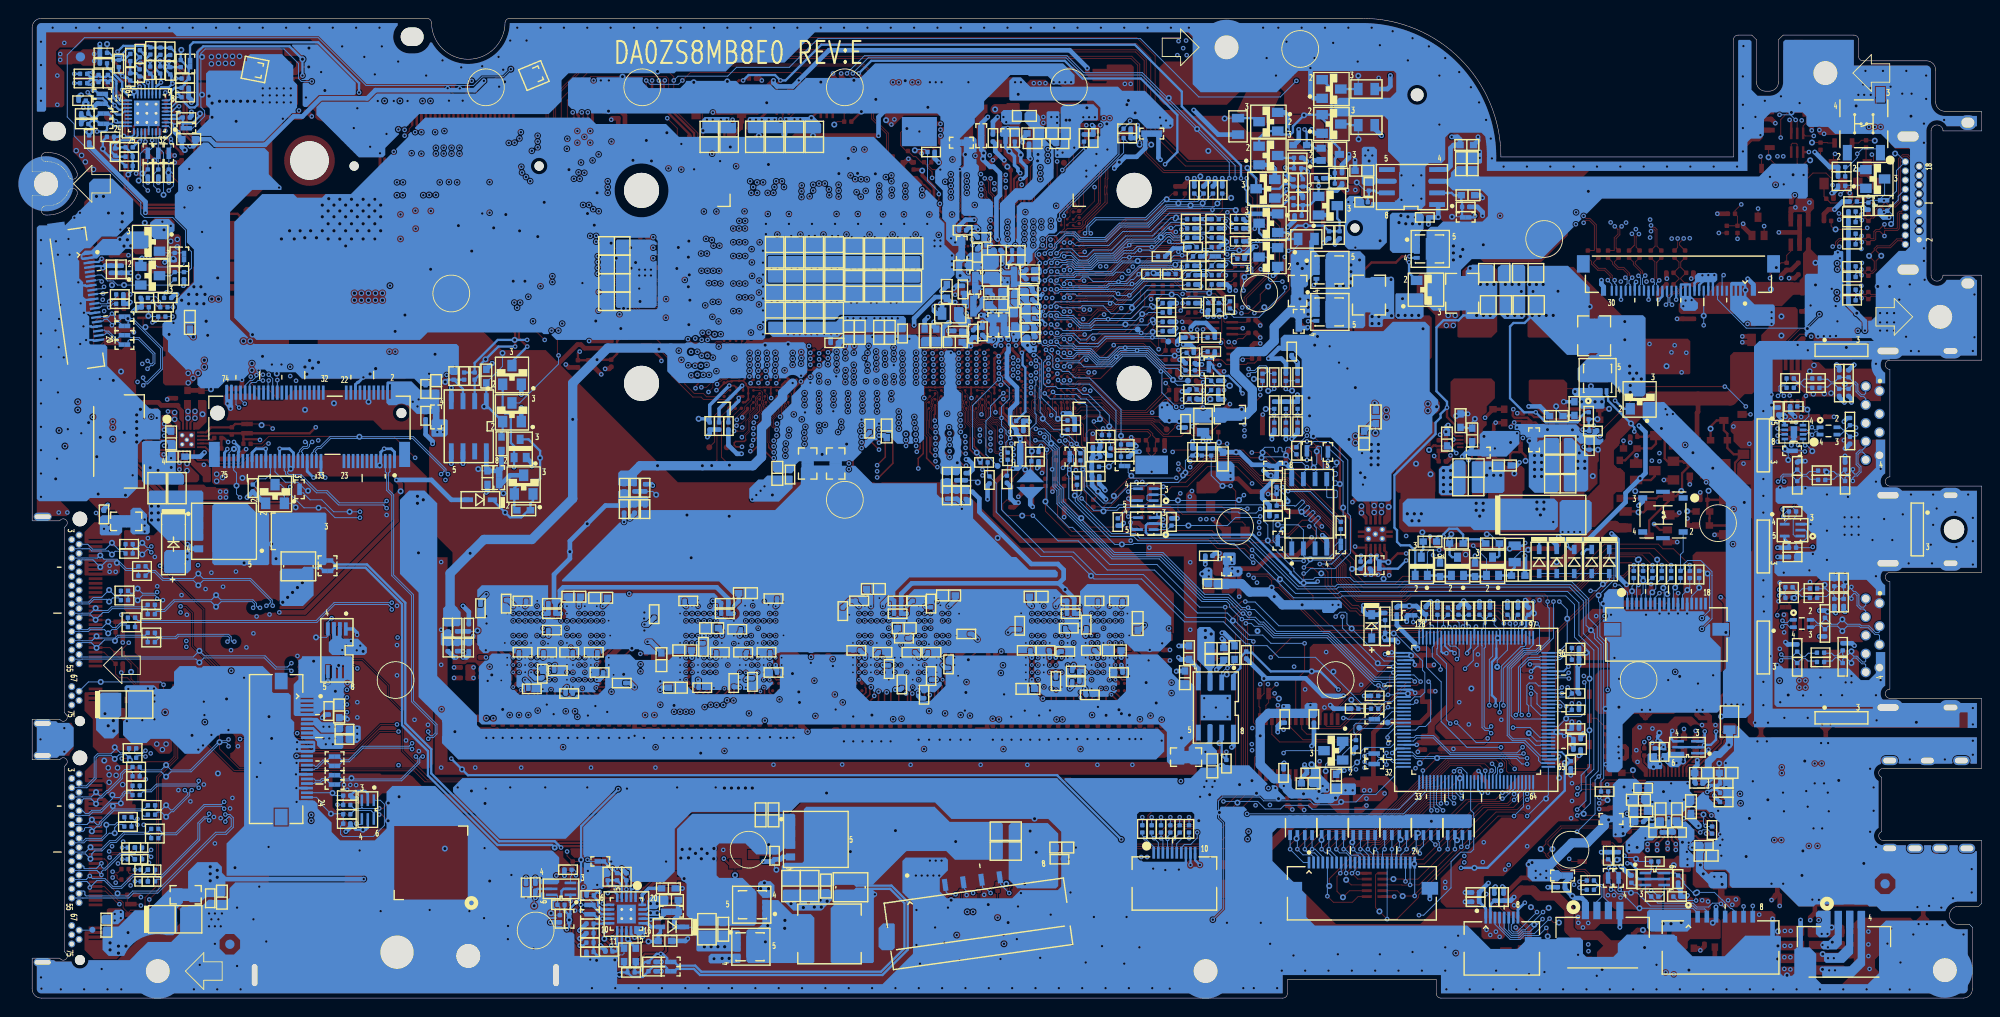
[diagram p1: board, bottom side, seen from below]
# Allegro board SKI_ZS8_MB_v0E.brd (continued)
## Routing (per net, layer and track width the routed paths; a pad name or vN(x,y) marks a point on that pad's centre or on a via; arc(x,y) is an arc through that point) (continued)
PEG_TXN5_L2: length 143.3
  TOP w0.076: U6.B21 110.34,85.62 110.3,85.66 110.3,85.78 110.52,86 110.52,86.34 110.17,86.69 110.17,87.56 110.22,87.62 v1(110.41,87.62)
  IN3 w0.102: v1(195.49,22.63) 194.99,22.14 193.66,22.14 188.14,27.66 188.14,35.69 179.15,44.68 179.15,46.71 176.84,49.02 176.84,55.65 167.18,65.31 167.18,66.46 165.28,68.37 165.28,69.64 161.67,73.25 161.67,77 154.5,84.18 154.5,88.6 152.8,90.3 151.13,90.3 147.25,94.17 125.35,94.17 125.12,94.4 119.98,94.4 119.51,93.93 119.51,93.46 117.79,91.74 116.26,91.74 115.75,91.24 114.6,91.24 114.47,91.36 113.16,91.36 111.63,89.84 111.63,88.9 110.41,87.68 v1(110.41,87.62)
  BOTTOM w0.102: v1(195.49,22.63) 195.16,22.31 195.16,22.14 196.81,20.49 197.02,20.49 v2(197.53,21) 198.07,20.45 198.58,20.45 198.72,20.59 C384.1
PEG_TXN5_L2_N: length 9.7
  BOTTOM w0.076: 207.53,18.89 206.72,18.89 ; CN13.23 207.54,18.89
  BOTTOM w0.102: C384.2 199.89,20.59 203.32,20.59 204.79,19.12 204.79,18.95 204.87,18.86 205.04,18.86 v2(205.6,19.42) 206.13,18.89 206.72,18.89 ; 207.54,18.89 207.53,18.89
PEG_TXN5_L3: length 143.1
  TOP w0.076: v1(110.41,89.52) 110.6,89.33 110.82,89.33 111,89.15 111,87.38 110.75,87.13 110.75,86.23 U6.B22
  IN3 w0.102: v1(110.41,89.52) 110.62,89.73 110.62,90.3 111.32,91 111.32,91.62 112.46,92.76 117.37,92.76 118.29,93.68 118.29,94.17 119.54,95.42 125.55,95.42 125.78,95.19 147.96,95.19 151.6,91.55 152.98,91.55 155.51,89.02 155.51,84.6 162.69,77.42 162.69,73.79 168.27,68.2 168.27,65.69 172.88,61.08 173.49,61.08 177.99,56.58 177.99,49.32 181.43,45.88 181.43,43.85 190.2,35.09 190.2,28.03 190.32,27.9 190.49,27.9 v1(190.73,28.15)
  BOTTOM w0.102: v1(190.73,28.15) 190.88,28.01 191.71,28.01 194.88,24.83 196.99,24.83 v2(197.53,25.36) 198.06,24.83 200.22,24.83 200.4,25.01 C372.1
PEG_TXN5_L3_N: length 8.6
  BOTTOM w0.076: CN13.11 206.67,21.89
  BOTTOM w0.102: 206.67,21.89 205.67,21.89 v2(205.15,22.42) 204.71,21.99 204.59,21.99 203.99,22.6 203.88,22.6 202.5,23.97 202.5,24.4 202.02,24.88 201.44,24.88 C372.2
PEG_TXN6_L1: length 139.6
  TOP w0.076: 106.5,87.04 106.5,87.02 106.51,87.01 106.51,86.2 U6.B14
  TOP w0.089: 106.5,87.04 106.5,87.27 106.6,87.38 106.6,89.16 106.56,89.2 106.37,89.2 106.17,89.01 v1(106.17,88.95)
  IN3 w0.102: v1(187.31,42.48) 187.54,42.48 187.66,42.6 187.66,42.84 180.64,49.86 180.64,57.62 174.52,63.74 174.52,65.21 164.92,74.81 164.92,78.42 159.28,84.06 159.28,91.3 157.51,93.08 157.51,94.15 153.21,98.44 126.39,98.44 125.63,97.68 112.78,97.68 111.19,96.09 111.19,95.57 107.06,91.44 107.06,90.84 106.58,90.35 106.58,89.36 v1(106.17,88.95)
  BOTTOM w0.102: v1(187.31,42.48) 187.5,42.48 187.7,42.67 187.7,42.97 188.08,43.35 191.58,43.35 v2(192.09,43.86) 192.6,43.35 196.68,43.35 197.75,42.28 198.61,42.28 198.75,42.42 C291.1
PEG_TXN6_L1_N: length 8.9
  BOTTOM w0.076: CN10.35 206.67,41.89
  BOTTOM w0.102: 206.67,41.89 205.74,41.89 v2(205.2,42.43) 204.94,42.18 203.88,42.18 203.47,42.59 199.74,42.59 C291.2
PEG_TXN6_L2_N: length 36
  TOP w0.102: C148.2 202.79,13.63 203.22,13.63 v1(203.34,13.76)
  IN1 w0.076: CN10.23 206.67,44.89
  IN1 w0.114: v1(203.34,13.76) 203.52,13.58 203.88,13.58 205.18,14.89 205.18,44.48 205.6,44.89 206.67,44.89
PEG_TXN6_L3: length 139.3
  TOP w0.076: U6.B15 107.25,86.17 106.84,86.58 106.84,86.94 106.97,87.06 106.97,88.22 v1(107.42,88.67)
  IN3 w0.102: v1(185.93,42.7) 185.93,43.42 179.41,49.94 179.41,57.19 173.71,62.89 173.71,64.87 164.11,74.47 164.11,78.08 157.23,84.96 157.23,89.15 157.99,89.92 157.99,90.83 155.14,93.67 155.14,95.11 152.63,97.63 136.52,97.63 135.75,96.85 113.1,96.85 112,95.75 112,94.94 108.66,91.59 108.66,91.28 107.39,90.01 107.39,88.7 v1(107.42,88.67)
  BOTTOM w0.102: C266.1 199.32,46.55 198.71,46.55 197.83,45.67 194.54,45.67 v2(194.02,46.19) 193.5,45.67 188.33,45.67 185.98,43.32 185.98,42.75 v1(185.93,42.7)
PEG_TXN6_L3_N: length 8.1
  BOTTOM w0.076: CN10.11 206.67,47.89
  BOTTOM w0.102: 206.67,47.89 204.97,47.89 v2(204.69,48.17) 204.28,47.77 202.86,47.77 201.84,46.75 200.78,46.75 C266.2
PEG_TXP4: length 110.9
  TOP w0.102: C18.1 118.95,92.06 118.95,94.14 120.57,95.77 120.57,100.59 121.63,101.65 151.88,101.65 155.35,98.18 155.35,91.69 155.07,91.41 155.07,77.33 155.35,77.05 155.35,72.89 v1(155.59,72.64)
  IN1 w0.114: v1(155.59,72.64) 155.32,72.37 155.32,70.41 167.25,58.48 167.25,57.38 v1(167.61,57.02)
  BOTTOM w0.102: v1(167.61,57.02) 167.27,57.36 167.27,57.47 170.7,60.9 179.61,60.9 180.68,59.83 180.98,59.83 181.3,59.52 181.3,59.43 181.18,59.31 CN9.35
PEG_TXP5_L0: length 146.3
  TOP w0.076: U6.C22 110.95,85.11 110.95,85.89 111.11,86.05 111.11,86.4 110.92,86.59 110.92,87.06 111.18,87.32 111.18,89.24 111.6,89.66 v1(112.15,89.66)
  IN3 w0.102: v1(112.15,89.66) 112.95,89.66 113.84,90.55 116.71,90.55 117.3,91.14 118.06,91.14 120.72,93.79 124.87,93.79 125.1,93.56 147,93.56 153.89,86.68 153.89,83.92 161.06,76.75 161.06,72.87 163.83,70.1 163.83,67.8 175.89,55.73 175.89,49.08 178.54,46.44 178.54,44.43 187.53,35.43 187.53,27.41 193.82,21.12 193.82,19.95 193.39,19.52 193.03,19.52 v1(192.84,19.34)
  BOTTOM w0.102: v1(192.84,19.34) 193.03,19.52 193.32,19.52 193.87,18.98 193.87,17.22 198.15,12.93 198.5,12.93 C402.1
PEG_TXP5_L1: length 139.2
  TOP w0.076: U6.A23 111.54,86.99 111.54,87.95 111.79,88.19 111.95,88.19 v1(112.15,88.39)
  IN3 w0.102: v1(191.21,20.61) 191.48,20.87 191.58,20.87 191.58,20.87 191.71,20.87 192.04,21.2 192.04,21.75 186.72,27.07 186.72,35.08 177.72,44.07 177.72,46.1 175.08,48.74 175.08,55.4 167.64,62.84 166.58,62.84 160.25,69.17 160.25,76.41 153.07,83.59 153.07,86.34 146.66,92.75 124.76,92.75 124.53,92.98 121.07,92.98 118.34,90.25 117.68,90.25 117.17,89.74 114.25,89.74 112.9,88.39 v1(112.15,88.39)
  BOTTOM w0.102: C395.1 197.98,17.78 196.4,17.78 193.31,20.87 191.48,20.87 v1(191.21,20.61)
PEG_TXP5_L1_N: length 9.9
  BOTTOM w0.102: C395.2 199.14,17.61 199.38,17.85 202.05,17.85 202.96,16.93 203.59,16.93 204.5,16.02 205.3,16.02 205.6,15.71 205.6,15.31 v2(205.76,15.15) 206.29,15.69 206.7,15.69 CN13.37
PEG_TXP5_L2: length 143.3
  TOP w0.076: U6.C21 110.13,85.09 110.13,85.85 110.35,86.07 110.35,86.27 110,86.62 110,87.84 v1(110.41,88.25)
  IN3 w0.102: v1(194.74,22.63) 194.45,22.34 193.75,22.34 188.34,27.75 188.34,35.77 179.35,44.76 179.35,46.79 177.04,49.1 177.04,55.74 167.39,65.39 167.39,66.55 165.48,68.45 165.48,69.72 161.87,73.33 161.87,77.08 154.7,84.26 154.7,88.68 152.88,90.5 151.21,90.5 147.34,94.38 125.44,94.38 125.21,94.61 119.9,94.61 119.3,94.01 119.3,93.55 117.7,91.95 116.17,91.95 115.66,91.44 114.68,91.44 114.55,91.57 113.07,91.57 111.43,89.92 111.43,88.98 110.7,88.25 v1(110.41,88.25)
  BOTTOM w0.102: v1(194.74,22.63) 194.96,22.41 194.96,22.05 196.73,20.28 196.97,20.28 v2(197.53,19.73) 198.04,20.24 198.44,20.24 C387.1
PEG_TXP5_L2_N: length 9.7
  BOTTOM w0.102: CN13.25 206.99,18.33 206.82,18.15 206.56,18.15 206.41,18.3 206.41,18.46 206.31,18.56 205.7,18.56 205.6,18.46 v2(205.6,18.15) 205.09,18.66 204.79,18.66 204.59,18.86 204.59,19.03 203.23,20.39 200.27,20.39 200.09,20.21 200.09,19.95 199.94,19.8 199.66,19.8 C387.2
PEG_TXP5_L3: length 143.1
  TOP w0.076: U6.A21 110.58,86.94 110.58,87.2 110.83,87.44 110.83,89.09 110.75,89.17 110.61,89.17 110.41,88.98 v1(110.41,88.89)
  IN3 w0.102: v1(190.73,27.4) 190.44,27.7 190.24,27.7 189.99,27.95 189.99,35.01 181.23,43.77 181.23,45.8 177.79,49.24 177.79,56.49 173.4,60.88 172.8,60.88 168.07,65.61 168.07,68.11 162.48,73.7 162.48,77.34 155.31,84.51 155.31,88.94 152.9,91.35 151.52,91.35 147.88,94.99 125.69,94.99 125.46,95.22 119.62,95.22 118.49,94.08 118.49,93.6 117.45,92.56 112.55,92.56 111.52,91.53 111.52,90.91 110.82,90.21 110.82,89.29 v1(110.41,88.89)
  BOTTOM w0.102: v1(190.73,27.4) 190.73,27.59 190.95,27.8 191.62,27.8 194.8,24.63 196.99,24.63 v2(197.53,24.09) 198.06,24.63 200.2,24.63 200.4,24.43 C377.1
PEG_TXP5_L3_N: length 8.6
  BOTTOM w0.102: CN13.13 206.73,21.39 206.62,21.5 206.62,21.59 206.51,21.69 205.69,21.69 v2(205.15,21.15) 204.97,21.33 204.97,21.63 204.82,21.78 204.51,21.78 203.9,22.39 203.79,22.39 202.3,23.88 202.3,24.31 201.94,24.68 201.31,24.68 201.18,24.55 C377.2
PEG_TXP6_L1: length 139.6
  TOP w0.076: 106.68,87.04 106.68,87.02 106.67,87.01 106.67,86.5 106.81,86.36 106.81,85.93 U6.C15
  TOP w0.089: 106.68,87.04 106.68,87.2 106.78,87.3 106.78,89.23 106.63,89.38 106.38,89.38 v1(106.17,89.59)
  IN3 w0.102: v1(106.17,89.59) 106.38,89.79 106.38,90.44 106.86,90.92 106.86,91.52 110.99,95.65 110.99,96.18 112.69,97.88 125.55,97.88 126.31,98.64 153.3,98.64 157.71,94.23 157.71,93.17 159.49,91.39 159.49,84.14 165.13,78.5 165.13,74.89 174.73,65.29 174.73,63.83 180.85,57.71 180.85,49.94 187.86,42.93 187.86,42.67 v1(188.05,42.48)
  BOTTOM w0.102: v1(188.05,42.48) 187.9,42.63 187.9,42.88 188.16,43.14 191.53,43.14 v2(192.09,42.59) 192.65,43.14 196.6,43.14 197.66,42.08 198.59,42.08 198.75,41.92 C299.1
PEG_TXP6_L1_N: length 8.9
  BOTTOM w0.102: C299.2 199.53,42.27 199.63,42.38 203.38,42.38 203.79,41.98 204.38,41.98 v2(205.2,41.16) 205.72,41.69 206.7,41.69 CN10.37
PEG_TXP6_L2_N: length 36
  TOP w0.102: v1(203.34,13.12) 203.04,13.43 202.96,13.43 202.86,13.32 202.86,13.07 202.68,12.89 C149.2
  IN1 w0.114: v1(203.34,13.12) 203.58,13.36 203.97,13.36 205.4,14.8 205.4,44.39 205.69,44.68 206.28,44.68 206.44,44.52 206.44,44.34 206.62,44.16 206.87,44.16 206.99,44.29 CN10.25
PEG_TXP6_L3: length 139.3
  TOP w0.076: v1(107.42,88.01) 107.21,88.01 107.13,87.93 U6.A15
  IN3 w0.102: v1(186.61,42.7) 186.54,42.7 186.13,43.1 186.13,43.51 179.62,50.02 179.62,57.27 173.91,62.98 173.91,64.95 164.31,74.55 164.31,78.16 157.43,85.05 157.43,89.07 158.19,89.83 158.19,90.91 155.35,93.76 155.35,95.2 152.71,97.83 136.44,97.83 135.66,97.05 113.01,97.05 111.8,95.84 111.8,95.02 108.46,91.68 108.46,91.36 107.19,90.09 107.19,89.05 107.01,88.87 107.01,88.42 v1(107.42,88.01)
  BOTTOM w0.102: v1(186.61,42.7) 186.51,42.7 186.18,43.03 186.18,43.23 188.42,45.47 193.48,45.47 v2(194.02,44.92) 194.56,45.47 197.92,45.47 198.8,46.34 199.39,46.34 C267.1
PEG_TXP6_L3_N: length 8.1
  BOTTOM w0.102: CN10.13 206.7,47.69 205.47,47.69 v2(204.69,46.9) 204.03,47.56 202.94,47.56 201.93,46.55 200.73,46.55 200.54,46.36 C267.2
PLTRST#: length 340.8
  TOP w0.102: v1(76.05,55.6) 78.14,55.6 80.87,58.33 84.41,58.33 86.61,56.13 90.69,56.13 R189.2 92.47,55.5 v1(92.85,55.12) ; v1(188.32,67.64) 188.32,66.96 187.65,66.29 186.44,66.29 185.67,65.52 R154.2 ; v1(201.59,38.67) 202.24,38.02 R205.2 202.22,37.53 200.59,35.91 200.59,33.19 199.27,31.87 199.04,31.87 196.26,29.09 196.26,26.11 198.34,24.03 198.34,11.75 v1(199.35,10.73) 199.35,9.67 199.94,9.08 R315.2 ; v1(76.71,34.16) 77.33,33.54 R224.1 ; R57.1 163.96,85.57 162.34,83.95 162.02,83.95 v2(161.89,83.82) 157.98,79.91 157.98,76.46 v1(158.12,76.33)
  IN1 w0.114: v1(158.12,76.33) 159.61,76.33 167.56,68.37 170.93,68.37 173.13,66.17 183.57,66.17 185.71,68.32 187.49,68.32 188.24,67.56 v1(188.32,67.64) 188.26,66.75 190.04,64.97 190.04,63.07 192.15,60.96 192.15,58.29 193.8,56.64 193.8,55.2 194.77,54.23 194.77,47.83 v1(194.06,47.12) ; v1(76.71,34.16) 76.4,34.47 69.42,34.47 68.28,33.32 62.39,33.32 61.95,33.76 60.86,33.76 v1(60.17,34.44)
  IN2 w0.114: v1(201.59,38.67) 199.86,38.67 196.56,41.98 v1(195.95,41.98)
  IN3 w0.102: v1(76.05,55.6) 76.05,53.47 75.31,52.73 75.31,37.97 75.62,37.67 75.62,35.26 v1(76.71,34.16) 75.01,32.46 75.01,23.03 75.85,22.19 76.92,22.19 81.08,18.03 v1(85.34,18.03) 85.52,18.21 92.33,18.21 93.14,19.02 115.36,19.02 121.23,13.15 130.35,13.15 130.98,13.78 144.16,13.78 146.03,15.65 151.85,15.65 152.97,14.53 187.2,14.53 190.53,11.2 198.89,11.2 v1(199.35,10.73) ; v1(195.95,41.98) 195.9,41.98 194.06,43.82 v1(194.06,47.12)
  BOTTOM w0.102: CN14.7 87.07,16.39 86.73,16.73 86.04,16.73 85.34,17.43 v1(85.34,18.03) ; U23.22 61.58,29.17 61.19,29.55 60.51,29.55 59.94,30.12 59.94,34.21 v1(60.17,34.44) ; U18.4 92.53,55.44 v1(92.85,55.12)
PROC_DETECT#: length 7.7
  TOP w0.076: U6.D61 135.68,85.18 135.68,85.41 136.03,85.76 136.61,85.76 136.68,85.83 137.02,85.83 137.24,86.05 137.24,86.07 137.42,86.25
  TOP w0.102: 137.42,86.25 138.1,86.93 138.1,88.52 139.04,89.46 TP5.1
PROCHOT_EC: length 13.5
  BOTTOM w0.102: v2(71.36,24.7) 71.36,25.44 70.9,25.91 Q24.2 69.52,26.49 68.58,27.43 68.58,27.94 68.44,28.08 R535.2 68.07,28.7 68.29,28.92 68.29,29.68 68.06,29.91 65.39,29.91 64.14,31.17 U23.17
PTP_PWR_EN#: length 59.9
  TOP w0.102: R781.1 R775.1 39.17,3.11 v2(41.29,3.11) 42.33,4.16 Q54.2 44.19,2.86 45.34,2.86 45.98,3.5 47.18,3.5 49.6,5.91 49.6,7.29 51.13,8.83 51.4,8.83 v1(53.89,11.32)
  IN3 w0.102: v1(53.89,11.32) 54.42,11.85 54.42,13.88 45.84,22.47 45.84,25.06 45.28,25.62 45.28,26.99 48.43,30.14 51.48,30.14 v1(52.44,31.1)
  BOTTOM w0.102: U23.99 49.59,38.43 49.76,38.25 50.12,38.25 52.26,36.11 52.26,32.35 52.44,32.17 v1(52.44,31.1)
PWR_DEBUG: length 27.1
  TOP w0.102: v1(152.65,89.87) 152.2,89.41 151.46,89.41 151.26,89.61 148.29,89.61 v2(146.73,91.17) 144.93,92.97 R31.1 ; CN1.53 163.25,94.49 161.43,92.66 159.44,92.66 159.08,93.01 v1(159.08,93.55)
  IN1 w0.114: v1(152.65,89.87) 155.78,89.87 156.11,89.53 157.25,89.53 157.88,90.16 157.88,90.83 159.08,92.02 v1(159.08,93.55)
PWR_DEBUG_R: length 16.8
  TOP w0.076: U6.H59 134.51,82.96 135.56,82.96 135.69,83.09 136.46,83.09 136.62,82.92 137.14,82.92
  TOP w0.102: v2(144.72,91.1) 144.55,90.93 R42.1 ; 137.14,82.92 139.01,84.79 139.35,84.79 139.83,85.26 139.83,87.06 142.56,89.79 143,89.79 143.65,90.43 R42.1 ; R31.2 143.65,91.95 R42.1
PWRLED#: length 44
  TOP w0.102: v2(45.99,8.22) 46.57,8.22 v1(47.01,8.65)
  IN1 w0.114: v1(47.01,8.65) 45.97,9.68 45.97,22.73 48.13,24.89 48.13,26.06 49.38,27.3 v1(49.94,27.3)
  BOTTOM w0.102: v1(49.94,27.3) 50.55,26.7 57.75,26.7 59.63,28.57 61.54,28.57 61.75,28.37 U23.24 ; CN18.4 52.45,7.83 51.21,6.59 50.27,6.59 49.85,7.01 48.64,7.01 v1(47.01,8.65)
R_PEG_TXN4: length 7.1
  TOP w0.102: U6.B29 115.65,86.41 115.87,86.41 116.08,86.61 116.08,88.04 117.13,89.09 117.41,89.09 117.46,89.14 117.46,89.16 117.9,89.6 117.92,89.6 118.3,89.98 119.07,89.98 119.3,90.22 119.3,90.49 C19.2
R_PEG_TXP4: length 7.1
  TOP w0.102: U6.A29 115.61,86.61 115.79,86.61 115.87,86.7 115.87,88.12 117.05,89.29 117.33,89.29 118.22,90.19 118.98,90.19 119.1,90.31 119.1,90.6 118.9,90.81 C18.2
R_SPK+: length 28.5
  TOP w0.203: U16.45 34.91,17.8 35.7,17.01 36.11,17.01 v1(36.35,16.76)
  IN3 w1.016: 37.15,15.69 37.15,13.72 38.35,12.52 38.35,11.36 38.35,8.31 37.54,7.49 35.21,5.17 34.07,5.17 31.82,2.92 22.35,2.92
  vias: v1(20.8,3.12) v1(21.46,3.17) v1(36.35,16.13) v2(21.17,2.48)
R_SPK-: length 25.4
  TOP w0.203: v1(35.31,16.74) 34.51,17.54 U16.44
  IN3 w1.016: 35.69,15.29 35.74,15.25 35.74,13.16 36.96,11.94 36.96,8.89 34.63,6.56 33.49,6.56 31.24,4.32 22.35,4.32
  vias: v1(20.8,4.44) v1(21.46,4.44) v1(35.31,16.1) v2(22.19,4.26)
RAM_ID0: length 20.5
  TOP w0.076: U6.AT3 99.23,66.56 98.72,66.56 98.54,66.74 98.54,66.94 98.31,67.17
  TOP w0.102: R148.2 84.15,67.5 84.97,67.5 85.21,67.74 85.68,67.74 R149.2 86.29,67.13 87.83,67.13 v2(87.98,67.28) 88.14,67.44 89.03,67.44 89.23,67.24 89.23,65.67 90.97,63.93 93.43,63.93 95.76,66.26 95.76,66.28 96.65,67.17 98.31,67.17
RAM_ID1: length 22.5
  TOP w0.102: R160.2 83.84,64 v2(83.84,63.05) 84.69,63.05 84.95,63.31 85.55,63.31 R161.2 86.32,63.93 87.22,63.93 v1(87.63,64.34) ; v1(99.82,68.74) 99.49,69.07 U6.AM3
  BOTTOM w0.102: v1(99.82,68.74) 99.42,69.13 98.09,69.13 97.67,68.71 94.6,68.71 93.43,69.87 90.97,69.87 89.18,68.08 89.18,65.89 v1(87.63,64.34)
RAM_ID2: length 24.5
  TOP w0.102: U6.AM2 98.84,69.08 v1(99.19,68.73) ; v1(87,65.15) 86.24,65.9 R152.2 85.79,66.61 84.28,66.61 R151.2 83.36,66.64 v2(81.78,66.64)
  IN3 w0.102: v1(99.19,68.73) 99.17,68.71 96.27,68.71 95.91,68.35 95.91,64.93 93.97,62.99 89.57,62.99 88.14,64.42 88.14,64.64 87.63,65.15 v1(87,65.15)
RAM_ID3: length 19.2
  TOP w0.102: U6.AH4 100.52,71.31 v1(100.63,71.43)
  BOTTOM w0.102: v1(100.63,71.43) 100.18,70.98 98.9,70.98 98.61,70.68 96.9,70.68 95.94,69.72 95.03,69.72 93.87,70.89 90.55,70.89 89.57,69.92 v2(87.8,69.92) 87.24,69.92 86.92,70.23 R413.2 85.99,69.72 85.34,69.72 84.71,70.36 R412.2
RF_EN: length 182.1
  IN1 w0.114: v1(57.18,30) 57.56,30.38 68.94,30.38 73.18,26.14 85.82,26.14 88.37,23.59 131.7,23.59 133.52,21.77 169.9,21.77 173.35,25.21 173.35,40.55 178.81,46.01 178.81,52.44 184.71,58.34 184.71,62.51 186.18,63.98 186.18,67.03 v1(186.36,67.21)
  BOTTOM w0.102: v1(186.36,67.21) 186.43,67.14 CN9.56 ; v1(57.18,30) 54.99,27.81 49.81,27.81 48.2,26.2 48.2,25.84 47.92,25.57 U23.66
RING2: length 19.9
  TOP w0.203: v1(35,25.48) 34.85,25.48 34.51,25.14 U16.17
  IN3 w0.508: v1(30.12,29.02) 30.12,28.17 30.17,28.13
  IN3 w1.016: 22.04,25.09 23.69,26.74 24.7,26.74 26.1,28.13 33.85,28.13 35.88,26.1
  BOTTOM w0.279: v1(30.12,29.02) 30.12,28.07 30.24,27.95 Q23.3
  vias: v1(21.74,25.12) v1(21.74,24.49) v1(36.07,25.78) v2(35.7,25.16)
RING2_R: length 16.7
  IN3 w1.016: 17.35,26.57 15.01,26.57 13.52,28.06 4.41,28.06 CN6.3
  vias: v1(17.4,25.53) v1(18.16,25.53) v2(19.24,25.8)
RSMRST#: length 63.9
  TOP w0.102: v1(91.95,56.16) 92.1,56.01 92.71,56.01 93.88,54.84 93.88,54.42 95.32,52.98 v2(95.54,52.98) 96.84,52.98 97.41,53.55 97.41,54.89 97.79,55.27 R182.1 R181.2
  IN1 w0.114: v1(56.2,35.85) 56.85,35.19 58.97,35.19 59.63,35.85 62.66,35.85 63.5,35 64.18,35 64.88,35.7 73.55,35.7 74.38,36.53 78.83,36.53 85.49,43.19 85.49,48.48 88.52,51.51 88.52,52.65 91.95,56.08 v1(91.95,56.16)
  BOTTOM w0.102: U23.112 54.79,38.3 55.31,37.79 55.31,36.73 v1(56.2,35.85)
RTC_RST#: length 97
  TOP w0.076: U6.AU7 102.35,66.25
  TOP w0.089: 102.35,66.25 102.9,66.8 v1(102.9,67.44)
  TOP w0.102: v1(88.01,59.44) 88,59.44 87.8,59.64 80.34,59.64 79.51,58.8 v2(78.35,58.8) 77.9,58.8 76.2,57.1 75.27,57.1 69.7,51.52 69.7,48.41 68.68,47.4 68.68,46.06 67.27,44.65 63.55,44.65 62.79,45.42 44.32,45.42 40.82,48.92 35.59,48.92 v1(33.78,47.12)
  IN3 w0.102: v1(88.01,59.44) 88.03,59.44 90.21,61.61 94.44,61.61 96.48,63.65 97.93,63.65 100.59,66.32 100.81,66.32 101.03,66.54 101.99,66.54 v1(102.9,67.44)
  BOTTOM w0.102: R496.1 v1(33.78,47.12) ; J2.1 103.5,58.3 R459.1 C249.1 103.53,59.58 103.53,61.9 102.87,62.56 102.87,63.53 103,63.65 103,66.65 102.9,66.75 v1(102.9,67.44)
RTC_X1: length 17.6
  TOP w0.076: 100.44,63.93 100.44,64.47 U6.AW5
  TOP w0.102: 100.44,63.93 100.44,63.45 100.22,63.22 97.69,63.22 97.46,63.45 95.86,63.45 94.28,61.87 90.63,61.87 90.19,61.43 90.19,61.22 C65.2 89.91,60.47 R173.2 89.91,59.32 90.18,59.04 90.18,58.27 89.95,58.04 Y2.1
RTC_X2: length 16.8
  TOP w0.102: Y2.2 90.64,58.04 90.41,58.27 90.41,59.04 90.69,59.32 R173.1 90.69,60.47 C66.2 90.41,61.21 90.41,61.33 90.73,61.65 94.38,61.65 95.99,63.26 97.38,63.26 97.61,63.03 100.29,63.03 100.63,63.37 100.63,64.05 U6.AY5
S5D: length 52.5
  TOP w0.254: PR47.2 38.79,58.52 PR38.2 35.94,59.82 35.43,60.33 PQ6.3 36.13,61.21 36.26,61.09 PC47.2 37.46,61.33 v1(37.79,61.66)
  IN3 w0.254: v1(62.3,80.08) 60.5,78.28 47.51,78.28 39.44,70.21 39.44,65.45 39.4,65.41 39.4,63.27 v1(37.79,61.66)
  BOTTOM w0.254: PQ27.2 62.3,78.93 v1(62.3,80.08) ; PQ30.4 40.81,65.66 40.64,65.49 40.64,65.02 v2(38.15,62.54) 38.04,62.42 38.04,62.36 37.79,62.1 v1(37.79,61.66)
S5ON: length 246.4
  TOP w0.254: v1(35.64,51.59) 35,50.95 PQ13.2
  IN1 w0.254: v1(159.66,57.78) 164.66,57.78 170.18,52.26 170.18,32.38 166.5,28.7 v1(166.5,26.06) ; v1(35.64,51.59) 35.65,51.6 40.65,51.6 41.38,50.87 41.7,50.87 44.28,48.29 48.27,48.29 49,49.01 54.7,49.01 55.09,49.4 56.66,49.4 56.99,49.08 60.91,49.08 62.36,47.62 v1(62.61,47.62)
  IN3 w0.254: v1(35.64,51.59) 36.27,50.95 37.33,50.95 43.38,44.9 47.59,44.9 48.77,43.72 v1(48.77,43.15) 49.79,42.13 51.34,42.13 53.7,39.78 61.44,39.78 63.37,37.85 63.37,25.15 64.64,23.88 72.52,23.88 79.92,16.47 92.8,16.47 v1(93.6,17.27)
  BOTTOM w0.203: U23.100 49.99,40.05 49.66,40.39
  BOTTOM w0.254: v1(62.61,47.62) 63.51,46.73 PR147.1 ; v1(159.66,57.78) PQ33.2 159.66,60.07 160.02,60.43 160.02,63.37 160.27,63.63 160.65,63.63 160.91,63.88 PQ29.2 ; v1(166.5,26.06) v2(165.33,24.89) 164.69,24.26 100.58,24.26 v1(93.6,17.27) ; 49.66,40.39 49.56,40.49 49.56,41.46 R506.2 48.77,42.25 v1(48.77,43.15)
SATA_IREF: length 7.4
  TOP w0.254: v1(104.6,89.78) 104.64,89.78 105.28,89.14 105.28,86.84 U6.A12
  BOTTOM w0.381: R337.1 106.2,92.58 v2(105.78,92.17) 105.22,91.61 105.22,90.66 104.84,90.27 104.84,90.02 v1(104.6,89.78)
SATA_LED#: length 15.4
  TOP w0.076: U6.U3 99.23,77.05 97.11,77.05
  TOP w0.102: 97.11,77.05 95.48,77.05 92.33,80.2 91.84,80.2 v2(91.81,80.23) 91.37,80.67 88.16,80.67 87.99,80.5 87.79,80.5 87.79,80.51 86,80.51 R82.2
SATA_RCOMP: length 8.8
  TOP w0.241: U6.C12 105.28,85.64 105.28,86.31 104.93,86.66 104.93,88.79 v1(104.57,89.14)
  BOTTOM w0.381: v1(104.57,89.14) 104.52,89.19 104.26,89.19 103.94,89.51 103.94,90.47 104.54,91.07 v2(104.54,91.76) 104.54,91.96 105.18,92.61 R336.2
SATA_RXN1/PEG_RXN6_L2: length 141.6
  TOP w0.102: R312.2 200.14,15.43 199.96,15.61 199.4,15.61 v1(199.16,15.37) ; v1(103.17,81.91) 103.17,81.64 103.07,81.53 102.75,81.53 U6.J8
  IN3 w0.102: v1(103.17,81.91) 103.34,81.91 103.43,81.83 103.43,81.81 103.93,81.31 106.29,81.31 106.65,81.67 106.65,82.85 107.19,83.39 107.19,84.57 107.77,85.16 111.19,85.16 111.73,85.7 114,85.7 114.03,85.74 133.21,85.74 133.96,84.99 136.21,84.99 136.44,84.76 138.66,84.76 141.3,82.12 141.3,80.97 143.36,78.91 143.36,77.87 146.29,74.93 146.29,73.68 168.12,51.85 168.12,50.84 174.29,44.67 174.29,41.05 183.87,31.48 183.87,24.04 192.2,15.71 199,15.71 199.16,15.55 v1(199.16,15.37)
  BOTTOM w0.102: v1(199.16,15.37) 199.4,15.61 199.96,15.61 200.14,15.43 R312.2
SATA_RXN1/PEG_RXP5_L0_N: length 8.4
  BOTTOM w0.076: CN13.43 207.78,13.88 206.8,13.88
  BOTTOM w0.102: C399.2 201.37,15.56 202.48,15.56 204.1,13.93 204.38,13.93 204.56,13.76 204.56,13.4 v1(204.56,13.4) 204.56,13.4 205.04,13.88 206.8,13.88
SATA_RXN3/PEG_RXN6_L0: length 128.7
  TOP w0.102: v1(101.26,83.97) 100.84,83.55 U6.F5
  IN3 w0.102: v1(101.26,83.97) 101.49,83.74 101.8,83.74 102.11,83.44 102.32,83.44 102.77,82.99 102.77,81.61 103.43,80.95 107.01,80.95 107.44,81.38 109.96,81.38 113.44,84.86 132.69,84.86 134.37,83.19 136.14,83.19 136.68,83.72 138.84,83.72 140.67,81.89 140.67,80.73 141.61,79.79 141.61,78.74 145.31,75.03 145.31,73.8 167.51,51.6 167.51,50.42 173.69,44.25 173.69,42.85 173.43,42.6 173.11,42.6 172.97,42.46 v1(172.97,42.29)
  BOTTOM w0.102: R519.2 200.91,40.78 200.8,40.88 181.12,40.88 179.17,42.83 173.35,42.83 172.97,42.46 v1(172.97,42.29)
SATA_RXN3/PEG_RXN6_L0_N: length 6.8
  BOTTOM w0.076: CN10.43 206.67,39.89
  BOTTOM w0.102: 206.67,39.89 205.98,39.89 205.77,40.1 204.23,40.1 v2(203.82,39.69) 203.39,40.12 202.9,40.12 202.42,40.6 201.9,40.6 R519.1
SATA_RXP1/PEG_RXN5_L0_N: length 8.4
  BOTTOM w0.102: C397.2 200.78,16.24 200.78,15.86 200.88,15.76 202.56,15.76 204.19,14.14 204.38,14.14 204.56,14.31 204.56,14.67 v1(204.56,14.67) 204.56,14.67 205.14,14.09 206.41,14.09 206.46,14.14 206.46,14.29 206.56,14.39 206.99,14.39 CN13.41
SATA_RXP1/PEG_RXP6_L2: length 141.7
  TOP w0.102: v1(103.17,82.55) 102.87,82.24 U6.H8 ; R311.2 200.14,15.99 199.96,15.81 199.47,15.81 v1(199.16,16.12)
  IN3 w0.102: v1(199.16,16.12) 198.96,15.92 192.28,15.92 184.07,24.13 184.07,31.56 174.5,41.14 174.5,44.75 168.33,50.93 168.33,51.93 146.5,73.76 146.5,75.02 143.56,77.95 143.56,78.99 141.5,81.06 141.5,82.21 138.74,84.96 136.52,84.96 136.3,85.19 134.04,85.19 133.29,85.94 113.95,85.94 113.91,85.9 111.65,85.9 111.1,85.36 107.69,85.36 106.98,84.66 106.98,83.47 106.45,82.94 106.45,81.75 106.21,81.51 104.01,81.51 103.63,81.89 103.63,82.09 v1(103.17,82.55)
  BOTTOM w0.102: v1(199.16,16.12) 199.47,15.81 199.96,15.81 200.14,15.99 R311.2
SATA_RXP3/PEG_RXP6_L0: length 128.7
  TOP w0.102: v1(101.26,84.6) 101.19,84.6 U6.E5
  IN3 w0.102: v1(172.97,43.04) 173.21,42.8 173.35,42.8 173.48,42.93 173.48,44.16 167.31,50.33 167.31,51.51 145.11,73.71 145.11,74.95 141.4,78.66 141.4,79.71 140.46,80.64 140.46,81.81 138.75,83.52 136.76,83.52 136.23,82.98 134.28,82.98 132.6,84.66 113.52,84.66 110.04,81.18 107.53,81.18 107.09,80.75 103.34,80.75 102.57,81.53 102.57,82.91 102.23,83.24 102.02,83.24 101.72,83.54 101.08,83.54 100.84,83.79 100.84,84.18 v1(101.26,84.6)
  BOTTOM w0.102: R516.2 200.59,41.09 181.2,41.09 179.25,43.04 v1(172.97,43.04)
SATA_RXP3/PEG_RXP6_L0_N: length 6.8
  BOTTOM w0.102: R516.1 201.68,40.97 201.84,40.81 202.5,40.81 202.99,40.33 203.34,40.33 203.82,40.81 v2(203.82,40.96) 204.49,40.3 205.86,40.3 206.06,40.1 206.7,40.1 CN10.41
SATA_TXN1/PEG_TXN5_L0_N: length 9.7
  BOTTOM w0.076: CN13.47 206.67,12.89
  BOTTOM w0.102: 206.67,12.89 206.23,12.89 v1(205.83,13.3) 205.52,12.99 204.15,12.99 203.32,12.16 202.44,12.16 201.13,13.46 200.02,13.46 C401.2
SATA_TXN1/PEG_TXN6_L2: length 139.2
  TOP w0.102: v1(200.91,13.97) 200.91,13.7 201.08,13.53 201.48,13.53 201.61,13.66 C148.1 ; U6.A17 108.25,87.18 108.25,87.76 108.43,87.95 108.43,88.24 108.52,88.33 108.52,88.52 108.65,88.65 v1(108.84,88.65)
  IN3 w0.102: v1(108.84,88.65) 109.18,88.31 109.44,88.31 109.73,88.02 109.73,87.5 110.51,86.72 112.59,86.72 112.95,87.07 113.95,87.07 114.27,86.75 138.76,86.75 142.47,83.04 142.47,81.31 144.37,79.41 144.37,78.31 147.72,74.97 147.72,73.69 170.38,51.03 170.38,50.03 175.31,45.1 175.31,41.83 181.8,35.34 181.8,34.98 184.89,31.9 184.89,24.46 191.76,17.59 198.55,17.59 200.07,16.08 200.07,13.84 200.28,13.63 200.73,13.63 200.91,13.82 v1(200.91,13.97)
  BOTTOM w0.102: C401.1 v1(200.91,13.97)
SATA_TXN3/PEG_TXN6_L0: length 137.9
  TOP w0.076: 107.63,87.12 107.59,87.08 107.59,86.69 107.92,86.36 107.92,85.98 107.75,85.82 107.75,85.74 U6.C17
  TOP w0.102: v1(108.46,89.2) 108.33,89.2 108.22,89.09 108.22,89.01 108.03,88.82 108.03,87.65 107.63,87.25 107.63,87.12
  IN3 w0.102: v1(108.46,89.2) 108.36,89.2 108.2,89.36 108.2,89.63 108.87,90.3 109.12,90.3 112.82,93.99 112.82,95.42 113.44,96.04 137.12,96.04 137.9,96.82 138.94,96.82 139.59,96.16 149.1,96.16 149.49,95.78 152.19,95.78 154.33,93.64 154.33,91.06 156.12,89.27 156.12,84.85 163.3,77.67 163.3,74.13 172.9,64.53 172.9,62.53 178.6,56.83 178.6,49.57 178.82,49.35 180.09,48.08 182.04,46.13 182.04,44.24 186.14,40.14 189.7,40.14 190.46,39.38 190.46,38.93 190.33,38.79 v1(190.1,38.79)
  BOTTOM w0.102: C310.1 198.75,39.54 198.53,39.32 196.52,39.32 196.25,39.59 190.72,39.59 190.44,39.31 190.44,38.9 190.34,38.79 v1(190.1,38.79)
SATA_TXN3/PEG_TXN6_L0_N: length 8.8
  BOTTOM w0.076: CN10.47 206.67,38.89
  BOTTOM w0.102: 206.67,38.89 205.59,38.89 v2(205.09,39.39) 204.89,39.18 203.09,39.18 202.78,39.49 199.79,39.49 C310.2
SATA_TXP1/PEG_TXP5_L0_N: length 9.8
  BOTTOM w0.102: 205.83,12.03 205.83,12.38 206.14,12.69 206.7,12.69 CN13.49 ; 205.83,12.03 v1(205.83,12.03) 205.83,12.03 ; 205.83,12.03 205.06,12.79 204.24,12.79 203.4,11.95 202.35,11.95 201.05,13.26 199.64,13.26 199.51,13.12 C402.2
SATA_TXP1/PEG_TXP6_L2: length 139.2
  TOP w0.102: v1(108.84,88.01) 108.76,88.01 108.44,87.69 108.44,87.09 108.23,86.88 U6.B17 ; C149.1 201.61,13.16 201.44,13.32 201.23,13.32 200.91,13 v1(200.91,12.7)
  IN3 w0.102: v1(200.91,12.7) 200.91,13.14 200.62,13.43 200.19,13.43 199.86,13.76 199.86,16 198.47,17.39 191.67,17.39 184.68,24.38 184.68,31.81 181.6,34.9 181.6,35.26 175.11,41.75 175.11,45.02 170.18,49.94 170.18,50.94 147.51,73.61 147.51,74.88 144.17,78.22 144.17,79.32 142.27,81.23 142.27,82.96 138.67,86.55 114.19,86.55 113.87,86.87 113.03,86.87 112.67,86.51 110.43,86.51 109.52,87.42 109.52,87.93 109.35,88.1 108.93,88.1 v1(108.84,88.01)
  BOTTOM w0.102: C403.1 v1(200.91,12.7)
SATA_TXP3/PEG_TXP6_L0: length 137.9
  TOP w0.076: 107.42,87.25 107.42,86.62 107.75,86.29 107.75,86.05 107.59,85.89 107.59,85.12 U6.D17
  TOP w0.102: v1(107.82,89.2) 107.82,87.73 107.42,87.33 107.42,87.25
  IN3 w0.102: v1(107.82,89.2) 108,89.38 108,89.71 108.79,90.5 109.04,90.5 112.61,94.07 112.61,95.5 113.35,96.24 137.03,96.24 137.81,97.02 139.02,97.02 139.67,96.37 149.19,96.37 149.57,95.99 152.27,95.99 154.53,93.72 154.53,91.15 156.32,89.36 156.32,84.93 163.5,77.76 163.5,74.22 173.1,64.62 173.1,62.62 178.8,56.92 178.8,49.66 178.97,49.49 180.24,48.22 182.25,46.22 182.25,44.32 186.22,40.34 189.79,40.34 190.67,39.46 190.67,38.97 v1(190.85,38.79)
  BOTTOM w0.102: v1(190.85,38.79) 190.64,39 190.64,39.22 190.8,39.39 196.17,39.39 196.44,39.12 198.37,39.12 C314.1
SATA_TXP3/PEG_TXP6_L0_N: length 8.8
  BOTTOM w0.102: C314.2 199.53,39.18 199.63,39.28 202.7,39.28 203,38.98 204.23,38.98 v2(205.09,38.12) 205.67,38.69 206.7,38.69 CN10.49
SB_ACDC: length 134.4
  IN1 w0.114: v1(64.57,27.71) 62.89,26.03 59.56,26.03 55.49,21.96 55.49,14.72 56.47,13.75 66.35,13.75 66.93,13.16 82.72,13.16 83.1,12.78 84.54,12.78 85.05,12.27 130.26,12.27 131.96,13.98 135.18,13.98 136.33,12.83 154.77,12.83 155.78,11.81 157.23,11.81 157.86,11.18 157.86,9.4 155.96,7.49 v1(153.92,7.49)
  BOTTOM w0.102: U23.21 63.68,29.57 64.63,28.62 v1(64.63,28.36) 64.63,27.78 v1(64.57,27.71)
  BOTTOM w0.254: v1(153.92,7.49) 153.67,7.75 PR165.1
SENSOR_EN: length 254.9
  TOP w0.102: v1(199.46,80.58) 199.21,80.83 199.21,82.87 R79.1 199.85,83.51 v2(199.85,84.37)
  IN1 w0.114: v1(199.46,80.58) 199.46,71.92 203.62,67.76 203.62,63.05 203.75,62.91 203.75,56.04 201.96,54.25 201.96,48.61 199.02,45.67 199.02,38.78 197.75,37.5 195.84,37.5 185.01,26.67 185.01,19.37 177.74,12.1 161.41,12.1 156.25,6.95 154.53,6.95 152.59,5.01 141.91,5.01 140.23,3.32 91.85,3.32 85.09,10.08 58.43,10.08 56.4,12.11 55.79,12.11 52.61,15.29 52.61,22.91 51.84,23.68 51.84,26.84 v1(52.29,27.29)
  BOTTOM w0.102: U23.126 60.39,36.01 58.8,34.42 58.8,30.1 55.99,27.29 v1(52.29,27.29) ; R780.1 195.58,79.89 195.9,79.57 198.44,79.57 v1(199.46,80.58)
SENSOR_INT: length 107.6
  TOP w0.102: v1(100.58,72.39) 100.82,72.15 U6.AG5
  IN1 w0.114: v1(100.58,72.39) 100.24,72.73 98.87,72.73 98.49,73.11 91.87,73.11 90.34,74.64 87.93,74.64 v1(86.93,75.63) ; v1(79.35,29.39) 78,30.73 71.27,30.73 70.18,31.83 59.89,31.83 58.12,33.6 49.2,33.6 v1(49.02,33.78)
  IN3 w0.102: v1(79.35,29.39) 79.35,29.68 80.77,31.1 80.77,36.22 78.38,38.6 78.38,38.91 78.13,39.16 78.13,49.11 79.22,50.21 79.22,53.44 78.03,54.63 78.03,56.07 77.5,56.61 77.5,59.9 78.03,60.44 78.03,61.51 77.59,61.95 77.59,68.73 78.21,69.34 78.21,69.76 82.11,73.66 84.27,73.66 84.61,74 84.61,74.4 84.43,74.57 84.43,74.92 84.69,75.18 86.49,75.18 v1(86.93,75.63)
  BOTTOM w0.102: R390.2 v1(86.93,75.63) ; U23.81 47.93,31.57 48.37,32.02 48.37,33.13 v1(49.02,33.78)
SENSOR_PCH_CLK: length 116.2
  TOP w0.076: U6.F3 99.23,83.3 98.81,82.88 97.77,82.88 97.72,82.83 97.31,82.83 v1(96.92,83.23)
  IN3 w0.102: v1(67.13,26.34) 67.34,26.14 67.49,26.14 67.67,26.31 67.67,30.34 72.01,34.69 72.01,43.46 69.81,45.65 69.81,50.27 71.58,52.03 71.58,55.49 69.81,57.25 69.81,59.09 70.48,59.76 70.48,69.34 74.24,73.1 74.24,78.12 76.23,80.1 76.23,81.76 77.34,82.87 77.34,88.33 79.15,90.14 87.66,90.14 89.09,88.71 89.09,86.67 93.22,82.55 96.96,82.55 97.12,82.71 97.12,83.02 97.07,83.07 v1(96.92,83.23)
  BOTTOM w0.102: v1(96.92,83.23) 97.12,83.43 97.12,83.92 96.34,84.7 90.87,84.7 88.89,86.68 85.28,86.68 85.03,86.93 85.03,87.18 R346.2 84.69,87.56 85.11,87.98 85.11,89.32 v2(85,89.42) ; R539.2 66.86,26.61 v1(67.13,26.34)
SENSOR_PCH_CLK_E: length 4.1
  BOTTOM w0.102: R539.1 65.7,26.28 65.6,26.18 65.25,26.18 v1(64.74,26.68) 64.74,26.25 64.68,26.19 64.29,26.19 63.98,25.88 63.81,25.88 63.73,25.97 U23.30
SENSOR_PCH_DAT: length 113.2
  TOP w0.076: U6.F2 98.84,83.14 98.74,83.05 97.73,83.05 v1(97.55,83.23)
  IN3 w0.102: v1(97.55,83.23) 97.35,83.02 97.35,82.62 97.05,82.32 93.12,82.32 88.86,86.58 88.86,88.62 87.57,89.92 79.25,89.92 77.57,88.24 77.57,82.78 76.45,81.66 76.45,80.01 74.47,78.03 74.47,73.01 70.71,69.25 70.71,59.66 70.04,58.99 70.04,57.34 71.81,55.58 71.81,51.93 70.04,50.17 70.04,45.75 72.24,43.55 72.24,34.59 67.89,30.25 67.89,26.22 67.58,25.91 67.34,25.91 v1(67.13,25.7)
  BOTTOM w0.102: v1(67.13,25.7) 66.9,25.47 R542.2 ; v1(97.55,83.23) 97.35,83.43 97.35,84.01 96.43,84.93 90.97,84.93 88.99,86.91 85.38,86.91 85.26,87.03 85.26,87.15 R347.2
SENSOR_PCH_DAT_E: length 4.2
  BOTTOM w0.102: U23.31 63.73,25.57 63.81,25.65 64.08,25.65 64.38,25.96 64.67,25.96 64.74,25.89 v1(64.74,25.41) 65.28,25.95 65.6,25.95 65.7,25.85 R542.1
SENSOR_SCL: length 247.1
  TOP w0.102: R787.1 203.4,75.66 203.54,75.66 203.55,75.64 v1(203.72,75.81)
  IN1 w0.114: v1(203.72,75.81) 203.95,75.58 204.84,75.58 205.68,74.74 205.68,64.48 204.36,63.17 204.36,55.79 202.57,54 202.57,48.35 199.63,45.41 199.63,38.53 198,36.89 196.09,36.89 185.62,26.42 185.62,19.12 177.99,11.49 161.66,11.49 156.5,6.34 154.79,6.34 151.97,3.52 148.01,3.52 147.13,4.4 142.64,4.4 140.96,2.71 91.6,2.71 84.84,9.47 55.99,9.47 54.73,10.73 54.73,12.31 51.42,15.61 51.42,22.52 51.23,22.72 51.23,27.85 50.09,28.99 50.09,30.76 v1(50.04,30.81)
  BOTTOM w0.102: R527.1 44.59,37.07 44.86,37.34 45.35,37.34 45.83,36.85 46.17,36.85 46.25,36.77 U23.94 48.03,36.77 48.11,36.85 49.23,36.85 50.16,35.92 50.16,30.94 v1(50.04,30.81) ; C219.1 202.95,76.32 203.47,75.81 v1(203.72,75.81) 203.98,75.55 204.64,75.55 204.74,75.65 CN7.12
SENSOR_SDA: length 246.1
  TOP w0.102: v1(203.72,75.15) 203.44,75.43 203.3,75.43 R788.1
  IN1 w0.114: v1(203.72,75.15) 203.92,75.34 204.74,75.34 205.44,74.64 205.44,64.58 204.12,63.27 204.12,55.89 202.33,54.1 202.33,48.45 199.39,45.51 199.39,38.63 197.9,37.13 195.99,37.13 185.38,26.52 185.38,19.22 177.89,11.73 161.56,11.73 156.4,6.58 154.69,6.58 151.87,3.77 148.11,3.77 147.23,4.64 142.54,4.64 140.86,2.96 91.7,2.96 84.94,9.72 56.09,9.72 54.97,10.83 54.97,12.41 51.67,15.71 51.67,22.62 51.47,22.82 51.47,27.95 50.33,29.09 50.33,30.47 v1(50.67,30.81)
  BOTTOM w0.102: C229.1 203.31,75.56 v1(203.72,75.15) 203.9,75.33 204.53,75.33 204.64,75.2 CN7.13 ; R525.1 44.59,37.79 44.81,37.57 45.44,37.57 45.92,37.08 46.17,37.08 46.25,37.17 U23.95 48.03,37.17 48.11,37.08 49.33,37.08 50.39,36.02 50.39,31.09 v1(50.67,30.81)
SIO_EXT_SCI#: length 95.2
  TOP w0.102: U6.G2 98.84,82.56 v1(99.18,82.22)
  IN3 w0.102: v1(68.71,24.89) 69.34,25.53 69.34,28.27 72.01,30.94 72.01,32.97 73.2,34.17 73.2,49.83 73.66,50.29 73.66,51.5 73.33,51.83 73.33,57.23 73,57.56 73,61.99 72.57,62.42 72.57,68.32 74.44,70.19 74.44,70.66 76.02,72.24 76.02,76.28 77.98,78.24 77.98,80.01 79.44,81.47 79.44,81.98 79.25,82.17 79.25,82.68 79.7,83.12 80.2,83.12 81.35,84.27 81.6,84.27 v1(81.61,84.26)
  BOTTOM w0.102: v1(99.18,82.22) 98.87,82.22 98.54,81.89 94.97,81.89 93.43,83.43 90.38,83.43 90.18,83.63 88.38,85.44 83.65,85.44 R352.2 82.78,84.98 82.06,84.98 81.61,84.53 v1(81.61,84.26) ; v1(68.71,24.89) v2(67.94,25.66) 67.56,26.03 67.56,26.8 67.08,27.28 64.32,27.28 63.87,27.73 63.87,28.59 63.69,28.77 U23.23
SIO_EXT_SMI#: length 105.8
  TOP w0.102: v1(100.65,81.06) 100.57,81.13 U6.K4
  IN1 w0.114: v1(61.49,32.28) 69.75,32.28 69.98,32.51 72.85,32.51 73.48,33.15 76.93,33.15 v1(76.93,33.16)
  IN3 w0.102: v1(76.93,33.16) 76.93,33.15 76.95,33.15 77.56,33.76 77.82,33.76 78.05,33.99 78.05,34.37 76.38,36.05 76.38,38.08 76.12,38.33 76.12,49.95 76.82,50.64 76.82,53.09 77.01,53.29 77.01,56.01 76.66,56.37 76.66,61.8 76.12,62.34 76.12,68.03 76.51,68.43 76.51,69.82 78.08,71.38 78.08,75.43 80.16,77.5 83.66,77.5 84.23,76.94 85.8,76.94 86.41,77.55 90.17,77.55 90.73,78.11 90.73,79.25 92,80.52 98.89,80.52 99.53,81.15 100.55,81.15 v1(100.65,81.06)
  BOTTOM w0.102: U23.15 61.81,31.97 v1(61.49,32.28) ; R353.2 86.45,84.79 87.47,84.79 v2(87.64,84.95) 88.18,84.95 89.98,83.15 90.18,82.95 93.12,82.95 94.66,81.41 96.65,81.41 97.34,80.71 98.14,80.71 98.97,81.54 100.16,81.54 v1(100.65,81.06)
SIO_RCIN#: length 96.2
  TOP w0.102: v1(99.84,76.22) 100.14,76.52 U6.V4
  IN1 w0.114: v1(70.28,41.52) 70.8,41.52 75.26,45.97 75.26,53.06 71.75,56.57 71.75,70.73 73.82,72.79 73.82,76.82 77.57,80.56 80.25,80.56 81.05,81.37 82.47,81.37 82.98,80.86 82.98,80.77 83.38,80.37 84.41,80.37 84.66,80.61 85.63,80.61 85.73,80.51 87.44,80.51 88.14,79.81 90.47,79.81 93.32,76.96 97.05,76.96 97.3,76.71 99.35,76.71 v1(99.84,76.22)
  BOTTOM w0.102: R384.2 86.63,77.66 86.76,77.54 90.98,77.54 92.53,75.99 92.54,75.99 92.55,75.97 94.04,75.97 94.49,76.42 98.42,76.42 98.63,76.63 99.57,76.63 99.84,76.36 v1(99.84,76.22) ; v1(70.28,41.52) 69.8,42 69.23,42 69.05,41.82 69.05,40.73 v2(68.54,40.22) 65,36.68 63.88,36.68 63.57,36.37 U23.4
SKU_ID0: length 16.6
  TOP w0.102: R94.2 84.17,79.08 86.21,79.08 86.22,79.09 86.55,79.09 86.76,78.88 87.33,78.88 87.49,79.04 88.09,79.04 88.7,79.65 90.43,79.65 93.44,76.65 v1(93.94,76.65) 94.3,76.65 94.99,75.96 97.31,75.96 97.33,75.94 97.64,75.94 97.66,75.96 98.07,75.96 U6.Y1
SKU_ID1: length 19.6
  TOP w0.102: U6.N5 100.82,79.75 v1(100.57,80)
  BOTTOM w0.102: v1(100.57,80) 100.53,80.05 99.59,80.05 99.51,80.12 98.92,80.12 98.49,79.7 96.99,79.7 96.25,80.44 94.23,80.44 93.32,81.35 92.33,81.35 91.88,81.8 90.36,81.8 v1(90.29,81.73) 90.04,81.73 88.65,83.12 88.31,83.12 87.94,82.74 87.09,82.74 86.68,83.15 84.55,83.15 84.14,82.74 R360.2
SLEEVE: length 18
  TOP w0.203: U16.18 34.11,25.68 v1(34.16,25.73)
  IN3 w1.016: 23.62,17.27 23.62,23.75 24.58,24.7 31.79,24.7 33.02,25.93
  vias: v1(21.79,17.2) v1(22.56,17.2) v1(33.2,25.58) v2(32.48,25.75)
SLEEVE_R: length 18.4
  IN3 w1.016: 18.14,15.8 17.17,15.8 15.2,13.83 4.07,13.83 CN6.4
  vias: v1(17.86,16.56) v1(18.8,16.56) v2(19.45,16.02)
SM_INTRUDER#: length 16.9
  TOP w0.076: v1(100.49,67.26) 100.71,67.04 100.71,66.67 100.97,66.42 101.22,66.42 101.5,66.14 U6.AU6
  BOTTOM w0.102: R465.1 v2(94.95,57.84) 94.18,58.6 94.18,63.93 97.07,66.82 100.05,66.82 v1(100.49,67.26)
SM_RCOMP_0: length 5.6
  TOP w0.178: U6.AU60 134.75,66.54 v1(134.86,66.64)
  BOTTOM w0.381: v1(134.86,66.64) 137.36,64.14 R439.1
SM_RCOMP_1: length 3.7
  TOP w0.305: v1(135.23,65.3) 135.04,65.49 U6.AV60
  BOTTOM w0.381: R438.1 136.35,63.86 135.23,64.98 v1(135.23,65.3)
SM_RCOMP_2: length 7.2
  TOP w0.178: U6.AU61 135.7,66.65 v1(136.26,66.65)
  BOTTOM w0.381: v1(136.26,66.65) 138.38,64.53 R440.1 138.78,63.04 v2(139.59,63.04)
SMB0ALERT#: length 11.6
  TOP w0.076: 97.35,70.36 97.39,70.31 98.41,70.31 98.84,69.88 U6.AL2
  TOP w0.102: R127.2 90.11,72.59 90.11,72.01 v1(90.22,71.91) 90.42,71.7 95.29,71.7 96.63,70.36 97.35,70.36
SMB1ALERT#: length 18
  TOP w0.076: 95.94,64.34 98.02,64.34 98.56,63.79 98.89,63.79 99.14,64.04 99.12,64.05 99.12,64.32 99.18,64.38 99.18,65.05 99.31,65.19 99.68,65.19 99.8,65.31 99.8,65.8 U6.AU4
  TOP w0.102: 95.94,64.34 95.57,64.34 93.91,62.69 90.3,62.69 88.97,61.36 88.53,61.36 87.77,62.11 87.77,62.29 v2(87.29,62.78) 87.2,62.86 R164.2
SMB_ME1_CLK: length 29.6
  TOP w0.076: U6.AU3 99.31,66.17 99.01,65.86 98.61,65.86 98.58,65.83 97.93,65.83
  TOP w0.102: R134.1 R139.1 79.09,69.11 79.86,69.11 80.01,68.96 82.19,68.96 82.69,69.45 Q11.4 83.57,69.09 83.36,68.88 v1(82.93,68.88) ; 97.93,65.83 97.24,65.83 v1(96.98,66.09)
  IN1 w0.114: v1(96.98,66.09) 96.98,67.08 96.74,67.32 95.99,67.32 92.28,71.04 89.16,71.04 88.1,69.98 88.1,69.38 87.53,68.8 86.23,68.8 84.93,70.1 83.67,70.1 82.93,69.37 v1(82.93,68.88)
SMB_ME1_DAT: length 32.8
  TOP w0.102: v1(81.91,71.4) 81.53,71.01 Q11.1 82.11,70.75 82.35,70.99 82.35,71.55 82.55,71.75 84.45,71.75 84.56,71.65 85.32,71.65 85.72,71.25 86.03,71.25 86.24,71.03 R135.1 R140.1 ; U6.AH3 99.19,71.61 v1(99.19,71.73)
  IN1 w0.114: v1(99.19,71.73) 98.42,70.96 98.42,68.45 97.54,67.56 96.09,67.56 92.38,71.28 89.06,71.28 87.86,70.08 87.86,69.48 87.43,69.04 86.33,69.04 85.03,70.35 82.97,70.35 v1(81.91,71.4)
SMB_PCH_CLK: length 24.5
  TOP w0.076: U6.AP2 98.61,67.6 98.32,67.9 97.61,67.9 97.41,67.69
  TOP w0.102: Q10.3 80.15,72.25 80.01,72.39 R130.2 80.39,71.77 80.89,71.77 v1(81.28,71.37) ; 97.41,67.69 96.77,67.69 96.52,67.94 v1(96.52,68.1)
  IN1 w0.114: v1(96.52,68.1) 96.52,69.6 96.14,69.98 94.38,69.98 92.42,71.93 85.81,71.93 85.76,71.88 81.79,71.88 v1(81.28,71.37)
SMB_PCH_DAT: length 17.9
  TOP w0.102: v1(96.65,71.78) 97,71.78 97.43,71.35 U6.AH1 ; v1(85.34,72.75) 85.27,72.81 R126.2 85.2,73.55 Q10.6
  IN1 w0.114: v1(96.65,71.78) 96.65,70.61 96.25,70.22 94.48,70.22 92.52,72.17 85.91,72.17 v1(85.34,72.75)
SMBALERT#: length 11.7
  TOP w0.076: U6.AN2 98.74,68.45 98.73,68.45 98.38,68.81 97.79,68.81 97.7,68.9
  TOP w0.102: 97.7,68.9 96,68.9 94.12,70.78 v1(93.18,70.78) 93,70.96 91.19,70.96 89.7,69.47 R141.2
SMBCLK0: length 13.4
  TOP w0.089: U6.AN1 97.49,68.35 97.35,68.5 95.76,68.5
  TOP w0.102: 95.76,68.5 95.44,68.5 v1(94.15,69.79) 93.86,70.08 90.88,70.08 89.45,68.65 86.69,68.65 R145.2
SMBDATA0: length 16.1
  TOP w0.102: U6.AK1 96.68,70.6 95.37,71.91 91.17,71.91 90.08,72.99 v1(90.08,73.45) 89.52,74.01 84.99,74.01 R116.2
SPD_A0: length 4.2
  TOP w0.102: v2(73.12,63.36) 73.24,63.48 v1(74.44,63.48) U9.1
  BOTTOM w0.102: R430.2 74.42,63.5 v1(74.44,63.48) 74.42,63.46 R441.2
SPD_A1: length 6.2
  TOP w0.102: U9.2 75.71,63.48 v1(75.69,63.5) 73.87,65.32 v2(73.17,65.32)
  BOTTOM w0.102: R431.2 v1(75.69,63.5) R442.2
SPD_A2: length 3.8
  TOP w0.102: U9.3 v1(76.98,63.48)
  BOTTOM w0.102: R443.2 76.96,63.46 v1(76.98,63.48) 76.96,63.5 R432.2 77.49,64.13 77.5,64.11 v2(77.89,64.11)
SPD_CLK: length 2.9
  TOP w0.102: U9.6 76.98,66.33 v1(76.96,66.31)
  BOTTOM w0.102: R422.1 v1(76.96,66.31) 77.19,66.08 v2(77.62,66.08)
SPD_DAT: length 3.4
  TOP w0.102: U9.5 78.25,66.51 v1(78.49,66.28)
  BOTTOM w0.102: v2(79.17,67.38) 78.43,67.38 R423.1 78.23,66.55 78.36,66.42 78.36,66.4 v1(78.49,66.28)
SPD_WP: length 4.2
  TOP w0.102: U9.7 v1(75.71,66.29)
  BOTTOM w0.102: v2(75.02,66.11) 75.52,66.11 v1(75.71,66.29) 75.69,66.31 R421.1 R420.1
SPI_CS0#_UR_ME: length 37.1
  TOP w0.102: v1(73.76,47.57) 73.58,47.75 v2(73.04,47.75) 71.73,47.75 70.74,46.76 70.74,45.01 68.47,42.74 67.84,42.74 67.37,42.27 62.46,42.27 61.99,42.74 51.78,42.74 50.04,41 v1(50.04,40.77)
  BOTTOM w0.102: v1(50.04,40.77) 50.39,40.41 U23.101 ; v1(73.76,47.57) 74.96,47.57 76.2,48.82 76.2,49.01 R487.1 76.72,49.39 77.09,49.76 77.09,51.98 76.7,52.37 R482.2
SPI_HOLD_IO3_ME: length 15
  TOP w0.102: R177.1 74.55,58.93 v1(73.41,57.78)
  BOTTOM w0.102: U19.7 73.79,57.18 73.41,57.56 v1(73.41,57.78) 73.91,58.29 74.93,58.29 75.54,58.9 78.08,58.9 78.23,59.05 v2(78.23,59.38) 78.23,59.69 77.98,59.94 77.04,59.94 76.94,59.84 76.94,59.54 76.83,59.44 76.63,59.44 76.53,59.54 76.53,59.84 76.43,59.94 76.23,59.94 76.12,59.84 76.12,59.54 76.02,59.44 75.82,59.44 75.72,59.54 75.72,59.84 75.62,59.94 75.32,59.94 R177.1
SPI_WP_IO2_ME: length 17.8
  BOTTOM w0.102: U19.3 72.52,49.91 72.39,50.04 72.39,51.18 72.61,51.4 72.61,51.54 71.96,52.18 71.96,52.33 72.11,52.47 72.25,52.47 72.89,51.83 73.04,51.83 73.18,51.97 73.18,52.12 72.54,52.76 72.54,52.9 72.68,53.05 72.83,53.05 73.47,52.4 73.61,52.4 73.76,52.55 73.76,52.69 73.11,53.33 73.11,53.48 73.26,53.62 73.4,53.62 74.04,52.98 74.19,52.98 74.33,53.12 74.33,53.27 73.69,53.91 73.69,54.05 73.83,54.2 73.98,54.2 74.62,53.55 74.76,53.55 74.8,53.59 76.7,53.59 R478.1 76.7,54.85 R475.1 v1(77.64,54.86)
SPK_L+:
  vias: v1(16.76,6.98) v1(17.4,6.98) v2(16.32,7.69)
SPK_L-:
  vias: v1(16.73,5.53) v1(17.31,5.78) v2(16.25,6.09)
SPK_R+:
  vias: v1(15.95,3.02) v1(16.59,3.02) v2(17.31,3.12)
SPK_R-:
  vias: v1(16.08,4.34) v1(16.71,4.34) v2(17.29,4.79)
SPKR: length 108.4
  TOP w0.076: 97.49,76.3 98.47,76.3 98.76,76.6 U6.V2
  TOP w0.102: D8.2 42.67,34.75 v2(42.66,34.76) 42.95,35.05 v1(43.28,35.05) ; 97.49,76.3 97.37,76.42 95.1,76.42 94.19,77.33 93.33,77.33 90.6,80.06 88.51,80.06 87.92,79.47 87.13,79.47 v1(87.04,79.57) 86.91,79.7 R88.1
  IN1 w0.114: v1(43.28,35.05) 44.09,34.24 59.37,34.24 60.02,34.89 61.85,34.89 63.19,33.55 68.07,33.55 69.22,34.7 77.11,34.7 v1(77.65,34.16)
  IN3 w0.102: v1(77.65,34.16) 77.65,34.27 76.02,35.9 76.02,37.93 75.77,38.18 75.77,50.09 76.47,50.79 76.47,53.24 76.66,53.43 76.66,55.86 76.3,56.22 76.3,61.65 75.06,62.9 75.06,67.48 76.16,68.58 76.16,69.96 77.72,71.53 77.72,75.58 80.01,77.86 82.43,77.86 83.82,79.25 86.72,79.25 v1(87.04,79.57)
SRTC_RST#: length 12.7
  TOP w0.076: v1(96.59,62.75) 96.59,62.4 95.77,61.58 95.76,61.58
  TOP w0.102: 95.76,61.58 95.37,61.58 94.49,60.71 C67.1 94.24,60.39 94.5,60.14 R174.1
  TOP w0.152: U6.AV6 101.22,65.79 101.21,65.79 v1(101.03,65.97)
  BOTTOM w0.102: v1(101.03,65.97) 100.75,65.69 98.48,65.69 97.99,65.2 97.38,65.2 95.93,63.75 v2(95.93,63.01) 96.18,62.75 v1(96.59,62.75)
SUSACK#_R: length 14.9
  TOP w0.076: U6.AK2 98.7,70.6 98.41,70.89 97.28,70.89 97.04,71.13 96.43,71.13
  TOP w0.102: 96.43,71.13 95.45,72.11 91.71,72.11 v1(91.43,72.38) 90.67,73.15 90.67,73.73 89.78,74.62 R120.1 88.7,74.21 86.71,74.21 R119.1
SUSB#: length 102.1
  TOP w0.102: v1(45.85,31.75) 45.85,32 46.33,32.49 46.33,39.88 40.25,45.96 39,45.96 v1(37.85,47.12) 38.1,47.37 40.73,47.37 43.78,44.32 62.34,44.32 63.1,43.56 67.81,43.56 69.77,45.52 69.77,46.94 70.79,47.96 70.79,51.07 75.73,56.01 78.26,56.01 80.78,58.53 84.5,58.53 86.14,56.89 v2(86.88,56.89) 87.02,57.02 87.21,57.02 87.39,57.2 v1(87.39,57.53) ; U6.AT4 100.14,66.93 v1(99.84,67.23)
  IN3 w0.102: v1(99.84,67.23) 99.84,66.53 97.82,64.52 96.37,64.52 94.15,62.3 89.92,62.3 86.98,59.36 86.98,57.94 v1(87.39,57.53)
  BOTTOM w0.102: U23.82 46.07,31.97 v1(45.85,31.75) ; R500.1 v1(37.85,47.12)
SUSC#: length 118.7
  TOP w0.102: U6.AJ6 101.47,71.01 v1(101.89,71.43) ; v1(86.11,57.78) 85.26,58.63 85.21,58.63 84.9,58.94 80.61,58.94 78.54,56.86 v2(77.33,56.86) 76.93,56.86 76.48,56.41 75.56,56.41 70.38,51.24 70.38,48.13 69.37,47.11 69.37,45.69 67.64,43.97 63.27,43.97 62.5,44.73 43.95,44.73 40.44,48.23 36.93,48.23 v1(35.81,47.12) 36.45,46.48 38.19,46.48 38.96,45.72 40.16,45.72 46.08,39.8 46.08,32.61 v1(45.21,31.75)
  IN3 w0.102: v1(101.89,71.43) 101.88,71.43 101.46,71.01 101.05,71.01 100.78,70.74 99.06,70.74 98.2,69.88 96.24,69.88 95.5,69.14 95.5,65.1 94.13,63.73 90.88,63.73 87.88,66.73 86.83,66.73 86.39,66.28 86.39,63.19 86.66,62.91 86.66,59.99 85.7,59.03 85.7,58.19 v1(86.11,57.78)
  BOTTOM w0.102: R498.1 v1(35.81,47.12) ; v1(45.21,31.75) 45.83,32.37 U23.83
SUSLED#: length 41.1
  TOP w0.102: v2(48.68,7.99) 48.38,7.99 v1(47.77,8.6)
  IN1 w0.114: v1(47.77,8.6) 46.23,10.14 46.23,21.72 48.41,23.9 48.41,25.68 48.84,26.11 v1(49.45,26.11)
  BOTTOM w0.102: v1(47.77,8.6) 49.15,7.22 49.93,7.22 50.35,6.8 51.13,6.8 51.95,7.62 CN18.5 ; v1(49.45,26.11) 50.27,26.11 50.44,26.29 61.47,26.29 61.95,26.77 U23.28
SUSON: length 275.3
  TOP w0.102: PR61.1 83.56,37.73 85.01,36.28 85.01,24.08 85.47,23.62 v1(87.12,23.62) ; PR23.1 187.26,62.48 v2(187.14,62.36) 186.31,62.36 v1(185.93,61.98)
  TOP w0.254: v1(25.15,63.53) PQ3.2
  IN1 w0.114: v1(185.93,61.98) 185.67,61.72 185.67,58.99 179.04,52.35 179.04,45.92 173.58,40.46 173.58,25.12 170,21.54 133.42,21.54 131.6,23.36 87.38,23.36 v1(87.12,23.62) 85.98,24.77 71.99,24.77 70.71,26.04 70.71,28.28 68.89,30.1 58.04,30.1 v1(57.81,29.87) 57.51,29.57 57.01,29.57 53.54,33.03 49.56,33.03 48.96,32.44 45.21,32.44 44.92,32.73 42.54,32.73 38.12,37.15 27.4,37.15 23.85,33.59 21.97,33.59 18.45,37.11 18.45,43.06 17.68,43.83 17.68,60.48 18.03,60.83 19.68,60.83 22.31,63.46 25.08,63.46 v1(25.15,63.53)
  BOTTOM w0.102: R514.1 59.19,41.7 U23.123 59.19,38.1 59.26,38.02 59.26,37.42 58.23,36.39 58.23,30.29 v1(57.81,29.87)
SYS_HWPG: length 38
  TOP w0.254: PR22.2 50.06,62.8 50.69,62.8 v1(50.85,62.64) 51.11,62.39 51.11,62.38 51.23,62.27 v1(51.23,62.16) ; PR40.2 PR44.2 59.56,58.92 v1(59.56,58.99)
  IN1 w0.254: v1(59.56,58.99) 59.56,53.92 56.35,50.71 47.92,50.71 47.41,50.21 47.41,49.6 47.06,49.24 45.18,49.24 v1(45.13,49.29)
  IN2 w0.254: v1(51.23,62.16) 51.23,60.41 53.59,58.04 58.61,58.04 v1(59.56,58.99)
  BOTTOM w0.254: v1(45.13,49.29) 45.13,49.24 44.71,48.82 D26.1
SYS_PWROK: length 166.6
  TOP w0.102: v1(92.84,52.4) 91.4,52.4 R193.2 R192.2 90.64,54.03 89.74,54.03 88.11,55.65 86.41,55.65 84.21,57.85 81.09,57.85 79.38,56.13 v1(79.38,56.01) ; v1(89.64,76.05) 89.09,76.6 R108.2 ; R4.1 162.43,99.37 161.56,100.24 159.6,100.24 155.96,103.89 91.96,103.89 90.4,102.33 90.4,94.33 86.62,90.55 79.38,90.55 78.11,89.27 78.11,85.02 76.89,83.8 76.89,79.04 76.68,78.84 76.68,78.38 v2(77.63,77.44) 78.49,76.58 78.49,75.82 79.79,74.52 80.52,74.52 v1(80.53,74.53) 80.53,74.64 81.08,75.19 R115.2
  IN1 w0.114: v1(80.53,74.53) 80.29,74.29 79.52,74.29 79.36,74.12 78.79,74.12 78.06,73.39 78.06,70.66 77.17,69.77 77.17,68.12 77.88,67.41 77.88,65.38 79.17,64.09 79.17,60.56 79.95,59.78 79.95,56.58 v1(79.38,56.01)
  IN3 w0.102: v1(89.64,76.05) 89.63,76.04 84.16,76.04 83.33,75.21 81.21,75.21 v1(80.53,74.53)
  BOTTOM w0.102: v1(92.84,52.4) 92.72,52.29 U20.4
SYS_PWROK_R: length 13.8
  TOP w0.076: 96.8,72.75 96.92,72.62 97.76,72.62 98,72.39 98.41,72.39 98.7,72.1 U6.AG2
  TOP w0.102: v2(93.16,73.32) 93.16,73.35 ; 93.16,73.35 93.5,73 96.55,73 96.8,72.75 ; 93.16,73.35 91.05,75.45 91.05,76.8 90.39,77.45 90.2,77.45 C47.1 R108.1 R107.1
SYS_RESET#: length 322.7
  TOP w0.102: U6.AC3 99.17,73.99 97.84,73.99 v1(97.75,73.9) ; v1(79.4,59.37) 77.79,59.37 76,57.58 75.07,57.58 69.22,51.72 69.22,48.61 68.2,47.6 68.2,46.27 67.07,45.14 63.75,45.14 62.99,45.9 44.53,45.9 41.02,49.4 35.18,49.4 34.67,48.89 33.53,48.89 v1(31.75,47.12) ; v1(156.34,71.63) 158.12,73.41 158.12,74.17 157.48,74.8 157.48,81.91 v2(159.07,83.49) 159.85,83.49 161.65,85.29 161.65,85.75 161.93,86.03 R55.1
  IN1 w0.114: v1(156.34,71.63) 156.34,70.27 171.28,55.33 171.28,28.79 172.24,27.83 v1(172.24,25.35) ; v1(78.49,53.24) 78.14,53.59 78.14,55.78 79.4,57.05 v1(79.4,59.37) 78.68,60.1 78.68,63.88 77.39,65.17 77.39,66.63 76.68,67.34 76.68,69.98 77.57,70.87 77.57,73.59 79.55,75.58 81.13,75.58 81.63,75.09 84.33,75.09 84.43,75.19 85.89,75.19 86.77,76.07 88.07,76.07 89,75.13 90.55,75.13 92.07,73.61 97.46,73.61 v1(97.75,73.9)
  IN3 w0.102: v1(78.49,53.24) 77.66,52.41 77.66,50.3 76.96,49.6 76.96,38.68 77.22,38.43 77.22,37.87 77.9,37.19 77.9,36.61 79.6,34.9 79.6,33.22 77.98,31.59 77.98,28.5 78.15,28.34 78.15,25.57 80.21,23.5 80.21,23.05 82.3,20.95 84.75,20.95 85.05,21.25 132.04,21.25 133.18,20.12 167,20.12 v1(172.24,25.35)
  BOTTOM w0.102: R485.2 93.29,52.9 80.89,52.9 80.77,52.78 78.94,52.78 v1(78.49,53.24) ; R494.1 v1(31.75,47.12)
SYS_SHDN#: length 268
  TOP w0.102: Q2.3 140.29,96.28 142.29,98.27 v1(142.29,99.86) 142.29,100.25 142.88,100.84 v2(144.06,100.84) 151.54,100.84 154.53,97.84 154.53,92.18 154.25,91.9 154.25,75.13 153.99,74.87 153.99,72.83 154.96,71.87 154.96,70.07 v1(154.83,69.94) ; v1(27.94,66.55) 36.58,66.55 41.4,61.73 41.4,61.29 v1(41.53,61.16) 41.53,61.09 41.9,60.71 PR32.2 ; v1(58.92,61.31) 58.84,61.24 58.84,60.93 PR31.1 ; PR37.2 50.16,60.71 v1(49.91,60.96)
  IN1 w0.114: v1(41.53,61.16) 42.11,60.58 49.53,60.58 v1(49.91,60.96) 55.5,60.96 55.85,61.31 v1(58.92,61.31)
  IN3 w0.102: v1(27.94,66.55) 27.94,66.7 34.58,73.35 37.63,73.35 50.14,85.85 53.72,85.85 57.66,89.79 57.66,89.81 60.81,92.96 60.83,92.96 64.26,96.39 71.12,96.39 v1(74.55,99.82) ; v1(13.53,91.88) 14.07,91.34 14.07,88.98 13.94,88.85 13.94,76.05 16.85,73.15 18.73,73.15 25.65,66.23 v1(25.65,64.39)
  BOTTOM w0.102: D16.1 C176.1 14.57,90.44 13.53,91.48 v1(13.53,91.88) 12.99,92.42 11.43,92.42 SW1.1 ; v1(25.65,64.39) 27.81,66.55 v1(27.94,66.55) ; v1(154.83,69.94) 154.83,69 159.06,64.77 PQ32.3 ; v1(74.55,99.82) 76.3,98.07 85.17,98.07 91.52,104.42 126.59,104.42 129.72,101.3 135.46,101.3 136.42,100.33 141.82,100.33 v1(142.29,99.86)
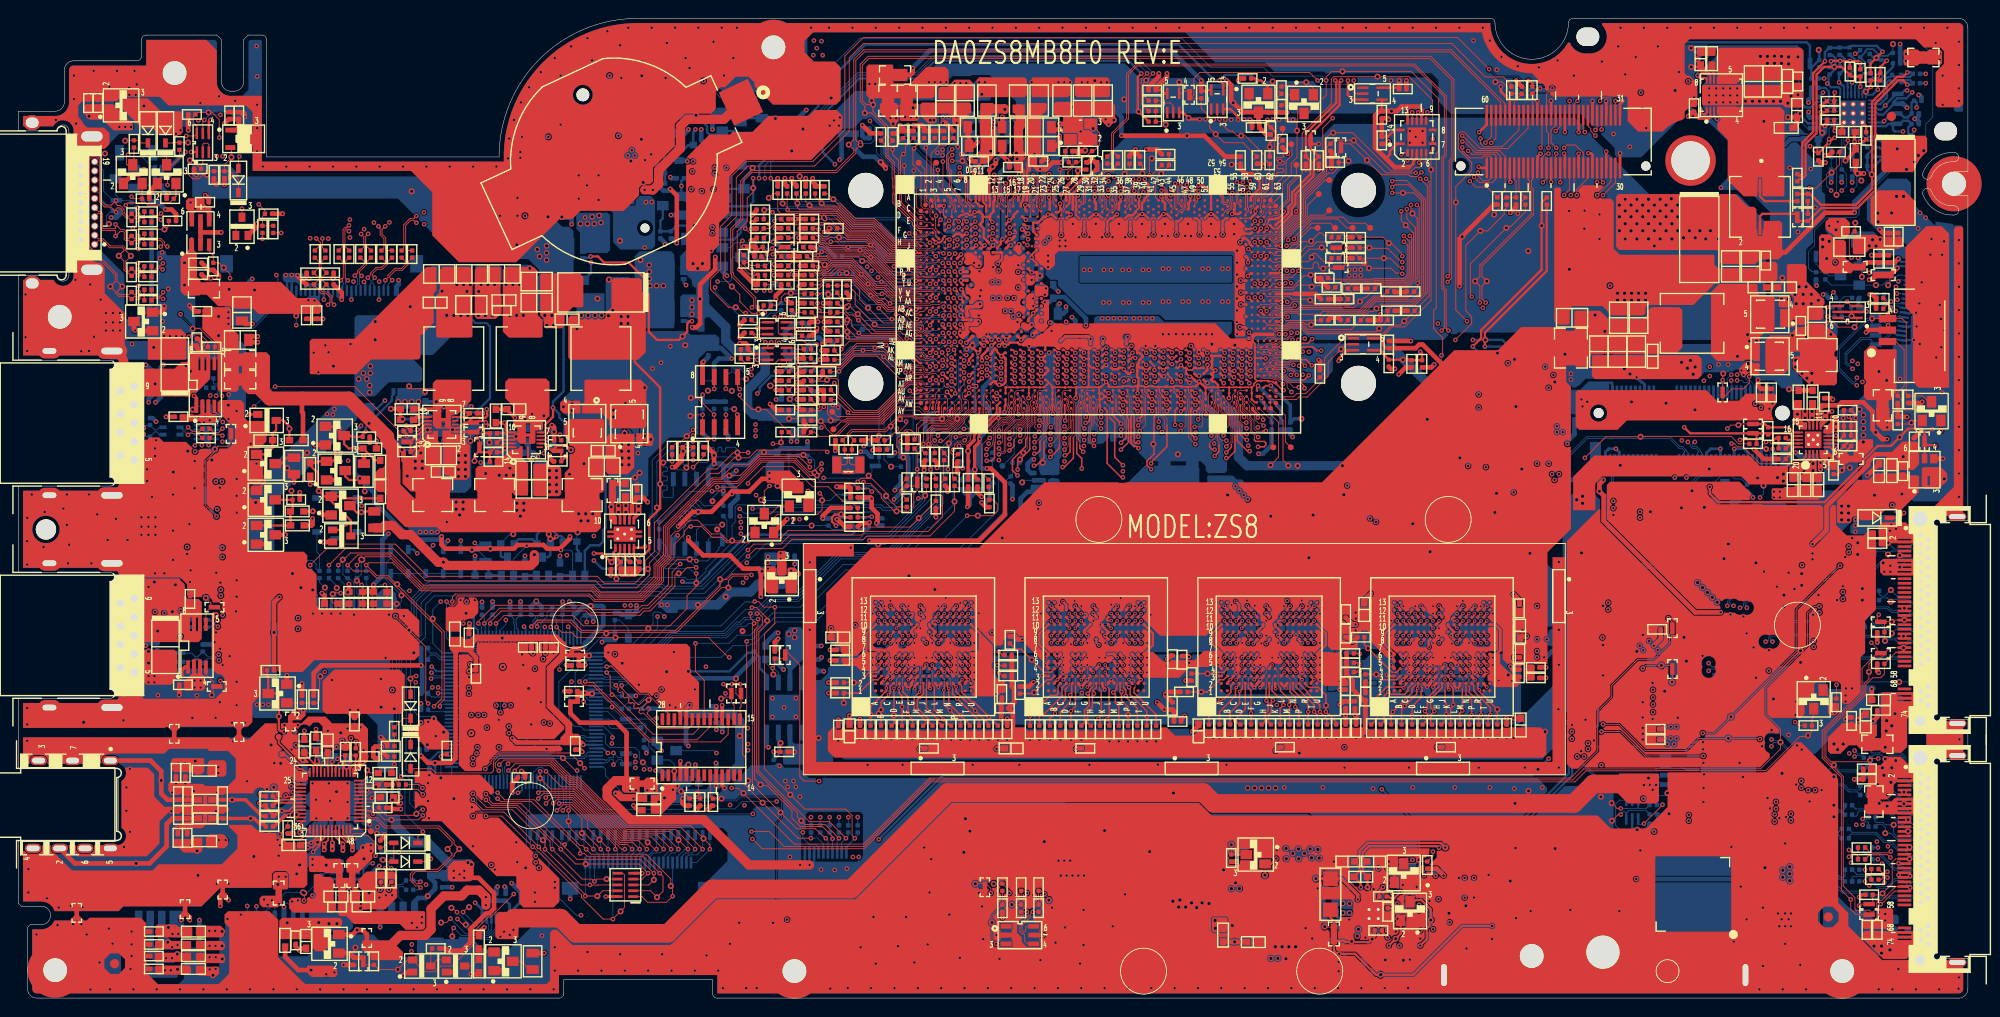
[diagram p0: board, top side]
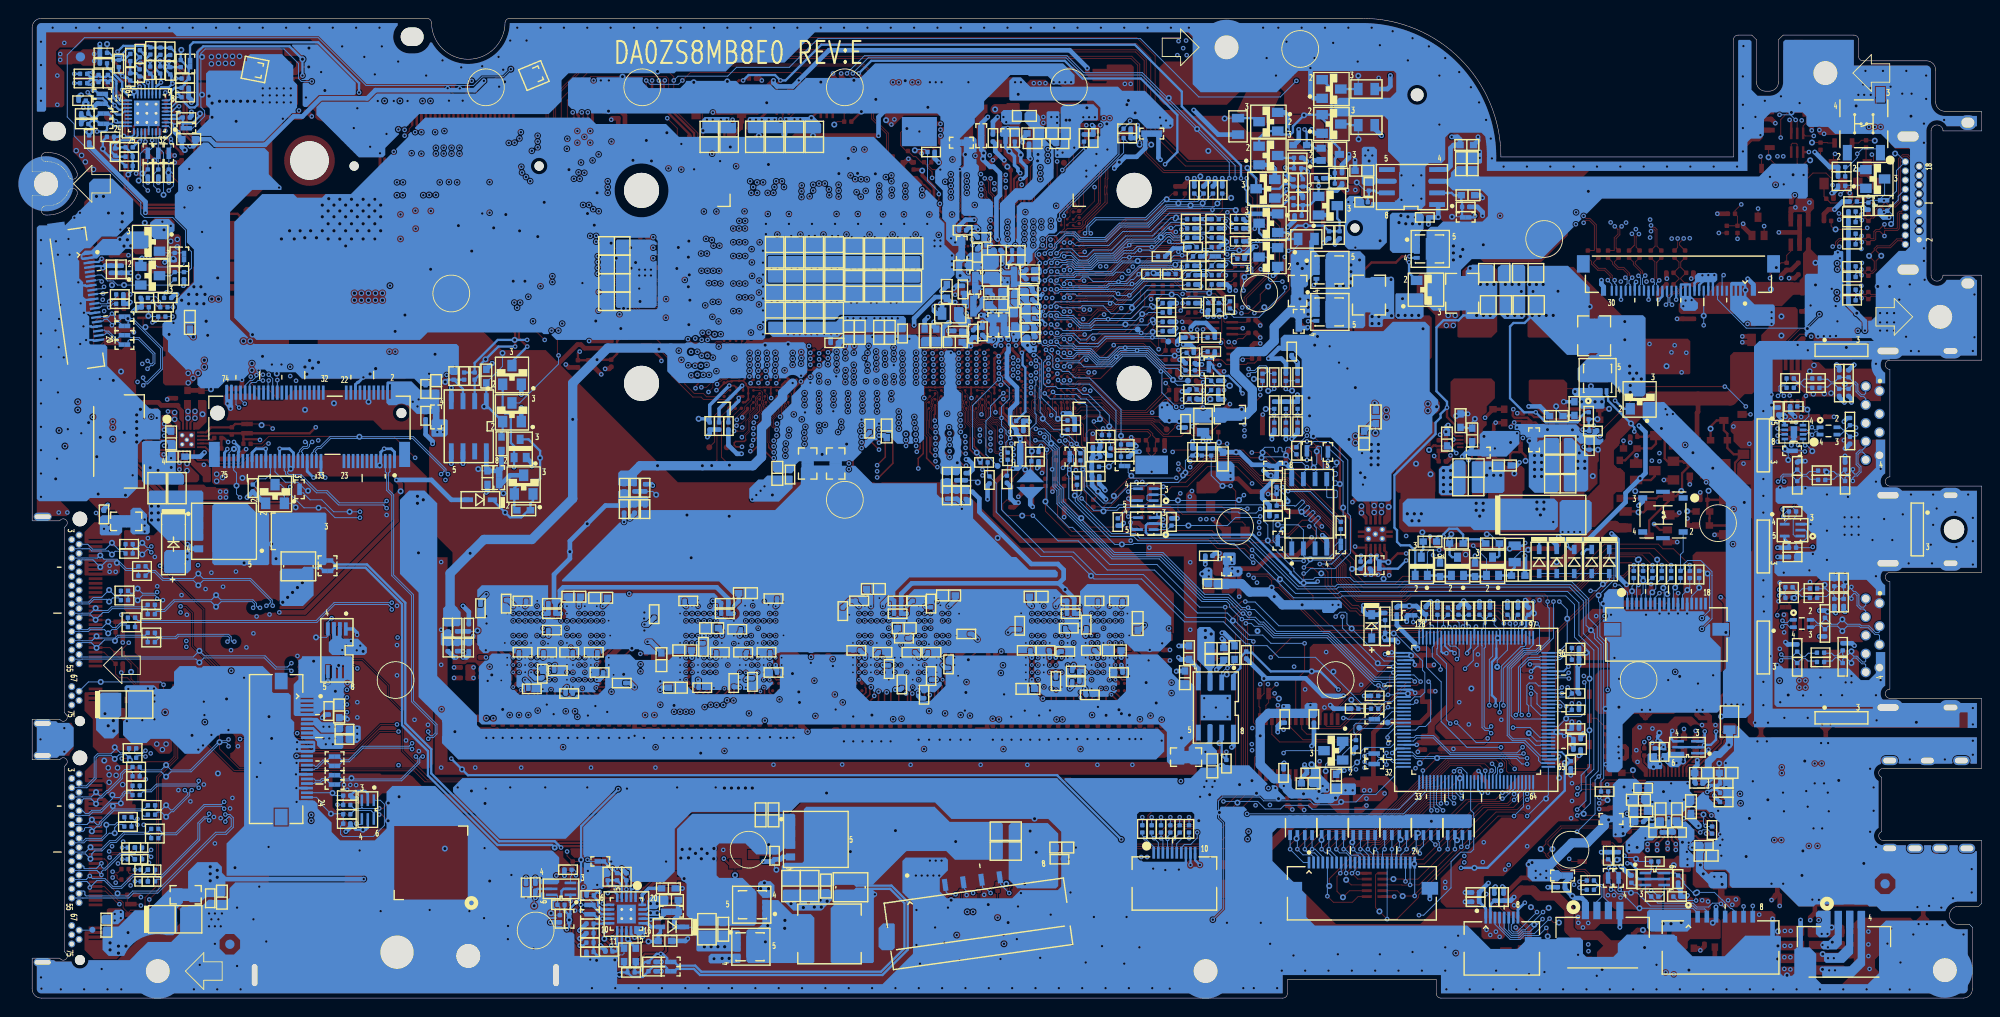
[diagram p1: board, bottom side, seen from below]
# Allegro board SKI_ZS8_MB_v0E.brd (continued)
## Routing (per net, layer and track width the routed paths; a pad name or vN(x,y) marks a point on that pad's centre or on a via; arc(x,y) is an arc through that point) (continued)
TD_IREF: length 7.9
  TOP w0.254: 105.63,90.04 105.63,87.07 105.71,87 105.71,86.22 U6.B12
  TOP w0.508: 105.63,90.04 105.63,90.11 v2(106,90.48) 106.34,90.82 v1(106.34,91.19)
  BOTTOM w0.508: R338.1 107.31,92.96 107.31,92.16 v1(106.34,91.19)
TEMP_MBAT: length 84
  TOP w0.102: PU6.3 v1(106.37,5.91) 105.92,6.36 v2(105.92,8.22) 105.92,9.03 PR69.1 PR66.2
  IN1 w0.114: v1(106.37,5.91) 105.29,6.98 88.77,6.98 85.45,10.31 58.97,10.31 56.64,12.64 55.66,12.64 52.84,15.46 52.84,27.58 v1(50.98,29.44)
  BOTTOM w0.102: U23.73 48.05,28.37 49.12,29.44 v1(50.98,29.44)
TESTLOW_AK8: length 10.2
  TOP w0.102: U6.AK8 102.87,69.98 v1(103.12,69.98)
  BOTTOM w0.102: R436.2 100.33,62.86 v2(100.5,63.03) 100.68,63.22 100.68,63.76 102.34,65.41 102.34,66.24 102.26,66.32 102.26,69.42 102.82,69.98 v1(103.12,69.98)
TESTLOW_AL8: length 10.4
  TOP w0.102: U6.AL8 102.58,69.71 v1(102.9,69.39)
  BOTTOM w0.089: 100.33,61.85 100.94,61.85 101.21,62.12
  BOTTOM w0.102: v1(102.9,69.39) 102.46,68.96 102.46,66.42 102.54,66.35 102.54,65.33 102.43,65.22 102.43,63.74 102.15,63.46 v2(102.15,63.06) 101.21,62.12 ; R444.2 100.33,61.85
TESTLOW_C34: length 6.7
  TOP w0.076: U6.C34 118.75,85.63 118.92,85.81 119.1,85.81 119.3,86.01 119.33,86.12 119.33,86.25 119.31,86.31 119.3,86.32 119.27,86.4 119.27,86.57 119.36,86.8 119.36,88.59 119.36,88.59 119.36,88.73 120.29,89.66
  TOP w0.102: 120.29,89.66 120.33,89.7 v2(120.36,89.7) 120.89,90.24 R32.2
TESTLOW_C35: length 7.7
  TOP w0.076: 122.21,89.66 121.03,89.66 120.36,88.99 119.85,88.99 119.52,88.66 119.52,86.75 119.51,86.75 119.44,86.54 119.44,86.43 119.49,86.31 119.5,86.28 119.5,86.09 119.46,85.94 119.36,85.79 U6.C35
  TOP w0.102: R33.2 122.3,90.54 v2(122.3,89.75) 122.21,89.66
THRMTRIP#: length 17.9
  TOP w0.076: U6.D60 135.04,85.01 135.5,85.47 135.5,85.68 135.83,86.02 135.83,86.23 136.03,86.42 136.42,86.42
  TOP w0.102: 136.42,86.42 137.54,87.54 137.54,88.65 138.48,89.59 138.48,90.86 139.12,91.49 v2(139.12,94.4) 139.12,95.3 139.19,95.38 139.19,96.77 138.8,97.16 R12.1 138.05,97.8 138.05,98.04 138.31,98.31 Q2.1
TP_DC_TEST_A4: length 4.4
  TOP w0.102: U6.A4 100.08,87.18 99.58,87.67 99.58,90.64 TP4.1
TP_DC_TEST_A60: length 8.9
  TOP w0.102: TP1.1 137.54,94.03 136.65,93.14 136.65,89.66 136.14,89.15 136.14,88.19 134.91,86.96 U6.A60
TP_DC_TEST_A62: length 7.1
  TOP w0.102: U6.A62 136.22,87.07 136.91,87.76 136.91,88.67 137.92,89.69 137.92,91.09 138.56,91.72 138.56,92.86 TP2.1
TP_DC_TEST_AV1: length 10.8
  TOP w0.076: 95.76,65.39 95.77,65.41 98.09,65.41 U6.AV1
  TOP w0.102: 95.76,65.39 93.66,63.3 90.04,63.3 90.03,63.29 89.06,63.29 TP14.1
TP_DC_TEST_AW1: length 10.7
  TOP w0.076: 95.76,64.77 U6.AW1
  TOP w0.102: TP13.1 89.47,62.7 90.02,62.7 90.21,62.89 93.83,62.89 95.71,64.77 95.76,64.77
TP_DC_TEST_AW63: length 5.5
  TOP w0.102: U6.AW63 136.81,64.43 137.85,63.4 137.85,60.53 TP16.1
TP_DC_TEST_AY60: length 5
  TOP w0.076: U6.AY60 135.03,64.19 136.36,62.85 136.36,62.7
  TOP w0.102: TP15.1 136.4,60.07 136.4,62.66 136.36,62.7
TP_DC_TEST_B2: length 4.9
  TOP w0.102: TP3.1 98.62,90.23 98.62,86.38 U6.B2
TPCLK: length 27.2
  IN3 w0.102: v1(40.56,14.15) 40.31,14.4 40.31,17.2 42.65,19.53 42.65,32.24 44.5,34.09 44.5,34.8 44.62,34.92 44.75,34.92 v1(44.91,34.77)
  BOTTOM w0.102: R573.1 40.56,13.55 v1(40.56,14.15) 40.28,14.43 40.28,14.75 R569.2 ; U23.89 46.25,34.77 46.17,34.85 44.98,34.85 v1(44.91,34.77)
TPCLK_R: length 12.8
  TOP w0.102: v1(40.33,11.8) 40.33,12.38 C408.1
  BOTTOM w0.102: R573.2 40.33,12.38 v1(40.33,11.8) 40.27,11.75 39.98,11.75 39.57,11.34 39.06,11.34 37.49,9.78 v2(37.23,9.78) 31.42,9.78 30.9,9.26 CN15.2
TPD_EN: length 66
  TOP w0.102: v1(31.06,10.62) 31.1,10.66 v2(31.1,11.42)
  IN1 w0.114: v1(49.28,30.81) 49.28,29.72 49.71,29.29 49.71,28.14 50.36,27.48 50.36,24.07 50.22,23.93 50.22,14.99 50.67,14.54 50.67,12.57 49.01,10.91 49.01,6.94 46.02,3.96 38.73,3.96 37.05,5.64 34.44,5.64 31.47,8.61 31.47,10.21 v1(31.06,10.62) 30.84,10.39 30.84,10.21 30.02,9.4 27.15,9.4 26.14,10.41 25.27,10.41 v1(24.9,10.03)
  BOTTOM w0.102: U23.87 48.19,33.97 48.51,34.29 49.23,34.29 49.48,34.04 49.48,32 49.28,31.8 v1(49.28,30.81) ; R580.1 33.53,11.05 33.1,10.62 v1(31.06,10.62) ; CN15.8 v1(24.9,10.03)
TPD_INT#: length 132.8
  TOP w0.102: v1(61.59,25.02) 61.13,25.49 v2(61.13,25.57) 60.02,26.67 58.75,26.67 52.27,26.67 51.41,25.81 51.41,25.55 v1(50.8,24.94)
  IN1 w0.114: v1(68.07,24.89) 67.31,24.13 62.48,24.13 v1(61.59,25.02) ; v1(50.8,24.94) 50.8,24.08 50.44,23.72 50.44,15.09 50.93,14.6 50.93,12.37 49.23,10.68 49.23,6.81 46.13,3.71 38.66,3.71 36.97,5.4 34.36,5.4 30.74,9.02 26.87,9.02 v1(25.9,9.98)
  IN3 w0.102: v1(68.07,24.89) 68.07,25.02 68.83,25.78 68.83,28.44 69.44,29.05 v1(69.44,30.48) 69.44,31.09 72.72,34.37 72.72,45.52 72.33,45.91 72.33,46.92 72.72,47.31 72.72,49.5 72.49,49.73 72.49,50.55 72.64,50.7 72.64,56.95 72.31,57.28 72.31,61.65 71.88,62.08 71.88,69.07 75.31,72.5 75.31,77.55 75.74,77.98 v1(76.07,77.98)
  BOTTOM w0.102: v1(76.07,77.98) 77.39,77.98 77.6,78.18 77.6,80.39 77.85,80.64 Q20.3 ; CN15.7 v1(25.9,9.98) ; v1(69.44,30.48) 69.09,30.48 68.96,30.35 R532.1
TPD_INT#_C: length 28
  TOP w0.102: U6.U7 101.91,77.83 v1(101.91,78.1)
  BOTTOM w0.102: Q20.1 77.47,81.66 78.04,82.24 79.31,82.24 80.18,81.37 v2(80.76,81.37) 80.79,81.35 82.26,81.35 82.49,81.11 83.91,81.11 84.15,81.36 84.64,81.36 84.88,81.11 85.4,81.11 R368.1 86.21,80.3 87.98,80.3 88.27,80.01 93.45,80.01 94.58,78.88 98.55,78.88 98.83,78.61 101.4,78.61 v1(101.91,78.1)
TPD_INT#_EC: length 3.5
  BOTTOM w0.102: U23.16 64.49,31.57 v1(64.58,31.66) 65.68,30.57 R532.2
TPDATA: length 28.1
  IN3 w0.102: v1(44.93,35.41) 44.68,35.15 44.53,35.15 44.27,34.9 44.27,34.19 42.42,32.33 42.42,19.63 40.08,17.29 40.08,14.3 v1(39.93,14.15)
  BOTTOM w0.102: v1(44.93,35.41) 45.26,35.08 46.16,35.08 46.25,35.17 U23.90 ; R572.1 39.93,13.9 v1(39.93,14.15) 40.06,14.27 40.06,14.9 39.85,15.1 R568.2
TPDATA_R: length 12.9
  TOP w0.102: v1(39.39,11.8) 39.44,11.85 C407.1
  BOTTOM w0.102: R572.2 39.5,11.91 v1(39.39,11.8) 39.16,11.57 38.26,11.57 v2(38.15,11.46) 37.47,11.46 36.04,10.03 31.39,10.03 31.06,9.7 30.12,9.7 29.9,9.48 CN15.3
TPM_BADD: length 3.6
  TOP w0.089: v2(76.49,21.71) 76.21,21.71
  TOP w0.102: U15.9 75.27,22.02 R301.2 75.58,21.71 76.21,21.71
TPM_CLKRUN#: length 4.8
  TOP w0.102: v2(78.08,34.78) 78.07,34.76 78.07,33.14 78.45,32.76 R225.2 78.62,32.75 78.62,31.72 78.52,31.62 U15.15
TPM_LRESET#: length 3.7
  TOP w0.089: 76.5,32.59 v2(76.46,32.59)
  TOP w0.102: 76.5,32.59 76.76,32.59 76.93,32.76 R224.2 77.57,32.16 77.87,31.86 U15.16
TPM_PP: length 5
  TOP w0.102: v2(72.1,22.49) 72.26,22.49 R299.2 R300.2 74.17,22.35 73.97,22.55 U15.7
TS_INT: length 9.9
  BOTTOM w0.102: CN7.6 204.93,78.69 204.54,78.69 203.89,78.04 203.27,78.04 202.82,77.6 v2(202.1,77.6) Q21.1 197.22,77.6 R379.1
TS_INT_PCH: length 225.9
  TOP w0.102: U6.R6 101.47,78.82 v1(101.22,79.08) ; v1(160.02,101.09) 156.57,104.54 91.93,104.54 89.92,102.53 89.92,94.53 86.45,91.06 79.21,91.06 77.62,89.47 77.62,85.22 76.4,84 76.4,79.32 75.31,78.23 75.31,77.14 77.27,75.18 v2(78.04,75.18) 78.24,75.18 78.87,74.55 v1(79.12,74.55)
  IN3 w0.102: v1(101.22,79.08) 100.79,79.5 100.2,79.5 99.54,80.16 92.15,80.16 91.08,79.1 91.08,77.96 90.32,77.19 86.56,77.19 85.95,76.58 82.17,76.58 81.97,76.38 80.11,76.38 79.12,75.39 v1(79.12,74.55)
  BOTTOM w0.102: Q21.3 196.99,78.61 R379.2 R378.2 195.52,79.06 195.14,79.06 194.76,79.44 194.76,81.22 195.42,81.88 195.42,83.57 196.81,84.96 199.9,84.96 200.28,85.34 200.28,86.58 207.52,93.82 207.52,95.12 208.28,95.89 208.28,102.65 206.41,104.52 180.98,104.52 175.77,99.31 164.08,99.31 163.14,100.25 160.86,100.25 v1(160.02,101.09)
TS_RST#: length 217.4
  TOP w0.102: v1(198.19,47.06) 193.42,42.29 193.42,37.72 v2(186.33,30.63) 184.53,28.83 v1(183.26,28.83)
  IN2 w0.114: v1(204.54,77.99) 205.4,77.99 207.58,75.81 207.58,57.98 205.61,56.01 199.9,56.01 197.81,53.91 197.81,47.44 v1(198.19,47.06)
  IN3 w0.102: v1(204.54,77.99) 201.91,77.99 201.68,77.76 198.44,77.76 v1(197.49,76.81) ; v1(183.26,28.83) 182.75,28.32 182.75,17.65 180.39,15.29 153.29,15.29 151.97,16.61 143.83,16.61 143.23,17.21 135.7,17.21 132.73,14.24 130.86,14.24 130.18,13.55 121.4,13.55 115.35,19.61 92.96,19.61 92.01,18.66 81.31,18.66 v1(79.92,20.05)
  BOTTOM w0.102: CN7.7 204.73,78.18 204.73,78.18 v1(204.54,77.99) ; v1(79.92,20.05) 62.89,20.05 60.39,22.55 U23.35 ; R387.1 197.75,76.55 v1(197.49,76.81)
USB2N0: length 133.9
  TOP w0.102: U6.AN8 102.56,68.41 v1(102.88,68.09) ; R171.2 21.21,61.36 22.06,61.36 v1(22.2,61.21)
  IN1 w0.076: 98.93,65.66 98.94,65.68 98.94,65.71 99.37,66.14 100.26,66.14 100.49,66.37 101.68,66.37 102.31,67.01 102.31,68.1 102.54,68.33 102.64,68.33 v1(102.88,68.09)
  IN1 w0.114: 98.93,65.66 97.43,64.16 95.66,64.16 94.27,62.78 89.04,62.78 84.29,58.03 84.29,54 82.21,51.92 82.21,45.86 80.29,43.94 80.14,43.94 79.13,42.94 77.39,42.94 72.62,38.17 63.97,38.17 63.81,38.01 62.52,38.01 62.13,38.4 60.47,38.4 60.3,38.23 26.85,38.23 24.22,35.6 21.17,35.6 19.3,37.46 19.3,53.95 19.68,54.33 19.68,57.4 22.8,60.52 22.8,61.23 22.56,61.47 22.45,61.47 v1(22.2,61.21)
  BOTTOM w0.102: v1(22.2,61.21) 22.07,61.35 U17.7
USB2N0_R: length 4.2
  TOP w0.102: R171.1 19.51,61.46 18.61,61.46 v1(18.45,61.3)
  BOTTOM w0.102: U17.2 19.1,61.35 18.89,61.56 18.71,61.56 v1(18.45,61.3) 18.11,61.64 17.9,61.64 L11.4
USB2N0_USB3: length 8.9
  IN1 w0.114: CN4.2 11.11,63.24 11.34,63 11.7,63 12.28,63.59 13.63,63.59 14.49,62.73 14.49,61.81 14.23,61.55 13.98,61.55 13.89,61.55 13.82,61.55 v1(13.64,61.37)
  BOTTOM w0.102: v1(13.64,61.37) 13.91,61.1 D21.1 14.79,61.56 14.79,61.56 14.86,61.62 15.03,61.62 15.36,61.3 15.39,61.32 L11.3
USB2N1: length 100.8
  TOP w0.102: U6.AR7 101.85,67.44 v1(101.53,67.76)
  IN1 w0.076: v1(101.53,67.76) 101.25,67.48 101.13,67.48 100.91,67.26 100.91,67.12 100.67,66.87 100.24,66.87 100.2,66.83 98.82,66.83 98.32,66.33 98.29,66.33 98.27,66.32
  IN1 w0.114: v1(21.67,41.07) 21.88,40.86 23.15,40.86 24.73,39.28 59.83,39.28 60.01,39.46 64.01,39.46 64.22,39.24 72.2,39.24 76.95,43.99 78.38,43.99 80.51,46.12 80.51,46.5 80.9,46.89 80.9,52.1 83.22,54.42 83.22,58.48 85.14,60.4 85.14,60.78 85.8,61.43 86.14,61.43 86.65,61.94 86.65,62.45 87.16,62.95 87.67,62.95 88.56,63.84 93.76,63.84 95.24,65.32 97.27,65.32 98.27,66.32
  BOTTOM w0.102: L15.1 20.84,41.17 21.15,40.86 21.45,40.86 v1(21.67,41.07)
USB2N1_USB3: length 9.8
  BOTTOM w0.102: L15.2 18.23,41.17 17.85,40.78 17.49,40.78 17.04,41.23 D33.1 16.33,40.68 15.69,40.68 v2(15.15,41.21) 14.62,40.68 13.25,40.68 13.08,40.51 12.25,40.51 11.53,39.79 11.19,39.79 11.11,39.87 CN5.2
USB2N3: length 148.4
  TOP w0.102: U6.AR10 103.5,67.09 v1(103.42,67.09)
  IN1 w0.102: 101.35,65.54 101.59,65.54 101.75,65.38 102.09,65.38 102.64,65.94 102.64,66.78 102.87,67.01 103.33,67.01 v1(103.42,67.09)
  IN1 w0.114: v1(170.76,27.74) 170.89,27.61 171.27,27.61 171.55,27.33 171.55,26.01 169.02,23.48 133.58,23.48 132.32,24.74 91.47,24.74 85.76,30.44 85.76,38.99 86.78,40 86.78,48.63 89.53,51.39 89.53,52.76 92.65,55.87 92.65,58.33 93.78,59.47 93.78,61.37 95.83,63.42 97.5,63.42 99.62,65.54 101.35,65.54
  BOTTOM w0.102: v1(170.76,27.74) 171.09,27.41 176.19,27.41 177.67,25.92 178.44,25.92 R540.1
USB2N3_C: length 3.1
  BOTTOM w0.102: R540.2 179.97,25.91 180.47,25.91 181.17,25.2 181.28,25.2 181.43,25.35 CN12.16
USB2N4: length 199.5
  TOP w0.102: U6.AM15 106.12,68.86 106.12,68.78 106.18,68.72 106.49,68.72 106.71,68.5 106.83,68.5 v1(106.92,68.6)
  IN3 w0.076: v1(106.92,68.6) 106.72,68.81 106.5,68.81 106.31,69 106.31,70.07 106.76,70.52 107.55,70.52 107.89,70.86 107.89,71.84 107.61,72.11 105.13,72.11 103.06,74.18 103.06,75.32 102.75,75.63 100.4,75.63 100.15,75.38 99.95,75.38
  IN3 w0.102: 99.95,75.38 95.13,75.38 92.8,73.05 91.73,73.05 90.15,71.47 89.25,71.47 87.65,69.88 85.83,69.88 85.6,70.1 84.71,70.1 84.23,69.62 84.23,69.24 83.39,68.4 83.39,61.93 82.85,61.39 82.85,53.9 82.4,53.44 82.4,43.25 81.86,42.71 81.86,41.84 82.25,41.46 82.25,38.79 84.2,36.83 84.2,33.88 85.29,32.79 85.29,27.8 89.24,23.85 163.39,23.85 168.14,28.6 168.83,28.6 169.01,28.78 v1(169.01,29.01)
  BOTTOM w0.102: v1(169.01,29.01) 169.01,28.8 168.76,28.55 168.54,28.55 168.25,28.84 168.25,29.69 170.81,32.26 170.81,43.81 172.97,45.97 172.97,54.7 173.53,55.26 173.53,57.15 173.68,57.3 CN9.5
USB2N5: length 225
  TOP w0.102: U6.AM13 105.89,69.52 105.89,69.65 105.83,69.71 v1(105.37,69.71)
  IN1 w0.114: v1(177.85,31.95) 177.85,31.7 178.04,31.51 180.96,31.51 186.86,37.4 186.86,37.91 189.6,40.65 190.11,40.65 196.46,47.01 196.46,55.22 199.58,58.34 199.58,63.89 198.86,64.61 198.86,66.83 199.16,67.13 199.88,67.13 200.02,67.28 v1(200.02,67.51)
  IN3 w0.076: 99.95,73.69 99.97,73.69 99.99,73.71 102.74,73.71 102.91,73.54 102.91,73.05 104.27,71.7 104.27,70.94 104.98,70.23 105.56,70.23 105.9,69.9 105.9,69.55 105.78,69.43 105.5,69.43 105.37,69.56 v1(105.37,69.71)
  IN3 w0.102: v1(177.85,31.95) 177.85,31.67 177.67,31.5 169.42,31.5 162.59,24.66 90.3,24.66 86.11,28.86 86.11,33.13 85.01,34.22 85.01,37.78 83.26,39.54 83.26,39.88 83.64,40.26 83.64,51.18 83.21,51.61 83.21,52.73 83.67,53.19 83.67,60.93 84.28,61.54 84.28,68.02 84.57,68.32 85.38,68.32 85.92,68.86 88.7,68.86 91.6,71.75 95.63,71.75 97.17,73.29 98,73.29 98.41,73.69 99.95,73.69
  BOTTOM w0.102: R414.1 201.67,73.52 201.44,73.75 201.21,73.75 198.14,70.68 198.14,68.53 199.62,67.05 199.76,67.05 200.02,67.31 v1(200.02,67.51)
USB2N5_C: length 3.5
  BOTTOM w0.102: CN7.16 204.39,73.69 204.27,73.86 204.16,73.87 204.02,73.89 203.94,73.89 203.42,73.37 v1(203.42,73.22) 203.08,73.56 202.62,73.56 202.45,73.39 R414.2
USB2N6: length 214.7
  TOP w0.102: v1(104.83,68.1) 104.5,68.1 104.41,68.01 U6.AP11
  IN1 w0.114: v1(199.54,69.34) 199.54,69.04 199.43,68.93 198.54,68.93 197.9,68.29 197.9,63.03 198.3,62.63 198.3,58.24 195.62,55.57 195.62,47.54 194.65,46.57 193.89,46.57 185.51,38.19 183.1,38.19 181.22,36.31 181.22,34.68 179.62,33.08 178.07,33.08 177.85,33.3 v1(177.85,33.55)
  IN3 w0.076: v1(104.83,68.1) 104.53,68.4 104.4,68.4 104,68.8 104,69.79 103.61,70.18 103.61,71.4 103.17,71.83 100.35,71.83 99.99,72.19 99.96,72.19 99.95,72.2
  IN3 w0.102: v1(177.85,33.55) 177.85,33.35 177.52,33.02 169.8,33.02 162.81,26.03 90.08,26.03 86.92,29.2 86.92,35.76 85.93,36.75 85.93,38.91 85.6,39.24 85.6,52.45 84.48,53.57 84.48,59.46 85.37,60.35 85.37,66.7 86.61,67.94 88.94,67.94 90.91,69.92 95.13,69.92 95.9,70.69 97.06,70.69 98.64,72.26 99.89,72.26 99.95,72.2
  BOTTOM w0.102: v1(199.54,69.34) 199.23,69.03 199.08,69.03 198.95,69.15 198.95,70.09 200.53,71.67 201.49,71.67 201.51,71.67 201.67,71.51 R419.1
USB2N6_C: length 3
  BOTTOM w0.102: R419.2 202.85,71.53 203,71.53 203.86,72.38 203.97,72.38 204.06,72.37 204.18,72.2 CN7.19
USB2N7: length 145.7
  TOP w0.102: U6.AR13 105.76,67.61 105.61,67.76 v1(105.37,67.76)
  IN1 w0.114: v1(105.37,67.76) 105.55,67.94 105.71,67.94 105.85,67.8 105.85,67.36 105.68,67.18 105.51,67.18 103.4,65.07 102.56,65.07 102.39,64.9 100.18,64.9 97.59,62.31 96.55,62.31 94.67,60.43 94.67,59.16 93.5,57.99 93.5,54.41 90.46,51.38 90.46,51.13 87.62,48.28 87.62,39.61 86.65,38.65 86.65,31.91 92.53,26.03 132.21,26.03 133.93,24.31 168.64,24.31 170.04,25.72 170.04,25.98 v1(170.35,26.29)
  BOTTOM w0.102: v1(170.35,26.29) 170.13,26.07 170.13,25.7 171.98,23.85 178.4,23.85 R545.1
USB2N7_C: length 2.9
  BOTTOM w0.102: CN12.19 181.43,23.85 181.28,23.7 180.77,23.7 180.59,23.88 179.97,23.88 R545.2
USB2P0: length 134
  TOP w0.102: R163.2 21.21,61.56 21.78,61.56 v1(22.2,61.98) ; U6.AM8 102.56,69.06 v1(102.9,68.73)
  IN1 w0.076: 98.78,65.82 98.79,65.83 98.82,65.83 99.3,66.31 100.19,66.31 100.42,66.54 101.61,66.54 102.15,67.07 102.15,68.17 102.47,68.49 102.66,68.49 v1(102.9,68.73)
  IN1 w0.114: v1(22.2,61.98) 22.49,61.68 22.64,61.68 23.01,61.32 23.01,60.43 19.9,57.31 19.9,54.24 19.52,53.86 19.52,37.55 21.26,35.81 24.13,35.81 26.76,38.44 60.21,38.44 60.38,38.61 62.22,38.61 62.61,38.23 63.72,38.23 63.88,38.39 72.53,38.39 77.3,43.15 79.04,43.15 80.05,44.16 80.2,44.16 81.99,45.95 81.99,52.01 84.07,54.09 84.07,58.12 88.95,62.99 94.18,62.99 95.57,64.38 97.34,64.38 98.78,65.82
  BOTTOM w0.102: v1(22.2,61.98) 22.07,61.84 U17.6
USB2P0_R: length 4.1
  TOP w0.102: R163.1 19.72,61.66 18.93,61.66 v1(18.47,62.13)
  BOTTOM w0.102: L11.1 17.87,61.84 18.18,61.84 v1(18.47,62.13) 18.83,61.76 18.93,61.76 19.01,61.84 U17.3
USB2P0_USB3: length 8.9
  IN1 w0.114: CN4.3 11.11,62.62 11.28,62.79 11.79,62.79 12.37,63.37 13.54,63.37 14.27,62.64 14.27,61.9 14.14,61.77 13.98,61.77 v1(13.67,62.08)
  BOTTOM w0.102: L11.2 15.36,62.12 15.07,61.83 14.85,61.83 D20.1 13.94,62.35 v1(13.67,62.08)
USB2P1: length 100.8
  TOP w0.102: U6.AT7 101.85,66.79 v1(101.53,67.11)
  IN1 w0.076: 98.43,66.17 98.44,66.18 98.44,66.22 98.89,66.66 100.27,66.66 100.31,66.7 100.73,66.7 101.08,67.05 101.08,67.19 101.2,67.31 101.33,67.31 v1(101.53,67.11)
  IN1 w0.114: 98.43,66.17 97.36,65.1 95.33,65.1 93.85,63.63 88.65,63.63 87.76,62.74 87.25,62.74 86.87,62.36 86.87,61.85 86.23,61.21 85.89,61.21 85.36,60.69 85.36,60.31 83.44,58.39 83.44,54.33 81.11,52.01 81.11,46.8 80.73,46.41 80.73,46.03 78.47,43.78 77.04,43.78 72.29,39.03 64.13,39.03 63.92,39.24 60.1,39.24 59.92,39.07 24.64,39.07 23.06,40.64 21.9,40.64 v1(21.69,40.44)
  BOTTOM w0.102: v1(21.69,40.44) 21.47,40.66 21.17,40.66 20.89,40.37 L15.4
USB2P1_USB3: length 9.8
  BOTTOM w0.102: CN5.3 11.11,39.46 11.24,39.59 11.61,39.59 12.34,40.31 13.17,40.31 13.33,40.48 14.62,40.48 v2(15.15,39.94) 15.69,40.48 16.71,40.48 D31.1 17.48,40.58 18.02,40.58 18.24,40.37 L15.3
USB2P3: length 148.3
  TOP w0.102: v1(103.43,66.45) 103.95,66.45 104.01,66.4 104.29,66.4 104.39,66.5 104.39,66.69 104.3,66.79 U6.AT10
  IN1 w0.102: v1(103.43,66.45) 103.07,66.81 102.95,66.81 102.83,66.7 102.83,65.86 102.17,65.19 101.67,65.19 101.52,65.34 101.38,65.34 101.36,65.32 101.35,65.32
  IN1 w0.114: v1(170.76,27.1) 171.06,27.39 171.18,27.39 171.34,27.24 171.34,26.1 168.93,23.69 133.67,23.69 132.41,24.96 91.56,24.96 85.98,30.53 85.98,38.9 87,39.92 87,48.54 89.75,51.3 89.75,52.67 92.86,55.78 92.86,58.24 94,59.38 94,61.28 95.92,63.21 97.59,63.21 99.71,65.32 101.35,65.32
  BOTTOM w0.102: R544.1 178.36,25.72 177.59,25.72 176.11,27.2 170.87,27.2 v1(170.76,27.1)
USB2P3_C: length 3.1
  BOTTOM w0.102: R544.2 180.02,25.7 180.38,25.7 181.09,25 181.28,25 181.43,24.85 CN12.17
USB2P4: length 199.5
  TOP w0.102: v1(106.92,69.24) 106.8,69.24 U6.AL15
  IN3 w0.076: 99.95,75.58 100.12,75.58 100.33,75.8 102.82,75.8 103.23,75.39 103.23,74.25 105.2,72.28 107.68,72.28 108.05,71.91 108.05,70.79 107.62,70.36 106.83,70.36 106.48,70 106.48,69.07 106.57,68.98 106.66,68.98 v1(106.92,69.24)
  IN3 w0.102: 99.95,75.58 95.04,75.58 92.71,73.25 91.64,73.25 90.06,71.67 89.17,71.67 87.57,70.08 85.91,70.08 85.68,70.31 84.62,70.31 84.02,69.71 84.02,69.32 83.19,68.49 83.19,62.01 82.65,61.48 82.65,53.98 82.19,53.53 82.19,43.33 81.66,42.8 81.66,41.75 82.04,41.37 82.04,38.7 84,36.75 84,33.8 85.09,32.71 85.09,27.71 89.16,23.65 163.47,23.65 168.22,28.4 168.83,28.4 v1(169.01,28.22)
  BOTTOM w0.102: CN9.3 173.18,57.3 173.32,57.15 173.32,55.34 172.77,54.79 172.77,46.06 170.61,43.9 170.61,32.34 168.05,29.78 168.05,28.75 168.45,28.35 168.88,28.35 v1(169.01,28.22)
USB2P5: length 225
  TOP w0.102: U6.AN13 105.74,68.74 105.41,69.07 v1(105.35,69.07)
  IN1 w0.114: v1(200.01,66.69) 199.78,66.92 199.25,66.92 199.08,66.74 199.08,64.7 199.8,63.98 199.8,58.25 196.68,55.13 196.68,46.92 190.2,40.44 189.69,40.44 187.07,37.82 187.07,37.31 181.05,31.29 178.03,31.29 v1(177.85,31.12)
  IN3 w0.076: 99.95,73.9 99.97,73.9 99.99,73.88 102.81,73.88 103.08,73.61 103.08,73.12 104.43,71.77 104.43,71.01 105.05,70.4 105.63,70.4 106.06,69.97 106.06,69.48 105.85,69.27 105.55,69.27 v1(105.35,69.07)
  IN3 w0.102: v1(177.85,31.12) 177.67,31.29 169.51,31.29 162.68,24.46 90.22,24.46 85.9,28.78 85.9,33.04 84.81,34.14 84.81,37.7 83.06,39.45 83.06,39.96 83.44,40.34 83.44,51.1 83.01,51.53 83.01,52.81 83.46,53.27 83.46,61.02 84.07,61.63 84.07,68.11 84.49,68.52 85.29,68.52 85.83,69.06 88.62,69.06 91.52,71.96 95.55,71.96 97.08,73.49 97.92,73.49 98.33,73.9 99.95,73.9
  BOTTOM w0.102: v1(200.01,66.69) 199.86,66.84 199.53,66.84 197.93,68.44 197.93,70.76 201.12,73.95 201.45,73.95 R411.1
USB2P5_C: length 3.7
  BOTTOM w0.102: CN7.15 204.46,74.18 204.29,74.06 204.24,74.06 204.19,74.07 204.04,74.09 203.84,74.09 203.44,74.49 v1(203.42,74.49) 203.11,74.18 203.11,73.95 202.92,73.76 202.6,73.76 202.45,73.91 R411.2
USB2P6: length 214.7
  TOP w0.102: v1(104.83,68.73) 104.51,68.41 U6.AN11
  IN1 w0.114: v1(199.55,68.49) 199.32,68.71 198.63,68.71 198.12,68.2 198.12,63.12 198.52,62.72 198.52,58.15 195.84,55.48 195.84,47.45 194.74,46.36 193.98,46.36 185.6,37.97 183.19,37.97 181.44,36.22 181.44,34.59 179.71,32.87 178,32.87 v1(177.85,32.72)
  IN3 w0.076: 100.09,72.35 100.11,72.34 100.11,72.31 100.42,72 103.24,72 103.77,71.47 103.77,70.25 104.17,69.85 104.17,68.87 104.47,68.57 104.67,68.57 v1(104.83,68.73)
  IN3 w0.102: v1(177.85,32.72) 177.75,32.82 169.88,32.82 162.9,25.83 90,25.83 86.72,29.11 86.72,35.67 85.72,36.66 85.72,38.83 85.39,39.16 85.39,52.37 84.28,53.48 84.28,59.55 85.17,60.43 85.17,66.78 86.53,68.15 88.86,68.15 90.83,70.12 95.04,70.12 95.81,70.89 96.98,70.89 98.55,72.47 99.98,72.47 100.09,72.35
  BOTTOM w0.102: R415.1 201.4,71.87 200.45,71.87 198.74,70.17 198.74,69.07 198.99,68.82 199.21,68.82 v1(199.55,68.49)
USB2P6_C: length 3.1
  BOTTOM w0.102: 204.93,72.6 204.25,72.7 204.09,72.57 203.98,72.59 203.78,72.59 202.92,71.73 202.85,71.73 R415.2
USB2P7: length 145.7
  TOP w0.102: U6.AP13 105.44,68.41 v1(105.37,68.41)
  IN1 w0.114: v1(169.6,26.29) 169.82,26.07 169.82,25.81 168.55,24.53 134.02,24.53 132.3,26.25 92.62,26.25 86.87,32 86.87,38.56 87.83,39.52 87.83,48.19 90.68,51.04 90.68,51.29 93.71,54.33 93.71,57.9 94.88,59.07 94.88,60.34 96.64,62.09 97.68,62.09 100.27,64.68 102.48,64.68 102.65,64.85 103.49,64.85 105.6,66.97 105.77,66.97 106.07,67.27 106.07,67.89 105.8,68.16 105.62,68.16 v1(105.37,68.41)
  BOTTOM w0.102: v1(169.6,26.29) 169.8,26.29 169.93,26.16 169.93,25.62 171.9,23.65 178.4,23.65 R547.1
USB2P7_C: length 2.9
  BOTTOM w0.102: CN12.20 181.43,23.35 181.28,23.5 180.68,23.5 180.51,23.67 180.02,23.67 R547.2
USB3_RXN1: length 115.7
  TOP w0.102: U6.G20 109.54,82.89 v1(109.86,82.58)
  IN1 w0.114: v1(109.86,82.58) 109.63,82.35 109.47,82.35 108.58,83.24 108.58,84.97 108.12,85.43 107.14,85.43 105.56,87.02 103.43,87.02 103.27,86.86 98.11,86.86 94.22,82.97 90.19,82.97 86.41,86.76 79.26,86.76 78.17,85.66 72.28,85.66 71.26,84.65 70.83,84.65 68.51,82.32 67.67,82.32 66.68,81.33 66.68,78.19 63.77,75.29 45.47,75.29 41.04,70.86 39.08,70.86 31.43,63.21 27.09,63.21 24.61,60.73 24.61,59.74 21.65,56.78 21.65,56.38 v1(21.49,56.21)
  BOTTOM w0.102: v1(21.49,56.21) 21.64,56.36 21.64,56.69 21.51,56.82 20.62,56.82 C259.1 19.54,56.79 19,56.79 18.68,56.47 17.87,56.47 R469.2
USB3_RXN1_USB3: length 9.3
  BOTTOM w0.102: R469.1 16.93,56.47 16.07,56.47 15.72,56.82 15.41,56.82 D23.1 14.86,56.65 14.69,56.82 14.55,56.82 v1(14.01,56.28) 14.01,56.62 13.81,56.82 13.54,56.82 13.12,57.24 13.12,57.83 13.45,58.16 13.45,59.19 13.2,59.44 12.95,59.44 12.61,59.09 CN4.5
USB3_RXN2: length 149.6
  TOP w0.102: U6.E18 108.35,84.2 108.03,83.87 v1(107.87,83.87)
  IN1 w0.114: v1(21.82,36.75) 21.77,36.8 21.21,36.8 20.49,37.53 20.49,41.69 21.53,42.74 24.11,42.74 24.32,42.52 35.96,42.52 36.01,42.47 60.41,42.47 60.65,42.7 64.94,42.7 65.79,41.86 67.49,41.86 71.9,46.26 71.95,46.26 72.66,46.97 72.66,47.9 73.83,49.06 73.83,52.61 69.77,56.66 69.77,68.35 67.69,70.43 67.69,80.32 71.02,83.65 71.71,83.65 72.88,84.81 78.51,84.81 79.62,85.92 86.05,85.92 89.85,82.13 94.57,82.13 98.46,86.02 100.25,86.02 100.48,85.79 100.88,85.79 101.1,86.02 103.61,86.02 103.77,86.18 105.14,86.18 106.1,85.22 106.15,85.22 107.19,84.17 107.21,84.17 107.52,83.87 v1(107.87,83.87)
  BOTTOM w0.102: v1(21.82,36.75) 21.64,36.93 20.54,36.93 C337.1 19.54,36.98 19.2,36.98 18.9,36.68 18.02,36.68 R528.2
USB3_RXN2_USB3: length 7.2
  BOTTOM w0.102: R528.1 17.03,36.68 16.27,36.68 15.91,37.05 15.7,37.05 D35.1 15.11,36.87 14.98,37.01 14.71,37.01 v2(14.16,36.46) 14.16,36.79 13.95,37.01 13.65,37.01 13.01,36.37 12.71,36.37 12.61,36.27 CN5.5
USB3_RXP1: length 115.7
  TOP w0.102: U6.H20 109.47,82.24 v1(109.78,81.94)
  IN1 w0.114: v1(22.15,56.21) 22.07,56.21 21.87,56.41 21.87,56.69 24.83,59.65 24.83,60.64 27.18,62.99 31.52,62.99 39.17,70.64 41.13,70.64 45.56,75.07 63.86,75.07 66.89,78.1 66.89,81.24 67.76,82.11 68.6,82.11 70.92,84.43 71.35,84.43 72.37,85.45 78.26,85.45 79.35,86.54 86.32,86.54 90.1,82.76 94.31,82.76 98.2,86.65 103.36,86.65 103.52,86.8 105.47,86.8 107.05,85.22 108.03,85.22 108.37,84.88 108.37,83.15 109.39,82.13 109.59,82.13 v1(109.78,81.94)
  BOTTOM w0.102: R466.2 17.87,57.32 18.73,57.32 19.05,57 19.54,57 C251.1 20.57,57.02 21.6,57.02 21.84,56.78 21.84,56.41 22.05,56.21 v1(22.15,56.21)
USB3_RXP1_USB3: length 9.2
  BOTTOM w0.102: R466.1 16.93,57.32 16.1,57.32 15.8,57.02 15.36,57.02 D22.1 14.86,57.18 14.71,57.02 14.53,57.02 v1(14.01,57.55) 14.01,57.23 13.81,57.02 13.63,57.02 13.32,57.33 13.32,57.74 13.66,58.07 13.66,59.27 13.29,59.64 12.98,59.64 12.61,60.01 CN4.6
USB3_RXP2: length 149.6
  TOP w0.102: v1(107.86,83.22) 108.52,83.22 108.58,83.29 108.58,83.37 U6.F18
  IN1 w0.114: v1(107.86,83.22) 107.12,83.96 107.1,83.96 106.06,85 106.01,85 105.05,85.96 103.86,85.96 103.7,85.8 101.19,85.8 100.97,85.57 100.39,85.57 100.16,85.8 98.55,85.8 94.66,81.91 89.76,81.91 89.52,82.15 85.96,85.7 79.71,85.7 78.6,84.6 72.96,84.6 71.8,83.43 71.11,83.43 67.91,80.23 67.91,70.52 69.99,68.44 69.99,56.75 74.04,52.7 74.04,48.97 72.88,47.81 72.88,46.88 72.04,46.04 71.99,46.04 67.58,41.64 65.7,41.64 64.85,42.49 60.74,42.49 60.5,42.25 35.92,42.25 35.87,42.3 24.23,42.3 24.02,42.52 21.62,42.52 20.7,41.6 20.7,37.62 21.3,37.02 21.42,37.02 v1(21.79,37.39)
  BOTTOM w0.102: v1(21.79,37.39) 21.54,37.13 20.64,37.13 C317.1 19.54,37.19 19.2,37.19 18.85,37.53 17.97,37.53 R526.2
USB3_RXP2_USB3: length 7.1
  BOTTOM w0.102: CN5.6 12.61,36.68 12.71,36.57 12.93,36.57 13.56,37.21 13.92,37.21 14.16,37.45 v2(14.16,37.73) 14.69,37.21 14.96,37.21 15.11,37.36 D34.1 15.7,37.25 16.04,37.25 16.33,37.53 17.08,37.53 R526.1
USB3_TXN1: length 122
  TOP w0.076: U6.C33 117.91,85.69 118.21,85.98 118.21,86.94 117.94,87.2 117.94,89.14 118.16,89.36 118.44,89.36 v1(118.62,89.53)
  IN1 w0.114: v1(21.52,65.54) 21.7,65.73 21.7,66.41 22.82,67.53 33.37,67.53 38.38,72.54 40.35,72.54 44.77,76.96 63.08,76.96 65,78.89 65,82.03 66.16,83.18 66.16,84.9 67.4,86.14 69.51,86.14 70.72,87.36 77.15,87.36 78.23,88.45 87.1,88.45 90.88,84.66 93.53,84.66 97.42,88.55 102.58,88.55 103.1,89.07 103.1,89.97 104.19,91.06 105.08,91.06 105.61,90.53 107.16,90.53 107.31,90.68 112.12,90.68 113.39,89.41 118.5,89.41 118.62,89.53 v1(118.62,89.53)
  BOTTOM w0.102: v1(21.52,65.54) 21.69,65.72 21.69,66.02 21.84,66.18 21.84,66.49 21.71,66.62 21.42,66.62 C237.1
USB3_TXN1_R: length 2.4
  BOTTOM w0.102: C237.2 20.03,66.83 19.63,66.83 19.31,66.5 18.51,66.5 R426.2
USB3_TXN1_USB3: length 7.4
  BOTTOM w0.102: R426.1 17.56,66.5 16.73,66.5 16.38,66.85 16.04,66.85 C239.1 D19.1 13.93,66.85 13.8,66.85 13.67,66.72 13.67,65.99 13.13,65.46 12.83,65.46 12.61,65.24 CN4.8
USB3_TXN2: length 136.8
  TOP w0.076: v1(117.09,87.81) 117.21,87.92 117.38,87.92 117.59,87.71 117.59,86.72 117.91,86.4 U6.B33
  IN1 w0.114: v1(22.02,43.81) 21.86,43.98 21.42,43.98 20.17,45.24 20.17,53.52 20.57,53.92 20.57,56.95 23.75,60.12 23.75,61.09 26.8,64.14 31.17,64.14 38.73,71.7 40.7,71.7 45.12,76.12 63.42,76.12 65.84,78.54 65.84,81.68 67.01,82.85 67.01,84.57 67.74,85.3 69.93,85.3 71.14,86.5 77.49,86.5 78.58,87.59 86.75,87.59 90.54,83.81 93.87,83.81 96.37,86.31 96.38,86.31 97.78,87.71 102.93,87.71 103.07,87.85 105.93,87.85 107.5,86.28 108.46,86.28 108.93,85.81 110.91,85.81 111.03,85.93 116.8,85.93 117.64,86.78 117.64,87.59 117.42,87.81 v1(117.09,87.81)
  BOTTOM w0.102: v1(22.02,43.81) 21.87,43.97 21.46,43.97 21.34,43.85 C275.1
USB3_TXN2_R: length 2.3
  BOTTOM w0.102: C275.2 20.12,44.01 19.88,44.01 19.56,43.69 18.81,43.69 R504.2
USB3_TXN2_USB3: length 9.2
  BOTTOM w0.102: CN5.8 12.61,42.12 12.83,42.34 13.19,42.34 13.55,42.7 13.55,43.8 13.79,44.03 13.91,44.03 14.16,43.78 v1(14.16,43.47) 14.72,44.03 14.85,44.03 15.01,43.87 D30.1 C286.1 16.03,43.83 16.23,44.03 16.55,44.03 16.88,43.69 17.76,43.69 R504.1
USB3_TXP1: length 122
  TOP w0.076: U6.B34 118.37,85.94 118.37,87 118.11,87.27 118.11,89.07 118.23,89.19 118.41,89.19 118.62,88.99 v1(118.62,88.9)
  IN1 w0.114: v1(118.62,88.9) 118.62,88.91 118.33,89.19 113.3,89.19 112.03,90.46 107.4,90.46 107.25,90.31 105.52,90.31 104.99,90.84 104.28,90.84 103.31,89.88 103.31,88.98 102.67,88.33 97.51,88.33 93.62,84.44 90.79,84.44 87.01,88.23 78.32,88.23 77.24,87.14 70.81,87.14 69.6,85.93 67.49,85.93 66.37,84.81 66.37,83.1 65.22,81.94 65.22,78.8 63.16,76.75 44.86,76.75 40.44,72.32 38.47,72.32 33.46,67.31 22.91,67.31 21.92,66.32 21.92,65.77 v1(22.15,65.54)
  BOTTOM w0.102: v1(22.15,65.54) 21.89,65.79 21.89,65.94 22.05,66.09 22.05,66.57 21.79,66.83 21.31,66.83 21.22,66.92 C235.1
USB3_TXP1_R: length 2.4
  BOTTOM w0.102: C235.2 20.03,67.03 19.63,67.03 19.31,67.35 18.51,67.35 R424.2
USB3_TXP1_USB3: length 7.4
  BOTTOM w0.102: R424.1 17.56,67.35 16.73,67.35 16.43,67.06 15.99,67.06 C234.1 D18.1 13.98,67.06 13.72,67.06 13.46,66.8 13.46,66.07 13.05,65.66 12.78,65.66 12.61,65.83 CN4.9
USB3_TXP2: length 136.8
  TOP w0.076: v1(117.09,88.44) 117.75,87.78 117.75,86.97 U6.A33
  IN1 w0.114: v1(117.09,88.44) 117.86,87.68 117.86,86.69 116.89,85.72 111.12,85.72 111,85.6 108.84,85.6 108.37,86.07 107.41,86.07 105.84,87.64 103.16,87.64 103.02,87.5 97.87,87.5 96.47,86.1 96.46,86.1 93.96,83.59 90.45,83.59 86.66,87.38 78.67,87.38 77.57,86.29 71.22,86.29 70.02,85.08 67.83,85.08 67.22,84.48 67.22,82.76 66.06,81.59 66.06,78.45 63.51,75.91 45.21,75.91 40.79,71.48 38.82,71.48 31.26,63.92 26.89,63.92 23.96,61 23.96,60.03 20.79,56.86 20.79,53.83 20.38,53.43 20.38,45.33 21.51,44.2 21.77,44.2 v1(22.02,44.45)
  BOTTOM w0.102: C269.1 21.34,44.34 21.51,44.17 21.74,44.17 v1(22.02,44.45)
USB3_TXP2_R: length 2.2
  BOTTOM w0.102: R502.2 18.71,44.54 19.51,44.54 19.84,44.21 20.07,44.21 C269.2
USB3_TXP2_USB3: length 9.1
  BOTTOM w0.102: R502.1 17.87,44.54 16.94,44.54 16.63,44.23 16.23,44.23 16.03,44.44 C268.1 D29.1 15.01,44.35 14.9,44.23 14.67,44.23 v1(14.16,44.74) 14.16,44.49 13.91,44.23 13.7,44.23 13.35,43.88 13.35,42.79 13.11,42.55 12.83,42.55 12.61,42.76 CN5.9
USB_BC_EN: length 13.4
  TOP w0.102: R168.1 23.13,60.44 22.75,60.06 21.72,60.06 v2(21.39,59.73) 21.39,59.49 20.32,58.42 20.32,53.67 v1(21.56,52.43)
  BOTTOM w0.102: U21.4 21.42,51.8 20.96,52.26 R481.2 21.21,52.96 21.56,52.6 v1(21.56,52.43)
USB_BC_ON: length 45.2
  IN1 w0.114: v1(21.64,53.19) 21.13,52.68 21.13,47.33 25.3,43.15 v1(45.95,43.15)
  BOTTOM w0.102: U21.1 20.33,50.28 20.5,50.44 20.5,52.14 20.18,52.45 R481.1 20.18,53 20.57,53.39 21.44,53.39 v1(21.64,53.19) ; U23.96 46.12,37.57 45.08,38.61 v2(45.08,41.29) 45.08,42.29 v1(45.95,43.15)
USB_CHARGE_ON: length 60.1
  IN1 w0.114: v1(43.23,34.37) 39.99,37.6 27.11,37.6 24.48,34.98 20.91,34.98 18.68,37.21 18.68,43.15 17.91,43.93 17.91,58.17 v1(19.23,59.49)
  BOTTOM w0.102: v1(19.23,59.49) 19.3,59.56 R446.1 ; v1(43.23,34.37) 43.1,34.24 43.1,31.14 43.61,30.63 44.99,30.63 v2(45.2,30.42) 46.05,29.57 U23.76
USB_CR_ON: length 2.5
  BOTTOM w0.102: U17.8 21.41,60.16 21.01,59.77 R446.2 21.04,59.54 v2(21.04,58.56)
USB_OC0#: length 140.8
  TOP w0.076: U6.AL3 99.25,69.81 98.99,69.56 98.72,69.56 98.5,69.78 98.5,69.95 98.31,70.14 97.33,70.14
  TOP w0.102: v1(22.23,41.67) 22.23,42.05 R200.2 ; 97.33,70.14 96.56,70.14 95.2,71.5 90.42,71.5 v1(89.53,70.61) 89.53,72.15 R132.2 ; v1(18.54,71.98) 18.81,72.25 19.78,72.25 20.62,71.41 R133.1
  IN1 w0.114: v1(89.53,70.61) 89.53,69.96 87.91,68.34 85.83,68.34 85.13,67.65 85.13,64.09 82.6,61.55 82.6,54.68 80.27,52.35 80.27,47.16 79.57,46.46 78.12,46.46 71.77,40.11 64.73,40.11 64.52,40.32 61.51,40.32 60.91,40.92 54.71,40.92 54.13,40.34 31.01,40.34 30.73,40.61 25.47,40.61 24.51,41.57 22.32,41.57 v1(22.23,41.67)
  IN3 w0.102: v1(22.23,41.67) 20.83,43.06 20.83,56.08 17.73,59.18 17.73,71.17 v1(18.54,71.98)
USB_OC1#: length 151.2
  TOP w0.102: v1(176.72,35.88) 177.05,36.2 v2(178.76,36.2) R213.2 ; v1(88.77,66.93) 88.4,66.56 R153.2 88.4,66.14 90.81,63.73 93.52,63.73 96.74,66.95 98.05,66.95 U6.AT1
  IN3 w0.102: v1(88.77,66.93) 88.57,67.13 86.66,67.13 85.98,66.45 85.98,63.02 86.26,62.74 86.26,60.25 85.29,59.28 85.29,57.7 86.57,56.42 86.57,52.74 86.74,52.57 86.74,36.8 87.29,36.25 87.8,36.25 88.57,35.48 88.57,29.76 90.82,27.51 116.26,27.51 116.46,27.3 135.25,27.3 135.66,27.71 162.94,27.71 171.11,35.88 v1(176.72,35.88)
USB_OC2#: length 11.5
  TOP w0.102: R114.2 89.33,75.4 v1(90.34,75.4) 93.22,72.52 95.99,72.52 96.27,72.24 96.95,72.24 97.41,71.78 98.4,71.78 98.83,71.35 U6.AH2
USB_OC3#: length 18.6
  TOP w0.076: U6.AV3 99.34,65.51 99.01,65.18 98.71,65.18 98.7,65.17 95.82,65.17 95.76,65.11
  TOP w0.102: 95.76,65.11 93.75,63.09 90.13,63.09 89.94,62.91 88.74,62.91 88.03,63.62 88.03,64.16 88.04,64.17 88.04,64.51 88.03,64.52 88.03,64.54 87.82,64.74 86.65,64.74 R155.2 86.24,65.25 85.87,65.62 84.37,65.62 v2(83.94,65.19)
USBCOMP: length 9.3
  TOP w0.254: U6.AJ11 104.65,70.46 v1(104.42,70.23) 104.39,70.23 103.94,70.69 U6.AJ10
  BOTTOM w0.254: R437.2 104.04,63.81 104.04,68.59 104.34,68.9 104.34,70.15 v1(104.42,70.23)
USBON#: length 189.7
  TOP w0.089: 78.25,22.84 77.61,22.84 v1(77.6,22.86)
  TOP w0.102: R220.1 v1(21.98,34.54) ; R202.1 179.64,39.55 179.64,38.58 177.89,36.83 176.14,36.83 173.36,34.04 173.36,32.77 171.83,31.24 171.83,26.9 168.87,23.94 99.12,23.94 91.94,16.76 84.42,16.76 v2(78.89,22.29) 78.34,22.84 78.25,22.84
  IN1 w0.114: v1(75.95,29.21) 74.8,30.35 70.99,30.35 69.77,31.57 59.56,31.57 57.76,33.38 49.28,33.38 v1(49.02,33.12) 48.59,32.69 45.34,32.69 45.06,32.97 42.62,32.97 38.21,37.38 27.31,37.38 23.82,33.88 22.64,33.88 v1(21.98,34.54)
  IN3 w0.102: v1(75.95,29.21) 75.44,28.7 75.44,24.89 76.83,23.49 76.96,23.49 v1(77.6,22.86)
  BOTTOM w0.102: U23.79 47.96,30.77 49.02,31.83 v1(49.02,33.12)
VA:
  vias: v2(196.97,57.75) v2(199.25,57.72)
VA1:
  vias: v2(201.95,54.73) v2(204.92,54.85) v4(198.37,53.54) v4(198.37,52.81) v4(198.37,52.04) v4(199.11,53.54) v4(199.11,52.78) v4(199.11,52.02)
VA2:
  vias: v2(189.04,47.36)
VL: length 174.9
  TOP w0.203: PU2.11 44.09,62.83 43.61,62.36 43.1,62.36 42.68,61.93 PC44.2
  TOP w0.254: v1(42.19,62.31) 42.19,62.21 PC44.2
  IN2 w0.254: v1(42.19,62.31) 41.76,62.74 40.51,62.74 39.24,64.01 39.24,71.37 48.01,80.14 52.07,80.14 55.67,83.74 55.67,86.28 58.68,89.28 59.42,89.28 60.9,90.76 63.81,90.76 66.56,93.51 75.2,93.51 76.37,94.68 80.03,94.68 86.38,101.03 95.18,101.03 96.11,100.1 98.2,100.1 98.81,100.71 121.29,100.71 121.71,101.13 125.26,101.13 128.13,98.26 137.39,98.26 142.49,93.16 146.62,93.16 152.8,86.98 152.8,77.86 156.56,74.1 156.56,73.31 v1(158.24,71.63)
  BOTTOM w0.254: v1(158.24,71.63) v2(159.6,71.63) 161.45,71.63 163.96,69.12 PR132.1 PR133.1
VR_SVID_ALERT#: length 66.8
  TOP w0.102: v1(150.57,79.46) 150.54,79.49 150.28,79.49 150.16,79.62 149.26,80.52 v2(148.55,80.52) R84.2 145.53,80.92 144.05,80.92 R83.2
  IN1 w0.114: v1(150.57,79.46) 154.78,79.46 155.05,79.73 165.53,79.73 166.45,80.64 196.84,80.64 198.77,82.58 198.77,87.48 v1(198.37,87.88)
  BOTTOM w0.102: PR109.1 PR116.2 198.88,89.67 198.88,88.39 v1(198.37,87.88)
VR_SVID_CLK: length 67
  TOP w0.102: R91.1 144.28,79.76 146.61,79.76 v2(146.94,79.43) 149.35,79.43 149.88,78.9 150.5,78.9 v1(150.57,78.83)
  IN1 w0.114: v1(150.57,78.83) 154.96,78.83 155.29,79.16 165.87,79.16 166.79,80.07 197.07,80.07 199.35,82.35 199.35,87.71 v1(199.52,87.88)
  BOTTOM w0.102: PR110.1 PR117.2 200.02,89.67 200.02,88.39 v1(199.52,87.88)
VR_SVID_DATA: length 65.7
  TOP w0.102: R77.1 143.77,81.79 144.15,82.17 145.42,82.17 R78.2 v2(146.98,81.66) 147.04,81.6 148.97,81.6 150.39,80.18 150.5,80.18 150.53,80.14 150.57,80.1 v1(150.57,80.1)
  IN1 w0.114: v1(197.23,87.88) 197.49,87.62 197.49,82.11 196.6,81.22 166.15,81.22 165.24,80.3 154.81,80.3 154.72,80.21 154.61,80.1 v1(150.57,80.1)
  BOTTOM w0.102: PR108.1 PR115.2 196.73,89.67 196.73,88.39 v1(197.23,87.88)
VRON: length 247.5
  IN1 w0.254: v1(196.47,100.08) 196.85,99.69 196.85,96.01 195.96,95.12 195.96,93.98 200.28,89.66 200.28,82.37 198.25,80.34 198.25,71.31 198.88,70.68 200.28,70.68 202.57,68.38 202.57,61.33 202.82,61.09 202.82,56.96 200.39,54.54 200.39,48.5 196.47,44.58 196.47,41.75 191.11,36.39 188.46,36.39 182.6,30.53 182.6,22.71 180.49,20.6 180.49,18.69 178.68,16.88 133.34,16.88 131.77,15.31 131.77,14.2 130.13,12.57 85.17,12.57 83.65,14.1 56.72,14.1 v1(56.64,14.17)
  BOTTOM w0.203: U23.69 45.68,26.77 R543.1
  BOTTOM w0.254: v1(56.64,14.17) v2(55.18,14.17) 53.77,14.17 45.35,22.59 45.35,25.14 R543.1 ; PR90.1 v1(196.47,100.08)
VRON_CPU: length 85.5
  TOP w0.254: R37.2 v2(136.14,92.62) 136.14,93.07 136.78,93.7 136.78,94.24 R17.1 135.89,95.13 v1(135.89,95.6) ; v1(135.18,83.75) 135.18,83.66 U6.F60
  IN1 w0.254: v1(135.18,83.75) 135.19,83.75 135.19,83.65 134.72,83.19 134.24,83.19 133.99,83.44 133.99,86.23 134.87,87.12 134.87,91.44 135.89,92.46 v1(135.89,95.6) 135.89,96.01 136.91,97.03 150.24,97.03 150.67,97.45 158.32,97.45 158.88,96.9 163.7,96.9 165.58,98.78 176.3,98.78 v1(176.53,98.55)
  BOTTOM w0.254: v1(176.53,98.55) 176.53,99.57 180.98,104.01 194.56,104.01 194.92,103.66 PR83.1
VRTC1:
  vias: v1(81.54,46.74) v1(81.54,46.1) v2(80.91,46.45)
VRTC2:
  vias: v1(84.08,46.52) v1(84.08,45.89) v2(84.8,46.17)
WLAN_CLKREQ#: length 5.7
  BOTTOM w0.102: CN9.53 185.68,57.28 184.53,56.13 183.18,56.13 183.01,55.96 R473.2 182.81,55.76 182.26,55.21 v2(182.08,55.21)
WLAN_RST#: length 3
  TOP w0.102: R154.1 185.42,67.05 v1(185.43,67.25) 185.43,67.9 v2(185.49,67.96)
  BOTTOM w0.102: CN9.52 v1(185.43,67.25)
WLAN_WAKE#: length 9.9
  BOTTOM w0.102: v2(183.43,53.41) 183.87,53.85 Q22.1 184.66,54.61 184.91,54.86 187.06,54.86 R474.1 187.46,56.52 186.69,56.52 186.18,57.03 CN9.55
WRST#: length 15.7
  BOTTOM w0.102: U23.14 62.12,32.37 61.7,32.79 61.06,32.79 60.58,33.27 60.58,35.43 60.83,35.69 60.83,36.7 63.81,39.68 v2(63.97,39.68) 64.35,39.68 64.43,39.76 C312.1 R517.1 65.41,41.14 66.36,40.18 D32.2
XDP_BPM#0: length 45
  TOP w0.102: U6.J60 134.51,82.19 v1(134.51,82.26) ; v1(169.63,97.63) 169.25,97.26 CN1.41
  IN1 w0.114: v1(134.51,82.26) 135.59,83.33 136.16,83.33 136.72,83.89 138.93,83.89 139.55,84.5 147.21,84.5 150.51,87.81 158.33,87.81 159.23,88.7 159.23,90.01 165.75,96.54 167.07,96.54 168.7,98.17 169.09,98.17 v1(169.63,97.63)
XDP_BPM#1: length 42.8
  TOP w0.102: v1(168.76,97.63) 168.76,97.62 CN1.42 ; v1(135.16,82.26) 134.86,82.56 U6.H60
  IN1 w0.114: v1(168.76,97.63) 167.25,96.12 165.93,96.12 159.72,89.91 159.72,88.6 158.51,87.39 150.69,87.39 147.38,84.08 139.72,84.08 139.11,83.47 136.9,83.47 136.34,82.91 135.82,82.91 v1(135.16,82.26)
XDP_BPM#2: length 9.2
  TOP w0.076: U6.H61 135.77,82.92 136.29,82.92 136.52,82.69 136.52,82.51 136.69,82.34 136.94,82.34 137.08,82.49
  TOP w0.102: TP7.1 140.23,86.26 140.23,85.09 139.52,84.38 139.17,84.38 137.28,82.49 137.08,82.49
XDP_BPM#3: length 8.1
  TOP w0.076: U6.H62 136.38,82.41 136.39,82.41 136.62,82.17 137.04,82.17 137.16,82.3 137.38,82.3 138.22,83.14
  TOP w0.102: TP8.1 142.11,85.22 140.65,85.22 139.6,84.18 139.26,84.18 138.22,83.14
XDP_BPM#4: length 14
  TOP w0.102: v1(133.82,81.5) 133.88,81.5 U6.K59 ; TP11.1 144.53,83.82 143.55,84.8 140.8,84.8 138.79,82.78 v1(138.79,82.63)
  IN3 w0.102: v1(138.79,82.63) 138.68,82.63 138.4,82.91 137.04,82.91 135.7,81.57 133.89,81.57 v1(133.82,81.5)
XDP_BPM#5: length 9.5
  TOP w0.102: U6.H63 136.91,82.73 137.24,82.73 139.09,84.58 139.44,84.58 140.03,85.18 140.03,86.92 142.14,89.03 TP6.1
XDP_BPM#6: length 15.6
  TOP w0.102: v1(138.15,82.5) 138.15,82.78 139.34,83.97 139.69,83.97 140.71,85 144.11,85 144.78,84.33 146.56,84.33 TP12.1 ; U6.K60 134.86,81.1 v1(134.52,80.76)
  IN3 w0.102: v1(134.52,80.76) 135.13,81.37 135.79,81.37 137.01,82.59 138.06,82.59 v1(138.15,82.5)
XDP_BPM#7: length 7.1
  TOP w0.102: TP9.1 140.59,83.82 139.45,82.68 139.45,82.42 139.04,82.02 138.71,82.02 138.17,81.48 136.96,81.48 136.88,81.56 135.79,81.56 U6.J61
XDP_DBRESET_N: length 6.8
  TOP w0.102: v2(160.57,85.27) 160.57,85.36 161.38,86.17 161.38,86.71 161.81,87.13 R55.2 R56.2 162.94,88.9 162.76,89.09 CN1.7
XDP_PRDY#: length 47.1
  TOP w0.102: v1(135.81,82.26) 136.16,81.91 U6.J62 ; v1(172.08,97.64) 172.49,98.05 172.98,98.05 173.25,97.77 CN1.33
  IN1 w0.114: v1(172.08,97.64) 170.15,95.7 166.1,95.7 160.13,89.73 160.13,88.43 158.68,86.97 150.86,86.97 147.56,83.67 139.89,83.67 139.28,83.05 137.07,83.05 136.51,82.49 136.05,82.49 v1(135.81,82.26)
XDP_PREQ#: length 47
  TOP w0.102: U6.K62 136.37,81.13 136.68,80.82 138.48,80.82 v1(138.68,81.03) ; CN1.32 v1(173.76,97.64)
  IN1 w0.114: v1(138.68,81.03) 141.09,83.44 147.65,83.44 150.95,86.74 158.77,86.74 160.36,88.33 160.36,89.64 166.2,95.47 171.59,95.47 v1(173.76,97.64)
XDP_RST_R_N: length 5.6
  TOP w0.102: v1(163.13,85.38) 163.52,85.77 163.52,86.65 163.96,87.1 R57.2 163.25,87.83 CN1.8
XDP_TCK_CPU: length 67
  TOP w0.102: U6.AE63 136.85,72.85 138.07,72.85 138.35,73.13 139.63,73.13 140.25,72.5 147.7,72.5 v2(148.06,72.86) R125.2 148.98,74.3 148.96,74.31 R117.2 149.47,75.31 151.84,75.31 153.29,76.76 153.29,88.39 152.53,89.15 v1(152.53,89.16) ; v1(159.61,93.09) 160.25,93.73 CN1.59
  TOP w0.114: U6.E60 135.16,84.46 v1(135.16,84.58)
  IN1 w0.114: v1(152.53,89.16) 152.53,89.15 ; 152.53,89.15 152.55,89.15 152.98,89.59 153.37,89.59 153.64,89.31 157.35,89.31 158.11,90.07 158.11,90.67 159.61,92.18 v1(159.61,93.09) ; 152.53,89.15 152.29,89.39 151.53,89.39 151.26,89.66 149.23,89.66 148.78,89.22 148.78,86.67 147.03,84.92 139.37,84.92 138.76,84.31 136.67,84.31 136.4,84.58 v1(135.16,84.58)
XDP_TCK_PCH: length 45.2
  TOP w0.102: U6.AE62 136.38,72.89 136.7,72.57 136.92,72.57 137.02,72.66 138.15,72.66 138.41,72.92 139.55,72.92 140.17,72.3 148.45,72.3 149.4,73.25 150.35,73.25 v2(150.78,73.68) R118.2 153.49,76.39 153.49,88.83 v1(153.16,89.16) ; v1(160.25,93.07) 160.76,93.57 CN1.58
  IN1 w0.114: v1(153.16,89.16) 153.24,89.08 157.47,89.08 158.34,89.95 158.34,90.55 160.25,92.46 v1(160.25,93.07)
XDP_TDI_CPU: length 27
  TOP w0.102: U4.6 153.15,91.12 152.43,90.4 151.97,90.4 151.59,90.02 149.33,90.02 145.18,94.17 v2(143.04,94.17) 142.84,94.17 142.11,93.45 142.11,89.92 139.42,87.22 139.42,85.43 139.18,85.19 138.84,85.19 137.02,83.38 U6.F63
XDP_TDI_PCH: length 58.7
  TOP w0.076: U6.AD61 135.84,73.35 137.09,73.35 137.16,73.28
  TOP w0.102: v1(149.48,88.27) 149.73,88.52 151.22,88.52 152.88,86.86 152.88,76.94 151.74,75.79 147.68,75.79 147.16,75.27 147.16,75.25 146.52,74.61 146.5,74.61 146.19,74.3 145.17,74.3 R123.2 144.16,73.29 v2(140.66,73.29) 140.07,73.29 139.83,73.53 138.21,73.53 137.91,73.23 137.21,73.23 137.16,73.28 ; v1(152.38,90.93) 152.65,91.19 U4.5 ; v1(158.37,89.36) 158.99,88.74 160.34,88.74 160.76,89.15 CN1.3 160.76,91.69 160.6,91.84 158.1,91.84 v1(157.73,92.2)
  IN1 w0.114: v1(157.73,92.2) 157.23,91.69 153.15,91.69 v1(152.38,90.93) ; v1(149.48,88.27) 149.69,88.48 158.09,88.48 158.37,88.76 v1(158.37,89.36)
XDP_TDO_CPU: length 27.3
  TOP w0.076: 137.16,83.23 137.02,83.09 136.69,83.09 136.4,83.38 U6.F62
  TOP w0.102: v1(151.13,91.16) 151.26,91.16 151.65,91.55 U4.3 ; 137.16,83.23 138.92,84.99 139.27,84.99 139.62,85.35 139.62,87.14 142.32,89.83 142.32,92.54 R30.2 143.14,93.37 145.25,93.37 v2(145.28,93.33) 148.8,89.81 v1(152.02,89.81)
  IN1 w0.114: v1(151.13,91.16) 151.26,91.16 152.02,90.4 v1(152.02,89.81)
XDP_TDO_PCH: length 71.1
  TOP w0.076: U6.AE61 135.84,73.18 136.97,73.18 137.11,73.04
  TOP w0.102: v1(150.47,91.82) 150.6,91.82 150.78,92 U4.2 ; v1(157.1,93.85) 158.71,92.25 161.12,92.25 161.76,91.61 CN1.5 161.76,87.98 R54.2 159.77,88.27 158.55,88.27 v1(157.91,88.91) ; 137.11,73.04 137.99,73.04 138.28,73.33 139.72,73.33 140.28,72.77 145.03,72.77 R124.2 146.96,74.71 147.41,74.71 v2(147.75,75.05) 148.22,75.52 151.77,75.52 153.09,76.84 153.09,86.94 151.05,88.98 149.56,88.98 v1(149.48,88.9)
  IN1 w0.114: v1(150.47,91.82) 150.47,96.11 151.51,97.16 154.56,97.16 157.1,94.61 v1(157.1,93.85) ; v1(149.48,88.9) 149.56,88.98 150.92,88.98 151.17,88.73 157.74,88.73 v1(157.91,88.91)
XDP_TMS_CPU: length 34.8
  TOP w0.076: U6.E61 135.51,84.24 135.69,84.41 135.69,84.72 136.06,85.09 136.47,85.09 136.55,85.17 136.98,85.17
  TOP w0.102: 136.98,85.17 137.16,85.35 137.16,85.7 138.3,86.84 138.3,88.39 139.67,89.76 139.67,94.13 142.85,97.31 142.85,100.02 143.11,100.28 v2(147.87,100.28) 151.31,100.28 153.87,97.72 U4.8
XDP_TMS_PCH: length 57.6
  TOP w0.102: v1(149.48,87.63) v2(150.64,87.63) 151.82,87.63 152.68,86.78 152.68,77.02 151.66,76 147.6,76 146.15,74.55 145.82,74.55 142.49,74.55 R122.2 141.71,73.77 140.45,73.77 140.42,73.74 137.89,73.74 137.56,74.07 136.59,74.07 U6.AD62 ; v1(158.8,89.84) 158.8,89.48 159.34,88.94 159.92,88.94 160.25,89.28 CN1.2 160.25,91.46 160.08,91.64 159.45,91.64 159.26,91.44 157.89,91.44 157.1,92.24 v1(157.1,92.58) ; v1(153.29,96.39) 153.15,96.25 U4.9
  IN1 w0.114: v1(149.48,87.63) 150.08,88.23 158.16,88.23 158.8,88.87 v1(158.8,89.84) ; v1(157.1,92.58) 156.37,93.32 156.37,94.33 154.31,96.39 v1(153.29,96.39)
XDP_TRST#: length 78.9
  TOP w0.076: U6.AU62 136.34,66.15 136.68,65.81 137.29,65.81
  TOP w0.102: v1(152.3,96.39) 152.15,96.24 U4.11 ; 137.29,65.81 137.65,65.45 138.72,65.45 139.08,65.8 140.06,65.8 141.1,66.83 141.1,67.05 R147.2 142.13,68.08 142.13,69.66 144.56,72.1 148.53,72.1 149.48,73.05 150.83,73.05 153.7,75.91 v2(153.7,90.16) 153.7,92.2 v1(153.92,92.43) ; v1(139.01,85.6) 139.22,85.8 139.22,87.31 141.91,90 141.91,94.67 v1(143,95.76)
  TOP w0.114: U6.E59 134.52,84.48 v1(134.52,84.58)
  IN1 w0.114: v1(143,95.76) 145.8,95.76 150.35,91.2 150.51,91.2 151,91.69 151,92.58 150.75,92.84 150.75,94.84 v1(152.3,96.39) 153.29,95.4 153.29,93.07 v1(153.92,92.43) ; v1(134.52,84.58) 134.96,85.01 136.47,85.01 136.95,84.54 138.39,84.54 139.01,85.17 v1(139.01,85.6)
XDP_TRST_N: length 14.7
  TOP w0.102: v1(151.65,96.39) U4.12 ; v1(157.1,93.22) 157.29,93.22 158.47,92.04 160.81,92.04 161.25,91.6 CN1.4
  IN1 w0.114: v1(151.65,96.39) 152.15,96.9 154.18,96.9 156.67,94.41 156.67,93.65 v1(157.1,93.22)
XTAL24_IN: length 11.7
  TOP w0.102: Y1.3 117.6,94.2 117.6,92.79 117,92.19 C17.1 116.19,91.57 115.95,91.57 115.35,90.97 R41.2 114.74,90.65 114.74,90.47 114.19,89.92 v1(114.19,89.26) 114.11,89.34 113.54,89.34 113.36,89.17 113.36,88.59 112.76,87.99 112.76,86.95 U6.A25
XTAL24_OUT: length 9.3
  TOP w0.102: Y1.1 114.46,92.84 113.9,92.28 C16.1 113.9,91.82 114.28,91.44 R41.1 114.55,90.69 114.55,90.55 114.16,90.16 113.29,90.16 v1(113.29,90.16) 113.29,90.16 113.4,90.05 113.4,89.47 113.17,89.25 113.17,88.67 112.57,88.07 112.57,86.49 U6.B25
N03288: length 16.2
  TOP w0.508: v1(195.2,49.4) 196.72,50.93 196.72,53.5 201.24,58.02 201.24,58.37 202.06,59.18 204.22,59.18
  BOTTOM w0.508: v1(195.2,49.4) 194.69,48.89 PQ35.4
  vias: v2(205.07,58.92)
N05582: length 5
  TOP w0.508: PR63.1 v1(132.56,14.85)
  BOTTOM w0.102: v2(131.13,13.96) 131.32,14.15 PR154.2
  BOTTOM w0.508: PQ36.4 130.43,15.37 130.69,15.1 PR154.2 131.57,14.85 131.72,14.85 131.72,14.86 132.45,14.86 132.46,14.85 v1(132.56,14.85)
N05646:
  vias: v2(209.54,56.5)
N05670: length 136.6
  TOP w0.102: v2(135.63,13.38) 135.64,13.39 PQ14.2
  TOP w0.254: v1(208.53,60.07) 208.42,60.19 PR34.1 PQ8.5 ; PQ14.2 136.27,14.6 v1(136.85,15.18)
  IN3 w0.254: v1(208.53,60.07) 204.65,56.18 202.74,56.18 201.8,55.25 201.8,48.49 200.7,47.39 200.7,40.83 195.9,36.03 195.9,31.6 197.82,29.68 200.52,29.68 201.46,28.74 201.46,19.49 204.44,16.51 204.44,12.55 203.58,11.68 190.73,11.68 187.4,15.01 153.17,15.01 152.05,16.13 143.13,16.13 142.43,16.83 136.92,16.83 136.21,16.12 136.21,15.81 v1(136.85,15.18)
N05802: length 38.2
  BOTTOM w0.254: PR159.1 122.42,11.89 118.75,11.89 117.2,10.34 117.2,5.41 119.74,2.87 139.29,2.87 139.95,3.53 141.82,3.53 PR173.2
  vias: v1(120.41,11.29)
N06510: length 2.6
  TOP w0.508: PR75.2 v2(132.32,6.12) 132.94,6.12 132.97,6.1 PC70.1
N90670: length 5
  TOP w0.102: v2(112.12,10.66) 112.12,10.82 v1(111.63,11.3) 111.26,11.68 PC69.1 PR71.1
  BOTTOM w0.102: v1(111.63,11.3) 112.4,11.3 112.66,11.56 PJ2.3
N90734:
  vias: v2(102.86,15.86) v2(103.52,18.18)
N91425: length 51.5
  TOP w0.102: v1(97.92,54.38) 98.35,54.38 v2(98.66,54.7) 98.81,54.84 R183.2 ; R109.1 83.38,76.65 83,76.27 83,75.76 82.62,75.38 R115.1 81.86,75.27 v1(81.21,74.62)
  IN1 w0.114: v1(79.88,53.26) 79.88,54.1 79.67,54.32 79.67,54.9 80.45,55.68 80.45,59.99 79.67,60.77 79.67,64.29 78.99,64.97 78.99,67 77.94,68.05 77.94,69.34 78.61,70.01 78.61,70.77 78.91,71.07 78.91,72.68 80.02,73.79 80.55,73.79 81.21,74.46 v1(81.21,74.62)
  BOTTOM w0.102: v1(79.88,53.26) 80.39,53.26 80.51,53.38 87.95,53.38 87.96,53.39 93.77,53.39 94.07,53.09 96.62,53.09 v1(97.92,54.38) ; v1(81.21,74.62) 81.64,75.05 R393.2
N125333: length 4.6
  TOP w0.102: Q2.2 140.89,99.02 140.24,99.66 v2(140.12,99.66) 139.23,99.66 138.89,99.31 137.53,99.31 R3.1
N125337: length 6.4
  TOP w0.102: v2(136.46,99.76) 136.46,99.37 R3.2 136.53,97.54 134.15,97.54 133.9,97.79 Q1.1
N243495:
  vias: v2(185.56,47.82)
N420837: length 2.9
  BOTTOM w0.102: C361.1 64.7,32.89 v1(64.58,33.01) 63.9,33.01 63.74,33.17 U23.12
N423040: length 2.7
  BOTTOM w0.102: R530.1 C362.1 68.58,32.26 v2(68.58,32.47)
N16778199: length 2.4
  TOP w0.102: PC22.1 191.91,77.84 v2(191.91,78.37)
  TOP w0.508: PC22.1 PR16.2
N16779997: length 14.7
  TOP w0.508: Q9.3 12.57,72.77 v1(12.7,72.64)
  BOTTOM w0.508: R350.1 R354.1 R359.1 R363.1 R373.1 R380.1 R385.1 R389.1 14.49,75.45 v2(13.58,74.54) 12.7,73.66 v1(12.7,72.64)
N16780395: length 2.6
  TOP w0.102: PR18.2 192.77,66.14 v2(192.65,66.26)
  TOP w0.508: PR18.2 PC39.1
N16793601: length 2.4
  TOP w0.089: 38.56,21.84 v1(38.47,21.76)
  TOP w0.102: U16.7 38.38,21.66 v1(38.47,21.76) ; C142.1 38.56,21.84
N16797704: length 3
  TOP w0.203: C147.1 30.98,16.91 v1(31.87,16.91) 32.51,17.55 U16.39
N16798387: length 3.6
  TOP w0.102: U16.35 30.28,19.66 30.02,19.41 v1(30.02,18.75)
  BOTTOM w0.102: C392.1 29.96,18.68 v1(30.02,18.75) 30.27,18.99 v2(30.27,19.98)
N16798543: length 2.8
  TOP w0.102: v1(30.61,18.03) 30.86,18.03 31.19,18.36 U16.37
  BOTTOM w0.102: v1(30.61,18.03) 30.33,18.31 29.75,18.31 C392.2
N16798641: length 3.5
  TOP w0.102: U16.34 30.27,20.06 29.3,19.09 C145.1 29.09,18.47 29.09,18.47 v1(28.44,17.82)
N16800298: length 3
  TOP w0.102: R292.2 35.09,26.41 v1(34.71,26.02)
  TOP w0.203: U16.15 35.31,25.12 35.56,25.37 R292.2
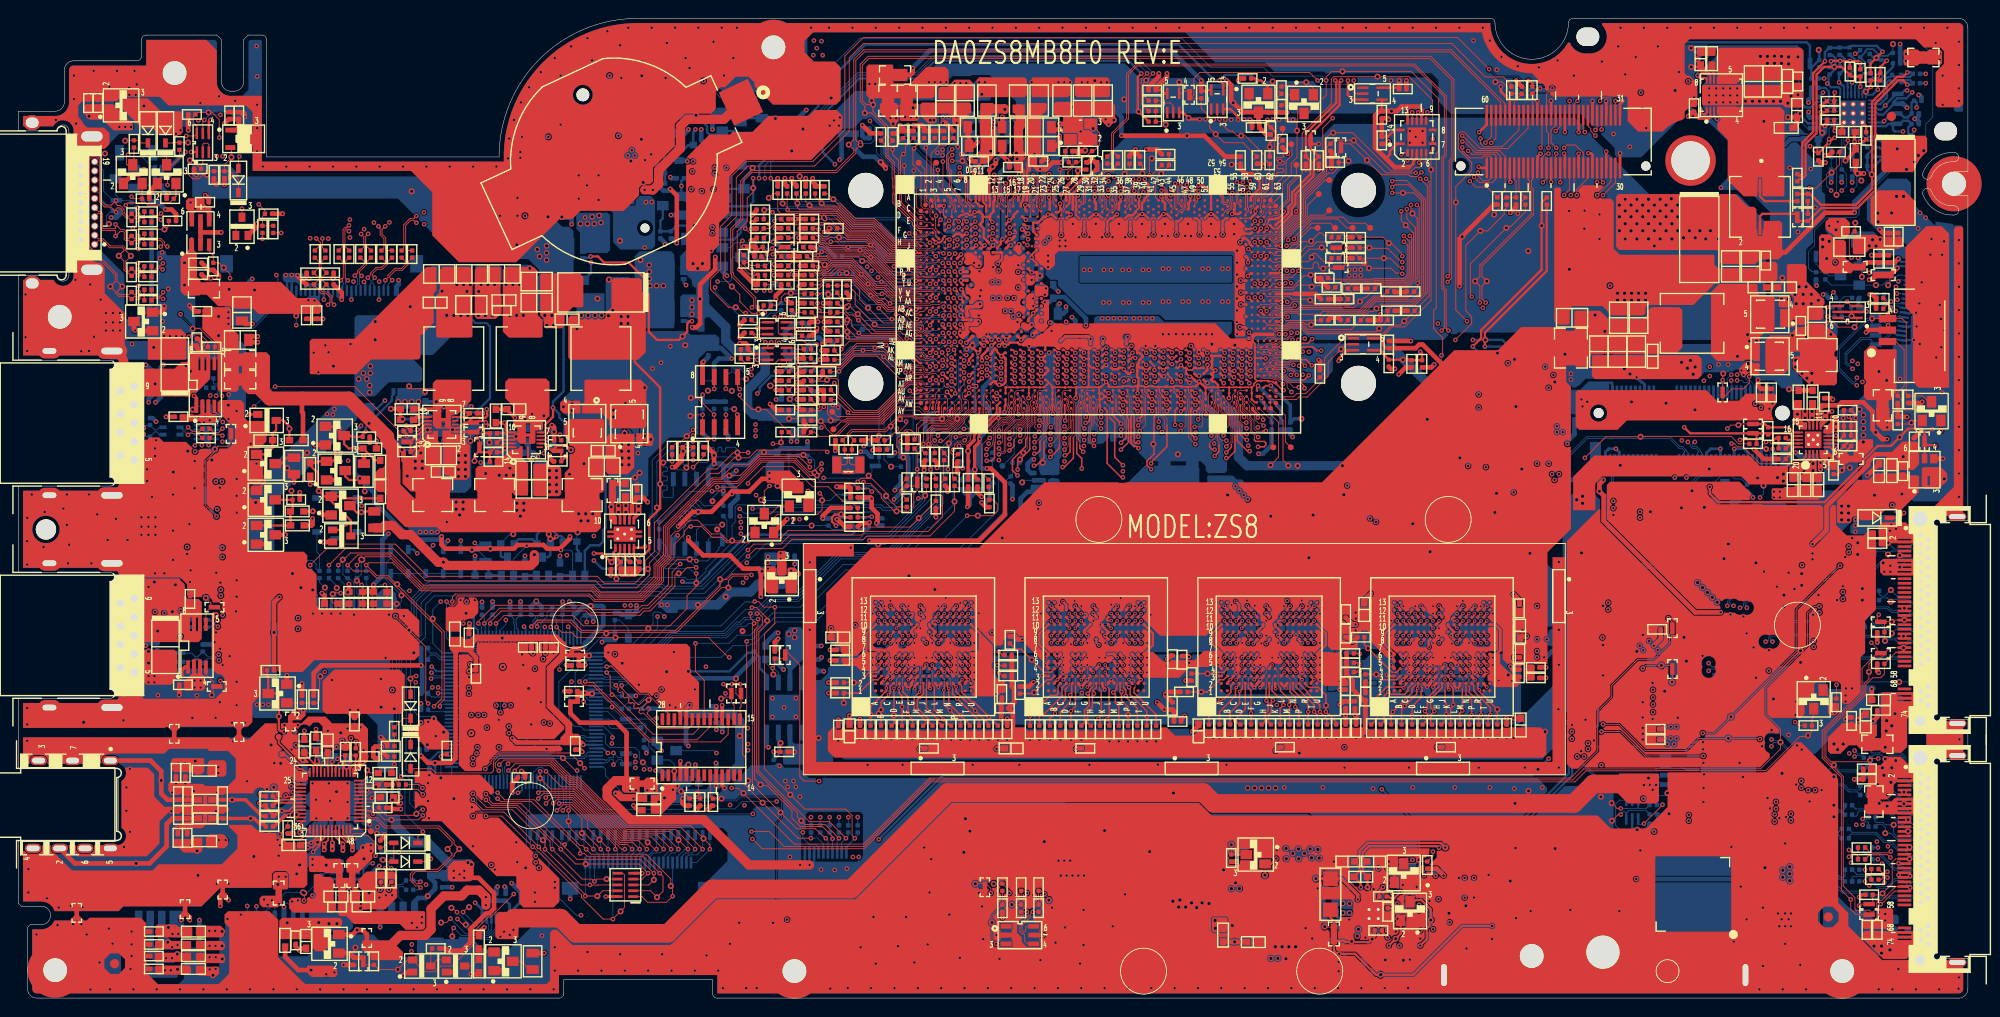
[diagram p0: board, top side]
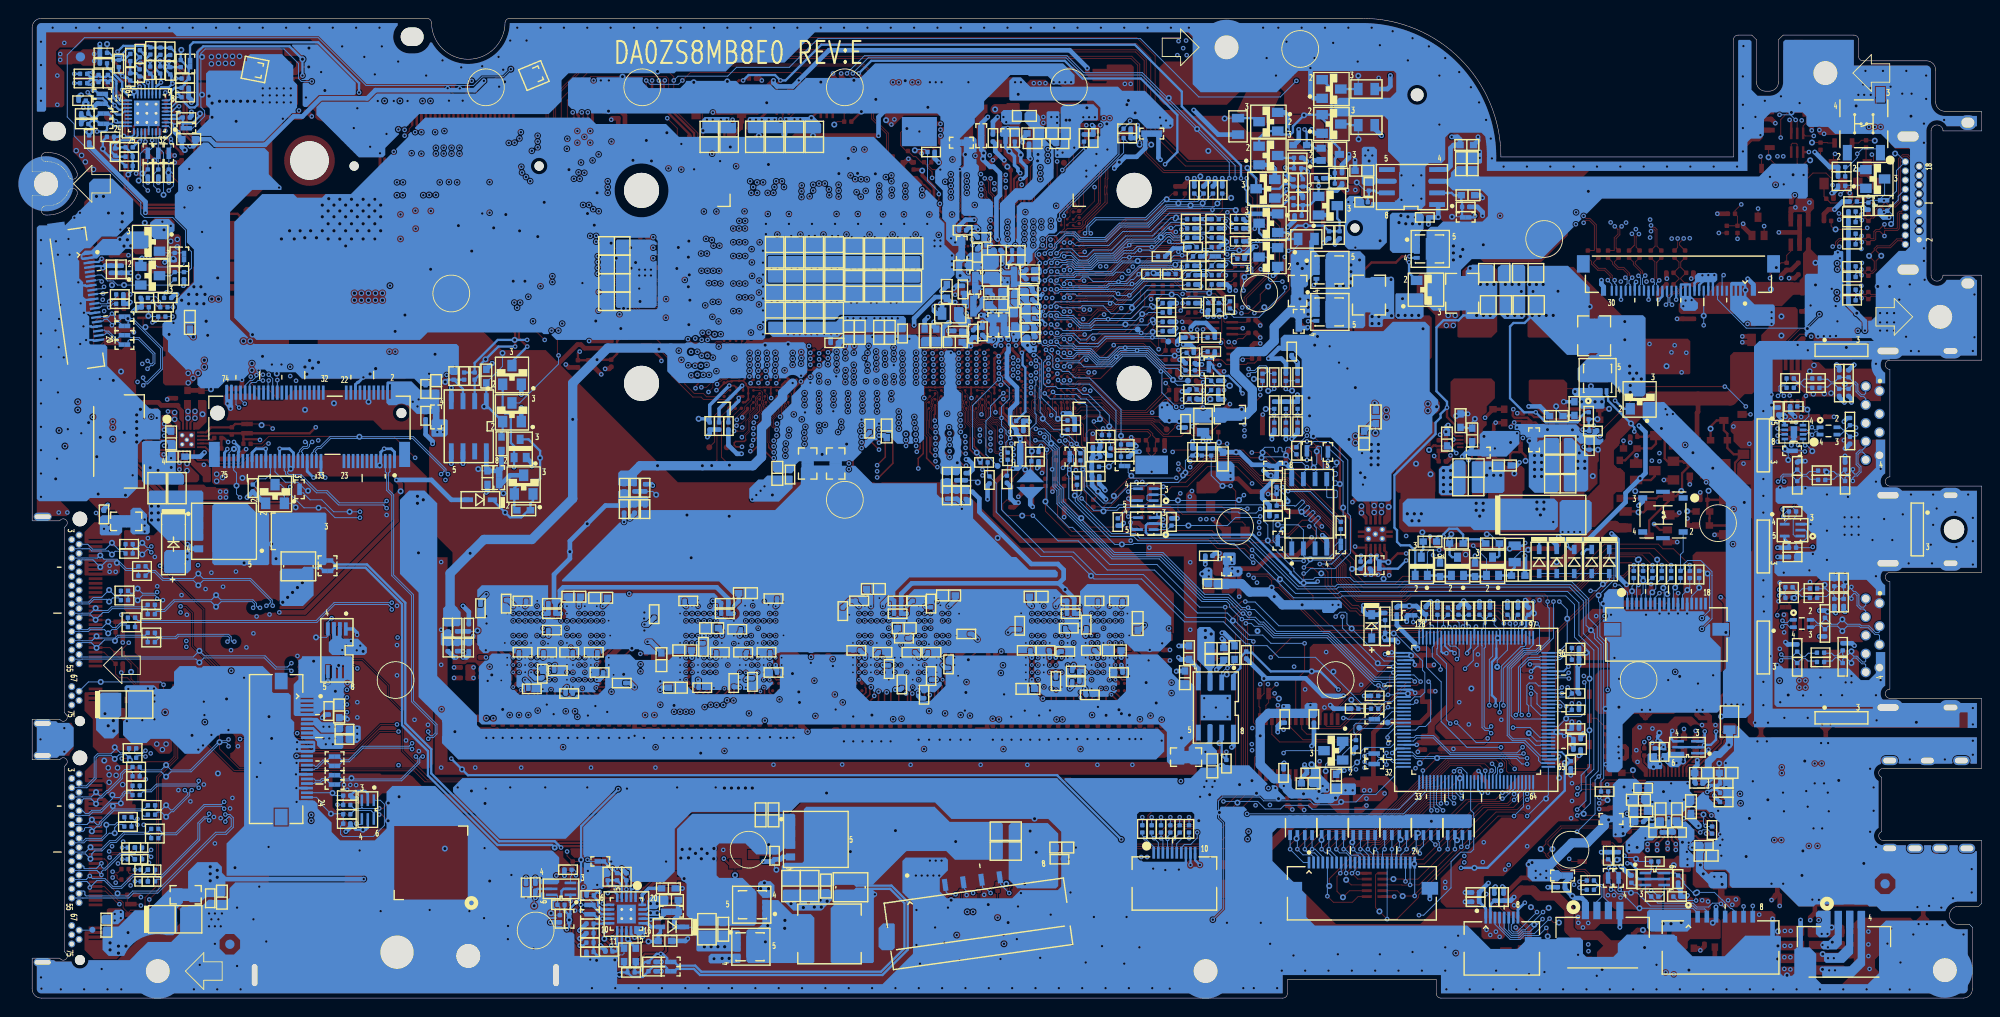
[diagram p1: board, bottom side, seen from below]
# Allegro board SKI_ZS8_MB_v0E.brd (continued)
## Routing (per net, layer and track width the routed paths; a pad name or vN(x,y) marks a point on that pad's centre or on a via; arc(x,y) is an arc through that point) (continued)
N16824795: length 5.1
  TOP w0.102: v1(109.73,11.43) 109.48,11.68 PC68.1 PR70.1 108.08,10.17 v2(108.08,10.18)
  BOTTOM w0.102: PJ2.4 110.69,11.9 110.42,11.63 109.93,11.63 v1(109.73,11.43)
N16828407: length 13.5
  TOP w0.254: v1(28.91,29.01) 28.85,29.06 28.52,29.06 28.34,29.25 v2(28.34,30.65) 28.34,32.85 28.04,33.15 Q15.3 27.18,34.95 27.04,35.09 R214.1
  BOTTOM w0.254: v1(28.91,29.01) 28.91,28.12 29.46,27.56 29.97,27.56 30.23,27.3 Q23.2 Q23.5
N16828426: length 28.8
  TOP w0.102: R295.1 43.59,23.24 v1(43.97,22.86) ; v1(33.34,35.5) v2(32.85,35.01) 32.77,34.92 32.77,32.39 32.49,32.12 R226.1 C103.2 30.17,32.12 30.17,32.13 Q15.2
  IN1 w0.114: v1(43.97,22.86) 43.97,25.02 44.23,25.28 44.23,28.93 37.66,35.5 v1(33.34,35.5)
N16828811: length 3.4
  TOP w0.102: v1(34.61,27.32) 34.1,26.81 33.77,26.81 C123.1
  TOP w0.203: C123.1 33.66,25.17 33.71,25.12 U16.19
N16832743: length 2.3
  TOP w0.102: TP19.1 38.15,18.36 U16.48
N16857822: length 2.7
  TOP w0.102: PR63.2 131.97,15.65 v2(131.97,16.7)
  TOP w0.254: PQ14.3 132.6,15.62 132.59,15.63 PR63.2
N16860490: length 2.5
  TOP w0.102: v2(18.46,93.11) 17.53,93.11 R29.2 16.77,93.1 16.73,93.06 D3.1
N16860618: length 2.6
  TOP w0.102: D2.1 13.37,93.06 13.08,93.35 R27.2 11.67,93.35 v2(11.62,93.31)
N16870904: length 8
  TOP w0.254: PQ16.3 151.84,10.49 152.02,10.67 152.65,10.67 153.66,9.66 v2(153.66,8.5) 153.54,8.38 153.54,7.87 153.23,7.56 153.23,6.41 v1(152.53,5.71)
  BOTTOM w0.254: v1(152.53,5.71) 152.13,5.71 PR169.1
N16876480: length 2.7
  TOP w0.102: v2(67.1,56.66) 66.72,56.66 PC62.1
  TOP w0.508: PC62.1 PR51.1
N16876574: length 2.6
  BOTTOM w0.102: v2(65.95,61.51) 65.95,62.47 PR136.2
  BOTTOM w0.508: PR136.2 66.37,62.51 PC95.1
N16911747: length 12.1
  TOP w0.102: v1(81.72,55.74) 81.15,55.17 Q14.3 81.86,52.7 82.69,53.53 Q13.2
  BOTTOM w0.102: v1(81.72,55.74) v2(82.59,55.74) 82.66,55.74 83.82,56.9 R450.2 C248.2
N16928869: length 15.6
  IN1 w0.508: v1(157.35,10.92) 157.2,10.77 v1(154.51,10.77) 154.33,10.77 153.8,11.3 151.76,11.3 151.38,10.92 149.99,10.92 v1(149.48,11.43)
  BOTTOM w0.102: v1(157.35,10.92) 157.48,10.79 v2(157.48,10.05)
  BOTTOM w0.254: PQ37.2 154.28,11.89 154.51,11.66 v1(154.51,10.77) ; PU11.5 148.45,11.29 148.72,11.56 149.35,11.56 v1(149.48,11.43) ; PR160.1 157.14,11.89 PQ37.5
  BOTTOM w0.508: v1(157.35,10.92) PR160.1
N16928948: length 3.9
  BOTTOM w0.102: v2(155.64,9.24) 155.43,9.03 PR166.1 154.69,9.9 PR161.2 154.95,11.13 155.05,11.24 PQ37.6
N16991480: length 5.2
  BOTTOM w0.102: v1(140.05,7.61) 140.15,7.71 141.08,7.71 PD8.1
  BOTTOM w0.508: PD8.1 141.99,7.75 142.24,8 142.24,8.54 141.81,8.97 PR163.1 PC129.2
N17028529: length 102.7
  TOP w0.254: v1(160.32,7.85) 157.07,7.85 151.76,2.54 v2(148.2,2.54) 147.7,2.54 145.42,4.83 143.46,4.83 143.13,5.16 PR74.2 144.25,6.25 144.4,6.1 146.94,6.1 147.57,6.72 PR73.1 ; v1(205.15,52.8) 204.61,52.26 PD1.1
  IN1 w0.254: v1(160.32,7.85) 162.83,10.35 178.57,10.35 186.51,18.3 186.51,26.05 196.43,35.97 198.39,35.97 200.68,38.25 200.68,45.19 205.15,49.66 v1(205.15,52.8)
N17036761: length 3.1
  TOP w0.102: v2(142.13,7.79) 142.19,7.72 PR74.1
  TOP w0.254: PR74.1 143.13,8.38 142.75,8.76 PR67.1
N17045614: length 5.2
  BOTTOM w0.102: PR162.2 151.02,10.28 151.4,10.66 151.98,10.66 152.29,10.96 152.29,11.95 v1(152.14,12.1)
  BOTTOM w0.279: PR162.2 151.02,9.97 150.19,9.14 PU11.8
N17046311: length 2
  BOTTOM w0.279: PR164.2 150.54,8.64 v1(150.05,8.64) PU11.9
N17109474: length 2.2
  BOTTOM w0.102: v2(163.64,39.99) 163.72,39.92 R520.2
  BOTTOM w0.508: R520.2 C304.2
N17109500: length 2.5
  BOTTOM w0.102: v2(144.21,54.78) 144.58,55.14 R471.2
  BOTTOM w0.508: R471.2 C260.2
N17132574: length 2.4
  BOTTOM w0.102: v2(109.21,56.12) 109.44,56.35 R467.2
  BOTTOM w0.508: R467.2 C256.2
N17177387: length 2.4
  BOTTOM w0.279: PR171.2 146.94,5.95 146.94,6.07 v2(147.28,6.42) 147.45,6.58 PU11.13
N17177693: length 4
  BOTTOM w0.102: v2(148.71,4.16) 148.16,4.7 147.86,4.7 147.7,4.86 PR172.2
  BOTTOM w0.279: PR172.2 147.95,5.68 PU11.12
N17295384: length 1.9
  BOTTOM w0.102: U23.19 64.25,30.37 TP25.1
N17295398: length 5.2
  BOTTOM w0.102: TP26.1 67.63,29.35 64.51,29.35 63.89,29.97 U23.20
N17388651: length 22.4
  TOP w0.254: U4.10 152.65,96 152.78,96.14 152.78,96.65 152.4,97.03
  TOP w0.279: 151.13,97.03 151.15,97.01 U4.13 ; R15.1 148.34,97.16 148.36,97.18 U1.4 ; 148.78,91.38 149.23,91.82 149.23,92.2 150,92.98 U4.1 ; U4.4 152.15,91.44 151.76,91.06 151.76,90.8 151.38,90.42 151.26,90.42
  TOP w0.508: 152.4,97.03 150.5,97.03 150,96.53 v2(149.39,96.53) R15.1 148.09,96.53 147.6,96.04 147.6,92.55 149.73,90.42 151.26,90.42
N19105029: length 2.2
  TOP w0.102: v3(179.92,34.39) 179.96,34.43 R213.1
  BOTTOM w0.102: v3(179.92,34.39) U22.5
N19105147: length 4.3
  TOP w0.102: R202.2 179.96,40.9 v1(179.52,41.34)
  BOTTOM w0.102: v2(181.22,39.26) 180.08,39.26 179.92,39.42 U22.4 179.92,40.94 v1(179.52,41.34)
N19105233: length 5.3
  TOP w0.102: v2(18.96,72.86) 19.73,72.86 21.4,71.19 R133.2 21.32,70.79 U8.5
N19105388: length 3.4
  TOP w0.102: U8.4 21.32,63.9 21.9,63.32 21.9,63.03 v1(22.23,62.69) R168.2
N19105409: length 3.4
  TOP w0.102: v2(21.05,32.98) 21.2,33.14 R220.2 21.2,34.43 20.41,35.22 U10.4
N19105455: length 3.3
  TOP w0.102: U10.5 20.41,42 R200.1 20.95,42.99 20.94,42.99 v2(20.39,43.55)
N19177528: length 14.7
  TOP w0.102: Q12.3 207.82,64.9 207.18,65.54 R158.2 205.4,65.75 205.4,73.49 204.94,73.95 CN3.4 v2(201.69,73.95)
N19177538: length 2.8
  TOP w0.102: Q12.2 206.2,62.86 v2(205.96,62.63) 205.81,62.48 R165.2
N19179160: length 3.3
  BOTTOM w0.102: R433.1 19.3,64.39 v2(18.96,64.04) 18.8,63.88 18.8,63.32 19.43,62.69 U17.4
N19426582: length 39.8
  TOP w0.203: 57.33,62.41 57.33,61.72 57.16,61.56 PU3.7
  TOP w0.254: v1(58.17,64.26) 58.17,63.25 57.33,62.41
  BOTTOM w0.254: v4(54.94,74.3) 56.39,74.3 56.92,73.76 58.55,73.76 59.31,73 59.31,66.04 58.17,64.9 v1(58.17,64.26) 58.86,63.56 58.86,63.18 59.41,62.63 59.41,61.39 63.88,56.92 63.88,51.19 63.6,50.91 63.6,49.66 63.22,49.28 62.23,49.28 61.62,48.67 PD7.2
  vias: v2(55.64,79.42) v4(53.06,77.67) v4(53.47,74.3) v4(53.8,77.67) v4(54.2,74.3) v4(54.53,77.67)
N19432785: length 3.5
  BOTTOM w0.102: PR101.2 67.82,93.5 v2(67.78,93.46)
  BOTTOM w0.254: PR101.2 68.71,95 68.83,95.12 PQ19.3
N19432788: length 3.3
  BOTTOM w0.102: v2(67.82,100.37) PR93.2
  BOTTOM w0.254: PR93.2 PQ17.3
N19432899: length 3.9
  BOTTOM w0.102: PR102.2 82.32,95.76 v2(82.36,95.72)
  BOTTOM w0.254: PQ18.3 79,95.76 PR102.2
N19432905: length 6.3
  TOP w0.102: PR61.2 PR60.1 82.3,36.14 v1(82.06,35.91) 82.06,35.3 v2(82.13,35.22)
  BOTTOM w0.102: PC115.2 81.28,36.53 81.9,35.91 v1(82.06,35.91) 82.2,35.91 82.68,35.43 PU10.2
N19432917: length 5.8
  TOP w0.102: PR62.2 82.92,26.8 v2(82.92,27.75)
  TOP w0.254: PR62.2 v1(82.17,26.8)
  BOTTOM w0.254: v1(82.17,26.8) PR153.1 82.68,26.42 PU10.7
N19433355: length 2.7
  BOTTOM w0.102: R780.2 C714.1 198.07,81.1 Q19.2
N19439774: length 23.4
  TOP w0.203: PU2.7 48.12,63.23
  TOP w0.254: 48.12,63.23 48.7,63.23 PC43.2 49.01,63.75 v1(48.51,63.75)
  BOTTOM w0.254: PR137.1 43.1,63.76 43.71,63.15 43.71,62.92 43.97,62.66 47.42,62.66 v1(48.51,63.75) 49.78,63.75 51.31,65.28 51.31,73.09 50.93,73.47 49.72,73.47 v4(48.89,74.3)
  vias: v2(46.09,76.93) v2(48.81,76.9) v4(46.61,74.3) v4(47.37,74.3) v4(47.7,77.67) v4(48.13,74.3) v4(48.44,77.67) v4(49.17,77.67)
N19442536: length 6.3
  BOTTOM w0.102: v2(57.62,85.03) 56.59,85.03 PR126.2
  BOTTOM w0.254: PR126.2 PR124.1 56.52,86.61 56.62,86.71 PC86.2 57.4,87.38 57.66,87.63 PU8.2
N19442558: length 5.1
  BOTTOM w0.102: PR120.2 67.1,87.88 v2(67.99,88.76)
  BOTTOM w0.254: PU8.7 65.79,87.63 66.04,87.88 PR120.2 66.67,87.24 66.79,87.12 PR123.1
N19866545: length 5.1
  BOTTOM w0.102: CN2.13 9.08,87.25 9.08,86.88 C177.1 10.13,85.67 9.59,85.13 9.59,84.5 v2(9.85,84.24)
N19866548: length 17.7
  TOP w0.102: v1(12.45,83.82) 12.61,83.66 v2(15.89,83.66) 16.01,83.66 16.37,84.02 C27.1
  IN3 w0.102: v1(12.45,83.82) 11.68,83.82 9.3,81.43 8.01,81.43 8.01,81.43 7.6,81.84 7.6,87.72 CN2.14
N19944352: length 6.4
  BOTTOM w0.254: PR121.1 73.85,85.79 73.97,85.67 PR125.2 ; PR121.1 PR122.2 ; PR121.1 73.09,86.29 PQ23.2 v1(72.14,88.38) 72.14,88.94 PC84.2
N20615974: length 13.1
  TOP w0.254: PR30.2 v2(29.49,61.97) 29.49,62.2 28.83,62.86 PQ3.3 28.04,61.8 27.66,61.42 PR29.1 27.66,59.87 26.97,59.18 PQ7.2 26.82,58.27 26.82,56.16 PQ10.2
N20616004: length 9.5
  TOP w0.102: v2(29.71,55.21) 29.84,55.08 PC64.2
  TOP w0.254: PQ12.2 PR55.2 29.62,52.2 29.59,52.23 PR53.2 29.84,53.2 PC64.2 PQ10.3
N20616028: length 4
  TOP w0.102: v2(31.41,59.35) 30.87,58.81 PR46.2
  TOP w0.254: PQ7.3 28.57,58.17 29.22,58.81 PR46.2
N21454878: length 4
  TOP w0.102: C713.1 36.52,5.35 v2(36.67,5.5)
  TOP w0.508: R781.2 C713.1 36.02,4.89 Q53.2
N21605343: length 3.4
  TOP w0.508: Q53.1 36.36,6.92 v2(36.85,7.41) 37.44,7.41 R325.2
N21733433: length 3.9
  TOP w0.102: R783.2 44.87,5.26 Q54.3 45.53,4.16 Q55.2
N21733447: length 4.8
  TOP w0.102: Q55.3 49.37,3.5 R786.1 R785.2 50.64,5.35 50.97,5.02 Q56.2
N21733477: length 2.5
  TOP w0.102: Q56.3 54.68,4 55.57,3.11 R784.2
N47973729: length 6.8
  BOTTOM w0.102: v2(163.57,57.57) 163.37,57.38 PC104.2
  BOTTOM w0.508: PR141.1 161.04,57.63 PR143.2 PC104.2 162.69,57.51 PU9.8
N47973733: length 7.1
  BOTTOM w0.254: PD2.1 v2(160.64,52.85) 160.12,52.32 158.88,52.32 158.12,53.09 PR144.1 157.89,53.85 157.61,54.13 PQ34.1
N47973739: length 4.2
  BOTTOM w0.102: v2(160.82,54.93) 161.29,55.4 PR143.1
  BOTTOM w0.508: PQ34.3 160.1,56.9 161.09,55.91 PR143.1
N47973743: length 11.5
  BOTTOM w0.254: PR144.2 159.64,53.37 PQ34.2 159.64,55.5 159.26,55.88 157.48,55.88 156.83,56.53 v2(156.83,58.79) 156.83,59.55 158.09,60.81 PQ33.3
N47973784: length 10.7
  BOTTOM w0.102: PC92.2 162.69,66.98 160.92,68.75 v2(160.92,70.2)
  BOTTOM w0.254: PC92.2 PU9.1 162.69,64.52 PQ32.2 160.91,61.72 161.04,61.59 PR141.2
N47973813: length 22.3
  TOP w0.254: v1(158.23,70.91) 159.15,71.82 159.15,72.69 165.72,79.27 v2(165.72,84.06) 165.72,86.57 PR17.1
  BOTTOM w0.254: PQ29.3 159.89,69.25 v1(158.23,70.91)
N105883866: length 4.5
  TOP w0.102: v1(105.79,11.43) 105.79,11.94 105.28,12.45 PR65.2 104.13,12.45 v2(104.11,12.44)
  BOTTOM w0.102: v1(105.79,11.43) 106.71,12.35 106.71,12.36 PJ2.6
N106376146: length 4.3
  TOP w0.102: v2(106.12,12.44) 107.04,12.44 PR66.1 107.82,11.69 v1(107.82,11.43)
  BOTTOM w0.102: v1(107.82,11.43) 108.27,11.88 108.53,11.88 108.69,12.04 PJ2.5
N106389743: length 17.5
  IN3 w0.254: v1(75.5,83.24) 75.27,83.24 74.87,83.63 74.87,87.26 v1(75.63,88.03)
  BOTTOM w0.254: PQ23.3 70.1,84.84 69.85,84.58 PR128.1 PR129.2 71.61,84.06 v2(73.52,84.06) 74.44,84.06 75.27,83.24 v1(75.5,83.24) 75.58,83.31 PQ24.2 ; v1(75.63,88.03) 75.63,87.82 76.39,87.06 PQ22.2
N106389874: length 7.6
  BOTTOM w0.102: v1(75.4,81.33) 74.97,81.33 74.74,81.56 74.73,81.56 74.37,81.92 PR130.2
  BOTTOM w0.254: PQ24.3 78.61,83.31 77.85,82.55 75.32,82.55 75.25,82.62 PR130.2
N106400087: length 5.6
  BOTTOM w0.178: 197.1,95.69 PU7.3
  BOTTOM w0.254: 197.1,95.69 196.09,95.69 195.95,95.83 PR99.1 195.72,95.14 ; 195.72,95.14 195.67,95.19 194.68,95.19 193.84,96.03 v2(193.84,96.26) ; 195.72,95.14 PR103.2
N106400399: length 1.2
  TOP w0.102: PC4.2 182.4,102.97 v2(181.98,103.39)
N106400425: length 5.6
  TOP w0.254: PR14.1 189.75,85.35 189.48,85.09 PL1.4
N106400429: length 5.6
  TOP w0.254: PL1.3 189.48,87.25 190,86.73 PR12.1
N106400442: length 2.2
  TOP w0.102: v1(195.53,86.05) 194.69,86.05
  TOP w0.254: PR13.2 PR15.2
N106400512: length 2.3
  TOP w0.508: PR10.2 193.52,95.15 PC10.1 v2(192.52,95.86)
N106400579: length 4.8
  BOTTOM w0.254: PR112.2 202.6,91.21 203.35,91.21 204.41,92.27 v2(204.41,92.42) 204.41,93.29 PC77.2
N106400606: length 7.2
  BOTTOM w0.102: PR79.2 203.95,102.87 v2(203.95,103.83)
  BOTTOM w0.203: PR88.1 200.91,101.58 200.91,101.85 PR80.1 200.95,102.95 200.95,103.09 201.14,103.28 201.78,103.28 202.5,102.56 202.61,102.56 202.63,102.54 203.01,102.54 203.02,102.56 203.39,102.56 203.71,102.87 PR79.2
N108094032: length 1.9
  TOP w0.203: PU3.11 53.27,61.16 52.96,61.47 PC45.2
N108094152: length 2.8
  BOTTOM w0.102: PC110.1 60.76,50.6 v2(60.85,50.69)
  BOTTOM w0.254: PC110.1 60.76,48.84 60.96,48.64 PD7.3
N108094154: length 6.6
  BOTTOM w0.102: v1(59.02,48.76) 60.06,48.76 60.3,48.52 PD7.1
  BOTTOM w0.254: PD6.2 57.81,45.87 PC112.2 59.05,46 PD7.1
N108094162: length 3.3
  BOTTOM w0.102: PC109.1 57.89,50.3 v2(57.7,50.49)
  BOTTOM w0.254: PC109.1 57.89,48.26 57.61,47.98 PD6.3
N108094178: length 2.4
  BOTTOM w0.102: v2(55.13,63.03) 55.42,62.74 PC94.1
  BOTTOM w0.254: PR138.2 56.13,62.1 56.06,62.03 PC94.1
N108094262: length 3.9
  BOTTOM w0.102: PC108.1 53.48,50.49 v2(53.84,50.49)
  BOTTOM w0.254: PC108.1 52.48,48.13 52.63,47.98 PD5.3
N108094270: length 6.4
  BOTTOM w0.102: v1(55.31,49.24) 53.87,47.8 PD5.2
  BOTTOM w0.254: PD5.2 54,45.87 PC111.2 55.25,46 PD6.1
N108094286: length 5.3
  BOTTOM w0.102: v2(49.34,48.78) 49.52,48.61 50.13,48.61 50.8,47.93 PR145.2
  BOTTOM w0.254: PR145.2 50.8,46.86 51.16,46.51 PC113.2 51.66,45.97 51.69,46 PD5.1
N108094465: length 2.6
  BOTTOM w0.102: v2(46.29,64.4) 46.29,64.1 PC93.1
  BOTTOM w0.254: PR135.2 44.83,63.42 44.91,63.35 PC93.1
N108099073: length 23
  TOP w0.254: PQ11.2 35.15,54.61 35.38,54.38 PR52.2 ; PQ11.2 34.04,54.1 36.17,51.97 PQ13.3 ; PQ11.2 33.25,54.61 v2(32.68,55.18) 32.59,55.28 32.59,57.12 31.75,57.96 PR48.1 32.38,58.27 32.54,58.42 PQ9.2 34.18,58.42 34.48,58.72 34.48,61.89 34.14,62.23 PQ6.2
N108099274: length 3
  TOP w0.254: PQ11.3 36.79,52.87 v2(37.33,52.87) 37.42,52.97 PR54.2
N108099282: length 4.1
  TOP w0.102: PR50.2 37.59,55.25 v2(37.68,55.16)
  TOP w0.254: PQ9.3 35.56,56.8 35.98,56.38 PR50.2
N108100988: length 2.6
  TOP w0.102: v2(49.19,60.65) 49.19,61.52 PR26.1
  TOP w0.203: PU2.3 48.01,61.63
  TOP w0.254: 48.01,61.63 48.64,61.63 48.68,61.59 PR26.1

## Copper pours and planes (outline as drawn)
3VPCU_AGND on BOTTOM (solid shape): 54.61,61.34 54.61,59.18 54.36,58.93 51.69,58.93 50.29,60.33 50.29,61.59 50.42,61.72 54.23,61.72
3VPCU_VIN on TOP (solid shape): 54.84,60.05 54.84,58.75 55.45,58.14 55.45,54.74 55.4,54.69 54.05,54.69 53.62,55.12 49.94,55.12 49.73,55.32 49.73,57.61 50.04,57.91 51.69,57.91 51.82,58.04 51.82,58.67 51.94,58.8 52.65,58.8 53.59,59.74 54.31,59.74 54.66,60.1 54.79,60.1
3VPCU_VIN on BOTTOM (solid shape): 55.47,58.32 55.47,55.07 55.37,54.97 52.12,54.97 51.92,55.17 51.92,58.22 52.12,58.42 55.37,58.42
5VPCU_AGND on BOTTOM (solid shape): 50.8,62.36 50.8,61.87 50.79,61.84 50.75,61.82 50.38,61.82 50.19,61.64 50.19,61.38 50.14,61.3 50.05,61.29 49.74,61.27 49.56,61.03 49.53,61 47.71,61 47.62,61.09 44.45,61.09 43.69,60.33 43.42,60.33 43.41,60.33 43.19,60.34 43,60.22 42.99,60.2 42.96,60.2 41.53,60.2 41.15,60.58 41.15,60.8 41.2,60.89 41.31,60.88 41.86,61.02 41.58,61.52 41.58,61.9 41.72,62.04 41.95,62.04 42.1,61.96 42.28,61.96 42.33,61.95 42.34,61.9 42.34,61.87 42.34,61.57 42.4,61.43 42.54,61.37 42.82,61.37 42.92,61.4 42.99,61.47 43,61.48 43.02,61.49 43.36,61.49 43.37,61.5 43.67,61.63 43.74,61.95 43.74,62.06 44.12,62.43 47.52,62.43 47.57,62.48 50.67,62.48
5VPCU_VIN on TOP (solid shape): 45.6,61.72 45.64,61.71 45.65,61.67 45.65,60.64 45.67,60.64 45.71,60.62 45.72,60.59 45.72,60.58 45.97,60.33 45.97,56.9 46.23,56.64 46.86,56.64 47.12,56.39 47.12,55.25 46.99,55.12 42.67,55.12 41.78,56.01 41.78,58.55 42.16,58.93 42.8,58.93 43.18,59.31 43.18,59.44 43.39,59.66 43.41,59.66 43.63,60.06 43.28,60.35 43.21,60.38 43.18,60.45 43.18,60.58 43.5,60.89 43.58,60.92 43.65,60.88 44.11,60.77 44.27,61.22 44.27,61.24 44.29,61.27 44.43,61.42 45.08,61.42 45.08,61.67 45.14,61.72
5VPCU_VIN on BOTTOM (solid shape): 45.47,60.83 45.47,55.25 45.34,55.12 43.05,55.12 42.8,55.37 42.8,59.18 43.18,59.56 43.43,59.56 43.69,59.82 43.69,60.07 44.58,60.96 45.34,60.96
51211V_DRVH on TOP (solid shape): 61.14,64.9 61.14,63.68 61.09,63.63 59.29,63.63 58.94,63.97 58.94,64.81 59.16,65.02 61.01,65.02
51211V_DRVH on TOP (solid shape): 65.6,53.73 65.6,51.56 65.59,51.55 65.34,51.55 65.33,51.56 65.33,52.4 64.98,52.75 64.98,53.73 65.15,53.9 65.43,53.9
51211V_DRVH on IN1 (solid shape): 60.83,64.77 60.83,63.25 60.71,63.12 60.07,63.12 59.82,63.37 59.82,64.9 59.94,65.02 60.58,65.02
51211V_DRVH on IN1 (solid shape): 65.58,54.15 65.58,52.73 65.38,52.53 64.87,52.53 64.77,52.63 64.77,54.15 64.87,54.25 65.48,54.25
51211V_DRVL on TOP (solid shape): 69.03,61.28 69.03,60.21 68.91,60.1 68.33,60.1 68.33,60.1 67.56,60.1 67.23,60.43 67.23,61.39 67.31,61.47 68.84,61.47
51211V_DRVL on TOP (solid shape): 67.79,53.67 67.79,52.68 67.59,52.48 67.51,52.48 67.1,52.06 67.1,51.57 67.08,51.55 66.84,51.55 66.83,51.57 66.83,52.4 67.16,52.73 67.16,53.67 67.34,53.85 67.61,53.85
51211V_DRVL on IN1 (solid shape): 68.71,61.47 68.71,59.94 68.58,59.82 67.69,59.82 67.56,59.94 67.56,61.47 67.69,61.59 68.58,61.59
51211V_DRVL on IN1 (solid shape): 67.94,54.41 67.94,52.5 67.92,52.48 67.03,52.48 66.93,52.58 66.93,54.43 67.03,54.53 67.82,54.53
51211V_SW on TOP (solid shape): 68.33,66.67 68.33,62.23 68.12,62.02 64.6,62.02 64.26,62.36 64.26,62.86 63.5,63.63 61.39,63.63 61.36,63.66 61.36,64.66 61.59,64.9 61.59,67.18 61.72,67.31 67.69,67.31
51211V_SW on TOP (solid shape): 66.45,54.89 66.45,53.85 66.4,53.8 66.4,52.73 66.1,52.44 66.1,51.56 66.09,51.55 65.83,51.55 65.83,51.56 65.83,52.4 65.74,52.49 65.74,53.75 65.66,53.82 65.66,54.89 65.71,54.94 66.4,54.94
51211V_SW on IN1 (solid shape): 65.15,64.16 65.15,62.64 65.02,62.51 64.26,62.51 64.14,62.64 64.14,64.16 64.26,64.29 65.02,64.29
51211V_SW on IN1 (solid shape): 66.8,54.1 66.8,52.73 66.6,52.53 65.89,52.53 65.79,52.63 65.79,54.15 65.89,54.25 66.65,54.25
51211V_VBST on TOP (solid shape): 65.02,54.91 65.02,54.1 64.85,53.92 64.85,52.68 65.1,52.43 65.1,51.61 65.05,51.56 64.69,51.56 64.26,51.99 64.26,54.91 64.34,54.99 64.95,54.99
+1.2VSUS_SRC on TOP (solid shape): 181.04,74.87 181.04,70.8 180.34,70.1 171.2,70.1 170.94,69.85 170.94,68.83 170.81,68.71 169.55,68.71 169.29,68.96 169.29,74.68 169.42,74.8 172.08,74.8 172.97,73.91 176.78,73.91 177.29,74.42 177.29,74.8 177.67,75.18 180.72,75.18
+1.2VSUS_SRC on TOP (solid shape): 194.98,59.64 194.98,58.48 194.84,58.34 194.84,58.06 193.55,56.77 193.55,56.26 193.42,56.13 192.79,56.13 192.66,56.26 192.66,57.66 193.29,58.29 194.18,58.29 194.65,58.76 194.68,58.76 194.68,58.79 194.77,58.88 194.77,59.64 194.78,59.65 194.97,59.65
+1V2_SUS on TOP (solid shape): outline of 6648 points within 87.88,35.06 168.91,73.02
+1V2_SUS on BOTTOM (solid shape): outline of 13054 points within 88.16,32.79 163.68,57.96
+1V2_SUS_VDDQ on BOTTOM (solid shape): outline of 4257 points within 115.06,57.13 131.53,72.2
+1V05 on TOP (solid shape): 114.47,99.91 114.47,98.34 114.17,98.04 110.36,98.04 110.24,98.17 110.24,100.08 110.36,100.2 114.17,100.2
+1V5 on TOP (solid shape): 28.7,11.1 28.7,10.36 28.22,9.88 26.57,9.88 26.23,10.23 26.23,10.86 26.52,11.15 28.65,11.15
+1V05 on TOP (solid shape): 95.19,101.54 95.19,99.66 95.28,99.57 97.03,99.57 98.81,101.35 100.84,101.35 101.22,100.97 101.22,99.57 101.09,99.44 100.33,99.44 99.69,98.81 99.69,98.17 99.44,97.92 92.58,97.92 92.25,98.25 92.25,101.35 92.5,101.6 95.12,101.6
+1V05 on BOTTOM (solid shape): 109.03,74.46 109.03,74.21 108.88,74.06 108.65,74.06 108.12,73.52 106.09,73.52 105.98,73.62 105.98,74.39 106.01,74.41 108.24,74.41 108.42,74.59 108.91,74.59
+1V05 on BOTTOM (solid shape): 75.18,76.45 75.18,75.47 75.3,75.35 75.3,74.25 75.14,74.08 74.84,74.08 74.68,73.91 73.79,73.91 73.66,74.04 72.86,74.04 72.75,74.16 72.02,74.16 72.01,74.17 72.01,76.33 72.26,76.58 75.06,76.58
+1V5 on BOTTOM (solid shape): 67.44,92.46 67.44,88.65 67.18,88.39 66.17,88.39 65.91,88.65 63.75,88.65 63.63,88.77 63.63,89.03 63.75,89.15 65.66,89.15 65.79,89.28 65.79,92.33 66.11,92.65 67.25,92.65
+1V05 on BOTTOM (solid shape): outline of 718 points within 98.68,81.85 153.8,101.73
+1V05 on IN2 (solid shape): 112.46,82.95 112.46,81.7 112.08,81.32 111.32,81.32 110.85,81.79 110.85,83.11 111.06,83.33 112.08,83.33
+1V05 on IN2 (solid shape): 199.9,90.55 199.9,88.65 199.77,88.52 196.47,88.52 195.45,89.53 195.45,91.57 195.83,91.95 198.5,91.95
+1V5 on IN2 (solid shape): 28.13,10.73 28.13,9.08 27.88,8.83 26.61,8.83 26.36,9.08 26.36,10.73 26.61,10.99 27.88,10.99
+1V5 on IN2 (solid shape): 36.39,59.76 36.39,58.23 36.01,57.85 34.61,57.85 33.98,58.49 33.98,59.38 34.48,59.88 36.26,59.88
+1V05 on IN2 (solid shape): 109.92,75.91 109.92,74.54 109.19,73.81 109.11,73.78 109.04,73.83 108.69,73.99 108.39,73.76 108.35,73.69 108.34,73.62 108.33,73.57 107.91,73.57 107.51,73.98 107.51,74.42 107.58,74.46 107.61,74.49 107.68,74.52 107.75,74.49 108.23,74.49 108.3,74.98 108.3,75.43 108.91,76.04 109.79,76.04
+1V05 on IN2 (solid shape): outline of 854 points within 72.39,74.04 94.23,99.82
+1V5 on IN3 (solid shape): 67.31,92.71 67.31,91.31 67.18,91.19 65.66,91.19 65.53,91.31 65.53,92.71 65.66,92.84 67.18,92.84
+1V5 on IN3 (solid shape): 36.39,59.76 36.39,58.23 36.01,57.85 33.98,57.85 33.72,58.11 33.72,60.01 34.1,60.39 35.75,60.39
+1V5_ADO_AVDD2 on TOP (solid shape): 29.34,13.46 29.34,11.94 29.21,11.81 27.81,11.81 27.69,11.94 27.69,13.46 27.94,13.72 29.08,13.72
+1V5_ADO_AVDD2 on BOTTOM (solid shape): 29.72,13.46 29.72,12.19 29.46,11.94 27.81,11.94 27.69,12.06 27.69,13.46 27.94,13.72 29.46,13.72
+1V05_AIDLE on TOP (solid shape): 95.76,97.16 95.76,95.63 95.76,95.47 95.5,95.21 95.5,95.07 95.39,94.96 95.14,94.96 94.59,95.5 93.73,96.37 93.73,97.28 93.85,97.41 95.5,97.41
+1V05_AIDLE on BOTTOM (solid shape): 103.44,79.44 103.44,78.81 103.32,78.68 102.39,78.68 102.26,78.81 102.26,79.4 102.43,79.57 103.32,79.57
+1V05_AIDLE on IN1 (solid shape): outline of 347 points within 94.92,78.05 102.92,80.57
+1V05_AIDLE on IN2 (solid shape): 96.44,80.64 96.44,79.68 96.11,79.35 94.95,79.35 94.59,79.71 94.59,80.77 94.69,80.87 96.22,80.87
+1V05_AIDLE on IN2 (solid shape): 95.76,96.01 95.76,95.38 95.69,95.31 95.62,95.26 95.57,95.19 94.81,94.43 94.27,94.43 94.27,94.45 93.85,94.87 93.85,96.01 94.11,96.27 95.5,96.27
+1V05_APLLOPI on TOP (solid shape): 119.33,97.16 119.33,95.43 118.72,94.82 118.49,94.82 117.27,96.04 112.85,96.04 112.67,96.22 112.67,97.33 112.88,97.54 118.95,97.54
+1V05_APLLOPI on TOP (solid shape): 110.4,76.71 110.48,76.67 110.5,76.59 110.6,76.33 110.87,76.26 110.96,76.24 111,76.16 111,76.11 110.96,76.03 110.87,76.01 110.5,75.73 110.87,75.45 110.96,75.43 111,75.35 111,75.31 110.89,75.21 110.87,75.2 110.86,75.2 110.61,75.15 110.5,74.93 110.5,74.91 110.48,74.89 109.89,74.89 109.74,75.04 109.74,75.06 109.63,75.17 109.6,75.22 109.6,75.56 109.66,75.73 109.6,75.9 109.6,76.24 109.63,76.29 109.66,76.34 109.74,76.4 109.74,76.47 109.94,76.66 109.99,76.68 110.04,76.71
+1V05_APLLOPI on BOTTOM (solid shape): 110.96,76.77 110.96,75.46 110.56,75.06 110.19,75.06 110.18,75.07 110.18,76.85 110.3,76.98 110.76,76.98
+1V05_APLLOPI on IN2 (solid shape): 119,95.89 119,94.49 118.74,94.23 118.11,94.23 117.86,94.49 117.86,96.01 117.98,96.14 118.74,96.14
+1V05_APLLOPI on IN2 (solid shape): outline of 749 points within 110.14,73.9 115.44,88.77
+1V05_ASATA3PLL on TOP (solid shape): 106.1,97.36 106.1,96.32 105.74,95.96 105.74,95 105.82,94.92 106.25,94.92 106.43,94.74 106.43,91.82 105.41,90.8 104.77,90.8 104.65,90.93 104.65,92.58 104.65,92.59 104.67,92.71 104.65,92.83 104.65,92.84 104.65,92.96 104.67,92.98 104.67,93.28 104.65,93.3 104.65,97.31 104.75,97.41 106.05,97.41
+1V05_ASATA3PLL on BOTTOM (solid shape): 106.81,94.61 106.81,93.85 106.68,93.73 106.44,93.73 106.43,93.73 106.19,93.78 105.95,93.73 105.43,93.73 105.19,93.78 104.95,93.73 104.94,93.73 104.77,93.73 104.65,93.85 104.65,94.74 104.77,94.87 106.55,94.87
+1V05_AUSB3PLL on TOP (solid shape): 109.35,93.34 109.35,92.2 109.73,91.82 109.73,91.57 109.35,91.19 109.35,90.17 109.22,90.04 108.46,90.04 108.33,90.17 108.33,93.34 108.46,93.47 109.22,93.47
+1V05_AXCK_DCB on TOP (solid shape): 109.17,81.89 109.17,81.76 109.09,81.69 109.09,81.41 109.19,81.31 109.19,81.15 108.97,80.92 108.79,80.92 108.25,81.46 108.25,81.66 108.71,82.12 108.94,82.12
+1V05_AXCK_DCB on TOP (solid shape): 103.63,97.31 103.63,96.39 102.89,95.65 102.83,95.65 102.71,95.52 102.71,94.96 102.58,94.83 102.02,94.83 101.6,95.26 101.6,95.96 101.55,96.01 101.55,96.02 101.47,96.14 101.35,96.22 101.34,96.22 101.3,96.27 100.03,96.27 99.86,96.09 99.84,96.08 99.84,95.47 99.57,95.2 98.98,95.2 98.17,96.01 98.17,97.31 98.32,97.46 103.48,97.46
+1V05_AXCK_DCB on IN2 (solid shape): outline of 459 points within 101.73,85.72 109.86,96.27
+1V05_AXCK_LCPLL on TOP (solid shape): 111.89,97.28 111.89,96.65 111.25,96.01 111.25,91.95 110.87,91.57 110.87,90.8 110.62,90.55 110.24,90.55 109.73,91.06 109.73,91.42 109.75,91.45 109.83,91.52 109.83,91.86 109.73,91.97 109.73,97.28 109.86,97.41 111.76,97.41
+1V05_CORE_PCH on TOP (solid shape): 97.94,97.28 97.94,95.63 97.76,95.45 96.01,95.45 95.86,95.61 95.86,97.18 96.04,97.36 97.87,97.36
+1V05_CORE_PCH on BOTTOM (solid shape): 111.27,72.79 111.27,72.1 111.02,71.86 110.28,71.86 110.08,72.05 110.08,72.54 110.4,72.86 111.19,72.86
+1V05_CORE_PCH on BOTTOM (solid shape): 100.2,96.9 100.2,92.71 100.31,92.6 100.69,92.6 100.84,92.46 100.84,91.57 100.71,91.44 99.19,91.44 98.04,92.58 98.04,95.12 97.66,95.5 96.27,95.5 96.14,95.63 96.14,96.77 96.65,97.28 99.82,97.28
+1V05_CORE_PCH on IN2 (solid shape): outline of 841 points within 98.93,78.74 109.22,94.49
+1V05_DCPSUS1 on BOTTOM (solid shape): 108.4,75.81 108.4,74.74 108.17,74.51 107.22,74.51 107.11,74.62 107.11,75.14 107.55,75.57 107.55,75.82 107.56,75.83 108.37,75.83
+1V05_DCPSUS1 on BOTTOM (solid shape): 103.34,75.2 103.34,74.54 103.18,74.37 103.13,74.37 103.07,74.37 103.01,74.34 103,74.33 102.96,74.33 102.82,74.27 102.76,74.13 102.76,74.09 102.75,74.06 102.71,74.04 102.24,74.04 102.2,74.08 102.2,74.1 102.25,74.29 102.2,74.47 102.2,74.54 102.13,74.6 102.1,74.63 102,74.63 101.95,74.69 101.95,74.82 102.03,74.9 102.39,74.9 102.7,74.93 102.87,75.2 102.87,75.22 102.91,75.25 103.29,75.25
+1V05_DCPSUS1 on IN1 (solid shape): 108.27,75 108.27,74.58 108.26,74.54 108.22,74.53 107.88,74.16 108.22,73.79 108.26,73.77 108.27,73.74 108.27,73.1 107.84,72.67 103.68,72.67 102.78,73.57 102.52,73.68 102.23,73.56 102.19,73.58 102.17,73.6 102.17,74.04 102.26,74.28 102.18,74.51 102.17,74.53 102.17,74.62 102.42,74.86 102.44,74.87 102.46,74.87 102.52,74.87 103.68,74.87 104.02,74.54 104.04,74.54 104.12,74.5 104.14,74.4 104.12,74.21 104.21,74.04 104.24,73.96 104.21,73.89 104.45,73.26 104.73,73.87 104.71,73.95 104.74,74.02 104.84,74.2 104.83,74.4 104.85,74.5 104.93,74.54 105.03,74.54 105.68,75.19 107.13,75.19 107.32,75.38 107.89,75.38
+1V05_DCPSUS2 on BOTTOM (solid shape): 105.58,73.5 105.58,72.02 105.49,71.93 105.49,71.48 105.38,71.37 104.96,71.37 104.8,71.54 104.8,71.58 104.77,71.68 104.7,71.75 104.7,71.75 103.82,72.63 103.72,72.63 103.6,72.76 103.6,73.17 103.75,73.32 104.21,73.32 104.23,73.29 104.3,73.29 104.46,73.26 104.62,73.29 104.64,73.29 104.65,73.31 104.72,73.36 104.77,73.43 104.82,73.47 104.82,73.52 104.84,73.55 105.53,73.55
+1V05_DCPSUS3 on BOTTOM (solid shape): outline of 435 points within 100.97,81.66 106.81,96.52
+1V05_S5 on BOTTOM (solid shape): 71.37,80.9 71.37,73.02 71.25,72.9 67.31,72.9 67.06,73.15 67.06,80.73 67.61,81.28 70.99,81.28
+1V05_S5 on BOTTOM (solid shape): 106.68,96.39 106.68,95.38 106.38,95.07 104.7,95.07 104.39,95.38 104.39,96.39 104.65,96.65 106.43,96.65
+1V05_S5 on BOTTOM (solid shape): 107,77.16 107,74.72 106.8,74.51 105.97,74.51 105.88,74.43 105.88,74.26 105.7,74.08 104.94,74.08 104.84,74.18 104.84,75 104.97,75.12 105.27,75.12 105.62,75.48 105.66,75.51 105.74,75.59 105.74,76.05 105.73,76.06 105.73,76.9 106.11,77.28 106.87,77.28
+1V05_S5 on IN2 (solid shape): 93.34,80.52 93.34,79.25 92.96,78.87 92.46,78.87 92.08,79.25 92.08,79.67 91.91,79.83 91.91,80.56 92,80.64 93.22,80.64
+1V05_S5 on IN2 (solid shape): 106.81,96.77 106.81,96.17 106.8,96.15 106.79,96.14 106.69,95.89 106.79,95.63 106.81,95.62 106.81,95.5 106.39,95.08 105.5,95.08 104.77,95.81 104.77,96.9 105.03,97.16 106.43,97.16
+1V05_S5 on SVCC (solid shape): 100.45,85.92 100.68,85.84 100.92,85.92 109.94,85.92 110.3,85.56 110.3,76.5 110.04,76.14 110.3,75.78 110.3,75.68 110.04,75.32 110.3,74.96 110.3,74.88 110.04,74.52 110.3,74.16 110.3,74.09 107.4,71.19 107.02,71.19 106.68,71.39 106.34,71.19 106.21,71.19 105.87,71.4 105.53,71.19 105.4,71.19 105.05,71.4 104.71,71.19 100.93,71.19 100.9,71.69 100.4,71.73 100.4,75.37 100.38,75.47 100.32,75.56 99.55,76.33 99.45,76.49 99.3,76.58 99.24,76.64 99.15,77.08 98.75,77.28 82.06,77.28 81.8,77.38 81.54,77.28 81.41,77.28 81.15,77.38 80.89,77.28 80.55,77.28 80.29,77.38 80.04,77.28 71.19,77.28 70.99,77.24 70.83,77.13 70.47,76.77 61.55,76.77 60.65,77.68 60.65,80.12 61.11,80.58 61.9,80.58 62.26,80.33 62.61,80.58 70.09,80.58 70.57,80.1 70.74,79.99 70.94,79.95 92.64,79.95 92.84,79.99 93.01,80.1 98.83,85.92
+1V05_SRC on TOP (solid shape): 67.84,78.11 67.84,76.99 67.84,76.89 68.26,76.47 68.26,70.29 67.44,69.47 60.07,69.47 59.82,69.72 59.82,74.04 60.07,74.3 60.81,74.3 60.85,74.26 60.85,74.24 60.9,74.1 60.99,73.98 61.28,73.86 61.58,73.98 61.65,74 62.01,73.86 62.38,74 62.74,73.86 63.1,74 63.17,73.98 63.71,73.94 63.86,74.47 63.85,74.48 63.85,74.52 64.52,75.18 64.52,78.08 64.78,78.35 67.6,78.35
+1V05_SRC on BOTTOM (solid shape): 66.5,78.41 66.5,74.48 66.67,74.3 66.67,73.15 66.55,73.02 65.28,73.02 65.15,73.15 65.15,73.79 65.02,73.91 64.01,73.91 63.91,74.02 63.91,78.13 64.26,78.49 66.42,78.49
+1V05_VCCASW on TOP (solid shape): 104.74,73.75 104.74,73.5 104.38,73.14 103.73,73.14 103.66,73.15 103.53,73.14 103.45,73.05 103.44,73.04 103.37,72.86 103.44,72.67 103.48,72.62 103.57,72.53 103.58,72.49 103.57,72.46 102.87,71.75 102.68,71.75 102.63,71.77 102.58,71.79 102.35,72.02 102.3,72.08 102.24,72.13 102.2,72.17 102.18,72.2 102.19,72.23 102.22,72.37 102.2,72.51 102.2,72.58 102.25,72.64 102.35,72.75 102.37,72.9 102.39,72.95 102.43,72.96 102.5,72.93 102.52,72.86 102.54,72.75 102.6,72.67 102.85,72.61 103.02,72.79 103.03,72.89 103,72.98 102.99,72.99 102.99,73.15 102.89,73.25 102.88,73.26 102.87,73.34 102.86,73.4 102.84,73.47 102.84,73.5 102.9,73.57 103.5,73.57 103.8,73.55 103.95,73.82 103.98,73.9 104.06,73.93 104.56,73.93
+1V05_VCCASW on BOTTOM (solid shape): 89.53,64.52 89.53,63.21 88.94,62.61 82.3,62.61 82.04,62.86 82.04,64.14 82.17,64.26 84.32,64.26 84.35,64.24 84.36,64.22 84.71,63.91 85.06,64.22 85.08,64.25 85.11,64.26 86.61,64.26 86.64,64.25 86.66,64.23 86.91,63.99 87.24,64.08 87.31,64.11 87.38,64.08 87.77,64.01 87.99,64.34 87.99,64.36 88,64.38 88.52,64.9 89.15,64.9
+1V05_VCCASW on IN2 (solid shape): outline of 903 points within 87.63,64.01 104.77,75.82
+1V05_VCCASW_1 on BOTTOM (solid shape): 107.97,73.07 107.97,72.1 107.86,72 107.69,72 107.65,72.04 107.34,72.04 107.11,71.81 107.11,71.52 107.54,71.09 107.54,70.94 107.4,70.81 107.3,70.81 107.03,71.08 107.03,71.19 106.82,71.4 106.58,71.4 106.4,71.58 106.4,71.81 106.59,72 106.77,72 106.87,72.1 106.87,73.01 106.97,73.12 107.91,73.12
+1V05_VCCASW_2 on BOTTOM (solid shape): 106.72,73.07 106.72,72.13 106.7,72.1 106.52,72.1 106.25,71.83 106.25,71.63 106.02,71.4 105.77,71.4 105.61,71.55 105.61,71.9 105.68,71.96 105.68,73 105.8,73.12 106.67,73.12
+1V05_VCCCLK1 on BOTTOM (solid shape): outline of 394 points within 107.57,81.66 111,93.73
+1V05_VCCCLK2 on TOP (solid shape): 109.91,78.85 109.92,78.84 110.14,78.64 110.43,78.67 110.46,78.68 110.49,78.66 110.58,78.58 110.58,78.37 110.5,78.16 110.59,77.96 110.62,77.89 110.59,77.82 110.31,77.55 109.78,77.55 109.6,77.72 109.6,78 109.66,78.17 109.6,78.34 109.6,78.74 109.73,78.87 109.89,78.87
+1V05_VCCCLK2 on BOTTOM (solid shape): 111.62,80.97 111.62,78.45 111.07,77.9 110.06,77.9 109.98,77.98 109.98,78.55 110.03,78.63 110.12,78.65 110.37,78.65 110.56,78.81 110.91,79.16 110.91,79.97 110.58,80.3 110.58,80.48 110.58,80.49 110.6,80.6 110.58,80.72 110.58,80.73 110.58,81.24 110.63,81.3 111.29,81.3
+1V05_VCCST on TOP (solid shape): outline of 171 points within 110.49,72.52 112.14,76.01
+1V05_VCCUSBCORE on IN1 (solid shape): outline of 647 points within 99.38,81.05 105.82,85.36
+1V05_VIN on TOP (solid shape): 63.75,62.86 63.75,55.25 63.5,54.99 59.56,54.99 59.44,55.12 59.44,57.15 59.94,57.66 59.94,59.11 59.98,59.19 60.06,59.21 60.56,59.67 60.03,60.09 60,60.09 59.94,60.15 59.94,60.58 59.44,61.09 59.44,62.48 59.97,63.02 63.6,63.02
+1V05DX_MODPHY on TOP (solid shape): 109.73,99.95 109.73,98.3 109.47,98.04 104.39,98.04 104.27,98.17 104.27,99.95 104.52,100.2 109.47,100.2
+1V05DX_MODPHY on TOP (solid shape): 103.83,81.12 103.83,81.1 103.94,80.88 104.19,80.83 104.28,80.8 104.31,80.71 104.37,80.49 104.58,80.38 104.65,80.35 104.67,80.28 104.67,80.26 104.8,80.14 104.8,79.68 104.6,79.48 104.13,79.48 103.78,79.83 103.49,79.83 103.41,79.76 103.12,79.76 102.87,80.01 102.87,80.17 102.93,80.22 102.93,80.25 102.93,80.27 102.94,80.29 103.03,80.51 102.9,80.7 102.88,80.72 102.87,80.74 102.87,80.77 102.9,80.85 102.91,80.92 102.91,80.94 103.12,81.15 103.8,81.15
+1V05DX_MODPHY on TOP (solid shape): outline of 449 points within 72.64,79.12 89.66,96.65
+1V05DX_MODPHY on BOTTOM (solid shape): 75.18,80.9 75.18,77.47 75.06,77.34 73.53,77.34 73.28,77.6 73.28,78.11 72.65,78.73 72.02,78.73 72.01,78.74 72.01,80.77 72.64,81.41 74.68,81.41
+1V05DX_MODPHY on BOTTOM (solid shape): outline of 819 points within 87.92,79.48 105.79,100.2
+1V05DX_MODPHY on IN2 (solid shape): outline of 831 points within 94.61,78.38 104.98,90.58
+1V8_SUS on TOP (solid shape): 93.44,37.5 93.47,37.41 93.42,37.34 93.25,37.06 93.41,36.77 93.41,36.53 93.25,36.24 93.43,35.96 93.48,35.88 93.45,35.8 93.28,35.63 91.63,35.63 91.13,36.13 89.98,36.13 89.6,36.52 89.6,36.9 89.73,37.02 91.25,37.02 91.89,37.66 93.28,37.66
+1V8_SUS on TOP (solid shape): 142.79,37.61 143.75,37.61 144.08,37.28 144.08,35.12 144.72,34.48 144.72,34.1 144.59,33.98 142.1,33.98 141.67,34.41 141.53,34.41 141.51,34.42 141.49,34.43 141.45,34.47 141.39,34.51 141.26,34.64 141.26,34.66 141.2,34.83 141.04,34.95 141.04,34.98 141.04,35.13 141.05,35.16 141.07,35.17 141.26,35.45 141.07,35.73 141.05,35.74 141.04,35.76 141.04,35.93 141.05,35.96 141.07,35.97 141.26,36.25 141.07,36.53 141.05,36.54 141.04,36.57 141.04,36.73 141.05,36.76 141.07,36.77 141.25,36.98 141.19,37.25 141.16,37.32 141.2,37.39 141.23,37.42 141.26,37.47 141.36,37.49 141.52,37.66 142.74,37.66
+1V8_SUS on TOP (solid shape): 161.23,37.4 161.23,36.39 162.37,35.25 163.29,35.25 163.31,35.22 163.32,35.21 163.35,35.11 163.4,35.02 163.42,34.97 163.41,34.92 163.32,34.75 163.38,34.37 163.42,34.33 163.43,34.29 163.42,34.26 163.01,33.85 160.59,33.85 160.35,34.09 160.34,34.13 160.35,34.14 160.29,34.45 159.98,34.51 159.97,34.5 159.94,34.51 159.83,34.61 159.83,35.11 159.84,35.14 159.87,35.16 160.07,35.45 159.87,35.74 159.84,35.76 159.83,35.79 159.83,35.91 159.84,35.94 159.87,35.96 160.07,36.25 159.87,36.54 159.84,36.56 159.83,36.59 159.83,36.71 159.84,36.74 159.87,36.76 160.07,37.02 159.91,37.32 159.89,37.34 159.89,37.36 159.89,37.38 159.92,37.41 159.93,37.41 160.02,37.51 161.13,37.51
+1V8_SUS on TOP (solid shape): 131,37.62 131,37.3 131,37.28 130.99,37.26 130.91,36.98 131.1,36.76 131.12,36.75 131.13,36.72 131.13,36.58 131.12,36.55 130.96,36.43 130.9,36.26 130.9,36.23 130.84,36.17 129.62,36.17 129.48,36.03 127.64,36.03 127.2,35.89 126.95,35.51 126.94,35.5 126.3,34.86 122.49,34.86 122.31,35.05 122.28,35.13 122.32,35.2 122.45,35.48 122.27,35.73 122.25,35.75 122.24,35.77 122.24,35.92 122.25,35.95 122.27,35.97 122.45,36.25 122.27,36.53 122.25,36.55 122.24,36.57 122.24,36.74 122.26,36.76 122.27,36.77 122.45,37.05 122.27,37.33 122.26,37.33 122.24,37.36 122.24,37.45 122.25,37.48 122.29,37.51 122.32,37.54 122.37,37.59 122.47,37.63 122.5,37.66 123.51,37.66 124.53,36.64 124.72,36.64 124.74,36.64 124.76,36.63 125.01,36.53 125.25,36.64 125.38,36.77 127.96,36.77 128.97,37.79 130.84,37.79
+1V8_SUS on TOP (solid shape): 106.02,38.38 106.02,36.6 105.89,36.47 105.89,35.98 106.11,35.75 106.11,35.63 106.11,35.62 106.11,35.14 106.79,34.46 107.28,34.46 107.38,34.36 107.38,33.34 107.25,33.21 106.87,33.21 106.49,32.83 103.95,32.83 103.77,33.01 103.74,33.1 103.8,33.18 103.94,33.56 103.57,33.74 103.48,33.76 103.44,33.84 103.44,33.86 103.48,33.94 103.57,33.96 103.72,33.95 103.86,34.02 103.95,34.33 103.71,34.55 103.67,34.57 103.66,34.61 103.62,34.81 103.47,34.95 103.44,34.96 103.44,35.14 103.47,35.15 103.67,35.45 103.47,35.75 103.44,35.76 103.44,35.94 103.47,35.95 103.67,36.25 103.47,36.55 103.44,36.56 103.44,36.74 103.47,36.75 103.67,37.05 103.47,37.35 103.44,37.36 103.44,37.53 103.57,37.66 104.21,37.66 104.46,37.91 104.46,39.44 104.59,39.56 104.84,39.56
+1V8_SUS on BOTTOM (solid shape): outline of 2779 points within 85.66,25.4 163.5,37.49
+1V8_SUS_C on BOTTOM (solid shape): 84.2,29.72 84.2,27.94 84.45,27.69 85.16,27.69 85.16,27.68 85.91,27.68 86.27,27.31 86.27,25.65 86.02,25.4 83.31,25.4 83.19,25.53 83.19,26.92 83.69,27.43 83.69,29.72 83.79,29.82 84.1,29.82
+3V3 on TOP (solid shape): 49.55,14.75 49.55,13.02 49.23,12.7 47.01,12.7 46.71,13 46.71,14.3 47.36,14.95 49.34,14.95
+3V3 on TOP (solid shape): 67.6,24.09 67.6,22.39 67.56,22.35 65.91,22.35 65.66,22.61 65.66,24 65.79,24.13 67.56,24.13
+3V3 on TOP (solid shape): 20.26,86.93 20.26,86.43 20.51,86.17 20.89,86.17 21.02,86.05 21.02,85.66 20.89,85.54 18.61,85.54 18.23,85.92 18.23,86.81 18.48,87.06 20.13,87.06
+3V3 on TOP (solid shape): 199.91,29.83 200.32,29.83 200.57,30.09 201.33,30.09 201.49,29.93 201.55,29.87 201.61,29.82 201.65,29.78 201.79,29.77 201.94,29.78 201.94,29.79 202.15,29.79 202.2,29.73 202.2,28.56 202,28.36 202,27.12 201.77,26.89 200.62,26.89 200.01,27.5 199.15,27.5 198.24,26.58 197.17,26.58 196.87,26.89 196.87,28.36 198.44,29.94 199.1,29.94 199.25,30.09 199.66,30.09
+3V3 on TOP (solid shape): 197.73,82.51 198.59,82.51 198.82,82.29 198.82,80.46 199.58,79.89 199.58,79.06 199.39,78.87 196.41,78.87 195.9,79.38 195.9,80.06 197.31,80.06 197.31,80.01 197.33,79.96 197.35,79.91 197.38,79.86 197.41,79.82 197.45,79.78 197.5,79.75 197.55,79.73 197.6,79.72 197.65,79.71 197.71,79.71 197.76,79.72 197.81,79.73 197.86,79.75 197.9,79.78 197.94,79.82 197.98,79.86 198.01,79.91 198.03,79.96 198.04,80.01 198.05,80.06 198.05,80.12 198.04,80.17 198.02,80.22 197.99,80.27 197.96,80.31 197.92,80.35 197.88,80.38 197.83,80.41 197.78,80.43 197.73,80.44 197.68,80.45 197.62,80.44 197.57,80.43 197.52,80.41 197.47,80.38 197.43,80.35 197.39,80.31 197.36,80.27 197.34,80.22 197.32,80.17 197.31,80.12 197.31,80.06 195.9,80.06 195.9,82.87 196.15,83.12 197.12,83.12
+3V3 on BOTTOM (solid shape): 168.66,62.86 168.66,61.21 168.53,61.09 167.13,61.09 166.88,61.34 166.88,62.86 167,62.99 168.53,62.99
+3V3 on BOTTOM (solid shape): 64.39,85.22 64.39,81.41 64.07,81.09 61.16,81.09 61.11,81.15 61.11,83.3 60.71,83.7 60.71,85.22 60.96,85.47 64.14,85.47
+3V3 on BOTTOM (solid shape): 195.14,13.78 195.14,10.63 194.93,10.43 193.77,10.43 193.21,10.99 191.28,10.99 191.07,11.19 191.07,13.27 191.46,13.66 191.46,14.29 191.96,14.8 194.12,14.8
+3V3 on BOTTOM (solid shape): 49.4,14.99 49.4,13.21 48.89,12.7 46.11,12.7 45.79,13.02 45.79,13.68 46.04,13.93 46.45,13.93 46.6,14.09 46.6,14.72 46.99,15.11 49.28,15.11
+3V3 on BOTTOM (solid shape): 181.55,29.5 182.85,29.5 182.87,29.48 182.87,29.23 182.84,29.2 181.57,29.2 181.55,29.2 181.55,29.18 181.52,29.15 181.52,29.02 181.54,29.01 181.6,29.01 181.6,29 182.81,29 182.85,28.96 182.85,28.7 181.55,28.7 181.52,28.67 181.52,28.54 181.55,28.51 181.56,28.5 181.57,28.49 182.85,28.49 182.85,28.24 182.82,28.21 181.4,28.21 181.1,27.92 181.1,27.51 180.71,27.12 178.4,27.12 178.25,27.27 178.25,28.64 178.37,28.77 180.74,28.77 181.47,29.5 181.55,29.5
+3V3 on IN1 (solid shape): 193.24,14.53 193.24,12.29 193.12,12.16 190.32,12.16 190.2,12.29 190.2,14.68 190.63,15.11 192.66,15.11
+3V3 on IN1 (solid shape): 198.85,28.26 198.85,27.4 198.59,27.14 198.59,25.92 198.03,25.36 195.8,25.36 195.24,25.92 195.24,27.85 196.15,28.77 198.34,28.77
+3V3 on IN2 (solid shape): 67.56,24 67.56,22.48 67.44,22.35 66.42,22.35 66.17,22.61 66.17,24 66.29,24.13 67.44,24.13
+3V3 on IN2 (solid shape): 49.4,14.99 49.4,13.34 48.77,12.7 47.12,12.7 46.74,13.08 46.74,14.86 47.39,15.51 48.88,15.51
+3V3 on IN2 (solid shape): outline of 145 points within 70.1,51.94 80.9,83.06
+3V3 on IN2 (solid shape): outline of 208 points within 194.27,73.41 202.44,83.63
+3V3 on IN2 (solid shape): outline of 3305 points within 86.23,21.85 199.71,104.82
+3V3 on SVCC (solid shape): outline of 882 points within 10.99,65.98 109.92,104.59
+3V3 on IN3 (solid shape): outline of 185 points within 81.28,77.24 90.42,83
+3V3_ADO on BOTTOM (solid shape): 40.13,23.24 40.13,17.6 40.03,17.5 39.12,17.5 37.82,18.8 37.46,18.8 37.34,18.92 37.34,20.09 38.23,20.09 38.23,20.04 38.23,19.99 38.25,19.94 38.27,19.89 38.3,19.84 38.34,19.8 38.38,19.77 38.43,19.74 38.48,19.73 38.53,19.71 38.58,19.71 38.64,19.71 38.69,19.73 38.74,19.74 38.78,19.77 38.83,19.8 38.86,19.84 38.89,19.89 38.91,19.94 38.93,19.99 38.94,20.04 38.94,20.09 38.93,20.15 38.91,20.2 38.89,20.24 38.86,20.29 38.83,20.33 38.78,20.36 38.74,20.39 38.69,20.41 38.64,20.42 38.58,20.42 38.53,20.42 38.48,20.41 38.43,20.39 38.38,20.36 38.34,20.33 38.3,20.29 38.27,20.24 38.25,20.2 38.23,20.15 38.23,20.09 37.34,20.09 37.34,21.97 36.96,22.35 36.96,23.24 37.59,23.88 39.5,23.88
+3V3_ADO on IN1 (solid shape): 39.44,18.99 39.44,18.48 39.31,18.35 38.04,18.35 37.79,18.61 37.79,19.37 37.91,19.5 38.93,19.5
+3V3_ADO on IN1 (solid shape): 31.94,18.86 31.94,18.1 31.69,17.85 31.31,17.85 30.95,18.21 30.88,18.3 30.78,18.37 30.42,18.74 30.42,19.24 30.55,19.37 31.44,19.37
+3V3_PCU on TOP (solid shape): 48.48,43.61 48.58,43.54 48.54,43.43 48.77,42.8 48.99,43.43 48.96,43.54 49.06,43.61 49.61,43.61 50.04,43.18 50.04,41.91 49.42,41.29 49,41.29 48.97,41.26 48.77,41.2 48.65,41.09 48.62,41.07 48.58,41.08 48.12,40.97 48.17,40.5 48.21,40.43 48.18,40.36 48.13,40.31 48.13,40 48.01,39.88 46.74,39.88 46.48,40.13 46.48,42.47 46.5,42.5 46.53,42.52 46.75,42.52 46.84,42.61 46.88,42.63 46.91,42.61 46.93,42.6 47.46,42.6 47.78,42.91 47.78,43.46 47.93,43.61
+3V3_PCU on BOTTOM (solid shape): 82.55,48.39 82.55,47.24 82.42,47.12 81.28,47.12 81.15,47.24 81.15,48.39 81.28,48.51 82.42,48.51
+3V3_PCU on BOTTOM (solid shape): 85.34,40.13 85.34,36.83 84.2,35.69 84.2,33.53 84.07,33.4 83.82,33.4 83.69,33.53 83.69,35.81 83.44,36.07 83.44,39.88 83.95,40.39 85.09,40.39
+3V3_PCU on BOTTOM (solid shape): outline of 277 points within 18.91,74.8 60.4,90.8
+3V3_PCU on IN1 (solid shape): outline of 406 points within 97.81,80.09 103.47,82.27
+3V3_PCU on IN1 (solid shape): outline of 969 points within 21.89,42.44 68.07,51.05
+3V3_PCU on IN2 (solid shape): 68.65,42.61 68.65,40.96 68.27,40.58 66.87,40.58 65.6,41.85 65.6,42.87 65.73,42.99 68.27,42.99
+3V3_PCU on IN2 (solid shape): 81.55,28.23 81.55,27.78 81.08,27.3 81.08,26.95 80.8,26.67 79.32,26.67 78.92,27.08 78.92,28.4 79.12,28.6 81.18,28.6
+3V3_PCU on IN2 (solid shape): 78.26,52.14 78.47,52.06 78.69,52.12 78.93,51.88 78.93,50.49 78.68,50.23 77.16,50.23 76.9,50.49 76.9,51.88 77.16,52.14
+3V3_PCU on IN2 (solid shape): outline of 1043 points within 79.44,59.17 92.52,73.3
+3V3_PCU on IN2 (solid shape): outline of 1135 points within 147.57,3.3 159.38,16.13
+3V3_PCU on SVCC (solid shape): 59.63,83.17 59.63,72.84 59.67,72.64 59.78,72.48 61.05,71.21 61.21,71.1 61.41,71.06 73.26,71.06 78.11,66.21 78.22,66.01 78.42,65.9 81.47,62.85 81.47,57.44 81.34,57.15 81.47,56.86 81.47,56.81 81.34,56.52 81.47,56.22 81.47,56.03 81.34,55.74 81.47,55.45 81.47,54.51 81.24,54.27 81.13,54.11 81.09,53.91 81.09,49.73 81.13,49.53 81.24,49.36 82.61,47.99 82.66,47.51 83.14,47.46 83.27,47.33 83.44,47.22 83.64,47.18 84.08,47.18 84.46,46.84 84.84,47.18 85.8,47.18 86.1,47.04 86.4,47.18 87.99,47.18 88.2,46.97 88.2,40.55 88.04,40.23 88.2,39.92 88.2,38.81 88.24,38.61 88.35,38.44 89.22,37.57 89.22,27.96 88.5,27.24 85.29,27.24 85.09,27.21 84.92,27.1 84.56,26.74 76.32,26.74 75.95,27.05 75.57,26.74 71.9,26.74 71.31,27.33 71.31,37.28 71.69,37.66 71.31,38.04 71.31,57.46 71.48,57.9 71.08,58.16 65.2,64.05 65.08,64.29 64.84,64.41 62.78,66.47 62.62,66.58 62.42,66.61 39.65,66.61 38.8,67.46 38.8,72.12 50.7,84.01 58.78,84.01
+3V3_PCU_EC on TOP (solid shape): 48.58,39.06 49.47,39.06 49.6,38.93 49.6,37.91 49.34,37.66 47.97,37.66 47.74,37.43 47.44,37.43 46.93,37.94 46.93,39.18 47.06,39.31 48.33,39.31
+3V3_PCU_EC on TOP (solid shape): 60.37,28.77 60.9,28.77 61.03,28.64 61.03,27.63 60.9,27.5 59.25,27.5 58.97,27.78 58.97,28.36 59.53,28.92 60.21,28.92
+3V3_RTC on TOP (solid shape): 83.57,48.49 83.57,46.14 83.4,45.97 82.68,45.97 82.55,46.1 82.55,48.49 82.74,48.68 83.38,48.68
+3V3_RTC on IN2 (solid shape): 84.37,49.34 84.37,48.78 83.95,48.36 83.95,47.5 83.82,47.37 82.8,47.37 82.68,47.5 82.68,49.28 82.93,49.53 84.18,49.53
+3V3_RTC on IN2 (solid shape): outline of 1072 points within 98.17,65.41 103.5,72.14
+3V3_S5 on TOP (solid shape): 86.55,54.85 86.55,53.03 86.43,52.9 85.54,52.9 85.41,53.03 85.41,54.68 85.66,54.93 85.66,55.31 85.77,55.41 85.99,55.41
+3V3_S5 on TOP (solid shape): 199.25,84.39 199.25,83.23 198.69,82.67 197.83,82.67 197.22,83.28 197.07,83.28 196.61,83.73 196.61,84.5 197.02,84.9 198.74,84.9
+3V3_S5 on TOP (solid shape): 65.8,22.19 68.37,22.19 68.42,22.14 68.42,21.4 68.37,21.35 67.38,21.35 67.3,21.43 65.45,21.43 64.73,22.14 64.73,22.49 64.84,22.6 65.39,22.6
+3V3_S5 on TOP (solid shape): 41.85,5.02 41.85,4.38 41.6,4.13 38.42,4.13 38.29,4.26 38.29,4.89 38.04,5.15 37.53,5.15 37.4,5.27 37.4,6.16 37.53,6.29 40.58,6.29
+3V3_S5 on BOTTOM (solid shape): 199.25,84.41 199.25,83.05 198.78,82.58 197.41,82.58 196.61,83.5 196.61,84.19 197.22,84.8 198.67,84.8
+3V3_S5 on BOTTOM (solid shape): 63.78,76.61 63.78,74.14 63.55,73.91 60.99,73.91 60.71,74.19 60.71,76.58 60.83,76.71 63.68,76.71
+3V3_S5 on IN1 (solid shape): 66.33,22.21 68.34,22.21 68.39,22.16 68.39,21.45 68.28,21.34 64.98,21.34 64.61,21.71 64.61,22.39 64.79,22.57 65.98,22.57
+3V3_S5 on IN2 (solid shape): 65.85,22.19 66.94,22.19 67.27,21.86 67.27,21.48 67.21,21.41 66.75,21.41 66.59,21.25 65.22,21.25 64.66,21.81 64.66,22.72 64.68,22.75 65.29,22.75
+3V3_S5 on IN2 (solid shape): 85.34,52.37 85.34,51.13 85.14,50.93 84.02,50.93 84.01,50.94 83.51,50.94 83.43,51.02 83.43,51.4 83.46,51.4 84.04,51.98 84.04,52.19 84.38,52.53 85.19,52.53
+3V3_S5 on IN2 (solid shape): outline of 1249 points within 80.64,75.31 107.06,79.49
+3V3_S5 on SVCC (solid shape): outline of 301 points within 60.65,48.2 99.89,76.27
+3V3_S5_DEEP on TOP (solid shape): 85.41,55.92 85.41,55.01 85.33,54.93 83.31,54.93 82.24,56.01 81.95,56.01 81.76,56.09 81.54,56.05 81.51,56.04 81.48,56.06 81.41,56.13 81.41,57.28 81.54,57.41 83.92,57.41
+3V3_S5_DEEP on TOP (solid shape): 109.73,73.41 109.98,73.41 110.02,73.45 110.07,73.48 110.1,73.51 110.12,73.53 110.14,73.53 110.36,73.53 110.48,73.42 110.49,73.4 110.49,73.18 110.47,73.15 110.43,73.1 110.13,72.79 110.11,72.78 110.01,72.74 109.93,72.66 109.91,72.65 109.89,72.64 109.47,72.64 109.09,73.02 109.09,73.15 109.09,73.41 109.22,73.53 109.6,73.53
+3V3_S5_DEEP on TOP (solid shape): 104.89,75.71 104.89,75.24 104.74,75.08 104.12,75.08 104.08,75.08 104.04,75.05 103.61,75.05 103.59,75.05 103.38,74.82 103.48,74.53 103.5,74.51 103.5,74.49 103.5,74.17 103.39,74.05 103.11,74.05 103.01,74.15 103.01,74.16 103,74.18 103,74.64 103,74.65 103.03,74.76 103,74.87 103,74.88 103,75.31 103.12,75.44 103.56,75.44 103.57,75.44 103.66,75.42 103.75,75.44 103.76,75.44 103.89,75.44 103.91,75.47 103.92,75.47 104.28,75.82 104.78,75.82
+3V3_S5_DEEP on BOTTOM (solid shape): 83.31,58.29 83.31,56.77 82.8,56.26 81.41,56.26 81.28,56.39 81.28,58.04 81.66,58.42 83.19,58.42
+3V3_S5_DEEP on BOTTOM (solid shape): 105.63,76.01 105.63,75.63 105.23,75.22 104.46,75.22 104.31,75.38 104.31,75.65 104.67,76.01 104.74,76.01 104.79,76.06 105.58,76.06
+3V3_S5_DEEP on BOTTOM (solid shape): 111.8,75.15 111.8,73.78 111.04,73.01 110.15,73.01 109.98,73.18 109.98,73.8 110.35,74.17 110.68,74.28 110.76,74.62 110.76,74.63 110.76,75.1 110.86,75.2 111.75,75.2
+3V3_S5_DEEP on IN2 (solid shape): outline of 442 points within 104.62,69.52 110.62,73.5
+3V3_S5_DEEP on IN3 (solid shape): 82.04,57.78 82.04,56.39 81.91,56.26 80.52,56.26 80.26,56.52 80.26,57.78 80.39,57.91 81.91,57.91
+3V3_S5_DEEP on IN3 (solid shape): outline of 989 points within 95,72.64 110.56,78.87
+3V3_SATA_N0 on TOP (solid shape): 206.41,7.18 206.41,5.24 205.4,4.24 202.91,4.24 200.85,6.29 205.95,6.29 205.95,6.49 204.45,6.49 204.45,6.29 200.85,6.29 200.68,6.47 200.68,6.79 205.95,6.79 205.95,6.99 204.45,6.99 204.45,6.79 200.68,6.79 200.68,7.13 200.83,7.28 206.31,7.28
+3V3_SATA_N0 on TOP (solid shape): 206.37,24.7 206.37,23.59 206.26,23.49 204.32,23.49 204.03,23.2 204.03,22.32 203.32,21.61 201.28,21.61 201.08,21.81 201.08,22.77 201.23,22.93 201.23,23.79 205.95,23.79 205.95,23.99 204.45,23.99 204.45,23.79 201.23,23.79 201.23,25.21 201.39,25.36 202.61,25.36 203.52,26.28 204.79,26.28
+3V3_SATA_N0 on BOTTOM (solid shape): 199.46,9.57 200.93,9.57 202.71,7.79 204.28,7.79 204.43,7.64 204.43,5.25 203.77,4.59 202.09,4.59 200.21,6.54 197.52,6.85 196.74,6.85 196.31,7.28 196.31,8.3 196.33,8.32 196.33,9.74 195.7,10.38 195.7,11.85 195.8,11.95 197.07,11.95
+3V3_SATA_N0 on IN2 (solid shape): outline of 96 points within 195.65,4.33 205.7,25.67
+3V3_SATA_N0_N on TOP (solid shape): 206.28,21.79 206.41,21.66 206.41,20.09 206.32,19.99 201.12,19.99 200.83,20.28 200.83,20.29 205.95,20.29 205.95,20.49 204.45,20.49 204.45,20.29 200.83,20.29 200.83,20.79 205.95,20.79 205.95,20.99 204.45,20.99 204.45,20.79 200.83,20.79 200.83,21 200.93,21.1 202.58,21.1 202.78,21.29 205.95,21.29 205.95,21.49 204.45,21.49 204.45,21.29 202.78,21.29 202.89,21.4 203.77,21.4 204.17,21.79 205.87,21.79
+3V3_SATA_N1 on TOP (solid shape): 198.08,32.02 198.08,31.16 197.68,30.75 197.17,30.75 196.87,31.05 196.87,31.92 197.07,32.12 197.98,32.12
+3V3_SATA_N1 on TOP (solid shape): 206.41,50.72 206.41,49.6 206.31,49.49 203.67,49.49 203.32,49.14 202.5,49.14 202.4,49.24 202.4,49.8 205.95,49.8 205.95,49.99 204.45,49.99 204.45,49.8 202.4,49.8 202.4,51.37 202.81,51.78 205.35,51.78
+3V3_SATA_N1 on TOP (solid shape): 206.41,33.18 206.41,31.28 205.5,30.37 205.5,27.35 204.84,26.69 202.86,26.69 202.66,26.89 202.66,32.29 205.95,32.29 205.95,32.49 204.45,32.49 204.45,32.29 202.66,32.29 202.66,32.79 205.95,32.79 205.95,32.99 204.45,32.99 204.45,32.79 202.66,32.79 202.66,33.15 202.79,33.29 206.3,33.29
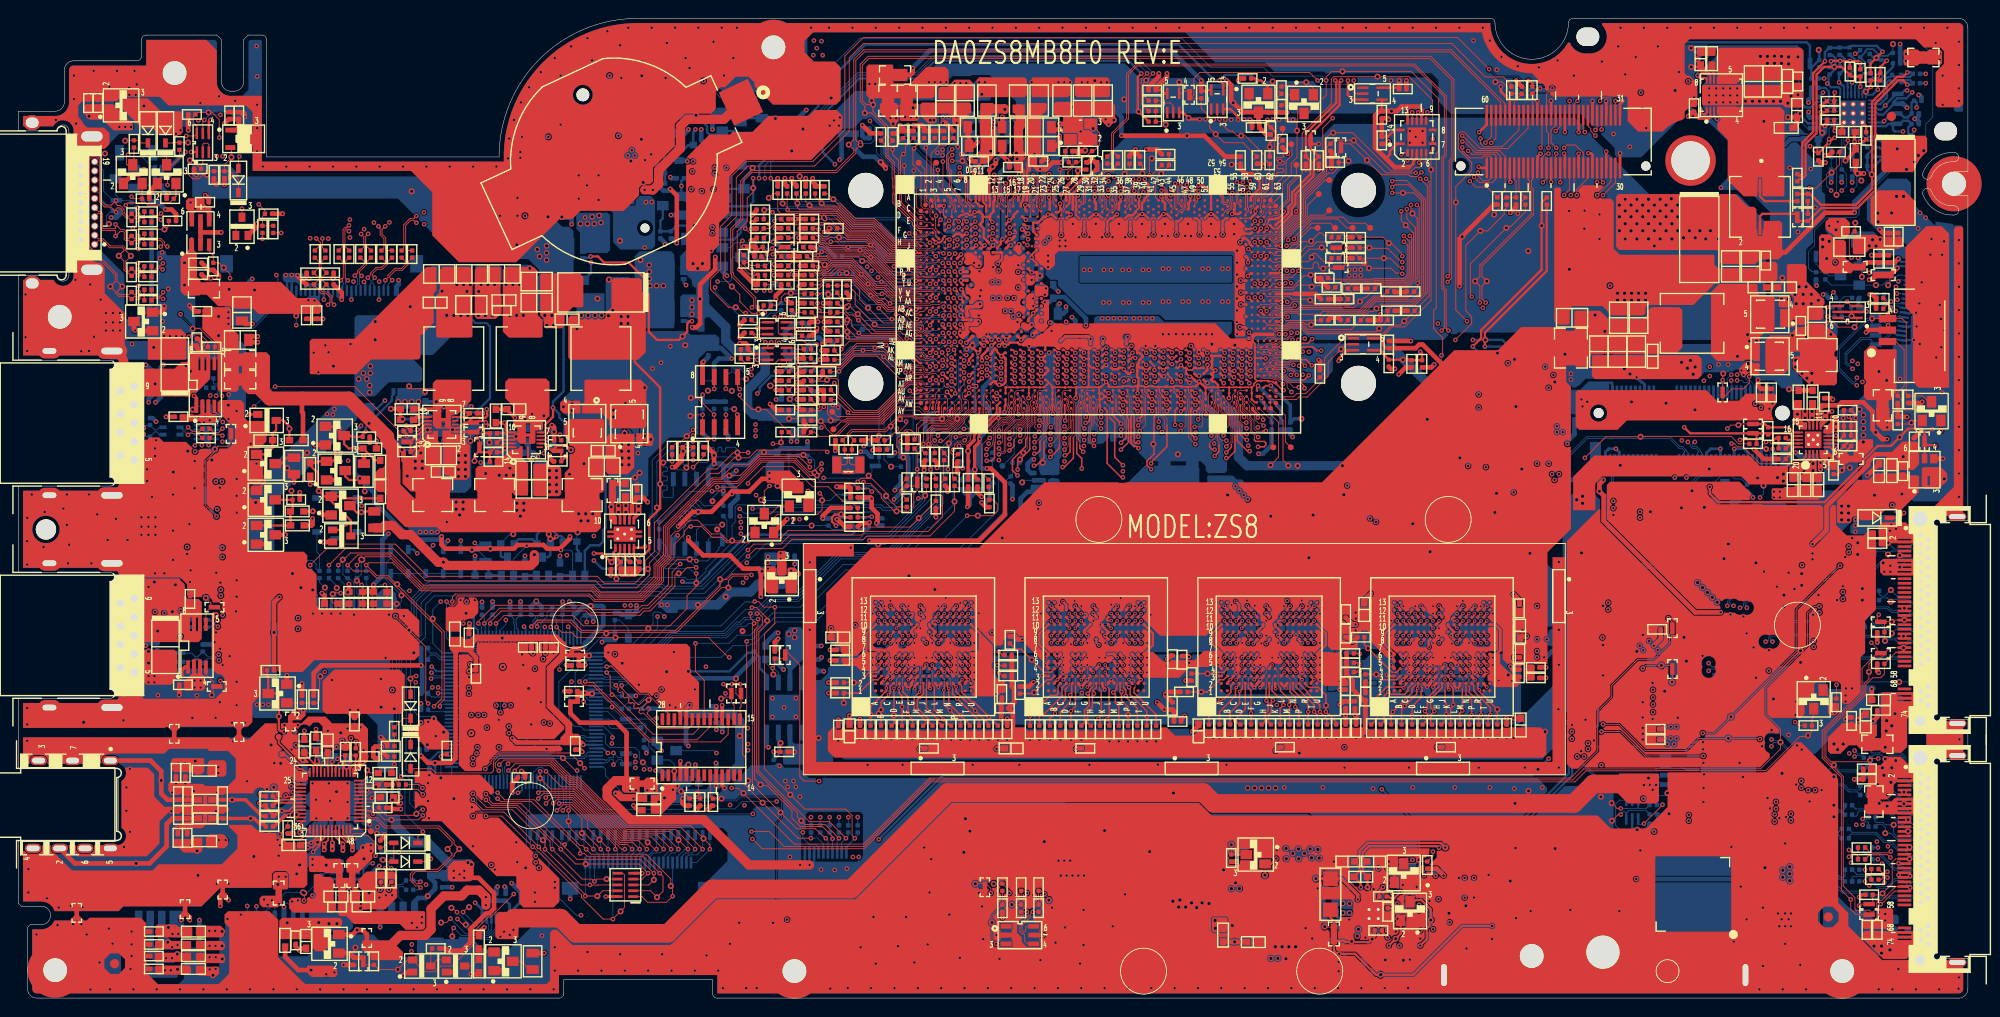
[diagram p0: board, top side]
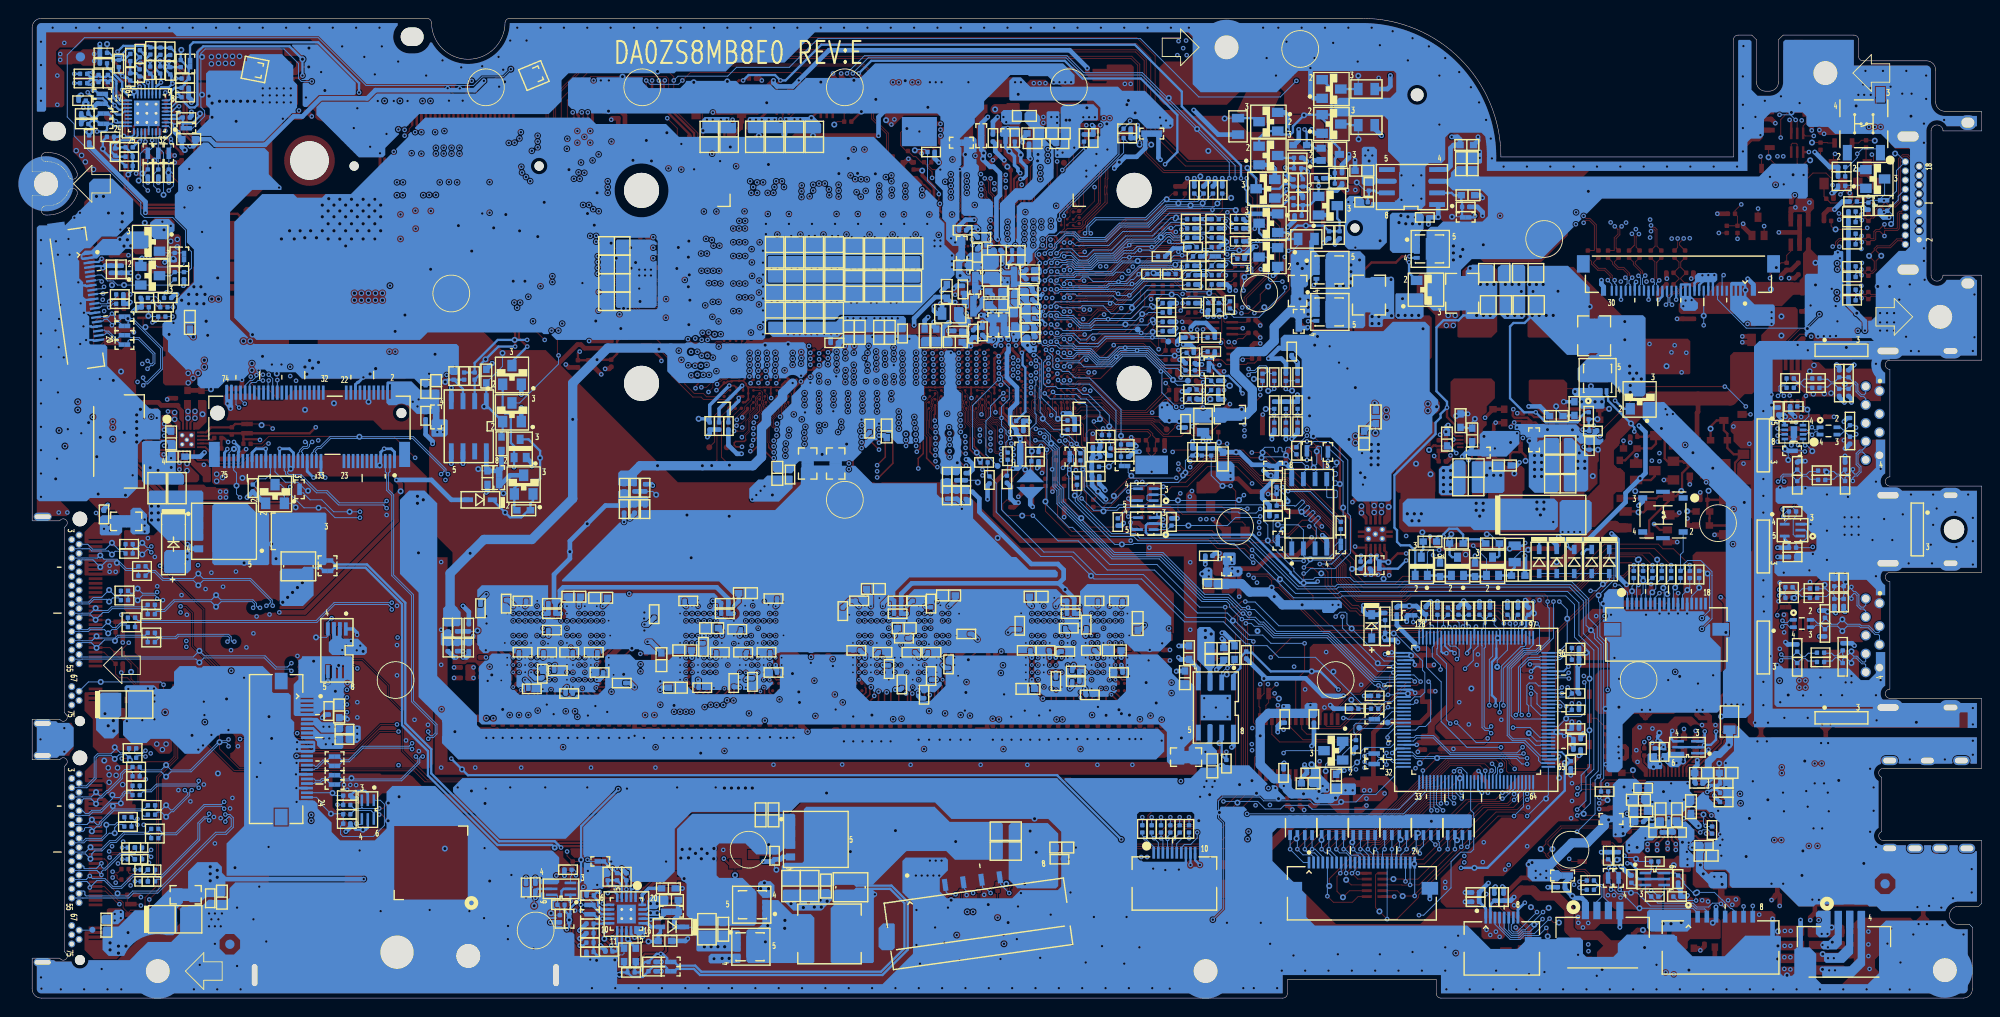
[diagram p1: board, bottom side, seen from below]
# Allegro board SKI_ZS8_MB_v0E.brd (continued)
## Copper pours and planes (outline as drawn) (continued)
+3V3_SATA_N1 on BOTTOM (solid shape): 204.74,52.29 204.74,50.51 204.59,50.36 202.66,50.36 202.3,50.71 202.3,52.34 202.5,52.54 204.49,52.54
+3V3_SATA_N1 on BOTTOM (solid shape): 205.15,32.63 205.15,29.17 204.23,28.26 203.29,28.26 202.69,28.86 202.69,30.46 202.4,30.75 202.4,33.19 202.45,33.24 204.54,33.24
+3V3_SATA_N1 on IN3 (solid shape): outline of 527 points within 196.31,28.62 206.06,51.93
+3V3_SATA_N1_N on TOP (solid shape): 206.41,47.68 206.41,46.08 206.32,45.99 205.7,45.99 204.2,45.99 202.91,45.99 202.6,46.3 205.95,46.3 205.95,46.49 204.45,46.49 204.45,46.3 202.6,46.3 202.55,46.34 202.55,46.8 205.95,46.8 205.95,46.99 204.45,46.99 204.45,46.8 202.55,46.8 202.55,47.3 205.95,47.3 205.95,47.49 204.45,47.49 204.45,47.3 202.55,47.3 202.55,47.41 202.94,47.8 206.3,47.8
+3V3_SATA_N1_N on BOTTOM (solid shape): 201.41,53.08 201.41,50.71 201.16,50.46 199.51,50.46 199.3,50.66 199.3,51.37 199.61,51.68 199.61,52.64 200.32,53.36 201.13,53.36
+3V3_SATA_N1_N on IN2 (solid shape): outline of 104 points within 199.61,44.57 205.96,52.85
+3V3_SER on TOP (solid shape): 202.37,82.87 204.79,82.87 205.04,82.62 205.04,81.98 204.6,81.53 201.44,81.53 200.84,80.94 199.71,80.94 199.58,81.07 199.58,82.62 200.04,83.07 202.17,83.07
+3V3_SER on BOTTOM (solid shape): 202.63,82.61 204.41,82.61 205.55,81.47 205.55,81.47 205.68,81.35 206.36,81.35 206.82,80.89 206.82,80.48 206.66,80.32 206.57,80.32 205.49,80.48 205.04,80.48 204.79,80.73 205.52,80.73 206.6,80.57 206.64,80.82 205.56,80.97 205.52,80.73 204.79,80.73 204.68,80.84 202.63,80.84 201.93,81.53 199.64,81.53 199.39,81.79 199.39,83.31 199.52,83.44 201.8,83.44
+3V3_SUS on TOP (solid shape): 34.74,2.99 34.74,2.58 34.46,2.3 31.89,2.3 31.38,2.81 31.38,3.42 31.51,3.55 34.18,3.55
+3V3_SUS on IN2 (solid shape): 34.91,2.96 34.91,2.61 34.66,2.35 33.26,2.35 33.04,2.58 33.04,3.55 33.31,3.83 34.05,3.83
+3V3_SUS on IN2 (solid shape): 155.51,69.28 155.51,68.6 155.36,68.44 154.45,68.44 153.81,69.08 153.81,69.28 153.96,69.43 155.36,69.43
+3V3_SUS on IN2 (solid shape): 92.17,15.79 92.17,15.05 91.94,14.82 90.74,14.82 90.52,15.05 90.52,15.51 91.07,16.07 91.89,16.07
+3V3_SUS on IN3 (solid shape): 35.35,2.66 35.35,2.23 35.17,2.05 33.39,2.05 33.09,2.35 33.09,2.75 33.68,3.34 34.66,3.34
+3V3_SUS on IN3 (solid shape): 91.73,15.46 91.73,14.39 91.61,14.26 90.72,14.26 90.52,14.47 90.52,15.46 90.67,15.61 91.58,15.61
+3V3_SUS on IN3 (solid shape): 68.11,20.94 68.11,19.85 68.06,19.8 67.17,19.8 66.84,20.13 64.43,20.13 64.1,20.46 64.1,20.92 64.4,21.22 67.83,21.22
+3V3_TPM on TOP (solid shape): 69.6,23.75 69.6,22.48 69.47,22.35 68.33,22.35 68.07,22.61 68.07,23.75 68.33,24 69.34,24
+3V3_TPM on BOTTOM (solid shape): 73.66,31.88 73.66,30.73 73.41,30.48 72.52,30.48 72.26,30.73 72.26,32 72.39,32.13 73.41,32.13
+3V3_TPM on BOTTOM (solid shape): 76.2,31.88 76.2,30.61 76.07,30.48 75.31,30.48 75.18,30.61 75.18,31.88 75.31,32 76.07,32
+3V3_TPM on BOTTOM (solid shape): 76.45,24.26 76.45,22.99 76.2,22.73 75.44,22.73 75.18,22.99 75.18,24.26 75.31,24.38 76.33,24.38
+3V3_TPM on BOTTOM (solid shape): 70.79,23.32 70.79,22.28 70.61,22.1 68.2,22.1 68.07,22.23 68.07,23.24 68.2,23.37 70.74,23.37
+3V3_TPM_VSB on TOP (solid shape): 72,23.21 72,23.08 71.57,22.65 71.57,21.61 70.04,20.08 68.85,20.08 68.8,20.13 68.8,22.04 68.87,22.11 69.59,22.11 70.02,22.55 70.02,23 70.37,23.36 71.85,23.36
+3V3_TPM_VSB on BOTTOM (solid shape): 73.24,25.59 73.24,25.31 72.99,25.06 72.99,24.27 73.24,24.02 73.24,23.18 73.01,22.95 72.41,22.95 71.82,22.37 71.14,22.37 70.96,22.55 70.96,23.38 72.02,24.45 72.02,25.03 72.76,25.77 73.07,25.77
+3V3_VCCPCORE on BOTTOM (solid shape): 108.42,79.03 108.42,79.01 108.77,78.68 109.13,79.01 109.13,79.03 109.16,79.06 109.74,79.06 109.84,78.96 109.84,78.17 109.11,78.17 108.7,77.76 107.99,77.76 107.64,77.41 105.98,77.41 105.73,77.66 105.73,78.25 105.73,78.45 105.74,78.49 105.78,78.5 106.46,78.5 106.9,78.94 106.93,78.98 106.97,79.04 107,79.06 108.39,79.06
+3V3_VCCPCORE on IN1 (solid shape): 106.87,78.02 106.87,76.66 106.79,76.57 106.77,76.56 106.58,76.54 106.45,76.46 106.38,76.44 106.31,76.46 105.92,76.53 105.69,76.21 105.66,76.14 105.59,76.11 105.05,76.11 104.96,76.16 104.95,76.25 104.98,76.43 104.92,76.6 104.9,76.67 104.94,76.74 104.77,77.39 104.41,76.82 104.42,76.75 104.39,76.68 104.26,76.49 104.27,76.25 104.26,76.16 104.18,76.11 102.94,76.11 102.87,76.14 102.84,76.21 102.7,76.48 102.41,76.55 102.37,76.57 102.35,76.6 102.35,76.65 102.36,76.66 102.36,77.6 102.49,77.72 102.51,77.73 102.78,77.73 103.16,78.11 105.43,78.11 105.48,78.16 106.73,78.16
+3V3_VCCPTS on IN2 (solid shape): outline of 739 points within 97.21,81.05 104.07,87.38
+3V3_WLAN on TOP (solid shape): outline of 189 points within 169.42,61.85 191.26,66.17
+3V3_WLAN on BOTTOM (solid shape): 190.57,66.71 190.57,65.22 190.6,65.18 190.74,65.18 190.78,65.22 190.78,66.71 190.83,66.76 191.02,66.76 191.08,66.69 191.08,64.59 190.88,64.31 190.77,63.98 190.34,63.98 190.22,64.1 190.22,64.47 190.27,64.52 190.27,66.71 190.33,66.76 190.51,66.76
+3V3_WLAN on BOTTOM (solid shape): 173.56,67 173.56,64.77 173.3,64.52 172.47,64.52 172.43,64.54 172.35,64.59 172.27,64.62 172.19,64.65 172.1,64.67 172.01,64.69 171.92,64.69 171.84,64.69 171.75,64.67 171.66,64.65 171.58,64.62 171.5,64.59 171.42,64.54 171.38,64.52 171.2,64.52 170.26,63.58 167.98,63.58 167.81,63.75 167.81,65.22 173.28,65.22 173.28,66.79 173.05,66.79 173.05,65.22 167.81,65.22 167.81,66 168.02,66.22 169.93,66.22 170.83,67.12 173.44,67.12
+5V on TOP (solid shape): 203.58,64.14 203.58,63.25 203.83,62.99 203.83,61.98 203.58,61.72 202.82,61.72 202.12,62.42 202.12,64.2 202.18,64.26 203.45,64.26
+5V on TOP (solid shape): 54.43,8.85 54.43,7.59 54.42,7.58 54.42,6.67 54.17,6.42 52.14,6.42 51.88,6.67 51.88,9.01 52.24,9.36 53.91,9.36
+5V on TOP (solid shape): 14.06,97.92 14.08,97.91 14.09,97.9 14.25,97.75 14.41,97.6 15.49,96.52 17.59,96.52 17.86,96.25 17.86,94.18 17.6,93.93 15.33,93.93 14.65,94.61 13.46,94.61 11.38,96.7 11.38,97.74 11.56,97.92
+5V on TOP (solid shape): 178.5,24.32 178.5,21.45 178.22,21.17 175.12,21.17 174.6,21.69 176.43,21.69 176.44,21.64 176.45,21.59 176.47,21.54 176.5,21.49 176.53,21.45 176.57,21.41 176.62,21.38 176.67,21.36 176.72,21.35 176.77,21.34 176.83,21.34 176.88,21.35 176.93,21.36 176.98,21.38 177.03,21.41 177.07,21.45 177.1,21.49 177.13,21.54 177.15,21.59 177.16,21.64 177.17,21.69 177.17,21.75 177.16,21.8 177.14,21.85 177.11,21.9 177.08,21.94 177.05,21.98 177,22.02 176.96,22.04 176.91,22.06 176.85,22.07 176.8,22.08 176.75,22.07 176.69,22.06 176.64,22.04 176.6,22.02 176.55,21.98 176.52,21.94 176.48,21.9 176.46,21.85 176.44,21.8 176.43,21.75 176.43,21.69 174.6,21.69 173.83,22.47 173.83,24.04 174.23,24.45 178.37,24.45
+5V on TOP (solid shape): 36.63,13 36.63,12.17 37.16,11.63 37.16,9.68 37.36,9.47 44.12,9.47 44.26,9.34 44.26,7.69 44.01,7.43 42.13,7.43 41.49,8.07 36.52,8.07 35.67,8.92 35,8.92 34.8,9.12 34.8,9.55 34.79,9.56 34.79,11.74 35.61,11.74 35.61,11.69 35.61,11.63 35.63,11.58 35.65,11.54 35.68,11.49 35.72,11.45 35.76,11.42 35.81,11.39 35.86,11.37 35.91,11.36 35.96,11.36 36.01,11.36 36.07,11.37 36.12,11.39 36.16,11.42 36.2,11.45 36.24,11.49 36.27,11.54 36.29,11.58 36.31,11.63 36.32,11.69 36.32,11.74 36.31,11.79 36.29,11.84 36.27,11.89 36.24,11.94 36.2,11.98 36.16,12.01 36.12,12.04 36.07,12.05 36.01,12.07 35.96,12.07 35.91,12.07 35.86,12.05 35.81,12.04 35.76,12.01 35.72,11.98 35.68,11.94 35.65,11.89 35.63,11.84 35.61,11.79 35.61,11.74 34.79,11.74 34.79,11.98 34.52,12.24 34.52,12.98 34.62,13.08 36.55,13.08
+5V on BOTTOM (solid shape): 182.84,30.22 181.55,30.22 181.52,30.19 181.52,30.01 181.55,29.99 182.84,29.99 182.87,29.96 182.87,29.73 182.84,29.71 181.46,29.71 180.65,28.9 178.42,28.9 178.25,29.07 178.25,29.66 178.58,29.99 179.14,29.99 179.17,30.02 180.59,30.02 181.07,30.5 182.84,30.5
+5V on BOTTOM (solid shape): outline of 187 points within 25.07,30.48 36.88,64.87
+5V on IN1 (solid shape): 196.21,38.86 196.21,38.23 195.2,37.21 194.69,37.21 194.44,37.46 194.44,38.35 195.2,39.12 195.96,39.12
+5V on IN1 (solid shape): 29.02,34.1 29.02,31.49 28.7,31.17 25.74,31.17 25.59,31.31 25.59,33.72 26.1,34.23 28.9,34.23
+5V on IN1 (solid shape): 44.39,10.48 44.39,7.61 44.01,7.23 42.33,7.23 41.85,7.71 41.85,10.35 42.1,10.61 44.26,10.61
+5V on IN1 (solid shape): 182.99,20.33 183,20.33 183.25,20.08 183.25,19.07 183.01,18.82 183.01,18.41 182.75,18.16 181.74,18.16 181.36,18.54 181.36,20.45 181.61,20.7 182.63,20.7
+5V on IN2 (solid shape): 54.3,7.69 54.3,4.64 53.91,4.26 52.26,4.26 51.5,5.02 51.5,7.56 51.88,7.94 54.04,7.94
+5V on IN2 (solid shape): 44.57,9.26 44.57,7.08 44.16,6.67 42.69,6.67 42.43,6.92 42.43,9.26 42.58,9.41 44.42,9.41
+5V on IN2 (solid shape): 178.5,24.32 178.5,22.72 178.2,22.42 176.62,22.42 176.34,22.7 176.34,24.45 176.6,24.7 178.12,24.7
+5V on IN2 (solid shape): 180.17,30.42 180.35,30.17 180.66,30.14 180.66,29.15 180.28,28.77 179.01,28.77 178.88,28.9 178.88,30.29 179.01,30.42
+5V on IN2 (solid shape): outline of 863 points within 16.59,63.27 35.26,95.52
+5V on IN3 (solid shape): 196.41,39.74 197.64,39.74 197.88,39.5 197.88,39 196.47,37.59 195.33,37.59 195.07,37.85 195.07,39.62 195.2,39.75 196.41,39.75
+5V on IN3 (solid shape): 203.71,63.12 203.71,61.85 203.58,61.72 201.8,61.72 201.68,61.85 201.68,63.25 201.8,63.37 202.81,63.37 202.82,63.38 203.44,63.38
+5V on IN3 (solid shape): outline of 192 points within 176.14,16.51 182.05,23.62
+5V on IN3 (solid shape): outline of 210 points within 200.29,76.34 208.65,81.57
+5V_ADO_AVDD on BOTTOM (solid shape): 30.43,24.94 30.43,24.13 30.61,23.95 30.61,23.22 30.51,23.11 30.18,23.11 29.84,23.44 29.49,23.44 29.21,23.72 29.21,25.04 29.29,25.12 30.25,25.12
+5V_ADO_PVDD1 on TOP (solid shape): 33.46,15.18 34.99,15.18 35.31,14.86 35.31,13.77 35.15,13.61 33.35,13.61 33.25,13.72 31.77,13.72 31.62,13.86 31.62,15.37 31.75,15.49 33.15,15.49
+5V_ADO_PVDD1 on BOTTOM (solid shape): 33.66,19.56 33.66,18.92 33.02,18.29 33.02,17.27 32.89,17.14 32.89,14.35 32.77,14.22 31.37,14.22 31.24,14.35 31.24,15.45 31.98,16.18 31.98,16.58 31.24,17.32 31.24,18.29 32.2,19.24 32.23,19.25 32.25,19.24 32.6,19.26 32.77,19.58 32.79,19.65 32.87,19.68 33.53,19.68
+5V_ADO_PVDD2 on TOP (solid shape): 38.73,16.76 38.73,15.88 38.48,15.62 38.48,15.12 37,13.64 35.79,13.64 35.69,13.74 35.69,15.01 36.12,15.44 36.4,15.44 37.85,16.89 38.61,16.89
+5V_ADO_PVDD2 on BOTTOM (solid shape): 35.43,19.56 35.43,19.3 35.69,19.05 36.2,19.05 36.58,18.67 37.08,18.67 38.73,17.02 38.73,16 38.48,15.75 37.21,15.75 36.7,16.26 36.7,17.02 36.58,17.14 35.81,17.14 35.31,17.65 35.31,18.29 35.18,18.41 34.92,18.41 34.54,18.8 34.54,19.56 34.67,19.68 35.31,19.68
+5V_FAN on TOP (solid shape): 202.36,70.58 204.29,70.58 204.34,70.53 204.34,66.51 204.32,66.48 204.32,65.89 204.28,65.88 204.16,65.81 204.12,65.68 204.12,65.43 203.76,65.07 201.12,65.07 200.79,65.41 200.79,66.72 201,67.06 200.79,67.39 200.79,70.36 201.42,70.99 201.95,70.99
+5V_HDMI on TOP (solid shape): 12.45,95.12 12.45,94.49 12.39,94.43 10.35,94.43 9.19,95.59 7.79,95.59 7.11,96.27 7.11,97.03 7.37,97.28 10.29,97.28
+5V_HDMI on IN3 (solid shape): outline of 118 points within 6.77,90.14 13.64,95.15
+5V_PCU on TOP (solid shape): 196.8,64.69 196.8,64.36 196.7,64.26 196.47,64.26 196.09,63.88 196.09,62.99 195.78,62.68 195.78,61.89 195.76,61.87 195.61,61.87 195.57,61.9 195.57,63.98 195.96,64.36 195.96,64.59 196.14,64.77 196.72,64.77
+5V_PCU on TOP (solid shape): 67.59,54.64 67.59,54.28 67.01,53.7 67.01,52.79 66.6,52.39 66.6,51.56 66.59,51.55 66.33,51.55 66.32,51.56 66.32,52.48 66.5,52.65 66.5,53.72 66.6,53.82 66.6,54.31 67.03,54.74 67.49,54.74
+5V_PCU on TOP (solid shape): 20.22,65.1 20.22,63.69 20.47,63.69 20.47,65.1 20.52,65.15 20.82,65.15 20.87,65.1 20.87,63.69 21,63.69 21.02,63.67 21.02,63.57 21.36,63.57 21.56,63.37 21.56,62.92 21.2,62.55 19.93,62.55 19.73,62.75 17.69,62.75 17.54,62.91 17.54,63.44 17.64,63.54 18.98,63.54 19.05,63.47 19.68,63.47 19.81,63.6 19.81,63.69 19.82,63.69 19.82,65.08 19.89,65.15 20.17,65.15
+5V_PCU on BOTTOM (solid shape): 41.76,74.17 41.76,70.18 41.98,69.97 42.54,69.97 43.95,68.55 43.95,67.28 43.69,67.02 40.3,67.02 38.73,65.46 36.85,65.46 36.55,65.75 36.55,74.02 36.84,74.31 41.62,74.31
+5V_PCU on IN2 (solid shape): outline of 425 points within 18.77,60.88 38.63,69.47
+5V_PCU_USB3_P0 on TOP (solid shape): outline of 181 points within 10.96,64.97 20.88,71.25
+5V_PCU_USB3_P0 on IN2 (solid shape): outline of 119 points within 10.56,64.97 20.88,70
+5V_S5 on TOP (solid shape): 19.96,36.86 19.96,35.31 20.32,34.95 20.32,33.68 20.08,33.44 18.25,33.44 18.01,33.68 18.01,34.42 18.9,35.31 19.55,35.31 19.55,36.76 19.31,36.76 19.31,35.31 18.9,35.31 18.9,36.84 18.95,36.88 19.94,36.88
+5V_S5 on BOTTOM (solid shape): 44.54,66.22 44.54,65.78 44.29,65.53 43.95,65.53 43.81,65.39 43.81,64.39 43.56,64.14 41.15,64.14 41.02,64.26 41.02,65.41 41.24,65.62 41.24,66.28 41.36,66.4 44.36,66.4
+5V_S5 on BOTTOM (solid shape): 178.82,39.44 179.06,39.44 179.06,40.89 179.45,40.89 179.45,39.12 179.83,38.73 179.83,37.72 179.45,37.34 175.93,37.34 175.68,37.58 175.68,38.14 176.66,39.12 178.31,39.12 178.44,39.24 178.44,40.89 178.82,40.89
+5V_S5 on SVCC (solid shape): outline of 589 points within 16.45,15.69 184.85,70.55
+5V_S5_USB2 on BOTTOM (solid shape): outline of 219 points within 177.17,30.7 183.64,37.21
+5V_S5_USB3_P1 on TOP (solid shape): outline of 393 points within 10.95,38.73 19.96,45.66
+VCC_RTC on BOTTOM (solid shape): 83.57,45.52 83.57,44.75 83.31,44.5 81.91,44.5 81.79,44.63 81.79,45.52 81.91,45.64 83.44,45.64
+VCC_RTC on BOTTOM (solid shape): 71.75,43.05 71.75,42.04 71.63,41.91 70.5,41.91 69.98,42.43 69.65,42.43 69.61,42.45 69.6,42.48 69.6,43.05 69.85,43.31 71.5,43.31
+VCC_RTC on IN3 (solid shape): 70.87,43.81 70.87,42.67 70.61,42.42 69.6,42.42 69.22,42.8 69.22,44.07 69.47,44.32 70.36,44.32
+VCCIN on TOP (solid shape): 188.21,86.11 188.85,86.11 189.1,85.85 189.1,83.19 189.23,83.06 189.23,82.94 189.74,82.94 189.74,83.19 189.87,83.31 189.87,84.45 189.99,84.58 191.64,84.58 191.9,84.33 191.9,81.52 192.14,81.28 192.14,81.02 191.52,80.39 189.48,80.39 188.98,79.88 185.29,79.88 185.04,80.14 185.04,81.15 184.79,81.41 176.66,81.41 176.64,81.42 174.16,81.42 173.83,81.75 173.83,87.24 174.09,87.5 186.82,87.5
+VCCIN on TOP (solid shape): outline of 1492 points within 110.49,72.01 133.48,84.96
+VCCIN on BOTTOM (solid shape): outline of 8582 points within 111.75,71.63 190.12,95.82
+VCCIN on SVCC (solid shape): outline of 638 points within 110.81,71.57 184.47,104.59
+VCCPDSW on BOTTOM (solid shape): 115.38,71.8 115.38,70.93 115.36,70.91 112.08,70.91 111.95,71.03 111.95,71.72 112.21,71.97 115.2,71.97
+VCCPDSW on BOTTOM (solid shape): 104.51,71.8 104.51,71.06 103.62,70.17 103.45,70.17 103.43,70.18 103.41,70.19 103.19,70.33 102.93,70.28 102.9,70.27 102.87,70.29 102.78,70.37 102.78,70.98 102.84,71.04 102.86,71.05 103.35,71.01 103.47,71.49 103.47,72 103.67,72.2 104.11,72.2
AGND_ADO on TOP (solid shape): 25.79,18.44 26.02,18.29 26.29,18.23 26.36,18.23 26.42,18.17 26.83,17.98 27.28,18.07 27.3,18.08 27.33,18.07 27.51,18 27.69,17.97 27.98,17.97 28.06,17.94 28.08,17.86 28.23,17.53 28.59,17.5 28.62,17.51 29.17,16.96 30.17,16.96 30.2,16.93 30.2,16.18 31.1,16.18 31.44,15.85 31.44,12.34 31.1,12 29.44,12 29.44,13.5 29.13,13.82 27.9,13.82 27.58,13.5 27.58,12 21.95,12 19.92,9.97 11.41,9.97 10.9,9.46 3.97,9.46 3.92,9.5 3.92,9.51 3.37,10.24 2.5,10.51 0.51,10.51 0.51,10.51 0.51,15.92 0.58,16.01 0.7,15.97 0.91,15.77 1.19,15.7 2.01,15.7 2.5,15.96 2.58,16.6 2.66,16.64 3.44,16.64 3.52,16.6 3.53,16.5 3.58,16 4,15.71 4.01,15.71 5.83,13.89 14.59,13.89 15.26,14.57 22.13,14.57 23.83,16.27 23.83,17.74 22.89,18.68 22.87,18.79 22.96,18.85 25.38,18.85
AGND_ADO on TOP (solid shape): outline of 346 points within 28.52,24.07 38.04,30.64
AGND_ADO on TOP (solid shape): outline of 229 points within 0.51,15.42 31.51,29.91
AGND_ADO on BOTTOM (solid shape): outline of 920 points within 0.51,9.46 31.28,29.61
AGND_ADO on SGND (solid shape): outline of 82 points within 0.51,9.46 38.04,29.91
AGND_ADO on IN1 (solid shape): 8.91,25.51 3.32,25.51 3.32,26.52 8.91,26.52
AGND_ADO on IN1 (solid shape): 1.52,26.4 1.2,26.01 1.29,25.51 0.51,25.51 0.51,28.39 1.52,28.39
AGND_ADO on IN1 (solid shape): 1.52,11.52 2.5,11.52 4.06,10.98 4.95,9.59 4.93,9.5 4.85,9.46 3.93,9.46 3.39,10.22 2.5,10.51 0.51,10.51 0.51,10.51 0.51,15.53 1.52,15.53
AGND_ADO on IN2 (solid shape): 8.78,25.51 3.37,25.51 3.37,26.52 8.78,26.52
AGND_ADO on IN2 (solid shape): 1.52,26.52 1.11,26.11 1.11,25.51 0.51,25.51 0.51,28.39 1.52,28.39
AGND_ADO on IN2 (solid shape): 1.52,11.52 2.5,11.52 4.06,10.98 4.95,9.59 4.93,9.5 4.85,9.46 3.93,9.46 3.39,10.22 2.5,10.51 0.51,10.51 0.51,10.51 0.51,15.53 1.52,15.53
AGND_ADO on SVCC (solid shape): outline of 82 points within 0.51,9.46 38.04,29.91
AGND_ADO on IN3 (solid shape): 8.83,25.51 4.89,25.51 4.89,26.27 5.15,26.52 8.83,26.52
AGND_ADO on IN3 (solid shape): 1.52,14.11 1.52,11.52 2.5,11.52 4.06,10.98 4.95,9.59 4.93,9.5 4.85,9.46 3.93,9.46 3.39,10.22 2.5,10.51 0.51,10.51 0.51,10.51 0.51,14.69 0.95,14.69
AGND_ADO on IN3 (solid shape): 11.15,26.47 12.62,25.12 12.22,23.17 12.22,18.98 12.54,16.81 10.7,15.63 8.47,15.63 8.47,16.64 10.7,16.64 11.67,17.39 11.21,18.52 11.21,23.63 11.71,24.57 11.09,25.43 11.09,26.4
AGND_ADO on SGND1 (solid shape): outline of 82 points within 0.51,9.46 38.04,29.91
AGND_CPU on TOP (solid shape): 206.88,103 206.88,101.73 206.63,101.47 205.23,101.47 205.11,101.6 205.11,103.12 205.23,103.25 206.63,103.25
AGND_CPU on IN2 (solid shape): outline of 410 points within 196.98,93.28 207.78,103.39
AGND_DDR on TOP (solid shape): 199.14,59.18 199.14,58.29 199.01,58.17 198.12,58.17 197.97,58.32 197.97,58.61 197.49,59.1 197.49,59.31 197.61,59.44 198.88,59.44
AGND_DDR on IN2 (solid shape): 200.02,63.37 200.02,60.25 197.1,57.33 196.75,57.33 196.62,57.45 196.62,57.76 196.37,58.01 196.37,58.04 196.38,58.06 196.34,58.53 195.87,58.57 195.83,58.56 195.8,58.58 195.71,58.67 194.06,58.67 193.95,58.79 193.94,58.92 194.06,59.03 194.06,61.34 194.39,61.67 196.28,61.67 197.11,60.85 197.66,60.85 197.81,60.85 197.94,60.9 198.06,60.9 198.44,61.28 198.44,63.37 198.69,63.63 199.77,63.63
GND on TOP (solid shape): 209.3,103 209.3,101.73 209.17,101.6 207.77,101.6 207.64,101.73 207.64,103 207.9,103.25 209.04,103.25
GND on TOP (solid shape): 118.74,99.95 118.74,98.17 118.62,98.04 115.19,98.04 114.93,98.3 114.93,100.08 115.06,100.2 118.49,100.2
GND on TOP (solid shape): 58.04,57.91 58.8,57.91 59.05,57.66 59.05,54.86 58.8,54.61 56.13,54.61 56.01,54.74 56.01,58.04 56.13,58.17 57.78,58.17
GND on TOP (solid shape): 67.01,61.3 67.01,57.74 66.29,57.02 64.14,57.02 63.88,57.28 63.88,60.96 64.34,61.42 66.89,61.42
GND on TOP (solid shape): 90.91,48.07 86.8,48.07 86.8,25.7 166.9,25.7 166.9,47.98 168.3,47.98 168.3,24.3 85.4,24.3 85.4,49.47 90.91,49.47
GND on TOP (solid shape): 183.13,69.57 183.13,67.77 182.73,67.36 171.53,67.36 171.2,67.69 171.2,69.85 171.32,69.98 182.73,69.98
GND on TOP (solid shape): 210.07,83.18 210.07,66.42 206.76,66.42 206.12,67.06 206.12,74.36 205.3,75.18 205.3,81.73 207.58,84.01 209.24,84.01
GND on TOP (solid shape): 103.89,99.57 103.89,98.04 103.63,97.79 100.2,97.79 100.08,97.92 100.08,98.93 100.33,99.19 101.09,99.19 101.85,99.95 103.5,99.95
GND on TOP (solid shape): 17.27,37.59 17.27,35.31 17.08,35.12 17.08,34.61 16.58,34.1 13.91,34.1 13.34,34.68 13.34,37.67 13.59,37.92 16.94,37.92
GND on TOP (solid shape): 24.86,96.33 24.86,95.72 24.81,95.67 24.48,95.67 24.37,95.77 24.37,95.87 24.07,96.18 22.62,96.18 22.57,96.23 22.57,96.59 22.62,96.64 24.55,96.64
GND on TOP (solid shape): 67.72,46.99 67.75,46.98 67.77,46.94 67.77,46.44 67.17,45.85 65.53,45.85 65.28,46.1 65.28,46.86 65.41,46.99
GND on TOP (solid shape): 194.2,99.46 194.2,97.09 194.03,96.93 192.26,96.93 191.96,97.22 183.23,97.22 183.17,97.27 183.17,99.33 183.23,99.38 191.71,99.38 191.96,99.63 194.02,99.63
GND on TOP (solid shape): 196.21,55.75 196.21,54.61 195.83,54.23 191.01,54.23 190.75,54.48 190.75,55.37 190.88,55.5 192.02,55.5 192.15,55.63 193.17,55.63 193.42,55.88 196.09,55.88
GND on TOP (solid shape): 52.45,79.51 52.45,76.45 52.58,76.33 52.58,74.55 51.94,73.91 49.91,73.91 49.66,74.17 49.66,79.25 49.98,79.57 52.39,79.57
GND on TOP (solid shape): 201.8,60.74 201.8,59.93 200.53,58.66 200.53,58.32 200.51,58.29 199.77,58.29 199.64,58.42 199.64,59.56 199.9,59.82 199.9,60.33 200.4,60.82 201.72,60.82
GND on TOP (solid shape): 206.43,86.65 206.43,84.38 206.15,84.1 201.83,84.1 201.52,84.4 201.52,87.1 202.26,87.84 202.26,87.86 202.28,87.89 202.31,87.91 205.17,87.91
GND on TOP (solid shape): 198.03,63.35 198.03,62.84 198.2,62.68 198.2,61.85 197.94,61.59 197.54,61.59 197.4,61.46 196.4,61.46 196.38,61.47 196.38,61.89 197.1,62.61 197.1,63.32 197.23,63.45 197.93,63.45
GND on TOP (solid shape): 203.98,9.62 203.98,7.79 203.72,7.53 202.71,7.53 202.71,7.53 200.83,7.53 200.57,7.79 200.57,8.45 200.73,8.6 202,8.6 202.2,8.8 202.2,9.51 202.45,9.77 203.82,9.77
GND on TOP (solid shape): 61.47,78.49 61.47,75.31 61.34,75.18 60.33,75.18 59.44,74.3 59.44,73.15 59.18,72.9 57.4,72.9 57.15,73.15 57.15,73.91 56.77,74.3 56.77,78.74 56.9,78.87 61.09,78.87
GND on TOP (solid shape): 211.59,83.82 211.59,52.36 211.57,52.34 210.31,52.34 210.2,52.45 208.37,52.45 208.07,52.76 208.07,53.12 210.58,55.64 210.58,83.71 210.86,83.99 211.42,83.99
GND on TOP (solid shape): 195.77,59.62 195.77,58.86 195.87,58.76 195.91,58.76 196.1,58.57 196.14,58.57 196.34,58.37 196.34,57.43 196.19,57.28 195.96,57.28 195.78,57.45 195.78,58.55 195.75,58.58 195.75,58.61 195.58,58.78 195.58,59.62 195.6,59.65 195.75,59.65
GND on TOP (solid shape): 18.26,72.21 18.24,72.18 18.19,71.95 18.29,71.73 18.29,69.6 18.16,69.47 14.12,69.47 14.07,69.52 14.07,71.73 14.22,71.88 15.37,71.88 15.49,72.01 15.49,72.52 15.77,72.8 17.68,72.8
GND on TOP (solid shape): 45.49,79.48 45.49,77.01 45.19,76.71 45.19,73.51 43.75,72.08 43.75,69.72 43.53,69.49 38.38,69.49 36.78,67.89 31.81,67.89 31.69,68.01 31.69,70.62 31.69,70.62 31.69,71.37 31.69,71.37 31.69,71.49 31.96,71.76 36.58,71.76 44.39,79.57 45.41,79.57
GND on TOP (solid shape): 211.59,26.15 209.41,26.15 209.19,26.38 208.06,26.38 208.04,26.43 208.03,26.48 207.86,26.83 207.58,27.1 207.58,29.52 207.72,29.72 207.8,29.94 207.83,29.96 209.34,29.96 209.51,30.13 211.59,30.13
GND on TOP (solid shape): 115.81,95.89 115.84,95.87 115.86,95.83 115.86,94.45 116.56,94.45 117.04,93.97 117.04,93.02 116.77,92.75 116.69,92.73 116.61,92.71 115.31,92.71 115.27,92.72 115.26,92.76 115.26,94.14 113.72,94.14 113.68,94.16 113.67,94.19 113.67,95.83 113.68,95.87 113.72,95.89
GND on TOP (solid shape): 47.07,61.72 47.07,61.49 47.07,61.49 47.07,61.43 47.13,61.43 47.14,61.42 47.93,61.42 47.97,61.41 48.01,61.4 48.2,61.4 48.78,60.82 48.8,60.43 49.12,60.2 49.12,56.77 48.77,56.41 47.29,56.41 46.81,56.9 46.48,56.9 46.2,57.18 46.2,60.55 46.15,60.61 46.15,61.72 46.16,61.76 46.2,61.77 47.02,61.77
GND on TOP (solid shape): 194.56,79.63 194.56,77.98 195.35,77.2 195.56,76.99 195.58,76.96 195.99,76.56 196.09,76.33 196.32,76.23 196.47,76.07 196.47,75.49 196.34,75.36 196.34,74.04 196.09,73.79 194.82,73.79 194.31,73.28 193.44,73.28 193.42,73.28 193.17,73.02 191.77,73.02 191.69,73.1 191.69,74.98 192.71,74.98 193.17,75.44 193.17,76.2 192.4,76.96 192.4,79.76 192.53,79.88 194.31,79.88
GND on TOP (solid shape): 42.04,35.18 42.04,31.37 41.6,30.93 33.47,30.93 33.09,31.31 33.09,33.51 40.31,33.51 40.31,33.46 40.33,33.4 40.35,33.35 40.38,33.31 40.42,33.26 40.46,33.23 40.5,33.19 40.55,33.17 40.61,33.15 40.66,33.15 40.72,33.15 40.77,33.15 40.83,33.17 40.88,33.19 40.92,33.23 40.97,33.26 41,33.31 41.03,33.35 41.05,33.4 41.07,33.46 41.07,33.51 41.07,33.57 41.06,33.62 41.04,33.68 41.02,33.73 40.98,33.77 40.95,33.81 40.9,33.85 40.85,33.87 40.8,33.89 40.75,33.91 40.69,33.91 40.64,33.91 40.58,33.89 40.53,33.87 40.48,33.85 40.44,33.81 40.4,33.77 40.36,33.73 40.34,33.68 40.32,33.62 40.31,33.57 40.31,33.51 33.09,33.51 33.09,34.48 34.36,35.75 41.47,35.75
GND on TOP (solid shape): 111.07,77.56 111.09,77.56 111.1,77.55 111.3,77.47 111.5,77.55 111.52,77.56 111.53,77.56 111.9,77.56 112.05,77.41 112.05,76.47 111.88,76.29 111.58,76.29 111.55,76.3 111.54,76.31 111.31,76.43 111.08,76.33 111.04,76.31 111.01,76.32 110.93,76.35 110.85,76.35 110.77,76.34 110.7,76.36 110.66,76.4 110.62,76.43 110.59,76.5 110.59,76.65 110.56,76.71 110.56,76.72 110.56,77.46 110.66,77.56
GND on TOP (solid shape): 33.2,13.18 33.99,13.18 34.32,12.85 34.32,10.64 34.54,10.41 34.54,9.45 34.39,9.3 29.9,9.3 29.46,9.73 29.46,10.67 29.72,10.92 30.65,10.92 30.74,10.87 30.75,10.78 31.06,10.26 31.38,10.78 31.39,10.87 31.47,10.92 31.5,10.92 31.56,10.98 31.64,11.01 31.71,10.97 32.28,10.95 32.16,11.5 32.15,11.5 32.13,11.53 32.13,13.41 32.23,13.51 32.87,13.51
GND on TOP (solid shape): outline of 163 points within 36.98,9.65 41.21,13.78
GND on TOP (solid shape): outline of 187 points within 63.69,31.31 74.06,38.55
GND on TOP (solid shape): outline of 211 points within 167.09,73.28 191.39,88.46
GND on TOP (solid shape): outline of 454 points within 43.12,9.85 58.87,24.7
GND on TOP (solid shape): outline of 856 points within 109.13,69.75 136.69,73.44
GND on TOP (solid shape): outline of 1056 points within 47.92,24.7 59.4,38.7
GND on TOP (solid shape): outline of 1038 points within 102.72,71.79 109.64,81.32
GND on TOP (solid shape): outline of 1200 points within 0.51,68.72 211.59,106.11
GND on TOP (solid shape): outline of 1239 points within 0.51,29.4 43.63,65.09
GND on TOP (solid shape): outline of 2744 points within 168.47,24.96 202.1,56.2
GND on TOP (solid shape): outline of 4095 points within 1.51,0.51 211.59,27.85
GND on BOTTOM (solid shape): 92.08,57.02 88.52,57.02 88.52,59.05 92.08,59.05
GND on BOTTOM (solid shape): 31.19,78.6 31.19,77.94 31.14,77.89 29.01,77.89 28.75,78.15 28.75,78.76 28.91,78.91 30.89,78.91
GND on BOTTOM (solid shape): 57.15,92.2 57.15,90.93 57.02,90.8 54.48,90.8 54.36,90.93 54.36,92.2 54.48,92.33 57.02,92.33
GND on BOTTOM (solid shape): 120.02,7.63 120.02,5.59 119.64,5.21 118.5,5.21 118.24,5.47 118.24,8.01 118.37,8.13 119.51,8.13
GND on BOTTOM (solid shape): 130.43,11.68 130.43,10.67 129.29,9.52 126.24,9.52 125.09,10.67 125.09,11.56 125.35,11.81 130.3,11.81
GND on BOTTOM (solid shape): 177.99,29.53 177.99,27.88 177.87,27.75 176.72,27.75 176.34,28.13 176.34,29.53 176.47,29.66 177.87,29.66
GND on BOTTOM (solid shape): 197.74,48.51 197.74,46.38 197.58,46.23 195.2,46.23 194.82,46.61 194.82,48.51 195.07,48.77 197.49,48.77
GND on BOTTOM (solid shape): 139.83,7.17 139.83,5.21 139.7,5.08 135.1,5.08 135,5.18 135,7.19 135.18,7.37 139.63,7.37
GND on BOTTOM (solid shape): 45.92,53.92 45.92,50.67 45.61,50.36 43.11,50.36 42.42,51.05 42.42,53.92 42.7,54.2 45.64,54.2
GND on BOTTOM (solid shape): 57.91,57.91 58.67,57.91 59.05,57.53 59.05,54.99 58.8,54.74 56.39,54.74 56.13,54.99 56.13,58.29 56.39,58.55 57.28,58.55
GND on BOTTOM (solid shape): 132.55,56.44 133.1,56.44 134.09,55.45 134.09,54.38 133.73,54.03 130.86,54.03 129.36,55.52 129.36,56.82 129.41,56.87 132.12,56.87
GND on BOTTOM (solid shape): 203.67,9.01 204.43,9.01 204.59,8.85 204.59,8.19 204.43,8.04 202.76,8.04 202.1,8.7 202.1,9.41 202.3,9.62 203.06,9.62
GND on BOTTOM (solid shape): 211.59,26.15 209.36,26.15 209.13,26.38 208.6,26.38 207.58,27.4 207.58,29.45 208.08,29.95 209.3,29.95 209.48,30.13 211.59,30.13
GND on BOTTOM (solid shape): 52.64,79.44 52.64,78.11 52.45,77.92 52.45,74.42 51.94,73.91 49.91,73.91 49.66,74.17 49.66,79.63 49.85,79.82 52.26,79.82
GND on BOTTOM (solid shape): 132.08,80.64 132.08,77.98 131.95,77.85 115.57,77.85 115.44,77.98 115.44,80.64 115.57,80.77 131.95,80.77
GND on BOTTOM (solid shape): 47.75,60.71 48.11,60.71 48.27,60.55 49.22,60.55 49.28,60.49 49.28,55.63 48.64,54.99 46.23,54.99 45.97,55.25 45.97,60.83 46.1,60.96 47.5,60.96
GND on BOTTOM (solid shape): 101.73,96.39 101.73,93.5 100.94,92.71 100.46,92.71 100.33,92.84 100.33,96.39 100.46,96.52 101.6,96.52
GND on BOTTOM (solid shape): 124.64,73.61 131.98,73.61 132,73.58 132,72.42 131.53,71.95 124.4,71.95 123.89,72.46 117.16,72.46 117.03,72.58 117.03,73.98 117.29,74.23 124.02,74.23
GND on BOTTOM (solid shape): 36.7,23.37 36.7,22.35 37.08,21.97 37.08,21.34 36.75,21.01 36.75,19.99 36.7,19.94 32.77,19.94 32,20.7 31.7,20.7 31.26,21.15 31.26,22.04 31.75,22.53 31.75,23.49 31.88,23.62 36.45,23.62
GND on BOTTOM (solid shape): 188.74,102.38 188.74,101.41 189.19,100.95 192.85,100.95 193.18,100.62 193.18,97.2 192.78,96.8 192.78,95.73 194.41,94.11 194.76,94.11 194.76,93.96 193.8,93.96 193.8,93.83 192.64,93.83 192.03,93.22 186.9,93.22 183.81,96.31 183.51,96.31 183.43,96.35 183.42,96.45 183.43,96.69 183.29,96.88 183.28,96.9 183.28,99.43 183.68,99.83 183.68,101.49 184.93,102.73 188.38,102.73
GND on BOTTOM (solid shape): 139.19,95.63 139.19,94.23 139.06,94.11 135.64,94.11 135.51,94.23 135.51,95.23 135.57,95.33 135.67,95.31 136.11,95.32 136.22,95.74 136.22,95.84 136.31,95.89 138.94,95.89
GND on BOTTOM (solid shape): 130.25,95.89 130.33,95.84 130.35,95.75 130.68,95.27 131.02,95.75 131.03,95.84 131.11,95.89 134.11,95.89 134.24,95.76 134.24,94.23 134.11,94.11 126.36,94.11 126.24,94.23 126.24,95.12 127,95.89
GND on BOTTOM (solid shape): 107.81,81.55 108.6,81.55 109.01,81.14 109.51,81.14 110.07,81.14 110.48,80.74 110.48,80.26 110.5,80.24 110.5,78.9 110.48,78.87 110.47,78.86 110.4,78.77 110.3,78.73 110.2,78.73 110.05,78.88 110.05,79.09 109.97,79.16 109.11,79.16 109.1,79.19 108.77,79.39 108.45,79.19 108.44,79.17 108.41,79.16 107.41,79.16 106.92,79.64 106.92,80.85 107.11,81.04 107.11,81.46 107.33,81.68 107.69,81.68
GND on BOTTOM (solid shape): 151.97,14.79 152.04,14.76 152.09,14.71 152.09,12.47 152.05,12.46 151.84,12.32 151.77,12.09 151.77,12.07 151.58,11.88 150.58,11.88 150.37,11.94 150.17,11.88 150.16,11.88 150.05,11.88 149.93,12 149.93,12.98 149.79,13.12 149.72,13.17 149.63,13.19 149.33,13.19 149.17,13.34 149.17,13.77 149.27,13.86 149.34,13.99 149.34,14 149.73,14.39 150.89,14.39 151.22,14.72 151.5,14.72 151.52,14.73 151.54,14.72 151.73,14.7 151.9,14.77
GND on BOTTOM (solid shape): 183.73,103.78 183.83,103.72 183.81,103.61 182.8,102.61 182.77,102.61 182.28,102.33 182.46,101.79 182.46,100.69 182.35,100.25 182.74,100.03 182.75,100.03 182.8,100 182.79,99.94 182.76,99.91 182.01,99.91 181.31,99.76 182.01,99.61 182.62,99.61 182.67,99.56 182.67,97.14 182.49,96.97 182.21,96.97 180.91,98.27 177.04,98.27 176.89,98.43 176.89,99.6 181.07,103.78
GND on BOTTOM (solid shape): 148.59,82.43 148.59,75.26 148.44,75.12 144.38,75.12 144.14,75.35 144.14,80.16 144.2,80.25 144.31,80.24 144.88,80.52 144.31,80.8 144.2,80.79 144.14,80.88 144.14,81.3 144.2,81.39 144.31,81.38 144.88,81.66 144.31,81.94 144.2,81.93 144.14,82.02 144.14,82.22 144.4,82.47 144.43,82.46 144.61,82.46 144.78,82.55 148.47,82.55
GND on BOTTOM (solid shape): 104.76,77.3 104.8,77.28 104.82,77.25 104.82,77.23 105.27,77.23 105.63,76.88 105.63,76.22 105.61,76.18 105.58,76.16 104.68,76.16 104.21,75.69 104.21,75.33 104.42,75.12 104.56,75.12 104.74,74.95 104.74,74.14 104.57,73.98 104.55,73.97 104.47,73.98 104.41,73.98 104.17,73.83 104.11,73.54 104.09,73.46 104.01,73.42 103.71,73.42 103.42,73.13 103.42,72.09 103.37,72.04 103.37,71.74 103.29,71.67 103.08,71.7 102.89,71.62 102.87,71.63 102.68,71.82 102.68,72.06 102.69,72.09 102.7,72.11 102.85,72.39 102.7,72.67 102.69,72.69 102.68,72.72 102.68,72.96 102.69,72.99 102.71,73.01 102.77,73.06 102.82,73.12 102.86,73.22 102.88,73.32 102.88,73.35 103.16,73.63 103.25,73.63 103.39,73.69 103.45,73.83 103.45,74.13 103.44,74.16 103.44,74.81 103.45,74.85 103.45,75.15 103.44,75.18 103.44,75.62 103.45,75.65 103.58,75.74 103.62,75.86 103.64,75.97 103.64,76.02 103.64,77.08 103.64,77.1 103.65,77.12 103.83,77.29 104.59,77.29 104.6,77.3
GND on BOTTOM (solid shape): outline of 185 points within 0.51,43.83 22.55,60.77
GND on BOTTOM (solid shape): outline of 222 points within 0.51,29.4 24.77,71.52
GND on BOTTOM (solid shape): outline of 243 points within 28.39,24.58 41.21,44.52
GND on BOTTOM (solid shape): outline of 439 points within 198.12,54.07 211.59,89.18
GND on BOTTOM (solid shape): outline of 416 points within 59.12,54.04 76.27,73.6
GND on BOTTOM (solid shape): outline of 649 points within 165.67,66.36 197.93,93.12
GND on BOTTOM (solid shape): outline of 1829 points within 0.51,66.89 211.59,106.11
GND on BOTTOM (solid shape): outline of 1887 points within 1.51,0.51 211.59,36.13
GND on SGND (solid shape): outline of 2274 points within 0.51,0.51 211.59,106.11
GND on IN1 (solid shape): 92.08,57.02 88.52,57.02 88.52,59.05 92.08,59.05
GND on IN1 (solid shape): 193.87,100.65 193.87,97.22 193.74,97.09 183.5,97.09 183.35,97.25 183.35,100.83 183.56,101.03 193.49,101.03
GND on IN1 (solid shape): 211.59,83.82 211.59,54.31 211.4,54.12 210.78,54.12 210.58,54.32 210.58,55.59 210.58,55.59 210.58,83.83 210.76,84.01 211.39,84.01
GND on IN1 (solid shape): 117.07,95.43 117.07,94.6 117.48,94.2 117.48,93.25 117.44,93.2 117.39,93.22 117.37,93.24 114.03,93.24 113.79,93.47 113.79,95.7 113.81,95.74 113.84,95.75 116.76,95.75
GND on IN1 (solid shape): 211.59,26.15 209.39,26.15 209.16,26.38 208.05,26.38 207.89,26.79 207.58,27.1 207.58,29.52 207.72,29.72 207.8,29.94 207.83,29.96 209.39,29.96 209.56,30.13 211.59,30.13
GND on IN1 (solid shape): 211.1,106.11 211.45,105.97 211.59,105.62 211.59,96.4 211.37,96.18 210.81,96.18 210.58,96.41 210.58,105.1 172.75,105.1 172.59,105.5 172.33,105.86 172.33,106.11
GND on IN1 (solid shape): 11.5,34.45 12.51,33.44 12.51,30.04 11.88,29.4 0.51,29.4 0.51,32.11 9.98,32.11 10.95,32.86 10.49,33.99 10.49,37.61 11.5,37.61
GND on IN1 (solid shape): 14.49,6.21 14.49,3.53 16.5,1.52 57.81,1.52 57.81,3.52 77,3.52 79.64,6.16 86.4,6.16 91.04,1.52 152.09,1.52 155.35,4.79 160.37,4.79 163.08,7.51 182.87,7.51 185.54,4.84 195.52,4.84 196.94,6.26 200.68,6.26 202.8,4.13 205.98,4.13 206.83,3.22 207.81,3.98 209.06,3.98 209.06,3.98 209.51,3.98 209.67,4.13 211.59,4.13 211.59,1 211.45,0.65 211.1,0.51 76.04,0.51 76.04,2.51 58.82,2.51 58.82,0.51 2,0.51 1.65,0.65 1.51,1 1.51,7.49 1.51,7.49 2.5,7.49 3.34,7.75 3.9,8.44 3.91,8.45 12.26,8.45
GND on IN1 (solid shape): outline of 168 points within 0.51,43.8 15.92,60.67
GND on IN1 (solid shape): outline of 801 points within 0.51,67.1 169.33,106.11
GND on IN2 (solid shape): 193.87,100.65 193.87,97.22 193.74,97.09 183.5,97.09 183.35,97.25 183.35,100.83 183.56,101.03 193.49,101.03
GND on IN2 (solid shape): 211.59,83.76 211.59,54.32 211.39,54.12 210.78,54.12 210.58,54.32 210.58,83.83 210.63,83.89 211.46,83.89
GND on IN2 (solid shape): 211.59,26.15 209.39,26.15 209.18,26.36 208.06,26.36 207.89,26.77 207.58,27.1 207.58,29.52 207.72,29.72 207.81,29.96 207.81,29.96 209.36,29.96 209.53,30.13 211.59,30.13
GND on IN2 (solid shape): 211.1,106.11 211.45,105.97 211.59,105.62 211.59,96.28 211.5,96.18 210.76,96.18 210.58,96.36 210.58,105.1 172.75,105.1 172.59,105.51 172.33,105.86 172.33,106.11
GND on IN2 (solid shape): 11.5,34.45 11.85,33.88 12,33.22 12.13,33.09 12.13,30.04 11.5,29.4 0.51,29.4 0.51,32.11 9.98,32.11 10.95,32.86 10.49,33.99 10.49,37.66 11.5,37.66
GND on IN2 (solid shape): 4.83,8.45 4.87,8.44 4.9,8.42 12.51,8.42 13.48,7.46 13.48,2.99 14.95,1.52 57.81,1.52 57.81,3.52 77.05,3.52 79.67,6.14 89.37,6.14 93.99,1.52 151.43,1.52 154.42,4.51 160.52,4.51 163.77,7.76 174.23,7.76 177.66,4.34 194.22,4.34 195.82,5.93 199.89,5.93 201.69,4.13 205.98,4.13 206.83,3.22 207.81,3.98 207.84,4 209.57,4 209.7,4.13 211.59,4.13 211.59,1 211.45,0.65 211.1,0.51 76.04,0.51 76.04,2.51 58.82,2.51 58.82,0.51 2,0.51 1.65,0.65 1.51,1 1.51,7.49 1.51,7.49 2.5,7.49 3.34,7.75 3.9,8.44 3.91,8.45
GND on IN2 (solid shape): outline of 170 points within 0.51,44.03 15.76,60.7
GND on IN2 (solid shape): outline of 1105 points within 0.51,68.9 169.33,106.11
GND on SVCC (solid shape): 210.07,96.16 210,96.16 209.93,96.16 209.43,96.16 208.17,95.66 207.62,94.43 206.27,94.43 206.19,94.51 206.19,97.85 206.15,98.05 206.04,98.22 200.47,103.78 200.47,104.12 200.94,104.59 210.07,104.59
GND on SVCC (solid shape): outline of 436 points within 89.22,27.24 164.91,73.85
GND on SVCC (solid shape): outline of 506 points within 0.51,29.4 26.49,104.29
GND on SVCC (solid shape): outline of 218 points within 1.51,0.51 211.59,88.46
GND on IN3 (solid shape): 193.87,100.65 193.87,97.22 193.74,97.09 183.5,97.09 183.35,97.25 183.35,100.83 183.56,101.03 193.49,101.03
GND on IN3 (solid shape): 211.59,83.76 211.59,54.26 211.5,54.17 210.83,54.17 210.58,54.42 210.58,83.83 210.76,84.01 211.34,84.01
GND on IN3 (solid shape): 117.42,95.48 117.46,95.46 117.48,95.43 117.48,93.66 117.13,93.32 113.72,93.32 113.68,93.33 113.67,93.37 113.67,95.48 113.67,95.48
GND on IN3 (solid shape): 211.59,26.15 209.36,26.15 209.16,26.36 208.06,26.36 207.89,26.77 207.58,27.1 207.58,29.52 207.72,29.71 207.8,29.93 207.83,29.96 209.29,29.96 209.46,30.13 211.59,30.13
GND on IN3 (solid shape): 211.1,106.11 211.45,105.97 211.59,105.62 211.59,96.45 211.42,96.28 210.71,96.28 210.58,96.41 210.58,105.1 172.75,105.1 172.59,105.51 172.33,105.86 172.33,106.11
GND on IN3 (solid shape): 11.5,35.11 12.89,33.72 12.89,29.91 12.56,29.58 3.78,29.58 3.6,29.4 0.51,29.4 0.51,32.11 9.98,32.11 10.95,32.86 10.49,33.99 10.49,37.73 11.5,37.73
GND on IN3 (solid shape): 4.83,8.45 4.88,8.44 4.91,8.4 4.94,8.36 8.11,8.36 8.12,8.37 13.17,8.37 14.59,6.95 14.59,3.11 16.19,1.52 57.81,1.52 57.81,3.52 76.49,3.52 79.14,6.16 95.78,6.16 100.42,1.52 117.89,1.52 117.9,1.52 151.4,1.52 154.92,5.04 160.75,5.04 164.12,8.42 174.64,8.42 177.84,5.22 196.15,5.22 197.47,6.54 200.35,6.54 202.75,4.13 205.98,4.13 206.83,3.22 207.81,3.98 209.62,3.98 209.77,4.13 211.59,4.13 211.59,1 211.45,0.65 211.1,0.51 76.04,0.51 76.04,2.51 58.82,2.51 58.82,0.51 2,0.51 1.65,0.65 1.51,1 1.51,7.49 1.51,7.49 2.5,7.49 3.34,7.75 3.9,8.44 3.91,8.45
GND on IN3 (solid shape): outline of 161 points within 0.51,43.86 15.94,60.67
GND on IN3 (solid shape): outline of 743 points within 0.51,67 169.33,106.11
GND on SGND1 (solid shape): outline of 2273 points within 0.51,0.51 211.59,106.11
VIN on TOP (solid shape): 27.37,69.92 27.37,65.98 27.12,65.73 24.98,65.73 24.32,66.39 24.32,70.04 24.58,70.3 26.99,70.3
VIN on TOP (solid shape): 194.2,103.16 194.2,100.04 194.05,99.89 187.39,99.89 187.14,99.63 184.98,99.63 184.85,99.76 184.85,103.19 185.11,103.44 193.92,103.44
VIN on TOP (solid shape): 197.87,69.72 197.87,66.93 197.61,66.67 194.94,66.67 193.04,68.58 193.04,69.6 193.29,69.85 197.74,69.85
VIN on TOP (solid shape): 207.67,93.62 207.67,92.09 206.83,91.22 206.25,90.14 206.23,90.08 206.21,90.01 206.09,89.88 202.94,89.88 202.69,90.12 202.69,93.6 202.95,93.85 207.44,93.85
VIN on TOP (solid shape): 41.58,57.53 41.58,55.91 43.13,54.36 63.25,54.36 63.37,54.23 63.37,51.16 62.92,50.7 46.05,50.7 45.94,50.81 45.85,50.98 45.68,51.07 45.49,51.26 42.09,51.26 40.06,53.29 40.06,54.76 39.75,55.07 39.19,55.07 39.19,55.06 39.15,55.06 38.81,55.4 38.81,57.19 39.31,57.68 39.61,57.68 40.16,58.23 40.88,58.23
VIN on BOTTOM (solid shape): 62.99,53.85 62.99,51.94 62.36,51.31 55.63,51.31 55.25,50.93 46.48,50.93 46.1,51.31 46.1,53.97 46.48,54.36 62.48,54.36
VIN on BOTTOM (solid shape): 185.17,46.48 185.17,42.93 184.91,42.67 182.63,42.67 181.48,43.81 181.48,46.61 181.61,46.74 184.91,46.74
VIN on BOTTOM (solid shape): 141.94,18.4 141.94,13.47 140.91,12.45 140.91,9.02 139.76,7.87 133.54,7.87 133.29,8.13 133.29,11.56 134.81,13.08 137.35,13.08 137.64,13.37 137.64,16.54 137.35,16.83 134.49,16.83 133.29,15.62 130.94,15.62 130.29,16.27 129.07,16.27 129.07,19.9 129.24,20.07 140.27,20.07
VIN on SVCC (solid shape): outline of 1147 points within 45.02,6.14 208.52,103.82
670_SW on TOP (solid shape): 57.78,67.06 57.78,63.35 57.07,62.64 57.07,61.98 56.95,61.85 56.52,61.85 56.43,61.76 56.26,61.76 56.26,61.6 56.26,61.59 56.26,60.45 56.13,60.33 54.61,60.33 54.51,60.43 55.6,60.43 55.6,61.09 55.21,61.09 55.21,60.43 54.51,60.43 54.28,60.66 54.28,61.46 55.69,61.46 55.69,62.55 55.2,62.55 55.2,61.46 54.28,61.46 54.28,61.93 53.85,62.36 53.85,62.7 53.85,62.71 53.86,62.74 53.87,62.76 53.9,62.78 53.92,62.79 53.95,62.8 53.99,62.79 54.05,62.79 54.1,62.8 54.16,62.81 54.21,62.84 54.25,62.87 54.29,62.9 54.33,62.95 54.36,62.99 54.38,63.04 54.39,63.1 54.4,63.15 54.39,63.21 54.38,63.26 54.36,63.31 54.34,63.36 54.3,63.41 54.26,63.44 54.22,63.48 54.17,63.5 54.12,63.52 54.08,63.53 53.85,63.75 53.85,64.39 52.96,65.28 52.96,67.06 53.34,67.44 57.4,67.44
671_SW on TOP (solid shape): 49.28,67.18 49.28,65.02 47.75,63.5 47.24,63.5 47.18,63.44 47.07,63.44 47.07,62.05 46.99,61.98 45.47,61.98 45.34,62.1 46.41,62.1 46.41,62.76 46.01,62.76 46.01,62.1 45.34,62.1 45.08,62.36 45.08,63.14 46.5,63.14 46.5,64.23 46,64.23 46,63.14 45.08,63.14 45.08,66.93 45.47,67.31 49.15,67.31
24707_LX on TOP (solid shape): 131.56,8.64 131.56,7.42 131.31,7.16 130.04,7.16 129.86,7.34 129.86,8.69 129.96,8.79 131.41,8.79
24707_LX on BOTTOM (solid shape): 132.66,10.5 132.66,8.05 133.22,7.49 134.21,7.49 134.4,7.31 134.4,4.03 134.18,3.81 127.13,3.81 127,3.94 127,8.74 127.38,9.14 129.41,9.14 130.94,10.67 132.5,10.67
24707_LX on BOTTOM (solid shape): 145.19,10.64 145.19,9.93 145.34,9.78 146.1,9.78 146.13,9.75 146.13,9.55 146.1,9.52 145.19,9.52 145.03,9.68 144.14,9.68 143.84,9.98 143.13,9.98 142.9,10.21 142.9,11.02 143,11.13 144.7,11.13
24707_LX on IN3 (solid shape): 131.56,8.64 131.56,7.42 131.31,7.16 130.04,7.16 129.86,7.34 129.86,8.69 129.96,8.79 131.41,8.79
24707_LX on IN3 (solid shape): 145.16,11.13 145.16,10.11 145.03,9.98 143.89,9.98 143.79,10.08 143.79,11.25 143.92,11.38 144.91,11.38
24737_DH on BOTTOM (solid shape): 133.12,12.5 133.12,11.46 132.59,10.92 131.62,10.92 131.34,11.2 131.34,12.29 131.78,12.73 132.89,12.73
24737_DH on BOTTOM (solid shape): 145.26,9.27 146.1,9.27 146.13,9.25 146.13,9.04 146.1,9.02 145.34,9.02 145.26,8.94 143.94,8.94 143.79,9.09 143.79,9.4 143.94,9.55 144.98,9.55
24737_DH on IN1 (solid shape): 133.35,12.12 133.35,10.97 133.22,10.85 131.83,10.85 131.5,11.18 131.5,12.04 131.7,12.24 133.22,12.24
24737_DH on IN1 (solid shape): 145.31,9.42 145.31,8.56 144.98,8.23 143.33,8.23 143.08,8.48 143.08,9.35 143.38,9.65 145.08,9.65
24737_DL on BOTTOM (solid shape): 138.52,4.55 138.52,3.94 138.34,3.76 137.21,3.76 137.16,3.81 135.13,3.81 135,3.94 135,4.7 135.13,4.83 138.24,4.83
24737_DL on BOTTOM (solid shape): 146.58,7.8 146.58,7.01 146.56,6.98 146.43,6.98 145.92,6.48 145.54,6.48 145.42,6.6 145.42,7.62 145.62,7.82 146.56,7.82
24737_DL on IN1 (solid shape): 137.67,4.95 137.67,3.94 137.54,3.81 136.02,3.81 135.76,4.06 135.76,4.95 135.89,5.08 137.54,5.08
24737_DL on IN1 (solid shape): 146.05,7.75 146.05,6.48 145.92,6.35 145.03,6.35 144.91,6.48 144.91,7.75 145.03,7.87 145.92,7.87
51216_DRVH on TOP (solid shape): 194.69,64.06 194.69,62.99 194.98,62.71 194.98,61.88 194.96,61.86 194.8,61.86 194.77,61.88 194.77,62.6 194.56,62.81 194.26,62.81 194.08,62.99 194.08,64.01 194.23,64.16 194.59,64.16
51216_DRVH on TOP (solid shape): 188.77,69.08 189.37,69.08 189.44,69 189.44,67.89 189.35,67.8 188.63,67.8 188.32,68 188,67.8 187.54,67.8 187.23,68.12 187.23,68.54 187.99,69.3 188.55,69.3
51216_DRVH on IN1 (solid shape): 194.69,64.03 194.69,62.97 194.51,62.79 193.7,62.79 193.55,62.94 193.55,64.08 193.68,64.21 194.51,64.21
51216_DRVH on IN1 (solid shape): 190.1,69.21 190.1,68.15 189.97,68.01 188.08,68.01 187.93,68.16 187.93,69.22 188.03,69.31 190.01,69.31
51216_DRVL on TOP (solid shape): 192.86,76.25 192.86,75.51 192.53,75.18 191.64,75.18 191.52,75.31 191.52,76.33 191.64,76.45 192.66,76.45
51216_DRVL on TOP (solid shape): 197.4,63.97 197.4,63.69 197.32,63.62 197,63.62 196.93,63.54 196.93,62.86 196.17,62.11 196.17,61.88 196.15,61.86 195.99,61.86 195.98,61.88 195.98,62.67 196.29,62.99 196.29,63.86 196.47,64.03 197.34,64.03
51216_DRVL on IN1 (solid shape): 192.91,76.35 192.91,75.31 192.53,74.93 191.64,74.93 191.52,75.06 191.52,76.33 191.66,76.47 192.8,76.47
51216_DRVL on IN1 (solid shape): 197.1,64.11 197.1,63.53 196.95,63.37 196.95,62.74 196.88,62.66 196.21,62.66 196.01,62.86 196.01,64.14 196.16,64.29 196.93,64.29
51216_SW on TOP (solid shape): 195.58,65.05 195.58,64.17 195.47,64.06 195.47,62.93 195.38,62.83 195.38,61.9 195.35,61.87 195.2,61.87 195.17,61.9 195.17,62.66 194.82,63.02 194.82,65.05 194.85,65.08 195.55,65.08
51216_SW on TOP (solid shape): 189.23,77.6 189.23,76.71 189.48,76.45 190.88,76.45 191.06,76.27 191.06,72.7 190.88,72.52 190.04,72.52 189.46,71.93 189.46,69.44 189.36,69.34 188.77,69.34 188.61,69.5 187.89,69.5 187.73,69.34 184.79,69.34 184.15,69.98 184.15,76.83 185.04,77.72 189.1,77.72
51216_SW on IN3 (solid shape): 189.46,71.75 189.46,70.61 189.33,70.48 188.19,70.48 188.06,70.61 188.06,71.88 188.19,72.01 189.2,72.01
51216_SW on IN3 (solid shape): 195.86,64.06 195.86,62.89 195.78,62.81 194.92,62.81 194.82,62.92 194.82,64.11 194.92,64.21 195.71,64.21
51216_VBST on TOP (solid shape): 194.06,65.06 194.06,64.16 193.98,64.08 193.98,62.92 194.23,62.66 194.56,62.66 194.57,62.65 194.57,61.87 194.57,61.86 193.94,61.86 193.12,62.69 193.12,64.94 193.27,65.09 194.02,65.09
51716_VIN on TOP (solid shape): 196.37,73.41 196.51,73.2 196.75,73.13 197.87,72.01 197.87,70.54 197.69,70.36 193.08,70.36 192.53,69.81 192.53,68.37 192.11,67.94 190.25,67.94 190.09,68.1 190.09,71.6 190.63,72.14 192.66,72.14 193.55,73.02 194.44,73.02 194.82,73.41
+DDR_VTT_RUN on TOP (solid shape): 195.38,59.61 195.38,58.84 195.65,58.57 195.65,57.36 195.96,57.05 196.19,57.05 196.21,57.02 196.21,56.26 196.09,56.13 194.18,56.13 193.93,56.39 193.93,56.9 194.94,57.91 194.94,58.3 195.17,58.53 195.17,59.61 195.2,59.64 195.35,59.64
+DDR_VTT_RUN on TOP (solid shape): 189.48,57.91 192.4,57.91 192.53,57.78 192.53,56.13 192.28,55.88 188.34,55.88 187.45,56.77 181.82,56.77 181.8,56.8 181.48,57 181.16,56.8 181.15,56.77 180.55,56.77 180.53,56.8 180.22,57 179.9,56.81 179.86,56.77 172.34,56.77 171.58,56.01 171.58,53.09 169.16,53.09 169.16,56.77 171.45,59.05 188.34,59.05
+DDR_VTT_RUN on TOP (solid shape): outline of 1443 points within 88.06,26.16 166.24,29.46
+DDR_VTT_RUN on BOTTOM (solid shape): outline of 376 points within 88.93,25.96 172.08,55.25
+DDR_VTT_RUN on IN2 (solid shape): outline of 97 points within 190.88,55.82 196.43,58.55
+M_VREF_CA on BOTTOM (solid shape): 167.39,42.42 167.39,40.56 167.37,40.53 167.33,40.51 167.24,40.47 167.19,40.45 167.13,40.44 166.39,40.44 166.35,40.4 166.34,40.39 166.32,40.39 166.29,40.39 166.27,40.4 166.08,40.51 165.86,40.55 165.53,40.55 165.5,40.57 165.48,40.6 165.48,42.03 165.68,42.22 165.78,42.35 165.84,42.51 165.86,42.53 165.89,42.55 165.93,42.55 165.93,42.56 166.28,42.92 166.89,42.92
+M_VREF_CA on BOTTOM (solid shape): outline of 1621 points within 127.76,66.93 143.51,71.37
+M_VREF_DQ0 on BOTTOM (solid shape): 148.34,57.15 148.34,55.88 148.18,55.73 146.46,55.73 146.3,55.88 146.3,57.28 146.43,57.4 148.08,57.4
+M_VREF_DQ1 on BOTTOM (solid shape): outline of 582 points within 111,56.92 113.54,70.48
+SM_VREF_CA on TOP (solid shape): 164.83,36.31 164.85,36.31 164.97,36.19 164.97,34.66 164.85,34.54 164.72,34.54 163.96,34.54 163.88,34.62 163.87,34.65 163.88,34.67 163.95,35 163.84,35.32 163.83,35.35 163.95,35.74 163.84,36.11 163.83,36.12 163.83,36.16 163.99,36.32 164.82,36.32
+SM_VREF_CA on BOTTOM (solid shape): 167.23,40.05 167.25,40.02 167.37,39.81 167.59,39.73 167.63,39.71 167.64,39.67 167.64,38.48 167.51,38.35 167.35,38.35 167.34,38.36 167.17,38.39 167,38.38 166.83,38.39 166.67,38.36 166.66,38.35 166.16,38.35 166.15,38.37 166.03,38.37 165.94,38.39 165.86,38.39 165.23,38.39 165.14,38.39 165.05,38.37 164.84,38.37 164.83,38.36 164.8,38.35 164.79,38.36 164.58,38.39 164.37,38.35 164.34,38.35 164.21,38.48 164.21,39.02 164.24,39.06 164.26,39.07 164.36,39.15 164.44,39.26 164.46,39.28 164.49,39.29 164.54,39.28 164.59,39.28 165.86,39.28 166.33,39.49 166.49,39.97 166.49,40 166.51,40.01 166.54,40.05 166.55,40.06 166.57,40.06 167.13,40.06 167.19,40.06
+SM_VREF_CA on IN1 (solid shape): outline of 257 points within 163.82,33.52 168.27,39.5
+SM_VREF_DQA on BOTTOM (solid shape): 148.34,55.12 148.34,53.59 148.08,53.34 148.07,53.34 147.7,53.46 147.33,53.34 146.93,53.34 146.66,53.45 146.37,53.43 146.36,53.43 146.34,53.44 146.23,53.48 146.11,53.49 145.08,53.49 145.05,53.51 145.03,53.54 145.03,54.36 145.29,54.61 146.81,54.61 146.84,54.58 146.89,54.61 146.94,54.61 147.07,54.74 147.07,54.78 147.07,54.79 147.16,54.99 147.18,55.2 147.18,55.21 147.18,55.24 147.24,55.29 147.24,55.29 147.3,55.35 148.11,55.35
+SM_VREF_DQB on BOTTOM (solid shape): 113.28,56.39 113.28,54.99 113.16,54.86 112.88,54.86 112.87,54.87 112.71,54.94 112.55,54.96 111.18,54.96 111.09,54.86 110.36,54.86 110.11,55.12 110.11,55.75 110.24,55.88 111.89,55.88 112.01,56.01 112.01,56.39 112.17,56.54 113.13,56.54
+TPVDD on TOP (solid shape): 35.22,8.5 35.22,7.99 34.97,7.74 33.96,7.74 33.75,7.52 33.75,5.6 33.24,5.1 32.32,5.1 31.97,5.45 31.97,6.16 31.71,6.42 28.51,6.42 28.39,6.54 28.39,8.45 28.68,8.74 34.98,8.74
+TPVDD on BOTTOM (solid shape): 36.4,9.4 36.4,7.65 35.99,7.24 32,7.24 31.62,7.62 31.62,9.52 31.72,9.63 36.17,9.63
+TPVDD on IN1 (solid shape): 35.31,9.52 35.31,8 34.8,7.49 33.69,7.49 33.39,7.79 33.39,8.7 33.78,9.09 33.78,9.52 34.04,9.78 35.05,9.78
BAT-V on BOTTOM (solid shape): 128.13,20.57 128.13,14.9 128.3,14.73 130.18,14.73 130.56,14.35 130.56,12.32 130.43,12.19 124.84,12.19 124.71,12.32 120.65,12.32 116.97,16 112.65,16 111.7,15.05 106.62,15.05 106.49,15.18 106.49,18.92 106.75,19.18 112.27,19.18 113.92,20.83 127.87,20.83
CS_BST1 on TOP (solid shape): 183.38,101.9 183.38,101.42 184.19,100.61 184.19,100.35 184.18,100.35 184.18,99.64 184.14,99.59 184.03,99.59 183.98,99.64 183.88,100.45 183.28,100.45 182.64,101.09 182.64,101.9 182.67,101.93 183.35,101.93
CS_BSTR1 on TOP (solid shape): 184.62,101.9 184.62,100.53 184.6,100.51 184.6,100.35 184.58,100.35 184.58,99.63 184.55,99.59 184.42,99.59 184.38,99.63 184.38,100.35 184.37,100.36 184.37,100.58 183.89,101.07 183.89,101.88 183.94,101.93 184.6,101.93
CS_SW1 on TOP (solid shape): 192.15,96.53 192.15,96.11 192.08,95.86 192.15,95.61 192.15,87.38 192.02,87.25 189.87,87.25 189.74,87.38 189.74,87.59 189.74,89.27 189.62,89.27 189.61,89.28 189.36,89.28 189.35,89.27 189.23,89.27 189.23,87.59 189.23,87.38 189.1,87.25 187.71,87.25 185.97,88.99 185.97,93.44 184.85,94.55 184.85,95.33 185.19,95.7 184.85,96.07 184.85,96.84 184.98,96.97 191.71,96.97
